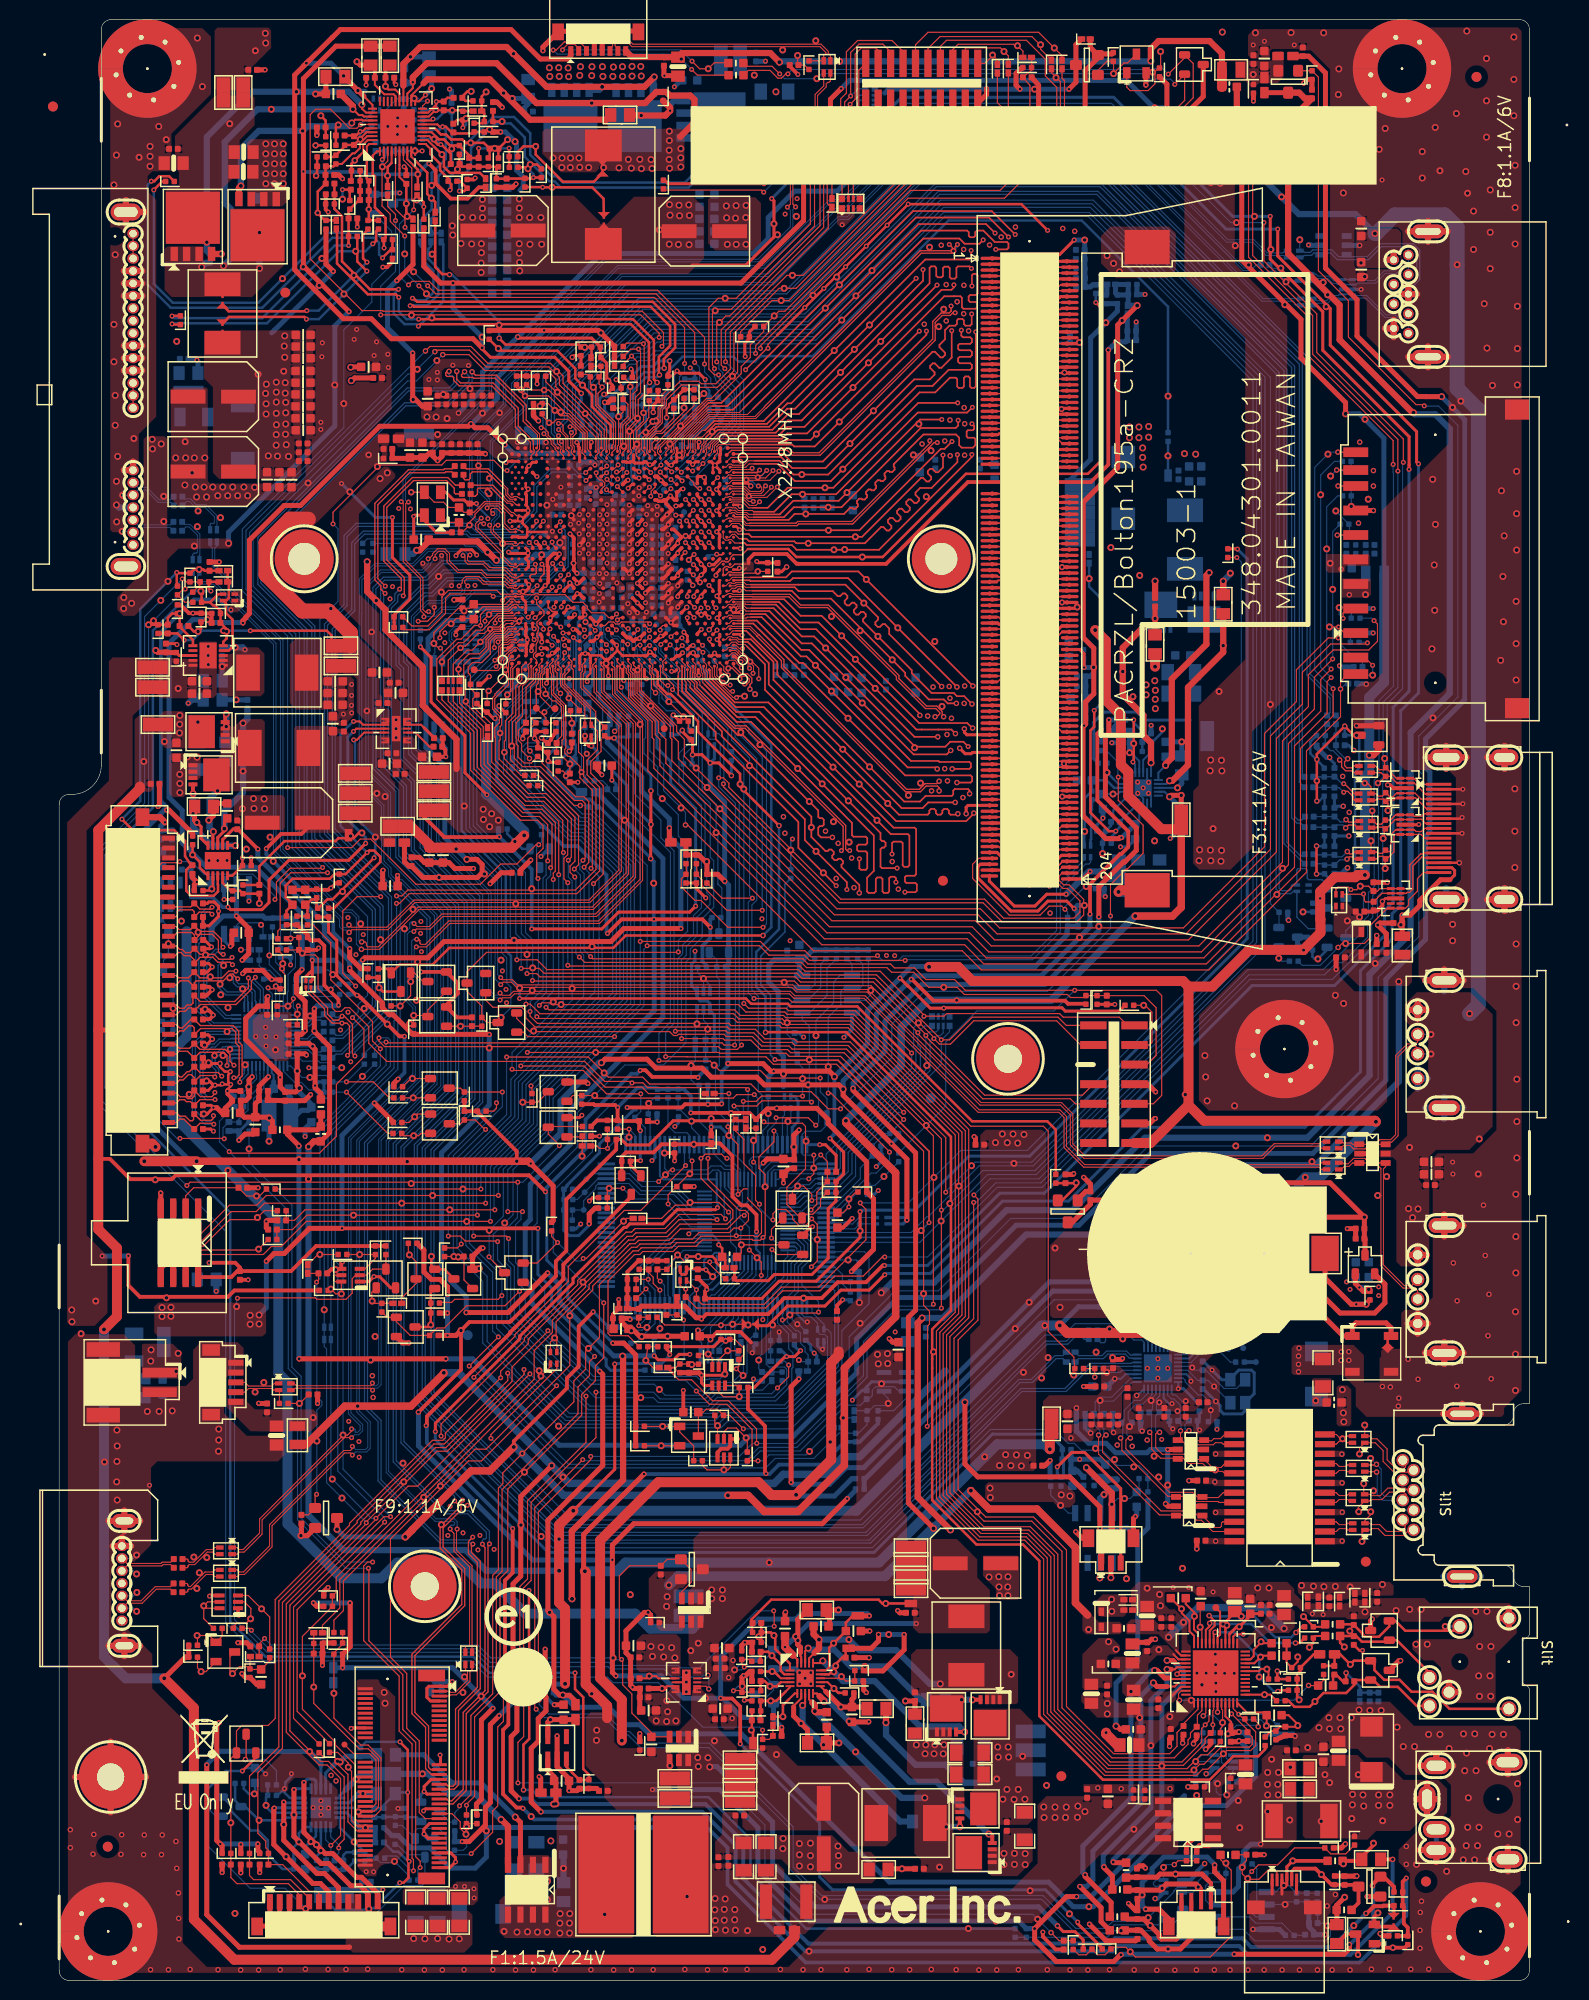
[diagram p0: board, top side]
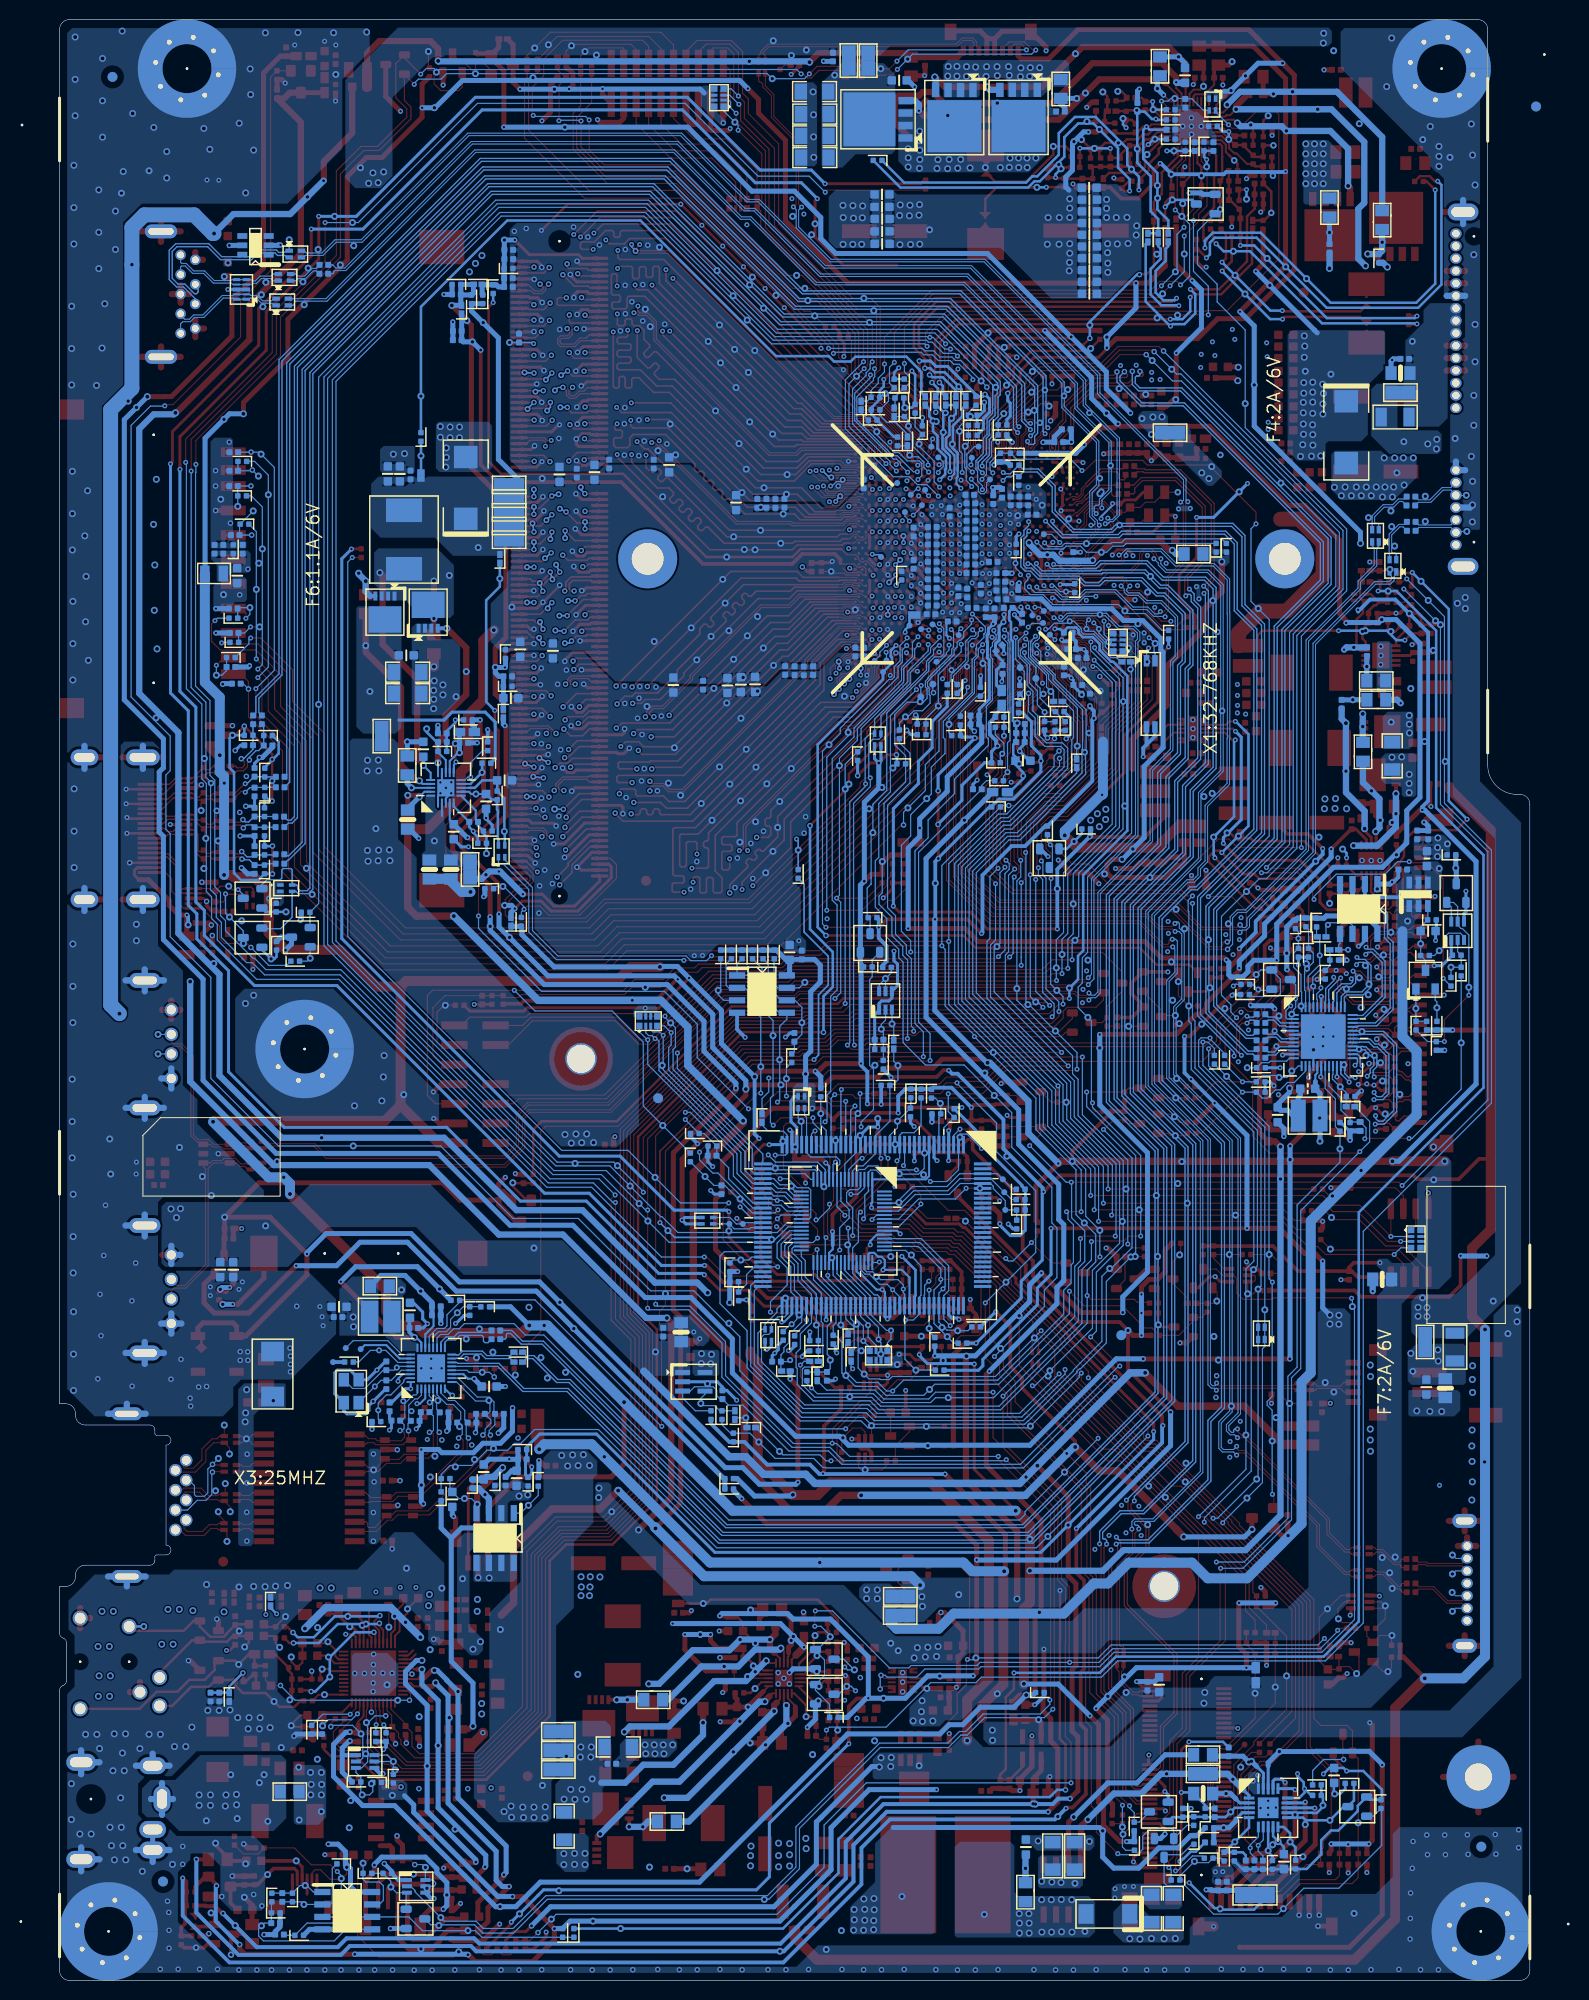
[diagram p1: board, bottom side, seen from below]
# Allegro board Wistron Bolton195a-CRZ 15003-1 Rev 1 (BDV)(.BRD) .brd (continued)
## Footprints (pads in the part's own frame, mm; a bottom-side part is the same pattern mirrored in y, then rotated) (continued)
SOT23-2D4-312H46
  custom 0.191x0.191 smd: 1(-0.984,-0.953) 2(0.984,-0.953) 3(0,0.953)
SOT23-2D4-312H48
  custom 0.191x0.191 smd: 1(-0.984,-0.953) 2(0.984,-0.953) 3(0,0.953)
SOT23-2D8-312H58
  custom 0.254x0.254 smd: 1(-1.016,-1.118) 2(1.016,-1.118) 3(0,1.118)
SOT23CBE2D4H44
  custom 0.191x0.191 smd: B(-0.984,-0.953) C(0,0.953) E(0.984,-0.953)
SOT23DGS2D4H35
  custom 0.191x0.191 smd: D(0,0.953) G(-0.984,-0.953) S(0.984,-0.953)
SOT23DGS2D4H44
  custom 0.191x0.191 smd: D(0,0.953) G(-0.984,-0.953) S(0.984,-0.953)
SOT23DGS2D4H48
  custom 0.191x0.191 smd: D(0,0.953) G(-0.984,-0.953) S(0.984,-0.953)
SOT23DGS2D8H50
  custom 0.254x0.254 smd: D(0,1.118) G(-1.016,-1.118) S(1.016,-1.118)
SOT-6-1H50
  rect 0.584x1.219 smd: 1(-0.95,-1.194) 2(0,-1.194) 3(0.95,-1.194) 4(0.95,1.194) 5(0,1.194) 6(-0.95,1.194)
SOT-6H58
  rect 0.584x1.016 smd: 1(-0.953,-1.346) 2(0,-1.346) 3(0.953,-1.346) 4(0.953,1.346) 5(0,1.346) 6(-0.953,1.346)
SOT-23-1H44
  custom 0.254x0.254 smd: 1(-1.016,-1.118) 2(1.016,-1.118) 3(0,1.118)
SOT-23-5H52
  rect 0.508x1.524 smd: 1(-0.95,-1.143) 2(0,-1.143) 3(0.95,-1.143) 4(0.95,1.143) 5(-0.95,1.143)
SOT-23-5H58
  rect 0.508x1.524 smd: 1(-0.95,-1.143) 2(0,-1.143) 3(0.95,-1.143) 4(0.95,1.143) 5(-0.95,1.143)
SOT-23-10H44
  rect 0.762x1.143 smd: 1(-0.984,-0.953) 2(0.984,-0.953) 3(0,0.953)
SOT-363H44
  rect 0.406x1.016 smd: 1(-0.65,-0.94) 2(0,-0.94) 3(0.65,-0.94) 4(0.65,0.94) 5(0,0.94) 6(-0.65,0.94)
STF237R128H34
  round 6.02 hole 3.251: 1(0,0)
STF256R109H124
  round 6.502 hole 2.769: 1(0,0)
STFT256B126R113H62
  round 6.502 hole 2.87: 1(0,0)
TPAD24
  round 0.61 smd: 1(0,0)
TPAD28-1-U
  round 0.711 smd: 1(0,0)
TVS5436-1121H105
  rect 2.337x2.007 smd: 1(0,2.299) 2(0,-2.299)
unnamed
  round 1.016 smd: (0,0)
WATA-07APLDJ6U
  oval 1.041x1.168 hole 0.762: 1(-3.81,0.25) 2(-2.54,0.25) 3(-1.27,0.25) 4(0,0.25) 5(1.27,0.25) 6(2.54,0.25) 7(3.81,0.25)
  oval 1.422x2.515 hole 0.711x1.803: 8(-6.37,0) 9(6.37,0)
XFORM24Z151100H160
  rect 0.635x2.032 smd: 1(-5.445,-4.623) 2(-4.455,-4.623) 3(-3.465,-4.623) 4(-2.475,-4.623) 5(-1.485,-4.623) 6(-0.495,-4.623) 7(0.495,-4.623) 8(1.485,-4.623) 9(2.475,-4.623) 10(3.465,-4.623) 11(4.455,-4.623) 12(5.445,-4.623) 13(5.445,4.623) 14(4.455,4.623) 15(3.465,4.623) 16(2.475,4.623) 17(1.485,4.623) 18(0.495,4.623) 19(-0.495,4.623) 20(-1.485,4.623) 21(-2.475,4.623) 22(-3.465,4.623) 23(-4.455,4.623) 24(-5.445,4.623)

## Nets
3V_5V_POK: PC4921.1 PR4928.1 PR4929.1 R4803.2 R5101.2 R5202.1
5V_A: C372.1 C435.1 C3602.1 C3608.1 EC10.1 PR4906.1 PR4907.1 PR4910.1 PR4913.1 R6536.1 R6537.1 U12.4 U13.4 U13.6 U13.7 U17.D U20.1 U20.2 U20.5 U20.6 U22.1 U22.2 U22.5 U22.6 U51.5
5V_FANCTL1_FSM#: R6513.2 U6502.1
5V_HDD: C412.1 C413.1 F4.2 HDD1.P7 HDD1.P8 HDD1.P9 R1021.2
5V_S0: C195.1 C196.1 C384.1 C3606.2 C3615.1 C6512.1 C6522.1 D14.A EC9.1 F3.1 F4.1 F7.1 FC1.1 L4.1 PR4426.1 PR4427.1 PR4440.1 R429.1 R508.2 R606.1 R607.1 R618.2 R671.1 R1021.1 R6516.1 R6531.1 R6576.1 R6578.1 U13.8 U13.9 U6502.2
5V_S5: C311.2 D7.2 L3.2 PC4806.1 PR5001.2 PR5005.2 PU4801.7 R86.1 R87.2 R499.2 R555.1 R808.2 R6536.2 R6537.2 RN11.5(B) RN11.6(B) RN11.7(B) RN11.8(B) U17.S U20.4
5V_S5_LCD_DOWN: Q33.D R377.2
12V_EN_D: PR161.2 Q82.D R1014.1
12V_EN_G: Q82.G Q4807.D R6562.2 R6563.2
12V_EN_G1: Q82.S Q83.D
+0.95V_DUAL: C119.1 C137.1 C138.1 C139.1 C140.1 C141.1 C142.1 CPU1.AR5 CPU1.AU4 CPU1.AV7 CPU1.AW5 R100.2 R119.1
+1.05V_LAN: C270.1 C271.1 C272.1 C273.1 C274.1 C275.1 C278.1 C279.1 L21.2 LAN1.3 LAN1.8 LAN1.22 LAN1.30 R269.2
+3VL: PG4904.2 PR161.1 R6541.2 R6543.1 R6544.2 R6550.1 R6551.2 R6561.1 R6563.1 R6573.1
+3VM: DIMM1.199 R136.2
+5VL: PG4901.2 PR4922.1
+5VLCDDDC: C389.1 F3.2 HDMI1.18
AGND: AUDIO1.26 AUDIO1.37 AUDS1.1 AUDS1.8 C185.2 C186.1 C187.2 C188.2 C189.2 C190.2 C191.1 C192.2 C193.1 C256.2 C257.2 C261.2 C262.2 C263.1 C264.1 C265.1 C267.1 EC704.2 R152.2 R164.1 R165.1 R166.1 R167.1 R168.1 R169.2 R235.2 R259.2 R261.2 R264.2
GND: AUDIO1.7 AUDIO1.42 AUDIO1.43 AUDIO1.49 BTT1.2 C1.2 C2.2 C3.2 C22.1 C23.1 C24.2 C25.1 C26.2 C27.1 C28.2 C29.2 C30.2 C31.2 C32.2 C33.1 C34.2 C35.2 C36.2 C37.2 C38.2 C39.2 C40.2 C41.2 C42.2 C43.2 C44.2 C45.2 C46.2 C47.2 C48.2 C49.2 C50.2 C51.2 C52.2 C53.2 C54.2 C55.2 C56.2 C57.2 C58.2 C59.2 C60.2 C61.2 C62.2 C63.2 C64.2 C65.2 C66.2 C67.2 C68.2 C69.2 C70.2 C71.2 C72.2 C73.2 C74.2 C75.2 C76.2 C77.2 C78.2 C79.2 C80.2 C81.2 C82.2 C83.2 C84.2 C85.2 C86.2 C87.2 C88.2 C89.2 C90.2 C91.2 C92.2 C93.2 C94.2 C95.2 C96.2 C97.2 C98.2 C99.2 C100.2 C101.2 C102.2 C103.2 C104.2 C105.2 C106.2 C107.2 C108.2 C109.2 C110.2 C111.2 C112.2 C113.2 C114.2 C115.2 C116.2 C117.2 C118.2 C119.2 C120.2 C121.2 C122.2 C123.2 C124.2 C125.2 C126.2 C127.2 C128.2 C129.2 C130.2 C131.2 C132.2 C133.2 C134.2 C135.2 C136.2 C137.2 C138.2 C139.2 C140.2 C141.2 C142.2 C143.2 C144.2 C145.2 C146.2 C147.2 C148.2 C149.2 C150.2 C151.2 C152.2 C153.2 C154.2 C155.2 C156.2 C157.2 C158.2 C159.1 C160.2 C161.2 C173.2 C174.1 C175.2 C176.1 C184.2 C195.2 C196.2 C197.2 C198.2 C200.2 C201.2 C205.2 C206.2 C207.2 C208.1 C209.1 C211.2 C223.2 C230.2 C235.2 C236.2 C237.2 C243.2 C245.2 C246.2 C247.2 C263.2 C264.2 C265.2 C266.2 C267.2 C268.2 C269.2 C270.2 C271.2 C272.2 C273.2 C274.2 C275.2 C278.2 C279.2 C280.2 C281.1 C282.2 C283.2 C284.2 C285.2 C286.2 C287.2 C288.2 C289.2 C292.2 C294.2 C295.2 C302.2 C303.2 C304.2 C305.2 C306.1 C307.1 C310.2 C312.1 C313.2 C325.1 C326.2 C351.2 C352.2 C353.1 C354.1 C355.2 C356.1 C357.1 C358.1 C359.1 C360.1 C361.1 C362.1 C363.1 C364.1 C365.1 C368.1 C369.1 C370.1 C371.1 C372.2 C373.1 C374.1 C375.1 C376.1 C377.1 C379.2 C384.2 C388.2 C389.2 C390.2 C391.2 C392.2 C393.2 C394.2 C395.2 C396.2 C397.2 C398.2 C412.2 C413.2 C420.2 C421.2 C426.2 C427.2 C428.2 C429.2 C430.2 C431.1 C432.2 C435.2 C436.2 C441.2 C444.2 C445.2 C446.2 C447.2 C450.2 C451.2 C452.2 C455.2 C458.2 C460.2 C467.2 C476.2 C477.2 C478.2 C480.2 C481.2 C482.2 C483.2 C484.2 C485.2 C486.2 C487.2 C488.2 C491.1 C493.2 C494.2 C497.2 C498.2 C499.2 C500.2 C501.2 C502.2 C503.2 C504.2 C505.2 C506.2 C507.2 C508.2 C509.2 C510.2 C511.2 C512.2 C679.2 C680.2 C3601.2 C3602.2 C3603.2 C3604.2 C3605.1 C3606.1 C3608.2 C3609.2 C3614.2 C3615.2 C3619.1 C4801.2 C5001.2 C5002.2 C6101.2 C6102.2 C6103.2 C6104.2 C6510.2 C6511.2 C6512.2 C6514.2 C6515.2 C6516.2 C6517.2 C6518.2 C6519.2 C6520.2 C6521.2 C6522.2 C6523.2 C6524.2 C6525.2 C6526.2 C6527.2 C6528.2 C6529.2 C6530.2 C6531.2 C6532.1 C6533.1 C6534.2 C6535.2 C6536.2 CAM1.4 CAM1.5 CAM1.9 CAM1.10 CMOS1.2 CMOS1.4 CNVBD2.1 CNVBD2.2 CNVBD2.3 CNVBD2.13 CNVBD2.14 CPU1.A8 CPU1.A13 CPU1.A15 CPU1.A31 CPU1.A35 CPU1.A39 CPU1.AA3 CPU1.AA7 CPU1.AA8 CPU1.AA11 CPU1.AA15 CPU1.AA19 CPU1.AA25 CPU1.AA29 CPU1.AA39 CPU1.AC3 CPU1.AC7 CPU1.AC11 CPU1.AC15 CPU1.AC19 CPU1.AC25 CPU1.AC29 CPU1.AC31 CPU1.AC39 CPU1.AC41 CPU1.AE3 CPU1.AE7 CPU1.AE25 CPU1.AE29 CPU1.AE32 CPU1.AE39 CPU1.AG3 CPU1.AG5 CPU1.AG10 CPU1.AG11 CPU1.AG13 CPU1.AG15 CPU1.AG19 CPU1.AG25 CPU1.AG29 CPU1.AG31 CPU1.AG39 CPU1.AG41 CPU1.AH1 CPU1.AH2 CPU1.AJ3 CPU1.AJ7 CPU1.AJ15 CPU1.AJ17 CPU1.AJ19 CPU1.AJ23 CPU1.AJ25 CPU1.AJ29 CPU1.AJ31 CPU1.AJ32 CPU1.AJ39 CPU1.AL3 CPU1.AL8 CPU1.AL15 CPU1.AL17 CPU1.AL19 CPU1.AL25 CPU1.AL29 CPU1.AL31 CPU1.AL39 CPU1.AL41 CPU1.AM11 CPU1.AM27 CPU1.AM29 CPU1.AM31 CPU1.AN3 CPU1.AN7 CPU1.AN39 CPU1.AP31 CPU1.AR3 CPU1.AR13 CPU1.AR17 CPU1.AR21 CPU1.AR25 CPU1.AR29 CPU1.AR39 CPU1.AR41 CPU1.AU1 CPU1.AU2 CPU1.AU3 CPU1.AU15 CPU1.AU19 CPU1.AU23 CPU1.AU27 CPU1.AU39 CPU1.AV9 CPU1.AW3 CPU1.AW7 CPU1.AW13 CPU1.AW15 CPU1.AW17 CPU1.AW19 CPU1.AW21 CPU1.AW23 CPU1.AW25 CPU1.AW27 CPU1.AW31 CPU1.AW33 CPU1.AW35 CPU1.AW37 CPU1.AW39 CPU1.AW41 CPU1.AY13 CPU1.AY15 CPU1.AY18 CPU1.AY30 CPU1.B8 CPU1.B13 CPU1.B23 CPU1.B31 CPU1.B39 CPU1.BA2 CPU1.BA7 CPU1.BA13 CPU1.BA15 CPU1.BA18 CPU1.BA21 CPU1.BA25 CPU1.BA31 CPU1.BA35 CPU1.BA39 CPU1.C1 CPU1.C2 CPU1.C5 CPU1.C7 CPU1.C9 CPU1.C11 CPU1.C13 CPU1.C15 CPU1.C17 CPU1.C19 CPU1.C21 CPU1.C23 CPU1.C25 CPU1.C27 CPU1.C29 CPU1.C31 CPU1.C33 CPU1.C35 CPU1.C37 CPU1.C39 CPU1.C41 CPU1.D9 CPU1.D11 CPU1.D13 CPU1.E3 CPU1.E4 CPU1.E9 CPU1.E11 CPU1.E13 CPU1.E27 CPU1.E31 CPU1.E35 CPU1.E38 CPU1.E39 CPU1.G3 CPU1.G7 CPU1.G11 CPU1.G13 CPU1.G15 CPU1.G17 CPU1.G21 CPU1.G25 CPU1.G29 CPU1.G35 CPU1.G37 CPU1.G39 CPU1.G41 CPU1.H11 CPU1.H13 CPU1.H23 CPU1.H31 CPU1.J3 CPU1.J7 CPU1.J8 CPU1.J39 CPU1.K11 CPU1.K13 CPU1.K17 CPU1.K19 CPU1.K21 CPU1.K23 CPU1.K25 CPU1.K27 CPU1.K29 CPU1.K31 CPU1.L3 CPU1.L7 CPU1.L8 CPU1.L10 CPU1.L11 CPU1.L15 CPU1.L19 CPU1.L31 CPU1.L39 CPU1.L41 CPU1.M1 CPU1.M2 CPU1.N3 CPU1.N7 CPU1.N15 CPU1.N19 CPU1.N25 CPU1.N29 CPU1.N31 CPU1.N39 CPU1.P1 CPU1.P2 CPU1.R3 CPU1.R7 CPU1.R15 CPU1.R19 CPU1.R25 CPU1.R29 CPU1.R39 CPU1.R41 CPU1.U1 CPU1.U2 CPU1.U3 CPU1.U7 CPU1.U8 CPU1.U11 CPU1.U15 CPU1.U19 CPU1.U25 CPU1.U29 CPU1.U31 CPU1.U39 CPU1.W3 CPU1.W5 CPU1.W11 CPU1.W15 CPU1.W19 CPU1.W25 CPU1.W29 CPU1.W39 CPU1.W41 CPU1.Y1 CPU1.Y2 CRS1.3 CRS1.6 CRS1.12 CRS1.13 D7.1 D9.3 D12.3 D19.3 D19.8 D20.2 D21.3 D24.2 D29.A DBGH1.7 DBGH1.11 DCIN1.2 DCIN1.3 DCIN1.4 DCIN1.5 DCIN1.6 DIMM1.2 DIMM1.3 DIMM1.8 DIMM1.9 DIMM1.13 DIMM1.14 DIMM1.19 DIMM1.20 DIMM1.25 DIMM1.26 DIMM1.31 DIMM1.32 DIMM1.37 DIMM1.38 DIMM1.43 DIMM1.44 DIMM1.48 DIMM1.49 DIMM1.54 DIMM1.55 DIMM1.60 DIMM1.61 DIMM1.65 DIMM1.66 DIMM1.71 DIMM1.72 DIMM1.127 DIMM1.128 DIMM1.133 DIMM1.134 DIMM1.138 DIMM1.139 DIMM1.144 DIMM1.145 DIMM1.150 DIMM1.151 DIMM1.155 DIMM1.156 DIMM1.161 DIMM1.162 DIMM1.167 DIMM1.168 DIMM1.172 DIMM1.173 DIMM1.178 DIMM1.179 DIMM1.184 DIMM1.185 DIMM1.189 DIMM1.190 DIMM1.195 DIMM1.196 DIMM1.201 DIMM1.205 DIMM1.206 EC1.2 EC2.2 EC3.2 EC4.2 EC5.2 EC6.2 EC7.2 EC8.2 EC9.2 EC10.2 EC11.2 EC12.2 EC13.2 EC14.2 EC15.2 EC16.2 EC17.2 EC18.2 EC302.2 EC326.2 EC327.2 EC328.2 EC329.2 EC330.2 EC701.2 EC702.2 EC703.2 EC705.2 EC706.2 EC707.2 EC708.2 EC709.2 FANC1.2 FANC1.4 FANC1.5 FC1.2 FC2.2 FC3.2 FC4.2 G3.1 GDT1.1 H1.1 H1.2 H1.3 H1.4 H1.5 H1.6 H1.7 H1.8 H2.1 H2.2 H2.3 H2.4 H2.5 H2.6 H2.7 H2.8 H3.1 H3.2 H3.3 H3.4 H3.5 H3.6 H3.7 H3.8 H4.1 H4.2 H4.3 H4.4 H4.5 H4.6 H4.7 H4.8 H5.1 H5.2 H5.3 H5.4 H5.5 H5.6 H5.7 H5.8 HDD1.23 HDD1.24 HDD1.P4 HDD1.P5 HDD1.P6 HDD1.P10 HDD1.P11 HDD1.P12 HDD1.S1 HDD1.S4 HDD1.S7 HDMI1.2 HDMI1.5 HDMI1.8 HDMI1.11 HDMI1.17 HDMI1.20 HDMI1.21 HDMI1.22 HDMI1.23 HDT1.3 HDT1.5 HDT1.7 HDT1.17 HS1.1 HS2.1 HS3.1 HS4.1 HS5.1 LAN1.33 LVDS19.7 LVDS19.14 LVDS19.17 LVDS19.24 LVDS19.31 LVDS19.32 NGFFE1.1 NGFFE1.7 NGFFE1.18 NGFFE1.33 NGFFE1.39 NGFFE1.45 NGFFE1.51 NGFFE1.57 NGFFE1.63 NGFFE1.69 NGFFE1.75 ODD1.1 ODD1.4 ODD1.7 ODD1.8 ODD1.9 ODDPW1.2 ODDPW1.3 ODDPW1.4 PC2.1 PC3.2 PC4.2 PC6.2 PC7.2 PC4205.2 PC4401.1 PC4403.2 PC4406.2 PC4407.2 PC4408.2 PC4409.2 PC4414.2 PC4416.2 PC4418.2 PC4419.2 PC4420.2 PC4421.2 PC4422.2 PC4423.2 PC4424.2 PC4425.2 PC4426.2 PC4427.2 PC4428.2 PC4429.2 PC4432.2 PC4433.2 PC4437.2 PC4442.2 PC4443.2 PC4445.2 PC4801.2 PC4803.2 PC4804.2 PC4806.2 PC4808.2 PC4809.2 PC4901.2 PC4902.2 PC4903.2 PC4905.2 PC4906.2 PC4907.2 PC4908.2 PC4911.2 PC4914.2 PC4915.2 PC4917.2 PC4919.2 PC4920.2 PC4921.2 PC4922.2 PC4923.2 PC5001.2 PC5005.2 PC5006.2 PC5007.2 PC5009.2 PC5011.2 PC5012.2 PC5014.2 PC5015.2 PC5016.2 PC5101.2 PC5102.2 PC5103.2 PC5105.2 PC5106.2 PC5107.2 PC5110.2 PC5203.2 PC5204.2 PC5205.2 PC5206.2 PC5207.2 PC5210.2 PC5211.2 PC5212.2 PC5213.2 PC5214.2 PC5215.2 PC5216.2 PC5217.2 PC5218.2 PC5219.2 PC5220.2 PC5221.2 PC5222.2 PC5223.2 PC5224.2 PC5225.2 PC5226.2 PC5229.2 PG4802.1 PQ4402.1 PQ4402.2 PQ4402.3 PQ4404.1 PQ4404.2 PQ4404.3 PQ4405.1 PQ4405.2 PQ4405.3 PQ4802.1 PQ4802.2 PQ4802.3 PQ4903.1 PQ4903.2 PQ4903.3 PQ4904.1 PQ4904.2 PQ4904.3 PQ5002.1 PQ5002.2 PQ5002.3 PR7.1 PR10.2 PR13.2 PR14.2 PR15.2 PR16.2 PR18.2 PR4408.2 PR4409.2 PR4420.2 PR4421.1 PR4425.1 PR4434.2 PR4438.1 PR4441.2 PR4443.2 PR4447.2 PR4455.2 PR4460.2 PR4805.1 PR4809.2 PR4812.2 PR4815.2 PR4919.2 PR4920.2 PR4921.2 PR4923.2 PR4924.2 PR4925.2 PR5019.2 PR5022.2 PR5104.2 PR5107.2 PR5108.2 PR5206.2 PR5208.2 PT4402.2 PT4403.2 PT4404.2 PT4406.2 PT4407.2 PT4411.2 PT4902.2 PT4903.2 PT5001.2 PU1.1 PU4401.41 PU4801.11 PU4901.21 PU5001.1 PU5001.3 PU5001.14 PU5001.21 PU5101.11 PU5201.2 PWRBT1.1 PWRBT1.3 PWRBT1.6 PWRBT1.7 PWRBT1.8 Q1.S Q2.E Q4.1 Q4.4 Q26.S Q27.1 Q27.4 Q29.1 Q29.4 Q33.S Q34.1 Q34.4 Q35.S Q39.S Q42.1 Q42.4 Q44.2 Q45.1 Q45.4 Q48.S Q49.1 Q49.4 Q75.S Q76.1 Q76.4 Q83.S Q98.S Q100.S Q4401.S Q4402.E Q4802.S Q4805.S Q4806.S Q4807.S R7.2 R10.2 R11.2 R12.2 R13.2 R14.2 R15.2 R17.2 R18.2 R21.2 R23.2 R25.2 R26.2 R27.2 R28.2 R31.2 R32.2 R42.2 R57.2 R58.2 R59.2 R60.2 R61.2 R73.2 R74.2 R93.2 R94.2 R95.2 R96.2 R97.1 R99.2 R130.2 R131.2 R132.2 R133.2 R134.2 R135.2 R141.2 R142.2 R152.1 R164.2 R165.2 R166.2 R167.2 R168.2 R179.1 R259.1 R261.1 R264.1 R268.1 R288.2 R296.2 R316.2 R342.1 R348.2 R349.2 R359.2 R378.2 R384.2 R386.1 R402.1 R435.2 R476.2 R477.2 R509.2 R510.2 R522.1 R523.2 R537.2 R546.2 R555.2 R560.2 R578.2 R583.2 R586.2 R587.2 R597.2 R601.2 R605.2 R610.2 R611.2 R613.2 R614.2 R615.2 R620.2 R624.2 R810.2 R6105.1 R6513.1 R6517.2 R6545.1 R6547.1 R6549.1 R6552.2 R6553.2 R6554.2 R6555.2 R6558.2 R6559.1 R6568.2 R6569.2 R6570.2 R6571.2 R6574.2 R6575.2 R6577.2 RJ1.9 RJ1.10 RN4.1(A) RN4.2(A) RN4.3(A) RN4.4(A) RN22.1(A) RN22.2(A) RN22.3(A) SPI1.4 TOUCH1.1 TOUCH1.2 TOUCH1.6 TOUCH1.7 U9.2 U10.2 U12.11 U12.15 U13.11 U13.15 U23.3 U23.8 U24.3 U24.8 U25.3 U25.8 U30.4 U31.7 U31.38 U31.74 U38.6 U38.16 U38.49 U39.1 U48.4 U51.2 U56.4 U58.1 U58.2 U58.4 U58.7 U59.20 U6502.5 U6502.6 U6502.7 U6502.8 U6503.54 USB2S1.4 USB2S1.5 USB2S1.6 USB2S2.4 USB2S2.5 USB2S2.6 USB3S1.4 USB3S1.7 USB3S1.10 USB3S1.11 X1.2 X1.3 X2.2 X2.4 X3.2 X3.4
V12: HDD1.P13 HDD1.P14 HDD1.P15
V33: HDD1.P1 HDD1.P2 HDD1.P3
VBAT_SB_N: C136.1 PU1.2 R122.2
VBAT_SIO: C481.1 R545.1 U31.69 U6503.29
VCC5_CAM: C446.1 C447.1 CAM1.8 F8.2 R463.2
VCC5_PANEL: C6520.1 C6521.1 L38.2 LVDS19.1 LVDS19.2 LVDS19.3 R377.1
VCC5_TOU: C450.1 C451.1 F9.2 TOUCH1.5
VDD_0.95_ALW: C123.1 C143.1 C144.1 C145.1 C146.1 CPU1.AE11 CPU1.AE13 CPU1.AJ11 CPU1.AJ13 R121.2
VDD_095_FB_H: CPU1.AV33 Q4801.S R4804.2 TP17.1
VDD_095_FB_H_CTL: PR4814.2 Q4801.D R4804.1
VDD_095_FB_L: CPU1.AU33 PG4802.2 TP18.1
VDD_095_GFX: C124.1 C125.1 CPU1.AA10 CPU1.U10 CPU1.W10 L1.1
VDDCR_APU_FB_H: PR4454.2 R35.1
VDDCR_APU_FB_L: PR4444.2 R37.1
VDDCR_CPU_SENSE: CPU1.G23 R35.2
VDDCR_NB_FB_H: PR4403.2 R34.1
VDDCR_NB_FB_L: PC4402.2 PC4406.1 PR4409.1 PR4437.2 R38.1
VDDCR_NB_SENSE: CPU1.D23 R34.2
VDDIO_SUS_FB_H: PR5210.2 R36.1
VDDIO_SUS_FB_R: PG4905.2 PR5210.1
VDDIO_SUS_SENSE: CPU1.E25 R36.2
VDDNB: C67.1 C68.1 C69.1 C70.1 C71.1 C72.1 C73.1 C74.1 C75.1 C76.1 C77.1 C78.1 C79.1 C80.1 C90.1 C91.1 C92.1 C93.1 CPU1.AA13 CPU1.AA17 CPU1.AC13 CPU1.AC17 CPU1.AE15 CPU1.AE17 CPU1.AE19 CPU1.AG17 CPU1.AG21 CPU1.L13 CPU1.L17 CPU1.N11 CPU1.N13 CPU1.N17 CPU1.R11 CPU1.R13 CPU1.R17 CPU1.U13 CPU1.U17 CPU1.W13 CPU1.W17 PC4418.1 PC4419.1 PC4420.1 PC5210.1 PC5211.1 PC5212.1 PC5213.1 PC5214.1 PC5215.1 PG4402.1 PL4905.2 PR4402.2 PT4402.1 PT4403.1 PT4404.1
VSS_BEEMA: CPU1.A23 R130.1
VSS_SENSE: CPU1.E23 R37.2 R38.2
0D75V_S0: DIMM1.203 DIMM1.204 PR5021.2
0D95V_S0: C6530.1 C6533.2 R98.1 R115.2 R116.2 R117.2 R4403.2 U12.8 U12.9
0D95V_S0_EN: C307.2 R299.2 R302.2 R6577.1 R6578.2 U12.5
0D95V_S5: C6524.1 C6527.1 PR4808.1 PR4810.1 PR4811.1 R119.2 R121.1 U12.6 U12.7
0D95V_S5_PG: PR4801.2 PU4801.1
0P95V_MAIN_APU_M: Q4402.B R4403.1
1D5V_S0: C327.2 U16.S
1D5V_S3: C94.1 C95.1 C96.1 C97.1 C98.1 C99.1 C100.1 C101.1 C102.1 C103.1 C104.1 C105.1 C114.1 C115.1 C116.1 C150.1 C151.1 C152.1 C153.1 C154.1 C155.1 C156.1 C157.1 C158.1 CPU1.AA31 CPU1.AA35 CPU1.AC32 CPU1.AC37 CPU1.AE31 CPU1.AE35 CPU1.AG32 CPU1.AG37 CPU1.AJ35 CPU1.AL32 CPU1.AL37 CPU1.AR35 CPU1.J35 CPU1.L32 CPU1.L37 CPU1.N35 CPU1.R31 CPU1.R37 CPU1.U32 CPU1.U35 CPU1.W31 CPU1.W32 CPU1.W37 DIMM1.75 DIMM1.76 DIMM1.81 DIMM1.82 DIMM1.87 DIMM1.88 DIMM1.93 DIMM1.94 DIMM1.99 DIMM1.100 DIMM1.105 DIMM1.106 DIMM1.111 DIMM1.112 DIMM1.117 DIMM1.118 DIMM1.123 DIMM1.124 EC11.1 EC12.1 FC2.1 FC3.1 PR5011.1 PR5013.1 PR5015.1 PR5016.1 PR5017.1 PR5213.1 R2.1 R4.2 R5.1 R139.1 R140.1 R832.1 U16.D
1D5V_S3_PG: PR5006.2 PU5001.10 R812.1
1D5V_S3_PG_R: C679.1 Q83.G R812.2
1D5V_S5: AUDIO1.9 C207.1 PR5204.2 R111.1 R6570.1
1D8V_S0: C6531.1 C6532.2 R109.2 U12.13 U12.14
1D8V_S0_EN: C3619.2 R982.2 R6575.1 R6576.2 U12.3
1D8V_S5: C81.1 C6525.1 C6526.1 PR5102.2 PR5211.2 R62.1 R65.2 R110.1 R6574.1 U12.1 U12.2
1P8V_PWR_PG: PU5101.4 R4801.1 R5201.1 RN19.4(B)
3D3V_2136: C497.1 L51.1 L53.1 R588.2 R589.2
3D3V_A: C478.1 C482.1 C485.1 C486.1 C3601.1 C3609.1 C6536.1 L50.2 PR4914.1 PR4915.1 PR4916.1 PR4930.1 PR5101.1 PR5201.1 PR5212.1 Q40.D Q4804.G R123.2 R309.1 R504.1 R505.1 R520.1 R524.2 R527.1 R535.1 R548.2 R549.2 R550.2 R551.2 R552.2 R553.2 R556.2 R557.1 R559.1 R568.2 R572.2 R622.2 R698.2 R822.1 R823.1 R824.1 R6535.1 R6538.1 R6539.1 R6540.2 R6572.1 RN10.1(A) RN10.2(A) RN12.1(A) RN12.2(A) U13.1 U13.2 U18.1 U18.2 U18.5 U18.6 U31.4 U31.35 U31.67 U56.8
3D3V_S0: C3605.2 C3614.1 CAM1.1 DBGH1.13 F6.1 L5.1 Q35.G Q37.C Q4803.G R16.2 R69.1 R70.1 R85.2 R112.1 R136.1 R286.1 R299.1 R367.1 R395.1 R396.1 R492.1 R493.1 R497.2 R498.2 R501.2 R502.2 R511.2 R512.2 R513.2 R526.2 R531.2 R542.2 R561.2 R562.2 R563.2 R579.1 R588.1 R982.1 R4401.1 R6512.1 R6532.2 R6534.1 R6546.1 R6548.1 R6557.1 R6560.2 R6564.2 RN5.1(A) RN5.2(A) RN9.5(B) RN9.6(B) RN9.7(B) RN9.8(B) RN16.1(A) RN16.2(A) RN18.1(A) RN18.2(A) U13.13 U13.14
3D3V_S5: C328.2 C426.1 C427.1 C6101.1 C6102.1 C6103.1 C6104.1 FC4.1 NGFFE1.2 NGFFE1.4 NGFFE1.72 NGFFE1.74 PR4801.1 PR5006.1 R76.1 R77.2 R78.2 R79.2 R80.2 R81.2 R83.2 R88.1 R89.1 R90.1 R113.1 R125.1 R126.1 R127.1 R128.1 R129.1 R175.2 R176.1 R278.1 R303.1 R310.1 R441.1 R466.1 R515.1 R516.1 R517.1 R518.1 R529.1 R533.1 R544.2 R578.1 R581.1 R608.1 R609.1 R617.1 R809.2 R1019.2 R1020.2 R1028.2 R4402.2 R6103.1 R6533.1 R6538.2 R6539.2 RN3.1(A) RN3.2(A) RN6.5(B) RN6.6(B) RN6.7(B) RN6.8(B) RN15.3(B) RN15.4(B) RN19.1(A) RN19.2(A) SPI1.8 U18.4 U30.8 U39.2
3D3V_S5_RSV: R474.1 R475.1 R6103.2 R6566.1
3D3V_USB: C444.1 C445.1 F8.1 Q40.S R589.1 R6571.1 R6572.2
+1P5V_LPS_APU: C135.1 CPU1.AN4 R122.1
+AUD_DVDD_1: AUDIO1.1 C205.1 C206.1 L5.2
+HDT_VDDIO_SUS: HDT1.1 HDT1.19 Q43.D R489.1 R491.1 RN7.5(B) RN7.6(B) RN7.7(B) RN7.8(B)
+RTCVCC: C147.1 C148.1 C149.1 CMOS1.1 CMOS1.3 D4.3 G3.2 PU1.3 R545.2
A_RST_N: CPU1.AY4 DBGH1.9 R63.1
AD_JK_S: D29.K DCIN1.1 PC2.2 PC3.1 PR1.1 PR4.1 R802.1 R803.1 R804.1
AD_JK_S_R: PC4.1 PC8.1 PR1.2 PR3.1 PR12.1 PR17.2 PU2.1 PU2.2 PU2.3 R802.2 R803.2 R804.2 U48.8
ADP_OCP: PR11.1 U48.7
ADU_LDO_CAP: AUDIO1.28 C185.1
AMPGND: SPK1.5 SPK1.6
APU_ALERT#: CPU1.B18 R40.2
APU_BLEN_SMI: CPU1.AP17 Q4803.D R6533.2
APU_DBRDY: CPU1.B25 HDT1.14
APU_DBREQ: HDT1.16 R486.1
APU_DBREQ#: C467.1 CPU1.A25 R486.2 R491.2
APU_M_VREF_SUS: C2.1 C3.1 CPU1.AD40 R6.1
APU_M_VREFDQ_SUS: C160.1 C161.1 C173.1 C174.2 DIMM1.1 R3.1 R139.2 R141.1 R145.1
APU_PROCHOT#: CPU1.A22 PR4428.1 Q75.D R41.2 R71.1
APU_PROCHOT#_R: CPU1.AM21 R71.2
APU_PWRGD: CPU1.B19 R22.2 R24.1 R56.1 R481.2
APU_PWRGD_BUF: HDT1.10 R481.1
APU_SIC: CPU1.B22 R43.2 U31.55 U6503.26
APU_SID: CPU1.B21 R44.2 U31.53 U6503.25
APU_SVC: CPU1.D27 R47.1 R54.1
APU_SVD: CPU1.E29 R48.1 R55.1
APU_SVT: CPU1.G31 R46.1 R53.1
APU_TCK: CPU1.D35 HDT1.2 RN7.2(A)
APU_TDI: CPU1.D29 HDT1.6 RN7.4(A)
APU_TDO: CPU1.D31 HDT1.8
APU_TEST0: CPU1.AU13 R88.2 R93.1 TP20.1
APU_TEST1: CPU1.AY10 R89.2 R94.1 TP19.1
APU_TEST2: CPU1.AY6 R90.2 R95.1 TP21.1
APU_TEST4_THERMDA: CPU1.H27 TP5.1
APU_TEST5_THERMDC: CPU1.H29 TP6.1
APU_TEST6_DIRECRACKMON: CPU1.D25 TP7.1
APU_TEST14_BP0: CPU1.A27 R21.1
APU_TEST15_BP1: CPU1.B27 TP8.1
APU_TEST16_BP2: CPU1.A26 R23.1
APU_TEST17_BP3: CPU1.B26 R25.1
APU_TEST28_PLLCHARZ_H: CPU1.AV35 TP9.1
APU_TEST28_PLLCHARZ_L: CPU1.AU35 TP10.1
APU_TEST31_M_TEST: CPU1.E33 TP11.1
APU_TEST36_FREE_2: CPU1.H21 R30.1 R31.1
APU_TEST37_FREE_2: CPU1.H25 R32.1 R33.1
APU_TMS: CPU1.D33 HDT1.4 RN7.3(A)
APU_TRST: CPU1.G27 R480.1 RN7.1(A)
APU_VDD18_ALW: C82.1 C83.1 C84.1 C85.1 C86.1 C87.1 C88.1 C89.1 CPU1.B1 CPU1.B2 R110.2
APU_VDD33_ALW: C118.1 C6535.1 CPU1.AL13 CPU1.AM13 R113.2
APU_VDD_0.95: C122.1 C126.1 C127.1 C128.1 C129.1 C130.1 C131.1 C132.1 C133.1 C134.1 C6534.1 CPU1.AG23 CPU1.AG27 CPU1.AJ21 CPU1.AJ27 CPU1.AL21 CPU1.AL23 CPU1.AL27 CPU1.AM23 CPU1.AM25 L1.2 R8.1 R9.2 R115.1 R116.1 R117.1
APU_VDD_18: C58.1 C59.1 C60.1 C61.1 C62.1 C63.1 C64.1 C65.1 C66.1 C120.1 CPU1.A2 CPU1.A3 CPU1.B3 CPU1.C3 PR4429.1 Q43.S R19.1 R22.1 R29.2 R30.2 R33.2 R39.2 R46.2 R47.2 R48.2 R49.1 R50.1 R51.1 R52.1 R109.1 R489.2 R490.1
APU_VDD_33: C111.1 C112.1 C113.1 C121.1 CPU1.AM15 CPU1.AM17 R40.1 R41.1 R43.1 R44.1 R45.1 R112.2 RN1.3(B) RN1.4(B)
APU_VDDIO_AZ: C106.1 C107.1 C108.1 C109.1 C110.1 C117.1 CPU1.AL10 CPU1.AL11 R111.2
APU_VRM_PWRGD: PC4429.1 PU4401.20 RN18.3(B)
AUD_CBN: AUDIO1.35 C194.1
AUD_CBP: AUDIO1.36 C194.2
AUD_CPVEE: AUDIO1.34 C186.2
AUD_LINK_RST_N1: Q4.2 R177.1
AUD_PVDD_1: AUDIO1.39 AUDIO1.46 C197.1 C198.1 C200.1 C201.1 L4.2
AUD_VREF: AUDIO1.27 C187.1 C188.1
AZ_BCLK: AUDIO1.6 EC701.1 R6552.1 RN2.4(A)
AZ_BCLK_M: CPU1.AN2 RN2.5(B)
AZ_RST_N: AUDIO1.11 R177.2 R6555.1 RN2.1(A)
AZ_RST_N_M: CPU1.AL1 RN2.8(B)
AZ_SDIN0: CPU1.AK2 R174.1 RN4.5(B)
AZ_SDIN0_R: AUDIO1.8 R174.2
AZ_SDIN1: CPU1.AK1 RN4.6(B)
AZ_SDIN2: CPU1.AM1 RN4.8(B)
AZ_SDIN3: CPU1.AL2 RN4.7(B)
AZ_SDOUT: AUDIO1.5 R6553.1 RN2.3(A)
AZ_SDOUT_M: CPU1.AN1 RN2.6(B)
AZ_SYNC: AUDIO1.10 C28.1 R6554.1 RN2.2(A)
AZ_SYNC_M: CPU1.AM2 RN2.7(B)
BATTERY: BTT1.1 R124.2
BKLT_ADJ: R353.2 R374.1 R375.1
BKLT_EN: C355.1 Q100.G R354.2 R364.2 R365.2 R367.2 U31.26
BKLT_EN_D: Q100.D Q101.G R1029.1 R1030.2
BLANCLK_REQ_N: CPU1.AU29 R85.1 R270.1
BLINK: CPU1.AU17 R76.2
BT_DISABLE_N: R6110.1 U31.18 U6503.42
BT_DISABLE_N#: NGFFE1.54 R475.2 R477.1 R6110.2
BUFFER1_M4: Q4401.G Q4402.C R4402.1
BYPASSCLK_H: CPU1.B24 R28.1
BYPASSCLK_L: CPU1.A24 R29.1
BZ_ON: AUDIO1.12 C324.1
C_GPP_TXN0: C5.1 CPU1.L1
C_GPP_TXN1: C7.1 CPU1.K1
C_GPP_TXP0: C4.1 CPU1.L2
C_GPP_TXP1: C6.1 CPU1.K2
CK_BLAN_DN: LAN1.16 R272.2
CK_BLAN_DP: LAN1.15 R271.2
CLK_48M_SIO: R547.2 U31.37 U6503.24
COMBO: AUDS1.7 C256.1 D9.1 L18.2 R236.2
COMBO JACK: AUDIO1.47 C257.1 R236.1
CPU_FANCTL1: R6511.1 R6512.2 U31.9 U6503.2
CPU_FANCTL1_5V: C6510.1 R6511.2 U6502.4
CPU_FANTACH1: C6523.1 FANC1.3 R6516.2 R6517.1 U31.8 U6503.1
CPU_VCORE: C38.1 C39.1 C40.1 C41.1 C42.1 C43.1 C44.1 C45.1 C46.1 C47.1 C48.1 C49.1 C50.1 C51.1 C52.1 C53.1 C54.1 C55.1 C56.1 C57.1 CPU1.AA21 CPU1.AA23 CPU1.AA27 CPU1.AC21 CPU1.AC23 CPU1.AC27 CPU1.AE21 CPU1.AE23 CPU1.AE27 CPU1.L21 CPU1.L23 CPU1.L25 CPU1.L27 CPU1.L29 CPU1.N21 CPU1.N23 CPU1.N27 CPU1.R21 CPU1.R23 CPU1.R27 CPU1.U21 CPU1.U23 CPU1.U27 CPU1.W21 CPU1.W23 CPU1.W27 G1.1 PC5216.1 PC5217.1 PC5218.1 PC5219.1 PC5220.1 PC5221.1 PC5222.1 PC5223.1 PC5224.1 PC5225.1 PC5226.1 PC5229.1 PG4403.1 PL4904.2 PR4458.2 PT4406.1 PT4407.1
D2_M: D4.2 R123.1 R6544.1
D2_M1: D4.1 R124.1
DAC_ZVSS: CPU1.A16 R18.1
DCBATOUT: EC13.1 EC14.1 EC15.1 EC16.1 EC17.1 EC18.1 F1.1 PC7.1 PR14.1 PR15.1 PR4405.2 PR4406.2 PR4432.2 PR4433.2 PR4802.1 PR4902.1 PR4903.1 PR4904.1 PR5002.1 PU2.5 PU2.6 PU2.7 PU2.8 R313.1 R315.1 R376.1 R380.1 R434.1 R436.1 R519.2 R530.1 R6556.1
DCBATOUT_CON: C211.1 C223.1 C351.1 C352.1 F1.2 L27.1 R339.1 R1029.2 R6556.2
DDR_VREF_S3: C1.1 PC5016.1 PU5001.4 R5.2 R6.2 R7.1 R145.2 R146.2
DIMM1_SA0: DIMM1.197 R6557.2 R6558.1
DIMM_TMPIN2: C469.1 RN20.4(B) RT2.1 U31.89 U6503.45
DMIC_CLK: AUDIO1.3 C209.2 D21.1 L74.2
DMIC_CLK_W: CAM1.3 L74.1
DMIC_DATA: AUDIO1.2 C208.2 D21.2 L75.2
DMIC_DATA_W: CAM1.2 L75.1
DP0_AUXN: C495.1 CPU1.E15 R57.1 RN1.2(A)
DP0_AUXN_PS8625: C495.2 U38.3
DP0_AUXP: C496.1 CPU1.D15 R58.1 RN1.1(A)
DP0_AUXP_PS8625: C496.2 U38.4
DP0_HPD_G: Q57.G R671.2
DP0_HPD_N: CPU1.H17 R12.1 R45.2 R830.2
DP0_HPD_NR: Q57.S R830.1
DP0_TXN0: C19.1 U38.8
DP0_TXN1: C21.1 U38.10
DP0_TXP0: C18.1 U38.7
DP0_TXP1: C20.1 U38.9
DP1_AUXN: CPU1.E17 Q38.S RN16.3(B)
DP1_AUXP: CPU1.D17 Q36.S RN16.4(B)
DP1_C_TXN0: C380.2 C397.1 R387.2 TR6.1
DP1_C_TXN1: C382.2 C395.1 R389.2 TR5.1
DP1_C_TXN2: C383.2 C393.1 R391.2 TR4.1
DP1_C_TXN3: C387.2 C388.1 R393.2 TR3.1
DP1_C_TXP0: C378.2 C396.1 R388.2 TR6.4
DP1_C_TXP1: C381.2 C394.1 R390.2 TR5.4
DP1_C_TXP2: C385.2 C392.1 R392.2 TR4.4
DP1_C_TXP3: C379.1 C386.2 R394.2 TR3.4
DP1_HDMI_CLK_C: C390.1 HDMI1.15 Q36.D RN17.4(B) U25.5 U25.6
DP1_HDMI_DATA_C: C391.1 HDMI1.16 Q38.D RN17.3(B) U25.4 U25.7
DP1_HPD_N: CPU1.H19 Q37.E R402.2
DP1_TXN0: C380.1 CPU1.B9
DP1_TXN0_C: HDMI1.3 R827.1 TR6.2 U24.4 U24.7
DP1_TXN1: C382.1 CPU1.B10
DP1_TXN1_C: HDMI1.6 R828.1 TR5.2 U24.1 U24.10
DP1_TXN2: C383.1 CPU1.B11
DP1_TXN2_C: HDMI1.9 R807.1 TR4.2 U23.4 U23.7
DP1_TXN3: C387.1 CPU1.B12
DP1_TXN3_C: HDMI1.12 R826.1 TR3.2 U23.1 U23.10
DP1_TXP0: C378.1 CPU1.A9
DP1_TXP0_C: HDMI1.1 R827.2 TR6.3 U24.5 U24.6
DP1_TXP1: C381.1 CPU1.A10
DP1_TXP1_C: HDMI1.4 R828.2 TR5.3 U24.2 U24.9
DP1_TXP2: C385.1 CPU1.A11
DP1_TXP2_C: HDMI1.7 R807.2 TR4.3 U23.5 U23.6
DP1_TXP3: C386.1 CPU1.A12
DP1_TXP3_C: HDMI1.10 R826.2 TR3.3 U23.2 U23.9
DP_2K_ZVSS: CPU1.A21 R11.1
DP_150_ZVSS: CPU1.B16 R10.1
DP_BLON: CPU1.B17 R364.1
DP_DIGON: CPU1.A17 R383.1
DP_REXT: R587.1 U38.12
DP_VARY_BL: CPU1.A18 R375.2 R585.1
DP_VARY_BL_R: R585.2 R611.1 U38.21
EC_EUP: R572.1 R574.1 R6543.2 U31.2 U6503.5
EC_EUP_EN: C493.1 Q48.G R574.2
EC_EUP_EN#: PR5209.1 Q48.D Q4805.G Q4806.G R319.1 R568.1 R4802.1 R6561.2
EC_SMI#: R75.2 R516.2
EC_SMI#_APU: CPU1.AR15 R75.1 R83.1
EDID_RDY: CPU1.AR4 TP67.1
EDP_LVDS_L0_N: C365.2 LVDS19.19 U38.42
EDP_LVDS_L0_P: C364.2 LVDS19.18 U38.41
EDP_LVDS_L1_N: C369.2 LVDS19.16 U38.40
EDP_LVDS_L1_P: C368.2 LVDS19.15 U38.39
EDP_LVDS_L2_N: C371.2 LVDS19.13 U38.38
EDP_LVDS_L2_P: C370.2 LVDS19.12 U38.37
EDP_LVDS_L3_N: C374.2 LVDS19.9 U38.34
EDP_LVDS_L3_P: C373.2 LVDS19.8 U38.33
EDP_LVDS_LC_N: C377.2 LVDS19.11 U38.36
EDP_LVDS_LC_P: C376.2 LVDS19.10 U38.35
EDP_LVDS_U0_N: C354.2 LVDS19.30 U38.32
EDP_LVDS_U0_P: C353.2 LVDS19.29 U38.31
EDP_LVDS_U1_N: C357.2 LVDS19.28 U38.30
EDP_LVDS_U1_P: C356.2 LVDS19.27 U38.29
EDP_LVDS_U2_N: C359.2 LVDS19.26 U38.28
EDP_LVDS_U2_P: C358.2 LVDS19.25 U38.27
EDP_LVDS_U3_N: C361.2 LVDS19.21 U38.24
EDP_LVDS_U3_P: C360.2 LVDS19.20 U38.23
EDP_LVDS_UC_N: C363.2 LVDS19.23 U38.26
EDP_LVDS_UC_P: C362.2 LVDS19.22 U38.25
EUP_DSW_SEL: R557.2 R560.1 R6573.2 U31.60 U6503.23
EUP_EN: C311.1 C313.1 C328.1 R314.2 U17.G U18.3 U20.3
EUP_R1: Q28.2 R313.2
EUP_R2: Q28.1 R315.2 R318.1
EUP_R3: C312.2 Q28.3 R314.1 R316.1 R317.1
EUP_R4: Q29.5 Q29.6 R318.2
EUP_R5: Q29.3 R317.2
EUP_R6: Q29.2 R319.2
F_GPP_CLK0N: CPU1.AC10 R272.1
F_GPP_CLK0P: CPU1.AC8 R271.1
F_GPP_CLK1N: CPU1.AE5 NGFFE1.49
F_GPP_CLK1P: CPU1.AE4 NGFFE1.47
F_HPO_L: AUDIO1.32 R240.1
F_HPO_L_1: L20.1 R240.2
F_HPO_R: AUDIO1.33 R238.1
F_HPO_R_1: L19.1 R238.2
F_USB0N: CPU1.AL5 L72.3
F_USB0P: CPU1.AL4 L72.2
F_USB1N: CPU1.AD2 L44.3
F_USB1N_RC: C680.1 R813.2
F_USB1P: CPU1.AD1 L44.2
F_USB2N: CPU1.AG8 L41.3
F_USB2N_RC: C452.1 R464.2
F_USB2P: CPU1.AG7 L41.2
F_USB4N: CPU1.AF2 L47.3
F_USB4P: CPU1.AF1 L47.2
F_USB5N: CPU1.AE2 L49.3
F_USB5P: CPU1.AE1 L49.2
F_USB8N: CPU1.AB2 L40.3
F_USB8P: CPU1.AB1 L40.2
FAN5V_OUT: R6515.1 U6502.3
FAN5V_OUT_CONN: C6511.1 FANC1.1 R6515.2 R6531.2
FM_L_CODEC: AUDIO1.21 C254.1
FM_R_CODEC: AUDIO1.22 C255.1
FP_RST_N: C29.1 CPU1.AY7 R78.1
HDMI_DP_5V: C398.1 D14.K RN17.1(A) RN17.2(A)
HDMI_EN: CPU1.E21 R39.1 R42.1
HDMI_HPDET_CN: HDMI1.19 R401.1 U25.1 U25.10
HDMI_HTPLG_CN1: Q37.B R401.2
HDMI_Q76_M: Q35.D R387.1 R388.1 R389.1 R390.1 R391.1 R392.1 R393.1 R394.1
HDT_C_M1: HDT1.11 RN22.8(B)
HDT_C_M2: HDT1.13 RN22.7(B)
HDT_C_M3: HDT1.15 RN22.6(B)
HDT_PW_M3: Q44.1 R492.2
HDT_PW_M4: Q43.G Q44.3 R490.2
HDT_RST0: HDT1.18 R487.1
HDT_RST1: HDT1.20 R488.1
HDT_TRST: HDT1.9 R480.2
HM_VCCP: G1.2 R507.1
HM_VCCP_R: C474.1 R507.2 U31.98 U6503.52
HP_OUT_L_CON: AUDS1.2 C262.1 D12.2 L20.2
HP_OUT_R_CON: AUDS1.3 C261.1 D12.1 L19.2
ICH_RSMRST_N_R: R534.1 U31.85 U6503.43
ISEN1: CNVBD2.12 U59.17
ISEN2: CNVBD2.11 U59.16
ISEN3: CNVBD2.8 U59.14
ISEN4: CNVBD2.7 U59.13
ISET: R341.1 R6579.1 U59.12
ISW: C183.1 R347.2 U59.19
ISW_1: Q78.1 Q78.2 Q78.3 R347.1 R348.1 R349.1
ITE_DEB: R698.1 U31.58
JD_HP_R: AUDS1.9 D9.2 EC704.1 R172.2
JDREF_1: AUDIO1.19 R169.1
KA20GATE: CPU1.AR31 Q99.S R498.1
KA20GATE_SIO: Q99.D U31.46 U6503.21
KBCLK: RN11.3(A) U31.81 U6503.39
KBRST_N: CPU1.AR23 R497.1 U31.45 U6503.20
KDAT: RN11.4(A) U31.80 U6503.38
LAD0_FWH0: CPU1.AT2 DBGH1.10 RN9.4(A) U31.41 U6503.16
LAD1_FWH1: CPU1.AT1 DBGH1.8 RN9.3(A) U31.42 U6503.17
LAD2_FWH2: CPU1.AR2 DBGH1.4 RN9.2(A) U31.43 U6503.18
LAD3_FWH3: CPU1.AR1 DBGH1.2 RN9.1(A) U31.44 U6503.19
LAN_CLKREQ_N: LAN1.12 R270.2 R285.1
LAN_EEDO: LAN1.25 TP69.1
LAN_EESK: LAN1.27 R266.1
LAN_RSET: LAN1.31 R268.2
LAN_WAKE: CPU1.AP15 LAN1.21 R287.1
LAN_XTAL1: C294.1 LAN1.28 X3.3
LAN_XTAL2: C295.1 LAN1.29 X3.1
LCD_5V_EN: C375.2 Q32.3 R378.1 R379.1 U22.3
LCD_5V_EN1: Q32.2 R376.2
LCD_5V_EN2: Q32.1 R380.2 R382.1
LCD_5V_EN3: Q33.G Q34.5 Q34.6 R382.2 R384.1
LCD_5V_EN4: Q34.3 R379.2
LCD_BOOST_VOUT: C184.1 C230.1 C235.1 C236.1 C266.1 CNVBD2.9 CNVBD2.10 D5.K U59.18
LDR: R346.2 U59.1
LDR_1: Q78.4 R346.1
LDRQ0#: CPU1.AP1 R106.2
LDRQ#: R106.1 R561.1 U31.5
LDT_PWRGD_R: C23.2 CPU1.A19 R24.2
LDT_RST: CPU1.B20 R19.2 R20.1 R483.2
LDT_RST#_BUF: HDT1.12 R483.1
LDT_RST#_R: C22.2 CPU1.A20 R20.2
LEDGND: C177.2 C178.2 C179.2 C180.2 C181.1 C182.2 C183.2 C322.2 C323.2 Q101.S Q4808.S R338.2 R341.2 R342.2 R345.2 R355.2 R356.2 R1030.1 U59.15 U59.21
LFRAMEJ_FW4: CPU1.AP2 DBGH1.1 R127.2 R133.1 U31.40 U6503.15
LINK*_ACTIVITY_L: R266.2 TP64.1
LPC_CLK0_R: CPU1.AY2 R102.2
LPC_CLK1: C35.1 DBGH1.5 R103.1 R126.2 R132.1
LPC_CLK1_R: CPU1.AW2 R103.2
LPC_PME_N: R67.1 R515.2 U31.73 U6503.32
LPC_SIO_CLK0: C34.1 R102.1 R125.2 R131.1 U31.47 U6503.22
LPF: C178.1 U59.9
LX: D5.A L27.2 Q78.5 Q78.6 Q78.7 Q78.8 R350.1
M1_SMB_CLK: NGFFE1.60 R478.1
M1_SMB_DATA: NGFFE1.58 R479.1
M_ANALOGIN: CPU1.R32 TP14.1
M_ANALOGOUT: CPU1.N32 TP15.1
M_DP0_TXN0: C19.2 CPU1.B4
M_DP0_TXN1: C21.2 CPU1.B5
M_DP0_TXP0: C18.2 CPU1.A4
M_DP0_TXP1: C20.2 CPU1.A5
M_VREFDQ: CPU1.AC38 R3.2
MCLK: RN11.1(A) U31.83 U6503.41
MCT1: GDT1.2 R284.1 XF1.1 XF1.4 XF1.7 XF1.10
MCT_R: C292.1 R284.2
MDAT: RN11.2(A) U31.82 U6503.40
MDI0+: EC1.1 LAN1.1 U10.3 XF1.13
MDI0+_C: L25.3 XF1.12
MDI0+_R: L25.4 RJ1.1
MDI0-: EC2.1 LAN1.2 U10.4 XF1.14
MDI0-_C: L25.2 XF1.11
MDI0-_R: L25.1 RJ1.2
MDI1+: EC3.1 LAN1.4 U10.1 XF1.16
MDI1+_C: L23.3 XF1.9
MDI1+_R: L23.4 RJ1.3
MDI1-: EC4.1 LAN1.5 U10.6 XF1.17
MDI1-_C: L23.2 XF1.8
MDI1-_R: L23.1 RJ1.6
MDI2+: EC5.1 LAN1.6 U9.3 XF1.19
MDI2+_C: L24.3 XF1.6
MDI2+_R: L24.4 RJ1.4
MDI2-: EC6.1 LAN1.7 U9.4 XF1.20
MDI2-_C: L24.2 XF1.5
MDI2-_R: L24.1 RJ1.5
MDI3+: EC7.1 LAN1.9 U9.1 XF1.22
MDI3+_C: L22.3 XF1.3
MDI3+_R: L22.4 RJ1.7
MDI3-: EC8.1 LAN1.10 U9.6 XF1.23
MDI3-_C: L22.2 XF1.2
MDI3-_R: L22.1 RJ1.8
MEM_MA0_CKE0: CPU1.L34 DIMM1.73
MEM_MA0_CKE1: CPU1.J38 DIMM1.74
MEM_MA0_CLK0_N: CPU1.AC34 DIMM1.103
MEM_MA0_CLK0_P: CPU1.AC35 DIMM1.101
MEM_MA0_CLK1_N: CPU1.AA32 DIMM1.104
MEM_MA0_CLK1_P: CPU1.AA34 DIMM1.102
MEM_MA0_CS_L0: CPU1.AJ34 DIMM1.114
MEM_MA0_CS_L1: CPU1.AR38 DIMM1.121
MEM_MA0_ODT0: CPU1.AN38 DIMM1.116
MEM_MA0_ODT1: CPU1.AU38 DIMM1.120
MEM_MA_ADD0: CPU1.AG38 DIMM1.98
MEM_MA_ADD1: CPU1.W35 DIMM1.97
MEM_MA_ADD2: CPU1.W38 DIMM1.96
MEM_MA_ADD3: CPU1.W34 DIMM1.95
MEM_MA_ADD4: CPU1.U38 DIMM1.92
MEM_MA_ADD5: CPU1.U37 DIMM1.91
MEM_MA_ADD6: CPU1.U34 DIMM1.90
MEM_MA_ADD7: CPU1.R35 DIMM1.86
MEM_MA_ADD8: CPU1.R38 DIMM1.89
MEM_MA_ADD9: CPU1.N38 DIMM1.85
MEM_MA_ADD10: CPU1.AG34 DIMM1.107
MEM_MA_ADD11: CPU1.R34 DIMM1.84
MEM_MA_ADD12: CPU1.N37 DIMM1.83
MEM_MA_ADD13: CPU1.AN34 DIMM1.119
MEM_MA_ADD14: CPU1.L38 DIMM1.80
MEM_MA_ADD15: CPU1.L35 DIMM1.78
MEM_MA_BANK0: CPU1.AJ38 DIMM1.109
MEM_MA_BANK1: CPU1.AG35 DIMM1.108
MEM_MA_BANK2: CPU1.N34 DIMM1.79
MEM_MA_CAS#: CPU1.AL34 DIMM1.115
MEM_MA_DATA0: CPU1.B30 DIMM1.5
MEM_MA_DATA1: CPU1.A32 DIMM1.7
MEM_MA_DATA2: CPU1.B35 DIMM1.15
MEM_MA_DATA3: CPU1.A36 DIMM1.17
MEM_MA_DATA4: CPU1.B29 DIMM1.4
MEM_MA_DATA5: CPU1.A30 DIMM1.6
MEM_MA_DATA6: CPU1.A34 DIMM1.16
MEM_MA_DATA7: CPU1.B34 DIMM1.18
MEM_MA_DATA8: CPU1.B37 DIMM1.21
MEM_MA_DATA9: CPU1.A38 DIMM1.23
MEM_MA_DATA10: CPU1.D40 DIMM1.33
MEM_MA_DATA11: CPU1.D41 DIMM1.35
MEM_MA_DATA12: CPU1.B36 DIMM1.22
MEM_MA_DATA13: CPU1.A37 DIMM1.24
MEM_MA_DATA14: CPU1.B41 DIMM1.34
MEM_MA_DATA15: CPU1.C40 DIMM1.36
MEM_MA_DATA16: CPU1.F40 DIMM1.39
MEM_MA_DATA17: CPU1.F41 DIMM1.41
MEM_MA_DATA18: CPU1.K40 DIMM1.51
MEM_MA_DATA19: CPU1.K41 DIMM1.53
MEM_MA_DATA20: CPU1.E40 DIMM1.40
MEM_MA_DATA21: CPU1.E41 DIMM1.42
MEM_MA_DATA22: CPU1.J40 DIMM1.50
MEM_MA_DATA23: CPU1.J41 DIMM1.52
MEM_MA_DATA24: CPU1.M41 DIMM1.57
MEM_MA_DATA25: CPU1.N40 DIMM1.59
MEM_MA_DATA26: CPU1.T41 DIMM1.67
MEM_MA_DATA27: CPU1.U40 DIMM1.69
MEM_MA_DATA28: CPU1.L40 DIMM1.56
MEM_MA_DATA29: CPU1.M40 DIMM1.58
MEM_MA_DATA30: CPU1.R40 DIMM1.68
MEM_MA_DATA31: CPU1.T40 DIMM1.70
MEM_MA_DATA32: CPU1.AF40 DIMM1.129
MEM_MA_DATA33: CPU1.AF41 DIMM1.131
MEM_MA_DATA34: CPU1.AK40 DIMM1.141
MEM_MA_DATA35: CPU1.AK41 DIMM1.143
MEM_MA_DATA36: CPU1.AE40 DIMM1.130
MEM_MA_DATA37: CPU1.AE41 DIMM1.132
MEM_MA_DATA38: CPU1.AJ40 DIMM1.140
MEM_MA_DATA39: CPU1.AJ41 DIMM1.142
MEM_MA_DATA40: CPU1.AM41 DIMM1.147
MEM_MA_DATA41: CPU1.AN40 DIMM1.149
MEM_MA_DATA42: CPU1.AT41 DIMM1.157
MEM_MA_DATA43: CPU1.AU40 DIMM1.159
MEM_MA_DATA44: CPU1.AL40 DIMM1.146
MEM_MA_DATA45: CPU1.AM40 DIMM1.148
MEM_MA_DATA46: CPU1.AR40 DIMM1.158
MEM_MA_DATA47: CPU1.AT40 DIMM1.160
MEM_MA_DATA48: CPU1.AV41 DIMM1.163
MEM_MA_DATA49: CPU1.AW40 DIMM1.165
MEM_MA_DATA50: CPU1.BA38 DIMM1.175
MEM_MA_DATA51: CPU1.AY37 DIMM1.177
MEM_MA_DATA52: CPU1.AU41 DIMM1.164
MEM_MA_DATA53: CPU1.AV40 DIMM1.166
MEM_MA_DATA54: CPU1.AY39 DIMM1.174
MEM_MA_DATA55: CPU1.AY38 DIMM1.176
MEM_MA_DATA56: CPU1.BA36 DIMM1.181
MEM_MA_DATA57: CPU1.AY35 DIMM1.183
MEM_MA_DATA58: CPU1.BA32 DIMM1.191
MEM_MA_DATA59: CPU1.AY31 DIMM1.193
MEM_MA_DATA60: CPU1.BA37 DIMM1.180
MEM_MA_DATA61: CPU1.AY36 DIMM1.182
MEM_MA_DATA62: CPU1.BA33 DIMM1.192
MEM_MA_DATA63: CPU1.AY32 DIMM1.194
MEM_MA_DM0: CPU1.B32 DIMM1.11
MEM_MA_DM1: CPU1.B38 DIMM1.28
MEM_MA_DM2: CPU1.G40 DIMM1.46
MEM_MA_DM3: CPU1.N41 DIMM1.63
MEM_MA_DM4: CPU1.AG40 DIMM1.136
MEM_MA_DM5: CPU1.AN41 DIMM1.153
MEM_MA_DM6: CPU1.AY40 DIMM1.170
MEM_MA_DM7: CPU1.AY34 DIMM1.187
MEM_MA_DM8: CPU1.Y40 TP1.1
MEM_MA_DQS_N0: CPU1.A33 DIMM1.10
MEM_MA_DQS_N1: CPU1.A40 DIMM1.27
MEM_MA_DQS_N2: CPU1.H40 DIMM1.45
MEM_MA_DQS_N3: CPU1.P40 DIMM1.62
MEM_MA_DQS_N4: CPU1.AH40 DIMM1.135
MEM_MA_DQS_N5: CPU1.AP40 DIMM1.152
MEM_MA_DQS_N6: CPU1.AY41 DIMM1.169
MEM_MA_DQS_N7: CPU1.BA34 DIMM1.186
MEM_MA_DQS_P0: CPU1.B33 DIMM1.12
MEM_MA_DQS_P1: CPU1.B40 DIMM1.29
MEM_MA_DQS_P2: CPU1.H41 DIMM1.47
MEM_MA_DQS_P3: CPU1.P41 DIMM1.64
MEM_MA_DQS_P4: CPU1.AH41 DIMM1.137
MEM_MA_DQS_P5: CPU1.AP41 DIMM1.154
MEM_MA_DQS_P6: CPU1.BA40 DIMM1.171
MEM_MA_DQS_P7: CPU1.AY33 DIMM1.188
MEM_MA_EVENT_L: CPU1.AE34 DIMM1.198 R1.2 R2.2
MEM_MA_RAS#: CPU1.AJ37 DIMM1.110
MEM_MA_RESET#: C159.2 CPU1.G38 DIMM1.30
MEM_MA_WE#: CPU1.AL35 DIMM1.113
MEM_VREFCA_SUS: C175.1 C176.2 DIMM1.126 R140.2 R142.1 R146.1
MEM_ZVDDIO: CPU1.AD41 R4.1
MIC2: C254.2 C255.2 R234.1
MIC_IN_JACK: L18.1 R232.1 R234.2 R235.1
MIC_VREFL: AUDIO1.31 R232.2
MIC_VREFR: AUDIO1.30 TP32.1
MODE_CFG0: R600.1 R601.1 U38.47
MODE_CFG1: R604.1 R605.1 U38.48
NGFF_SUSCLK: NGFFE1.50 TP70.1
OCP_0: PC1.1 PR2.1 PR3.2 U48.2
OCP_1: PR4.2 PR7.2 U48.3
OCP_2: PC1.2 PR2.2 PR4202.1 U48.1
OCP_3: PC4205.1 PR10.1 PR4202.2 U48.5
OCP_6: PR12.2 PR16.1 Q76.5 Q76.6
OCP_7: PR11.2 PR13.1 Q75.G Q76.3
OCP_8: PC6.1 R808.1 R809.1 R810.1 U48.6
OZ554_EMA: C322.1 Q4802.G R354.1 R356.1 R1028.1 U59.3
OZ554_PWM: C323.1 R353.1 R355.1 U59.5
OZ554_VIN: C182.1 R339.2 U59.4
P_1.2V_EDP: C507.1 C508.1 C509.1 C510.1 L52.2 R590.2 U38.11 U38.15 U38.43
P_1.05VLAN_OUT: L21.1 LAN1.24 R269.1
P_3.3V_EDP_VDDIO: C498.1 C499.1 C500.1 L51.2 R591.1 R592.1 R598.1 R599.1 R600.2 R604.2 U38.5 U58.3 U58.8
P_3.3V_EDP_VDDIOX: C501.1 C502.1 C503.1 C504.1 C505.1 C506.1 L53.2 U38.18 U38.22
P_RX_ZVDD: CPU1.W7 R9.1
P_TX_ZVDD: CPU1.W8 R8.2
PB_IN_N_1: C491.2 R575.1 R576.2 U31.75 U6503.33
PCH_CLK48: C33.2 R101.1 R547.1
PCH_CLK48_F: CPU1.AP13 R101.2
PCH_SPKR1: C324.2 C325.2 R359.1 R360.1
PCIE_C_RXN0: C276.2 CPU1.R8
PCIE_C_RXN1: CPU1.R4 NGFFE1.43
PCIE_C_RXP0: C277.2 CPU1.R10
PCIE_C_RXP1: CPU1.R5 NGFFE1.41
PCIE_C_TXN0: C5.2 LAN1.14
PCIE_C_TXN1: C7.2 NGFFE1.37
PCIE_C_TXP0: C4.2 LAN1.13
PCIE_C_TXP1: C6.2 NGFFE1.35
PCIE_RST_N: CPU1.AY9 R64.2
PCIE_RST_N_R: C25.2 R64.1
PCIE_RXN_LAN_C: C276.1 LAN1.18
PCIE_RXP_LAN_C: C277.1 LAN1.17
PCIE_WAKE_N_PCIE: CPU1.AW11 NGFFE1.55 R77.1
PCIRST1#: RN8.3(B) RN8.4(B) RN10.4(B) U31.33 U6503.10
PCIRST2#: RN10.3(B) U31.34
PD: Q4.5 Q4.6 R175.1
PD#_C: AUDIO1.4 Q4.3 R176.2 R179.2
PLT_WLAN_RST: C460.1 NGFFE1.52 R6104.2 R6105.2
PLT_WLAN_RST#: R6104.1 RN8.1(A)
PLTRST*_SIO: C26.1 C27.2 R63.2 R501.1 U31.49 U6503.13
PLTRST_LAN: LAN1.19 RN8.2(A)
PME#_M: CPU1.AN5 R67.2
PS8625_BKLT_EN: R365.1 R614.1 U38.44
PS8625_BKLT_PWM: R374.2 R610.1 U38.19
PS8625_HPD: Q57.D R615.1 U38.1
PS8625_INI_SCL: R602.2 U58.6
PS8625_INI_SCL_R: R598.2 R602.1 U38.46
PS8625_INI_SDA: R603.2 U58.5
PS8625_INI_SDA_R: R597.1 R599.2 R603.1 U38.45
PS8625_LCD_PW_EN: C511.1 R381.1 R613.1 U38.20
PS8625_ROM2_CLK: R591.2 R593.1 R595.1 U38.13
PS8625_ROM2_DAT: R592.2 R594.1 R596.1 U38.14
PS8625_SW: L52.1 R590.1 U38.17
PWR_1D8V: PC5105.1 PC5106.1 PC5107.1 PC5108.1 PL5101.2 PR5102.1 PR5105.1 PR5211.1
PWR_1D8V_EN: PC5110.1 PR5208.1 PR5209.2 PU5101.5 R5101.1 RN19.3(B)
PWR_1D8V_FB: PC5108.2 PC5109.1 PR5105.2 PR5107.1 PU5101.6
PWR_1D8V_FB_A: PC5109.2 PR5108.1
PWR_1D8V_PH: PC5104.1 PL5101.1 PU5101.1 PU5101.2 PU5101.3
PWR_1D8V_PVIN: PC5101.1 PC5102.1 PR5101.2 PR5103.1 PR5212.2 PU5101.9 PU5101.10
PWR_1D8V_SNB: PC5104.2 PR5104.1
PWR_1D8V_SVIN: PC5103.1 PR5103.2 PU5101.8
PWR_3D3V: PC4911.1 PG4902.2 PL4901.1 PR4914.2 PR4915.2 PR4916.2 PR4929.2 PR4930.2 PT4902.1
PWR_3D3V_BOOT: PR4908.2 PU4901.7
PWR_3D3V_BOOT_A: PC4909.2 PR4908.1
PWR_3D3V_ENTRIP1_D: PR4926.2 Q4806.D R6568.1
PWR_3D3V_ENTRIP2: PC4920.1 PR4927.1 PU4901.4
PWR_3D3V_ENTRIP2_D: PR4927.2 Q4805.D R6569.1
PWR_3D3V_FB: PC4916.1 PR4917.2 PR4921.1 PU4901.5
PWR_3D3V_FB_A: PC4916.2 PG4902.1 PR4917.1
PWR_3D3V_HG: PR4911.1 PU4901.8
PWR_3D3V_HG_A: PQ4901.4 PR4911.2
PWR_3D3V_LDO3: PC4914.1 PG4904.1 PU4901.15
PWR_3D3V_LG: PQ4903.4 PU4901.10
PWR_3D3V_PH: PC4909.1 PC4913.1 PL4901.2 PQ4901.1 PQ4901.2 PQ4901.3 PQ4903.5 PQ4903.6 PQ4903.7 PQ4903.8 PU4901.9
PWR_3D3V_SNB: PC4913.2 PR4920.1
PWR_5V: PC4915.1 PC4917.1 PG4903.1 PL4902.2 PR4906.2 PR4907.2 PR4910.2 PR4913.2 PT4903.1 PU4901.20
PWR_5V3V_EMN: PR4922.2 PR4925.1 PU4901.13
PWR_5V3V_ENLDO: PR4901.2 PU4901.12
PWR_5V3V_LDO5: PC4906.1 PG4901.1 PU4901.14
PWR_5V3V_PGOOD: PR4928.2 PU4901.6
PWR_5V3V_TON: PR4924.1 PU4901.3
PWR_5V3V_VIN: PC4905.1 PR4901.1 PR4905.2 PU4901.11
PWR_5V_BOOT: PR4909.1 PU4901.19
PWR_5V_BOOT_A: PC5208.1 PR4909.2
PWR_5V_ENTRIP1: PC4919.1 PR4926.1 PU4901.2
PWR_5V_FB: PC4918.2 PR4918.1 PR4923.1 PU4901.1
PWR_5V_FB_A: PC4918.1 PG4903.2 PR4918.2
PWR_5V_HG: PR4912.1 PU4901.18
PWR_5V_HG_A: PQ4902.4 PR4912.2
PWR_5V_LG: PQ4904.4 PU4901.16
PWR_5V_PH: PC4912.1 PC5208.2 PL4902.1 PQ4902.1 PQ4902.2 PQ4902.3 PQ4904.5 PQ4904.6 PQ4904.7 PQ4904.8 PU4901.17
PWR_5V_SNB: PC4912.2 PR4919.1
PWR_AD+_2: PC8.2 PR17.1 PR18.1 PU2.4
PWR_CORE_BOOT1: PR4445.1 PU4401.21
PWR_CORE_BOOT1_A: PC4431.1 PR4445.2
PWR_CORE_HG1: PR4442.1 PU4401.22
PWR_CORE_HG1_A: PQ4403.4 PR4442.2 PR4463.1
PWR_CORE_ISUMN: PC4430.2 PC4433.1 PC4439.1 PC4440.1 PR4446.1 PR4447.1 PR4448.1 PR4449.1 PR4451.1 PR4462.2
PWR_CORE_ISUMP: PC4439.2 PC4440.2 PR4451.2 PR4453.2 PR4461.2 PU4401.14
PWR_CORE_LG1: PQ4404.4 PQ4405.4 PU4401.24
PWR_CORE_PH1: PC4431.2 PC4434.1 PG4404.1 PL4904.1 PQ4403.1 PQ4403.2 PQ4403.3 PQ4404.5 PQ4404.6 PQ4404.7 PQ4404.8 PQ4405.5 PQ4405.6 PQ4405.7 PQ4405.8 PR4463.2 PU4401.23
PWR_CORE_PH1N: PG4403.2 PR4462.1
PWR_CORE_PH1P: PG4404.2 PR4461.1
PWR_CORE_SNB: PC4434.2 PR4455.1
PWR_CORE_VIN: PC4425.1 PC4426.1 PC4427.1 PC4428.1 PC4445.1 PQ4403.5 PQ4403.6 PQ4403.7 PQ4403.8 PR4432.1 PR4433.1
PWR_CPU_COMP: PC4435.1 PC4441.1 PR4460.1 PU4401.19
PWR_CPU_COMP_A: PC4441.2 PR4456.1
PWR_CPU_COMPNB: PC4404.1 PC4412.1 PR4408.1 PU4401.36
PWR_CPU_COMPNB_A: PC4412.2 PR4411.1
PWR_CPU_EN: PR4430.2 PU4401.8
PWR_CPU_FB: PC4435.2 PR4450.1 PR4452.1 PU4401.18
PWR_CPU_FB_A: PC4436.1 PR4450.2
PWR_CPU_FB_B: PR4452.2 PR4456.2 PR4457.1 PR4459.1
PWR_CPU_FB_C: PC4442.1 PR4459.2
PWR_CPU_FBNB: PC4404.2 PR4404.1 PR4407.1 PR4411.2 PR4412.1 PU4401.37
PWR_CPU_FBNB_A: PC4405.1 PR4407.2
PWR_CPU_FBNB_B: PC4403.1 PR4404.2
PWR_CPU_IMON: PC4424.1 PR4434.1 PU4401.10
PWR_CPU_ISEN1: PC4430.1 PR4443.1 PU4401.13
PWR_CPU_ISEN2: PR4440.2 PU4401.12
PWR_CPU_ISUMN: PC4438.2 PR4446.2 PU4401.15
PWR_CPU_ISUMN_A: PC4438.1 PR4449.2
PWR_CPU_ISUMNNB: PC4413.2 PR4418.2 PU4401.39
PWR_CPU_ISUMNNB_B: PC4413.1 PR4413.2
PWR_CPU_ISUMP_A: PR4448.2 PR4453.1
PWR_CPU_NB_IMON: PC4401.2 PR4425.2 PU4401.2
PWR_CPU_NB_NTC: PR4401.2 PR4422.1 PU4401.1
PWR_CPU_NB_NTCA: PR4401.1 PR4421.2 PR4422.2
PWR_CPU_NTC: PR4435.2 PR4439.1 PU4401.11
PWR_CPU_NTC_A: PR4435.1 PR4438.2 PR4439.2
PWR_CPU_PWROK: PR4431.2 PU4401.9
PWR_CPU_RTN: PC4432.1 PR4437.1 PR4441.1 PR4444.1 PU4401.17
PWR_CPU_VDD: PC4422.1 PR4427.2 PU4401.25
PWR_CPU_VDDIO: PC4423.1 PR4429.2 PU4401.6
PWR_CPU_VDDP: PC4421.1 PR4426.2 PU4401.26
PWR_CPU_VR_HOT: PR4428.2 PU4401.4
PWR_CPU_VSEN: PC4436.2 PC4437.1 PR4454.1 PR4457.2 PR4458.1 PU4401.16
PWR_CPU_VSENNB: PC4402.1 PC4405.2 PC4414.1 PR4402.1 PR4403.1 PR4412.2 PU4401.38
PWR_DCBATOUT_5V3D3V: PC4901.1 PC4902.1 PC4903.1 PC4907.1 PC4908.1 PC4922.1 PC4923.1 PQ4901.5 PQ4901.6 PQ4901.7 PQ4901.8 PQ4902.5 PQ4902.6 PQ4902.7 PQ4902.8 PR4902.2 PR4903.2 PR4904.2 PR4905.1
PWR_DCBATOUT_VDDP: PC4803.1 PC4804.1 PQ4801.5 PQ4801.6 PQ4801.7 PQ4801.8 PR4802.2
PWR_DCBATOUT_VDDQ: PC5005.1 PC5006.1 PC5007.1 PQ5001.5 PQ5001.6 PQ5001.7 PQ5001.8 PR5002.2 PR5008.1
PWR_ID0: CNVBD2.4 EC705.1 Q4808.G R822.2 U6503.58
PWR_ID1: CNVBD2.5 EC706.1 R823.2 U31.57
PWR_ID2: CNVBD2.6 EC707.1 R824.2 U31.79
PWR_V1P5A: PC5206.1 PR5204.1 PU5201.5
PWR_V1P5A_EN: PC5203.1 PR5206.1 PU5201.3 R5201.2 R5202.2
PWR_V1P5A_VIN: PC5205.1 PR5201.2 PU5201.1
PWR_VDDNB_BOOT: PR4417.1 PU4401.31
PWR_VDDNB_BOOT_A: PC4415.1 PR4417.2
PWR_VDDNB_HG: PR4415.1 PU4401.32
PWR_VDDNB_HG_A: PQ4401.4 PR4415.2 PR4464.1
PWR_VDDNB_ISUMN: PC4410.2 PC4411.2 PC4416.1 PR4413.1 PR4414.2 PR4416.2 PR4418.1 PR4424.2
PWR_VDDNB_ISUMP: PC4410.1 PC4411.1 PR4410.1 PR4414.1 PR4423.2 PU4401.40
PWR_VDDNB_ISUMP_A: PR4410.2 PR4416.1
PWR_VDDNB_LG: PQ4402.4 PU4401.34
PWR_VDDNB_PH: PC4415.2 PC4417.2 PG4401.1 PL4905.1 PQ4401.1 PQ4401.2 PQ4401.3 PQ4402.5 PQ4402.6 PQ4402.7 PQ4402.8 PR4464.2 PU4401.33
PWR_VDDNB_PH_N: PG4402.2 PR4424.1
PWR_VDDNB_PH_P: PG4401.2 PR4423.1
PWR_VDDNB_SNB: PC4417.1 PR4420.1
PWR_VDDNB_VIN: PC4407.1 PC4408.1 PC4409.1 PC4443.1 PQ4401.5 PQ4401.6 PQ4401.7 PQ4401.8 PR4405.1 PR4406.1
PWR_VDDP: PC4808.1 PC4809.1 PG4801.1 PL4906.2 PR4808.2 PR4810.2 PR4811.2 PR4814.1 PT4411.1
PWR_VDDP_BOOT: PR4806.1 PU4801.10
PWR_VDDP_BOOT_A: PC4805.2 PR4806.2
PWR_VDDP_CS: PR4805.2 PU4801.2
PWR_VDDP_EN: C4801.1 PC4801.1 PU4801.3 R4801.2 R4802.2 R4803.1
PWR_VDDP_FB: PC4810.2 PR4813.2 PR4815.1 PU4801.4
PWR_VDDP_FB_A: PC4810.1 PG4801.2 PR4813.1
PWR_VDDP_HG: PR4804.1 PU4801.9
PWR_VDDP_HG_A: PQ4801.4 PR4804.2
PWR_VDDP_LG: PQ4802.4 PU4801.6
PWR_VDDP_PH: PC4805.1 PC4807.1 PL4906.1 PQ4801.1 PQ4801.2 PQ4801.3 PQ4802.5 PQ4802.6 PQ4802.7 PQ4802.8 PU4801.8
PWR_VDDP_RF: PR4809.1 PU4801.5
PWR_VDDP_SNB: PC4807.2 PR4812.1
PWR_VDDQ: PC5011.1 PC5012.1 PC5207.1 PG4905.1 PL5001.2 PR5013.2 PR5015.2 PR5016.2 PR5017.2 PR5018.2 PR5213.2 PT5001.1
PWR_VDDQ_BOOT: PR5007.1 PU5001.18
PWR_VDDQ_BOOT_A: PC5008.1 PR5007.2
PWR_VDDQ_CS: PC5002.2 PR5004.2 PU5001.13
PWR_VDDQ_EN: C5001.1 PU5001.8 R5002.2 RN21.3(B)
PWR_VDDQ_FB: PC5013.2 PR5020.2 PR5022.1 PU5001.6
PWR_VDDQ_HG: PR5009.1 PU5001.17
PWR_VDDQ_HG_A: PQ5001.4 PR5009.2
PWR_VDDQ_LG: PQ5002.4 PU5001.15
PWR_VDDQ_PH: PC5008.2 PC5010.1 PL5001.1 PQ5001.1 PQ5001.2 PQ5001.3 PQ5002.5 PQ5002.6 PQ5002.7 PQ5002.8 PU5001.16
PWR_VDDQ_SENSE: PC5013.1 PR5018.1 PR5020.1 PU5001.5
PWR_VDDQ_SNB: PC5010.2 PR5019.1
PWR_VDDQ_TON: PR5008.2 PU5001.9
PWR_VDDQ_VDD: PC5001.1 PC5002.1 PR5001.1 PR5004.1 PU5001.11
PWR_VDDQ_VDDP: PC5204.1 PR5005.1 PU5001.12
PWR_VDDQ_VTT_EN: C5002.1 PU5001.7 R5002.1 RN21.4(B)
PWR_VDDQ_VTTIN: PC5009.1 PR5011.2 PU5001.19
PWR_VDDQ_VTTOUT: PC5014.1 PC5015.1 PR5021.1 PU5001.2 PU5001.20
PWRBTN#: EC702.1 L56.1 PWRBT1.2
PWRBTN#_1: L56.2 R622.1 R623.2 R6551.1
PWRBTN_IN: C512.1 R575.2 R623.1
PWRGD_3V_B_1: Q49.5 Q49.6 R581.2
PWRGD_3V_LL: Q49.3 R582.2
PWRGD_PS_L: C480.1 Q45.2 R530.2 R537.1
PWRGD_PS_L1: Q45.5 Q45.6 R529.2
PWRGD_PS_L2: Q45.3 R536.1
PWRLED_CON: L54.1 PWRBT1.4
PWROK3_1: R543.2 U31.32 U6503.36
PWROK3_1_R: R543.1 R579.2 R580.1
PWROK3_2: R540.1 U31.78 U6503.9
PWROK3_2_R: R540.2 R563.1 R584.1
Q5102_GATE: Q36.G R395.2
Q5103_GATE: Q38.G R396.2
REMOTE1+: C468.1 RN20.3(B) RT1.1 U31.90 U6503.46
ROM_RST#: CPU1.AU9 R105.1
RSMRST*_R: Q49.2 R584.2
RSMRST_N: D1.2 R518.2 R534.2
RSMRST_N_FCH: C24.1 CPU1.AY5 D1.3 R62.2
RT: R338.1 U59.10
RTC_CLK: CPU1.AV11 R129.2 R135.1
RTL_ISOLATE_N: LAN1.20 R286.2 R288.1
RUN_EN: C310.1 C327.1 R302.1 R307.2 U16.G
RUNPWR_G: Q26.G R1014.2 R1015.2
RUNPWR_R3: R306.1 R307.1
RUNPWR_R4: Q27.5 Q27.6 R309.2
RUNPWR_R5: Q27.3 R303.2 R306.2
RUNPWR_R6: Q26.D Q27.2 R310.2 U13.3 U13.5
S0_PWR_GOOD: C494.1 D2.2 Q76.2 R580.2 R582.1 R583.1
SATA_CALRN: CPU1.AP19 R98.2
SATA_CALRP: CPU1.AR19 R97.2
SATA_RX0N: CPU1.BA16 TR26.1
SATA_RX0P: CPU1.AY16 TR26.4
SATA_RX1N: CPU1.AY17 TR28.4
SATA_RX1P: CPU1.BA17 TR28.1
SATA_RXN0_C: C414.1 TR26.2
SATA_RXN0_N: C414.2 HDD1.S5
SATA_RXN1_C: C425.1 TR28.3
SATA_RXN1_N: C425.2 ODD1.5
SATA_RXP0_C: C411.1 TR26.3
SATA_RXP0_N: C411.2 HDD1.S6
SATA_RXP1_C: C424.1 TR28.2
SATA_RXP1_N: C424.2 ODD1.6
SATA_TX0N: CPU1.AY14 TR25.4
SATA_TX0P: CPU1.BA14 TR25.1
SATA_TX1N: CPU1.BA19 TR27.1
SATA_TX1P: CPU1.AY19 TR27.4
SATA_TXN0_C: C410.1 TR25.3
SATA_TXN0_N: C410.2 HDD1.S3
SATA_TXN1_C: C423.1 TR27.2
SATA_TXN1_N: C423.2 ODD1.3
SATA_TXP0_C: C409.1 TR25.2
SATA_TXP0_N: C409.2 HDD1.S2
SATA_TXP1_C: C422.1 TR27.3
SATA_TXP1_N: C422.2 ODD1.2
SCALAR_VDD_EN1: Q34.2 R381.2 R383.2 R386.2
SD_CD#: CPU1.AY20 CRS1.11 EC709.1
SD_CLK: CRS1.5 EC302.1 R1026.2
SD_CLK_CH: CPU1.AY22 R1026.1
SD_CMD: CRS1.2 EC328.1 R1027.2
SD_CMD_CH: CPU1.AY23 R1027.1
SD_DATA0: CRS1.7 EC327.1 R1022.2
SD_DATA0_CH_C: CPU1.BA22 R1022.1
SD_DATA1: CRS1.8 EC708.1 R1023.2
SD_DATA1_CH_C: CPU1.AY21 R1023.1
SD_DATA2: CRS1.9 EC330.1 R1024.2
SD_DATA2_CH_C: CPU1.AY24 R1024.1
SD_DATA3: CRS1.1 EC329.1 R1025.2
SD_DATA3_CH_C: CPU1.BA24 R1025.1
SD_PWRCTL_CH: CPU1.BA23 TP55.1
SD_WP: CPU1.BA20 CRS1.10 EC326.1
SENSE_A: AUDIO1.13 R172.1
SERIRQ_N: CPU1.AV29 R562.1 U31.39 U6503.14
SIO_3VSB: R6540.1 R6541.1 U6503.11
SIO_AGND: C468.2 C469.2 C471.2 C472.2 C473.2 C474.2 C475.2 C479.2 C681.2 R500.2 R503.2 R514.2 R521.2 R522.2 RT1.2 RT2.2 U31.86 U31.87 U6503.44
SIO_AMD SVID_EN: R542.1 U31.29
SIO_ATXPG: R531.1 R536.2 U31.19 U6503.6
SIO_AVCC3: C476.1 C477.1 L50.1 U31.99
SIO_BLEN: Q4802.D R6532.1 U6503.4
SIO_BLEN_SMI: Q4803.S R6534.2 U6503.3
SIO_BOARD_ID1: R505.2 R510.1 U31.14 U6503.55
SIO_BOARD_ID2: R504.2 R509.1 U31.6
SIO_BOARD_ID3: R520.2 R523.1 U31.16
SIO_CE_N: R548.1 U31.30 U56.1
SIO_CLK_DB: RN15.2(A) TP65.1 U31.51
SIO_COPEN#: R546.1 U31.68 U6503.28
SIO_DAT_DB: RN15.1(A) TP66.1 U31.52
SIO_DEBUG_RX: R512.1 TP34.1 U31.125 U6503.60
SIO_DEBUG_TX: R511.1 R6545.2 TP33.1 U31.124 U6503.59
SIO_GP31: CPU1.AV31 R6546.2 R6547.2
SIO_GP45: CPU1.AU31 R6548.2 R6549.2
SIO_HOLD#: R551.1 U56.7
SIO_JP2: R6559.2 R6560.1 U6503.57
SIO_K8PWR_EN: R513.1 TP35.1 U31.126 U6503.61
SIO_MAIN_VCC3: R526.1 R1031.1 U31.92 U6503.53
SIO_MEM_EVENT_L: R1.1 U31.54
SIO_PCIRSTIN#: R556.1 U31.3
SIO_PSON_N: Q98.G Q4807.G R527.2 R1015.1 R6550.2 U31.76 U6503.34
SIO_PSON_N_D: Q98.D R1031.2
SIO_PWNBTN_N: CPU1.BA8 R576.1 R577.2
SIO_SCK: C487.1 R539.1 R552.1 U56.6
SIO_SCK_R: R539.2 U31.25
SIO_SI: R553.1 U31.24 U56.5
SIO_SMCLK0: Q50.D R609.2 U31.63
SIO_SMCLK0_1: Q50.S R595.2
SIO_SMCLK0_2: Q50.G R607.2
SIO_SMDAT0: Q51.D R608.2 U31.64
SIO_SMDAT0_1: Q51.S R596.2
SIO_SMDAT0_2: Q51.G R606.2
SIO_SO: R549.1 U31.48 U56.2
SIO_VCORE: C483.1 C484.1 U31.36 U6503.12
SIO_VIN1: C681.1 R832.2 U31.97 U6503.51
SIO_VIN2: C475.1 R519.1 R521.1 U31.96 U6503.50
SIO_VIN3: C471.1 R499.1 R500.1 U31.95
SIO_VIN4: C472.1 R502.1 R503.1 U31.94 U6503.48
SIO_VIN5: C473.1 R508.1 R514.1 U31.93 U6503.49
SIO_VREF: C479.1 RN20.1(A) RN20.2(A) U31.91 U6503.47
SIO_WP#: R550.1 U56.3
SIO_WRST#: C488.1 R559.2 U31.50
SLP_S3_N: CPU1.AY3 D2.1 Q99.G R79.1 R6562.1 RN21.1(A) U31.71 U6503.30
SLP_S5_N: CPU1.BA5 R80.1 R439.1 R440.1 R541.2 RN21.2(A)
SLP_S5_N_R: R541.1 U31.77 U6503.35
SMB0_CLK: C179.1 CPU1.AU25 DIMM1.202 L2901.3 L2901.4 R593.2 RN5.4(B) RN12.3(B) U31.66 U59.6
SMB0_DATA: C180.1 CPU1.AV25 DIMM1.200 L2901.1 L2901.2 R594.2 RN5.3(B) RN12.4(B) U31.65 U59.7
SMB1_CLK: CPU1.AY11 R478.2 RN3.4(B)
SMB1_DATA: CPU1.BA11 R479.2 RN3.3(B)
SNB: C246.1 R350.2
SPEED_100*_L: LAN1.26 TP68.1
SPI_CLK: C430.1 CPU1.AU7 R431.2
SPI_CLK_R: R431.1 SPI1.6 U30.6
SPI_CS0_N: CPU1.AW9 RN6.2(A) SPI1.1 U30.1
SPI_DATAIN: CPU1.AR7 R430.1
SPI_DATAOUT: C429.1 CPU1.AR11 R433.2
SPI_SI_R: R433.1 SPI1.5 U30.5
SPI_SO: C428.1 R430.2 SPI1.2 U30.2
SPI_SW: CPU1.AV17 R128.2 R134.1
SPI_WP#: R105.2 R432.2 RN6.3(A) SPI1.3 U30.3
SPI_WP#_R: Q39.D R432.1
SPI_WP_R_N: Q39.G R524.1 U31.28
SPKR: CPU1.BA27 R360.2
SPKR_L+: AUDIO1.40 L7.1
SPKR_L-: AUDIO1.41 L9.1
SPKR_OUT_L+_C: C237.1 L7.2 SPK1.1
SPKR_OUT_L-_C: C243.1 L9.2 SPK1.2
SPKR_OUT_R+_C: C245.1 L11.2 SPK1.3
SPKR_OUT_R-_C: C247.1 L13.2 SPK1.4
SPKR_R+: AUDIO1.45 L11.1
SPKR_R-: AUDIO1.44 L13.1
SST_HOLDJ_1: R104.2 RN6.4(A) SPI1.7 U30.7
SST_HOLDJ_1_R: CPU1.AU11 R104.1
SSTCMP: Q101.D R322.1 U59.11
SSTCMP_1: C177.1 R322.2
STATUS: R345.1 U59.8
SUSLED_1: Q52.1 R619.1
SUSLED_2: Q4804.D R616.2 R617.2 R619.2 R620.1
SUSLED_CON: EC703.1 L55.1 PWRBT1.5 R624.1 U39.3
SUSLED_CON_P1: Q52.3 R621.1
SUSLED_N: Q4804.S R1012.1 R1013.1 R6535.2 U6503.37
SUSLED_R_N_1: R1012.2 U31.22
SUSLED_R_N_PWM: R1013.2 U31.11
SVC_VDD: PU4401.3 R50.2 R54.2 R60.1
SVD_VDD: PU4401.5 R51.2 R55.2 R61.1
SVT_VDD: PU4401.7 R49.2 R53.2
SW_ON_N_SIO: R517.2 R535.2 R577.1 U31.72 U6503.31
SYS_3VSB: R544.1 U31.70 U6503.27
SYS_ID2: CPU1.AU21 R69.2 R73.1
SYS_ID3: CPU1.AY26 R70.2 R74.1
SYS_PWRGD: CPU1.AM19 D2.3 D3.3 R65.1 R92.2
SYS_PWRGD_HV: Q1.D Q4801.G R86.2
SYS_PWRGD_HV_1: Q1.G Q2.C R87.1
SYS_PWRGD_HV_2: C32.1 Q2.B R92.1
TEST18_M: CPU1.B28 R26.1 R488.2
TEST19_M: CPU1.A28 R27.1 R487.2
TEST_MODE: R586.1 U38.2
THERMAL_SHUT#: CPU1.BA4 R81.1 R538.1
THERMAL_SHUT#_SIO: R538.2 U31.23 U6503.8
TMON_CAL: CPU1.AP29 TP16.1
TP20: CPU1.W4 TP29.1
TP29: CPU1.AV23 TP23.1
TP48: CPU1.AP21 TP24.1
TP49: CPU1.BA26 TP25.1
TP51: CPU1.BA28 TP22.1
TP52: CPU1.AN8 TP27.1
TP53: CPU1.BA6 TP28.1
TP_LPC_CLKRUN#: CPU1.AP25 TP30.1
TP_LPC_PD#: CPU1.AV2 TP31.1
USB30_EN: R866.2 R867.2 U51.4
USB30_RN0_C: D19.1 D19.10 TR11.1 USB3S1.5
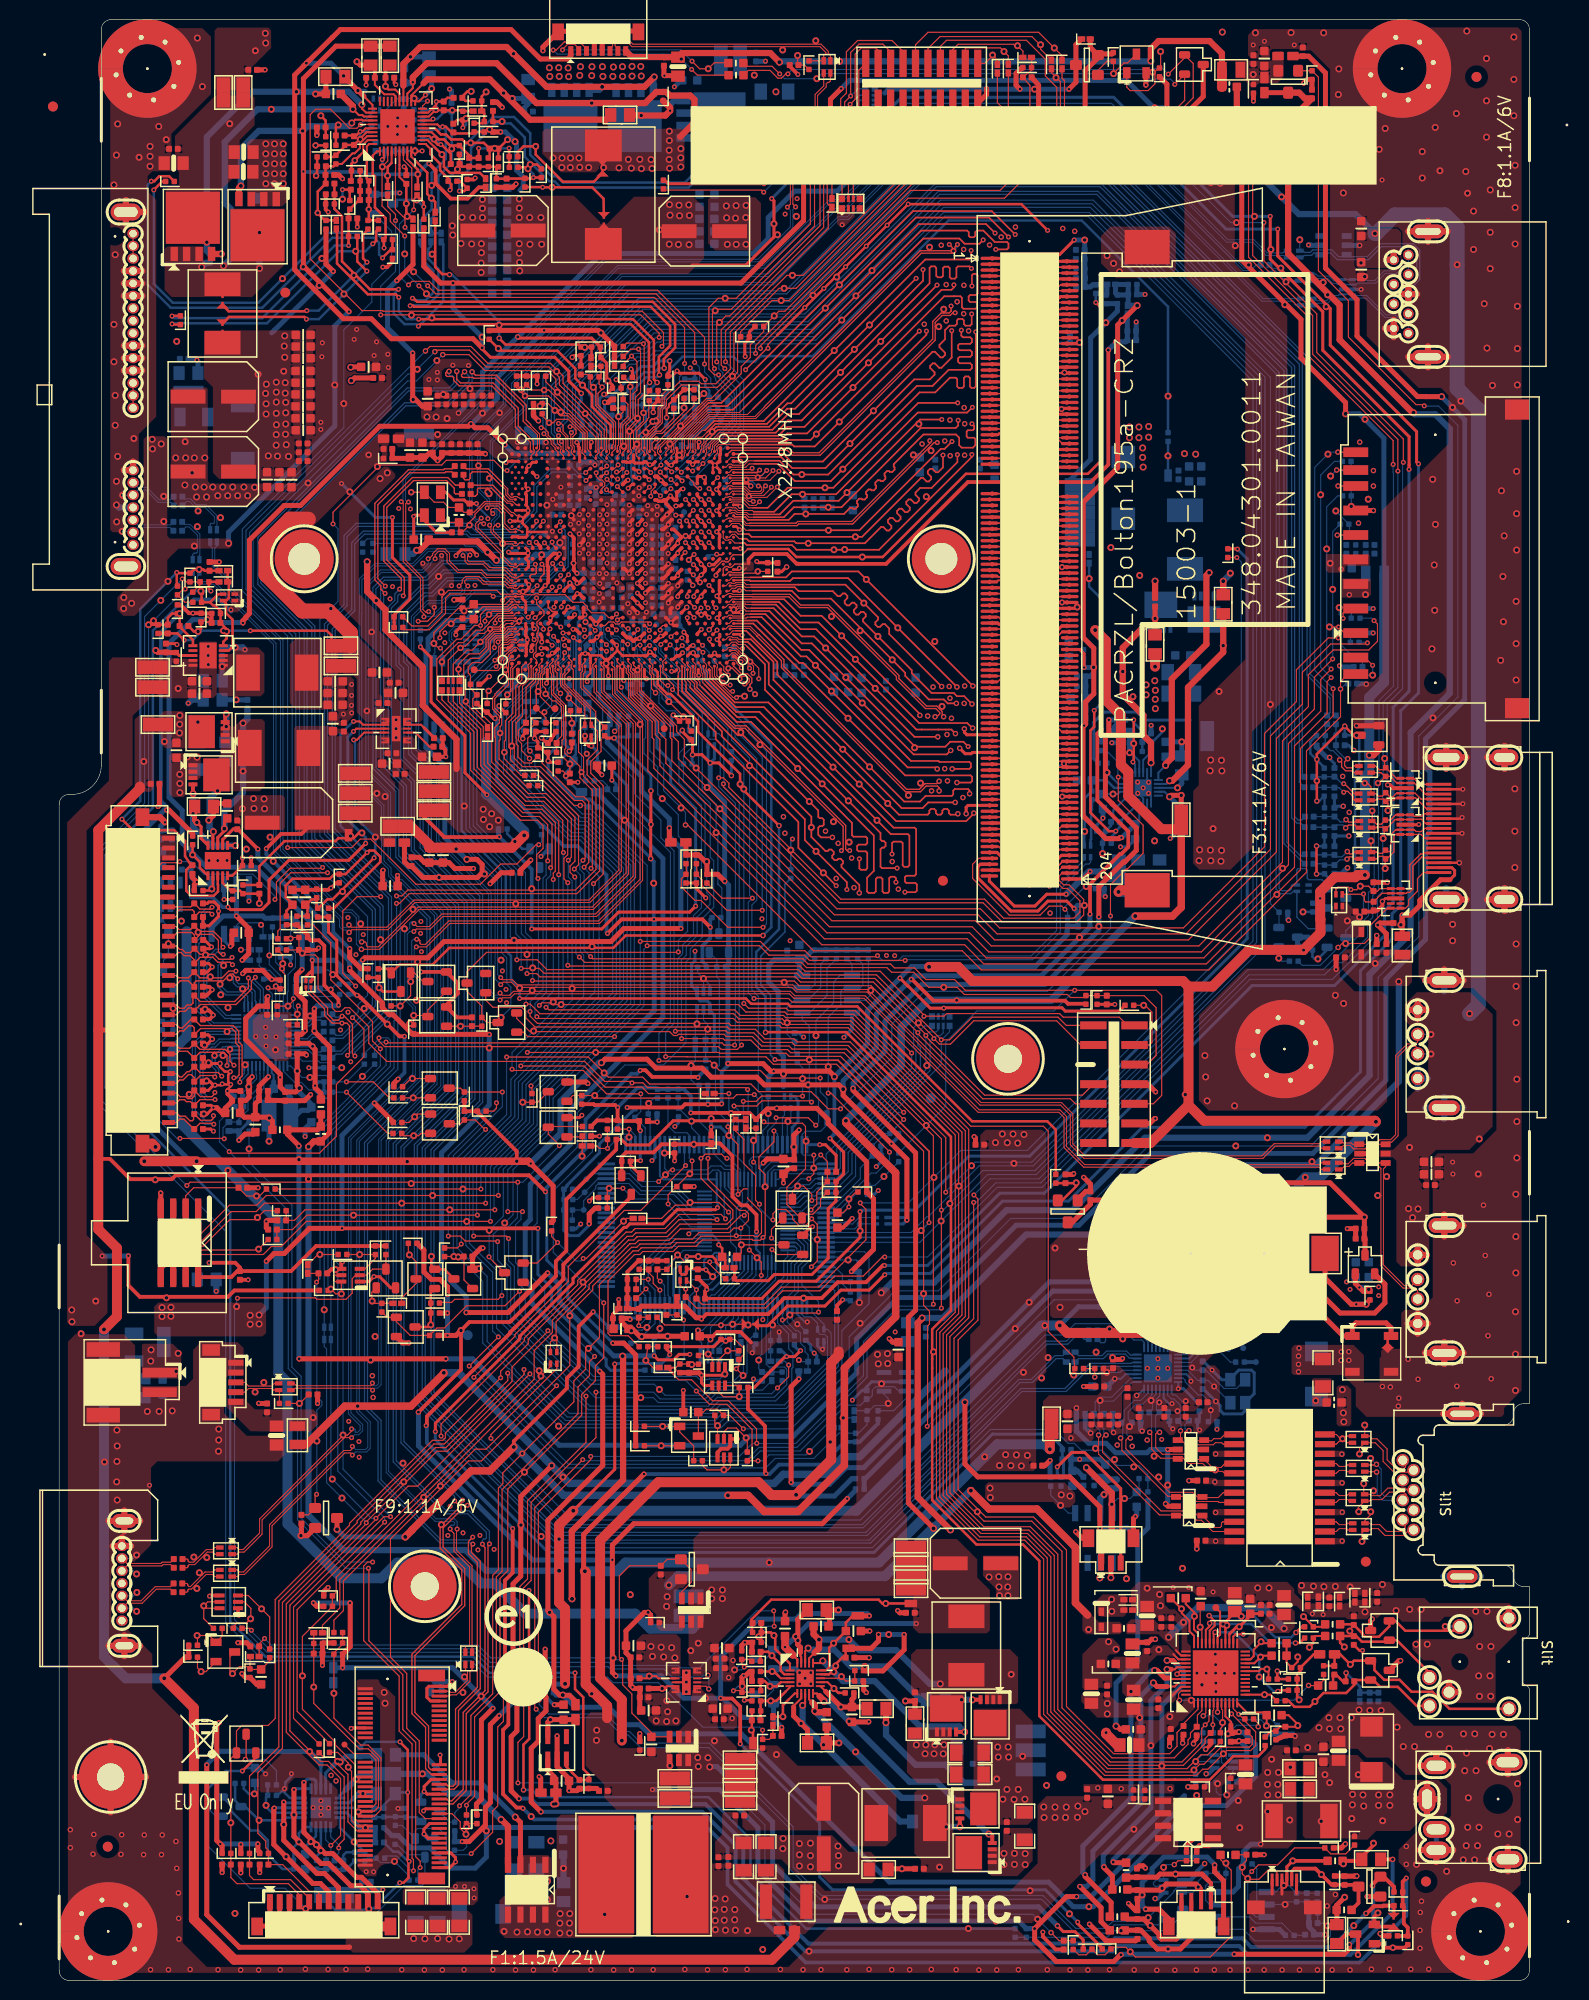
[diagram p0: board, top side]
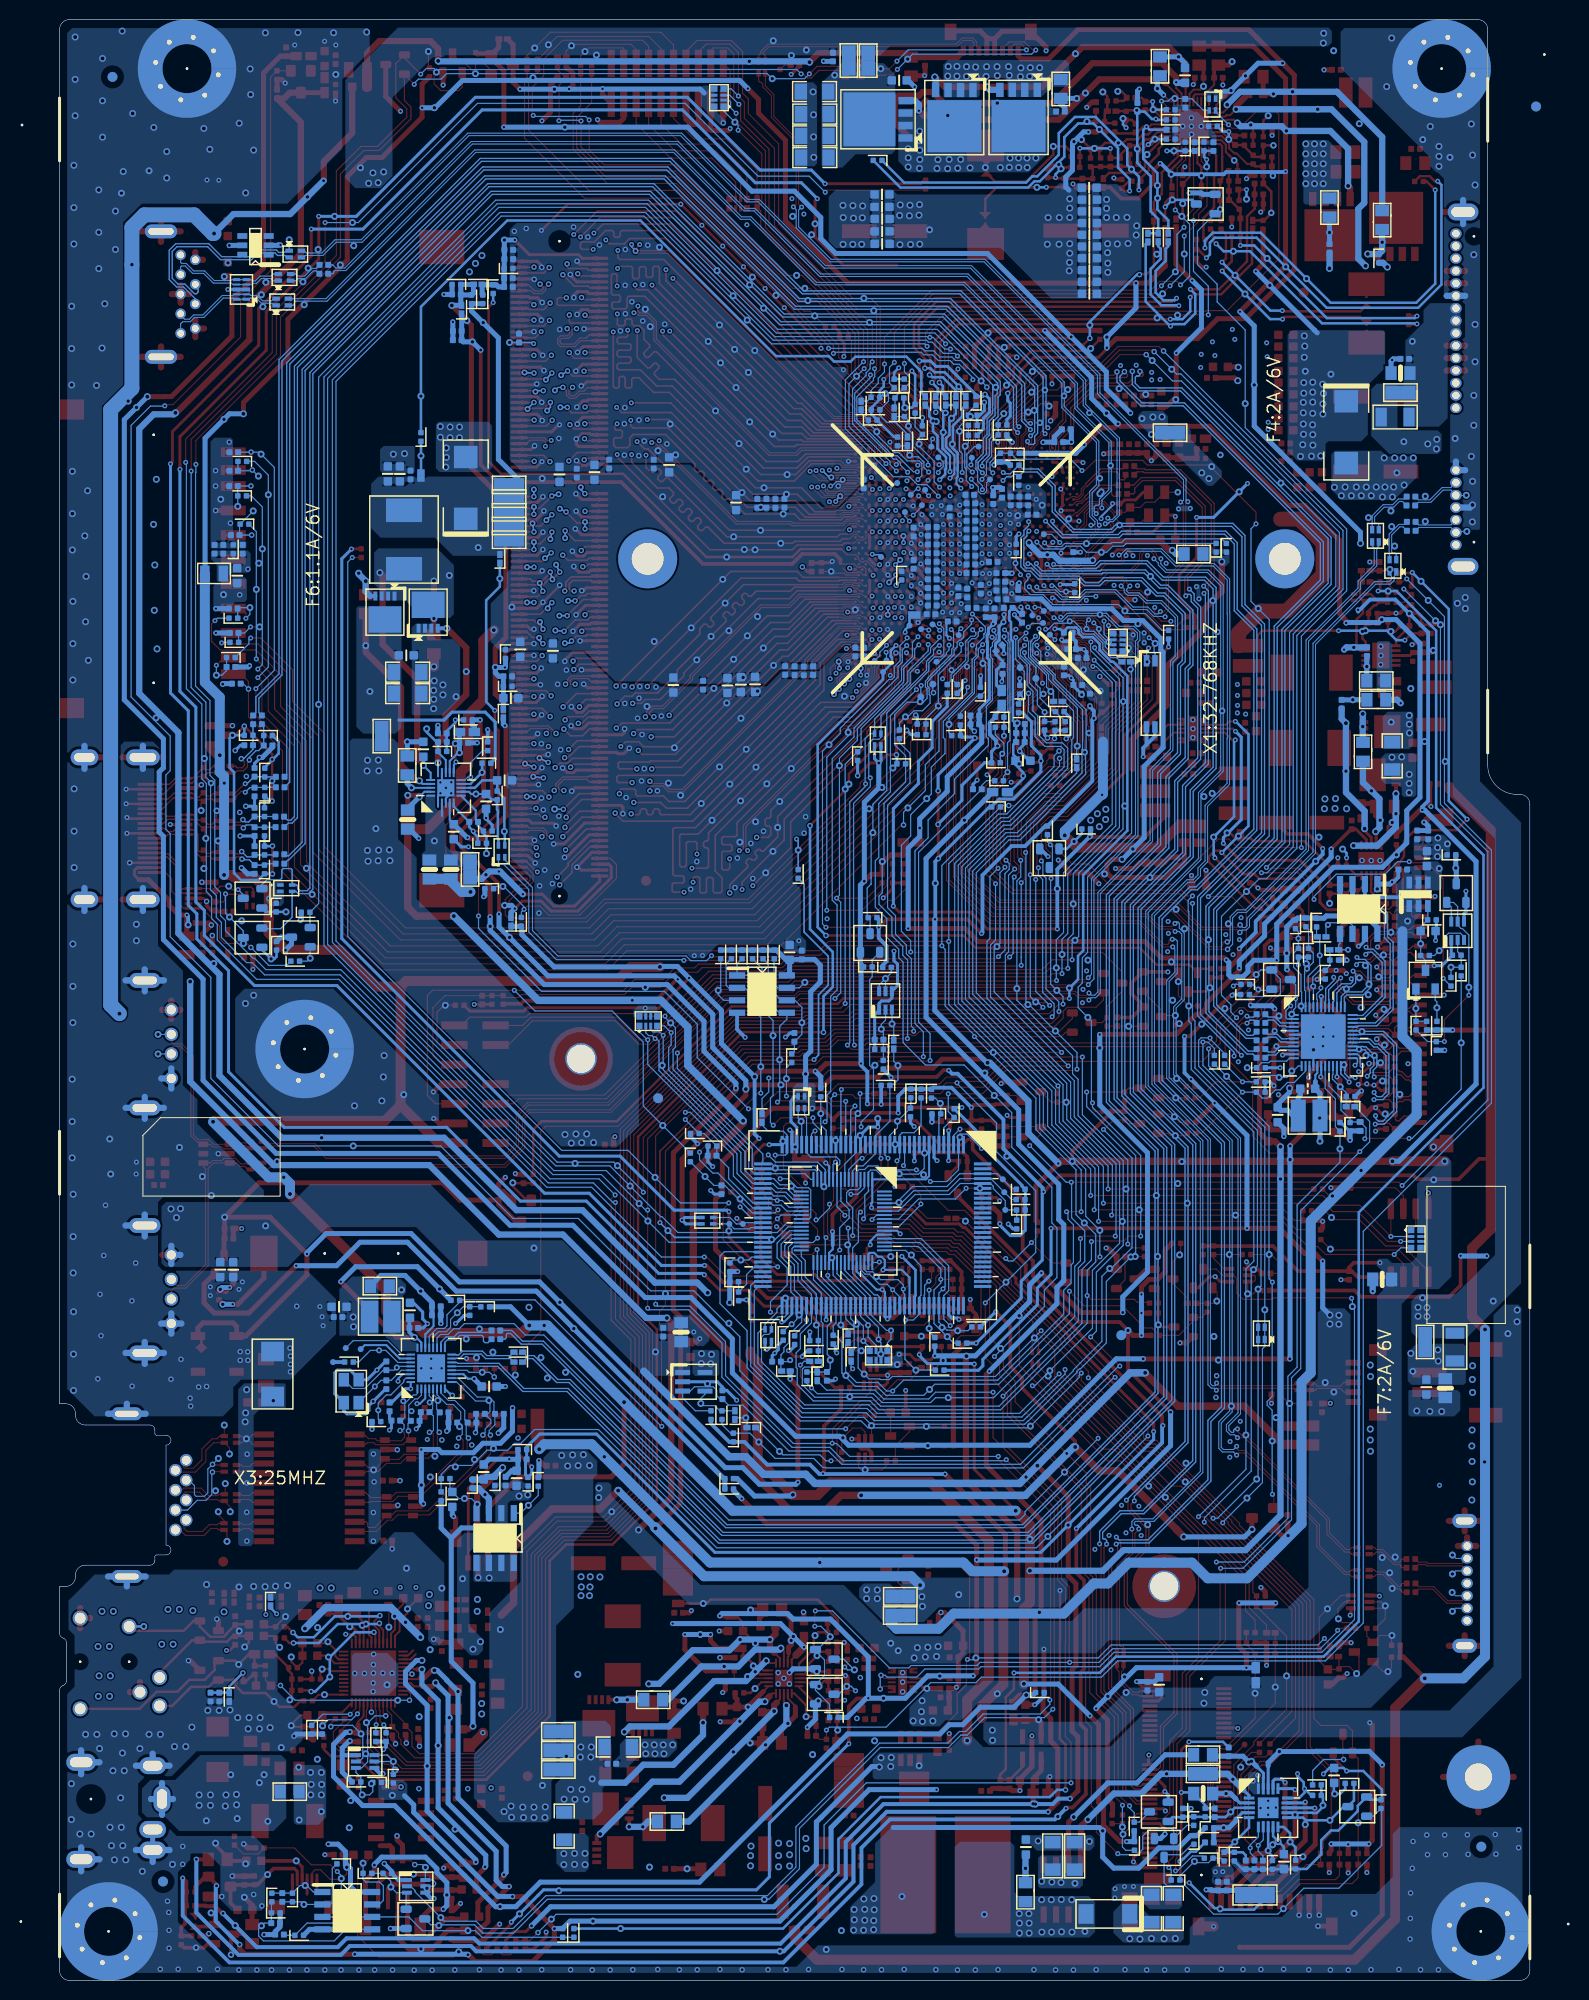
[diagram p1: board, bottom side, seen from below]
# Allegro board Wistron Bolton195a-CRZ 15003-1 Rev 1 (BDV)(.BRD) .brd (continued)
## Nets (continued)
USB30_RP0_C: D19.2 D19.9 TR11.4 USB3S1.6
USB30_RXN0: CPU1.V1 TR11.2
USB30_RXP0: CPU1.V2 TR11.3
USB30_TN0_C: D19.4 D19.7 TR12.1 USB3S1.8
USB30_TN0R*: C434.1 TR12.2
USB30_TP0_C: D19.5 D19.6 TR12.4 USB3S1.9
USB30_TP0R*: C433.1 TR12.3
USB30_TXN0: C434.2 CPU1.T1
USB30_TXP0: C433.2 CPU1.T2
USB30_VCCA: C432.1 C436.1 C458.1 C6514.1 C6515.1 C6516.1 C6517.1 C6518.1 C6519.1 D20.5 D24.5 F9.1 G2.1 R463.1 R616.1 U51.1 USB2S1.1 USB2S2.1 USB3S1.1
USB_ATEST0: CPU1.AJ10 TP12.1
USB_ATEST1: CPU1.AJ8 TP13.1
USB_COMP_M: CPU1.AG4 R96.1
USB_EN: R440.2 R867.1
USB_EN1: Q41.2 R434.2
USB_EN2: Q41.1 R436.2 R438.1
USB_EN3: C431.2 Q40.G Q41.3 R435.1 R437.1
USB_EN4: Q42.5 Q42.6 R438.2
USB_EN5: Q42.3 R437.2
USB_EN6: Q42.2 R439.2
USB_OC_01: C455.1 CPU1.AY8 R466.2
USB_OC_02: CPU1.AV1 R1019.1
USB_OC_03: CPU1.AY1 R1020.1
USB_OC_23: C441.1 CPU1.AW1 R441.2 U51.3
USB_PN0_C: D24.1 L72.4 USB2S1.2
USB_PN1_2-: L44.4 R813.1 TOUCH1.4
USB_PN2_11-: CAM1.7 L41.4 R464.1
USB_PN4_C: D24.4 L47.4 USB2S2.2
USB_PN5*: L49.4 NGFFE1.5
USB_PN8_C: D20.1 L40.4 USB3S1.2
USB_PP0_C: D24.6 L72.1 USB2S1.3
USB_PP1_2+: L44.1 TOUCH1.3
USB_PP2_11+: CAM1.6 L41.1
USB_PP4_C: D24.3 L47.1 USB2S2.3
USB_PP5*: L49.1 NGFFE1.3
USB_PP8_C: D20.6 L40.1 USB3S1.3
USB_PWR_EUP: R533.2 R866.1 U31.13
USBSS_CALRN: CPU1.AE10 R99.1
USBSS_CALRP: CPU1.AE8 R100.1
V_3_CARD: C303.1 C304.1 C305.1 C306.2 CRS1.4 F6.2 R296.1
V_3P3_DBP: DBGH1.3 R493.2
V_3P3_LAN: C268.1 C269.1 C282.1 C283.1 C284.1 C285.1 C286.1 C287.1 C288.1 C289.1 C302.1 C326.1 LAN1.11 LAN1.23 LAN1.32 R278.2 R285.2 R287.2 U9.5 U10.5
V_5_CODEC: AUDIO1.25 AUDIO1.38 C189.1 C190.1 C191.2 C192.1 C193.2 L3.1
V_5_LCD1: L38.1 U22.4
V_5_LED: G2.2 Q52.2
V_5_ODD: C420.1 C421.1 F7.2 ODDPW1.1 R429.2
V_5_PWR1: L54.2 R618.1
V_5_SUS1: L55.2 R621.2
V_VCORE_EN: PR4430.1 Q4401.D R4401.2
VCORE_PWROK: PR4431.1 R52.2 R56.2 R59.1
VGA_BLUE: CPU1.B15 R15.1
VGA_FCH_DDCSCL: CPU1.D19 TP3.1
VGA_FCH_DDCSDA: CPU1.D21 TP4.1
VGA_GREEN: CPU1.A14 R14.1
VGA_HSYNC_3V: CPU1.G19 R16.1 R17.1
VGA_RED: CPU1.B14 R13.1
VGA_VSYNC_3V: CPU1.E19 TP2.1
VREF: C181.2 U59.2
VRM_PWRGD: D3.1 PU4401.35 RN18.4(B)
VTT_CT_0.95V: C6528.1 U12.10
VTT_CT_1.8V: C6529.1 U12.12
VTT_CT_3.3V: C3604.1 U13.12
VTT_CT_5VC: C3603.1 U13.10
WIFI_DISABLE_N: NGFFE1.56 R474.2 R476.1 U31.17 U6503.7
WLAN_CLKREQ: NGFFE1.53 R6565.1 R6566.2
WLAN_CLKREQ_CPU#: CPU1.AW29 R6564.1 R6565.2
X32K_X1: C30.1 CPU1.AJ2 R84.1 X1.1
X32K_X2: C31.1 CPU1.AJ1 R84.2 X1.4
X48M_X1: C36.1 CPU1.N2 R108.1 X2.3
X48M_X2: C37.1 CPU1.N1 R108.2 X2.1
XRF_TDC1: C280.1 C281.2 XF1.15 XF1.18 XF1.21 XF1.24
N16511429: Q4808.D R6579.2

Pads without a net: AUDIO1 14 15 16 17 18 20 23 24 29 48; CPU1 A6 A7 A29 AA1 AA2 AA4 AA5 AA37 AA38 AA40 AA41 AB40 AB41 AC1 AC2 AC4 AC5 AC40 AE37 AE38 AG1 AG2 AJ4 AJ5 AL7 AL38 AN35 AN37 AP11 AP23 AP27 AR27 AR37 AV13 AV15 AV19 AV21 AV27 AY12 AY25 AY27 AY28 AY29 B6 B7 BA3 BA9 BA10 BA12 BA29 BA30 D1 D2 D7 E1 E2 E7 F1 F2 G1 G2 G4 G5 H1 H2 H15 J1 J2 J4 J5 J34 J37 K15 L4 L5 N4 N5 N8 N10 R1 R2 U4 U5 U41 V40 V41 W1 W2 W40 Y41; D1 1; D3 2; D20 3 4; DBGH1 6 12 14; DIMM1 77 122 125; HDMI1 13 14; LVDS19 4 5 6; NGFFE1 6 8 9 10 11 12 13 14 15 16 17 19 20 21 22 23 32 34 36 38 40 42 44 46 48 59 61 62 64 65 66 67 68 70 71 73 76 77; PU4401 27 28 29 30; PU5101 7; PU5201 4; RN6 1; RN22 4 5; U25 2 9; U31 1 10 12 15 20 21 27 31 56 59 61 62 84 88 100 101 102 103 104 105 106 107 108 109 110 111 112 113 114 115 116 117 118 119 120 121 122 123 127 128; U6503 56 62 63 64

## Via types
v1: diameter 0.559, hole 0.305, TOP to BOTTOM, 645 vias
v2: diameter 0.711, hole 0.356, TOP to BOTTOM, 905 vias
v3: diameter 0.508, hole 0.254, TOP to BOTTOM, 1346 vias
v4: diameter 0.66, hole 0.33, TOP to BOTTOM, 41 vias
v5: diameter 0.711, hole 0.406, TOP to BOTTOM, 666 vias
v6: diameter 0.61, hole 0.305, TOP to BOTTOM, 86 vias
v7: diameter 0.102, hole 0.051, TOP to BOTTOM, 2 vias

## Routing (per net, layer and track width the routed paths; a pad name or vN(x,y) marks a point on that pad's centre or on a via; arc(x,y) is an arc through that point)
3V_5V_POK: length 181.3
  TOP w0.114: R5101.2 14.38,142.35 14.38,142.65 ; 14.38,142.65 R4803.2 12.98,142.65 12.68,142.95 v3(12.56,142.95) ; 14.38,142.65 R5202.1 ; PR4928.1 72.82,26 PC4921.1 72.46,24.59 PR4929.1 v3(71.77,25.53)
  BOTTOM w0.114: v3(71.77,25.53) 71.46,25.83 65.67,25.83 61.13,30.37 56.51,30.37 55.95,30.93 43.71,30.93 42.05,32.59 20.86,32.59 16.99,36.46 16.99,76.4 3.92,89.48 3.92,115.28 8.71,120.07 8.71,139.1 v2(10.37,140.76) v3(12.56,142.95)
5V_A: length 152.5
  TOP w0.203: U12.4 30.31,127.68 v3(30.03,127.4)
  TOP w0.305: v3(31.27,115.98) 29.54,114.25 23.43,114.25 21.41,112.23 21.41,109.94 20.69,109.22 17.48,109.22 v3(17.22,109.47)
  BOTTOM w0.305: v3(30.03,127.4) 29.44,126.81 29.44,118.39 31.27,116.56 v3(31.27,115.98)
  BOTTOM w0.381: 13.42,110.47 15.67,110.47 16.66,109.47 v3(17.22,109.47)
  BOTTOM w1.016: 65.2,36.81 65.2,36.46 64.61,35.86 60.33,35.86 58.78,37.41 47.55,37.41 44.48,40.49 43.04,40.49 40.92,42.61 37.29,42.61 37.29,42.61 34.46,42.61 32.87,41.01 28.84,41.01 23.29,46.56 23.29,61.01 22.35,61.95 22.35,77.47 v2(17.22,82.61) 11.55,88.28 11.55,94.81 13,96.26 13,107.02
  vias: v2(12.47,108.05) v2(65.2,34.39) v2(83.9,60.86) v5(66.57,39.83) v5(66.57,38.94) v5(67.67,39.83) v5(67.67,38.94) v5(83.49,63.86) v5(83.57,62.89) v5(84.51,63.93) v5(84.53,62.92)
5V_FANCTL1_FSM#: length 4.2
  BOTTOM w0.114: U6502.1 102.96,47.66 v2(102.17,48.46) 101.16,49.46 R6513.2
5V_HDD:
  vias: v2(11.99,167.18)
5V_S0: length 399.9
  TOP w0.305: v3(30.38,100.48) 30.33,100.53 30.28,100.53 28.32,102.49 28.32,106.07 27.48,106.91 R6576.1 R6578.1
  TOP w0.381: PR4440.1 42.81,182.89 41.66,181.74 39.95,181.74 38.4,183.29 38.4,184.63 v3(37.72,185.32) ; v3(35.23,96.29) 34.72,96.29 30.81,100.2 30.78,100.2 30.51,100.48 v3(30.38,100.48) ; v3(48.84,76.71) v3(28.85,76.71)
  TOP w0.406: R618.2 v1(136.04,12.34)
  TOP w0.508: R607.1 34.15,91.5 v3(34.57,91.92) ; PR4427.1 PR4426.1 28.23,197.29 24.92,193.98 v3(24.92,184.51) 24.92,174.87 v3(29.58,170.21) ; v1(49.15,17.2) 48.16,18.19 48.16,23.67 48.88,24.39 48.88,26.7 49.66,27.49 49.66,28.89 49.58,28.97 v3(49.58,33.78) ; v3(21.13,73.36) 21.92,74.14 22.96,74.14 25.53,76.71 v3(28.85,76.71) ; v3(32.16,89.48) 34.08,87.56 R606.1
  TOP w0.635: v5(88.04,67.56) 88.04,67.51 87.59,67.07 87.59,49.29 88.24,48.64 88.24,48.64 88.98,47.9 v5(90.93,45.95)
  BOTTOM w0.305: R508.2 59.74,62.23 56.26,62.23 55.8,62.69 55.8,63.35 50.24,68.91 50.24,70.62 48.84,72.02 v3(48.84,76.71)
  BOTTOM w0.381: v3(32.16,89.48) 32.16,89.51 v3(34.57,91.92) 35.23,92.58 v3(35.23,96.29) ; v3(24.92,184.51) 24.97,184.45 30.99,184.45 31.22,184.23 36.53,184.23 37.62,185.32 v3(37.72,185.32) ; v3(30.38,100.48) 30.3,100.56 R671.1
  BOTTOM w0.406: v1(49.15,17.2) 65.61,17.2 69,13.8 69,10.08 76.11,2.97 107.5,2.97 108.03,3.51 120.39,3.51 121.29,2.6 131.74,2.6 136.04,6.91 v1(136.04,12.34)
  BOTTOM w0.508: v5(20.4,67.87) 21.13,68.61 v3(21.13,73.36) ; v3(28.85,76.71) 28.85,86.18 v3(32.16,89.48) ; v5(17.28,146.58) 17.28,147.71 28.12,158.55 v2(28.12,162.74) 28.12,168.75 v3(29.58,170.21)
  BOTTOM w0.635: v5(88.04,67.56) 90.14,67.56 98.65,76.07 105.18,76.07 112.27,83.16 128.15,83.16 136.68,91.68 v5(136.68,101.88)
  vias: v2(10.95,69.62) v2(12.85,156.95) v2(64.44,33.63) v2(93.68,47.8) v2(108.89,40.97) v2(134.26,103.73) v5(6.59,141.06) v5(6.58,139.93) v5(7.39,140.46) v5(9.49,157.19) v5(9.53,156.21) v5(10.41,156.72) v5(10.49,68.63) v5(10.49,67.72) v5(11.4,68.66) v5(11.4,67.74) v5(19.48,67.84) v5(19.48,66.93) v5(20.4,66.95) v5(60.38,34.06) v5(60.53,33.05) v5(61.42,33.99) v5(61.67,32.99) v5(62.48,33.93) v5(62.81,32.89) v5(94.97,50.22) v5(95,49.25) v5(102.23,49.53) v5(103.12,49.4) v5(107.06,34.54) v5(107.82,33.78)
5V_S5: length 371.2
  TOP w0.254: v1(47.37,19.43) 47.37,24.05 47.96,24.63 47.96,34.68 47.93,34.71 v3(47.93,39.78)
  TOP w0.305: v3(64.34,63.86) 63.25,63.86 62.69,63.3 61.11,63.3 v3(60.71,63.7) ; PC4806.1 17.76,117.44 16.68,116.36 PU4801.7
  TOP w0.381: PC4806.1 18.22,117.44 v3(20.27,115.39)
  TOP w0.508: v3(49.83,72.16) 45.8,68.12 v1(41.53,68.12) ; v1(81,90.98) 81,90.78 87.38,84.4 87.38,68.38 86.64,67.64 86.64,48.69 89.2,46.13 v5(89.2,46.1) ; v3(107.09,128.57) 107.09,127.18 106.74,126.83 106.74,120.72 107.44,120.03 107.44,120.01 109.12,118.33 109.89,117.55 109.89,115.26 108.72,114.08 108.59,114.08 106.07,111.56 v3(106.07,108.48) ; v3(43.88,96.48) 43.87,96.5 36.23,96.5 R87.2 36,96.56 34.06,98.5 33.68,98.5 32.98,99.2 R86.1 32.98,99.68 29.64,103.02 v3(29.64,103.25)
  TOP w0.635: v5(52.32,38.91) 52.3,38.94 52.3,45.82 57.53,51.05 57.53,63.63 v5(57.48,63.68)
  TOP w0.762: 104.93,37.26 103.68,38.51 103.68,44.16 99.76,48.08 94.87,48.08 93.01,49.94 v5(93.01,49.96)
  BOTTOM w0.254: R808.2 v2(92.76,5.29) 76.2,5.29 70.53,10.95 70.53,14.4 66.23,18.69 48.97,18.69 48.23,19.43 v1(47.37,19.43)
  BOTTOM w0.305: R499.2 60.71,64.68 v3(60.71,63.7)
  BOTTOM w0.508: PR5005.2 107.68,127.87 107.9,128.09 107.9,128.56 PR5001.2 v3(107.09,128.57) ; v1(41.53,68.12) 41.53,69.72 39.01,72.24 39.01,83.85 39.01,84.42 43.88,89.29 v2(43.88,95.11) 43.88,96.38 43.88,96.38 v3(43.88,96.48) ; 57.45,63.7 v5(57.48,63.68) ; 57.45,63.7 56.56,63.7 51.03,69.24 51.03,70.95 49.83,72.14 v3(49.83,72.16) ; 57.45,63.7 v3(60.71,63.7) ; v3(106.07,108.48) v2(106.07,107.52) 106.07,107.1 100.55,101.57 88,101.57 84.25,97.83 84.25,94.77 81,91.52 v1(81,90.98) ; v3(20.27,115.39) 20.27,114.56 27.06,107.77 27.06,106.54 29.64,103.96 v3(29.64,103.25)
  BOTTOM w0.762: v5(93.01,49.96) 92.99,49.96 89.28,46.25 ; 89.2,46.18 v5(89.2,46.1)
  BOTTOM w1.016: v5(62.21,40.31) 63.12,41.22 84.25,41.22 89.28,46.25
  vias: v2(58.27,39.34) v2(64.54,62.81) v2(105.03,35.79) v5(62.03,39.14) v5(61.98,38.15)
5V_S5_LCD_DOWN: length 3
  BOTTOM w0.508: Q33.D 7.5,113.23 7.56,113.29 v2(7.56,113.46) R377.2
12V_EN_D: length 7.1
  TOP w0.114: R1014.1 34.94,69.61 36.41,71.08 Q82.D 36.42,71.56 36.42,73.3 v2(35.73,74) 35.62,74.1 PR161.2
12V_EN_G: length 5.6
  TOP w0.254: Q82.G 37.91,70.16 R6562.2 R6563.2 v2(37.91,66.87) 37.69,66.65 Q4807.D
12V_EN_G1: length 3.8
  TOP w0.254: Q83.D 39.29,72.54 Q82.S 37.97,72.88 v2(37.97,73.84)
+0.95V_DUAL: length 46.2
  TOP w0.305: v3(49.17,135.89) 49.7,135.9 CPU1.AV7 ; v3(49.25,135.27) 49.2,135.26 48.86,135.26 CPU1.AW5 ; v3(49.24,136.51) 49.25,136.55 49.25,137.04 arc(49.23,137.14) 49.18,137.22 CPU1.AR5 ; v3(36.86,136.02) 37.94,134.93 37.94,130.41 38.3,130.05 38.3,130.05 41.39,126.96 41.39,123.18 41.94,122.64 41.94,122.63 v3(43.64,120.93)
  TOP w0.356: CPU1.AU4 48.18,136.08 48.18,135.63 v3(48.18,135.63)
  TOP w1.016: R119.1 35.87,117.72 37.76,115.83 C137.1 C138.1 46.19,115.54 v5(47.45,116.79)
  BOTTOM w0.305: R100.2 v3(36.86,136.02)
  BOTTOM w1.016: v5(47.45,116.79) 47.45,117.22 43.74,120.93 v3(43.64,120.93) 43.55,121.01 43.55,126.36
  vias: v2(45.54,133.68)
+1.05V_LAN: length 17.8
  BOTTOM w0.203: LAN1.8 110.18,59.84 110.11,59.84 v1(109.93,59.66) ; C273.1 111.85,67.69 111.85,66.74 112.69,65.9 LAN1.22 ; v3(113.54,58.83) 113.23,58.83 112.69,59.37 LAN1.3 ; LAN1.30 115,61.83 115.47,61.37 v3(115.47,61.11)
  BOTTOM w0.508: R269.2 117.22,71.91 114.76,71.91 v2(113.16,70.31) 112,69.15 C279.1 C273.1
  vias: v2(111.4,59.16) v5(120.04,67.67) v5(120.02,66.67)
+3VL: length 229.4
  TOP w0.305: v3(103.91,5.94) 103.91,5.79 106.41,3.29 R6551.2 ; R6541.2 69.91,87.68 69.15,87.68 R6573.1 68.87,87.68 62.64,87.68 60.17,85.22 57.91,85.22 57.35,85.78 R6543.1
  TOP w0.381: v3(67.49,28.78) 67.52,28.75 68.66,28.75 69.48,27.93 v3(69.48,24.13) ; v1(36.65,57.96) 41,62.31 v2(41,66.29) 41.86,67.16 45.97,67.16 46.11,67.3 46.14,67.3 50.66,71.82 50.66,71.84 50.67,71.86 50.67,73.36 51.74,74.42 51.74,79.65 56.83,84.75 R6543.1
  TOP w0.508: v2(41,66.29) 40.49,65.79 v3(39.62,65.79) R6550.1 ; PG4904.2 v3(82.65,37.19) ; v3(39.62,69.98) 39.62,70.74 38.86,71.5 37.98,71.5 37.21,72.27 37.21,74.49 PR161.1 ; R6563.1 v3(39.62,68.07) ; v3(80.4,49.14) 77.85,46.58 58.62,46.58 56.44,44.4 v3(56.44,42.9) 56.44,31.42 v3(56.79,31.06)
  BOTTOM w0.305: v3(103.91,5.94) 103.91,5.95 v2(103.07,6.79) 101.19,8.67 100.62,9.24 78.9,9.24 77.58,10.55 77.58,16.04 69.49,24.13 v3(69.48,24.13)
  BOTTOM w0.508: v3(56.44,42.9) 56.41,42.88 48.31,42.88 36.65,54.53 v1(36.65,57.96) ; v3(80.4,49.14) 81.24,49.97 R6544.2 ; v3(82.65,37.19) 82.42,37.41 75.72,37.41 75.16,36.86 71.35,36.86 67.49,32.99 v3(67.49,28.78) ; v3(39.62,69.98) v3(39.62,68.07) v3(39.62,65.79) ; v3(56.79,31.06) 61.43,31.06 63.71,28.78 v2(65.94,28.78) v3(67.49,28.78) ; v3(67.49,28.78) 67.69,28.78 69.65,26.82 R6561.1
+3VM: length 16.6
  TOP w0.305: v3(103.56,109.32) 102.79,110.08 100.86,110.08 99.86,109.08 97.11,109.08 93.72,112.47 93.72,113.59 93.97,113.85 DIMM1.199
  BOTTOM w0.508: R136.2 103.94,108.94 v3(103.56,109.32) 103.89,109.65 v2(104.6,109.65)
+5VL: length 12.9
  TOP w0.508: PG4901.2 82.84,33.87 83.59,34.62 v1(83.59,35.28) ; v3(86.21,35.28) 86.21,33.73 84.05,31.57 82.43,31.57 PR4922.1
  BOTTOM w0.508: v3(86.21,35.28) v2(84.63,35.28) v1(83.59,35.28)
+5VLCDDDC: length 12.8
  TOP w0.305: HDMI1.18 142.08,113.5 142.37,113.22 142.37,112.74 141.89,112.27
  TOP w0.508: 141.89,112.27 140.93,112.27 138.81,110.15 138.81,109.64 137.83,108.66 v3(137.02,108.66) C389.1 137.02,106.51 F3.2
  BOTTOM w0.381: v3(137.02,108.66) 136.88,108.52 v2(136.88,107.67)
AGND: length 19.1
  TOP w0.203: v3(120.81,35.31) 120.8,35.31 120.8,35.31 120.02,35.31 119.78,35.07 AUDIO1.26
  TOP w0.254: C257.2 129.97,31.06 C256.2 130.28,31.19 130.96,30.51 EC704.2 131.29,30.56 v1(131.29,31.37) ; R235.2 R169.2 124.27,31.43 124.28,31.45 v1(124.28,31.55) ; v3(132.97,33.66) 132.65,33.66 C261.2
  TOP w0.635: 142.82,29.4 AUDS1.8 141.8,30.42 ; 146.88,36.95 AUDS1.1 ; AUDS1.1 147.9,37.97 ; AUDS1.1 147.9,35.93
  BOTTOM w0.254: C263.1 C265.1 R167.1 132.69,29.97 v1(131.29,31.37) ; v3(127.85,37.39) 128.34,37.87 128.47,37.97 R152.2
  vias: v2(111,40.01) v3(113.65,40.08) v3(115.24,40.08) v3(117.73,39.62) v3(128.96,37.31) v5(112.27,39.37) v5(112.36,38.22) v5(122.28,40.03) v5(123.43,40.03) v5(133.22,37.59) v5(136.4,37.72) v5(137.78,37.85) v5(138.42,34.29) v5(138.94,37.85) v5(139.57,34.29) v5(144.52,37.64) v5(144.82,31.06) v5(144.92,34.06) v5(144.9,28.98) v5(145.67,37.64) v5(145.97,31.06) v5(146.08,34.06) v5(146.05,28.98)
GND: length 1399.2
  TOP w0.127: 73.25,167.8 72.31,166.87 v3(72.31,166.47) 72.21,166.47 v3(70.03,164.29) ; v3(36.63,138.63) 37.58,138.63 38.27,139.32 v3(38.27,140.05)
  TOP w0.152: CPU1.AH2 CPU1.AH1 45.62,141.15 45.25,140.77 v3(45.25,140.77) ; CPU1.AJ7 49.9,140.04 50.31,139.63 50.57,139.63 CPU1.AL8
  TOP w0.203: AUDIO1.42 114.35,31.54 v1(114.05,31.24) 114.14,31.14 AUDIO1.43 ; v3(53.87,132.49) 53.87,132.99 54.2,133.32 CPU1.BA15 54.2,133.79 54.19,133.79 54.19,134.39 CPU1.AY15 ; CPU1.AY13 53.1,134.29 53.09,134.28 53.09,133.71 CPU1.BA13 ; U13.11 63.96,30.41 v1(63.99,30.43) ; AUDIO1.7 v1(118.18,27.36) ; v1(61.97,159.41) 61.97,160.27 62.21,160.51 62.21,160.75 R25.2
  TOP w0.25: v3(67.64,133.13) 67.45,133.32 CPU1.BA39 ; v3(69.47,150.35) 69.32,150.5 CPU1.L41 ; v1(66.9,154.52) 66.7,154.33 CPU1.E38 ; v3(69.67,137.21) 69.48,137.21 69.39,137.3 CPU1.AR41 ; CPU1.BA31 62.83,133.53 v3(62.48,133.53) ; v3(69.49,146.05) 69.44,146.1 CPU1.W41 ; CPU1.C41 v3(69.52,154.95) ; v3(69.55,134.5) 69.49,134.5 69.06,134.93 69.06,134.93 68.94,135.05 CPU1.AW41 ; v3(69.42,147.96) 69.08,148.3 CPU1.R41 ; CPU1.AC41 69.25,143.9 v3(69.39,144.04) ; CPU1.AL41 69.27,139.5 69.34,139.57 v3(69.6,139.57) ; CPU1.A35 65.2,156.83 v3(65.28,156.91) ; CPU1.AG41 69.28,141.7 69.34,141.76 v3(69.41,141.76)
  TOP w0.254: v1(70.56,152.43) 70.29,152.7 CPU1.G41 ; v3(67.01,143.31) 67.01,143.46 67.4,143.85 CPU1.AC39 ; 56.92,135.68 CPU1.AW21 57.53,135.13 57.89,135.13 57.89,135.13 58.21,135.13 58.21,135.13 58.57,135.13 CPU1.AW23 58.63,135.13 59.67,135.13 CPU1.AW25 ; 56.92,135.68 56.92,136.15 v3(56.88,136.19) ; 56.92,135.68 56.92,135.62 CPU1.AW19 ; 47.75,147.74 49.76,147.74 ; 47.75,147.74 47.75,147.35 CPU1.U3 ; 47.75,147.74 47.75,148.15 CPU1.R3 47.28,148.62 47.28,148.82 CPU1.P2 CPU1.P1 ; v3(143.21,120.02) 143.18,119.99 140.75,119.99 HDMI1.5 ; CPU1.L3 47.83,150.27 v3(47.83,149.92) 47.8,149.95 CPU1.M2 CPU1.M1 ; CPU1.G3 47.6,152.31 47.79,152.12 v3(47.86,152.12) 47.86,152.02 47.6,151.77 CPU1.J3 ; U25.8 135.31,110.36 v1(135,110.06) ; v1(97.28,157.23) 96.72,157.78 95.92,157.78 95.79,157.65 DIMM1.61 ; v3(17.5,91.39) 17.5,91.21 17.17,90.88 v3(17.17,90.72) ; v3(17.5,91.39) 16.69,91.39 v3(16.64,91.44) 16.51,91.31 v3(15.9,91.31) ; v3(17.5,91.39) 17.25,91.64 17.25,92.38 17.46,92.59 v3(17.46,92.69) 16.9,92.69 16.41,93.18 v1(16.41,93.52) ; HDMI1.11 v3(143.13,117) ; CPU1.E31 63.09,153.4 63.54,152.96 v3(63.56,152.96) ; HDMI1.8 140.74,118.5 143.01,118.5 v3(143.13,118.62) ; v3(100.84,178.5) 98.16,181.18 v3(86.62,181.18) v3(84.47,179.03) v3(82.34,176.89) v3(80.23,174.79) v3(78.02,172.58) v3(76.06,170.62) 73.25,167.8 ; HDMI1.17 v1(142.85,114) ; CPU1.AL3 47.6,139.85 47.63,139.88 47.63,140.23 47.6,140.26 CPU1.AJ3 ; v3(69.9,28.57) 70.62,28.57 PR4921.2 ; CPU1.BA18 55.85,134.01 56.01,133.86 56.01,133.1 v3(56.03,133.07) ; CPU1.B31 63,155.66 63.04,155.7 63.04,156.21 63,156.25 CPU1.A31 ; CPU1.AW15 54.25,135.15 55.25,135.15 CPU1.AW17 55.65,134.75 CPU1.AY18 ; HDMI1.2 v3(143.21,121.5)
  TOP w0.305: R21.2 64.73,162.28 63.78,162.28 R23.2 63.03,161.57 R25.2 ; v3(51.04,145.49) 50.9,145.36 50.9,145.2 CPU1.AA8 ; CPU1.AR17 54.92,137.02 54.9,137.02 54.88,137 v3(54.86,137) ; CPU1.AJ3 47.25,140.95 CPU1.AH2 ; v3(52.59,139.3) 52.58,139.3 52.58,139.23 52.35,139 CPU1.AM11 ; DIMM1.49 96.05,161.25 96.19,161.11 96.6,161.11 v1(97.23,160.48) ; CPU1.AE32 63.1,142.4 v3(63.1,142.25) ; DIMM1.54 101.28,159.75 100.76,159.23 v1(100.76,159.11) ; v1(74.22,144.17) 74.19,144.17 73.72,143.69 EC11.2 ; v1(47.29,126.66) 47.29,126.94 C24.2 ; v3(27.74,111.43) 28.26,111.95 R6575.2 ; CPU1.AP31 62.71,138.2 v3(62.41,138.5) ; Q49.4 65.81,60.68 65.53,60.96 v3(65.53,61.72) 67.64,61.72 67.93,62.02 Q49.1 ; v1(97.26,155.02) 96.77,154.53 96.24,154.53 96.12,154.65 DIMM1.71 ; CPU1.R39 67.4,148.04 67.11,147.75 ; v1(92.35,127.66) 92.35,127.3 92.61,127.05 DIMM1.155 ; CPU1.E4 48.63,153.47 48.67,153.47 v3(48.74,153.39) ; 126.24,8.89 126.24,10.03 126.25,10.04 PWRBT1.6 ; 15.75,91.31 15.39,91.67 C359.1 ; 15.75,91.31 v3(15.9,91.31) ; 15.75,91.31 15.21,90.78 C356.1 ; v3(54.29,156.9) 54.2,156.81 CPU1.A15 ; DIMM1.14 102.16,171.75 102.04,171.63 101.24,171.63 v1(100.76,171.15) ; v3(58.34,164.36) 58.48,164.22 R11.2 ; CPU1.G37 65.9,153.21 v1(65.81,153.31) 65.79,153.31 65.7,153.4 CPU1.E35 65.1,153.3 CPU1.G35 ; v3(52.81,156.88) 52.96,156.73 52.96,156.44 CPU1.A13 53.09,156.29 53.09,156.26 53.03,156.21 53.03,155.69 53.09,155.64 53.09,155.61 CPU1.B13 CPU1.C13 ; v1(100.85,133.85) 101.35,133.35 DIMM1.134 ; v3(40.11,30.48) 39.62,29.99 38.96,29.99 38.95,30 38.91,30 38.9,30 38.77,30 ; CPU1.C2 46.85,154.95 CPU1.C1 45.73,154.95 v3(45.59,154.81) ; v3(54.09,79.5) 54.43,79.84 R6559.1 ; R27.2 70.41,168.13 R26.2 70.41,167.45 69.95,166.99 69.95,165.68 v3(69.99,165.64) ; CPU1.AN39 67.4,138.69 v3(67.12,138.97) 67.4,139.24 CPU1.AL39 ; C371.1 15.25,103.73 v3(15.62,103.37) 15.1,102.84 C368.1 ; CPU1.E3 47.7,153.9 47.7,154.26 v3(47.92,154.48) 48.29,154.85 48.65,154.85 CPU1.C5 ; v1(101.14,121.97) 101.16,121.95 DIMM1.172 ; CPU1.AG3 47.92,142.02 v3(47.92,142.37) 47.6,142.69 CPU1.AE3 ; DIMM1.195 95.69,115.05 97.21,113.54 ; v3(12.01,136.25) 11.91,136.35 PC5103.2 ; DIMM1.128 v1(101.61,135.15) ; v1(97.82,127.97) 97.51,127.66 96.64,127.66 96.05,128.25 DIMM1.151 ; v1(97.33,164.14) 97.33,164.16 96.64,164.85 DIMM1.37 ; CPU1.AG11 52.5,142.1 52.19,142.41 52.19,142.45 v3(52.1,142.54) 52.1,142.4 51.5,141.8 CPU1.AG10 ; v3(47.83,145.59) 47.85,145.57 47.85,145.28 47.6,145.03 CPU1.AA3 47.88,144.72 47.88,144.18 CPU1.AC3 ; v3(47.83,145.59) 47.81,145.57 47.78,145.57 47.76,145.55 CPU1.Y2 CPU1.Y1 45.98,145.55 v3(45.85,145.68) ; v3(47.83,145.59) 47.83,145.87 CPU1.W3 ; R6549.1 63.95,111.94 R6547.1 65.01,111.37 v3(65.96,110.41) ; v3(35.2,184.99) 35.42,184.77 PC4423.2 ; CPU1.AU39 67.4,136.49 v3(67.12,136.77) 67.4,137.04 CPU1.AR39 ; CPU1.AE7 49.9,142.58 v3(49.58,142.27) 49.1,141.78 CPU1.AG5 ; DIMM1.162 100.48,124.95 100.38,125.04 v1(100.15,125.04) ; NGFFE1.69 38.78,13 39.96,13 40.44,12.52 v3(40.44,12.09) 39.85,11.5 38.78,11.5 NGFFE1.75 ; C354.1 15.45,86.84 15.62,86.67 15.69,86.67 v3(15.74,86.62) ; v3(53.33,88.24) 53.32,88.24 53.09,88 Q48.S ; CPU1.AW37 66.59,135.1 v3(66.87,135.38) 67.14,135.1 CPU1.AW39 ; CPU1.AY30 62.65,134.75 CPU1.AW31 ; v3(98.99,158.67) 99.08,158.67 99.8,157.95 DIMM1.60 ; v3(63.11,140.06) 63.11,140.21 CPU1.AJ32 ; CPU1.C37 66.53,154.9 v1(66.9,154.52) ; DIMM1.133 96.72,133.65 v1(96.75,133.68) ; CPU1.U1 46.26,147.26 46.8,147.26 46.86,147.2 CPU1.U2 CPU1.U3 ; CPU1.A39 67.45,156.22 67.46,156.22 67.46,155.66 CPU1.B39 CPU1.C39 67.28,154.9 v1(66.9,154.52) ; v3(45.5,135.76) 45.52,135.78 45.66,135.78 45.8,135.93 45.83,135.95 45.95,135.95 CPU1.AU1 ; v1(96.49,168.45) DIMM1.25 ; CPU1.P1 46,148.85 v3(46,148.85) ; CPU1.C27 60.5,154.6 v3(60.26,154.6) 60.16,154.6 59.86,154.9 CPU1.C25 59.57,154.77 58.73,154.77 CPU1.C23 ; v3(34.34,193.37) 34.18,193.53 PC4422.2 ; DIMM1.167 97.3,123.45 97.56,123.19 98.2,123.19 v1(98.68,123.67) ; v3(40.47,137.25) 40.47,137.57 40.93,138.04 C31.2 ; CPU1.AY13 CPU1.AW13 53.33,135.33 v3(53.67,135.33) 53.97,135.33 CPU1.AW15 CPU1.AY15 ; CPU1.C21 57.83,154.9 57.88,154.85 58.22,154.85 58.27,154.9 CPU1.C23 ; R130.2 61.09,162.13 R28.2 60.61,160.66 v1(60.61,159.94) ; v1(91.87,125.68) 92.43,125.12 93.04,125.12 93.17,125.25 DIMM1.161 ; v1(101.6,168.17) 101.65,168.17 101.67,168.15 DIMM1.26 ; DIMM1.190 101.82,116.55 v1(101.55,116.28) ; v3(100.79,154.91) 101.35,154.35 DIMM1.72 ; DIMM1.48 101.3,161.55 100.81,161.06 v1(100.81,160.96) ; PWRBT1.1 123.75,8.82 ; v3(29.79,25.7) 29.84,25.75 31.22,25.75 NGFFE1.18 ; v1(66.9,154.52) 67.4,154.03 CPU1.E39 ; CPU1.J3 47.68,151.52 47.68,150.58 CPU1.L3 ; DIMM1.150 101.36,128.55 100.83,129.08 v1(100.82,129.08) ; v1(97.89,174) 97.89,173.92 97.22,173.25 DIMM1.9 ; CPU1.AM29 61.91,139 v3(62.41,138.5) ; Q27.1 31.6,71.28 v3(32.11,71.78) 32.69,71.78 33.83,70.65 Q26.S ; NGFFE1.51 38.77,17.5 37.39,17.5 v3(37.18,17.29) ; v1(92.53,119) 92.53,119.66 92.72,119.85 DIMM1.179 ; v1(99.59,115.92) 98.56,115.92 96.43,118.05 DIMM1.185 ; CPU1.K31 CPU1.H31 63.11,151.8 63.45,152.13 v3(63.65,152.13) ; v3(40.49,145.31) 40.49,145.38 41.03,145.92 42.1,145.92 42.6,145.43 v3(42.6,145.39) ; 97.21,113.54 97.05,113.54 96.77,113.25 DIMM1.201 ; 97.21,113.54 v1(97.22,113.54) ; 38.77,30 37.72,30 37.52,29.79 37.52,28.88 37.89,28.5 38.77,28.5 NGFFE1.7 ; 38.77,30 NGFFE1.1 ; 62.5,150.05 CPU1.L31 ; C377.1 14.83,106.12 v3(15.54,105.41) 15.37,105.23 C370.1 ; v3(107.7,99.55) C35.2 106.87,99.56 R132.2 ; DIMM1.156 101.64,126.75 v1(101.23,127.16) ; NGFFE1.45 38.77,19 37.53,19 37.26,19.27 v3(37.24,19.27) 37.24,19.79 37.95,20.5 38.77,20.5 NGFFE1.39 ; DIMM1.189 95.98,116.85 98.27,114.55 v1(98.48,114.55) ; v1(100.94,132.16) 101.26,132.16 101.27,132.15 DIMM1.138 ; DIMM1.66 101.91,156.15 v1(101.54,156.53) ; v1(100.84,169.34) 100.84,169.52 101.27,169.95 DIMM1.20 ; v1(62.66,129.06) 62.68,129.06 R74.2 ; DIMM1.43 96.23,163.05 96.65,162.64 v1(96.77,162.64) ; 67.11,147.75 67.4,147.46 CPU1.U39 67.35,147.15 67.35,146.2 67.4,146.15 CPU1.W39 ; 67.11,147.75 v3(67.08,147.75) ; CPU1.AW25 59.91,135.1 60.27,135.45 v3(60.27,135.49) 60.34,135.49 60.74,135.1 CPU1.AW27 ; CPU1.C23 CPU1.B23 ; v1(100.71,165.76) 101.3,166.35 DIMM1.32 ; C493.2 v3(55.12,86.11) ; v3(77.6,85.24) 78.18,85.24 79.27,84.16 C27.1 ; v1(100.79,123.7) 101.34,123.15 DIMM1.168 ; C482.2 60.16,87.55 v3(61.01,87.55) ; CPU1.AM31 62.92,139 v3(62.41,138.5) ; PR4815.2 v3(16.82,110.25) ; CPU1.AN3 47.6,138.07 47.65,138.02 47.65,137.68 47.6,137.63 CPU1.AR3 47.6,137.14 47.75,136.99 47.75,136.75 v3(47.77,136.74) 47.75,136.73 47.75,136.35 CPU1.AU3 ; CPU1.AW35 64.95,135.1 64.69,135.36 v1(64.69,135.41) 64.41,135.41 CPU1.AW33 ; C353.1 15.08,88.37 v3(15.73,89.02) 15.49,89.26 C357.1 ; v1(97.18,158.74) 97.17,158.75 97.17,158.89 96.61,159.45 DIMM1.55 ; DIMM1.19 95.95,170.25 96.11,170.41 96.72,170.41 v1(97.21,169.93) ; CPU1.N39 67.4,149.59 v3(67.08,149.91) 67.4,150.23 CPU1.L39 ; DIMM1.44 101.41,162.75 v1(101.32,162.84) ; v3(49.72,132.31) 49.8,132.4 CPU1.BA7 ; v1(49.2,126.73) 49.72,126.22 C29.2 ; CPU1.AW3 47.65,135.15 47.65,135.47 47.65,135.48 47.65,135.82 47.65,135.83 47.65,136.15 CPU1.AU3 ; C25.1 52.3,125.63 v1(52.04,125.37) ; CPU1.C33 64.36,154.9 v3(64.63,154.62) 64.91,154.9 CPU1.C35 ; Q98.S 76.72,76.88 v3(76.86,76.88) ; v1(97.28,157.23) 97.28,156.69 97.04,156.45 DIMM1.65 ; v3(42.57,150.63) C36.2 41.69,150.63 41.33,151 40.23,151 39.44,151.79 X2.2 ; v3(52.91,122.21) C455.2 ; v1(99.34,117.75) 99.62,118.03 101.82,118.03 102.13,118.35 DIMM1.184 ; C132.2 v3(56.38,122.43) ; C374.1 C376.1 15.29,107.57 16.25,108.52 16.25,109.04 v3(16.26,109.05) 16.26,109.56 15.82,110 15.26,110 15.11,109.86 C373.1 ; v3(50.31,135.37) 50.31,135.36 50.05,135.1 CPU1.AW7 ; v3(38.86,22.99) 38.91,22.94 38.91,22.13 NGFFE1.33 ; v1(96.53,132.22) 96.16,131.85 DIMM1.139 ; C125.2 v3(36.17,149.33) 36.29,149.45 X2.4 37.25,148.93 38.48,147.7 C37.2 ; v1(101.57,173.51) 101.65,173.51 101.69,173.55 DIMM1.8 ; v1(100.58,164.21) 100.92,164.55 DIMM1.38 ; CPU1.J39 67.4,151.75 v3(67.07,152.08) 67.07,152.12 67.4,152.46 CPU1.G39 ; DIMM1.196 102.25,114.75 v1(101.47,113.97) ; CPU1.P2 47.25,149.05 CPU1.N3 47.83,149.63 v3(47.83,149.92) ; CPU1.C29 62.25,154.55 v3(62.45,154.55) 62.8,154.9 CPU1.C31 CPU1.B31 ; v1(97.79,129.92) 97.21,129.34 96.72,129.34 96.01,130.05 DIMM1.145 ; C362.1 15.16,95.55 v1(15.62,96.01) 15.19,96.44 C361.1 ; v1(97.54,171.65) 97.54,171.88 97.16,172.25 96.18,172.25 95.98,172.05 DIMM1.13 ; NGFFE1.63 38.77,14.5 37.64,14.5 37.23,14.91 v3(37.23,14.93) 37.21,14.95 37.21,15.43 37.79,16 38.77,16 NGFFE1.57 ; v1(100.81,174.73) 100.81,174.9 101.26,175.35 DIMM1.2 ; CPU1.AW19 56.05,134.75 CPU1.AY18 CPU1.BA18 ; DIMM1.178 101.29,120.15 v1(100.84,120.6) ; v1(98.45,134.54) 98.45,134.67 97.67,135.45 DIMM1.127 ; CPU1.BA21 57.5,132.7 v3(57.61,132.59) ; v1(100.77,130.97) 101.39,130.35 102.51,130.35 DIMM1.144 ; v1(97.21,175.36) 97.21,175.31 96.94,175.05 DIMM1.3 ; PWRBT1.3 124.75,8.8 ; v1(97.16,166.07) 96.95,166.27 96.95,166.28 96.62,166.61 96.58,166.61 96.53,166.65 DIMM1.31 ; CPU1.BA25 59.7,132.98 v3(59.92,132.77) ; PC4421.2 v3(31.32,193.32) ; R133.2 43.05,132.2 43.85,133 v1(43.87,133) ; v3(138.71,117.91) 138.68,117.87 138.21,117.87 U23.3 U23.8 ; CPU1.AE39 67.35,142.75 67.35,141.75 CPU1.AG39 67.4,141.5 v3(67.1,141.2) 67.1,141.18 67.4,140.89 CPU1.AJ39 ; C363.1 C358.1 15.29,93.19 15.62,93.52 v1(16.41,93.52) ; C23.1 53.24,164.71 R59.2 52.51,165.72 v1(52.35,165.56) ; CPU1.AU3 CPU1.AU2 ; v3(66.34,144.4) 66.8,144.4 CPU1.AA39 ; v3(65.26,133.11) 65.26,133.14 65.2,133.2 CPU1.BA35 ; DIMM1.173 97.4,121.65 v1(97.75,121.3)
  TOP w0.356: CPU1.AR29 61.85,137.4 61.56,137.11 v3(61.37,137.11) 61.35,137.11 60.84,136.6 CPU1.AU27 ; v3(18.33,37.25) 18.29,37.29 18.29,37.31 18.24,37.36 Q29.1 ; CPU1.W29 61.65,146 v3(62.14,146.49) ; CPU1.AG29 61.65,142 v3(62.14,142.49) ; v3(59.06,148.5) 59.06,148.56 CPU1.N25 ; v3(52.43,137.82) 52.45,137.79 52.7,137.79 CPU1.AR13 ; CPU1.BA2 46.8,133.01 46.79,132.99 v3(46.79,132.84) ; CPU1.R29 61.65,148 v3(62.14,148.49) ; v3(62.02,149.51) 61.51,149 CPU1.N29 ; 62.14,143.49 61.65,143 CPU1.AE29 ; CPU1.AU19 56.42,136.6 56.82,136.19 v3(56.88,136.19) ; v3(54.86,137) 54.84,136.98 54.84,136.96 54.48,136.6 CPU1.AU15 ; CPU1.AJ29 61.65,141 v3(62.14,141.49) ; CPU1.K29 61.94,151 v3(62.36,151.42) 62.78,151 CPU1.K31 ; CPU1.K29 61.9,150.65 62.5,150.05 ; CPU1.K29 61.68,151 61.56,150.89 61.12,150.89 61.01,151 CPU1.K27 ; CPU1.AW31 63.28,135.1 v3(63.6,135.42) ; v3(48.67,146.69) 49.1,146.25 CPU1.W5 ; v3(50.31,135.37) 50.47,135.37 CPU1.AV9 ; CPU1.AE7 CPU1.AC7 49.9,144.18 49.81,144.27 49.81,144.91 CPU1.AA7 50.44,145.54 50.99,145.54 v3(51.04,145.49) ; Q29.4 15.41,39.26 v3(15.34,39.19) ; CPU1.AN7 50.13,138.63 50.13,138.95 50.11,138.96 v3(50.11,138.97) 50.18,139.04 50.2,139.04 50.66,139.5 CPU1.AL8 ; CPU1.AR25 59.31,137.01 59.31,136.99 v3(59.21,136.89) 59.13,136.81 58.81,136.81 CPU1.AU23 ; CPU1.AJ23 v3(59,140.5) CPU1.AL25 ; CPU1.AC29 61.65,144 v3(62.14,144.49) ; v3(52.83,143.52) 52.5,143.85 CPU1.AC11 CPU1.AA11 CPU1.W11 CPU1.U11 52.5,147.17 v3(52.12,147.55) ; v3(59,141.5) CPU1.AJ25 ; v3(59,142.5) CPU1.AG25
  TOP w0.381: C512.2 101.66,3.16 100.36,4.47 v3(100.36,4.93) ; 62.14,143.49 62.14,143.64 CPU1.AC31 ; CPU1.AU23 58.23,136.97 57.93,136.97 CPU1.AR21 ; v3(59,143.5) CPU1.AC25 ; C398.2 134,109.02 C391.2 134.51,109.13 135,109.62 v1(135,110.06) ; CPU1.AJ31 62.14,140.64 v3(62.14,140.49) ; C369.1 15.32,101.35 v3(15.62,101.04) 15.03,100.46 C364.1 ; PC4406.2 27.2,181.2 PR4409.2 27.19,180.64 v3(27.46,180.37) ; v3(62.02,149.51) 62.14,149.63 62.14,149.64 CPU1.L31 ; C360.1 15.37,98.07 15.72,98.42 v3(15.72,98.45) 15.72,98.5 15.29,98.93 14.97,98.93 C365.1 ; v3(80.9,77.72) 79.96,76.78 C488.2 ; v3(62.14,141.49) 62.14,141.64 CPU1.AG31 ; v3(59,147.5) CPU1.R25 ; v3(48.76,162.84) R10.2 47.69,163.63 R18.2 R15.2 ; 62.36,139.43 62.36,139.86 CPU1.AL31 ; v3(19.59,114.5) PR4809.2 ; v3(28.91,73.29) 28.79,73.17 Q27.4 28.75,72.54 27.77,72.54 C310.2 ; v3(21.69,102.1) 22.47,102.1 R614.2 ; v3(36.93,102.87) Q1.S 40.67,101.71 40.67,100.67 39.52,99.51 Q2.E 40.58,98.23 C32.2 ; C478.2 79.36,68.84 v3(79.93,69.42) ; v1(114.62,24.21) 114.62,24.59 114.62,24.59 114.62,24.89 114.71,24.98 C208.1 ; v3(26.47,105.31) 26.27,105.11 C355.2 ; PC5110.2 15.56,139.42 PR5208.2 14.5,139.43 PR5108.2 v3(13.65,139.45) 13.24,139.45 12.39,140.31 PR5107.2 ; v3(33.02,174.75) 33.45,174.75 34,175.3 PR4421.1 ; C427.2 v3(19.28,71.46) ; CPU1.AE25 v3(59,142.5) ; C29.2 50.17,126.52 50.17,126.61 R95.2 ; v3(63.68,60.17) C431.1 ; v3(62.14,146.49) 62.14,146.64 CPU1.U31 ; EC701.2 117.47,24.05 116.97,23.55 v1(116.97,23.57) ; C3619.1 25.1,111.24 C307.1 26.19,111.24 R6577.2 26.34,111.24 27.47,111.24 27.66,111.43 v3(27.74,111.43) ; v3(59,145.5) CPU1.W25 ; v1(115.72,24.13) 115.72,24.28 116.05,24.61 C209.1 ; C6529.2 39.14,125.89 C6528.2 39.4,125.53 39.4,124.87 v3(39.45,124.82) 39.04,124.82 39.04,124.81 C6530.2 ; v3(59,144.5) CPU1.AA25 ; CPU1.N31 62.14,148.64 v3(62.14,148.49) ; C477.2 56.5,66.52 C476.2 56.5,67.94 R522.1 v3(57.09,69.46) ; v1(120.37,24.42) C28.2 ; Q42.4 67.17,53.86 67.54,54.23 68.2,54.23 68.47,54.5 Q42.1 v3(69.18,55.22) ; C502.2 17.65,89.92 17.17,90.4 v3(17.17,90.72) C504.2 ; v3(75.36,194.41) 74.53,195.24 C452.2 ; v3(59,146.5) CPU1.U25 ; C484.2 v3(73.89,81.33) ; LVDS19.24 v3(12.44,93.5) ; PC4416.2 v3(30.41,178.84) ; v3(42.44,183.85) 42.29,183.69 PR4438.1
  TOP w0.406: CPU1.G29 61.81,152.6 61.41,153 v3(61.4,153) 61,153.4 CPU1.E27 ; CPU1.G21 57.93,153.03 v3(58.04,153.03) ; v1(135.53,121.95) 135.61,121.95 135.62,121.93 135.75,121.93 136.07,121.61 U24.8
  TOP w0.508: HDT1.7 86.1,189.82 85.56,189.29 84.42,189.29 ; v3(10.36,80.31) 10.36,80.31 U30.4 ; U9.2 115.6,48.36 v1(115.49,48.46) ; PC4403.2 26.29,188.34 26.29,188.34 v3(26.29,188.19) ; EC706.2 v3(18.53,10.97) ; v3(45.2,191.05) 44.67,191.59 PC4442.2 ; 83.56,188.77 HDT1.3 ; 83.56,188.77 83.47,188.68 81.79,188.68 v3(81.58,188.89) ; 83.56,188.77 83.9,188.77 84.42,189.29 ; v3(103.5,82.3) 103.42,82.21 C136.2 ; R6568.2 69.63,34.16 v3(69.95,34.48) PR4923.2 70.68,34.42 70.68,33.52 PC4919.2 ; R555.2 60.34,37.28 v1(60.09,37.53) 59.71,37.53 57.83,35.65 C3615.2 57.83,33.42 C3606.1 58.3,30.83 C3603.2 58.31,30.08 v3(58.5,29.9) 58.62,29.77 C3604.2 59.25,28.9 C3605.1 59.24,27.67 C3614.2 ; v1(21.62,5.54) 20.24,5.54 CNVBD2.13 ; C281.1 v1(115.27,50.98) ; v3(108.48,63.44) 108.47,63.44 108.37,63.33 C282.2 ; FANC1.4 104.38,45.1 v3(103.71,45.77) ; FC4.2 54.83,19.58 PR5206.2 54.03,19.56 PC5203.2 53.03,19.56 52.83,19.35 v3(52.02,19.35) PC5205.2 52.02,20.57 50.8,21.79 PU5201.2 v3(50.8,24.94) ; C429.2 21.23,77.52 v3(21.13,77.42) 21.13,76.77 C430.2 ; U10.2 115.57,54.15 v1(115.54,54.13) ; C505.2 21.29,89.81 C503.2 21.3,89.78 22.69,89.74 22.7,89.73 C508.2 24.49,89.73 24.53,89.73 25.04,89.73 v3(25.65,90.35) ; v3(33.05,113.23) 33,113.19 C133.2 ; 54.6,198.05 55.28,198.05 55.4,198.17 ; 54.6,198.05 53.85,198.81 50.96,198.81 CAM1.9 49.65,197.5 49.35,197.2 v3(49.35,196.82) ; 54.6,198.05 CAM1.4 ; v1(126.09,24.92) 126.02,24.98 C325.1 R359.2 ; v3(111.86,90.63) 111.08,91.41 DBGH1.7 ; C81.2 33.98,155.26 R6574.2 35.71,155.24 C88.2 C82.2 37.32,155.33 37.79,155.8 38.08,155.8 C87.2 38.1,155.52 v3(38.61,155.01) 39.07,155.47 C89.2 39.08,155.8 C86.2 C85.2 C84.2 C83.2 42.72,155.76 43.43,155.76 v3(43.48,155.7) ; v3(43.97,111.86) 45.09,112.98 C6534.2 ; R6569.2 69.66,30.92 v3(69.82,31.09) 70.03,31.09 70.45,31.51 PR4924.2 70.66,30.56 PC4920.2 ; v3(126.97,193.52) 127.34,193.89 R435.2 127.81,193.88 C6536.2 ; v3(100.79,189.68) 99.92,190.54 99.92,193.3 C467.2 ; v1(23.55,6.65) 23.5,6.7 CNVBD2.3 ; EC707.2 v3(20.46,11) ; C243.2 C247.2 109.79,7.15 v3(109.09,7.85) ; C498.2 17.61,106.65 17.61,105.62 v3(17.48,105.49) ; v1(136.86,32.61) 136.69,32.61 D9.3 ; v3(104.52,81.92) 105.21,81.23 C147.2 104.74,80.48 103.91,79.65 PU1.1 ; C451.2 20.38,58.84 v3(20.35,58.87) ; v3(18.24,34.44) 19.14,34.44 C313.2 ; Q35.S v1(132.36,127.98) ; EC15.2 100.56,52.5 v3(101.09,53.04) ; R620.2 135,4.55 v1(134.77,4.78) ; v1(40.28,140.81) 40.31,140.85 C30.2 ; CRS1.6 134.02,149.93 134.03,149.92 v1(134.08,149.92) ; v3(95.12,189.8) 94.85,189.52 92.85,189.52 92.45,189.93 HDT1.17 ; v3(28.91,183.77) 28.52,184.16 PC4414.2 ; 55.4,198.17 CAM1.5 ; 55.4,198.17 56.06,198.84 59.01,198.84 CAM1.10 ; PC4801.2 v3(16.33,144.68) ; C483.2 74.47,82.83 C484.2 ; C506.2 19.81,86.32 18.96,86.32 v3(18.34,85.7) ; v1(21.49,6.65) 21.5,6.67 CNVBD2.1 ; v3(85.55,37.72) 85.77,37.5 PC4915.2 ; C207.2 120.22,24.35 120.29,24.42 v1(120.37,24.42) ; LVDS19.17 v3(8.74,100.5) ; v1(55.65,160.96) 56,160.96 56.31,161.26 C22.1 ; Q4807.S 35.02,65.02 v3(35.69,65.02) ; 84.42,189.29 84.83,189.7 HDT1.5 ; R578.2 v3(59.24,25.17) ; v3(16.62,11) EC705.2 ; C123.2 36.74,114.55 37.28,114.01 C137.2 C138.2 39.77,114.01 40.37,113.41 v3(42.27,113.41) ; C428.2 v3(20.29,80.85) ; PC4914.2 v3(82.7,35.64) ; Q44.2 110.86,194.55 110.86,193.33 v3(110.87,193.32) ; LVDS19.7 9.74,110.5 v3(9.68,110.57) ; R6571.2 v3(121.84,191.69) ; v3(111.84,87.91) 111.76,87.91 111.26,87.41 DBGH1.11 ; R477.2 26.94,34.42 R6105.1 26.89,33.35 C460.2 v3(26.86,32.13) ; PR4447.2 44.62,182.89 PC4433.2 46.27,182.89 v3(46.61,183.24) ; C245.2 109.82,4.04 106.81,4.04 v3(105.11,5.74) ; v3(15.73,89.02) 16.09,89.02 16.62,88.48 C501.2 16.93,88.95 17.65,89.66 C502.2 ; C446.2 63.09,194.28 v3(61.75,194.28) 61.7,194.33 C447.2 ; v3(10.08,119.74) 10.22,119.88 EC13.2 ; v1(135.49,112.01) 135.46,112.01 135.45,112 C390.2 ; D24.2 v1(133.81,84.33) ; v3(27.43,40.08) 26.99,39.64 R476.2 ; Q83.S 42.18,73.82 C679.2 43.03,74.7 v3(43.23,74.7) ; v1(113.28,23.88) 113.28,24.63 C206.2 ; v3(73.71,25.81) 73.71,25.73 73.7,25.72 PC4921.2 ; Q39.S 53.77,91.64 53.92,91.48 v3(53.94,91.48) ; PC4905.2 82.57,26.36 v3(82.6,26.39) ; v3(131.42,76.68) C148.2 C149.2 ; C237.2 110.22,11.68 110.59,11.68 v3(110.82,11.46) ; v1(133.96,36.86) 133.79,36.69 D12.3 ; PR18.2 v1(115.16,19.74) ; C680.2 26.36,59.75 v3(26.36,58.85) ; v3(109.8,47.32) 109.6,47.12 FANC1.5 ; EC702.2 v3(122.94,12.82) ; EC14.2 v3(21.01,194.88) ; v3(93.34,86.06) 93.48,85.92 EC16.2 ; v3(84.68,65.46) 85.04,65.1 C435.2 ; v1(111.84,34.8) 111.44,34.8 111.12,34.48 C198.2 109.66,34.48 C197.2 ; R14.2 R13.2 48.39,159.59 v1(48.9,159.08) ; FANC1.2 v5(107.3,41.07) ; C283.2 v3(104.52,60.58) ; PR7.1 130.81,13.51 v1(131.22,13.92) ; PR4805.1 13.79,111.78 v3(14.05,112.04) 13.6,112.48 C4801.2 ; PR16.2 115.01,13.79 115.57,14.35 v1(115.57,14.74) ; PR4925.2 82.08,30.5 82.08,29.63 v3(82.35,29.36) ; C389.2 134.72,107.85 v1(134.52,107.65) 135.41,106.76 EC9.2 ; v3(65.53,61.72) 65.28,61.98 C494.2 64.26,61.99 R583.2 ; C280.2 v1(116.07,44.02) ; v3(21.69,102.1) 20.76,103.02 v3(19.76,103.02) 19.05,103.02 v3(18.72,102.69) ; CNVBD2.2 v1(22.5,6.6) ; v3(18.64,31.29) 19.05,30.89 R316.2 20.16,30.2 C312.1 ; LVDS19.14 v3(9.75,103.5) ; v1(82.63,32.92) PC4906.2 ; v1(132.38,10.64) 132.16,10.64 132.14,10.63 EC703.2 R624.2 ; FC1.2 v3(130.28,103.12) ; R510.2 v3(64.77,80.97) ; PC4917.2 74.05,37.48 74.1,37.52 v1(74.1,37.56) ; U39.1 v1(133.45,8.55) ; D21.3 116.72,192.16 v3(115.21,190.65) ; C384.2 v1(134.42,106.58) ; PC5206.2 v3(50.52,28.12)
  TOP w0.635: 139.35,102 USB2S1.6 ; USB2S1.6 143.27,102 ; USB2S1.6 141.31,103.12 ; 141.31,62.88 USB2S2.5 ; USB2S2.5 141.31,65.12 ; USB2S2.5 139.35,64 ; USB2S2.5 143.27,64 ; 6.65,45.8 ODD1.9 ; ODD1.9 6.65,47.94 ; ODD1.9 5.04,46.87 ; ODD1.9 8.26,46.87 ; USB3S1.7 138.54,172 ; USB3S1.7 137.65,172.89 ; USB3S1.7 137.65,171.11 ; USB3S1.7 136.76,172 ; USB2S2.6 143.27,77 ; USB2S2.6 141.31,78.12 ; USB2S2.6 141.31,75.88 ; HDMI1.20 141.5,125.92 ; HDMI1.20 141.5,123.58 ; HDMI1.20 139.43,124.75 ; HDMI1.20 143.57,124.75 ; 135.26,168.5 USB3S1.4 ; USB3S1.4 136.15,169.39 ; USB3S1.4 136.15,167.61 ; 6.6,164.2 HDD1.P4 8.48,164.2 ; 5.46,44.31 ODD1.7 ; ODD1.7 6.4,45.19 ; ODD1.7 7.34,44.31 ; ODD1.8 8.26,34.13 ; ODD1.8 6.65,35.2 ; ODD1.8 5.04,34.13 ; ODD1.8 6.65,33.06 ; USB3S1.11 141.66,178.4 ; USB3S1.11 139.65,179.47 ; USB3S1.11 139.65,177.33 ; USB3S1.11 137.64,178.4 ; 138.6,65.97 USB2S2.4 ; USB2S2.4 138.6,68.03 ; USB2S2.4 139.63,67 ; USB2S2.4 137.57,67 ; 6.6,174.36 HDD1.P12 8.48,174.36 ; 8.48,171.82 HDD1.P10 6.6,171.82 ; USB3S1.10 141.66,165.6 ; USB3S1.10 139.65,166.67 ; USB3S1.10 139.65,164.53 ; USB3S1.10 137.64,165.6 ; 6.6,165.47 HDD1.P5 8.48,165.47 ; 8.48,166.74 HDD1.P6 6.6,166.74 ; 141.5,109.08 HDMI1.21 143.57,110.25 ; HDMI1.22 147.46,125.92 ; HDMI1.22 147.46,123.58 ; HDMI1.22 145.69,124.75 ; 8.48,173.09 HDD1.P11 6.6,173.09 ; 138.79,21.9 DCIN1.4 ; DCIN1.4 142.22,21.9 ; DCIN1.4 140.5,23.12 ; DCIN1.5 147.8,23.47 ; DCIN1.5 145.93,22.25 ; DCIN1.5 147.8,21.03 ; 7.54,154.92 HDD1.S7 6.6,154.04 ; 6.81,179.16 HDD1.24 ; HDD1.24 8.73,180.37 ; HDD1.24 6.81,181.59 ; DCIN1.3 142.22,13.3 ; DCIN1.3 138.79,13.3 ; DCIN1.3 140.5,12.08 ; HS3.1 8.86,20.75 ; HS3.1 1.64,20.75 ; HS3.1 5.25,24.36 ; HS3.1 5.25,17.14 ; 147.8,11.13 DCIN1.6 ; DCIN1.6 145.93,12.35 ; DCIN1.6 147.8,13.57 ; LVDS19.31 10.27,118.65 v3(10.8,118.13) ; RJ1.9 143.14,58.82 ; RJ1.9 141.22,57.8 ; RJ1.9 145.06,57.8 ; 147.46,109.08 HDMI1.23 ; HDMI1.23 147.46,111.42 ; HDMI1.23 145.69,110.25
  TOP w1.016: v5(108.08,111.02) 108.25,111.2 DIMM1.206 ; PR5019.2 v5(111.81,134) ; C205.2 107.95,24 106.81,25.15 v1(106.81,25.27) ; v3(32.26,5.5) CNVBD2.14 ; v5(9.83,85.01) 9.49,85.35 LVDS19.32
  L3 w0.635: H4.2 147.7,3.98 ; H4.2 148.49,3.19 ; H4.2 147.7,2.41 ; 6.3,196.02 H2.6 ; H2.6 5.51,196.81 ; H2.6 6.3,197.59 ; 94.81,94 HS5.1 ; HS5.1 96.8,95.99 ; HS5.1 98.79,94 ; HS5.1 96.8,92.01 ; 6.41,192.3 H2.8 ; H2.8 7.98,192.3 ; H2.8 7.19,191.51 ; 1.81,3.58 H3.7 1.81,5.15 ; 146.42,1.81 H4.1 144.85,1.81 ; H3.5 5.15,8.19 ; H3.5 3.58,8.19 ; H3.5 4.37,8.98 ; H4.8 143.98,2.3 ; H4.8 142.41,2.3 ; H4.8 143.19,1.51 ; H5.6 122.3,97.59 ; H5.6 122.3,96.02 ; H5.6 121.51,96.81 ; 127.7,92.41 H5.2 ; H5.2 128.49,93.19 ; H5.2 127.7,93.98 ; 146.02,7.7 H4.4 ; H4.4 147.59,7.7 ; H4.4 146.81,8.49 ; H5.7 121.81,95.15 ; H5.7 121.81,93.58 ; H5.7 121.02,94.37 ; H2.2 12.49,193.19 ; H2.2 11.7,192.41 ; H2.2 11.7,193.98 ; 6.42,1.81 H3.1 4.85,1.81 ; H5.1 126.42,91.81 ; H5.1 124.85,91.81 ; H5.1 125.63,91.02 ; 3.19,1.51 H3.8 ; H3.8 2.41,2.3 ; H3.8 3.98,2.3 ; H1.3 140.98,195.63 ; H1.3 140.19,196.42 ; H1.3 140.19,194.85 ; 7.7,2.41 H3.2 ; H3.2 7.7,3.98 ; H3.2 8.49,3.19 ; 122.41,92.3 H5.8 ; H5.8 123.98,92.3 ; H5.8 123.19,91.51 ; 142.3,6.02 H4.6 ; H4.6 142.3,7.59 ; H4.6 141.51,6.81 ; H3.3 8.98,5.63 ; H3.3 8.19,4.85 ; H3.3 8.19,6.42 ; H2.3 12.98,195.63 ; H2.3 12.19,194.85 ; H2.3 12.19,196.42 ; 9.15,198.19 H2.5 7.58,198.19 ; 143.58,8.19 H4.5 ; H4.5 145.15,8.19 ; H4.5 144.37,8.98 ; H2.1 10.42,191.81 ; H2.1 8.85,191.81 ; H2.1 9.63,191.02 ; HS2.1 27.18,145 ; HS2.1 25,147.18 ; HS2.1 22.82,145 ; HS2.1 25,142.82 ; 126.02,97.7 H5.4 ; H5.4 126.81,98.49 ; H5.4 127.59,97.7 ; HS4.1 39.29,40.2 ; HS4.1 37.3,42.19 ; HS4.1 37.3,38.21 ; HS4.1 35.31,40.2 ; 148.19,6.42 H4.3 148.19,4.85 ; 133.51,196.81 H1.6 ; H1.6 134.3,196.02 ; H1.6 134.3,197.59 ; H1.4 139.59,197.7 ; H1.4 138.02,197.7 ; H1.4 138.81,198.49 ; H4.7 141.81,5.15 ; H4.7 141.02,4.37 ; H4.7 141.81,3.58 ; 123.58,98.19 H5.5 ; H5.5 124.37,98.98 ; H5.5 125.15,98.19 ; HS3.1 7.19,20.75 ; HS3.1 5.25,18.81 ; HS3.1 5.25,22.69 ; HS3.1 3.31,20.75 ; H5.3 128.19,96.42 ; H5.3 128.19,94.85 ; H5.3 128.98,95.63 ; H1.7 133.81,195.15 ; H1.7 133.02,194.37 ; H1.7 133.81,193.58 ; H1.1 138.42,191.81 ; H1.1 136.85,191.81 ; H1.1 137.63,191.02 ; 135.19,191.51 H1.8 ; H1.8 135.98,192.3 ; H1.8 134.41,192.3 ; H3.6 2.3,7.59 ; H3.6 2.3,6.02 ; H3.6 1.51,6.81 ; 135.58,198.19 H1.5 137.15,198.19 ; H3.4 7.59,7.7 ; H3.4 6.02,7.7 ; H3.4 6.81,8.49 ; H1.2 139.7,193.98 ; H1.2 139.7,192.41 ; H1.2 140.49,193.19 ; H2.4 11.59,197.7 ; H2.4 10.02,197.7 ; H2.4 10.81,198.49 ; 5.81,195.15 H2.7 5.81,193.58
  BOTTOM w0.203: v3(59.21,136.89) 59.51,137.19 59.51,138.48 C128.2 ; U6503.54 64.55,76.47 v3(64.24,76.15) ; v3(42.57,150.63) 42.57,150.47 43.74,149.3 v3(43.74,149.1) ; PU5001.14 110.99,122.35 v3(111.14,122.2) ; PU5001.1 111.39,120.83 v3(111.14,121.08) ; v3(22.13,96.25) 22.35,96.47 U38.6 ; PU5001.3 110.59,120.57 110.08,121.08 v3(110.04,121.08) ; U38.16 22.08,95.19 21.08,96.19 v3(21.08,96.27)
  BOTTOM w0.254: v3(64.38,164.48) 64.85,164.02 R61.2 64.84,163.34 R60.2
  BOTTOM w0.305: C396.2 131.55,125.98 v1(132.08,125.45) ; v1(49.2,126.73) 49.51,127.04 R135.2 ; Q34.1 8.02,104.68 R386.1 8.97,103.5 v3(9.75,103.5) ; EC3.2 113.2,57.15 EC2.2 113.27,56.59 v3(113.61,56.26) ; v3(53.21,77.14) 52.72,76.65 R6545.1 ; v3(9.62,106.07) C375.1 9.54,107.11 R378.2 ; v1(62.66,129.06) 62.49,128.9 R73.2 ; R96.2 46.51,142.37 v3(47.92,142.37) ; R613.2 18.39,86.62 19.28,87.51 R610.2 ; v3(62.81,87.1) 63.19,87.47 R523.2 ; R131.2 83.87,85.07 C34.2 83.87,83.51 v3(83.36,83.01) ; v3(80.92,59.18) 81.93,60.19 C441.2 82.37,60.53 82.91,61.06 U51.2 ; R97.1 57.89,131.82 57.89,132.31 v3(57.61,132.59) ; C119.2 47.06,133.12 v3(46.79,132.84) 46.56,132.62 C139.2 46.56,132.03 C141.2 ; R288.2 108.72,67.83 109.55,67.01 v3(109.6,67.01) ; R94.2 46.86,128.76 46.86,127.09 v1(47.29,126.66) ; v3(56.38,122.43) 56.81,122 C33.1 ; v3(60.48,83.62) 60.79,83.93 U31.7 ; R93.2 v3(52.03,132.79) ; v3(70.84,61.34) 71.01,61.17 C491.1 ; R597.2 21.65,102.14 v3(21.69,102.1) ; v3(6.52,111.1) Q33.S 6.52,109 6.72,108.8 Q34.4 ; v1(56.67,127.41) 57.06,127.8 C113.2 C121.2 ; U31.38 77.59,85.25 v3(77.6,85.24) ; v3(53.87,132.49) 53.8,132.56 C118.2 ; v1(131,119.76) 130.38,119.76 130.22,119.6 C392.2 C395.2 ; v3(53.67,135.33) 53.67,136.04 C6535.2 ; Q4802.S 36.89,18.92 v3(37.24,19.27) ; R601.2 23.61,104.38 R605.2 v3(23.61,103.58) ; R99.2 52.4,147.27 v3(52.12,147.55) ; v1(129.62,124.74) 129.62,124.61 130.11,124.12 C394.2 ; C302.2 113.89,69.11 112.95,68.17 112.95,67.46 v3(112.47,66.98) 112.9,66.55 C268.2 ; C487.2 75.48,96.63 75.9,96.22 v3(75.95,96.22) ; PC5016.2 109,115.62 v3(108.28,115.62) ; C481.2 77.3,63.72 v3(77.04,63.98) 76.68,64.34 76.68,64.78 R546.2 ; v1(131.57,116.73) C393.2 C379.2 ; v3(106.49,118.56) 106.49,118.48 105.86,117.85 PR5022.2 ; C295.2 116.75,60.31 v1(118.01,59.05) 118.44,58.62 118.44,58.14 118.8,57.78 120.68,57.78 121,58.11 X3.4 121.92,59.84 121.92,61.97 121.65,62.25 120.35,62.25 119.49,61.38 X3.2 118.61,61.27 v3(117.63,62.26) 116.75,63.13 C294.2 ; C286.2 116.33,57.29 EC1.2 116.14,56.34 v3(116.34,56.13) ; R32.2 61.97,159.36 61.97,159.36 v1(61.97,159.41) ; v3(132.83,172.48) D19.8 D19.3 ; v3(64.87,104.98) 64.87,104.01 64.52,103.66 64.52,101.46 Q45.4 65.08,100.22 65.41,99.9 66.14,99.9 66.39,99.65 Q45.1 66.39,98.94 66.84,98.49 C480.2 R537.2 ; R31.2 56.39,158.62 R42.2 56.12,159.65 55.65,160.12 v1(55.65,160.96) ; C26.2 83.2,80.2 v3(83.57,80.57) ; U31.74 v3(71.79,67.39) ; C107.2 C110.2 51.54,127.22 C109.2 51.54,126.13 52.02,125.65 52.02,125.37 v1(52.04,125.37) 51.08,124.41 C106.2 ; v3(17.48,105.49) 17.38,105.49 16.82,106.05 U58.7 ; v3(25.48,93.09) R587.2 ; v1(107.57,55.88) 107.48,55.97 EC6.2 107.48,57.76 EC7.2 ; R560.2 80.63,69.42 v3(79.93,69.42) ; v3(52.59,139.3) 52.58,139.3 52.58,139.25 51.82,138.5 C117.2
  BOTTOM w0.381: 39.1,126.05 38.25,126.9 X1.3 ; 39.1,126.05 X1.2 ; 39.1,126.05 39.45,125.7 v3(39.45,124.82) ; C124.2 v3(45.85,145.68) ; v3(80.06,96.19) 80.88,97.01 U56.4 ; R6552.2 R6553.2 116.69,23.85 v1(116.97,23.57) ; U58.2 v3(16.82,110.25) ; v3(17.17,90.72) 17.28,90.72 R611.2 ; Q4402.E 49.94,115.42 v3(49.16,114.64) ; v3(50.52,28.12) 50.44,28.12 49.54,29.02 R6570.2 ; R134.2 56.03,131.91 v3(56.03,133.07) ; 46.65,136.92 46.99,136.58 47.59,136.58 47.75,136.74 v3(47.77,136.74) ; 46.65,136.92 46.31,136.58 C140.2 45.53,135.79 v3(45.5,135.76) 45.23,135.5 C142.2 ; 46.65,136.92 C135.2 ; C372.2 13.41,112.52 13.89,112.04 v3(14.05,112.04)
  BOTTOM w0.406: v1(116.86,11.91) 116.12,11.16 PR13.2 115.44,10.25 Q76.1 ; 121.16,22.99 121.15,22.98 119.76,22.98 ; Q76.4 112.08,8.35 v1(111.81,8.35) ; Q4.4 117.31,21.11 117.05,21.11 v1(117.02,21.08)
  BOTTOM w0.508: v3(110.78,171.97) C1.2 R7.2 ; R58.2 53.33,154.89 R12.2 54.37,154.89 54.66,154.6 v3(54.66,154.57) ; v3(130.61,134.1) 130.74,133.97 EC330.2 ; C3.2 109.87,167.31 C2.2 109.88,168.25 v3(109.88,169.16) ; C71.2 52.86,143.55 v3(52.83,143.52) ; EC329.2 v3(134.06,137.44) ; R342.1 29.9,9.17 C6104.2 C6103.2 32.41,9.17 32.49,9.25 v3(33.02,9.25) ; v3(111.1,66.99) 111.11,67.01 C273.2 C279.2 ; C5002.2 v3(106.49,118.56) ; v1(75.54,31.39) 75.15,31.78 Q4806.S ; v1(105.23,55.83) 104.69,56.38 EC8.2 ; v3(73.71,25.81) 72.89,26.63 Q4805.S ; v1(129.62,124.74) 129.31,124.74 128.28,125.77 C397.2 ; EC17.2 72.05,195.75 v3(72.06,195.76) ; v1(125.43,108.14) 125.34,108.22 R402.1 ; R810.2 124.5,5.21 U48.4 v1(121.79,5.21) ; D20.2 127.74,176.97 127.7,177.01 v3(127.46,177.01) ; C6512.2 103.87,51.98 C6522.2 103.24,52.12 C6523.2 ; R6554.2 123.19,25.13 R6555.2 125.88,25.13 v1(126.09,24.92) ; C412.2 13.93,165.39 v3(14.05,165.28) 14.16,165.17 C413.2 ; Q4401.S 33.38,182.18 33.53,182.32 v3(34.75,182.32) ; R268.1 v3(118.12,56.21) ; v3(40.11,30.48) 39.04,30.48 C6101.2 38.29,30.45 C6102.2 ; v3(8.69,94.87) 8.71,94.87 8.71,94.87 R384.2 ; v3(37.23,14.93) 37.23,14.91 37.68,14.47 Q100.S ; C326.2 v3(104.52,60.58) ; PC5001.2 111.4,127.24 111.4,127.24 v3(111.4,128.02) ; C507.2 25.09,86.89 v3(25.09,86.08) ; EC328.2 134.02,139.93 134.03,139.92 v3(134.06,139.92) ; v3(52.1,142.54) 52.2,142.44 C144.2 ; PC5009.2 114.31,117.44 v3(113.36,116.48) ; v3(39.83,192.91) 40.03,192.71 PC4432.2 ; v3(101.09,53.04) 101.09,51.37 R6513.1 ; v3(61.01,87.55) 60.99,87.57 R509.2 ; v3(52.81,156.88) 53.35,157.43 R17.2 ; EC709.2 133.31,132.27 v1(133.36,132.22) ; C511.2 18.2,86.65 18.23,86.62 R613.2 18.34,85.77 18.34,85.77 v3(18.34,85.7) ; v3(14.05,112.04) 14.26,111.82 U58.1 ; PC4425.2 63.42,193.8 v3(62.76,193.14) ; v3(109.8,47.32) 109.93,47.45 C6510.2 ; v1(49.66,156.88) 49.64,156.9 C59.2 48.51,157.45 C120.2 ; v3(19.36,110.08) U58.4 ; v1(110.49,56.03) 110.32,56.2 EC5.2 EC4.2 ; v1(129.13,4.67) PC6.2 128,4.97 127.51,5.45 PC4205.2 127.5,5.86 PR10.2 ; R179.1 121.16,21.25 121.16,23.7 120.43,24.42 v1(120.37,24.42) ; C6523.2 v3(104.11,53.15) 104.12,53.16 106.18,53.16 C6511.2 ; C6523.2 R6517.2 ; PC5204.2 v3(107.39,126.24) ; DCIN1.2 DCIN1.3 ; R6558.2 106.61,110.66 v3(106.73,110.54) ; C73.2 54.01,152.28 v3(54.79,152.28) 54.74,152.23 C72.2 ; C6520.2 C6521.2 10.37,117.75 10.74,118.13 v3(10.8,118.13) ; C388.2 130.83,112.87 v1(131.44,113.49) ; Q75.S v1(116.23,5.29)
  BOTTOM w0.635: 7.54,154.92 HDD1.S7 6.6,154.04 ; 6.6,171.82 HDD1.P10 8.48,171.82 ; 139.35,64 USB2S2.5 ; USB2S2.5 141.31,65.12 ; USB2S2.5 141.31,62.88 ; USB2S2.5 143.27,64 ; USB2S1.4 138.6,93.03 ; USB2S1.4 138.6,90.97 ; USB2S1.4 139.63,92 ; USB2S1.5 141.31,90.12 ; USB2S1.5 143.27,89 ; USB2S1.5 139.35,89 ; USB2S1.5 141.31,87.88 ; 147.8,21.03 DCIN1.5 ; DCIN1.5 145.93,22.25 ; DCIN1.5 147.8,23.47 ; 145.93,12.35 DCIN1.6 ; DCIN1.6 147.8,13.57 ; DCIN1.6 147.8,11.13 ; RJ1.9 143.14,58.82 ; RJ1.9 141.22,57.8 ; RJ1.9 145.06,57.8 ; 140.5,12.08 DCIN1.3 ; DCIN1.3 142.22,13.3 ; DCIN1.3 138.79,13.3 ; 141.5,125.92 HDMI1.20 141.5,123.58 ; 143.14,40.18 RJ1.10 ; RJ1.10 141.22,41.2 ; RJ1.10 145.06,41.2 ; 141.31,100.88 USB2S1.6 ; USB2S1.6 143.27,102 ; USB2S1.6 141.31,103.12 ; USB2S1.6 139.35,102 ; 147.46,109.08 HDMI1.23 147.46,111.42 ; 141.5,109.08 HDMI1.21 141.5,111.42 ; v3(13.17,130.27) 13.53,130.62 PR4812.2 ; USB2S2.6 141.31,78.12 ; USB2S2.6 141.31,75.88 ; USB2S2.6 143.27,77 ; USB2S2.4 139.63,67 ; USB2S2.4 138.6,68.03 ; USB2S2.4 137.57,67 ; USB2S2.4 138.6,65.97 ; 147.46,125.92 HDMI1.22 147.46,123.58 ; C426.2 v3(16.03,70.29) ; HDD1.S4 6.1,150.23 v5(5.84,150.5) ; DCIN1.4 140.5,23.12 ; DCIN1.4 142.22,21.9 ; DCIN1.4 138.79,21.9 ; 6.81,179.16 HDD1.24 6.81,181.59
  BOTTOM w1.016: v5(108.08,111.02) 108.97,111.02 110.08,112.13 PC5015.2 PC5014.2
  vias: v1(1.14,15.37) v1(1.14,13.54) v1(3.53,14.88) v1(3.45,12.88) v1(6.3,12.85) v1(6.38,14.86) v1(8.61,12.83) v1(8.69,14.83) v1(9.32,1.09) v1(10.44,12.83) v1(10.52,14.83) v1(11.15,1.09) v1(11.91,14.17) v1(11.99,11.43) v1(12.17,8.92) v1(12.19,6.32) v1(12.22,4.22) v1(13.36,1.12) v1(15.21,136.06) v1(15.2,135.14) v1(15.22,134.21) v1(15.29,114.22) v1(16.18,114.22) v1(16.21,1.09) v1(17.13,114.23) v1(18.52,1.07) v1(20.35,1.07) v1(22.56,1.09) v1(25.12,1.14) v1(27.43,1.12) v1(27.74,20.91) v1(28.24,20.35) v1(29.26,1.12) v1(31.47,1.14) v1(31.95,61.67) v1(32.03,59.46) v1(33.53,189.11) v1(34.38,128.58) v1(34.37,127.67) v1(34.38,126.76) v1(34.53,189.98) v1(34.52,189.11) v1(34.51,188.29) v1(34.95,1.09) v1(35.41,189.11) v1(37.26,1.07) v1(39.09,1.07) v1(41.3,1.09) v1(44.25,1.09) v1(46.56,1.07) v1(48.39,1.07) v1(50.6,1.09) v1(54.25,1.09) v1(56.57,1.07) v1(58.39,1.07) v1(60.6,1.09) v1(63.83,1.12) v1(63.99,31.4) v1(63.99,29.44) v1(66.14,1.09) v1(67.97,1.09) v1(68.3,30.89) v1(68.66,26.72) v1(68.76,32.64) v1(70.18,1.12) v1(73.58,1.12) v1(73.89,118.69) v1(74.04,117.02) v1(75.54,30.25) v1(75.9,1.09) v1(76.11,30.82) v1(76.68,31.39) v1(76.68,30.25) v1(77.72,1.09) v1(78.18,117.22) v1(79.27,112.39) v1(79.48,115.98) v1(80.36,1.09) v1(80.85,114.48) v1(81.09,111.46) v1(82.63,1.12) v1(84.94,1.09) v1(84.99,114.12) v1(85.61,111.31) v1(86.77,1.09) v1(88.04,156.72) v1(88.26,168.93) v1(88.61,128.96) v1(89,121.34) v1(88.98,1.12) v1(89.15,131.93) v1(89.99,176.99) v1(90.35,157.02) v1(90.35,123.6) v1(90.5,172.97) v1(90.5,169.27) v1(90.58,127.08) v1(90.63,122.35) v1(90.81,131.98) v1(90.88,159.16) v1(90.9,155.52) v1(90.88,130.78) v1(91.03,128.74) v1(91.52,1.09) v1(91.61,171.22) v1(92.2,120.65) v1(92.28,176.56) v1(92.3,172.9) v1(92.28,170) v1(92.33,160.43) v1(92.33,130.25) v1(92.38,158.78) v1(92.37,155.57) v1(92.38,132.03) v1(92.78,168.25) v1(93.83,1.07) v1(94.92,177.01) v1(95.66,1.07) v1(96.1,177.83) v1(97.56,178.84) v1(97.87,1.09) v1(98.29,133.65) v1(98.88,125.53) v1(98.97,168.4) v1(99.06,157.28) v1(99.06,118.75) v1(99.19,132.21) v1(99.72,111.87) v1(100.51,113.26) v1(100.65,119.39) v1(100.85,126.14) v1(100.81,1.09) v1(101.03,111.64) v1(101.09,108.86) v1(102.39,178.7) v1(103.12,1.07) v1(103.23,55.32) v1(103.61,178.41) v1(104.95,1.07) v1(105.97,19.63) v1(107.16,1.09) v1(107.95,54.61) v1(108.36,19.55) v1(109.47,54.48) v1(109.68,1.07) v1(111,55.12) v1(111.99,1.04) v1(113.33,19.56) v1(113.82,1.04) v1(116.03,1.07) v1(116.08,31.34) v1(117.02,31.34) v1(117.86,1.07) v1(117.96,33.27) v1(117.98,32.21) v1(117.98,31.34) v1(118.01,30.33) v1(118.01,29.46) v1(118.9,31.32) v1(119.46,1.07) v1(119.89,31.32) v1(121.28,1.07) v1(122.94,1.07) v1(124.76,1.07) v1(125.81,68.76) v1(126.44,63.68) v1(126.44,62.84) v1(126.44,62.08) v1(126.49,64.49) v1(126.54,1.07) v1(128.37,1.07) v1(129.36,7.59) v1(129.87,1.07) v1(130.2,8.76) v1(130.81,64.11) v1(130.78,63.25) v1(130.94,122.81) v1(131.63,141.34) v1(131.62,119.14) v1(131.57,64.14) v1(131.57,63.25) v1(131.7,1.07) v1(132.56,148.64) v1(132.68,156.9) v1(133.88,1.14) v1(134.08,154) v1(134.08,152.43) v1(135,60.58) v1(135.71,1.14) v1(135.81,60.53) v1(136.63,58.57) v1(136.68,59.39) v1(137.44,13.67) v1(137.44,11.84) v1(137.62,63.35) v1(137.9,1.14) v1(138.63,61.32) v1(138.84,5.11) v1(138.84,3.28) v1(138.86,6.93) v1(138.99,8.08) v1(139.73,1.14) v1(142.24,73.18) v1(142.62,69.32) v1(142.6,60.6) v1(145.31,79.07) v1(145.49,73.94) v1(145.77,65.76) v1(145.87,69.98) v1(146.1,61.37) v2(4.62,52.88) v2(7.62,157.28) v2(8.15,185.95) v2(10.92,187.76) v2(13.56,153.77) v2(17.93,6.83) v2(22.07,94.92) v2(25.4,152.73) v2(38.71,143.21) v2(49.76,150.47) v2(71.78,3.15) v2(76.5,2.97) v2(87.27,125.73) v2(87.71,158.75) v2(101.6,74.7) v2(109.19,56.49) v2(109.55,130.94) v2(114.6,42.04) v2(114.88,90.35) v2(116.59,30.15) v2(127.38,23.75) v2(131.01,11.89) v2(131.7,40.13) v2(131.67,35.64) v2(133.27,141.35) v2(133.55,151.08) v2(140.16,128.78) v2(140.87,184.58) v2(143,161.09) v2(143.69,182.3) v2(144.78,82.25) v2(144.88,85.83) v3(9.22,50.5) v3(20.05,96.28) v3(21.06,97.22) v3(21.11,95.3) v3(26.7,158.93) v3(26.7,158.19) v3(26.85,167.03) v3(26.8,165.61) v3(28.7,96.94) v3(28.99,129.16) v3(29.46,108.4) v3(29.46,98.76) v3(29.54,57.02) v3(29.63,106.16) v3(29.74,93.7) v3(29.83,132.19) v3(29.83,131.07) v3(29.82,130.05) v3(29.84,129.28) v3(30.1,167.39) v3(30.28,104.62) v3(30.35,168.4) v3(30.58,54.97) v3(30.61,53.37) v3(31.02,106.67) v3(32.13,165.74) v3(32.38,167.13) v3(33.53,165.86) v3(33.58,164.52) v3(33.76,140.92) v3(34.01,142.16) v3(34.65,150.14) v3(35.84,150.09) v3(36.9,108.01) v3(36.87,106.8) v3(36.96,104.93) v3(37.1,144.55) v3(37.72,163.29) v3(38.58,164.02) v3(38.58,163.25) v3(39.01,145.34) v3(39.34,136.45) v3(39.35,137.45) v3(39.65,45.38) v3(39.89,48.36) v3(40.03,142.27) v3(40.16,164.75) v3(40.44,9.58) v3(41.2,45.65) v3(41.35,9.58) v3(41.66,48.46) v3(41.76,164.72) v3(42.32,9.35) v3(42.34,8.41) v3(42.42,142.29) v3(42.72,43.92) v3(42.93,45.39) v3(44.37,43.97) v3(45.22,102.97) v3(45.59,101.08) v3(45.64,99.72) v3(50.32,147.8) v3(50.36,151.07) v3(51.18,152.31) v3(53.98,149.49) v3(54,148.4) v3(54,147.48) v3(53.98,146.47) v3(54,145.53) v3(55.12,141.46) v3(55.09,140.59) v3(55.88,150.53) v3(55.88,149.51) v3(55.88,148.55) v3(55.88,147.51) v3(55.88,146.49) v3(55.88,145.53) v3(55.88,144.56) v3(59.13,151.42) v3(59.17,152.24) v3(62.11,147.48) v3(62.13,145.55) v3(71.7,108.29) v3(74.07,180.16) v3(74.57,106.05) v3(75.29,181.74) v3(79.88,179.07) v3(84.4,104.54) v3(85.24,104.52) v3(85.29,66.14) v3(110.03,122.21) v3(110.59,121.64) v3(111.02,62.43) v3(112.09,63.41) v3(112.09,62.43) v3(112.09,61.42) v3(112.48,55.18) v3(113.1,62.43) v3(121.82,197.41) v3(122.96,197.79) v3(123.11,66.78) v3(123.22,67.69) v3(123.44,68.73) v3(126.01,197.41) v3(131.34,71.25) v3(131.7,70.48) v3(133.76,183.62) v3(134.62,70.74) v3(134.62,69.85) v3(134.96,183.64) v3(142.16,83.46) v3(142.19,82.25) v5(5.59,183.13) v5(5.59,168.91) v5(5.59,165.1) v5(5.71,176.02) v5(5.71,161.67) v5(5.71,158.62) v5(5.84,186.18) v5(5.84,152.91) v5(5.84,62.69) v5(5.84,59.97) v5(5.87,148.77) v5(5.87,61.29) v5(5.89,56.13) v5(5.92,54.51) v5(5.89,52.93) v5(5.87,50.85) v5(5.92,49) v5(5.97,189.36) v5(5.97,155.45) v5(8.99,58.03) v5(9.27,187.07) v5(9.27,186.06) v5(9.27,185.04) v5(10.16,189.1) v5(10.2,58.04) v5(11.53,58.09) v5(11.89,155.3) v5(12.3,123.02) v5(12.31,122.09) v5(12.31,121.15) v5(12.83,152.53) v5(12.9,155.3) v5(13.07,124.8) v5(13.79,155.3) v5(13.89,152.32) v5(14.02,151.31) v5(14.1,198.12) v5(14.07,124.76) v5(14.61,193.17) v5(14.78,152.32) v5(14.86,155.3) v5(15.04,151.31) v5(15.67,152.32) v5(16.18,151.43) v5(16.28,62.76) v5(16.26,61.59) v5(16.28,56.24) v5(16.28,55.12) v5(16.26,53.98) v5(16.69,152.32) v5(17.2,151.43) v5(17.7,152.32) v5(18.21,151.43) v5(18.69,119.51) v5(18.85,152.32) v5(19.23,151.43) v5(19.82,120.54) v5(19.94,152.3) v5(19.87,119.54) v5(20.9,120.51) v5(20.95,119.51) v5(21.08,187.32) v5(21.08,186.31) v5(21.08,185.29) v5(21.08,184.28) v5(21.08,183.26) v5(21.97,187.32) v5(21.97,186.31) v5(21.97,185.29) v5(21.97,184.28) v5(21.97,183.26) v5(22.86,187.32) v5(22.86,186.31) v5(22.86,185.29) v5(22.86,184.28) v5(22.86,183.26) v5(40.11,178.97) v5(40.16,178.03) v5(41,177.16) v5(41.1,179.83) v5(42.09,177.11) v5(42.19,179.81) v5(43.08,177.14) v5(43.08,176.23) v5(43.05,175.16) v5(43.05,174.22) v5(43.18,181.66) v5(43.18,180.75) v5(43.18,179.81) v5(44.93,14.17) v5(50.01,195.09) v5(50.06,194.2) v5(50.16,14.22) v5(50.97,195.1) v5(51.02,194.21) v5(51.93,195.07) v5(51.98,194.18) v5(53.11,194.31) v5(53.19,195.2) v5(54.33,194.28) v5(54.36,195.2) v5(55.42,195.2) v5(55.47,194.21) v5(56.54,195.16) v5(56.49,194.21) v5(57.47,195.2) v5(57.48,194.21) v5(58.45,195.23) v5(58.45,194.23) v5(59.34,195.22) v5(59.38,194.24) v5(68.06,181) v5(68.1,179.78) v5(68.17,177.08) v5(69,179.75) v5(69.06,181.03) v5(69.07,177.08) v5(70.08,181.05) v5(70.05,179.81) v5(70.07,177.08) v5(73.13,192.63) v5(73.08,190.3) v5(73.08,188.04) v5(73.05,185.95) v5(73.83,13.44) v5(73.86,14.48) v5(75.52,13.96) v5(75.52,12.81) v5(75.52,11.67) v5(76.65,14) v5(76.65,12.73) v5(76.65,11.58) v5(79.46,13.7) v5(79.5,12.72) v5(79.5,11.68) v5(87.45,24.03) v5(88.34,23.11) v5(88.42,24.03) v5(89.33,24.03) v5(89.26,23.11) v5(90.2,23.11) v5(90.27,24.03) v5(94.87,41.15) v5(95.86,41.17) v5(95.89,40.13) v5(95.94,39.24) v5(96.39,12.95) v5(96.39,11.81) v5(96.8,41.17) v5(96.77,40.13) v5(96.8,39.24) v5(97.46,12.95) v5(97.46,11.84) v5(98.55,12.93) v5(98.55,11.81) v5(102.11,68.66) v5(106.17,41.05) v5(106.91,175.94) v5(106.93,28.24) v5(106.93,27.18) v5(107.37,38.86) v5(107.39,37.64) v5(107.57,175.13) v5(108.18,174.27) v5(109.19,158.45) v5(109.19,157.35) v5(110.16,158.45) v5(110.16,157.35) v5(110.54,156.31) v5(110.54,155.35) v5(110.59,154.36) v5(110.89,132.14) v5(110.89,131.12) v5(111.15,158.5) v5(111.15,157.4) v5(111.78,132.56) v5(111.83,131.59) v5(111.82,130.68) v5(111.83,129.72) v5(114.81,155.73) v5(115.95,155.68) v5(116.89,94.34) v5(116.97,92.15) v5(117.12,89.71) v5(118.67,198.73) v5(119.91,89.2) v5(122.05,198.65) v5(125.68,198.68) v5(126.75,40.28) v5(127.97,40.21) v5(128.52,25.78) v5(129.01,198.65) v5(129.03,40.16) v5(129.54,26.8) v5(129.61,25.65) v5(130.2,186.69) v5(130.2,100.48) v5(130.2,40.18) v5(130.51,192.35) v5(130.56,194.97) v5(130.67,26.8) v5(130.76,25.65) v5(131.01,182.32) v5(131.04,99.64) v5(131.67,189.43) v5(131.83,26.8) v5(132.61,27.58) v5(133.72,27.53) v5(134.67,186.77) v5(134.87,27.53) v5(135,40.39) v5(135.28,188.9) v5(136.5,25.83) v5(137.12,23.85) v5(138.28,23.85) v5(138.48,11.84) v5(139.06,186.54) v5(139.06,183.85) v5(139.72,25.1) v5(140.13,153.11) v5(140.06,135.81) v5(140.28,144.37) v5(140.34,139.75) v5(140.39,189) v5(140.41,148.51) v5(140.87,25.1) v5(141.55,11.13) v5(141.81,23.65) v5(142.16,107.72) v5(142.16,106.05) v5(142.54,190.42) v5(143.25,12.29) v5(143.27,25.15) v5(143.4,21.39) v5(143.51,184.51) v5(143.61,198.83) v5(143.59,23.19) v5(143.55,13.74) v5(143.7,15.62) v5(143.76,18.62) v5(144.3,180.47) v5(144.3,176.56) v5(144.42,25.15) v5(144.4,12.29) v5(144.55,21.39) v5(144.7,13.74) v5(144.86,15.62) v5(145.39,171.02) v5(145.62,196.04) v5(145.62,191.72) v5(145.62,188.01) v5(145.67,166.5) v5(145.92,23.65) v5(146,182.63) v5(146,178.31) v5(146,174.6) v5(146.23,162.69) v5(146.19,25.1) v5(146.78,14.94) v5(147.14,151.94) v5(147.07,134.65) v5(147.29,143.21) v5(147.35,138.58) v5(147.35,25.1) v5(147.42,147.35) v5(147.93,14.94) v5(148.41,198.22) v5(148.41,193.9) v5(148.41,190.2) v5(148.54,185.14) v5(148.54,180.82) v5(148.54,177.11) v5(148.51,121.54) v5(148.51,117.22) v5(148.51,113.51) v5(148.64,140.67) v5(148.64,136.35) v5(148.64,132.64) v5(148.64,105.71) v5(148.64,101.4) v5(148.64,97.69) v5(148.62,80.19) v5(148.62,75.87) v5(148.62,72.16) v5(148.58,68.2) v5(148.58,63.88) v5(148.58,60.17) v5(148.69,153.92) v5(148.69,149.61) v5(148.69,145.9) v5(148.72,91.92) v5(148.72,87.6) v5(148.72,83.9) v5(148.77,170.76) v5(148.77,166.45) v5(148.77,162.74) v5(148.79,20.07) v5(148.79,16.41) v6(67.72,132.36)
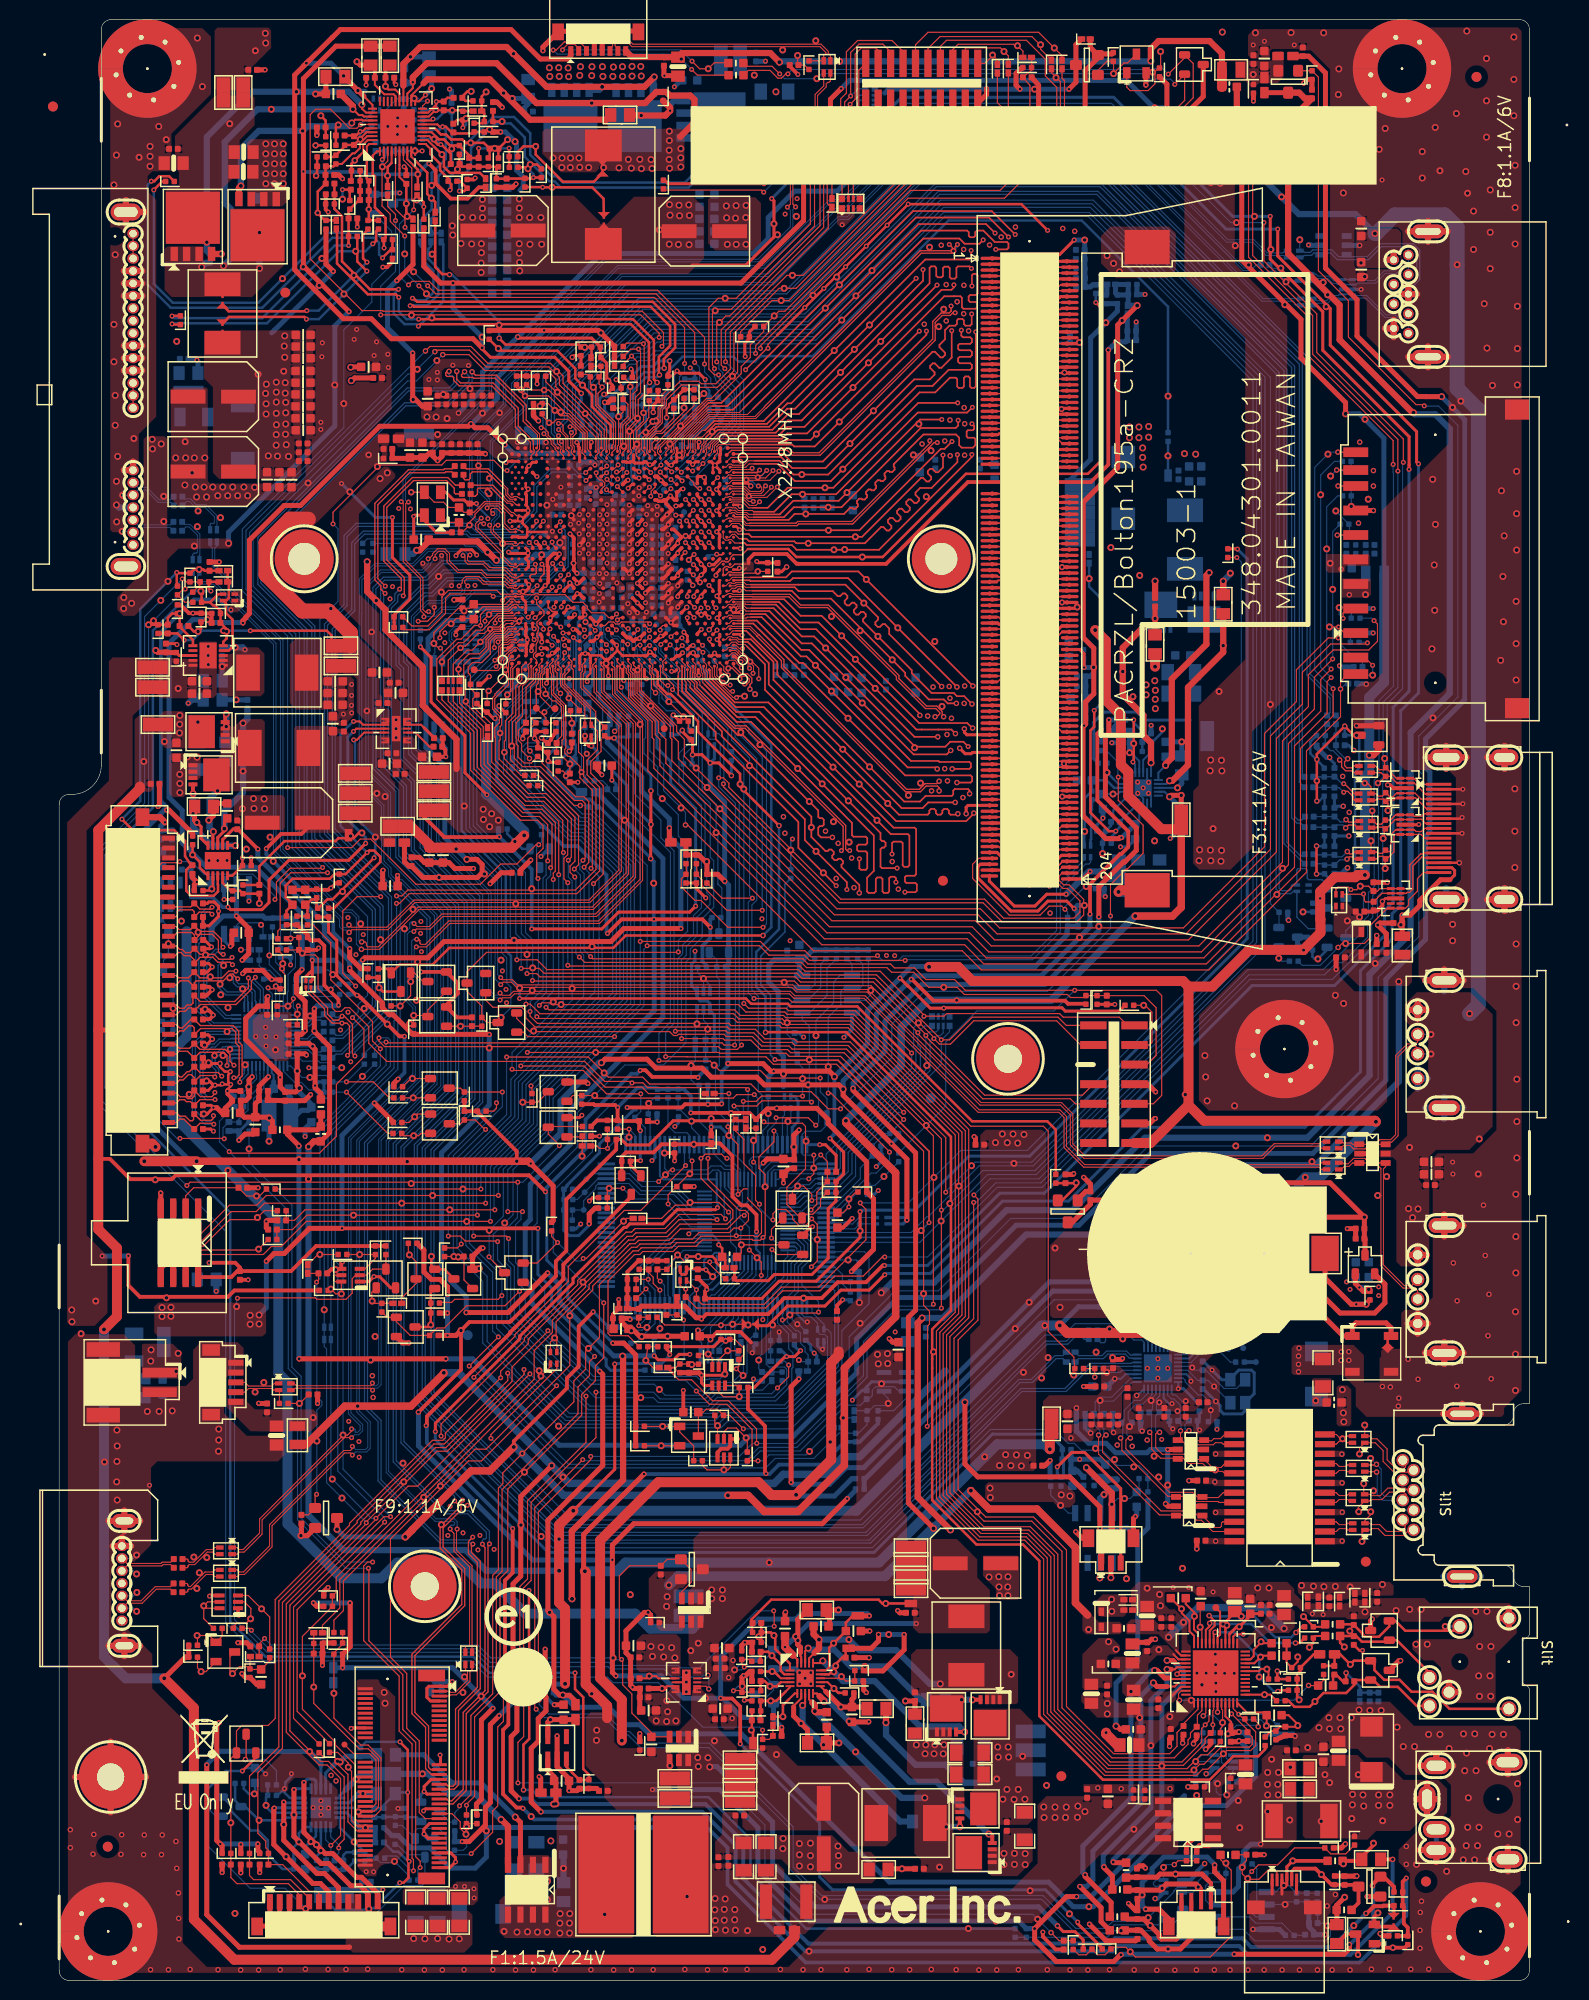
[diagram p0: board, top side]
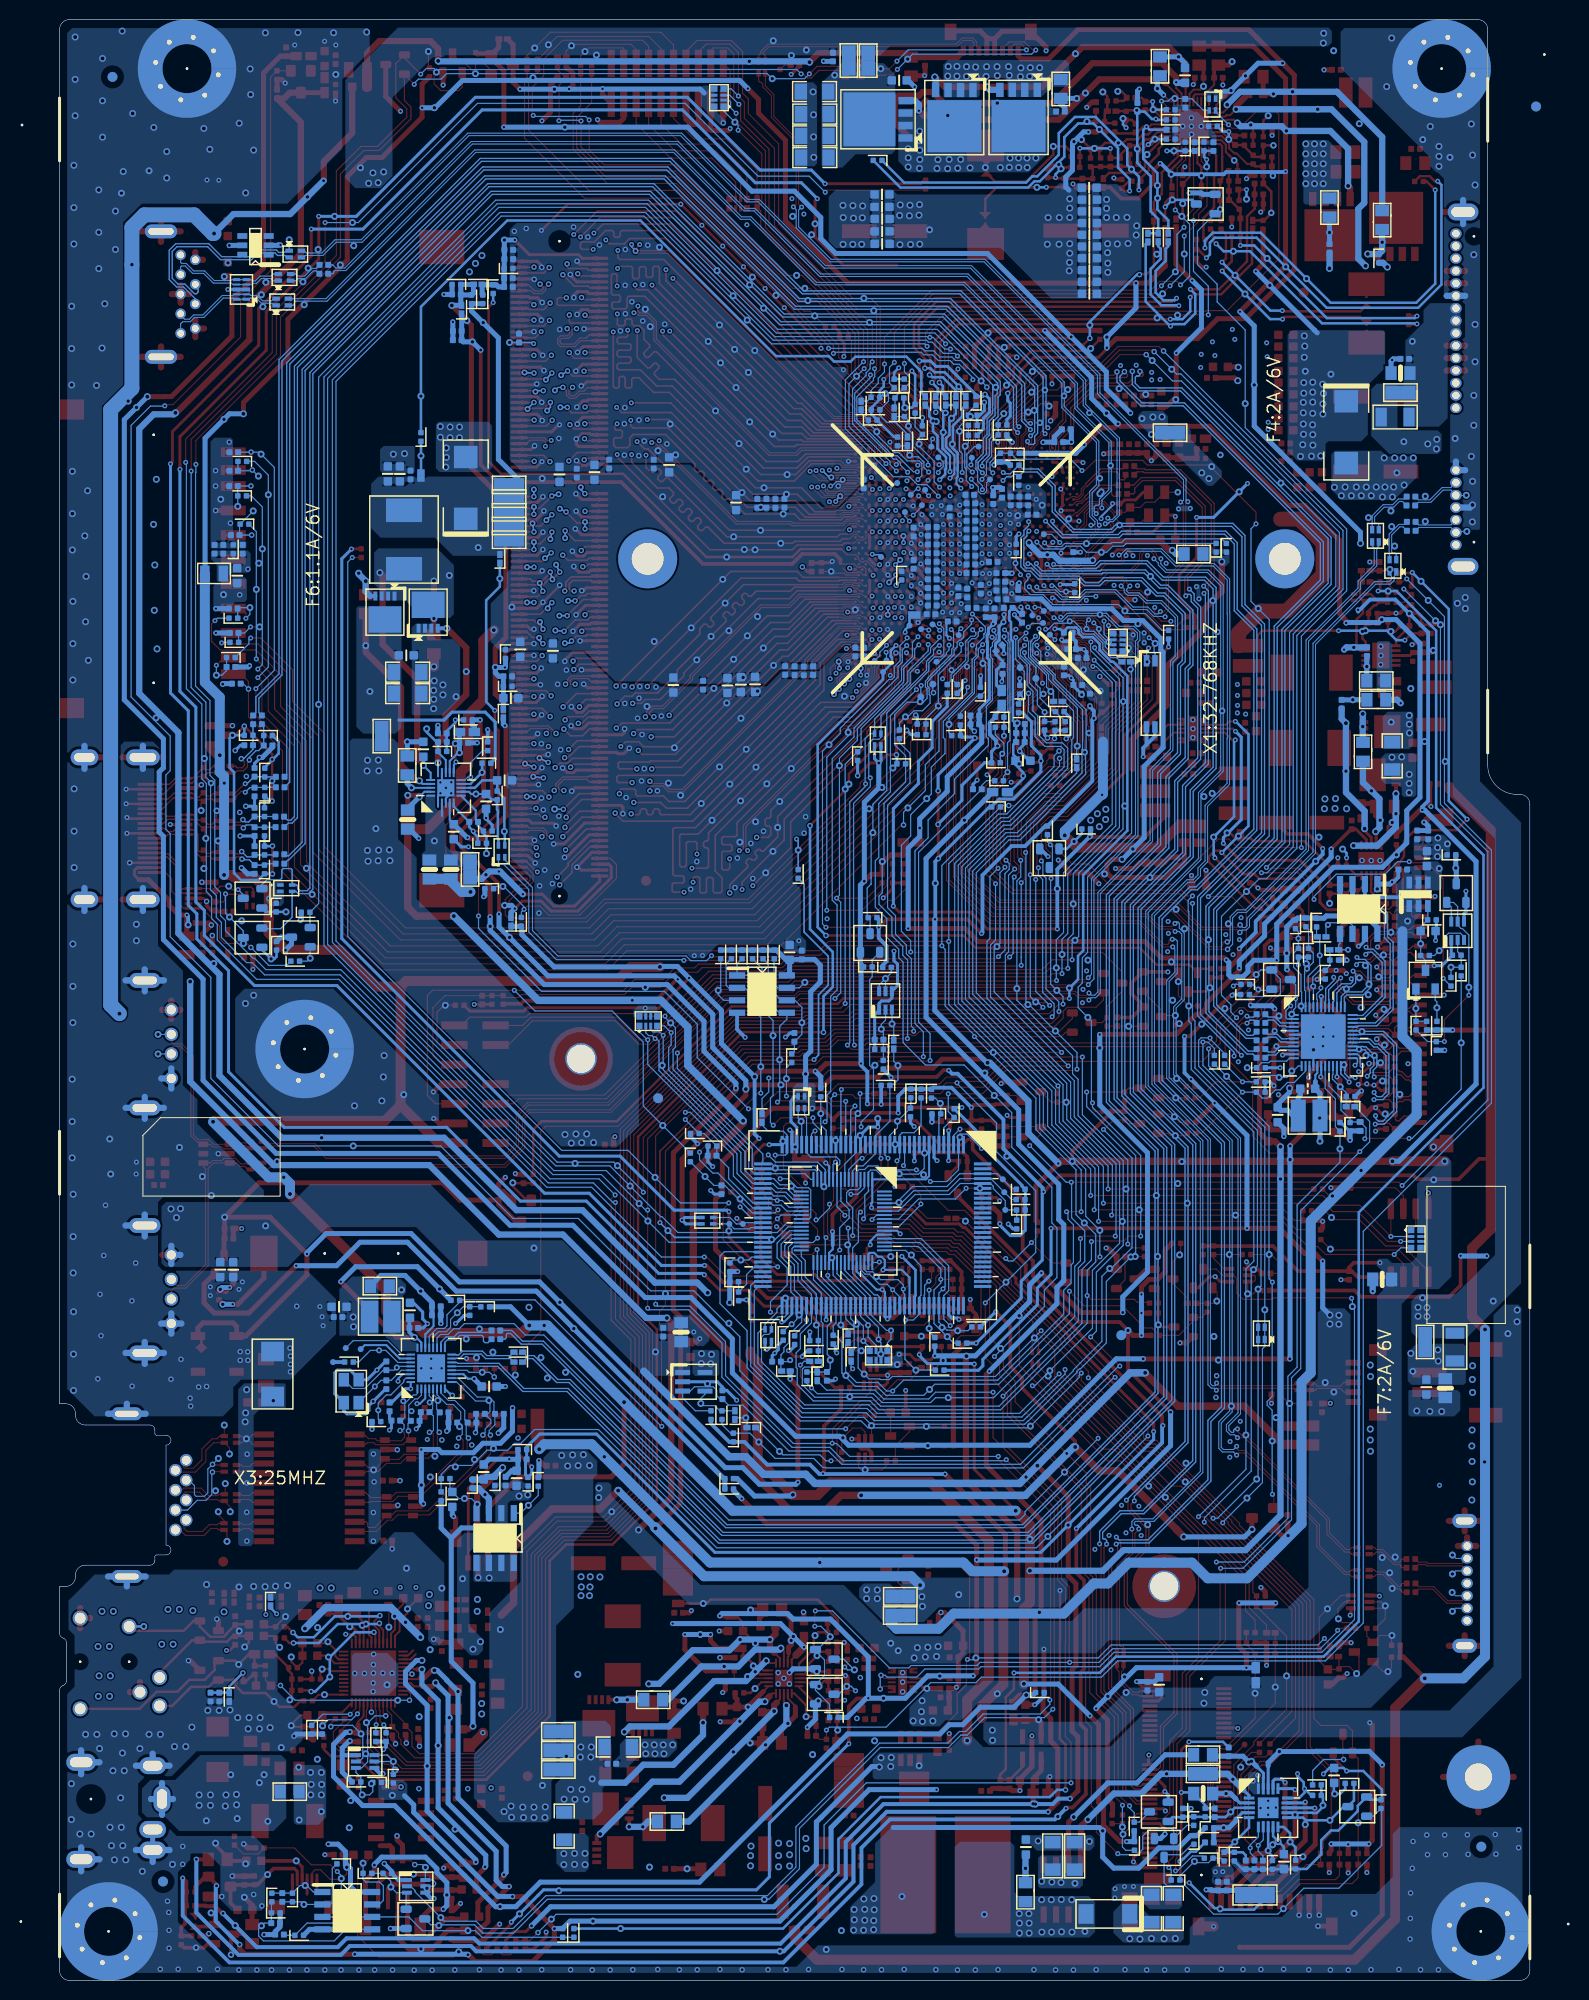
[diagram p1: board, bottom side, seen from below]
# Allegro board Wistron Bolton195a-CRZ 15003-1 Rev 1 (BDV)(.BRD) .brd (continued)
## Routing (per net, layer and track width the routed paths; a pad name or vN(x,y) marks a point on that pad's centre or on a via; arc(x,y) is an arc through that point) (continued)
V12: length 2.5
  TOP w0.114: HDD1.P13 HDD1.P14 HDD1.P15
V33: length 2.5
  TOP w0.114: HDD1.P1 HDD1.P2 HDD1.P3
VBAT_SB_N: length 4.9
  TOP w0.254: R122.2 C136.1 103.72,81.32 v2(103.76,81.36) 103.76,81 102.31,79.55 PU1.2
VBAT_SIO: length 17.5
  BOTTOM w0.114: U6503.29 75.29,75.67 75.47,75.49 75.47,75.49 76.01,74.95 76.01,73.95 75.03,72.97 75.03,70.43 74.29,69.69 U31.69 74.29,67.14 75.17,66.26 75.4,66.26 75.62,66.04 75.62,65.02 76.1,64.54 76.1,64.11 76.41,63.8 C481.1 ; C481.1 76.41,62.22 R545.1 ; C481.1 75.62,63.11 v6(75.46,63.27)
VCC5_CAM: length 67.2
  TOP w0.635: F8.2 118.63,196.56 117.37,197.82 112.17,197.82 111.38,197.03 v5(111.38,195.78) ; v5(73.48,195.66) 73.48,195.66 72.56,196.59 63.55,196.59 C446.1 61.71,196.17 C447.1 58.42,196.18 CAM1.8
  TOP w1.016: R463.2 118.63,193.14 F8.2
  BOTTOM w0.635: v5(111.38,195.78) 111.34,195.74 104.36,195.74 104.36,195.75 v2(79.63,195.75) 73.57,195.75 v5(73.48,195.66)
VCC5_PANEL:
  vias: v2(8.41,115.93) v5(9.38,116.53) v5(9.42,115.55) v5(9.42,114.64)
VCC5_TOU:
  vias: v2(25.91,57.4)
VDD_0.95_ALW: length 56.9
  TOP w0.356: v3(52.86,141.45) 52.86,141.43 52.5,141.07 CPU1.AJ11 ; CPU1.AE11 52.83,142.67 v3(52.83,142.5)
  TOP w0.381: v3(52.83,142.5) 53,142.5 CPU1.AE13 ; v3(52.86,141.45) 52.9,141.41 53.09,141.41 CPU1.AJ13
  TOP w0.508: v5(41.6,114.34) 42.63,114.34 43.15,113.82 43.15,112.98 42.67,112.5 v2(38.76,112.5) 37.11,112.5 C123.1 35.66,113.66 35.22,114.1 R121.2
  BOTTOM w0.508: C144.1 51.15,140.94 51.13,140.92 49.83,140.92 48.82,139.9 42.65,139.9 41.45,138.71 39.49,138.71 37.64,136.87 37.64,135.69 37.41,135.46 37.41,125.76 39.34,123.83 39.34,116.56 v2(40.5,115.4) 41.56,114.34 v5(41.6,114.34)
VDD_095_FB_H: length 75.1
  TOP w0.254: R4804.2 33.5,103.18 Q4801.S 34.72,103.6 38.08,103.6 39.79,105.32 56.54,105.32 57.8,106.58 v1(71.81,106.58) ; v3(64.67,136.16) 64.46,136.16 CPU1.AV33
  BOTTOM w0.254: v1(71.81,106.58) 72.65,107.43 72.65,126.05 65.99,132.72 TP17.1 65.07,134.36 65.07,134.9 65.19,135.02 65.19,135.64 v3(64.67,136.16)
VDD_095_FB_H_CTL: length 4.5
  TOP w0.254: Q4801.D 33.02,100.86 v2(32.64,101.24) 32.55,101.33 R4804.1 31.82,102.29 PR4814.2
VDD_095_FB_L: length 3.1
  TOP w0.254: v3(63.73,137.51) 64.1,137.14 CPU1.AU33
  BOTTOM w0.254: v3(63.73,137.51) 63.73,137.76 TP18.1 63.29,139.07 PG4802.2
VDD_095_GFX: length 18.3
  TOP w0.635: v5(36.47,145.87) 36.78,145.87 37.69,146.79 C125.1 37.88,146.77 42.68,146.77 v5(44.6,144.86)
  BOTTOM w0.635: v5(36.47,145.87) 36.09,145.49 L1.1 ; v5(44.6,144.86) 44.67,144.79 C124.1 47.99,144.79 48.61,145.41 v2(49.23,145.41) 49.96,145.41 51.09,146.54 v5(51.09,146.65)
VDDCR_APU_FB_H: length 47.1
  TOP w0.254: v3(36.04,171.58) 36.16,171.58 36.52,171.22 60.55,171.22 62.84,168.94 62.84,166.53 61.69,165.38 61.69,164.48 v1(61.72,164.45)
  BOTTOM w0.254: v2(37.47,172.03) 37.76,171.74 ; 37.76,171.74 38.18,172.16 38.18,174.37 37.16,175.39 37.16,176.37 37.15,176.62 36.89,176.88 PR4454.2 ; 37.76,171.74 37.39,171.37 36.25,171.37 v3(36.04,171.58) ; v1(61.72,164.45) 61.16,164.45 60.75,164.03 59.69,164.03 57.99,162.33 57.99,162.02 R35.1
VDDCR_APU_FB_L: length 46.4
  TOP w0.254: v3(35.81,170.81) 36.09,170.81 36.19,170.71 60.34,170.71 62.33,168.73 62.33,166.74 61.18,165.59 61.18,163.82 v1(61.24,163.76)
  BOTTOM w0.254: v2(38.05,176.07) 37.66,176.07 ; 37.66,176.07 37.66,176.37 37.66,176.63 37.92,176.89 PR4444.2 ; 37.66,176.07 37.66,175.6 38.68,174.58 38.68,171.95 37.6,170.87 35.86,170.87 v3(35.81,170.81) ; R37.1 58.55,162.18 59.9,163.53 60.96,163.53 61.19,163.76 v1(61.24,163.76)
VDDCR_CPU_SENSE: length 10.2
  TOP w0.254: CPU1.G23 58.45,152.6 v3(58.05,152.2)
  BOTTOM w0.203: 58.37,154 58.37,153.34 58.5,153.22 58.5,152.65 v3(58.05,152.2)
  BOTTOM w0.254: 58.37,154 58.37,155.78 58.93,156.34 v2(58.93,156.69) 58.85,156.77 58.85,158.57 57.91,159.51 57.91,160.31 R35.2
VDDCR_NB_FB_H: length 46.6
  TOP w0.254: v3(36.68,169.45) 36.68,169.44 58.54,169.44 60.67,167.31 60.67,163.31 v1(61,162.98) ; v3(34.65,171.68) 34.34,171.98 31.49,171.98 28.35,175.13 28.35,178.57 PR4403.2
  BOTTOM w0.254: v2(35.94,169.85) 35.94,169.45 ; 35.94,169.45 v3(36.68,169.45) ; 35.94,169.45 35.44,169.45 34.65,170.24 v3(34.65,171.68) ; R34.1 60.4,161.79 60.4,162.38 v1(61,162.98)
VDDCR_NB_FB_L: length 61.2
  TOP w0.254: v3(36.65,168.74) 36.65,168.74 36.85,168.94 58.33,168.94 60.17,167.09 60.17,163.05 v1(60.24,162.98) ; PC4402.2 28.08,182.19 PC4406.1 28.09,181.2 PR4409.1 28.08,180.7 28.85,179.93 28.85,175.34 31.7,172.49 v3(34.62,172.49)
  BOTTOM w0.254: R38.1 59.89,161.85 59.89,162.64 v1(60.24,162.98) ; 37.77,169.82 36.76,168.81 36.72,168.81 v3(36.65,168.74) 36.45,168.94 35.23,168.94 34.14,170.03 34.14,172.01 v3(34.62,172.49) ; 37.77,169.82 39.19,171.24 39.19,177.09 PR4437.2 ; 37.77,169.82 v2(38.02,169.57)
VDDCR_NB_SENSE: length 8.2
  TOP w0.254: CPU1.D23 58.74,154.06 58.99,154.06 59.07,153.98 59.07,153.98 v3(59.16,153.89)
  BOTTOM w0.203: v3(59.16,153.89) 59.16,155.52 59.24,155.6
  BOTTOM w0.254: R34.2 60.55,160.67 59.84,159.97 v2(59.84,157.91) 59.92,157.84 59.92,156.28 59.24,155.6
VDDIO_SUS_FB_H: length 77
  BOTTOM w0.254: PR5210.2 v2(113.13,161.59) 113.13,170.7 104.33,179.51 90.73,179.51 76.9,165.67 71.54,165.67 71,165.13 69.29,165.13 68.8,165.61 63.6,165.61 62.26,164.27 62.26,164.23 62.08,164.05 62.08,161.97 R36.1
VDDIO_SUS_FB_R: length 3.2
  BOTTOM w0.254: PG4905.2 113.12,153.81 v2(113.12,155.5) 113.12,156.98 PR5210.1
VDDIO_SUS_SENSE: length 9.4
  TOP w0.254: v3(60.2,153.07) 59.87,153.4 CPU1.E25
  BOTTOM w0.254: R36.2 61.26,160.26 61.26,159.55 60.89,159.17 v2(60.89,159.07) 60.89,158.02 60.43,157.56 60.43,156.24 59.56,155.37 59.56,154.17 59.65,154.09 59.65,153.62 v3(60.2,153.07)
VDDNB: length 17.7
  TOP w0.381: v3(53.09,146.42) 53.5,146.83 CPU1.U13
  TOP w0.508: C93.1 30.15,163.45 29.87,163.17 v5(29.79,163.17) ; C67.1 29.85,164.57 29.82,164.54 v5(29.74,164.54) ; v3(27.96,174.32) 27.96,174.33 27.22,175.07 PR4402.2
  BOTTOM w0.508: 21.69,168.05 21.97,168.33 21.97,168.33 v2(26.53,172.89) v3(27.96,174.32)
  vias: v2(20.29,163.83) v2(22.91,164.13) v2(52.25,149.4) v3(52.17,148.51) v3(53.01,148.64) v3(53.09,149.53) v3(53.06,147.55) v3(53.09,145.58) v3(55.15,149.49) v3(55.12,148.52) v3(55.12,147.51) v3(55.12,146.52) v3(55.12,145.48) v3(55.12,143.49) v3(55.15,142.48) v3(55.83,143.49) v3(56.9,142.54) v5(21.13,162.81) v5(21.06,161.87) v5(21.11,160.81) v5(21.11,159.77) v5(21.34,155.5) v5(22.15,163.02) v5(22.15,162) v5(22.15,160.99) v5(22.15,159.84) v5(22.14,157.67) v5(22.14,156.6) v5(22.16,158.67) v5(22.28,155.47) v5(23.01,167.74) v5(22.96,166.7) v5(23.01,165.56) v5(23.06,162.97) v5(23.06,161.9) v5(23.11,160.96) v5(23.11,159.89) v5(23.11,158.75) v5(23.09,157.71) v5(23.16,156.64) v5(23.39,155.45)
VSS_BEEMA: length 6.5
  TOP w0.114: CPU1.A23 58.6,158.05 59.61,159.06 v4(59.61,159.89) 59.61,161.39 60.21,161.99 R130.1
VSS_SENSE: length 10.1
  TOP w0.254: v3(59.15,153.23) 58.77,153.23 CPU1.E23
  BOTTOM w0.203: v3(59.15,153.23) 58.7,153.68 58.7,155.56 59.1,155.96
  BOTTOM w0.254: R38.2 59.6,160.68 R37.2 58.55,159.78 v2(59,159.33) 59.21,159.13 59.21,157.65 59.56,157.29 59.56,156.42 59.1,155.96
0D75V_S0: length 19
  TOP w0.305: DIMM1.203 94.9,112.13 97.44,109.58 99.55,109.58 100.75,110.79 v3(102.74,110.79) ; DIMM1.204 103.11,112.34 104.42,112.34 v3(105.18,113.11)
  BOTTOM w0.635: PR5021.2 106.93,112.35 v2(106.5,112.78) 106.17,113.11 v3(105.18,113.11) 105.05,113.11 v3(102.74,110.79)
0D95V_S0: length 62.9
  TOP w0.305: v3(64.94,109.58) 64.33,108.97 57.08,108.97 55.36,107.25 v3(48.21,107.25)
  TOP w0.381: v3(44.91,116.64) 44.88,116.62 39.29,116.62 37.21,118.69 37.21,119.7
  BOTTOM w0.305: R98.1 59.44,129.94 60.99,128.4 60.99,125.73 62.38,124.33 62.38,122.07 64.94,119.52 v3(64.94,109.58)
  BOTTOM w0.381: v3(44.91,116.64) 48.21,113.34 v2(48.21,111.35) v3(48.21,107.25)
  BOTTOM w0.508: v3(44.91,116.64) 44.82,116.73 R4403.2
0D95V_S0_EN: length 29.3
  TOP w0.203: U12.5 31.12,127.28 30.37,126.53 v3(30.05,126.53)
  TOP w0.254: v3(32.13,114.5) 27.9,110.27 27.37,110.27 26.45,109.36 R6578.2 26.26,109.46 R6577.1 26.1,110.26 25.76,110.26 25.21,109.72 C307.2 25.33,109.49 R302.2 R299.2
  BOTTOM w0.254: v3(30.05,126.53) 30.18,126.4 30.18,118.69 32,116.87 v2(32.26,116.61) 32.26,114.81 32.13,114.68 v3(32.13,114.5)
0D95V_S5:
  vias: v2(33.25,120.75)
0D95V_S5_PG: length 3.8
  TOP w0.254: PU4801.1 14.76,113.09 14.75,113.09 14.35,113.5 14.35,114.1 13.77,114.68 13.74,114.68 v2(13.61,114.81) PR4801.2
0P95V_MAIN_APU_M: length 3.5
  BOTTOM w0.254: R4403.1 45.71,117.44 45.71,116.95 v2(46.49,116.17) 47.24,115.42 Q4402.B
1D5V_S0: length 3
  TOP w0.508: C327.2 24.71,45.42 v2(24.66,45.36) 25.32,45.36 U16.S
1D5V_S3: length 288.1
  TOP w0.254: v1(100.69,140.56) 98.98,142.27 v1(98.98,142.32)
  TOP w0.305: DIMM1.123 96.17,136.65 96.18,136.64 96.89,136.64 v1(96.9,136.63) ; DIMM1.112 101.3,139.95 v1(100.69,140.56) ; CPU1.J35 65.1,151.45 v3(65.5,151.05) 65.9,150.65 CPU1.L37 ; DIMM1.100 100.99,143.55 v1(100.76,143.78) ; CPU1.AJ35 65.1,140.75 v3(65.5,141.15) 65.5,141.3 CPU1.AG37 ; v3(63.1,141.15) 63.1,141.3 CPU1.AG32 ; DIMM1.106 v1(101.61,141.75) ; DIMM1.87 96.76,147.45 97.37,148.06 v1(97.38,148.06) ; DIMM1.93 96.18,145.65 96.54,145.29 97.19,145.29 v1(97.69,145.78) ; v1(97.31,149.86) 96.7,149.25 DIMM1.81 ; DIMM1.117 95.76,138.45 95.89,138.33 96.91,138.33 v1(97.62,137.62) ; DIMM1.111 96.35,140.25 v1(97.31,139.29) ; CPU1.AE35 65.1,142.95 v3(65.5,143.35) 65.9,143.75 CPU1.AC37 65.9,144.05 v3(65.5,144.45) 65.5,144.56 65.1,144.96 CPU1.AA35 ; DIMM1.124 v1(101.6,136.35) ; CPU1.AL32 63.5,139.52 v1(64.03,140.05) ; DIMM1.99 95.79,143.85 96,143.64 97.02,143.64 97.49,144.11 97.49,144.17 v1(97.54,144.22) ; CPU1.N35 65.1,149.25 v3(65.5,148.85) 65.9,148.45 CPU1.R37 ; EC11.1 72.31,144.58 R4.2 71.91,144.61 71.91,144.6 71.3,144.6 v3(71.17,144.73) ; v3(62.92,150.39) 63.39,150.39 CPU1.L32 ; v1(97.32,151.63) 96.74,151.05 DIMM1.75 ; DIMM1.105 96.25,142.05 96.55,141.76 v1(96.72,141.76) ; DIMM1.94 101.29,145.35 v1(100.7,145.95) ; DIMM1.118 102.29,138.15 101.96,137.82 v1(101.6,137.82) ; CPU1.U35 65.1,147.05 v3(65.5,146.65) 65.9,146.25 CPU1.W37 ; DIMM1.76 101.28,150.75 v1(100.7,151.33) ; v1(100.58,149.89) 100.58,149.78 101.42,148.95 DIMM1.82 ; CPU1.AL37 65.9,139.42 v3(66.3,139.01) ; DIMM1.88 101.26,147.15 v1(100.69,147.72) ; CPU1.AR35 65.1,137.38 v3(65.52,137.8)
  TOP w0.356: CPU1.AC32 63.1,143.5 v3(63.1,143.29) 63.04,143.29 62.75,143 CPU1.AE31 ; CPU1.R31 62.7,148 CPU1.U32 63.1,146.8 v3(63.1,146.59) 63.09,146.59 CPU1.W31 ; CPU1.AA31 62.52,145 v3(63.1,145.58) 63.1,145.7 CPU1.W32
  TOP w0.381: v3(54.48,68.2) 53,66.72 53,62.63 51.8,61.43 51.8,60.42 46.38,55 v5(46.38,54.41)
  TOP w0.508: v5(28.35,46) U16.D
  TOP w0.762: v5(46.38,54.41) 43.94,51.97 42.01,51.97 36.02,45.98 36.02,45.95 v5(35.31,45.24) ; PR5011.1 114.48,109.45 113.59,108.56 v5(109.78,108.56) ; v5(80.26,87.68) 80.26,87.45 85.34,82.38 85.34,67.69 80.11,62.46 80.11,52.55 75.39,47.83 71.93,47.83 70.29,49.47 v5(68.22,49.47)
  TOP w1.016: PR5011.1 112.45,117.42 109.67,120.2 109.67,120.2 109.07,120.79 109.07,123.23 108.32,123.99 108.32,129.04 106.78,130.58 106.78,136.64 v5(105.69,137.73)
  BOTTOM w0.305: R832.1 54.5,68.2 v3(54.48,68.2)
  BOTTOM w0.508: v5(28.35,46) 29.11,45.24 v5(35.31,45.24) ; R139.1 R5.1 107.97,170.27 v2(106.78,169.09) 105.23,167.54 105.23,155.15 103.17,153.08 PR5213.1
  BOTTOM w0.762: 47.24,53.7 51.47,49.47 v5(68.22,49.47) ; 47.24,53.7 v6(47.24,53.75) ; 47.24,53.7 46.53,54.41 v5(46.38,54.41) ; v5(80.26,87.68) 85.9,93.32 85.9,97.23 88.64,99.97 v6(91.57,99.97) 101.18,99.97 109.78,108.56 v5(109.78,108.56)
  vias: v2(68.82,139.81) v2(80.14,145.95) v2(81.71,137.67) v2(88.47,151.33) v2(89.33,136.58) v2(100.76,153.2) v2(103.86,140.08)
1D5V_S3_PG: length 119
  TOP w0.114: v3(79.72,88.9) 78.46,88.9 76.71,90.65 71.35,90.65 70.57,91.43 60.24,91.43 59.53,92.13 56.03,92.13 v2(55.6,92.56) 55.1,93.06 53.97,94.18 v3(45.65,94.18) ; v3(107.26,108.57) 107.26,111.77 108.85,113.37 108.98,113.37 110.59,114.97 110.59,117.84 109.46,118.97 108.05,120.37 v3(108.05,122.73) ; R812.1 40.63,74.71 v3(41.02,75.11)
  BOTTOM w0.114: v3(41.02,75.11) 41.02,83.67 45.65,88.3 v3(45.65,94.18) ; v3(79.72,88.9) 84.94,94.13 84.94,97.54 88.29,100.88 100.83,100.88 107.26,107.31 v3(107.26,108.57) ; PU5001.10 108.65,122.44 108.36,122.73 v3(108.05,122.73) 108.01,122.77 108.01,124.27 106.85,125.44 PR5006.2
1D5V_S3_PG_R: length 5.6
  TOP w0.114: Q83.G 41.3,71.44 41.3,73.8 C679.1 v2(40.26,73.84) 39.33,73.84 R812.2
1D5V_S5: length 204.9
  TOP w0.203: 119.54,26.08 119.54,26.38 118.98,26.94 AUDIO1.9
  TOP w0.508: PR5204.2 52.68,28.47 52.07,29.08 51.41,29.08 v5(51.38,29.11) 51.05,29.11 50.47,29.69 50.47,37.11 v2(50.04,37.54) 49.86,37.72 49.86,46.93 55.45,52.52 55.45,61.82 v3(55.14,62.13) ; 119.54,26.08 119.54,25.6 119.53,25.59 C207.1 119.85,25.23 119.93,25.31 120.26,25.31 120.29,25.35 v1(120.37,25.35)
  BOTTOM w0.508: v1(120.37,25.35) 120.41,25.31 120.8,25.31 122.05,24.07 122.05,20.8 119.08,17.83 115.81,17.83 105.5,7.52 v2(105.05,7.52) 103.46,7.52 100.95,10.02 84.72,10.02 69.6,25.14 60.18,25.14 59.24,26.08 57.84,26.08 56.06,27.86 52.6,27.86 52.6,27.89 v5(51.38,29.11) 50.69,29.11 R6570.1 ; v3(55.14,62.13) 48.25,69.02 48.25,70.67 47.55,71.37 47.55,77.09 48.06,77.6 48.06,81.2 52.15,85.28 52.15,88.79 61.59,98.24 61.59,114.43 v2(57.68,118.34) 55.56,120.46 55.56,120.46 R111.1
1D8V_S0:
  vias: v2(32.46,154.41) v4(31.88,137.54) v5(32.74,153.18) v5(33.48,153.77)
1D8V_S0_EN: length 41.2
  TOP w0.203: U12.3 31,128.08 30.67,128.41 v3(30.04,128.41)
  TOP w0.254: R6576.2 28.03,109.36 32.75,114.08 32.75,114.62 32.13,115.24 31.62,115.24 v3(31.42,115.04) 29.22,112.84 R6575.1 28.08,112.84 27.61,112.37 23.82,112.37 23.11,111.67 23.11,110.49 23.8,109.8 C3619.2 23.19,109.1 R982.2
  BOTTOM w0.254: v3(31.42,115.04) v2(29.73,116.72) 28.7,117.75 28.7,127.12 30,128.41 v3(30.04,128.41)
1D8V_S5: length 40.2
  TOP w0.305: v3(34,149.22) 34,145.13 35.78,143.35 35.78,140.88 34.17,139.27 R65.2 34.17,138.54 34.18,138.53 R62.1
  TOP w1.524: 25.43,149.05 23.53,149.05 21.1,146.62 21.1,143.38 24.81,139.67 27.48,139.67 29.72,137.44 PR5211.2
  BOTTOM w0.305: v3(28.8,152.68) v2(29.65,151.83) 32.26,149.22 v3(34,149.22)
  vias: v4(31.39,129.49) v4(31.57,155.6)
1P8V_PWR_PG: length 9.7
  TOP w0.254: PU5101.4 17.29,135.64 17.69,136.03 17.69,138.8 17.02,139.47 17.02,140.45 RN19.4 16.74,140.77 17.08,140.77 17.31,141 17.31,142.53 R5201.1 R4801.1
3D3V_2136: length 278.4
  TOP w0.508: R589.2 125.89,196.27 C497.1 127.48,196.27 129.19,194.56 129.19,174.65 132.41,171.43 132.41,167.72 138.58,161.55 139.4,161.55 139.4,161.54 v5(141.05,161.54) ; L51.1 26.69,88.32 R588.2 26.34,86.76 L53.1 23.28,86.32 24.45,85.15 v1(24.45,85.11) ; v1(39.45,63.4) v1(24.49,63.4)
  BOTTOM w0.508: v1(24.49,63.4) 24.46,63.42 v2(24.46,83.72) 24.46,85.09 v1(24.45,85.11) ; v1(39.45,63.4) 42.19,63.4 51,54.58 69.49,54.58 70.41,55.5 74.89,55.5 81.36,61.97 81.36,65.44 85.57,69.65 90.25,69.65 97.62,77.03 104.04,77.03 111.37,84.35 127.9,84.35 135.36,91.81 135.36,102.12 139.4,106.17 139.4,116.7 139.84,117.13 139.84,123.25 139.4,123.69 139.4,126.63 143.4,130.62 143.4,159.19 v2(142.15,160.44) v5(141.05,161.54)
3D3V_A: length 448.7
  TOP w0.305: Q4804.G 58.28,83.15 R6535.1 58.36,83.62 v3(59.31,83.62) ; v1(101.85,5.56) 102.44,4.98 103.63,4.98 104.48,4.13 R622.2
  TOP w0.381: R556.2 R572.2 54.89,87.72 R568.2 ; R556.2 57.04,87.66 C482.1 59.17,86.8 v3(59.29,86.68) ; R556.2 56.97,89.03 v3(56.98,89.04) 56.72,89.29 54.62,89.29 54.53,89.37 R524.2 ; L50.2 66.7,65.7 67.13,66.14 69.52,66.14 70.59,65.07 ; v1(73.2,88.95) 72.22,88.95 R6540.2 70.43,88.48 v3(64.44,88.48) ; v3(7.06,73.91) 7.06,70.89 8.23,69.72 17.22,69.72 17.87,70.38 R309.1 ; v3(70.71,64.01) 70.71,64.03
  TOP w0.508: R822.1 16.62,13.73 v3(16.43,13.92) 16.07,14.28 16.07,26.03 v3(16.33,26.29) ; v3(48.97,20.78) 49.12,20.62 49.12,19.17 PR5201.1 ; v3(20.27,13.92) 20.27,13.25 20.46,13.06 R824.1 ; v3(18.53,13.87) R823.1 ; R6572.1 122.97,192.55 Q40.D ; v3(80.82,72.3) 83.08,74.56 83.08,79.72 R559.1 82.38,83.48 78.46,87.4 78.46,87.79 77.3,88.95 v1(73.2,88.95)
  TOP w0.635: v5(138.18,159.89) 138.09,159.89 130.63,167.35 130.63,170.89 125.38,176.14 125.38,189.53 C6536.1 127.09,191.96 126.5,192.55 Q40.D
  TOP w1.016: v5(57.4,24.46) 57.4,28.63 55.19,30.84 55.19,44.88 61.13,50.82 71.35,50.82 72.66,49.5 75.16,49.5 v5(75.18,49.53) 75.69,50.04 75.69,50.04 78.77,53.11 78.77,63.02 79.53,63.78 79.53,64.16
  BOTTOM w0.203: v3(76.33,67.16) 76.07,67.16 75.29,67.94 U31.67
  BOTTOM w0.305: U31.35 74.79,87.01 75.38,87.6 75.38,89.66 75.07,90.16 RN10.2 ; v3(59.31,83.62) 59.29,83.64 U31.4 59.29,86.65 59.26,86.68 v3(59.29,86.68) ; v3(70.71,64.01) 70.87,64.16 70.87,64.71 R527.1 ; v3(73.46,66.14) 73.46,65.89 73.47,65.87 R535.1 ; RN12.1 78.02,64.51 v3(77.88,64.36) 77.72,64.36 77.37,64.71 RN12.2
  BOTTOM w0.381: v3(64.44,88.48) 64.44,90.2 63.72,90.91 R520.1 62.12,90.91 R505.1 61.06,90.9 R504.1 60.87,91.06 59,91.06 v3(56.98,89.04)
  BOTTOM w0.508: C486.1 75.52,102.79 U56.8 ; C486.1 75.47,104.15 C485.1 72.98,104.15 72.39,103.56 72.39,101.83 73.36,100.86 73.36,94.79 73.89,94.26 v2(73.89,92.46) 73.89,91.16 ; C486.1 75.88,104.1 76.87,105.08 R551.2 78.22,105.08 R552.2 R553.2 R548.2 R549.2 R550.2 ; v1(101.85,5.56) 99.91,7.51 77.12,7.51 76.45,8.17 72.79,11.84 72.79,16.14 72.77,16.16 67.12,21.81 66.42,21.81 v5(66.37,21.77) ; v3(80.82,72.3) R698.2 81.61,71.29 R557.1 81.62,69.15 v5(81.64,69.14) ; v3(4.39,73.89) 7.03,73.89 v3(7.06,73.91) ; v3(20.27,13.92) 18.58,13.92 v3(18.53,13.87) 18.48,13.92 v3(16.43,13.92) ; v5(75.18,49.53) 75.29,49.53 75.42,49.4 79.1,49.4 80.87,51.18 R123.2
  BOTTOM w0.635: v5(138.18,159.89) 138.33,159.74 140.39,159.74 141.87,158.26 141.87,131.28 137.88,127.29 137.88,106.8 133.69,102.61 133.69,92.29 127.34,85.95 v2(123.27,85.95) 110.76,85.95 103.38,78.56 96.65,78.56 89.26,71.17 84.94,71.17 83.9,70.13 v5(83.87,70.13)
  vias: v2(2.24,65.96) v2(3.73,69.29) v2(62.31,21.89) v2(66.85,24.43) v2(81.71,67.03) v5(1.29,68.38) v5(1.31,67.18) v5(65.15,22.73) v5(65.2,21.82) v5(66.19,22.71)
3D3V_S0: length 914.9
  TOP w0.305: v3(62.29,63.83) 62.29,64.05 61.96,64.38 R579.1 66.79,64.64 R563.2 ; R493.1 108.14,98.87 102.65,98.87 102.31,99.21 90.29,99.21 v3(90.25,99.17) 88.87,99.17 86.62,101.41 86.58,101.44 v3(85.78,102.23) ; v1(68.58,122.89) 67.29,124.18 v1(66.42,124.18) 65.58,125.02 v1(64.62,125.02) 64.62,126.41 R70.1 64.42,126.54 63.58,127.38 v1(63.58,127.51) ; v1(43.15,166.52) 43.15,166.4 44,165.56 50.57,165.56 52,164.13 52,163.14 v1(53.26,161.87) ; R526.2 68.89,72.65 R502.2 69.09,71.37 72.34,71.37 72.96,72 76.79,72 78.46,73.66 78.46,78.71 79.26,79.51 R498.2 79.26,80.39 R501.2 80.04,82.26 80.04,84.48 v3(78.64,85.88) ; v5(52.45,47.9) 56.68,52.13 v3(56.68,62.87)
  TOP w0.381: v3(57.95,89.04) 63.52,89.04 63.85,89.36 66.17,89.36 v3(66.18,89.36) 67.54,89.36 v3(67.59,89.41) ; R982.1 24.25,107.68 R299.1 25.04,106.88 25.15,106.88 25.35,106.68 R367.1 25.63,106.1 26.49,106.1 27.05,105.54 27.05,101.5 28.5,100.05 v3(28.5,99.47)
  TOP w0.508: CAM1.1 52.2,196.3 51.88,195.99 49.1,195.99 46.1,198.98 28.68,198.98 27.87,198.18 27.86,198.18 25.46,195.78 25.45,195.78 v1(25.22,195.55) 24.97,195.3 24.97,195.29 24.03,194.35 24.03,174.5 24.26,174.27 24.26,174.24 29.01,169.49 31.85,169.49 33.9,167.45 42.23,167.45 v1(43.15,166.52) ; R6560.2 54.67,78.77 54.08,78.18 54.08,77.18 v3(54.07,77.18) ; v5(79.09,92.18) 79.09,92.23 78.58,92.74 72.91,92.74 v3(72.9,92.73) 72.6,92.73 72.31,93.02 71.82,93.51 68.24,93.51 v3(68.22,93.52) ; v1(106.17,46.15) 106.17,48.29 103.1,51.36 93.72,51.36 92.41,52.68 v5(92.41,58.98) ; R112.1 63.94,114.81 R6548.1 R6546.1 65.24,114.8 66.09,113.95 R562.2 67.19,112.82 v1(67.89,112.12) ; L5.1 108.25,25.6 107.92,25.93 v5(107.82,25.93) ; v3(79.78,192.96) 78.69,191.87 78.69,190.45 75.95,187.71 75.95,179.5 69.57,173.13 v1(40.18,173.13) 38.92,173.13 37.2,174.84 37.2,178.74 R4401.1 ; v3(44.89,27) 43.99,26.1 43.99,18.15 43.48,17.64 43.48,15.83 41.82,14.16 v3(41.12,14.16) ; R492.1 113.02,193.41 v3(113.02,191.01) 113.02,190.04 117.12,185.93 118.7,185.93 120.65,183.98 120.65,175.47 126.7,169.43 126.7,165.48 131.24,160.94 v5(131.24,159.79) ; v3(26.03,99.11) 26.03,96.79 27.59,95.23 27.59,86.48 R588.1
  TOP w0.635: R588.1 25.99,85.58 v5(25.44,85.03) ; Q35.G 134.63,125.51 134.09,124.97 v5(133.65,124.97)
  TOP w1.016: v5(133.22,112.75) 132.46,112.75 132.23,112.52 130.12,112.52 128.65,111.05 v3(128.65,110.36) 128.65,108.25 128.68,108.23 128.68,106.86 126.93,105.11 ; v5(102.08,66.8) 102.84,66.04 112.83,66.04 113.56,66.78 115.2,66.78 116.69,68.27 116.69,70.41 v5(126.49,80.21) ; 115.21,101.37 115.21,89.28 ; 115.21,101.37 117.65,101.37 121.39,105.11 126.93,105.11 ; 115.21,101.37 114.65,101.94 93.16,101.94 91.72,103.38 v5(88.75,103.38) ; 115.21,89.28 111.35,85.41 DBGH1.13 ; 115.21,89.28 116.81,87.68 134.24,87.68 v5(134.34,87.58) ; 126.93,105.11 v1(126.96,105.09) ; v5(51.61,30.25) 51.61,37.92 51,38.53 v5(51,41.78) v2(51,45.01) 51,46.46 v5(52.45,47.9)
  BOTTOM w0.305: v3(62.29,63.83) 62.29,63.74 61.47,62.92 56.73,62.92 v3(56.68,62.87) ; R497.2 64.57,124.98 v1(64.62,125.02) ; v1(63.58,127.51) 63.13,127.06 R69.1 ; R16.2 53.35,159.2 53.01,159.54 53.01,160.88 53.26,161.14 v1(53.26,161.87) ; RN5.2 66.2,124.4 v1(66.42,124.18) 66.85,124.61 66.85,125.96 RN5.1 ; R85.2 v1(68.58,122.89) ; v3(57.95,89.04) 58.6,89.04 R561.2 58.41,88.59 58.4,88.59 55.12,85.31 55.12,84.41 51.82,81.11 51.82,81.01 R513.2 51.46,80.66 51.46,79.7 R512.2 51.49,79.63 51.49,78.89 R511.2 51.48,76.51 52.02,75.97 53,75.97 54.07,77.04 v3(54.07,77.18)
  BOTTOM w0.381: R531.2 v3(66.18,89.36) ; v3(67.59,89.41) 67.59,92.68 68.22,93.32 v3(68.22,93.52) ; v5(79.09,92.18) 79.09,86.33 v3(78.64,85.88)
  BOTTOM w0.508: v1(66.42,124.18) 66.42,121.64 67.89,120.17 v1(67.89,112.12) 68.3,111.71 68.3,108.23 68.29,108.22 Q4803.G 68.3,104.86 68.3,103.7 R6534.1 68.22,103.14 v3(68.22,93.52) ; v3(113.02,191.01) v2(111.76,191.01) 111.68,191.01 108.89,193.8 103.56,193.8 103.55,193.8 80.62,193.8 v3(79.78,192.96) ; 51.59,30.23 51.61,30.23 ; 51.59,30.23 v5(51.61,30.25) ; 51.59,30.23 48.12,30.23 v3(44.89,27) ; 110.04,45.11 111.07,46.14 R6512.1 ; 110.04,45.11 110.04,32.54 107.82,30.33 v5(107.82,25.93) ; 110.04,45.11 108.99,46.15 v1(106.17,46.15) ; 31.22,192.69 30.59,192.69 v2(29.02,194.26) 27.72,195.55 v1(25.22,195.55) ; v5(79.09,92.18) 82.47,95.56 82.47,98.93 v3(85.78,102.23) 86.96,103.42 88.7,103.42 v5(88.75,103.38) 99.55,103.38 102.83,106.66 102.83,106.97 R6557.1 103.47,107.51 R136.1 ; v3(41.12,14.16) R6564.2 40.36,14.19 R6532.2 ; R542.2 72.34,92.17 v3(72.9,92.73) ; v5(102.08,66.8) 103.99,68.71 R286.1 ; F6.1 135.15,143.54 135.15,157.3 v2(133.22,159.23) 132.66,159.79 v5(131.24,159.79) ; v1(126.96,105.09) 126.33,105.71 Q37.C 127.44,106.41 R396.1 ; v3(26.03,99.11) 26.34,99.42 28.45,99.42 v3(28.5,99.47) ; v1(40.18,173.13) 40.18,170.59 v2(43.15,167.61) v1(43.15,166.52)
  BOTTOM w0.635: v5(25.44,85.03) 25.44,83.86 25.44,83.86 v2(25.44,81.74) 25.44,47.45 29,43.89 37.82,43.89 37.82,43.89 41.45,43.89 43.56,41.78 v5(51,41.78)
  BOTTOM w1.016: v5(102.08,66.8) v2(100.56,66.8) 100.23,66.8 v5(92.41,58.98) 81.33,47.9 v5(52.45,47.9) ; F6.1 135.18,132.41 133.65,130.89 v5(133.65,124.97) 133.65,123.25 133.22,122.81 v5(133.22,112.75) ; v5(126.49,80.21) 126.49,81.28 v2(127.13,81.92) 128.68,81.92 v5(134.34,87.58)
  vias: v2(54.33,29.24) v5(60.91,26.47) v5(62,28.52) v5(61.97,26.41) v5(62.08,27.41) v5(62.92,26.47)
3D3V_S5: length 674.2
  TOP w0.305: R581.1 70.92,60.48 74.07,63.63 v3(74.22,63.63) 75.03,63.63 v3(75.64,64.24) ; R466.1 50.02,124.25 v1(49.89,124.38) 49.89,125 R78.2 49.57,125.26 49.1,125.73 R81.2 48.83,126.33 v1(48.5,126.67) 48.5,126.86 48.52,126.88 48.52,127.26 R80.2 R90.1 ; v1(44.48,128.73) 44.3,128.73 R1019.2 43.61,129.41 43.45,129.41 R127.1 ; RN3.1 53.63,126.31 54.03,125.91 v1(54.31,125.91) 54.28,125.94 RN3.2 ; v1(60.35,114.43) 60.35,117.88 v1(60.38,117.9) 60.38,118.35 60.36,118.37 60.36,121.33 v1(60.37,121.34) ; v1(56.62,126.72) 55.88,126.72 55.88,126.72 R77.2 ; R1020.2 45.52,129.31 44.88,129.94 v1(44.88,130)
  TOP w0.381: v3(66.43,107.42) 65.61,108.23 v3(60.68,108.23) 57.38,108.23 v3(55.94,106.79) ; v3(106.32,127.58) 105.91,127.17 105.91,120.36 106.61,119.66 107.13,119.14 108.59,117.69 109.07,117.21 109.07,115.6 108.37,114.91 108.25,114.91 105.17,111.83 105.17,108.77 v3(105.16,108.76) ; R310.1 R303.1 32.17,74.9 26.21,74.9 23.66,72.35 C427.1 ; v3(72.11,51.69) 72.01,51.79 72.01,56.54 70.27,58.28 R581.1 ; v3(86.93,102.11) 87.01,102.11 89.19,99.93 102.61,99.93 102.92,99.62 104.69,99.62 R126.1 ; C427.1 18.44,72.72 17.96,73.2 v3(15.29,73.2) ; C427.1 18.17,72.35 17.56,71.74 U30.8 ; v2(46.69,83.55) 46.69,84.56 42.67,88.57 R515.1 42.65,88.65 R608.1 41.34,88.66 R609.1
  TOP w0.406: R617.1 136.18,9.54 135.14,10.58 U39.2 133.99,9.77 v1(133.99,9.65)
  TOP w0.508: v1(119.89,2.67) 131.07,2.67 131.62,3.22 v1(131.62,3.66) ; v1(103.79,8.55) 102.78,8.55 v1(99.52,5.28) 99.52,4.14 101.73,1.92 107.59,1.92 108.28,2.62 v1(108.33,2.62) ; v3(59.66,51.64) 53.51,45.49 53.51,41.86 v5(53.63,41.73) ; v3(48.11,83.32) 50.39,81.04 50.39,77.48 R518.1 ; v3(86.49,77.55) 86.49,83.77 v3(84.91,85.34) 79.98,90.27 v5(79.98,90.91) 79.55,91.34 v2(76.4,91.34) 71.95,91.34 71.17,92.13 66.52,92.13 65.6,93.05 60.88,93.05 59.97,93.96 55.68,93.96 v5(55.32,93.6) ; PR4801.1 13.61,116.97 11.2,119.38 v3(10.97,119.38)
  TOP w0.762: v3(48.11,83.32) 47.88,83.55 v2(46.69,83.55) v5(14.02,83.55)
  TOP w1.016: 55.91,26.75 55.91,28.02 53.71,30.21 53.71,41.65 v5(53.63,41.73) ; v5(101.07,54.18) 101.07,55.63 R278.1 ; v5(8.69,83.55) v5(14.02,83.55)
  BOTTOM w0.305: RN15.4 86.11,77.17 v3(86.49,77.55) 86.22,77.82 RN15.3 ; 54.36,125.91 54.91,125.35 R516.1 55.63,124.2 57.94,121.89 57.94,120.37 60.38,117.93 v1(60.38,117.9) ; v1(48.5,126.67) 48.5,126.8 48.44,126.86 R129.1 R89.1 ; v3(75.64,64.24) 75.46,64.24 75.03,64.67 75.03,64.83 R544.2 ; R88.1 52.14,129.31 51.76,129.31 50.85,128.4 50.85,125.93 49.89,124.97 v1(49.89,124.38) 49.89,123.29 52.68,120.5 54.15,120.5 54.9,119.75 R79.2 55.13,119.69 60.35,114.48 v1(60.35,114.43) ; R517.1 73.73,64.22 74.22,63.73 v3(74.22,63.63) ; R128.1 58.09,128.04 R76.1 57.94,126.82 56.72,126.82 v1(56.62,126.72) 60.37,122.97 v1(60.37,121.34)
  BOTTOM w0.381: v1(44.88,130) 44.88,129.9 44.48,129.49 v1(44.48,128.73) 44.64,128.56 44.64,122.32 R4402.2 49.43,117.75 51.48,115.7 52.87,115.7 55.84,112.73 55.84,106.89 v3(55.94,106.79) ; R113.1 53.88,129.76 54.54,129.1 R83.2 55.1,128.29 55.1,127.1 54.45,126.45 54.45,126.08 54.36,125.98 54.36,125.91 v1(54.31,125.91) ; R6533.1 66.43,108.22 v3(66.43,107.42) 66.43,106.32 65.63,105.52 65.63,103.94 66.03,103.54 R529.1 ; R441.1 83.54,56.79 81.67,54.93 R533.1 80.12,54.93 77.81,52.61 73.44,52.61 72.47,51.64 72.15,51.64 v3(72.11,51.69) 72.07,51.64 v3(59.66,51.64) ; v3(60.68,108.23) 60.66,108.25 v2(60.66,111.91) 60.66,114.12 v1(60.35,114.43) ; v3(10.97,119.38) 10.97,119.71 10.37,120.31 10.37,137.5 v2(12.29,139.42) 13.72,140.85 16.3,140.85 17.53,139.62 v3(17.53,139.8) ; v3(106.32,127.58) PR5006.1 ; R125.1 85.64,86.07 v3(84.91,85.34)
  BOTTOM w0.406: v1(133.99,9.65) 134.06,9.58 134.06,6.04 131.68,3.66 v1(131.62,3.66)
  BOTTOM w0.508: v5(14.02,83.55) 13.36,83.55 5.49,91.43 5.49,114.13 10.74,119.38 v3(10.97,119.38) ; 114.81,18.85 113.87,17.91 113.87,17.14 105.28,8.56 103.8,8.56 v1(103.79,8.55) ; v3(60.68,108.23) 60.71,108.2 60.71,98.93 55.37,93.6 v5(55.32,93.6) ; v5(79.98,90.91) 79.98,91.77 83.36,95.15 83.36,98.54 v3(86.93,102.11) 87.28,102.46 100.18,102.46 v2(104.09,106.38) 105.16,107.45 v3(105.16,108.76) ; v3(60.53,19.46) 67.41,19.46 71.29,15.58 71.29,11.27 74.99,7.57 76.51,6.05 v2(95.58,6.05) 97.91,6.05 R809.2 99.08,5.29 99.09,5.28 v1(99.52,5.28) ; v1(108.33,2.62) 108.38,2.67 v1(119.89,2.67) ; R1028.2 v3(34.57,17.54)
  BOTTOM w0.635: v5(55.32,93.6) 55.07,93.6 51.16,89.69 51.16,86.41 48.11,83.36 v3(48.11,83.32)
  BOTTOM w1.016: v5(53.63,41.73) 56.89,41.73 57.78,42.62 v2(72.44,42.62) 83.64,42.62 v2(94.43,53.41) 95.71,54.69 100.56,54.69 v5(101.07,54.18)
  vias: v2(9.8,81.66) v2(116.05,18.87) v3(31.32,11.09) v3(32.08,11.07) v5(33.16,29.38) v5(33.25,28.27) v5(54.84,25.53) v5(54.81,24.49)
3D3V_S5_RSV: length 41.5
  TOP w0.508: v3(28.92,31.89) R475.1 29.69,34.05 29.69,38.48 v3(29.67,38.51) ; v3(44.25,27.74) 43.08,26.57 43.08,18.49 42.57,17.99 42.57,16.93 R6566.1 ; v3(25.93,38.51) 26.29,38.15 R474.1
  BOTTOM w0.508: R6103.2 v3(28.92,31.89) 29.25,31.89 29.25,31.89 40.14,31.89 v2(43.05,28.98) 44.25,27.79 v3(44.25,27.74) ; v3(25.93,38.51) v3(29.67,38.51)
3D3V_USB:
  vias: v2(121.82,194.41)
+1P5V_LPS_APU: length 111.3
  TOP w0.254: CPU1.AN4 48.3,138.04 48.46,137.88 48.46,137.86 v3(48.47,137.86) ; R122.1 101.68,86.77 100.81,87.63 93.14,87.63 81.43,99.35 74.6,99.35 74.34,99.61 70.6,99.61 70.06,100.15 v3(46.98,100.15)
  BOTTOM w0.254: v3(46.98,100.15) v2(46.98,101.22) 46.1,102.1 46.1,104.5 45.57,105.03 45.57,112.77 41.06,117.27 41.06,133.06 42.51,134.5 42.7,134.5 43.89,135.69 43.89,136.32 44.58,137.01 45.62,137.01 46.05,137.44 46.05,137.75 46.29,138 47.17,138 47.54,137.63 C135.1 47.91,137.84 48.42,137.84 48.44,137.86 v3(48.47,137.86)
+AUD_DVDD_1:
  vias: v2(113.31,26.9)
+HDT_VDDIO_SUS: length 31.2
  TOP w0.508: v3(103.02,192.9) 103.73,193.61 Q43.D 103.73,197.45 R489.1 ; v3(98.02,192.91) 97.63,193.31 97.63,194.52 98.09,194.99 98.18,194.99 R491.1 ; HDT1.1 v1(82.29,189.46) ; HDT1.19 94.62,192.37 94.62,192.82 94.61,192.84 v3(94.61,192.94)
  BOTTOM w0.508: 98.01,192.9 v2(99.52,192.9) v3(103.02,192.9) ; 98.01,192.9 v3(98.02,192.91) ; 98.01,192.9 94.65,192.9 v3(94.61,192.94) 94.58,192.91 84.63,192.91 84.23,192.51
+RTCVCC: length 139.9
  TOP w0.254: G3.2 135.53,65.39 CMOS1.3
  TOP w0.508: CMOS1.3 135.88,66.56 135.37,67.07 132.31,67.07 131.94,66.7 CMOS1.1 130.99,65.73 124.76,71.96 v3(124.76,74.09) 128.52,77.85 v2(133.16,77.85) ; v3(74.68,50.8) 74.68,60.55 v3(75.46,61.34) ; v2(133.16,77.85) 129.66,81.35 110.95,81.35 109.18,79.59 C147.1 105.21,79.17 103.35,77.32 PU1.3 ; v2(133.16,77.85) C148.1 C149.1 133.22,75.6 D4.3
  BOTTOM w0.508: v3(124.76,74.09) 124.76,74.22 122.8,76.18 114.14,76.18 109.21,71.25 101.04,71.25 v2(98.96,69.17) 82.09,52.3 80.29,52.3 78.6,50.6 74.87,50.6 v3(74.68,50.8) ; v3(75.46,61.34) 75.46,62.14 R545.2
A_RST_N: length 138.3
  TOP w0.114: DBGH1.9 111.62,89.41 112.48,90.27 112.48,100.45 111.94,100.99 v3(103.61,100.99) 92.44,100.99 91.35,102.08 88.44,102.08 87.25,103.28 85.22,103.28 84.82,103.67 76.4,103.67 75.87,104.2 54.43,104.2 v3(54.21,104.42) ; v3(53.44,114.25) 53.66,114.47 53.66,120.05 53.37,120.35 52.57,120.35 52.29,120.62 52.29,120.62 49.11,123.8 47.29,123.8 46.43,124.66 46.43,125.76 46.26,125.93 46.26,128.35 46.91,129.01 46.91,131.96 47.91,132.96 47.91,133.85 47.84,133.92 47.84,134.18 48.15,134.49 CPU1.AY4
  BOTTOM w0.114: v3(54.21,104.42) 53.55,105.09 53.55,112.89 53.11,113.33 53.11,113.92 v3(53.44,114.25) ; R63.1 v2(88.46,87.2) 90.45,89.19 90.45,95.7 93.63,98.88 101.5,98.88 v3(103.61,100.99)
AD_JK_S: length 10.9
  TOP w0.635: DCIN1.1 139.55,20.11 ; DCIN1.1 139.55,16.89 ; DCIN1.1 140.67,18.5 ; DCIN1.1 138.43,18.5
  BOTTOM w0.635: 138.43,18.5 DCIN1.1 ; DCIN1.1 139.55,16.89 ; DCIN1.1 139.55,20.11 ; DCIN1.1 140.67,18.5
  vias: v2(128.75,16.23) v2(129.13,20.98) v2(129.62,20.17) v2(131.88,16.51) v2(132.54,20.98) v2(135.03,16.28) v5(131.94,17.91) v5(131.95,18.97) v5(133.02,18.92) v5(133.1,17.78) v5(134.61,18.92) v5(134.61,17.86) v5(135.76,18.92) v5(135.76,17.86)
AD_JK_S_R: length 10
  TOP w0.508: 117.3,13.74 116.33,13.74 116.05,13.47 PR12.1
  BOTTOM w0.508: U48.8 119.76,9.02 120.32,9.58 120.32,11.39 PR3.1 120.82,13.12 121.59,13.89 v1(122.58,13.89)
  vias: v2(120.29,18.34) v2(120.45,15.57) v2(123.29,17.22) v2(123.7,22.56) v2(125.6,21.74) v2(125.55,16.36) v5(123.29,21.21) v5(123.26,19.99) v5(123.29,18.92) v5(124.33,19.99) v5(124.4,21.21) v5(124.37,18.93)
ADP_OCP: length 6.8
  BOTTOM w0.114: v2(119.04,11.96) PR11.1 119.04,10.33 118.75,10.03 117.35,10.03 116.97,9.65 116.97,8.15 117.37,7.75 U48.7
ADU_LDO_CAP: length 3.6
  TOP w0.203: AUDIO1.28 118.98,35.51
  TOP w0.254: 118.98,35.51 118.98,36.05 119.13,36.2 v2(119.13,36.22) 119.13,36.67 C185.1
AMPGND: length 22.1
  TOP w0.508: SPK1.6 113.2,6.27 112.21,7.26 v1(110.85,7.26) ; SPK1.5 118.8,10.16 117.88,11.07 v1(117.88,11.76)
  BOTTOM w0.508: v1(117.88,11.76) 117.88,11.83 117.14,12.57 112.68,12.57 111.51,11.4 111.51,11 110.49,9.98 v2(110.49,8.71) 110.49,7.62 v1(110.85,7.26)
APU_ALERT#: length 20.9
  TOP w0.102: 56.26,157.26 56.1,157.1 56.1,156.17 56.15,156.12 56.15,155.78 55.85,155.48 CPU1.B18
  TOP w0.254: R40.2 v2(44.81,166.45) 45.04,166.22 50.84,166.22 52.66,164.4 52.66,163.42 54.36,161.72 54.36,160.53 56.26,158.62 56.26,157.26
APU_BLEN_SMI: length 40.9
  TOP w0.114: CPU1.AP17 55.7,138.2 56.06,138.56 56.56,138.56 56.77,138.35 57.15,138.35 57.35,138.56 60.07,138.56 v3(60.25,138.38)
  BOTTOM w0.114: Q4803.D 67.31,108.22 R6533.2 67.61,108.52 67.61,111.42 67.2,111.83 67.2,112.4 67.2,116.89 v2(67.02,117.07) 67.02,119.97 65.61,121.39 65.61,129.27 61.32,133.56 61.32,134.42 60.73,135 60.08,135 59.79,135.29 59.79,137.89 60.25,138.35 v3(60.25,138.38)
APU_DBRDY: length 82.9
  TOP w0.114: HDT1.14 89.91,197.27 90.53,197.89 98.68,197.89 100.61,195.96 100.61,194.26 101.78,193.09 101.78,190.33 101.68,190.23 v3(101.68,190.22) ; v3(95.97,189.76) 95.97,186.7 94.46,185.19 87.17,185.19 75.9,173.91 v2(74.8,173.91) 74.24,173.91 68.47,168.15 68.47,164.34 66.99,162.86 65.52,162.86 65.26,163.11 63.34,163.11 62.45,162.22 62.44,162.15 61.74,161.44 61.74,160.71 61.32,160.29 61.32,158.97 60.79,158.44 60.64,158.44 59.39,157.2 59.39,156.17 59.7,155.86 CPU1.B25
  BOTTOM w0.114: v3(101.68,190.22) 101.58,190.13 96.33,190.13 v3(95.97,189.76)
APU_DBREQ: length 9.7
  TOP w0.114: HDT1.16 91.18,196.96 91.7,197.48 97.36,197.48 97.49,197.36 97.75,197.36 v2(97.77,197.33) 98.34,196.77 R486.1
APU_DBREQ#: length 66
  TOP w0.114: v3(99.06,189.69) 99.04,189.71 99.04,193.3 C467.1 99.23,194.87 R491.2 99.23,196.01 R486.2 ; v3(96.8,189.66) 96.8,187.01 94.34,184.56 87.15,184.56 75.18,172.59 v2(73.96,172.59) 73.44,172.59 68.84,167.99 68.84,164.19 67.15,162.49 65.36,162.49 65.11,162.74 63.5,162.74 62.44,161.68 62.43,161.68 61.95,161.2 61.95,160.62 61.53,160.2 61.53,158.88 60.88,158.23 60.73,158.23 59.7,157.2 CPU1.A25
  BOTTOM w0.114: v3(96.8,189.66) 96.88,189.74 99.01,189.74 v3(99.06,189.69)
APU_M_VREF_SUS: length 64.6
  TOP w0.127: 70.1,144.07 69.62,143.58 68.66,143.58 68.58,143.67 68.32,143.67 68,143.35 CPU1.AD40 67.75,144 67.97,144.22 68.23,144.22 68.31,144.13 68.59,144.13 68.92,144.46 70.09,144.46
  TOP w0.381: v1(107.04,166.29) 107.04,154.61 105.26,152.83 92.71,152.83 84.37,144.49 75.43,144.49 75.42,144.5 75.23,144.5 74.24,145.49 70.89,145.49 70.33,144.93 70.33,144.55
  BOTTOM w0.508: v1(107.04,166.29) v2(107.87,167.13) 108.81,167.13 C3.1 108.98,167.31 C2.1 108.98,169.96 R6.1
APU_M_VREFDQ_SUS: length 18.7
  TOP w0.305: v3(103.56,177.52) 102.06,176.03 97.06,176.03 96.68,175.65 DIMM1.1
  BOTTOM w0.508: R139.2 106.89,171.98 R145.1 106.84,172.95 R3.1 105.44,172.95 105.23,172.74 C174.2 C173.1 104.65,174.6 R141.1 104.64,175.56 C160.1 C161.1 104.62,176.52 v2(104.62,177.52) v3(103.56,177.52)
APU_PROCHOT#: length 464.6
  TOP w0.114: v3(90,68.57) v3(90,78.57) 90,85.84 80.48,95.36 75.08,95.36 74.76,95.68 71.84,95.68 70.87,96.65 68.22,96.65 68,96.87 62.92,96.87 v3(62.87,96.81) ; v3(53.42,53.11) 48.52,48.22 48.52,27.81 v3(48.67,27.66) ; PR4428.1 33.51,180.94 34.32,180.13 v3(34.32,179.5) ; R41.2 58.3,166.39 v3(59.11,166.39) 59.11,166.34 59.31,166.13 59.31,161.98 58.8,161.47 58.8,159.07 58.05,158.32 CPU1.A22 ; v3(32.8,169.88) 59.33,169.88 61.21,168 v3(61.21,167.59)
  BOTTOM w0.114: v3(90,78.57) 90.21,78.57 v2(90.87,79.24) 94.23,82.6 99.57,82.6 122.66,105.69 122.66,163.39 105.2,180.85 90.22,180.85 77.03,167.67 61.29,167.67 v3(61.21,167.59) 60.88,167.59 59.69,166.39 v3(59.11,166.39) ; v3(48.67,27.66) 49.52,26.8 55.62,26.8 57.4,25.02 58.05,25.02 59.32,23.75 66.27,23.75 74.51,15.51 74.51,11.39 77.63,8.28 100.23,8.28 103.68,4.82 106.81,4.82 107.65,5.67 112.13,5.67 Q75.D ; v3(62.87,96.81) 62.87,97.1 63.1,97.34 63.1,104.21 63.61,104.72 63.61,105.61 64.71,106.71 64.71,108.6 65.53,109.42 65.53,119.86 63.23,122.15 63.23,125.17 64.31,126.25 R71.1 ; v3(34.32,179.5) 34.32,174.32 32.8,172.81 v3(32.8,169.88) ; v3(90,68.57) 89.84,68.4 85.83,68.4 82.42,65 82.42,61.53 75.26,54.37 71.39,54.37 70.03,53.01 53.52,53.01 v3(53.42,53.11)
APU_PROCHOT#_R: length 15.9
  TOP w0.114: v3(56.95,138.77) 56.97,138.79 57.02,138.79 57.24,139 CPU1.AM21
  BOTTOM w0.114: v3(56.95,138.77) 56.97,138.74 56.97,138.33 57.76,137.54 57.76,137.01 58.07,136.7 58.18,136.7 58.42,136.46 58.42,136.01 58.74,135.69 58.74,135.21 61.19,132.77 61.19,132.7 61.45,132.44 61.45,131.99 61.28,131.83 61.28,131.16 61.19,131.07 61.19,130.28 61.96,129.5 62.84,129.5 63.46,128.88 v2(63.7,128.88) 64.31,128.27 R71.2
APU_PWRGD: length 76.4
  TOP w0.114: R56.1 R22.2 55.27,163.75 R24.1 55.08,162.82 v1(55.4,162.51) 55.4,162.31 54.97,161.87 54.97,160.71 56.76,158.92 56.76,156.61 56.72,156.57 56.72,156.18 56.4,155.86 CPU1.B19 ; v3(71.54,166.46) 71.54,166.72 86.61,181.78 96.44,181.78 102.57,187.91 102.57,193.78 102.51,193.83 102.31,194.03 R481.2
  BOTTOM w0.114: v1(55.4,162.51) 55.4,162.56 v2(55.98,163.14) 58.07,165.23 58.6,165.23 58.96,165.59 60.19,165.59 60.82,166.22 61.72,166.22 61.96,166.46 v3(71.54,166.46)
APU_PWRGD_BUF: length 18.8
  TOP w0.114: R481.1 102.31,196.31 v2(101.52,197.1) 99.92,198.7 88.64,198.7 87.37,197.43 HDT1.10
APU_SIC: length 211.2
  TOP w0.114: CPU1.B22 58.05,155.49 58.36,155.8 58.36,156.1 58.29,156.17 58.29,158.23 59.07,159.01 59.07,161.25 59.68,161.85 59.68,166.86 v3(59.61,166.93) 59.54,167 57.89,167 R43.2
  BOTTOM w0.114: v3(59.61,166.93) 59.61,166.94 59.61,166.95 60.7,168.03 76.88,168.03 90.06,181.22 105.35,181.22 123.02,163.55 123.02,105.54 99.68,82.19 94.72,82.19 v2(89.98,77.46) 87.81,75.28 U31.55 77.29,75.28 76.66,75.91 76.63,75.91 75.67,76.87 U6503.26
APU_SID: length 207.1
  TOP w0.114: CPU1.B21 57.5,155.86 57.81,156.17 57.81,158.6 58.54,159.34 58.54,161.81 58.95,162.21 58.95,165.13 v3(58.39,165.68) 57.55,164.84 R44.2
  BOTTOM w0.114: U6503.25 75.8,77.27 76.78,76.28 U31.53 86.93,76.28 88.54,77.9 88.67,77.9 v2(91.8,81.03) 93.85,83.08 99.38,83.08 122.17,105.87 122.17,163.25 105.1,180.32 90.21,180.32 77.19,167.3 61.56,167.3 61.37,167.11 60.99,167.11 59.83,165.95 58.67,165.95 v3(58.39,165.68)
APU_SVC: length 7.7
  TOP w0.114: v3(61.39,154.56) 61.32,154.56 60.96,154.2 CPU1.D27
  BOTTOM w0.114: v3(61.39,154.56) 61.39,154.94 62.89,156.43 62.89,157.68 63.4,158.19 v2(63.4,158.55) 63.4,159.09 R47.1 R54.1
APU_SVD: length 5.8
  TOP w0.114: CPU1.E29 61.73,153.4 61.33,153.8 v3(61.33,153.85)
  BOTTOM w0.114: R48.1 63.5,156.53 R55.1 63.49,155.8 v2(63.27,155.57) 63.11,155.41 62.37,155.41 61.82,154.86 61.82,154.34 v3(61.33,153.85)
APU_SVT: length 11.8
  TOP w0.114: v3(62.42,153.09) 62.99,152.52 63.08,152.52 CPU1.G31
  BOTTOM w0.114: v3(62.42,153.09) 62.04,153.48 62.04,154.72 62.31,154.99 63.53,154.99 64.36,155.83 64.79,155.83 66.63,157.67 v2(66.63,157.97) 67.49,158.83 R46.1 68.22,159.89 R53.1
APU_TCK: length 52.2
  TOP w0.114: HDT1.2 81.58,194.83 81.58,191.05 v3(80.98,190.45) 80.98,189.61 77.99,186.63 77.99,178.8 67.54,168.36 67.54,164.77 v3(67.91,164.4) ; v3(65.69,154.72) 65.2,154.23 CPU1.D35
  BOTTOM w0.114: v3(67.91,164.4) v2(68.68,163.63) 69.46,162.85 69.46,158.49 v3(65.69,154.72) ; RN7.2 81.73,191.79 81.53,191.59 81.53,191.01 v3(80.98,190.45)
APU_TDI: length 61.8
  TOP w0.114: HDT1.6 84.83,196.71 84.04,197.5 81.61,197.5 80.75,196.64 v3(80.75,192.2) 80.14,191.59 80.14,189.94 77.06,186.87 77.06,178.95 68.58,170.46 67.08,170.46 v2(66.93,170.31) 66.65,170.03 66.65,164.74 66.85,164.54 v3(66.85,164.39) ; CPU1.D29 62.17,154.2 v3(62.49,153.88)
  BOTTOM w0.114: v3(62.49,153.88) 62.89,153.88 64.53,155.51 64.97,155.51 68.66,159.2 68.66,161.51 66.97,163.21 66.97,163.45 66.84,163.58 66.84,164.37 v3(66.85,164.39) ; RN7.4 81.48,192.94 v3(80.75,192.2)
APU_TDO: length 62.1
  TOP w0.114: HDT1.8 86.1,196.74 84.97,197.87 81.46,197.87 80.31,196.73 80.31,192.51 79.73,191.92 79.73,190.42 76.64,187.33 76.64,179.15 69.06,171.58 v2(67.94,171.58) 67.23,171.58 66.28,170.62 66.28,164.34 66.86,163.76 v3(67.27,163.76) ; v3(63.48,153.83) 63.11,154.2 CPU1.D31
  BOTTOM w0.114: v3(67.27,163.76) 67.34,163.7 67.34,163.42 68.88,161.88 68.88,159.11 64.94,155.17 64.6,155.17 64.22,154.79 64.22,154.58 v3(63.48,153.83)
APU_TEST0: length 8.2
  TOP w0.114: v3(52.45,136.98) 52.83,136.6 CPU1.AU13
  BOTTOM w0.114: v3(52.45,136.98) 52.45,134.74 52,134.29 TP20.1 51.58,133.51 51.58,131.66 R93.1 52.03,130.31 R88.2
APU_TEST1: length 9.6
  TOP w0.114: v3(51.56,135.44) 51.55,135.43 51.55,135.37 51.45,135.26 CPU1.AY10
  BOTTOM w0.114: R89.2 47.39,128.4 R94.1 48.59,129.42 49.96,130.78 49.96,131.8 50.39,132.23 TP19.1 50.39,133.89 51.56,135.06 v3(51.56,135.44)
APU_TEST2: length 8.2
  TOP w0.114: R95.1 R90.2 49.66,128.79 TP21.1 48.68,132.09 48.87,132.28 48.87,133.3 49.01,133.44 49.01,133.85 48.94,133.92 48.94,134.18 49.25,134.49 CPU1.AY6
APU_TEST4_THERMDA: length 1.5
  TOP w0.114: v3(61.34,151.42) 61.33,151.42 60.95,151.8 CPU1.H27
  BOTTOM w0.114: v3(61.34,151.42) 61.7,151.77 TP5.1
APU_TEST5_THERMDC: length 1.7
  TOP w0.114: CPU1.H29 62.05,151.8 v3(62.4,152.15)
  BOTTOM w0.114: TP6.1 62.55,152.15 v3(62.4,152.15)
APU_TEST6_DIRECRACKMON: length 2.8
  TOP w0.114: v3(60.35,153.81) 59.96,154.2 CPU1.D25
  BOTTOM w0.114: v3(60.35,153.81) 60.35,153.92 59.85,154.43 59.85,154.89 60.3,155.35 TP7.1
APU_TEST14_BP0: length 7.9
  TOP w0.114: v2(65.77,161.86) 65.27,161.35 R21.1 64.77,160.63 61.34,157.2 61.34,157.06 60.88,156.6 60.88,156.38 CPU1.A27
APU_TEST15_BP1: length 2.8
  TOP w0.114: CPU1.B27 60.8,155.86 60.49,156.17 60.49,156.8 v3(60.93,157.23)
  BOTTOM w0.114: v3(60.93,157.23) 61.06,157.1 TP8.1
APU_TEST16_BP2: length 7.2
  TOP w0.114: CPU1.A26 60.25,157.14 60.91,157.8 61.52,157.8 63.75,160.03 v2(63.75,160.41) 63.75,160.41 R23.1
APU_TEST17_BP3: length 6.7
  TOP w0.114: R25.1 62.7,159.34 v7(62.03,158.67) 61.37,158.01 60.82,158.01 60.01,157.21 60.01,156.15 59.94,156.08 59.94,155.82 60.25,155.51 CPU1.B26
APU_TEST28_PLLCHARZ_H: length 1.5
  TOP w0.114: v3(65.68,135.47) 65.34,135.8 CPU1.AV35
  BOTTOM w0.114: TP9.1 65.64,135.42 v3(65.68,135.47)
APU_TEST28_PLLCHARZ_L: length 2.7
  TOP w0.114: CPU1.AU35 65.6,136.2 65.62,136.2 v3(65.64,136.18)
  BOTTOM w0.114: v3(65.64,136.18) 65.66,136.15 65.66,136.13 66.31,135.48 66.31,135.12 TP10.1
APU_TEST31_M_TEST: length 2.9
  TOP w0.114: CPU1.E33 64.74,152.76 64.74,152.55 65.12,152.17 v3(65.35,152.17)
  BOTTOM w0.114: TP11.1 64.7,152.73 65.26,152.17 v3(65.35,152.17)
APU_TEST36_FREE_2: length 7.5
  TOP w0.114: v3(56.95,152.37) 57.5,151.82 CPU1.H21
  BOTTOM w0.114: R31.1 R30.1 57.28,156.82 v2(57.61,156.49) 57.65,156.44 57.65,154.32 57.5,154.17 57.5,153 56.95,152.44 v3(56.95,152.37)
APU_TEST37_FREE_2: length 9.6
  TOP w0.114: v3(60.22,152.31) 60.21,152.31 CPU1.H25
  BOTTOM w0.114: R33.1 62.71,158.43 R32.1 62.31,157.35 v2(62.31,156.71) 62.31,156.49 60.78,154.96 60.78,152.87 v3(60.22,152.31)
APU_TMS: length 57.9
  TOP w0.114: v3(64.63,153.96) 64.6,153.96 64.58,153.98 64.46,153.98 64.25,154.2 CPU1.D33 ; v3(67.09,165.09) 67.09,168.84 v2(67.36,169.11) 68.02,169.77 68.41,169.77 77.62,178.98 77.62,186.79 80.52,189.69 80.52,191.19 v3(80.7,191.36) 81.21,191.87 81.21,196.48 81.84,197.12 83.3,197.12 83.56,196.86 HDT1.4
  BOTTOM w0.114: v3(80.7,191.36) 81.62,192.29 RN7.3 ; v3(67.09,165.09) 67.31,164.87 67.31,164.38 67.72,163.97 67.72,163.7 69.09,162.33 69.09,158.76 65.27,154.93 65.27,154.6 v3(64.63,153.96)
APU_TRST: length 53.8
  TOP w0.114: CPU1.G27 60.8,152.31 60.4,151.91 60.4,151.43 v3(60.35,151.38) ; v3(80.77,188.72) 78.36,186.31 78.36,181.35 78.38,181.33 78.38,181.21 78.48,181.1 78.6,181.1 R480.1 78.46,180.49 78.46,178.71 67.98,168.24 v3(67.98,165.11)
  BOTTOM w0.114: v3(60.35,151.38) 60.4,151.43 60.4,151.46 61.51,152.57 62.48,152.57 63.29,153.37 64.93,153.37 69.83,158.28 69.83,163.26 v3(67.98,165.11) ; v3(80.77,188.72) 80.77,189.21 v2(81.1,189.54) 82.24,190.68 RN7.1
APU_VDD18_ALW:
  vias: v2(38.61,157.68)
APU_VDD33_ALW: length 10.4
  TOP w0.356: CPU1.AM13 53.34,139 v3(53.65,139.3)
  TOP w0.381: v3(53.65,139.3) 53.65,139.33 53.5,139.48 CPU1.AL13
  BOTTOM w0.305: v3(53.65,139.3) 53.65,138.65 53.7,138.6 v6(53.7,138.56) 54.15,138.1 54.15,137.4 54.14,137.39 54.14,136.69 54.52,136.32 54.52,135.62 54.47,135.58 54.47,135.24 53.8,134.57 C118.1 53.9,134.16 54.41,133.65 54.41,132.1 R113.2
APU_VDD_0.95: length 30.5
  TOP w0.356: v3(59,139.5) CPU1.AL23
  TOP w0.381: v3(59.82,141.51) 60.31,142 CPU1.AG27 ; C132.1 54.86,123.48 v3(55.37,122.97)
  TOP w0.508: v3(48.11,114.27) 47.05,113.22 C6534.1 ; C133.1 34.53,112.67 34.52,112.67 v3(34.52,112.7)
  TOP w0.635: 40.54,123.57 40.54,126.59 37.42,129.72 37.42,129.73 37.09,130.06 37.09,133.97 33.29,137.77 33.29,139.79 v2(32.35,140.74) 31.42,141.67 v5(31.42,144.7)
  vias: v2(41.33,119.79) v3(58.02,140.42) v3(58.18,139.51) v3(59.82,140.52) v3(59.91,139.56) v5(43.26,119.46) v5(43.28,118.41) v5(43.92,117.68) v5(44.12,119) v5(44.81,118.34)
APU_VDD_18: length 160.8
  TOP w0.254: v3(63.04,164.16) 62.53,163.65 R29.2
  TOP w0.305: v1(46.79,167.64) 46.91,167.51 54.32,167.51 54.99,166.84 54.99,166.83 R52.1 55.21,165.59 R22.1 55.5,165.3 55.52,165.3 55.86,164.96 55.86,163.29 56.44,162.71 R19.1 55.8,161.77 v1(55.58,161.77) ; v3(65.91,163.3) 65.28,163.93 63.3,163.93 63.07,164.16 v3(63.04,164.16) ; v1(62.29,165.18) 62.29,164.09 62.11,163.91 R29.2
  TOP w0.508: v3(104.67,189.03) 104.67,194.79 105.97,196.09 Q43.S ; R489.2 105.19,197.17 Q43.S ; v3(34.44,173.38) 36.1,175.04 PR4429.1 ; R490.1 107.4,196.49 106.07,196.49 Q43.S ; v3(36.07,165.99) 36.07,161.54 37.05,160.56 C58.1
  BOTTOM w0.254: R50.1 63.88,160.46 R47.2 63.78,160.41 63.05,160.41 R33.2 62.71,163.79 63.02,164.09 63.02,164.13 v3(63.04,164.16) ; R48.2 64.54,157.44 64.88,157.44 R46.2 66.6,159.19 67.2,159.78 R51.1 67.2,160.39 66.32,161.27 R49.1 66.32,162.18 65.91,162.59 v3(65.91,163.3)
  BOTTOM w0.305: R30.2 55.75,158.24 55.75,159.32 55.12,159.95 55.12,161.31 v1(55.58,161.77) 55.79,161.56 R39.2 56.5,161.73 59.4,164.63 60.59,164.63 61.14,165.18 v1(62.29,165.18)
  BOTTOM w0.508: 46.77,156.9 C59.1 ; 46.77,156.9 v1(46.77,156.91) ; 46.77,156.9 46.77,158.14 C120.1 ; v3(34.44,173.38) 33.5,172.44 33.5,168.55 v3(36.07,165.99) ; v1(40.74,159.87) 43.21,162.33 43.21,164.06 v1(46.79,167.64) 46.83,167.64 55.33,176.14 70.81,176.14 72.34,177.67 72.34,179.82 75.02,182.5 79.38,182.5 85.9,189.03 v2(98.45,189.03) v3(104.67,189.03)
  vias: v2(39.57,159.31) v4(44.93,159.89) v5(37.53,159.48) v5(38.46,159.46)
APU_VDD_33: length 210.8
  TOP w0.305: RN1.4 25.18,102.4 25.55,102.77 25.57,102.77 25.82,103.02 ; 25.82,103.02 v3(25.82,104.05) ; 25.82,103.02 25.82,102.05 RN1.3
  TOP w0.356: CPU1.AM15 54.74,138.46 54.74,138.37 v3(54.75,138.35) 54.75,138.35 55.3,138.9 CPU1.AM17
  TOP w0.508: v1(45.47,156.64) 43.74,158.37 42.42,158.37 v1(42.01,158.78) 41.76,158.52 32.7,158.52 24.62,150.44 22.95,150.44 19.41,146.9 19.41,139.41 19.05,139.05 19.05,138.99 18.75,138.68 v3(18.75,138.46) ; R40.1 43.89,168.3 v3(49.48,168.3) 55.02,168.3 v2(55.27,168.05) R43.1 R41.1 R44.1 ; v1(62.25,117.54) 62.25,116.24 R112.2 ; v3(63.42,107.29) 57.61,107.29 56.29,105.96 56.26,105.96 56.25,105.96 39.26,105.96 37.6,104.3 31.17,104.3 v3(30.96,104.09)
  BOTTOM w0.305: C121.1 56.17,129.65 55.14,130.68 55.14,134.7 55.33,134.89 55.33,136.02 55.32,136.04 55.32,136.46 55.37,136.51 55.37,137.21 55.24,137.34 55.24,137.86 55.19,137.9 54.75,138.35 v3(54.75,138.35)
  BOTTOM w0.508: v1(45.47,156.64) 46.34,155.77 R45.1 ; v1(42.01,158.78) 42.11,158.78 v2(43.19,159.85) 44.7,161.37 44.7,163.49 49.48,168.26 v3(49.48,168.3) ; v3(30.96,104.09) 30.71,103.84 30.71,102.57 30.48,102.34 29.87,102.34 29.84,102.36 29.27,102.36 28.75,102.88 28.75,103.45 28.16,104.05 v3(25.82,104.05) 25.82,107.75 20.03,113.54 15.04,113.54 12.56,116.02 12.56,119.32 11.21,120.67 11.21,136.38 13.63,138.8 v2(15.11,138.8) 15.41,138.51 18.69,138.51 v3(18.75,138.46) ; C112.1 C111.1 54.62,138.49 v3(54.75,138.35) ; v3(63.42,107.29) 63.42,115.49 62.25,116.67 v1(62.25,117.54) 62.25,118.47 59.44,121.29 59.44,122.76 55.92,126.27 55.92,127.87 C113.1 C121.1
APU_VDDIO_AZ: length 23.9
  TOP w0.254: CPU1.AL10 51.72,139.72 51.72,139.84 51.93,140.05 v3(51.93,140.09) 51.95,140.09 52.04,139.99 52.49,139.99 CPU1.AL11
  BOTTOM w0.254: R111.2 53.06,121.21 51.69,122.58 v6(51.69,122.86) 51.69,123.22 52.48,124 C106.1 52.48,124.82 52.7,125.04 52.7,126.04 C109.1 52.43,127.22 C110.1 C107.1 52.74,128.48 52.74,136.59 52.93,136.78 52.93,138.56 53.11,138.73 53.11,139.61 53.09,139.63 53.09,139.67 C108.1 52.59,139.99 51.98,139.38 C117.1 51.81,139.97 v3(51.93,140.09)
APU_VRM_PWRGD: length 6.5
  TOP w0.114: PU4401.20 37.07,191.18 v3(37.58,191.69)
  BOTTOM w0.114: RN18.3 33.29,190.74 34.47,191.92 35.15,191.92 PC4429.1 35.2,191.96 v2(36.22,191.96) 36.64,191.96 36.91,191.69 v3(37.58,191.69)
AUD_CBN: length 5.2
  TOP w0.203: AUDIO1.35 116.18,35.39 115.77,35.8 115.77,37.08 v2(115.82,37.13) 115.82,37.5 114.94,38.39 C194.1
AUD_CBP: length 5.6
  TOP w0.203: C194.2 v2(114.5,37.9) 114.53,37.87 114.53,37.46 115.32,36.67 115.32,35.61 115.78,35.15 AUDIO1.36
AUD_CPVEE: length 3.9
  TOP w0.114: C186.2 116.41,38.12 v2(116.41,36.03) 116.58,35.86 AUDIO1.34
AUD_LINK_RST_N1: length 7.9
  TOP w0.114: R177.1 122.33,26.2 v1(122.33,25.88)
  BOTTOM w0.114: v1(122.33,25.88) 122.19,26.02 120.11,26.02 v2(119.24,25.15) 119.07,24.98 119.07,22.69 119.43,22.33 119.76,22.33
AUD_PVDD_1: length 3.3
  TOP w0.203: AUDIO1.39 114.2,32.74 113.67,33.27 ; AUDIO1.46 114.45,29.94 113.51,29.01
  vias: v2(112.19,33.73)
AUD_VREF: length 5.1
  TOP w0.203: AUDIO1.27 119.38,35.31
  TOP w0.305: C187.1 121.53,37.4 C188.1 121.51,37.19 v2(120.4,36.07) 120.14,36.07 119.38,35.31
AZ_BCLK: length 177.5
  TOP w0.114: RN2.4 40.85,130.28 43.27,127.86 43.27,126.55 43.35,126.47 43.35,124.01 47.52,119.84 49.34,119.84 50.96,118.21 v3(50.96,112.78) ; AUDIO1.6 117.78,27.61 117.7,27.52 v3(117.7,26.08) 117.7,25.46 EC701.1 116.92,24.68 116.92,24.18 116.54,23.81 116.54,23.79 114.69,21.94 107.09,21.94 101.52,27.51 101.52,43.34 98.93,45.93 94.19,45.93 90.53,49.59 90.53,65.81 92.45,67.73 92.45,86.66 80.91,98.2 74.13,98.2 73.9,98.42 69.49,98.42 68.92,98.99 49.97,98.99 49.71,99.26 v3(49.67,99.26)
  BOTTOM w0.114: R6552.1 117.74,26.04 v3(117.7,26.08) ; v3(49.67,99.26) 50.22,99.8 v2(50.41,99.8) 50.96,100.36 v3(50.96,112.78)
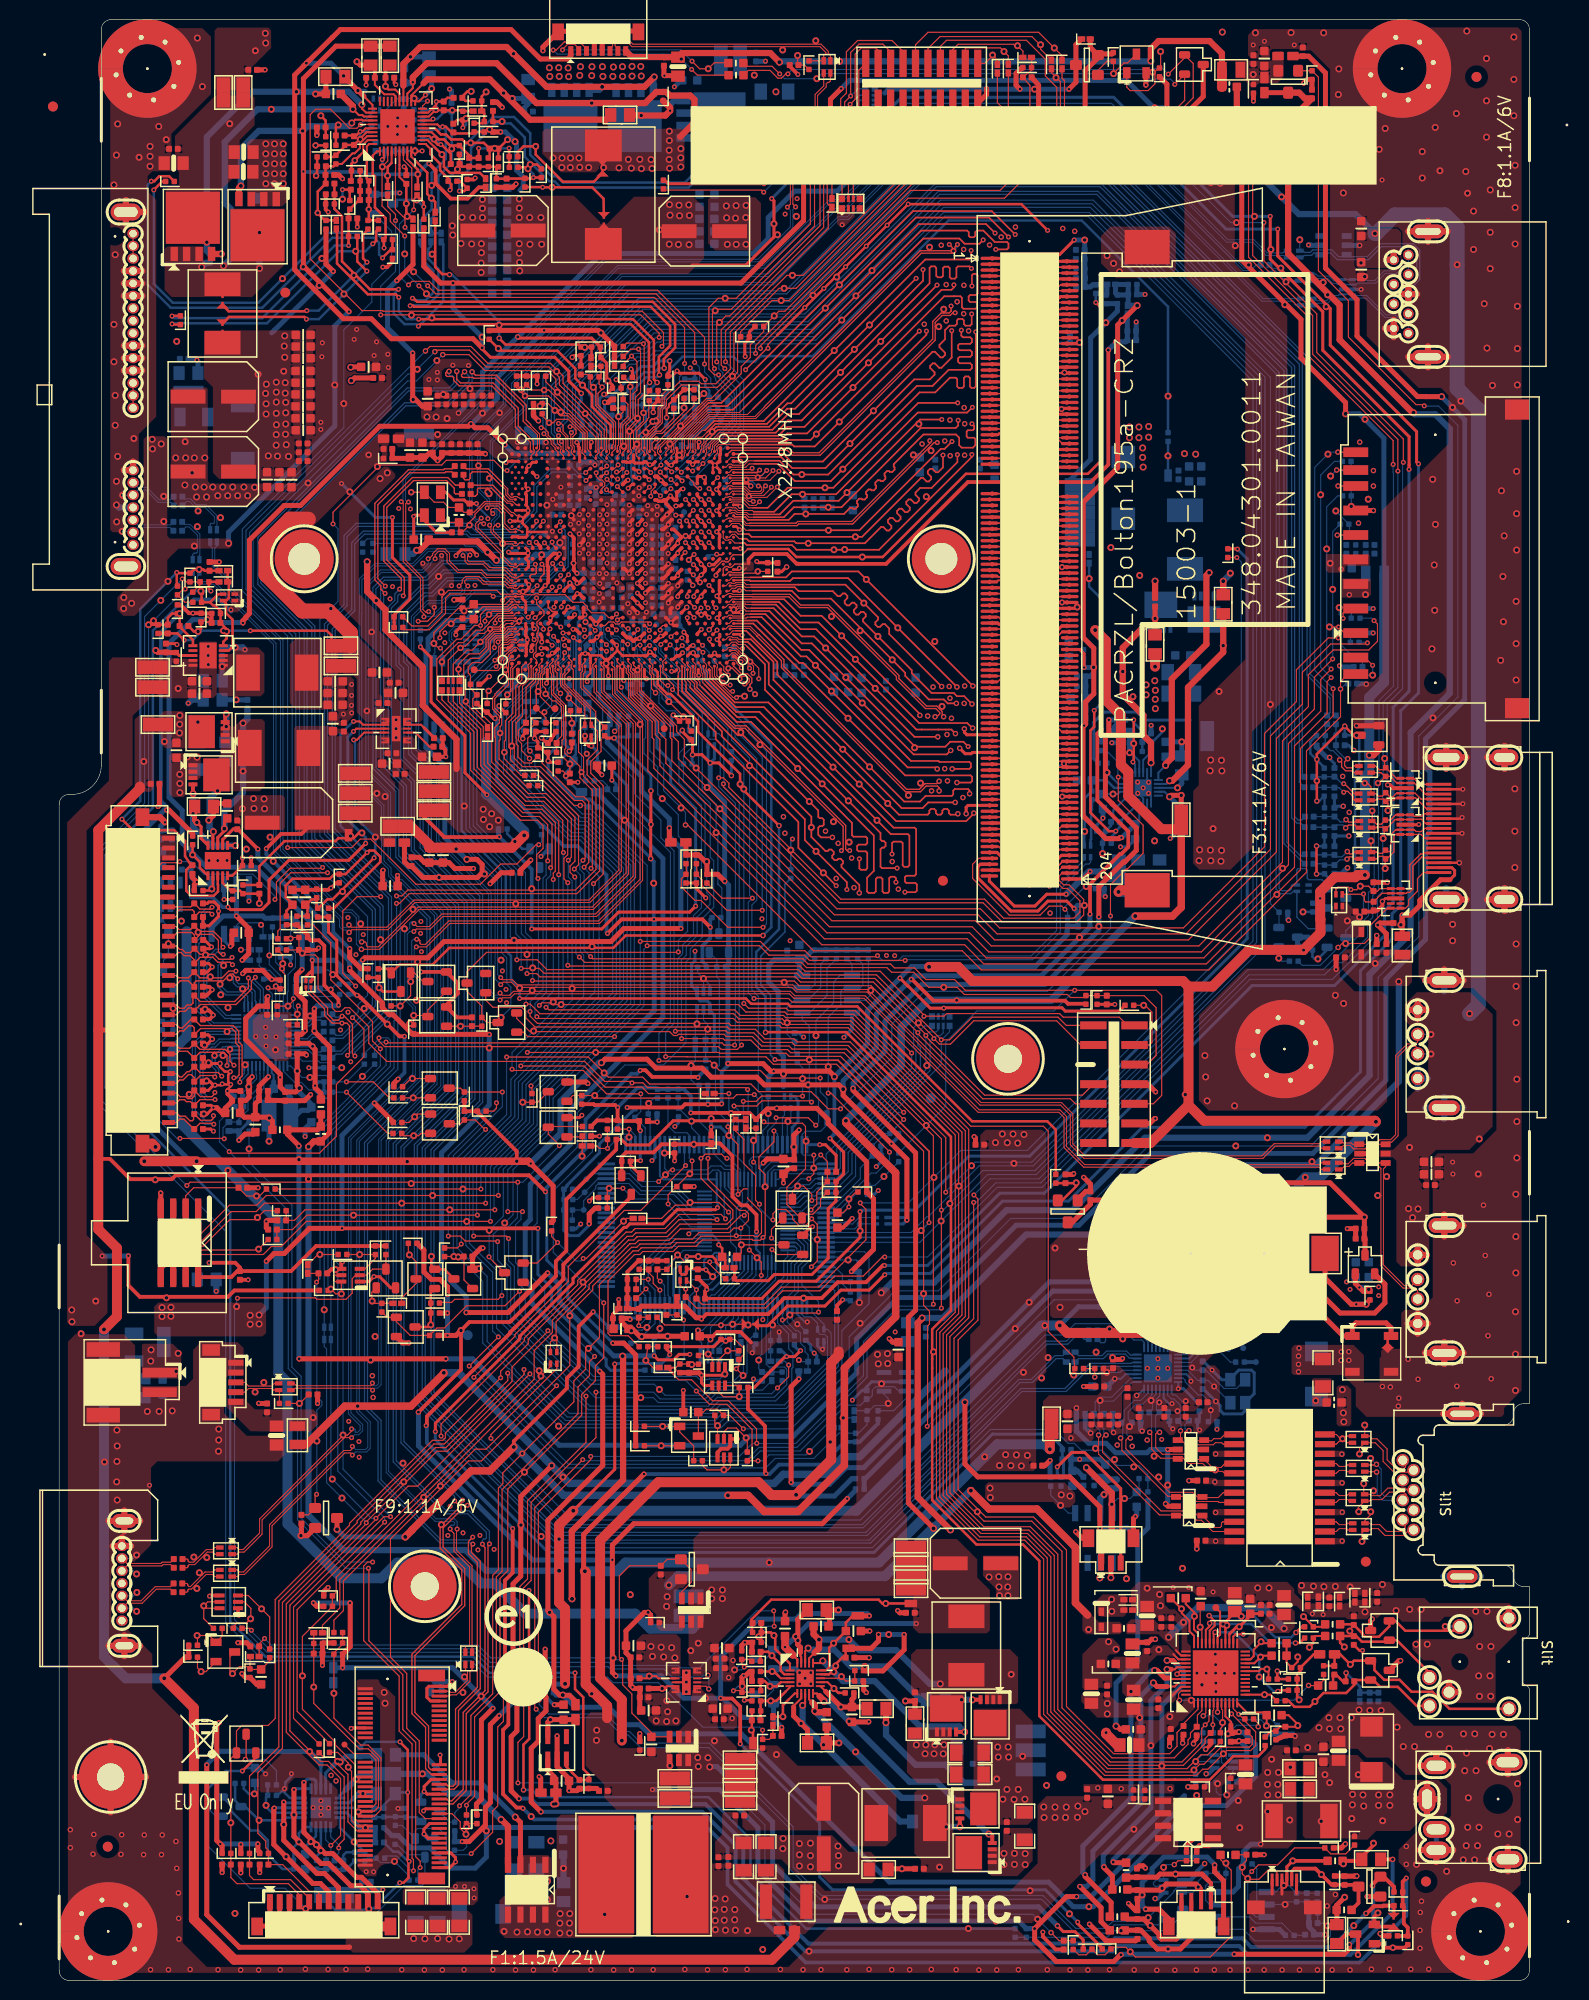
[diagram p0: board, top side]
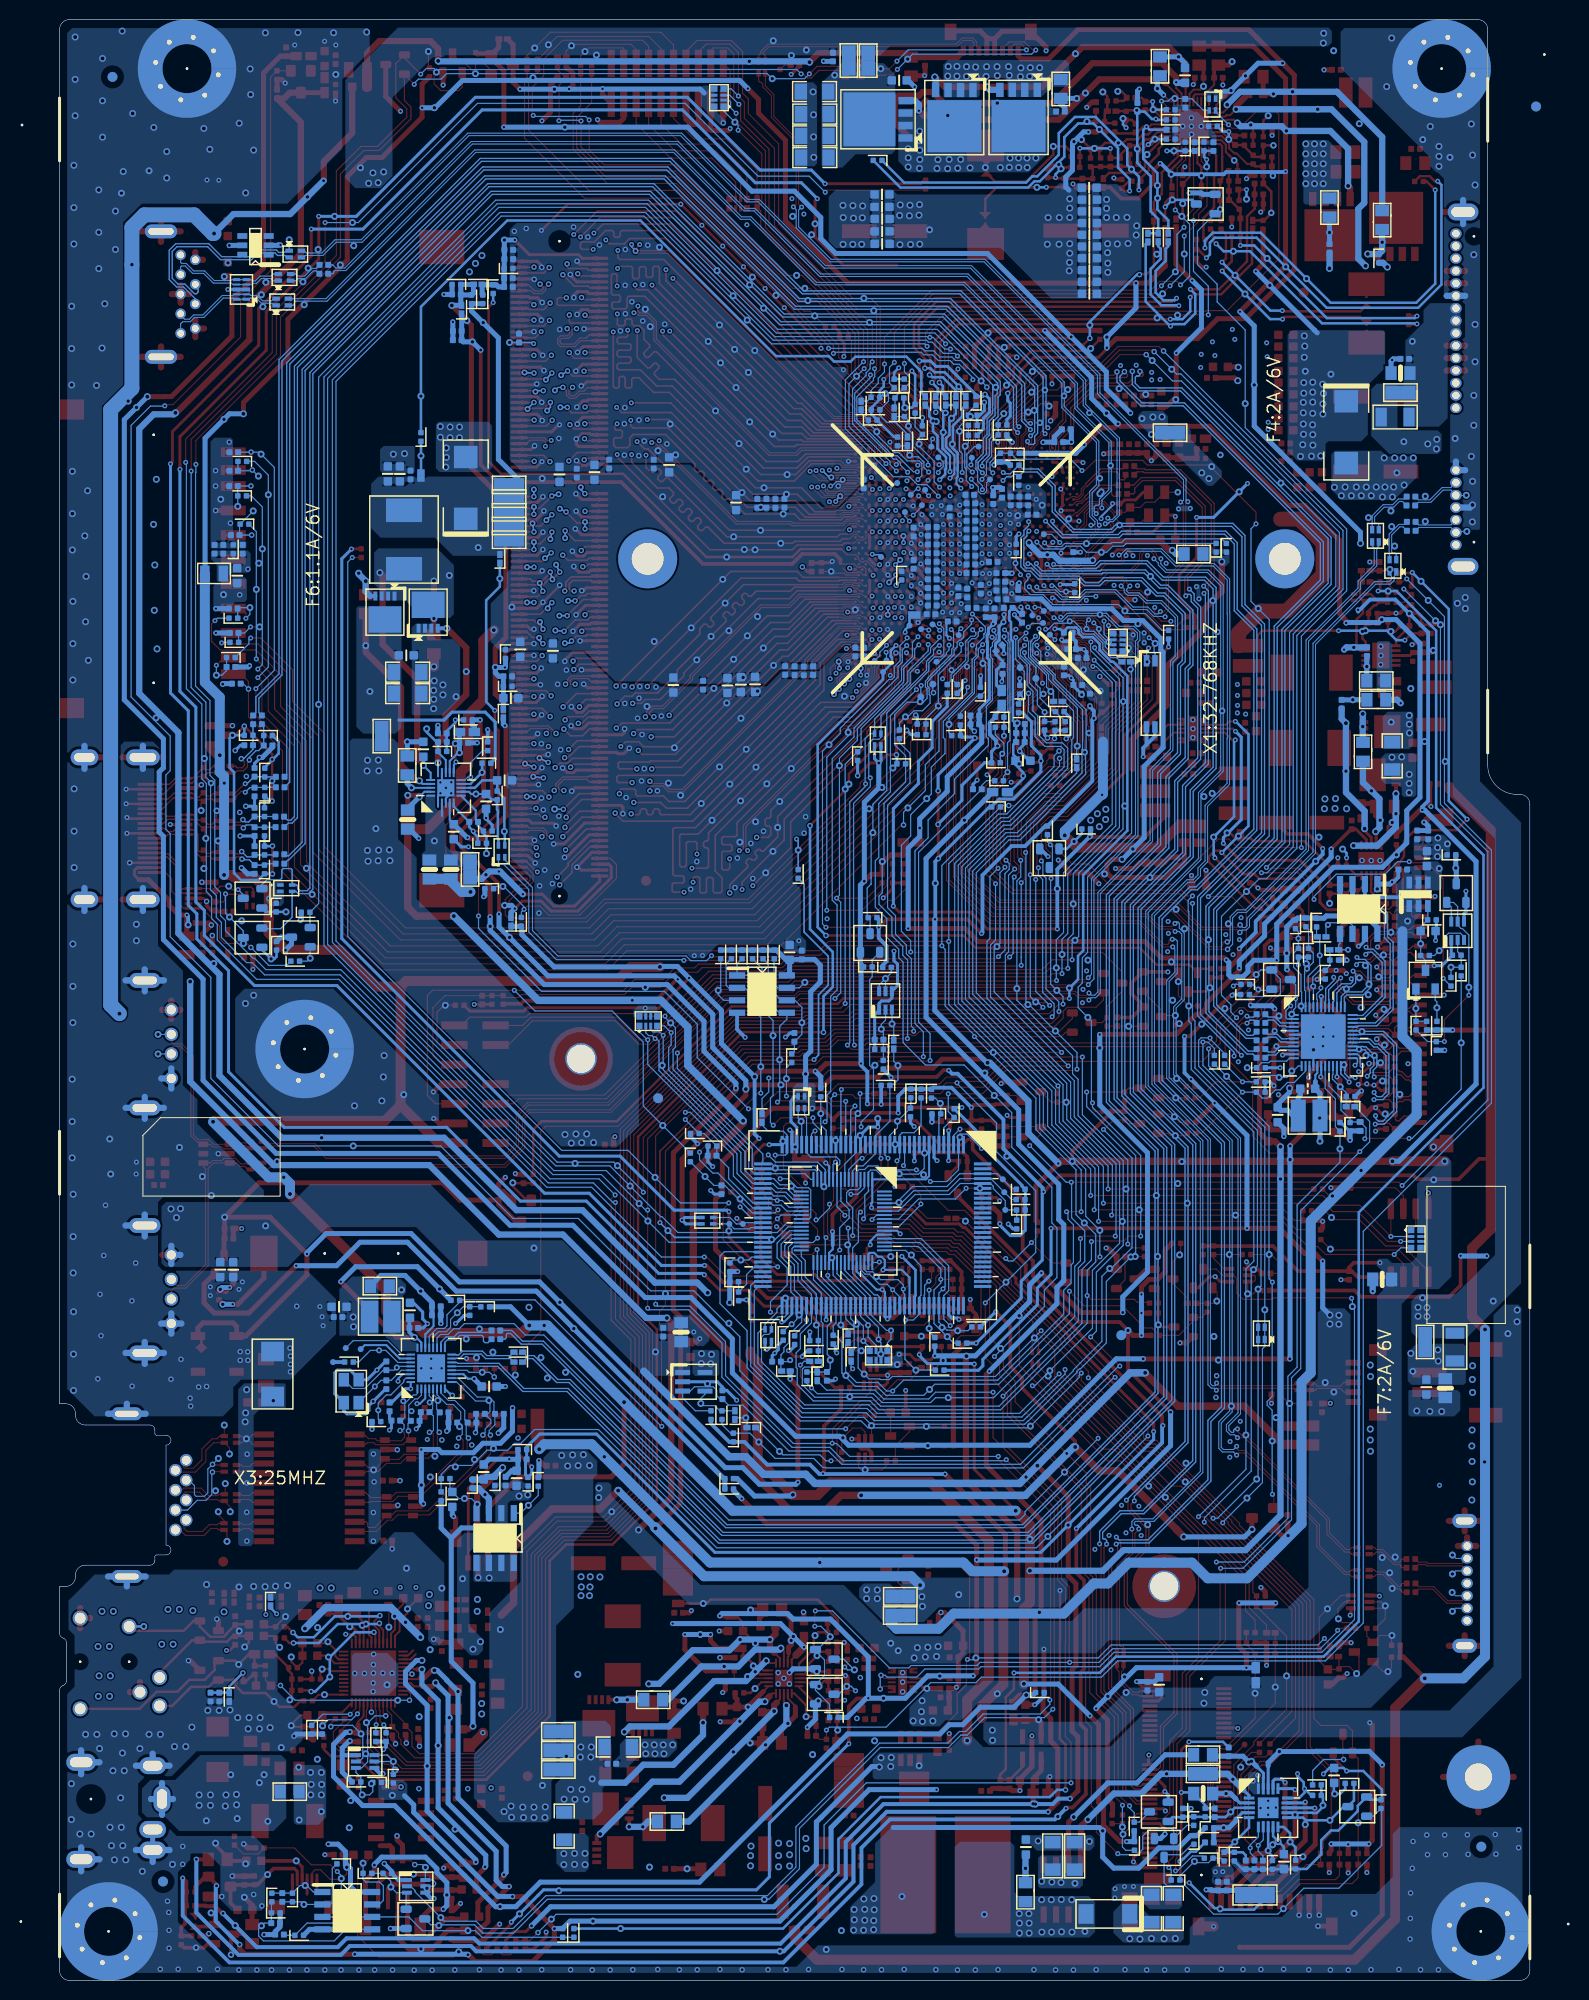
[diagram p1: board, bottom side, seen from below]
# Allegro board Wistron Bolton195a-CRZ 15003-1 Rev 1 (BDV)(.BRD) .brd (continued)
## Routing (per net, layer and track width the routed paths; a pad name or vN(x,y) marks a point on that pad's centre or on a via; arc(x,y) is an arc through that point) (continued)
AZ_BCLK_M: length 10.1
  TOP w0.114: RN2.5 40.85,133.14 40.74,133.25 v4(40.74,133.73) 40.74,134.24 41.81,135.31 42.88,135.31 43.54,135.97 43.54,136.79 44.36,137.6 45.25,137.6 45.73,138.09 46.33,138.09 46.64,138.4 CPU1.AN2
AZ_RST_N: length 190.4
  TOP w0.114: RN2.1 39.05,130.63 42.32,127.35 42.32,123.57 47.17,118.72 49,118.72 49.84,117.88 v3(49.84,114.19) ; v3(48.04,98.83) 48.04,98.37 48.79,97.62 68.32,97.62 68.55,97.38 73.48,97.38 73.7,97.17 80.49,97.17 91.42,86.23 91.42,68.16 89.5,66.24 89.5,49.17 93.77,44.9 98.51,44.9 100.44,42.97 100.44,27.14 106.67,20.91 116.03,20.91 116.66,21.54 117.2,21.54 v2(118.77,23.11) 119.1,23.44 121.56,23.44 122.07,23.95 122.07,25.36 120.97,26.45 R177.2 120.82,26.67 v3(120.35,27.15) 120.35,27.15 119.78,27.71 AUDIO1.11
  BOTTOM w0.114: R6555.1 123.15,27.15 v3(120.35,27.15) ; v3(49.84,114.19) 49.68,114.03 49.68,112.75 49.36,112.43 49.36,101.13 48.06,99.83 48.06,98.85 v3(48.04,98.83)
AZ_RST_N_M: length 11.4
  TOP w0.114: RN2.8 v4(39.05,134.49) 39.05,134.78 40.72,136.45 41.25,136.45 42.52,137.72 43.17,137.72 43.86,138.41 43.86,138.52 44.77,139.43 46.01,139.43 46.08,139.5 CPU1.AL1
AZ_SDIN0: length 192.5
  TOP w0.114: CPU1.AK2 46.99,140.05 46.68,140.36 46.42,140.36 46.33,140.27 46.22,140.27 45.82,139.86 43.54,139.86 42.99,139.3 v3(42.99,138.2) 42.39,138.2 41,136.81 40.57,136.81 38.53,134.77 38.53,130.66 41.98,127.21 41.98,123.43 47.07,118.34 48.79,118.34 49.36,117.77 49.36,115.46 48.72,114.82 48.72,112.52 v3(48.84,112.39) ; R174.1 118.47,24.31 117.17,23.01 116.48,23.01 115.07,21.6 106.95,21.6 101.17,27.38 101.17,43.21 98.79,45.59 94.05,45.59 90.19,49.45 90.19,65.95 92.11,67.87 92.11,86.52 80.77,97.85 73.98,97.85 73.77,98.07 69.34,98.07 68.81,98.6 49.04,98.6 48.07,99.58 v3(47.62,99.58)
  BOTTOM w0.114: RN4.5 42.71,137.38 42.99,137.66 v3(42.99,138.2) ; v3(47.62,99.58) 47.62,100.35 v2(48.26,100.99) 48.89,101.62 48.89,112.35 v3(48.84,112.39)
AZ_SDIN0_R: length 3.2
  TOP w0.114: R174.2 118.47,25.68 118.69,25.91 118.69,26.3 v2(118.69,26.3) 118.69,26.3 118.69,27.57 118.58,27.69 AUDIO1.8
AZ_SDIN1: length 6.4
  TOP w0.114: v3(43.44,138.65) 43.44,138.9 v4(43.86,139.32) 44.18,139.64 45.91,139.64 46.31,140.05 CPU1.AK1
  BOTTOM w0.114: RN4.6 42.89,136.73 43.44,137.28 v3(43.44,138.65)
AZ_SDIN2: length 6.6
  TOP w0.114: v3(45.01,138.78) 45.18,138.95 CPU1.AM1
  BOTTOM w0.114: RN4.8 42.86,135.58 43.33,136.04 43.33,136.47 44.47,137.62 45.01,137.62 v6(45.24,137.85) 45.24,138.55 v3(45.01,138.78)
AZ_SDIN3: length 6.3
  TOP w0.114: v3(44.48,138.46) 44.48,138.84 44.84,139.19 46.33,139.19 46.64,139.5 CPU1.AL2
  BOTTOM w0.114: v3(44.48,138.46) 43.97,137.94 v6(43.97,137.85) 43.97,137.42 43.02,136.47 43.02,136.36 42.89,136.23 RN4.7
AZ_SDOUT: length 177.7
  TOP w0.114: v3(48.99,99.45) 49.25,99.71 50.06,99.71 50.24,99.53 v2(51.21,99.53) 69.3,99.53 70.05,98.78 74.03,98.78 74.27,98.54 81.05,98.54 92.79,86.8 92.79,67.59 90.87,65.67 90.87,49.73 94.34,46.27 99.08,46.27 101.88,43.47 101.88,27.64 107.23,22.28 114.55,22.28 116.2,23.94 116.2,23.98 116.56,24.33 116.56,25.7 116.92,26.06 v3(116.92,26.07) 116.92,26.07 117.31,26.45 117.31,27.53 117.38,27.61 AUDIO1.5 ; v3(50.41,112.29) 50.41,112.94 50.62,113.16 50.62,118.07 49.24,119.46 47.42,119.46 43.01,123.87 43.01,127.64 40.2,130.45 RN2.3
  BOTTOM w0.114: R6553.1 116.69,25.83 v3(116.92,26.07) ; v3(48.99,99.45) 48.99,99.46 50.41,100.88 v3(50.41,112.29)
AZ_SDOUT_M: length 9.4
  TOP w0.114: RN2.6 40.2,134.25 41.63,135.69 42.14,135.69 v4(42.98,136.53) 44.27,137.82 45.03,137.82 45.62,138.4 CPU1.AN1
AZ_SYNC: length 188.6
  TOP w0.114: RN2.2 39.7,130.46 42.67,127.49 42.67,123.73 47.29,119.1 49.11,119.1 50.28,117.93 50.28,113.63 v3(50.14,113.49) ; v3(48.73,98.29) 48.91,98.12 68.79,98.12 69.18,97.73 73.63,97.73 73.84,97.51 80.63,97.51 91.76,86.37 91.76,68.01 89.85,66.1 89.85,49.31 93.91,45.24 98.65,45.24 100.81,43.08 100.81,27.25 106.81,21.25 115.56,21.25 v2(115.77,21.46) 116.36,22.05 116.79,22.05 118.53,23.79 121.42,23.79 121.72,24.09 121.72,24.82 C28.1 121.23,25.57 v3(119.61,27.19) 119.61,27.2 119.38,27.43 AUDIO1.10
  BOTTOM w0.114: v3(119.61,27.19) 120.21,26.59 122.59,26.59 123.17,26.01 R6554.1 ; v3(50.14,113.49) 50.14,112.73 49.71,112.29 49.71,100.79 48.54,99.62 48.54,98.49 v3(48.73,98.29)
AZ_SYNC_M: length 11.5
  TOP w0.114: CPU1.AM2 46.99,138.95 46.68,138.64 46.4,138.64 46.33,138.71 45.52,138.71 44.85,138.03 44.03,138.03 43.38,137.39 42.75,137.39 41.45,136.09 41.12,136.09 v4(40.94,135.92) 39.7,134.67 RN2.7
BATTERY: length 9.4
  TOP w0.508: R124.2 133.29,68.96 v3(132.33,68.96) 131.83,68.96 129.15,71.64 129.15,71.64 BTT1.1
  BOTTOM w0.508: v3(132.33,68.96) v2(133.35,68.96)
BKLT_ADJ: length 5.9
  BOTTOM w0.114: R353.2 31.48,12.47 R374.1 32.79,12.01 34.08,12.01 v2(34.21,12.14) 35.7,10.65 R375.1
BKLT_EN: length 165.7
  TOP w0.114: v3(42.04,12.93) 44.22,15.11 44.22,17.27 44.74,17.79 44.74,25.84 45.32,26.43 45.32,31.21 44.98,31.55 44.98,41 45.76,41.79 45.76,50.11 53.31,57.65 53.31,59.77 54.71,61.17 54.71,62.67 55.56,63.52 v3(55.56,69.11) ; R365.2 C355.1 ; C355.1 24.97,104.6 26.11,104.6 26.42,104.29 26.42,101.14 27.86,99.69 27.86,99.19 28.22,98.83 28.78,98.83 29.16,99.21 29.64,99.21 31.58,97.27 31.58,95.58 33.44,93.73 53.61,93.73 55.65,91.69 58.3,91.69 v3(58.45,91.55) 59.55,91.55 60.04,91.06 70.05,91.06 v3(70.24,90.87) ; C355.1 R367.2 23.32,106.38 R364.2
  BOTTOM w0.114: v3(70.24,90.87) 70.24,90.85 70.29,90.8 U31.26 ; R354.2 34.98,15.81 Q100.G 36.33,15.27 36.55,15.49 38.71,15.49 39.5,14.71 39.5,13.36 40.04,12.82 41.93,12.82 v3(42.04,12.93) ; v3(58.45,91.55) 58.45,91.5 54.41,87.46 54.41,84.54 50.41,80.54 50.41,74.25 v2(53.44,71.22) v3(55.56,69.11)
BKLT_EN_D: length 38.2
  BOTTOM w0.114: Q101.G 15.98,16.74 R1030.2 15.11,17.46 15.11,13.77 19.48,9.4 23.06,9.4 v2(25.14,7.31) 25.7,6.76 32.26,6.76 35.18,9.68 37.03,9.68 37.31,9.96 Q100.D 37.05,12.82 35.53,12.82 34.47,13.88 R1029.1
BLANCLK_REQ_N: length 102.5
  TOP w0.114: R270.1 103.52,63.58 100.91,66.19 100.91,86.62 100.41,87.12 93.01,87.12 81.23,98.91 74.42,98.91 74.17,99.16 70.33,99.16 v3(69.85,99.64) ; v3(61.38,136.26) 61.72,136.6 CPU1.AU29
  BOTTOM w0.114: v3(61.38,136.26) 61.38,135.6 63.46,133.53 63.46,132.45 68.22,127.69 68.22,125.68 R85.1 69.85,124.05 v2(69.85,121.51) v3(69.85,99.64)
BLINK: length 11.5
  TOP w0.114: CPU1.AU17 55.48,136.6 v3(55.83,136.25)
  BOTTOM w0.114: R76.2 59.26,127.25 v2(59.26,128.12) 59.26,128.7 56.67,131.29 56.67,134.65 56.27,135.05 56.27,135.77 56.24,135.8 56.24,135.84 v3(55.83,136.25)
BT_DISABLE_N: length 79
  TOP w0.114: R6110.1 28.03,36.75 29,37.72 29,40.75 42.44,54.18 43.56,54.18 52.1,62.72 v2(52.1,67.79) 52.1,68.07 54.43,70.41 54.43,70.82 58.39,74.78 58.93,74.78 59.26,75.11 62.36,75.11 62.86,75.62 64.62,75.62 65.28,76.28 68.38,76.28 68.83,76.73 v3(69.55,76.73) 70.33,77.51 70.33,78.21 70,78.54 69.39,78.54 66.19,81.73 v3(66.19,83.84)
  BOTTOM w0.114: v3(66.19,83.84) 66.29,83.94 U31.18 ; v3(69.55,76.73) 69.55,75.8 69.49,75.74 U6503.42
BT_DISABLE_N#: length 22.7
  TOP w0.114: NGFFE1.54 32.17,16.75 32.83,17.41 32.83,22.69 31.52,24 30.78,24 28.03,26.75 v2(28.03,29.29) R475.2 28.03,33.41 28.92,34.3 R477.1 R6110.2
BUFFER1_M4: length 106.9
  TOP w0.114: v3(48.92,115.84) 48.66,115.84 46.69,113.87 45.03,113.87 42.97,111.8 36.4,111.8 31.79,116.41 30.71,116.41 29.84,115.54 v3(23.31,115.54)
  BOTTOM w0.114: v3(23.31,115.54) 23.31,137.11 18.69,141.73 18.69,147.73 18.69,148.04 29.04,158.39 v2(29.04,160.83) 29.04,168.34 31.9,171.2 31.9,173.01 33.91,175.02 33.91,178.41 Q4401.G ; R4402.1 49.21,116.13 v3(48.92,115.84) 48.71,115.62 48.71,113.82 Q4402.C
BYPASSCLK_H: length 6.6
  TOP w0.114: R28.1 60.15,161.09 60.15,159.4 59.99,159.24 59.99,159.14 58.93,158.08 58.93,156.2 58.84,156.1 58.84,155.8 58.91,155.73 58.91,155.49 CPU1.B24
BYPASSCLK_L: length 8
  TOP w0.114: CPU1.A24 59.15,157.6 v2(60.56,159.01) 61.1,159.55 61.1,160.38 61.52,160.8 61.52,161.75 62.08,162.31 R29.1
BZ_ON: length 4.6
  TOP w0.203: AUDIO1.12 121.17,27.33 122.91,27.33 C324.1 123.19,26.04 123.16,26.01 v2(123.16,25.96)
C_GPP_TXN0: length 6.1
  TOP w0.102: 45.19,151.11 45.21,151.09 45.28,151.09 45.71,150.67 46.03,150.67 CPU1.L1
  TOP w0.127: C5.1 41.98,151.51 42.11,151.38 42.46,151.38 42.67,151.6 42.67,152.08 42.8,152.21 43.71,152.21 ; 43.71,152.21 44.1,152.21 45.19,151.11 ; 43.71,152.21 v4(43.71,151.84)
C_GPP_TXN1: length 8.1
  TOP w0.102: 45.1,152.44 45.11,152.43 45.18,152.43 45.57,152.04 45.57,151.52 46.01,151.08 46.52,151.08 CPU1.K1
  TOP w0.127: v4(43.87,153.21) 44.1,153.44 ; 44.1,153.44 45.1,152.44 ; 44.1,153.44 43.67,153.87 42.16,153.87 41.94,153.64 41.94,153.21 41.78,153.06 41.4,153.06 41.25,153.21 C7.1
C_GPP_TXP0: length 5.8
  TOP w0.102: 45.41,151.33 45.43,151.31 45.43,151.24 45.79,150.88 46.25,150.88 46.63,150.5 CPU1.L2
  TOP w0.127: 45.41,151.33 44.23,152.51 C4.1
C_GPP_TXP1: length 8.1
  TOP w0.102: 45.31,152.66 45.32,152.65 45.32,152.58 45.77,152.13 45.77,151.6 46.09,151.28 46.31,151.28 46.38,151.35 46.68,151.35 CPU1.K2
  TOP w0.127: C6.1 41.53,154.18 42.77,154.18 ; 45.31,152.66 43.79,154.18 42.77,154.18 ; 42.77,154.18 v4(42.77,154.51)
CK_BLAN_DN: length 7.2
  BOTTOM w0.127: 105.79,63.73 106.4,63.73 106.86,64.19 108.89,64.19 109.3,63.78 109.47,63.78 109.52,63.83 LAN1.16 ; 105.79,63.73 v2(105.79,64.08) ; 105.79,63.73 104,63.73 R272.2
CK_BLAN_DP: length 7.2
  BOTTOM w0.127: LAN1.15 109.53,63.43 109.49,63.47 109.17,63.47 108.76,63.88 107.47,63.88 ; v2(107.47,63.53) 107.47,63.88 ; 107.47,63.88 106.98,63.88 106.53,63.42 104,63.42 R271.2
CLK_48M_SIO: length 16.4
  TOP w0.114: v3(76.99,84.18) v2(76.99,82.85) 76.99,82.27 v3(76.48,81.76)
  BOTTOM w0.114: U6503.24 73.53,77.66 73.36,77.83 73.36,80.62 73.59,80.85 74.75,80.85 75.67,81.76 v3(76.48,81.76) ; v3(76.99,84.18) 75.94,84.18 75.79,84.33 U31.37 75.79,86.25 76.15,86.61 77.7,86.61 78.33,87.25 R547.2
COMBO: length 23
  TOP w0.254: R236.2 129.01,32.08 C256.1 130.12,32.11 L18.2 130.7,33.26 v2(131.72,32.23) 132.1,32.61 D9.1 134.19,32.21 134.19,31.65 135.18,30.66 136.75,30.66 137.97,29.44 140.11,29.44 141.85,27.7 AUDS1.7
COMBO JACK: length 17.7
  TOP w0.114: v1(114.3,28.57) 114.2,28.68 114.2,29.26 114.48,29.54 AUDIO1.47 ; R236.1 129,30.63 C257.1 127.47,30.07 v1(127.46,30.08)
  BOTTOM w0.114: v1(114.3,28.57) v2(115.5,28.57) 125.96,28.57 v1(127.46,30.08)
CPU_FANCTL1: length 138.8
  TOP w0.114: v3(38.96,55.52) 38.96,56.74 47.47,65.25 47.47,65.53 52.91,70.97 52.91,71.4 57.84,76.33 58.39,76.33 58.62,76.56 58.62,76.56 58.75,76.68 61.8,76.68 63.25,78.13 67.52,78.13 v3(67.97,77.68)
  BOTTOM w0.114: v3(67.97,77.68) 67.85,77.8 67.85,80.11 67.49,80.47 U6503.2 67.49,82.43 67.26,82.65 66.69,82.65 66.27,82.23 62.38,82.23 61.79,82.82 U31.9 ; v3(38.96,55.52) 38.96,55.5 v2(49.18,45.29) 50.34,44.13 82.96,44.13 95.02,56.19 101.53,56.19 102.94,54.78 103.58,54.78 104.28,54.08 106.4,54.08 107.95,52.53 110.16,52.53 111.06,51.63 R6511.1 111.07,51.17 R6512.2
CPU_FANCTL1_5V: length 5.4
  BOTTOM w0.114: U6502.4 107.47,48.64 107.98,49.15 v2(108.69,49.15) 109.26,49.15 C6510.1 110.17,50.06 R6511.2
CPU_FANTACH1: length 147
  TOP w0.305: v3(67.16,78.82) 66.95,78.61 63.04,78.61 61.59,77.17 58.22,77.17 57.86,76.81 57.63,76.81 52.43,71.6 52.43,71.14 47.01,65.72 47.01,65.7 46.99,65.68 46.99,65.43 38.38,56.82 v3(38.38,55.98) ; v3(101.83,52.37) 103.3,53.85 104.62,53.85 108.3,50.17 FANC1.3
  BOTTOM w0.203: U31.8 61.29,82.04 61.62,81.71 U6503.1 67.09,79.34 67.18,79.25 67.18,78.84 v3(67.16,78.82)
  BOTTOM w0.305: v3(101.83,52.37) 101.83,51.69 R6516.2 102.46,51.57 102.46,53.04 C6523.1 R6517.1 102.35,54.4 101.02,55.73 95.21,55.73 83.15,43.66 49.89,43.66 v2(47.11,46.44) 38.38,55.17 v3(38.38,55.98)
CPU_VCORE: length 254.2
  TOP w0.305: v3(84.23,71.97) 84.21,71.97 82.64,70.41 79.75,70.41 78.12,68.78 74.29,68.78 72.29,66.78 71.2,66.78 G1.1 ; v3(124.32,178.63) 124.32,175.89 129.68,170.53 129.68,166.79 138.49,157.98 138.49,154.88 v3(138.68,154.69) ; v3(72.69,181.74) 72.92,181.51 v2(72.92,179.17) 72.92,177.83 70.07,174.97 64.57,174.97
  TOP w0.356: CPU1.AC23 58.18,143.68 v3(58.18,143.51) 57.68,144 CPU1.AC21 ; CPU1.W23 58.18,145.68 v3(58.18,145.51) ; v3(58.18,144.51) 58.18,144.68 CPU1.AA23 ; CPU1.N23 58.19,148.69 v3(58.19,148.5) ; v3(58.18,146.51) 58.18,146.68 CPU1.U23 ; v3(58.17,147.51) 58.17,147.67 CPU1.R23
  TOP w0.381: v3(58.17,149.49) 58.17,149.67 CPU1.L23
  TOP w0.508: v3(45.03,188.54) 45.03,188.54 PR4458.2
  BOTTOM w0.305: v3(72.69,181.74) 74.32,183.36 79.02,183.36 86.45,190.79 106.88,190.79 119.04,178.63 v3(124.32,178.63) ; v3(138.68,154.69) 138.68,131.32 136.87,129.5 136.87,109.66 135.99,108.79 135.99,106.22 132.76,102.99 132.76,92.68 127.09,87.01 110.5,87.01 102.98,79.49 96.25,79.49 88.87,72.11 84.36,72.11 v3(84.23,71.97)
  BOTTOM w0.508: v3(45.03,188.54) 45.52,188.54 v2(46.51,187.55) 46.66,187.4 46.66,184.63 47.35,183.95 47.35,182.93 47.02,182.6
  vias: v2(61.24,178.56) v3(58.17,150.48) v3(59.82,148.51) v3(59.82,147.47) v3(59.82,146.51) v3(59.82,145.52) v3(59.82,144.5) v3(59.82,143.51) v3(59.82,142.52) v3(59.93,149.53) v3(60.05,150.43) v3(61.01,150.35) v3(61,149.5) v5(46.94,181.71) v5(46.94,180.77) v5(46.94,179.81) v5(46.94,177.14) v5(46.94,176.17) v5(46.96,175.23) v5(46.99,174.37) v5(48.01,179.81) v5(48.03,177.09) v5(49.15,179.81) v5(49.23,177.09) v5(62.24,177.1) v5(62.26,181.13) v5(62.32,180.06) v5(63.24,181.07) v5(63.18,177.07) v5(63.3,179.99) v5(64.24,181.1) v5(64.3,180.03) v5(64.26,177.05)
D2_M: length 71
  TOP w0.508: v3(125.86,72.9) 130.68,68.07 134.21,68.07 135.25,69.11 135.25,71.02 D4.2
  BOTTOM w0.508: v3(125.86,72.9) 121.74,72.9 119.35,75.29 114.51,75.29 109.52,70.31 101.36,70.31 v2(97.54,66.48) 82.24,51.18 R123.1 R6544.1
D2_M1: length 3.8
  TOP w0.508: R124.1 133.03,70.29 v3(132.65,70.68) 132.24,71.09 D4.1
  BOTTOM w0.508: v2(133.6,70.48) 133.41,70.68 v3(132.65,70.68)
DAC_ZVSS: length 10.8
  TOP w0.114: R18.1 48.21,162.22 v4(49.48,162.22) 49.95,162.22 54.75,157.42 CPU1.A16
DCBATOUT: length 303.3
  TOP w0.381: v3(59.28,92.81) 59.31,92.84 59.82,92.84 60.51,92.15 65.12,92.15 v3(65.17,92.1) ; 3.99,83.79 5.18,83.79 7.25,81.72 11.49,81.72 11.89,82.12 47.93,82.12 v3(49.61,80.44)
  TOP w0.508: v5(10.72,30.81) 12.9,32.99 13.2,32.99 13.22,32.97 ; R434.1 R436.1 58.81,63.8 57.61,65 v3(56.49,65) ; v3(7.87,96.94) 4,96.94 3.99,96.95 ; 13.22,32.97 R313.1 ; 13.22,32.97 R315.1
  TOP w1.016: v5(4.57,66.4) 5.89,67.72 5.89,74.7 3.99,76.61 3.99,117.32 8.23,121.56 8.23,121.77 ; v5(10.72,30.81) 13.74,27.79 13.74,6.23 17.86,2.11 72.72,2.11 75.02,4.41 R6556.1
  BOTTOM w0.305: v3(49.61,80.44) 49.75,80.3 49.75,73.47 51.89,71.32 51.89,69.6 v3(56.49,65) 57.43,65 R519.2
  BOTTOM w0.381: v3(65.17,92.1) 65.17,92.15 65.96,92.94 R530.1 ; v3(59.28,92.81) 58.95,92.48 58.38,92.48 53.7,87.81 53.7,84.83 49.71,80.83 49.71,80.54 v3(49.61,80.44)
  BOTTOM w0.508: v3(7.87,96.94) R376.1 R380.1
  BOTTOM w1.016: v5(4.57,66.4) 4.57,33.02 6.78,30.81 v5(10.72,30.81)
  vias: v2(8.64,124.33) v2(20.02,196.82) v2(78.11,8.26) v2(97.41,83.34) v2(99.06,9.14) v2(100.74,19.89) v2(109.65,15.42) v2(117.73,117.47) v2(119.3,184.89) v5(21.03,198.61) v5(21.07,197.61) v5(95.52,85.45) v5(95.93,52.52) v5(96.22,86.33) v5(96.56,53.62) v5(96.73,85.44) v5(97.1,52.51) v5(97.32,86.33) v5(97.66,53.6) v5(97.8,85.4) v5(98.16,52.47) v5(98.43,86.28) v5(98.78,53.55) v5(100.45,17.7) v5(100.48,16.61) v5(101.6,17.68) v5(101.6,16.61) v5(102.74,17.68) v5(102.67,16.61) v5(103.94,17.78) v5(103.89,16.64) v5(104.65,17.22) v5(116.29,114.21) v5(116.35,115.31) v5(116.94,184.46) v5(117.42,123.38) v5(117.5,183.36) v5(117.48,124.48) v5(117.45,115.29) v5(117.5,114.2) v5(118.03,184.37) v5(118.47,183.3) v5(118.53,114.16) v5(118.58,124.45) v5(118.63,123.37) v5(118.59,115.26)
DCBATOUT_CON: length 36.8
  BOTTOM w0.508: 64.95,15.6 43.92,15.6 v2(43.58,15.25) 43.58,12.58 42.45,11.46 39.91,11.46 37.85,13.51 35.86,13.51 34.61,14.77 R1029.2 33.93,14.77 R339.1
  vias: v2(64.06,8.56) v2(70.23,5.08) v5(66.91,8.35) v5(66.89,7.2) v5(66.93,6.1) v5(66.95,5.17) v5(67.94,8.31) v5(67.86,7.24) v5(67.86,6.14) v5(67.98,5.12) v5(68.93,7.22) v5(68.92,6.18) v5(68.99,5.12)
DDR_VREF_S3: length 72
  TOP w0.508: v3(108.37,116.56) 108.22,116.56 108.11,116.46 106.79,116.46 106.76,116.49 104.45,118.8 104.45,127.87 v3(104.57,127.99) 104.57,127.99 104.72,128.14 104.72,130.4 105.55,131.23 105.55,135.89 104.47,136.97 104.47,150.78 107.99,154.29 107.99,168.85 v2(108.44,169.3) v5(109.98,170.84)
  BOTTOM w0.203: PU5001.4 110.19,118.33 PC5016.1
  BOTTOM w0.508: C1.1 109.01,171.91 R5.2 107.77,172.11 R145.2 107.78,172.98 R7.1 C1.1 ; C1.1 109.07,170.98 R6.2 109.74,170.86 109.75,170.84 v5(109.98,170.84) ; v3(104.57,127.99) 104.57,127.99 104.72,128.14 104.72,128.76 R146.2 ; PC5016.1 108.45,116.59 108.4,116.59 v3(108.37,116.56)
DIMM1_SA0: length 20.2
  TOP w0.114: DIMM1.197 93.8,114.45 93.19,113.84 93.19,112.4 96.93,108.66 100.08,108.66 100.99,109.58 102.29,109.58 v3(102.61,109.25)
  BOTTOM w0.114: R6557.2 102.88,108.98 v3(102.61,109.25) 102.61,109.52 104.67,111.58 v2(104.78,111.58) 105.49,111.58 R6558.1
DIMM_TMPIN2: length 123.2
  TOP w0.114: v3(120.14,145.13) 120.14,145.13 RT2.1 ; v3(81.73,79.3) 81.73,79.23 82.3,78.65 82.3,75.54 77.48,70.72 73.69,70.72 71.92,68.95 65.6,68.95 C469.1 v3(65.01,70.45) 64.07,71.38 RN20.4
  BOTTOM w0.114: v3(81.73,79.3) 86.64,79.3 v2(89.25,81.91) 92.01,84.66 98.77,84.66 120.6,106.5 120.6,144.67 v3(120.14,145.13) ; U6503.45 68.29,72.5 67.82,72.04 67.39,72.04 66.35,71 65.56,71 v3(65.01,70.45) 64.29,69.72 U31.89
DMIC_CLK: length 281.3
  TOP w0.114: L74.2 70.3,194.82 71.93,194.82 71.93,194.82 72.53,194.82 73.33,194.02 73.69,194.02 74.13,194.46 v3(74.35,194.46) ; v3(113.16,194.44) 114.82,196.1 D21.1 115.7,195.53 115.7,192.02 114.58,190.91 114.58,190.04 117.56,187.07 119.26,187.07 121.76,184.56 121.76,175.94 127.88,169.82 127.88,165.87 136.58,157.18 v3(136.58,153.95) ; v3(93.29,79.35) 93.29,67.5 91.29,65.5 91.29,49.91 94.36,46.84 99.22,46.84 102.31,43.76 102.31,27.8 107.41,22.7 113.77,22.7 115.17,24.1 115.17,24.54 115.42,24.79 115.42,25.23 C209.2 116.12,25.94 116.12,27.05 116.58,27.51 AUDIO1.3
  BOTTOM w0.114: v3(93.29,79.35) 93.55,79.35 95.54,81.34 100.14,81.34 121.37,102.57 129.08,102.57 130.33,103.81 130.91,103.81 133.49,106.39 133.49,107.91 134.01,108.43 134.01,110.67 134.59,111.25 134.59,122.26 135.07,122.74 135.07,130.37 136.58,131.88 v3(136.58,153.95) ; v3(113.16,194.44) 112.57,195.02 111.81,195.02 111.56,194.77 v2(111.56,194.64) 111.29,194.91 104.02,194.91 104.01,194.91 74.8,194.91 v3(74.35,194.46)
DMIC_CLK_W: length 23.2
  TOP w0.114: v3(64.52,194.92) 65.11,194.33 L74.1 ; CAM1.3 53.8,197.03 53.1,197.73 51.59,197.73 51.58,197.71 51.54,197.71 50.72,196.9 v3(50.41,196.9)
  BOTTOM w0.114: v3(64.52,194.92) v2(63.47,195.98) 62.97,196.48 50.83,196.48 v3(50.41,196.9)
DMIC_DATA: length 276.2
  TOP w0.114: L75.2 70.13,195.24 72.73,195.24 v3(73.51,194.46) ; AUDIO1.2 116.18,27.66 114.71,26.19 C208.2 114.05,25.29 114.05,23.88 113.29,23.12 107.58,23.12 102.77,27.93 102.77,43.89 99.4,47.26 94.53,47.26 91.71,50.08 91.71,65.32 93.73,67.34 93.73,79.7 v3(93.32,80.11) ; v3(136.09,154.64) 136.09,157.07 127.46,165.7 127.46,169.64 121.34,175.76 121.34,184.27 118.97,186.65 117.38,186.65 114.16,189.87 114.16,190.21 114.15,190.22 114.15,191.08 114.82,191.75 114.82,194.4 ; 114.82,194.4 v3(113.82,193.4) ; 114.82,194.4 D21.2
  BOTTOM w0.114: v3(113.82,193.4) 113.82,193.5 113.39,193.93 111.07,193.93 110.51,194.49 103.84,194.49 103.84,194.49 77.81,194.49 v2(77.29,193.97) 74,193.97 v3(73.51,194.46) ; v3(136.09,154.64) 136.09,153.81 136.12,153.78 136.12,132.02 134.65,130.55 134.65,122.91 134.16,122.42 134.16,111.56 133.58,110.97 133.58,108.61 133.07,108.1 133.07,107.07 130.24,104.24 130.1,104.24 128.96,103.1 121.31,103.1 99.97,81.76 94.97,81.76 v3(93.32,80.11)
DMIC_DATA_W: length 20.3
  TOP w0.114: v3(64.57,195.76) 65.34,194.99 v2(66.22,194.99) 66.84,195.61 68.24,195.61 L75.1 ; CAM1.2 53,197.06 52.58,197.48 51.87,197.48 51.36,196.97 51.36,196.92 v3(51.35,196.91)
  BOTTOM w0.114: v3(64.57,195.76) 63.41,196.91 v3(51.35,196.91)
DP0_AUXN: length 99.9
  TOP w0.127: CPU1.E15 54.16,153.4 v3(53.75,152.98) ; v3(30.18,94.28) 29.92,94.54 29.92,97.51 29.08,98.35 v3(28.86,98.35) 28.46,97.94 27.99,97.94 27.38,98.55 27.38,99.21 25.68,100.92 RN1.2
  BOTTOM w0.127: v3(28.86,98.35) 28.76,98.25 28.18,98.25 C495.1 ; v3(53.75,152.98) 53.75,153 53.37,153.37 52.87,153.37 52.63,153.61 52.37,153.61 R57.1 51.68,153.86 50.26,153.86 48.73,152.33 48.73,149.8 46.63,147.7 42.6,147.7 41.99,148.31 30.42,148.31 29.37,147.25 29.37,140.21 27.37,138.22 27.37,117.05 33.9,110.52 33.9,98.4 33.26,97.76 ; 33.26,97.76 v2(33.48,97.54) ; 33.26,97.76 30.18,94.67 v3(30.18,94.28)
DP0_AUXN_PS8625: length 3.6
  BOTTOM w0.127: v2(25.6,98.37) 25.86,98.11 ; 25.86,98.11 26.01,98.26 26.7,98.26 C495.2 ; 25.86,98.11 25.41,97.67 U38.3
DP0_AUXP: length 100.3
  TOP w0.127: v3(29.42,94.36) 29.62,94.55 29.62,97.38 29.36,97.64 v3(28.85,97.64) 27.86,97.64 27.08,98.42 27.08,99.09 25.18,100.99 RN1.1 ; v3(53.72,153.8) 54.12,154.2 CPU1.D15
  BOTTOM w0.127: v3(29.42,94.36) 29.43,94.36 33.6,98.53 33.6,110.4 27.07,116.93 27.07,138.34 29.06,140.34 29.06,147.38 30.3,148.62 42.11,148.62 42.72,148.01 46.51,148.01 47.31,148.81 ; 47.31,148.81 48.43,149.92 48.43,152.45 50.13,154.16 51.73,154.16 52.12,154.55 R58.1 53,153.67 53.6,153.67 v3(53.72,153.8) ; 47.31,148.81 v2(47.04,149.07) ; v3(28.85,97.64) 28.55,97.94 28.16,97.94 C496.1
DP0_AUXP_PS8625: length 3.3
  BOTTOM w0.127: U38.4 24.83,97.27 24.93,97.36 25.54,97.36 26.14,97.96 26.69,97.96 C496.2
DP0_HPD_G: length 8
  BOTTOM w0.114: v2(27.91,102.59) 27.43,103.07 Q57.G 26.33,103.01 25.45,102.13 25.45,100.61 25.7,100.36 28.41,100.36 R671.2
DP0_HPD_N: length 91
  TOP w0.114: v3(30.25,101.42) 28.93,102.74 28.93,109.07 30.4,110.54 v3(32.8,110.54) ; v3(27.94,148.56) 27.94,149.76 32.75,154.57 39.03,154.57 39.5,155.05 44.34,155.05 45.39,154 v3(45.69,154) ; v3(54.79,153.77) 54.79,153.4 55.15,153.04 55.37,153.04 55.66,152.75 55.66,152.45 55.3,152.1 55.3,152.06 CPU1.H17
  BOTTOM w0.114: v3(54.79,153.77) 55.07,154.05 55.07,154.83 54.13,155.78 R12.1 52.99,155.78 R45.2 52.38,155.17 46.86,155.17 v3(45.69,154) ; v3(32.8,110.54) 32.78,110.54 26.59,116.73 26.59,138.81 v2(27.71,139.93) 28.45,140.67 28.45,148.06 v3(27.94,148.56) ; R830.2 30.07,101.6 v3(30.25,101.42)
DP0_HPD_NR: length 2.6
  BOTTOM w0.114: Q57.S 26.45,100.99 27.63,100.99 v6(27.71,101.07) 28.24,101.6 R830.1
DP0_TXN0: length 3.3
  BOTTOM w0.127: C19.1 26.66,96.21 25.9,96.21 25.42,95.73 24.84,95.73 24.77,95.67 U38.8
DP0_TXN1: length 3.3
  BOTTOM w0.127: C21.1 26.71,94.39 25.93,94.39 25.39,94.93 24.66,94.93 24.6,94.87 U38.10
DP0_TXP0: length 3.6
  BOTTOM w0.127: C18.1 26.73,96.51 26.04,96.51 ; v6(26.04,96.85) 26.04,96.51 ; 26.04,96.51 25.77,96.51 25.3,96.04 24.82,96.04 24.79,96.07 U38.7
DP0_TXP1: length 3.5
  BOTTOM w0.127: C20.1 26.69,94.69 26.06,94.69 25.67,95.08 ; U38.9 24.61,95.27 24.64,95.23 25.52,95.23 25.67,95.08 ; 25.67,95.08 v6(25.86,95.28)
DP1_AUXN: length 157.7
  TOP w0.127: CPU1.E17 v3(55.85,153.77)
  BOTTOM w0.127: 124.46,111 124.16,111.3 124.16,163.87 105.85,182.18 89.82,182.18 76.52,168.88 60.25,168.88 54.33,162.96 54.33,161.85 54.56,161.63 54.56,159.61 55.15,159.02 55.15,157.61 55.45,157.32 55.45,155.69 56.29,154.85 56.29,154.21 v3(55.85,153.77) ; 124.46,111 v2(124.23,110.77) ; 124.46,111 124.61,110.85 125.65,110.85 125.89,111.08 RN16.3 126.27,108.45 127.45,107.27 129.29,107.27 Q38.S
DP1_AUXP: length 157.7
  TOP w0.127: CPU1.D17 55.6,154.2 v3(55.87,154.46)
  BOTTOM w0.127: v2(124.82,113.44) 124.46,113.44 ; 124.46,113.44 124.46,111.43 124.74,111.15 125.53,111.15 125.7,111.33 125.7,111.63 125.8,111.73 RN16.4 126.27,113.27 126.41,113.41 127.18,113.41 127.33,113.26 127.33,112.42 127.48,112.27 128.85,112.27 129.36,111.77 Q36.S ; 124.46,113.44 124.46,164 105.98,182.48 89.69,182.48 76.4,169.18 60.12,169.18 54.03,163.09 54.03,161.73 54.26,161.5 54.26,159.48 54.85,158.89 54.85,157.48 55.14,157.19 55.14,155.56 55.87,154.84 v3(55.87,154.46)
DP1_C_TXN0: length 7.3
  TOP w0.127: TR6.1 132.07,123.19 131.88,123.38 131.24,123.38 130.84,123.79 130.84,124.29 v1(130.64,124.49)
  BOTTOM w0.127: v1(130.64,124.49) 130.64,124.76 129.96,125.44 129.69,125.44 C397.1 R387.2 129.18,126.99 129.18,127.95 C380.2
DP1_C_TXN1: length 5.4
  TOP w0.127: v3(131.05,121.19) 131.15,121.28 131.47,121.28 132.01,120.75 132.02,120.75 132.03,120.74 132.03,120.52 132.18,120.37 TR5.1
  BOTTOM w0.127: C382.2 127.95,121.69 R389.2 130.08,121.69 C395.1 130.58,121.66 v3(131.05,121.19)
DP1_C_TXN2: length 5.1
  TOP w0.127: TR4.1 132.44,117.58 132.18,117.84 131.53,117.84 v1(131.25,117.56)
  BOTTOM w0.127: C383.2 127.97,117.62 R391.2 C393.1 130.14,117.62 130.38,117.86 130.95,117.86 v1(131.25,117.56)
DP1_C_TXN3: length 5.2
  TOP w0.127: v1(131.39,114.37) 131.62,114.6 131.94,114.6 132.14,114.4 TR3.1
  BOTTOM w0.127: v1(131.39,114.37) 131.16,114.37 131.09,114.3 130.64,114.3 C388.1 R393.2 128.95,113.9 C387.2
DP1_C_TXP0: length 6.6
  TOP w0.127: TR6.4 132.07,123.87 131.88,123.69 131.37,123.69 131.14,123.91 131.14,124.29 v1(131.46,124.61)
  BOTTOM w0.127: v1(131.46,124.61) 131.21,124.61 130.26,125.56 C396.1 R388.2 130.26,128.12 C378.2
DP1_C_TXP1: length 5.4
  TOP w0.127: TR5.4 132.13,121.05 131.13,122.06 v3(131.05,122.06)
  BOTTOM w0.127: C381.2 127.95,122.75 R390.2 129.09,122.78 C394.1 130.15,122.78 130.87,122.06 v3(131.05,122.06)
DP1_C_TXP2: length 5.2
  TOP w0.127: v1(131.29,118.4) 131.55,118.14 132.18,118.14 132.3,118.26 TR4.4
  BOTTOM w0.127: C385.2 128,118.71 R392.2 C392.1 130.15,118.71 130.71,118.16 131.05,118.16 v1(131.29,118.4)
DP1_C_TXP3: length 5.2
  TOP w0.127: v1(131.42,115.14) 131.66,114.9 131.98,114.9 132.16,115.08 TR3.4
  BOTTOM w0.127: v1(131.42,115.14) 130.88,114.6 130.31,114.6 130.11,114.8 C379.1 R394.2 128.02,114.8 C386.2
DP1_HDMI_CLK_C: length 15.7
  TOP w0.127: RN17.4 130.26,111.31 130.45,111.51 131.54,111.51 v3(131.78,111.26) 132.39,111.26 v2(132.74,111.61) 133.59,111.61 C390.1 134.5,111.11 134.75,111.36 U25.6 U25.5 137.43,111.36 137.52,111.28 137.64,111.28 137.79,111.43 137.79,113.79 138.91,114.9 139.16,114.9 139.26,115 HDMI1.15
  BOTTOM w0.127: v3(131.78,111.26) 131.26,110.74 Q36.D
DP1_HDMI_DATA_C: length 19.1
  TOP w0.127: HDMI1.16 139.26,114.5 139.16,114.6 139.04,114.6 138.1,113.66 138.1,111.3 137.77,110.97 137.52,110.97 137.43,110.88 U25.4 U25.7 134.97,110.88 134.11,110.03 C391.1 134.1,110.01 133.29,110.01 133.16,110.13 133.16,110.73 v3(133.07,110.82) 133.04,110.78 RN17.3
  BOTTOM w0.127: Q38.D 131.26,107.06 v2(132.66,108.46) 133.07,108.86 v3(133.07,110.82)
DP1_HPD_N: length 152.9
  TOP w0.114: CPU1.H19 56.1,151.8 55.85,152.05 v3(55.84,152.05)
  BOTTOM w0.114: v3(55.84,152.05) 55.84,152.44 56.34,152.94 56.34,153.94 56.51,154.11 56.51,155 55.75,155.76 55.75,157.33 55.38,157.7 55.38,159.25 54.81,159.82 54.81,162.75 60.46,168.4 76.72,168.4 89.91,181.58 105.51,181.58 123.57,163.52 v2(123.57,130.15) 123.57,109.83 R402.2 124.45,107.42 Q37.E
DP1_TXN0: length 141.4
  TOP w0.102: v3(49.45,157.76) 50.19,157.02 50.19,156.72 50.6,156.31 50.6,156.17 50.9,155.87 CPU1.B9
  BOTTOM w0.127: 50.49,164.37 49.66,163.53 49.66,157.98 49.45,157.77 v3(49.45,157.76) ; 50.49,164.37 v2(50.75,164.11) ; 50.49,164.37 58.16,172.03 74.22,172.03 87.73,185.54 106.96,185.54 127.31,165.19 127.31,133.14 129.67,130.79 129.67,129.32 C380.1
DP1_TXN0_C: length 8.9
  TOP w0.127: v4(134.54,122.12) 134.65,122.12 R827.1 ; R827.1 135.23,122.81 134.85,123.19 TR6.2 ; R827.1 135.8,122.81 136.47,122.13 U24.7 U24.4 138.24,122.13 139.38,121 HDMI1.3
DP1_TXN1: length 144.9
  TOP w0.102: v3(50.94,157.55) 50.83,157.43 50.83,156.8 51.2,156.43 51.2,156.17 51.13,156.1 51.13,155.84 51.45,155.52 CPU1.B10
  BOTTOM w0.127: C382.1 126.52,122.22 126.52,164.85 106.71,184.66 88.06,184.66 74.64,171.24 59.21,171.24 50.52,162.55 50.52,162 ; 50.52,162 v2(50.83,162) ; 50.52,162 50.52,157.93 50.85,157.61 50.89,157.61 v3(50.94,157.55)
DP1_TXN1_C: length 8.7
  TOP w0.127: TR5.2 134.29,120.37 134.42,120.5 135.1,120.5 R828.1 ; R828.1 135.47,120.4 136.17,120.4 136.39,120.61 U24.10 U24.1 138.39,120.61 139.5,119.5 HDMI1.6 ; R828.1 135.56,120.04 v2(135.56,119.33)
DP1_TXN2: length 146.5
  TOP w0.102: v3(50.95,158.18) 51.7,157.43 51.7,156.17 52,155.87 CPU1.B11
  BOTTOM w0.127: C383.1 126.66,118.04 126.28,118.04 125.74,118.59 125.74,164.52 106.51,183.75 88.33,183.75 76.69,172.11 ; v3(50.95,158.18) 51.84,159.06 51.84,162.75 59.54,170.45 75.03,170.45 76.69,172.11 ; 76.69,172.11 v2(76.91,171.88)
DP1_TXN2_C: length 8.6
  TOP w0.127: v2(135.08,116.48) 135.18,116.59 135.18,117.34 R807.1 ; R807.1 135.37,117.46 136.31,118.41 U23.7 U23.4 138.19,118.41 138.23,118.44 138.96,118.44 139.4,118 HDMI1.9 ; R807.1 135.14,117.63 134.43,117.63 134.38,117.58 TR4.2
DP1_TXN3: length 147.7
  TOP w0.102: CPU1.B12 52.55,155.52 52.25,155.82 52.25,156.12 52.35,156.21 52.35,156.39 52.2,156.54 52.2,157.82 v3(52.26,157.88)
  BOTTOM w0.127: 53.15,162.95 52.68,162.48 52.68,158.3 v3(52.26,157.88) ; 53.15,162.95 v2(53.39,162.71) ; 53.15,162.95 59.87,169.67 76.2,169.67 89.49,182.96 106.18,182.96 124.95,164.2 124.95,115.95 126.64,114.26 126.71,114.26 C387.1
DP1_TXN3_C: length 10.2
  TOP w0.127: TR3.2 134.42,114.4 134.67,114.65 135.07,114.65 R826.1 ; R826.1 135.28,114.36 v2(135.28,113.41) ; R826.1 135.46,114.4 136.17,115.11 136.17,116.74 136.32,116.89 U23.10 U23.1 138.94,116.89 139.33,116.5 HDMI1.12
DP1_TXP0: length 141.9
  TOP w0.102: CPU1.A9 50.4,156.8 50.4,157.11 49.89,157.62 49.89,157.91 49.43,158.37 v3(49.17,158.37)
  BOTTOM w0.127: C378.1 129.97,129.3 129.97,130.91 127.61,133.27 127.61,165.31 107.08,185.84 87.6,185.84 74.09,172.33 58.03,172.33 49.36,163.66 49.36,160.58 ; v3(49.17,158.37) 49.36,158.55 49.36,160.58 ; 49.36,160.58 v2(49.05,160.58)
DP1_TXP0_C: length 8.8
  TOP w0.127: R827.2 135.14,123.5 134.67,123.5 134.29,123.87 TR6.3 ; R827.2 136.42,122.61 U24.6 U24.5 138.19,122.61 138.81,122 HDMI1.1 ; R827.2 135.23,123.81 v2(135.23,124.64)
DP1_TXP1: length 144.9
  TOP w0.102: CPU1.A10 51.41,155.99 51.41,156.82 v3(51.24,156.98)
  BOTTOM w0.127: v2(53.62,166.57) 53.87,166.33 ; 53.87,166.33 50.22,162.68 50.22,157.81 50.52,157.5 50.52,156.79 50.65,156.67 51.11,156.67 51.24,156.79 v3(51.24,156.98) ; 53.87,166.33 59.09,171.55 74.51,171.55 87.93,184.97 106.84,184.97 126.83,164.98 126.83,122.98 C381.1
DP1_TXP1_C: length 9.2
  TOP w0.127: HDMI1.4 138.94,120.5 138.34,121.09 U24.2 U24.9 136.43,121.09 136.04,120.7 135.78,120.7 R828.2 134.99,120.8 134.57,120.8 134.32,121.05 TR5.3 133.83,121.74 133.45,122.12 v4(133.2,122.12)
DP1_TXP2: length 146.5
  TOP w0.102: v3(50.94,158.81) 51.22,158.81 51.41,158.62 51.41,158.01 51.9,157.52 51.9,156.4 CPU1.A11
  BOTTOM w0.127: v2(51.18,159.97) 51.54,159.97 ; 51.54,159.97 51.54,159.19 51.16,158.81 v3(50.94,158.81) ; 51.54,159.97 51.54,162.88 59.42,170.76 74.9,170.76 88.2,184.06 106.63,184.06 126.04,164.65 126.04,118.71 126.41,118.35 126.74,118.35 C385.1
DP1_TXP2_C: length 8.6
  TOP w0.127: HDMI1.7 139.29,119 139.04,118.75 138.25,118.75 138.11,118.89 U23.5 U23.6 136.34,118.89 135.81,118.35 R807.2 134.95,118 134.88,117.93 134.41,117.93 134.09,118.26 TR4.3 133.96,118.32 v4(133.96,119.3)
DP1_TXP3: length 147.7
  TOP w0.102: v3(52.12,158.47) 52.41,158.47 52.73,158.15 52.73,157.78 52.4,157.45 52.4,156.63 52.55,156.48 CPU1.A12
  BOTTOM w0.127: C386.1 126.92,114.72 126.62,114.72 125.25,116.08 125.25,164.32 106.31,183.27 89.37,183.27 79.58,173.48 ; v2(79.32,173.74) 79.58,173.48 ; 79.58,173.48 76.07,169.97 59.74,169.97 52.37,162.6 52.37,158.72 v3(52.12,158.47)
DP1_TXP3_C: length 10.3
  TOP w0.127: HDMI1.10 139.32,117.5 139.01,117.19 138.43,117.19 138.25,117.37 U23.2 U23.9 136.36,117.37 135.86,116.87 135.86,115.24 135.76,115.14 135.47,115.14 R826.2 134.99,114.96 134.55,114.96 134.42,115.08 TR3.3 133.83,115.14 v2(133.83,116.23)
DP_2K_ZVSS: length 7.8
  TOP w0.114: CPU1.A21 57.5,156.43 57.5,156.43 57.5,158.63 58.27,159.39 v4(58.27,162.56) 58.27,162.84 R11.1
DP_150_ZVSS: length 10.7
  TOP w0.114: CPU1.B16 54.75,155.51 55.06,155.82 55.06,156.1 54.99,156.17 54.99,157.72 v7(52.28,160.43) 49.64,163.07 R10.1
DP_BLON: length 99.8
  TOP w0.114: R364.1 22.3,107.04 22.55,107.28 22.55,111.9 23.63,112.98 v3(27.38,112.98) ; v1(38.33,166.13) 38.49,166.29 41.87,166.29 43.58,164.57 49.97,164.57 51.04,163.5 51.04,162.74 55.61,158.17 55.61,156.17 55.3,155.86 CPU1.B17
  BOTTOM w0.114: v3(27.38,112.98) 26.79,112.98 24.14,115.63 24.14,137.33 19.43,142.04 19.43,147.69 35.59,163.86 36.05,163.86 v2(36.53,164.33) v1(38.33,166.13)
DP_DIGON: length 119.4
  TOP w0.114: v3(12.31,114.11) 12.2,114.01 10.49,114.01 8.84,112.35 v3(8.84,102.21) ; v1(39.13,165.83) 41.81,165.83 43.43,164.2 49.81,164.2 50.67,163.35 50.67,162.56 55.3,157.93 CPU1.A17 ; v3(22.02,110.26) 22.17,110.41 22.17,112.04 23.56,113.44 26.8,113.44 v3(26.87,113.51)
  BOTTOM w0.114: v3(22.02,110.26) 22.02,110.57 19.76,112.83 14.76,112.83 13.48,114.11 v3(12.31,114.11) ; v3(26.87,113.51) 24.51,115.88 24.51,137.48 19.8,142.2 19.8,147.39 35.55,163.14 36.45,163.14 v2(38.53,165.22) v1(39.13,165.83) ; v3(8.84,102.21) R383.1
DP_REXT: length 5.2
  BOTTOM w0.114: v2(28.83,93.09) R587.1 27.36,93.61 26.63,93.61 26.47,93.76 24.82,93.76 24.51,94.07 U38.12
DP_VARY_BL: length 221.7
  TOP w0.114: v3(36.83,11.51) 36.83,12.16 36.37,12.62 36.37,24.27 35.06,25.59 35.06,31.18 31.6,34.64 31.6,41.99 v3(31.55,42.04) ; CPU1.A18 55.85,158.45 51.41,162.9 51.41,163.65 50.12,164.94 43.73,164.94 42.02,166.66 37.83,166.66 v1(37.37,166.2) ; v3(29.92,98.2) 31.09,97.03 31.09,94.21 28.28,91.4 28.28,86.11 26.56,84.39 17.49,84.39 v3(17.35,84.53)
  BOTTOM w0.114: v1(37.37,166.2) 19.06,147.89 19.06,141.89 23.77,137.18 23.77,115.48 26.88,112.37 27.61,112.37 v2(28.91,111.07) 31.46,108.52 31.46,100.5 30.51,99.54 30.51,98.78 v3(29.92,98.2) ; v3(36.83,11.51) 36.59,11.27 R375.2 ; v3(31.55,42.04) 29.26,42.04 24.31,46.99 24.31,61.46 23.37,62.4 23.37,78.51 v3(17.35,84.53) 16.34,85.53 16.34,87.62 17.85,89.12 R585.1
DP_VARY_BL_R: length 4.8
  BOTTOM w0.114: R585.2 18.74,90.16 R611.1 18.73,90.53 v2(19.34,91.15) 20.14,91.95 20.14,92.32 20.08,92.38 U38.21
EC_EUP: length 22.8
  TOP w0.114: v3(61.16,81.48) v2(61.86,82.18) 62.35,82.67 v3(62.59,82.67) ; R574.1 54.86,85.12 55.12,84.86 v3(55.94,84.86) R6543.2 55.93,85.79 R572.1
  BOTTOM w0.114: U6503.5 68.69,82.47 68.45,82.71 67.87,82.71 67.5,83.07 66.52,83.07 66.12,82.67 v3(62.59,82.67) ; v3(55.94,84.86) 57.41,86.32 58.03,86.32 58.29,86.06 U31.2 58.29,82.68 59.49,81.48 v3(61.16,81.48)
EC_EUP_EN: length 3.6
  TOP w0.114: v2(53.35,84.07) R574.2 53.38,85.14 C493.1 53.31,86.04 Q48.G
EC_EUP_EN#: length 244.7
  TOP w0.114: v3(72.95,36.12) 72.95,37.64 v3(72.9,37.69) ; v3(51.03,85.14) 51.03,85.19 49.9,86.32 Q48.D 49.97,87.1 R568.1 ; v3(46.79,81.42) 13.37,81.42 v3(13.03,81.08) ; PR5209.1 12.84,140.57 R4802.1 12.66,141.92 v3(12.86,141.92) ; v3(46.95,32.44) 47,32.48 47,40.16 47.78,40.95 47.78,48.93 53.75,54.89 v3(53.75,59.59) ; v3(19.61,35.71) 19.41,35.92 R319.1
  BOTTOM w0.114: v3(19.61,35.71) 19.61,35.6 21.38,33.83 42.57,33.83 43.97,32.44 v3(46.95,32.44) 47.07,32.44 47.07,32.44 56.08,32.44 56.39,32.12 61.87,32.12 61.87,32.12 61.88,32.12 63.13,32.12 63.37,31.88 65.33,31.88 71.15,37.69 v3(72.9,37.69) ; v3(12.86,141.92) v2(9.62,138.68) 9.12,138.18 9.12,119.96 4.29,115.13 4.29,89.79 13,81.08 v3(13.03,81.08) ; R6561.2 71.44,28.16 72.89,29.6 Q4805.G 71.96,31.1 71.96,32.69 72.89,33.62 Q4806.G 72.68,33.75 v2(71.37,35.05) 71.37,35.18 72.31,36.12 v3(72.95,36.12) ; v3(53.75,59.59) 46.06,67.27 46.06,72.67 45.41,73.32 45.41,76.45 46.75,77.79 46.75,81.38 v3(46.79,81.42) 47.3,81.42 v3(51.03,85.14)
EC_SMI#: length 4.1
  BOTTOM w0.114: R75.2 54.54,127.05 53.66,126.17 53.66,125.29 v6(53.82,125.12) 54.02,124.92 R516.2
EC_SMI#_APU: length 11.2
  TOP w0.114: CPU1.AR15 53.86,137.06 v3(53.63,137.06)
  BOTTOM w0.114: v3(53.63,137.06) 53.63,136.77 53.26,136.39 53.26,129.52 53.66,129.12 R83.1 53.66,127.82 R75.1 53.65,126.94 v6(53.65,126.94)
EDID_RDY: length 1.3
  TOP w0.114: CPU1.AR4 48.3,136.92 48.44,136.78 48.44,136.78 v3(48.46,136.75)
  BOTTOM w0.114: TP67.1 48.97,137.26 v3(48.46,136.75)
EDP_LVDS_L0_N: length 14.9
  TOP w0.127: 17.22,99.54 14.41,99.54 C365.2 13.5,99.19 13.19,99.19 12.85,98.85 12.3,98.85 11.95,98.5 LVDS19.19 ; 17.22,99.54 v2(17.22,99.22) ; 17.22,99.54 18.04,99.54 19.61,101.11 19.61,101.93 20,102.32 v3(20.01,102.32)
  BOTTOM w0.127: v3(20.01,102.32) 20,102.3 20,101.99 20.83,101.15 20.83,99.92 20.88,99.87 U38.42
EDP_LVDS_L0_P: length 14.9
  TOP w0.127: v3(19.3,102.25) 19.3,102.05 19.3,101.24 18.96,100.89 ; LVDS19.18 11.95,99.5 12.3,99.15 12.72,99.15 13.07,99.49 13.46,99.49 13.64,99.68 13.64,100.32 C364.2 14.39,99.85 17.91,99.85 18.96,100.89 ; 18.96,100.89 v2(18.72,101.14)
  BOTTOM w0.127: v3(19.3,102.25) 20.53,101.03 20.53,100.05 20.48,100 U38.41
EDP_LVDS_L1_N: length 13.1
  TOP w0.127: v3(18.21,102.16) 18.18,102.16 17.71,102.64 17.43,102.64 16.74,101.96 16.41,101.96 ; LVDS19.16 11.89,101.5 12.36,101.96 13.16,101.96 C369.2 13.78,101.76 13.98,101.96 16.41,101.96 ; 16.41,101.96 v2(16.41,101.62)
  BOTTOM w0.127: U38.40 20.08,99.82 19.99,99.92 19.99,100.87 19.2,101.66 18.29,101.66 18.07,101.87 18.07,102.02 v3(18.21,102.16)
EDP_LVDS_L1_P: length 13.2
  TOP w0.127: v3(18.03,102.95) 17.3,102.95 16.62,102.26 14.36,102.26 C368.2 13.18,102.27 12.18,102.27 11.95,102.5 LVDS19.15
  BOTTOM w0.127: U38.39 19.68,99.77 19.68,99.77 19.68,100.74 19.07,101.35 18.17,101.35 17.77,101.75 17.77,102.26 ; 17.77,102.26 17.77,102.68 v3(18.03,102.95) ; 17.77,102.26 v2(17.4,102.26)
EDP_LVDS_L2_N: length 16
  TOP w0.127: LVDS19.13 11.82,104.5 12.16,104.85 12.43,104.85 12.75,104.52 13.36,104.52 13.78,104.1 C371.2 14.38,104.36 15.69,104.36 16.19,103.85 16.78,103.85 ; v3(17.68,103.6) 17.43,103.85 16.78,103.85 ; 16.78,103.85 v2(16.78,103.52)
  BOTTOM w0.127: v3(17.68,103.6) 17.44,103.84 16.94,103.84 16.51,103.4 16.51,101.45 17.13,100.83 18.78,100.83 19.23,100.37 19.23,99.87 19.28,99.82 U38.38
EDP_LVDS_L2_P: length 16
  TOP w0.127: v3(17.64,104.35) 17.45,104.15 16.32,104.15 15.81,104.66 14.38,104.66 C370.2 13.4,104.83 12.88,104.83 12.55,105.15 12.3,105.15 11.95,105.5 LVDS19.12
  BOTTOM w0.127: U38.37 18.88,99.8 18.93,99.85 18.93,100.25 18.66,100.52 17.01,100.52 16.74,100.79 ; v3(17.64,104.35) 17.43,104.14 16.81,104.14 16.21,103.53 16.21,101.32 16.74,100.79 ; 16.74,100.79 v2(16.48,100.53)
EDP_LVDS_L3_N: length 21.5
  TOP w0.127: v3(15.59,108.75) 15.37,108.97 14.29,108.97 C374.2 13.78,109.02 13.6,109.2 12.22,109.2 12.07,109.05 12.07,108.66 11.91,108.5 LVDS19.9
  BOTTOM w0.127: 14.62,98.79 15.74,97.67 U38.34 ; 14.62,98.79 14.25,99.16 14.25,105.77 14.83,106.35 14.83,108.76 15.04,108.97 15.37,108.97 v3(15.59,108.75) ; 14.62,98.79 v2(14.88,99.06)
EDP_LVDS_L3_P: length 21.5
  TOP w0.127: LVDS19.8 13.42,109.5 C373.2 14.36,109.27 15.4,109.27 v3(15.6,109.46)
  BOTTOM w0.127: U38.33 17.57,97.27 17.47,97.36 15.62,97.36 13.94,99.04 13.94,105.89 14.52,106.47 14.52,106.91 ; v3(15.6,109.46) 15.41,109.28 14.91,109.28 14.52,108.89 14.52,106.91 ; 14.52,106.91 v2(14.17,106.91)
EDP_LVDS_LC_N: length 18
  TOP w0.127: LVDS19.11 11.67,106.5 12.05,106.88 13.54,106.88 13.8,106.62 C377.2 14.38,106.69 15.63,106.69 16.24,106.08 16.24,104.91 16.5,104.65 v3(16.74,104.65)
  BOTTOM w0.127: U38.36 17.63,98.47 17.58,98.42 17.05,98.42 15.06,100.41 15.06,102.36 ; v2(15.42,102.36) 15.06,102.36 ; 15.06,102.36 15.06,103.84 16.1,104.88 16.52,104.88 v3(16.74,104.65)
EDP_LVDS_LC_P: length 17.9
  TOP w0.127: v3(16.71,105.38) 16.55,105.55 16.55,106.2 15.75,107 14.35,107 C376.2 13.4,107.19 12.23,107.19 11.92,107.5 LVDS19.10
  BOTTOM w0.127: v2(14.94,104.6) 15.16,104.37 ; 15.16,104.37 15.98,105.18 16.51,105.18 v3(16.71,105.38) ; 15.16,104.37 14.76,103.96 14.76,100.28 16.92,98.12 17.61,98.12 17.66,98.07 U38.35
EDP_LVDS_U0_N: length 20.4
  TOP w0.127: LVDS19.30 11.95,87.5 12.3,87.85 12.74,87.85 13.74,86.84 C354.2 14.36,87.43 15.68,87.43 v3(15.77,87.33)
  BOTTOM w0.127: U38.32 17.25,96.87 17.18,96.8 14.91,96.8 13.59,95.48 13.59,90.38 ; 13.59,90.38 v2(13.27,90.38) ; 13.59,90.38 13.59,88.61 14.86,87.33 15.77,87.33 v3(15.77,87.33)
EDP_LVDS_U0_P: length 20.5
  TOP w0.127: v3(15.74,88.2) 15.74,87.94 15.54,87.73 14.41,87.73 C353.2 13.71,88.3 13.71,87.81 13.58,87.68 13.33,87.68 12.86,88.15 12.3,88.15 11.95,88.5 LVDS19.29
  BOTTOM w0.127: 14.5,88.12 13.89,88.74 13.89,95.35 15.04,96.49 17.2,96.49 17.22,96.47 U38.31 ; 14.5,88.12 14.99,87.64 15.45,87.64 15.74,87.93 v3(15.74,88.2) ; 14.5,88.12 v2(14.76,88.38)
EDP_LVDS_U1_N: length 15.9
  TOP w0.127: LVDS19.28 11.95,89.5 12.28,89.83 12.78,89.83 12.98,89.64 13.4,89.64 C357.2 14.36,89.84 v3(15.9,89.84)
  BOTTOM w0.127: U38.30 17.51,96.07 17.45,96.01 16.31,96.01 15.8,95.5 15.42,95.5 15.07,95.16 ; v2(14.83,95.4) 15.07,95.16 ; 15.07,95.16 14.37,94.46 14.37,90.46 14.99,89.84 v3(15.9,89.84)
EDP_LVDS_U1_P: length 15.9
  TOP w0.127: LVDS19.27 11.97,90.5 12.34,90.14 12.91,90.14 13.1,89.94 13.53,89.94 13.78,90.19 C356.2 14.41,90.14 15.58,90.14 15.89,90.45 v3(15.89,90.57)
  BOTTOM w0.127: v3(15.89,90.57) 15.89,90.45 15.58,90.14 15.12,90.14 14.68,90.59 14.68,91.74 ; v2(15.04,91.74) 14.68,91.74 ; 14.68,91.74 14.68,94.33 15.54,95.2 15.93,95.2 16.43,95.71 17.38,95.71 17.42,95.67 U38.29
EDP_LVDS_U2_N: length 11.4
  TOP w0.127: LVDS19.26 11.95,91.5 12.3,91.85 12.65,91.85 13.19,92.39 13.48,92.39 13.78,92.09 C359.2 14.41,92.3 15.73,92.3 v3(15.88,92.15)
  BOTTOM w0.127: v2(15.24,93.6) 15.61,93.6 ; 15.61,93.6 15.61,93.2 15.98,92.83 15.98,92.26 v3(15.88,92.15) ; 15.61,93.6 15.61,94.11 16.72,95.22 16.99,95.22 17.03,95.27 U38.28
EDP_LVDS_U2_P: length 11.4
  TOP w0.127: v3(16.59,92.23) 16.22,92.6 14.37,92.6 C358.2 13.28,92.69 13.06,92.69 12.52,92.15 12.3,92.15 11.95,92.5 LVDS19.25
  BOTTOM w0.127: v3(16.59,92.23) 16.28,92.53 16.28,92.96 15.91,93.33 15.91,93.99 16.49,94.56 ; v2(16.71,94.34) 16.49,94.56 ; 16.49,94.56 16.84,94.92 17.12,94.92 17.16,94.96 17.46,94.96 17.56,94.87 U38.27
EDP_LVDS_U3_N: length 15.9
  TOP w0.127: 17.13,97.09 v2(17.13,96.78) ; 17.13,97.09 14.42,97.09 C361.2 13.78,97.18 13.59,97.37 13.22,97.37 12.7,96.85 12.3,96.85 11.95,96.5 LVDS19.21 ; 17.13,97.09 17.62,97.09 18.01,96.7 18.01,95.61 18.36,95.25 18.36,92.37 18.06,92.07 v3(17.82,92.07)
  BOTTOM w0.127: U38.24 18.88,92.51 18.45,92.07 v3(17.82,92.07)
EDP_LVDS_U3_P: length 15.9
  TOP w0.127: v3(18.43,91.62) 18.43,92.01 18.66,92.24 18.66,93.39 ; 18.66,93.39 18.66,95.38 18.31,95.73 18.31,96.83 17.75,97.39 14.41,97.39 C360.2 13.44,98.02 12.57,97.15 12.3,97.15 11.95,97.5 LVDS19.20 ; 18.66,93.39 v2(18.98,93.39)
  BOTTOM w0.127: v3(18.43,91.62) 18.57,91.77 19.19,92.38 19.19,92.38 19.28,92.47 U38.23
EDP_LVDS_UC_N: length 9.9
  TOP w0.127: v4(15.85,94.34) 15.85,94.67 ; 15.85,94.67 14.36,94.67 C363.2 13.09,94.77 12.22,94.77 11.95,94.5 LVDS19.23 ; 15.85,94.67 16.79,94.67 17.12,94.34 v3(17.12,93.32)
  BOTTOM w0.127: v3(17.12,93.32) 17.31,93.5 17.31,94.19 17.58,94.47 U38.26
EDP_LVDS_UC_P: length 10
  TOP w0.127: 17.17,94.72 16.92,94.97 14.36,94.97 C362.2 13.3,95.08 12.26,95.08 11.84,95.5 LVDS19.22 ; 17.17,94.72 v4(17.42,94.97) ; 17.17,94.72 17.42,94.47 17.42,93.75 v3(17.83,93.34)
  BOTTOM w0.127: U38.25 17.69,94.07 17.6,93.98 17.6,93.58 v3(17.83,93.34)
EUP_DSW_SEL: length 31.6
  TOP w0.114: v3(71.45,79.17) 71.04,79.58 71.04,82.12 69.85,83.31 69.85,85.8 69.01,86.64 R6573.2 ; v3(72.82,77.57) 72.82,78.21 73.25,78.64 74.14,78.64 74.83,77.95 74.83,77.64 75.45,77.01 76.18,77.01 76.77,77.61 v3(76.77,77.68) 77.34,77.12 v2(77.34,75.56) 77.34,73.38 v3(76.74,72.78)
  BOTTOM w0.114: v3(76.77,77.68) 76.39,78.06 U6503.23 ; R557.2 80.72,71.26 R560.1 79.91,71.03 79.91,72 79.12,72.78 U31.60 76.74,72.78 v3(76.74,72.78) ; v3(72.82,77.57) 72.64,77.57 71.45,78.77 v3(71.45,79.17)
EUP_EN: length 70.8
  TOP w0.114: v3(20.95,34.87) 20.4,34.32 C313.1 R314.2 ; U20.3 63.52,39.64 64.47,40.59 64.47,41.92 U17.G 62.04,42.95 C311.1 58.19,42.29 57.15,41.25 57.15,32.97 57.38,32.74 v3(57.38,32.74) 57.49,32.63 57.49,30.14 58.43,29.2 58.43,27.27 60.42,25.28 C328.1 60.44,24.85 U18.3
  BOTTOM w0.114: v3(57.38,32.74) 57.35,32.71 56.7,32.71 v2(56.52,32.89) 44.03,32.89 42.71,34.21 21.62,34.21 v3(20.95,34.87)
EUP_R1: length 3.6
  TOP w0.114: R313.2 14.11,31.86 v2(14.48,31.5) 14.98,31.5 Q28.2
EUP_R2: length 4.9
  TOP w0.114: R318.1 16.63,35.11 Q28.1 15.3,35.18 v2(14.07,35.18) 14.1,35.15 R315.2
EUP_R3: length 8.7
  TOP w0.114: Q28.3 17.42,33.02 17.42,31.55 v2(17.68,31.29) 18.39,32 19.24,32 R316.1 ; R316.1 19.47,32.99 R314.1 ; R316.1 19.52,31.72 C312.2 21.48,32.6 R317.1
EUP_R4: length 6.2
  TOP w0.114: Q29.6 14.99,37.96 v2(14.75,38.2) ; R318.2 14.75,36.9 v2(14.75,38.2) ; v2(14.75,38.2) 15.16,38.61 Q29.5
EUP_R5: length 7.4
  TOP w0.114: R317.2 21.48,37.07 v2(20.65,37.9) 19.29,39.26 Q29.3
EUP_R6: length 4.9
  TOP w0.114: R319.2 17.77,36.08 18.19,36.5 19.15,36.5 v2(19.53,36.88) 19.56,36.91 19.56,37.95 18.9,38.61 Q29.2
F_GPP_CLK0N: length 183.9
  TOP w0.127: v3(51.21,144.5) 51.5,144.21 CPU1.AC10
  BOTTOM w0.127: v2(100.89,63.53) 101.14,63.27 ; 101.14,63.27 101.6,63.73 102.4,63.73 R272.1 ; 101.14,63.27 99.16,61.29 97.9,61.29 82.31,45.69 51.18,45.69 37.35,59.52 37.35,84.83 42.41,89.89 42.41,110.33 37.13,115.62 37.13,122.76 35.16,124.73 35.16,133.81 34.67,134.29 34.67,139.64 37.05,142.01 37.79,142.01 39.34,143.56 43.59,143.56 43.68,143.47 49.88,143.47 50.91,144.5 v3(51.21,144.5)
F_GPP_CLK0P: length 184
  TOP w0.127: CPU1.AC8 v3(50.34,144.53)
  BOTTOM w0.127: 99.99,61.68 99.29,60.99 98.03,60.99 82.43,45.39 51.05,45.39 37.05,59.4 37.05,84.96 42.11,90.02 42.11,110.21 36.83,115.49 36.83,122.63 34.85,124.61 34.85,133.68 34.37,134.16 34.37,139.76 36.92,142.32 37.67,142.32 39.22,143.87 43.71,143.87 43.8,143.78 49.76,143.78 50.34,144.36 v3(50.34,144.53) ; 99.99,61.68 v2(100.23,61.44) ; 99.99,61.68 101.73,63.42 102.4,63.42 R271.1
F_GPP_CLK1N: length 158.2
  TOP w0.127: v3(49.25,144.45) 49.47,144.24 49.47,143.47 49.1,143.11 CPU1.AE5 ; v3(43.89,44.53) 43.75,44.39 43.75,29.43 41.53,27.21 41.53,19.36 40.17,18 NGFFE1.49
  BOTTOM w0.127: v2(35.08,52.76) 34.86,52.54 ; 34.86,52.54 39.5,47.9 41.81,47.9 43.89,45.82 v3(43.89,44.53) ; 34.86,52.54 34.39,53.01 34.39,85.24 39.96,90.81 39.96,109.39 34.65,114.71 34.65,121.41 32.31,123.74 32.31,141.94 33.2,142.82 37.49,142.82 39.17,144.5 43.74,144.5 44.23,144.01 48.81,144.01 v3(49.25,144.45)
F_GPP_CLK1P: length 158.3
  TOP w0.127: NGFFE1.47 39.55,18.5 39.74,18.3 40.05,18.3 41.22,19.48 41.22,27.34 43.45,29.56 43.45,44.15 43.18,44.41 v3(43.18,44.5) ; CPU1.AE4 48.03,143.07 48.03,143.26 48.18,143.41 48.54,143.41 48.67,143.54 48.67,144.36 v3(48.59,144.44)
  BOTTOM w0.127: v3(48.59,144.44) 48.46,144.31 44.36,144.31 43.87,144.81 39.04,144.81 37.36,143.13 33.07,143.13 32.01,142.06 32.01,123.62 34.34,121.29 34.34,114.58 39.66,109.26 39.66,90.93 34.09,85.36 34.09,52.88 37.44,49.53 ; 37.44,49.53 39.37,47.6 41.68,47.6 43.59,45.69 43.59,45.11 43.51,45.03 43.33,45.03 43.18,44.88 v3(43.18,44.5) ; 37.44,49.53 v2(37.19,49.28)
F_HPO_L: length 14.4
  TOP w0.203: v1(117.32,37.21) 117.88,36.65 117.88,36.18 117.38,35.68 AUDIO1.32
  TOP w0.254: R240.1 126.77,36.07 v1(126.19,35.48)
  BOTTOM w0.254: v1(126.19,35.48) 125.7,35 124.05,35 121.92,37.13 v2(120.6,37.13) 117.4,37.13 v1(117.32,37.21)
F_HPO_L_1: length 2.8
  TOP w0.203: v2(126.95,37.11) 127.95,36.11 R240.2 128.91,36.07 L20.1
F_HPO_R: length 12.9
  TOP w0.203: v1(117.37,36.42) 117.37,36.14 116.98,35.75 AUDIO1.33
  TOP w0.254: R238.1 126.56,34.42 v1(126.14,34.42)
  BOTTOM w0.254: v1(117.37,36.42) 117.45,36.35 v2(118.75,36.35) 121.62,36.35 123.55,34.42 v1(126.14,34.42)
F_HPO_R_1: length 2.4
  TOP w0.203: v2(127.55,33.97) 127.95,34.38 R238.2 128.16,35.13 L19.1
F_USB0N: length 142.1
  TOP w0.102: v3(48.56,138.99) 48.57,139 48.6,139 CPU1.AL5 ; v3(45.05,102.28) 45.26,102.07 46.24,102.07 46.77,101.54 74.85,101.54 75.32,101.07 82.52,101.07 94.06,89.53 102.26,89.53 103.41,88.38 103.41,85.34 104.65,84.1 122.71,84.1 123.95,85.34 128.55,85.34 128.77,85.56 L72.3
  BOTTOM w0.102: 44.73,104.06 44.73,102.6 v3(45.05,102.28) ; 44.73,104.06 44.73,112.37 40.23,116.86 40.23,136.6 40.04,136.8 40.04,137.43 40.48,137.87 41.98,137.87 43.31,139.19 47.11,139.19 47.66,138.64 48.02,138.64 48.38,138.99 v3(48.56,138.99) ; 44.73,104.06 v2(45.09,104.06)
F_USB0P: length 142.3
  TOP w0.102: CPU1.AL4 48.18,139.38 48.18,139.37 v3(47.86,139.05) ; v3(45.05,101.57) 45.29,101.82 46.14,101.82 46.67,101.29 74.74,101.29 75.21,100.82 82.42,100.82 93.95,89.28 102.16,89.28 103.16,88.28 103.16,85.23 104.55,83.85 122.81,83.85 124.06,85.09 128.56,85.09 128.78,84.88 L72.2
  BOTTOM w0.102: v3(45.05,101.57) 44.48,102.14 44.48,112.26 43.63,113.1 ; v3(47.86,139.05) 47.62,139.05 47.22,139.45 43.21,139.45 41.88,138.12 40.37,138.12 39.78,137.53 39.78,136.69 39.98,136.5 39.98,116.76 43.63,113.1 ; 43.63,113.1 v2(43.38,112.85)
F_USB1N: length 117.1
  TOP w0.102: L44.3 23.92,60.21 24.11,60.4 31.78,60.4 v3(31.98,60.2) ; CPU1.AD2 46.68,143.05 46.42,143.05 46.34,143.13 46.18,143.13 45.46,143.86 43.82,143.86 43.23,144.45 41.71,144.45 41.4,144.75 41.4,145.14 v3(41.2,145.34)
  BOTTOM w0.102: 32.16,120.83 33.13,119.86 33.13,114.19 33.86,113.47 33.86,112.76 34.09,112.53 34.09,112.52 34.34,112.27 34.98,112.27 38.55,108.7 38.55,91.4 32.84,85.69 32.84,60.76 32.49,60.4 32.18,60.4 v3(31.98,60.2) ; 32.16,120.83 v2(32.41,121.08) ; 32.16,120.83 30.89,122.09 30.89,126.7 30.86,126.73 30.86,139.39 30.88,139.41 30.88,142.84 32.31,144.27 36.17,144.27 37.67,145.77 41.04,145.77 41.2,145.61 v3(41.2,145.34)
F_USB1N_RC: length 2.5
  TOP w0.114: C680.1 24.55,58.85 v2(24.51,58.85) R813.2
F_USB1P: length 116.9
  TOP w0.102: CPU1.AD1 46.52,143.38 46.29,143.38 45.56,144.11 43.93,144.11 43.34,144.7 41.81,144.7 41.66,144.86 41.66,145.24 41.81,145.39 v3(41.91,145.39) ; v3(31.95,60.93) 31.95,60.81 31.8,60.66 24.2,60.66 23.96,60.89 L44.2
  BOTTOM w0.102: 32.59,65.68 32.59,85.79 38.3,91.5 38.3,108.59 34.87,112.01 34.23,112.01 33.83,112.42 33.83,112.42 33.6,112.65 33.6,113.36 32.88,114.09 32.88,119.75 30.64,121.99 30.64,126.59 30.61,126.63 30.61,139.49 30.63,139.51 30.63,142.95 32.2,144.53 36.06,144.53 37.56,146.02 41.15,146.02 41.78,145.39 v3(41.91,145.39) ; 32.59,65.68 32.59,60.86 32.38,60.66 32.13,60.66 31.95,60.83 v3(31.95,60.93) ; 32.59,65.68 v2(32.23,65.68)
F_USB2N: length 100.4
  TOP w0.102: v3(37.21,139.09) 37.21,139.37 36.86,139.72 36.86,142.96 35.1,144.71 35.1,150.62 v3(34.9,150.83) ; CPU1.AG8 51.05,142.05 51.05,142.14 v3(51.07,142.15) ; L41.3 78,193.24 77.12,192.36 77.12,190.13 74.6,187.6 74.6,181.18 v3(74.3,180.87)
  BOTTOM w0.102: v3(74.3,180.87) 74.6,180.57 74.6,178.87 73.53,177.8 ; v3(34.9,150.83) 35.08,151 35.08,153.16 43.86,161.95 43.86,163.84 55.58,175.55 71.29,175.55 73.53,177.8 ; v3(37.21,139.09) 37.25,139.13 38.37,139.13 39.07,139.83 40.57,139.83 42.35,141.6 45.29,141.6 46.03,140.87 47.79,140.87 48.49,141.57 50.48,141.57 v3(51.07,142.15) ; v2(73.28,178.05) 73.53,177.8
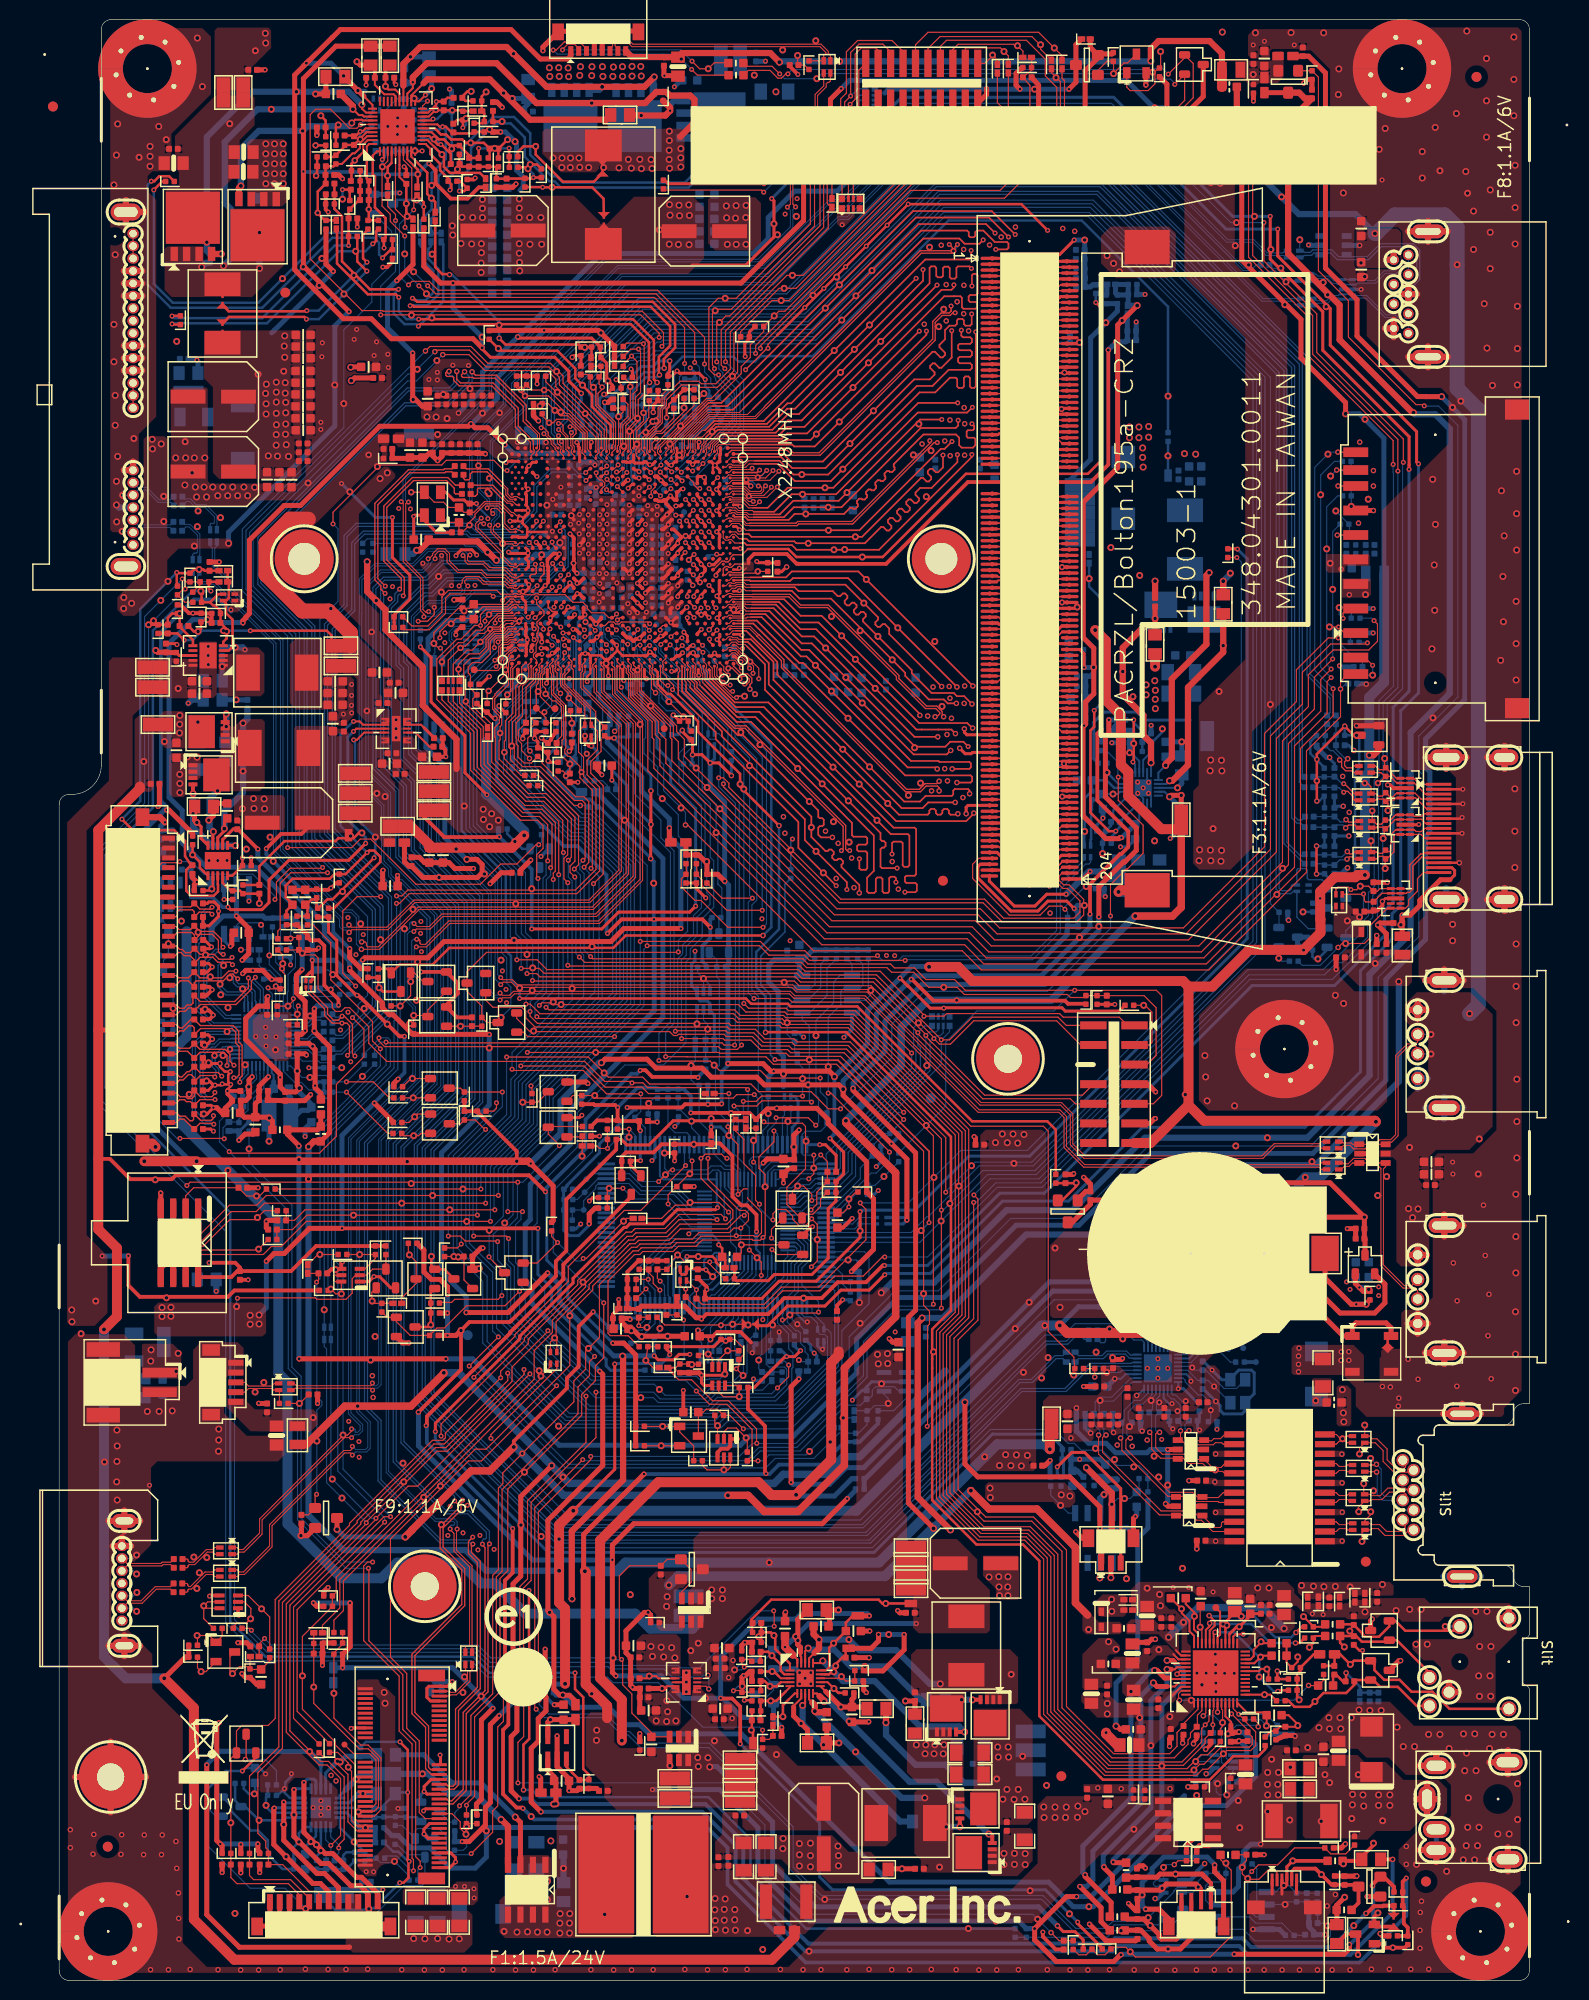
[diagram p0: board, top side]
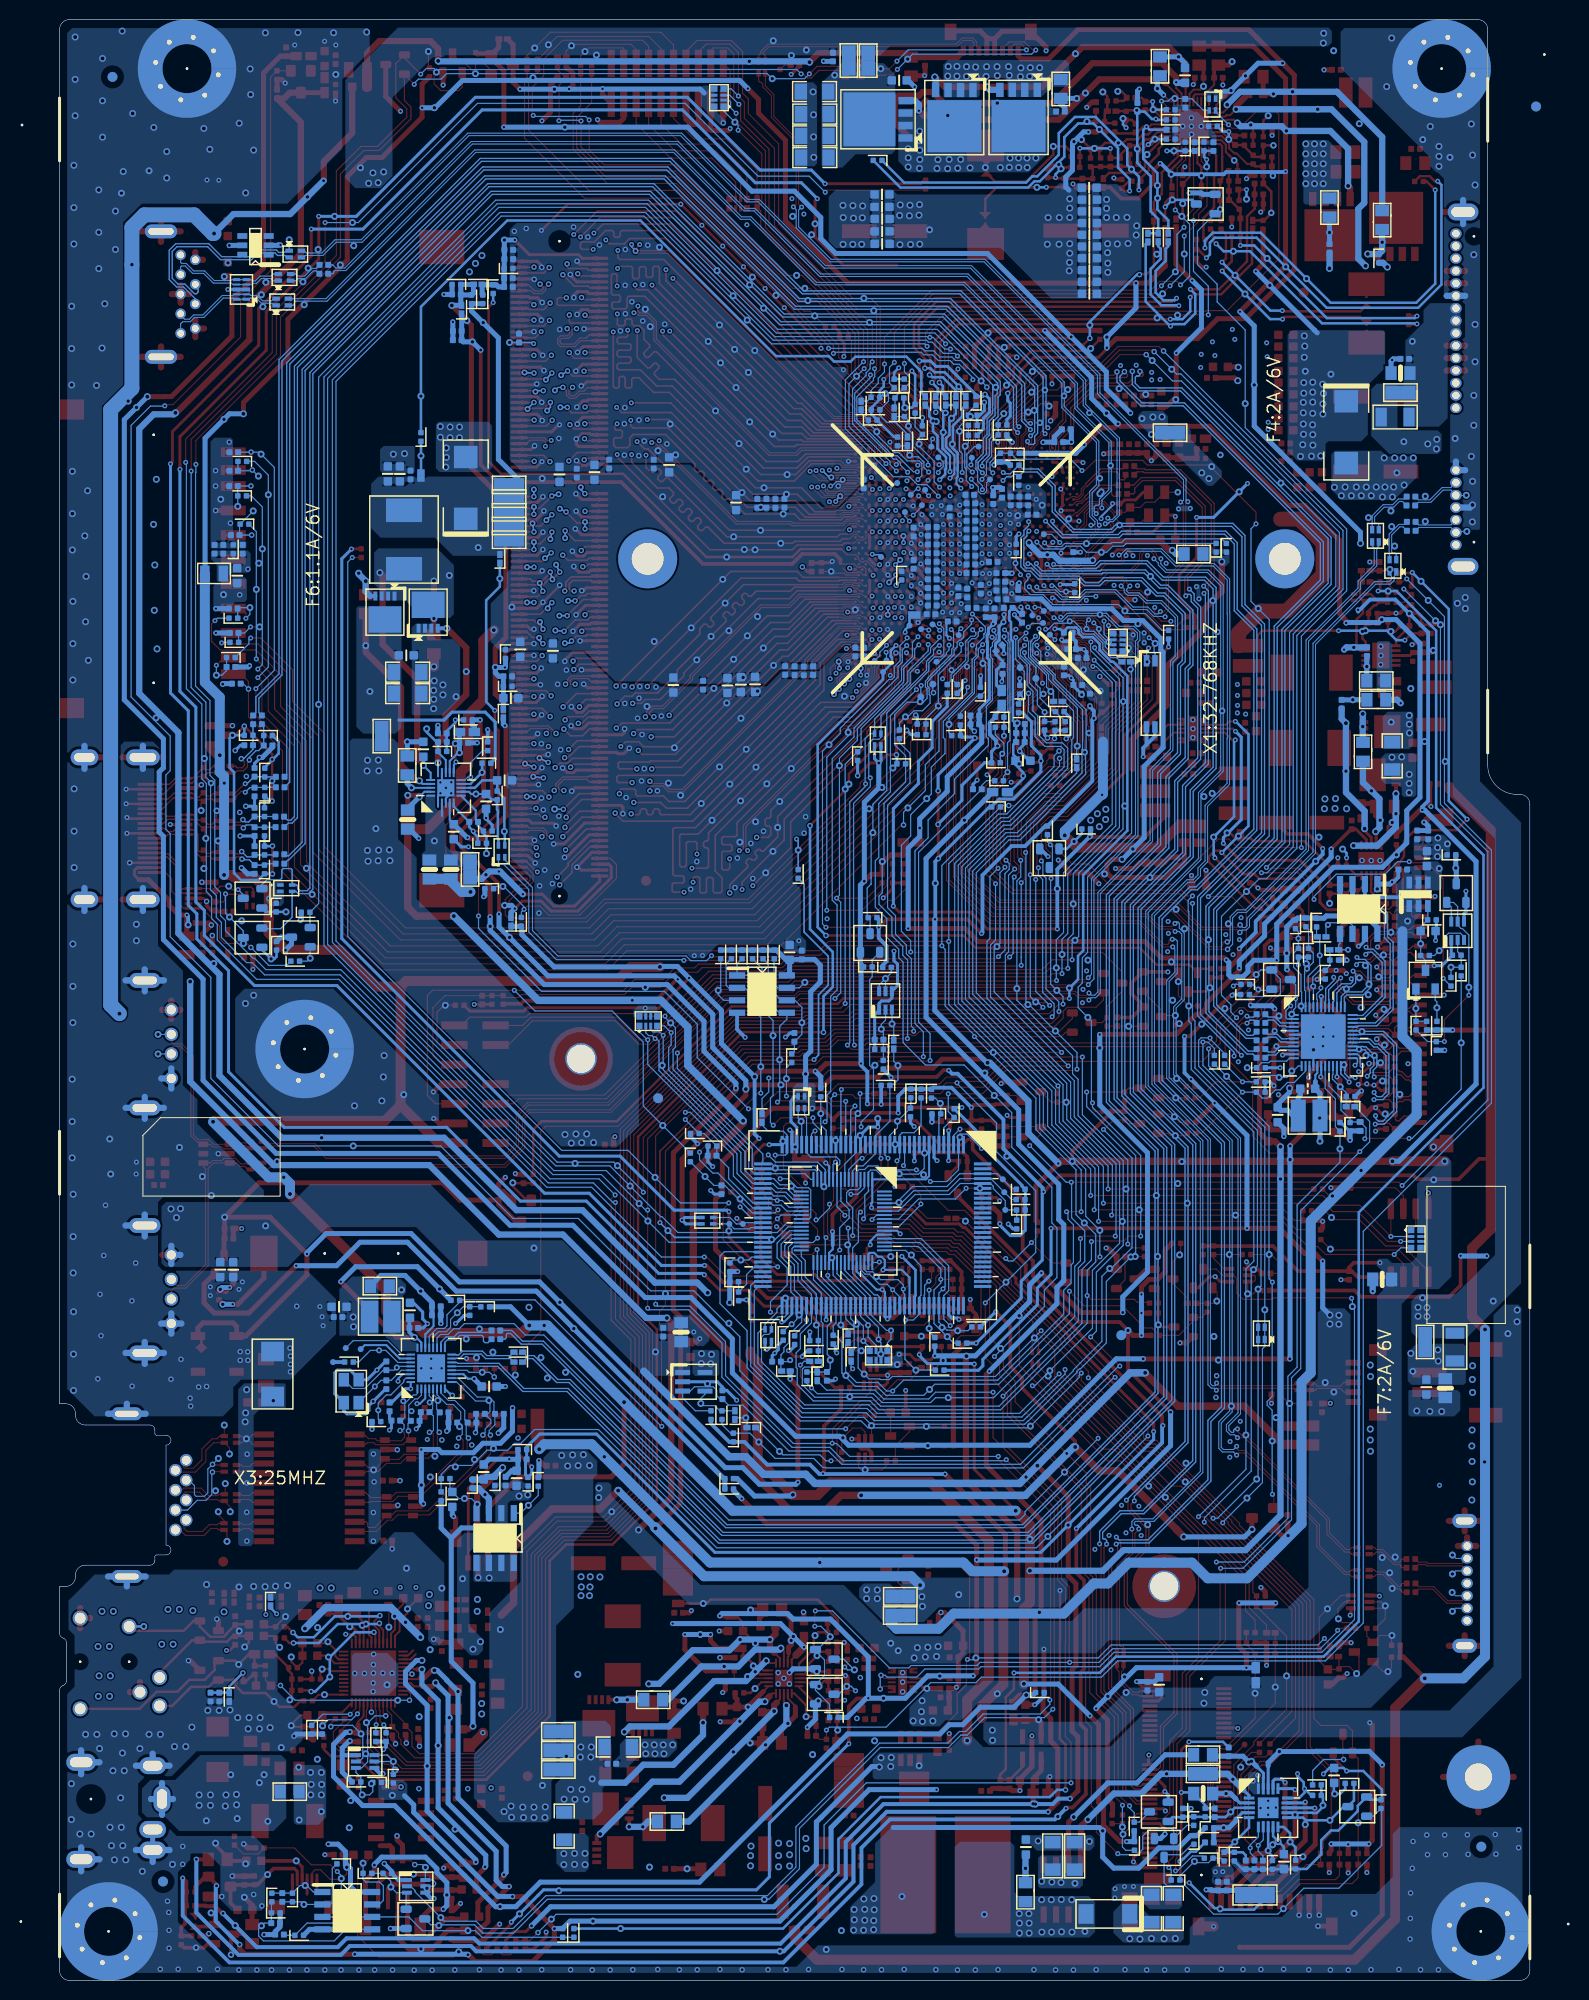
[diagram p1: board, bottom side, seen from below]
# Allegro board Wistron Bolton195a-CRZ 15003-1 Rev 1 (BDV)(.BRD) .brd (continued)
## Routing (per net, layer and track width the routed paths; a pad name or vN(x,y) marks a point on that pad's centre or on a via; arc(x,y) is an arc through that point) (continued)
F_USB2N_RC: length 2.3
  TOP w0.114: R464.2 76.05,195.36 C452.1 75.34,195.45 v2(75.34,196.34)
F_USB2P: length 99.5
  TOP w0.102: v3(50.3,142.12) 50.3,141.92 50.08,141.7 CPU1.AG7 ; L41.2 78.68,193.75 78.53,193.6 78.41,193.6 78.25,193.45 78.25,193.13 77.38,192.26 77.38,190.02 74.85,187.5 74.85,181.18 v3(75.13,180.9) ; v3(37.69,139.62) 37.64,139.57 37.37,139.57 37.11,139.83 37.11,143.06 35.36,144.82 35.36,150.65 35.5,150.79 v3(35.64,150.79)
  BOTTOM w0.102: v2(75.21,179.93) 74.85,179.93 ; 74.85,179.93 74.85,178.76 71.39,175.3 55.68,175.3 44.11,163.73 44.11,161.84 35.33,153.06 35.33,150.98 35.52,150.79 v3(35.64,150.79) ; 74.85,179.93 74.85,180.62 v3(75.13,180.9) ; v3(50.3,142.12) 50,141.82 48.38,141.82 47.68,141.12 46.13,141.12 45.4,141.86 42.24,141.86 40.46,140.08 38.96,140.08 38.27,139.38 37.93,139.38 v3(37.69,139.62)
F_USB4N: length 150.9
  TOP w0.102: v2(127.81,83.52) 127.81,83.21 ; 127.81,83.21 128.57,83.21 128.77,83.4 L47.3 ; 127.81,83.21 104.62,83.21 102.77,85.05 102.77,88.12 102.09,88.8 93.86,88.8 82.22,100.43 75.05,100.43 74.59,100.89 46.35,100.89 45.95,100.48 45.21,100.48 v3(44.98,100.71) ; CPU1.AF2 47.02,142.25 46.72,141.95 46.42,141.95 46.33,142.05 46.14,142.05 45.78,142.05 45.41,142.42 43.25,142.42 42.72,142.95 41.58,142.95 41.38,142.74 41.38,142.55 v3(41.7,142.23)
  BOTTOM w0.102: v3(41.7,142.23) 41.38,141.91 41.38,141.6 41.05,141.27 39.95,141.27 39.17,140.49 37.66,140.49 36.19,139.01 36.19,135.06 36.67,134.58 36.67,125.59 38.74,123.51 38.74,116.29 44.07,110.96 44.07,100.81 44.39,100.49 44.76,100.49 v3(44.98,100.71)
F_USB4P: length 150.9
  TOP w0.102: 88.75,93.55 82.12,100.18 74.95,100.18 74.49,100.63 46.46,100.63 46.05,100.23 45.22,100.23 v3(44.99,100) ; 88.75,93.55 v2(88.52,93.32) ; 88.75,93.55 93.75,88.54 101.99,88.54 102.52,88.01 102.52,84.95 104.52,82.95 128.53,82.95 128.77,82.72 L47.2 ; v3(40.8,142.23) 41.12,142.55 41.12,142.85 41.48,143.21 42.82,143.21 43.36,142.67 45.51,142.67 45.93,142.25 46.06,142.25 CPU1.AF1
  BOTTOM w0.102: v3(40.8,142.23) 41.12,141.91 41.12,141.71 40.94,141.53 39.85,141.53 39.06,140.74 37.56,140.74 35.93,139.11 35.93,134.96 36.42,134.48 36.42,125.48 38.49,123.41 38.49,116.19 43.82,110.86 43.82,100.71 44.29,100.24 44.75,100.24 v3(44.99,100)
F_USB5N: length 138.3
  TOP w0.102: CPU1.AE2 46.33,142.5 46.02,142.5 45.43,143.09 43.52,143.09 43,143.61 40.64,143.61 39.57,144.68 39.57,145.44 39.24,145.77 38.71,145.77 38.35,145.41 v3(38.35,145.01) ; v3(40.6,46.04) 40.54,45.97 40.54,43.87 42.12,42.29 L49.3
  BOTTOM w0.102: v3(40.6,46.04) 40.6,46.8 40.32,47.08 38.45,47.08 34.91,50.61 ; 34.91,50.61 33.62,51.91 33.62,85.56 39.19,91.13 39.19,109.04 33.81,114.42 33.81,121.15 31.54,123.42 31.54,142.26 32.89,143.61 37.14,143.61 37.9,144.37 37.9,144.55 v3(38.35,145.01) ; 34.91,50.61 v2(35.15,50.85)
F_USB5P: length 138.8
  TOP w0.102: v3(37.64,145.01) 37.74,145.01 38.1,145.37 38.1,145.52 38.6,146.02 39.35,146.02 39.83,145.55 39.83,144.78 40.75,143.87 43.11,143.87 43.63,143.34 45.53,143.34 45.78,143.09 46.08,142.8 CPU1.AE1 ; L49.2 41.44,34 41.5,34.06 41.78,34.06 41.87,34.15 41.87,42.18 40.28,43.77 40.28,45.59 39.89,45.99 v3(39.89,46.05)
  BOTTOM w0.102: v3(39.89,46.05) 39.89,46.33 39.99,46.43 40.24,46.43 40.35,46.54 40.35,46.69 40.35,46.7 40.22,46.82 38.99,46.82 ; v3(37.64,145.01) 37.64,144.47 37.03,143.87 32.79,143.87 31.28,142.36 31.28,123.32 33.56,121.05 33.56,114.32 38.94,108.94 38.94,91.23 33.36,85.66 33.36,51.8 38.34,46.82 38.99,46.82 ; 38.99,46.82 v2(38.99,46.48)
F_USB8N: length 119.9
  TOP w0.102: v3(43.06,149.15) 42.49,148.58 42.49,148.03 45.06,145.47 45.06,145.16 46.01,144.2 46.33,144.2 46.38,144.15 46.68,144.15 46.98,144.45 CPU1.AB2
  BOTTOM w0.102: v3(43.06,149.15) 42.91,149 42.6,149 42.12,149.47 42.12,157.2 45.57,160.65 45.57,163.15 57.06,174.65 71.96,174.65 78.72,181.41 79.88,181.41 86.64,188.16 108.25,188.16 119.12,177.29 119.99,177.29 ; 119.99,177.29 121.79,177.29 123.14,175.95 124.92,175.95 125.12,175.74 L40.3 ; 119.99,177.29 v2(119.99,176.94)
F_USB8P: length 119.6
  TOP w0.102: CPU1.AB1 46.48,144.45 46.48,144.46 46.12,144.46 45.31,145.26 45.31,145.57 42.75,148.14 42.75,148.48 42.99,148.72 43.17,148.72 v3(43.31,148.57)
  BOTTOM w0.102: 123.62,176.2 123.24,176.2 121.89,177.55 119.23,177.55 108.36,188.42 86.53,188.42 79.78,181.66 78.61,181.66 71.86,174.91 56.96,174.91 45.31,163.26 45.31,160.75 41.86,157.31 41.86,149.44 42.51,148.79 42.84,148.79 43.06,148.57 v3(43.31,148.57) ; 123.62,176.2 v2(123.62,176.56) ; 123.62,176.2 124.84,176.2 125.07,176.43 L40.2
FAN5V_OUT: length 3.6
  BOTTOM w0.635: R6515.1 107.24,50.19 v2(106.6,49.55) 106.2,49.15 U6502.3
FAN5V_OUT_CONN: length 14.9
  TOP w0.635: FANC1.1 106.3,44.48 107.39,45.57 v2(107.39,48.56) 107.39,49.71 v5(104.8,52.3)
  BOTTOM w0.635: v5(104.8,52.3) 105.59,51.51 R6531.2 106.46,51.36 C6511.1 107.88,51.09 R6515.2
FM_L_CODEC: length 3
  TOP w0.203: AUDIO1.21 121.93,32.34 v2(122.57,32.98) 122.64,33.05 122.67,33.05 122.73,33.12 C254.1
FM_R_CODEC: length 3.9
  TOP w0.203: C255.1 122.78,34.39 122.63,34.54 v2(122.62,34.54) 122.58,34.5 122.58,34.44 121.87,33.73 121.87,33.07 121.54,32.74 AUDIO1.22
FP_RST_N: length 10.5
  TOP w0.114: CPU1.AY7 49.8,134.14 49.49,133.83 49.49,133.3 49.31,133.12 49.31,132.08 49.63,131.75 v4(49.63,131.22) 50.34,130.51 50.65,130.51 51.25,129.9 51.25,126.9 50.75,126.4 C29.1 50.75,125.27 R78.1
HDMI_DP_5V:
  vias: v2(131.42,108.08)
HDMI_EN: length 8.3
  TOP w0.114: CPU1.E21 57.91,153.81 v3(57.91,153.81)
  BOTTOM w0.114: v3(57.91,153.81) 57.91,155.73 58.19,156 v2(58.19,158.01) 58.19,158.49 57.28,159.4 R42.1 57.28,159.89 R39.1
HDMI_HPDET_CN: length 20.2
  TOP w0.114: v1(130.48,105.36) 130.89,105.77 v2(131.24,105.77) 133.17,105.77 133.68,106.27 133.68,107.54 135.5,109.36 U25.10 U25.1 137.35,109.36 137.67,109.68 137.67,110.2 138.58,111.1 138.58,112.38 139.19,113 HDMI1.19
  BOTTOM w0.114: v1(130.48,105.36) 128.65,103.53 126.83,103.53 R401.1
HDMI_HTPLG_CN1: length 2.4
  BOTTOM w0.114: R401.2 124.73,103.96 v2(124.43,104.26) Q37.B
HDMI_Q76_M: length 42.8
  TOP w0.254: v1(128.28,115.7) v1(128.28,112.86) ; v1(128.31,120.29) v4(128.31,122.35) v1(128.31,124.54) 128.31,125.08 v1(131.15,127.93) 132.08,127 Q35.D
  BOTTOM w0.254: v1(128.31,120.29) 128.54,120.29 129.05,120.8 R389.1 129.09,120.77 R392.1 ; R387.1 127.65,126.34 127.65,125.14 128.25,124.54 v1(128.31,124.54) 128.31,124.48 129.07,123.73 R390.1 ; v1(128.28,112.86) 128.29,112.87 R393.1 129.73,112.24 131.49,112.24 132.2,112.95 132.2,123.23 132.64,123.67 132.64,126.72 v2(132.36,127) R388.1 v1(131.15,127.93) ; v1(128.28,115.7) 128.29,115.69 R394.1 R391.1
HDT_C_M1: length 15.6
  TOP w0.114: HDT1.11 88.64,189.37 86.56,187.3 82.7,187.3 79.87,184.47 RN22.8
HDT_C_M2: length 16.1
  TOP w0.114: RN22.7 80.52,184.05 83.08,186.61 87.21,186.61 89.91,189.31 HDT1.13
HDT_C_M3: length 16.4
  TOP w0.114: HDT1.15 91.18,189.4 87.66,185.88 83.46,185.88 81.02,183.43 RN22.6
HDT_PW_M3: length 8.4
  TOP w0.114: Q44.1 108.92,193.11 109.27,192.76 111.1,192.76 111.79,193.45 111.79,194.7 112.16,195.06 R492.2 112.37,195.18 v2(112.37,196.75)
HDT_PW_M4: length 6.8
  TOP w0.114: v2(107.57,194.49) 107.57,194.51 ; 107.57,194.51 108.64,195.58 109,195.58 Q44.3 ; 107.57,194.51 107.57,195.72 R490.2 106.9,195.75 105.97,194.82 Q43.G
HDT_RST0: length 7.1
  TOP w0.114: R487.1 96.84,196.3 v2(96.39,196.75) 96.03,197.12 92.52,197.12 92.45,197.04 HDT1.18
HDT_RST1: length 3.1
  TOP w0.114: HDT1.20 94.44,195.54 95.23,196.32 v2(95.23,196.38) 95.72,195.89 R488.1
HDT_TRST: length 15.2
  TOP w0.114: HDT1.9 87.37,189.93 85.27,187.83 81.99,187.83 78.84,184.68 R480.2
HM_VCCP: length 9.3
  TOP w0.114: R507.1 61.79,66.85 68.63,66.85 v2(68.71,66.93) G1.2
HM_VCCP_R: length 17
  TOP w0.114: R507.2 59.17,67.64 C474.1 v3(59.13,66.78) 59.31,66.6 v2(59.97,66.6)
  BOTTOM w0.114: v3(59.13,66.78) 59.79,67.43 U31.98 59.79,69.85 59.29,70.35 59.29,72.88 62.08,75.67 U6503.52
HP_OUT_L_CON: length 15.9
  TOP w0.254: AUDS1.2 142.46,35.66 137.34,35.66 136.33,36.67 D12.2 135.7,36.11 134.65,35.05 133.24,35.05 132.97,35.32 132.97,35.37 C262.1 132.02,36.32 L20.2
  BOTTOM w0.254: AUDS1.2 v2(141.41,36.1)
HP_OUT_R_CON: length 12.6
  TOP w0.254: AUDS1.3 139.8,31.37 136.47,34.7 D12.1 135.54,34.54 132.91,34.54 132.34,35.12 C261.1 132.07,35.13 L19.2 130.68,34.44 v2(131.11,34.01)
ICH_RSMRST_N_R: length 21.1
  TOP w0.114: R534.1 61.47,77.72 62.26,78.51 62.29,78.51 62.85,79.08 64.09,79.08 v2(64.36,79.35) 67.31,79.35 v3(68.29,78.37)
  BOTTOM w0.114: v3(68.29,78.37) 68.5,78.15 68.5,75.31 69.09,74.73 U6503.43 69.09,72.13 66.88,69.92 66.57,69.92 66.29,69.64 U31.85
ISEN1: length 18.3
  TOP w0.508: CNVBD2.12 32.5,8.88 30.86,10.52 30.34,10.52 27.92,12.93 27.14,12.93 v2(26.24,13.83) 24.97,15.11 v3(24.97,20.19)
  BOTTOM w0.305: v3(24.97,20.19) 25.3,20.52 26.01,20.52 26.2,20.34 U59.17
ISEN2: length 17.4
  TOP w0.508: CNVBD2.11 31.5,8.86 30.71,9.65 29.76,9.65 27.5,11.92 26.72,11.92 23.95,14.69 v2(23.95,16.89) v3(23.95,19.46)
  BOTTOM w0.305: v3(23.95,19.46) 24.05,19.56 U59.16
ISEN3: length 14.8
  TOP w0.508: v3(22.91,18.19) v2(22.91,15.9) 22.91,14.29 26.3,10.9 27.07,10.9 28.5,9.48 CNVBD2.8
  BOTTOM w0.305: v3(22.91,18.19) 22.99,18.1 U59.14
ISEN4: length 15.2
  TOP w0.508: v3(21.95,17.58) 21.89,17.53 21.89,13.87 v2(23.15,12.61) 25.88,9.89 26.65,9.89 27.5,9.04 CNVBD2.7
  BOTTOM w0.305: U59.13 21.97,17.6 v3(21.95,17.58)
ISET: length 6.2
  BOTTOM w0.254: U59.12 22.19,17.1 22.16,17.07 21.74,17.07 21.11,17.7 v2(21.11,17.86) 21.11,18.71 R341.1 R6579.1
ISW: length 7.6
  BOTTOM w0.305: 27.86,21.82 27.85,21.82 27.18,21.14 27.18,20.68 27.2,20.66 U59.19
  BOTTOM w0.508: 27.86,21.82 28.32,22.27 v2(28.67,22.27) 29.27,22.87 C183.1 32.23,22.87 R347.2
ISW_1: length 19.9
  TOP w0.508: Q78.3 47.06,16.13 v5(46.53,16.66)
  BOTTOM w0.508: v5(46.53,16.66) 43.05,20.14 40.08,20.14 37.2,23.01 R347.1
  vias: v2(46.41,9.91) v5(47.83,9.98) v5(48.77,10.03) v5(49.81,10.11)
ITE_DEB: length 3.6
  BOTTOM w0.114: R698.1 81.32,73.48 v2(80.49,73.48) 79.68,73.48 79.38,73.78 U31.58
JD_HP_R: length 17.4
  TOP w0.254: AUDS1.9 138.51,28 136.57,29.94 134.77,29.94 134.07,30.64 D9.2 132.26,30.64 EC704.1 132.13,30.15 131.3,29.31 128.98,29.31 v2(128.12,28.45) 127.57,27.9 126.04,27.9 125.42,28.52 R172.2
JDREF_1: length 3.4
  TOP w0.203: AUDIO1.19 122.4,31.54 122.63,31.78 123.19,31.78 v2(123.22,31.75) 123.38,31.58 R169.1
KA20GATE: length 74
  TOP w0.114: v3(62.42,137.05) 62.77,137.4 CPU1.AR31 ; v3(71.9,87.58) 72.05,87.43 75.81,87.43 76.14,87.1 76.14,85.66 v2(76.2,85.6) 76.14,85.54 76.14,82.8 74.24,80.9 74.24,79.15 75.62,77.77 Q99.S 76.17,78.15 76.89,78.15 77.67,78.93 77.67,79.69 R498.1
  BOTTOM w0.114: v3(71.9,87.58) 71.7,87.78 71.7,90.3 71.33,90.67 71.33,100.37 70.68,101.03 70.68,109.69 71.17,110.19 71.17,124.61 68.95,126.83 68.95,127.75 64.1,132.59 64.1,133.92 62.99,135.03 62.99,136.47 62.42,137.05 v3(62.42,137.05)
KA20GATE_SIO: length 8.3
  TOP w0.114: Q99.D 74.81,80.5 v2(75.34,81.03) 75.95,81.03 76.78,80.19 v3(76.78,79.55)
  BOTTOM w0.114: U6503.21 75.59,78.86 76.28,79.55 v3(76.78,79.55) 76.87,79.64 77.27,79.64 77.41,79.78 U31.46
KBCLK: length 10.7
  BOTTOM w0.114: RN11.3 66.7,64.79 67.51,65.61 v6(67.51,66.83) 67.51,66.95 68.29,67.73 U31.81 68.29,69.68 70.69,72.08 U6503.39
KBRST_N: length 91.6
  TOP w0.114: v3(86.16,88.54) 80.08,94.62 74.63,94.62 74.31,94.94 71.53,94.94 70.56,95.91 67.89,95.91 67.74,96.06 v3(63.5,96.06) ; v3(59.03,137.79) 58.95,137.71 58.95,137.59 58.76,137.4 CPU1.AR23
  BOTTOM w0.114: U6503.20 75.3,79.26 76.05,80.01 77.11,80.01 77.39,80.28 U31.45 79.5,80.28 81.25,82.04 81.25,84.15 85.65,88.54 v3(86.16,88.54) ; v3(59.03,137.79) 58.8,137.55 58.8,135.97 58.98,135.79 58.98,135.28 61.42,132.84 61.42,132.78 61.66,132.53 61.66,131.9 61.5,131.74 61.5,130.78 61.9,130.37 62.35,130.37 62.36,130.38 63.53,130.38 64.8,129.12 64.8,126.03 63.69,124.92 R497.1 63.69,122.24 65.89,120.03 65.89,114.29 v2(66.07,114.12) 66.07,110.93 66.4,110.6 66.4,109.77 65.08,108.45 65.08,106.56 63.98,105.45 63.98,104.57 63.48,104.07 63.48,96.08 v3(63.5,96.06)
KDAT: length 10.6
  BOTTOM w0.114: RN11.4 67.35,64.58 v6(68,65.23) 68,66.73 68.79,67.52 U31.80 68.79,69.63 71.09,71.92 U6503.38
LAD0_FWH0: length 128.7
  TOP w0.114: v3(48.29,101.98) 48.34,101.93 75.01,101.93 75.48,101.46 82.81,101.46 v3(87.6,96.67) 87.6,96.55 94.21,89.94 94.25,89.94 94.26,89.93 103.16,89.93 103.68,89.41 DBGH1.10 ; v3(44.58,134.02) 44.86,134.31 44.86,134.74 45.06,134.93 45.06,135.9 45.41,136.26 45.82,136.26 46.07,136.51 46.35,136.51 46.42,136.44 46.68,136.44 46.99,136.75 CPU1.AT2
  BOTTOM w0.114: v3(44.58,134.02) 44.23,134.02 42.61,132.4 42.61,117.95 47.57,112.98 47.57,106.88 48.31,106.15 v2(48.31,103.28) 48.31,102.01 v3(48.29,101.98) ; U6503.16 73.38,81.71 73.96,82.28 U31.41 79.13,82.28 79.69,82.84 79.69,84.69 87.86,92.86 87.86,95.15 87.6,95.4 v3(87.6,96.67) 88.29,97.35 RN9.4
LAD1_FWH1: length 128
  TOP w0.114: DBGH1.8 104.39,90.3 94.41,90.3 89.08,95.62 89.06,95.62 88.8,95.88 88.8,95.9 88.42,96.29 v3(88.42,96.39) 88.42,96.48 83.07,101.83 75.63,101.83 75.1,102.36 49.05,102.36 48.72,102.69 v3(47.73,102.69) ; CPU1.AT1 46,136.75 45.73,136.48 45.32,136.48 45.24,136.39 44.84,135.99 44.84,135.04 v3(44.45,134.66)
  BOTTOM w0.114: v3(47.73,102.69) v2(47.73,104.65) 47.73,106.2 47.14,106.78 47.14,112.86 42.24,117.76 42.24,132.44 v3(44.45,134.66) ; U6503.17 74.94,80.46 75.63,81.15 76.5,81.15 77.13,81.78 U31.42 79.24,81.78 80.06,82.6 80.06,84.54 88.42,92.89 v3(88.42,96.39) 88.77,96.75 89.47,96.75 89.7,96.98 89.7,97.34 RN9.3
LAD2_FWH2: length 129.1
  TOP w0.114: CPU1.AR2 46.64,137.3 46.3,136.97 45.91,136.97 45.66,136.71 44.97,136.71 44.79,136.53 v3(44.78,136.53) ; v3(47.13,103.23) 48.97,103.23 49.47,102.73 75.25,102.73 75.79,102.2 83.23,102.2 89.24,96.19 v3(89.24,96.06) 89.81,95.5 90.93,95.5 93.31,97.88 101.76,97.88 104.23,95.41 DBGH1.4
  BOTTOM w0.114: v3(47.13,103.23) 47.13,106.21 46.58,106.76 v2(46.58,109.8) 46.58,112.89 41.87,117.61 41.87,132.72 44.81,135.66 44.81,136.5 v3(44.78,136.53) ; U6503.18 75.06,80.06 75.77,80.77 76.71,80.77 77.22,81.28 U31.43 79.28,81.28 80.49,82.5 80.49,84.45 88.85,92.8 88.85,95.81 89.1,96.06 v3(89.24,96.06) 89.55,96.37 89.91,96.37 90.19,96.66 RN9.2
LAD3_FWH3: length 128.4
  TOP w0.114: v3(44.4,135.94) 44.37,135.97 44.37,136.7 44.61,136.94 45.58,136.94 45.83,137.18 46.08,137.18 CPU1.AR1 ; v3(46.7,104.1) 48.76,104.1 49.76,103.1 75.41,103.1 75.94,102.57 83.38,102.57 89.99,95.96 v3(89.99,95.94) 90.84,95.94 93.15,98.25 101.91,98.25 102.75,97.41 DBGH1.2
  BOTTOM w0.114: RN9.1 90.84,96.76 90.12,96.04 90.09,96.04 v3(89.99,95.94) 89.99,93.43 80.89,84.32 80.89,82.32 79.35,80.78 U31.44 77.3,80.78 76.91,80.39 75.91,80.39 75.18,79.66 U6503.19 ; v3(44.4,135.94) 44.4,135.77 41.5,132.87 41.5,117.45 46.02,112.93 46.02,106.48 v2(46.41,106.1) 46.7,105.81 v3(46.7,104.1)
LAN_CLKREQ_N: length 6.6
  TOP w0.114: R270.2 R285.1 v1(105.65,61.54)
  BOTTOM w0.114: v1(105.65,61.54) 106.13,62.03 v2(106.88,62.03) 108.23,62.03 108.44,62.23 LAN1.12
LAN_EEDO: length 7.5
  BOTTOM w0.114: TP69.1 120.04,65.25 116.51,65.25 115.09,63.83 LAN1.25
LAN_EESK: length 6.9
  BOTTOM w0.114: R266.1 119.48,63.07 118.29,64.26 v6(117.4,64.26) 116.71,64.26 115.48,63.03 LAN1.27
LAN_RSET: length 6.5
  BOTTOM w0.114: LAN1.31 114.66,61.43 114.88,61.21 114.88,61.04 116.2,59.72 116.66,59.72 117.49,58.89 v6(117.49,58.15) 117.49,57.25 R268.2
LAN_WAKE: length 139.7
  TOP w0.114: v3(88.56,56.52) 88.6,56.55 88.6,66.75 88.79,66.95 88.79,68.26 88.19,68.86 v2(88.19,70.05) 88.19,84.57 79.31,93.45 72.86,93.45 72.11,94.2 64.07,94.2 64.05,94.22 v3(61.87,94.22) ; v3(54.69,137.69) 54.69,137.71 CPU1.AP15
  BOTTOM w0.114: v3(61.87,94.22) 61.87,96.75 62.52,97.39 62.73,97.61 62.73,115.21 61.39,116.55 61.39,118.36 58.69,121.06 58.69,122.53 55.23,125.99 55.23,126.63 55.44,126.84 55.44,129.94 54.83,130.55 54.83,134.83 55.02,135.01 55.02,135.01 55.02,135.02 55.02,135.78 55.02,135.9 54.83,136.09 54.83,136.45 54.45,136.82 54.45,137.26 54.69,137.5 54.69,137.69 v3(54.69,137.69) ; v3(88.56,56.52) 88.6,56.52 101.51,69.42 109.13,69.42 R287.1 109.18,69.18 110.48,67.88 110.48,66.76 110.74,66.5 111.5,66.5 112.29,65.71 LAN1.21
LAN_XTAL1: length 8.1
  BOTTOM w0.114: LAN1.28 115.47,62.63 v6(115.6,62.51) 115.6,62.5 115.85,62.24 C294.1 116.98,62.24 118.85,60.38 120.11,60.38 X3.3
LAN_XTAL2: length 6.7
  BOTTOM w0.114: LAN1.29 115.13,62.23 116.17,61.2 C295.1 117.21,61.2 v6(117.83,60.58) 117.83,60.58 X3.1
LCD_5V_EN: length 7.1
  BOTTOM w0.114: U22.3 10.4,108.2 R378.1 11.14,107.46 C375.2 v2(11.14,105.74) 11.14,104.54 R379.1 10.64,104.04 Q32.3
LCD_5V_EN1: length 3.4
  BOTTOM w0.114: Q32.2 9.66,99.98 9.48,99.8 v2(9.48,99.21) R376.2
LCD_5V_EN2: length 4.4
  BOTTOM w0.114: Q32.1 v2(11.63,99.14) 11.63,97.85 R382.1 10.54,97.83 R380.2
LCD_5V_EN3: length 22.2
  TOP w0.114: v3(8.71,95.76) 8.71,97.99 v3(6.22,100.48)
  BOTTOM w0.114: v3(6.22,100.48) v2(6.22,101.3) 6.22,106.63 6.88,107.29 7.02,107.29 7.37,107.64 Q34.5 7.37,109.53 7.79,109.95 Q33.G 8.02,109.48 Q34.6 ; R382.2 10.43,95.76 R384.1 v3(8.71,95.76)
LCD_5V_EN4: length 5.4
  BOTTOM w0.114: Q34.3 6.72,106.44 7.09,106.81 8.3,106.81 8.62,106.49 8.62,105.65 v2(9.25,105.03) 9.74,104.54 R379.2
LCD_BOOST_VOUT: length 46.6
  TOP w0.508: 29.62,3.4 29.59,3.38 18.39,3.38 15.06,6.71 v3(15.06,21.97)
  BOTTOM w0.305: U59.18 26.7,21.89
  BOTTOM w0.508: v3(15.06,21.97) 15.06,22.04 16.38,23.37 21.84,23.37 21.87,23.34 v2(25.55,23.34) 26.7,22.2 26.7,21.89
  vias: v5(36.17,4.27) v5(37.31,4.24) v5(38.61,4.27) v5(39.78,4.22) v5(40.82,4.24)
LDR: length 4.9
  BOTTOM w0.305: U59.1 28.65,18.87 29.24,19.46
  BOTTOM w0.635: R346.2 30.84,21.06 v2(30.3,20.52) 29.24,19.46
LDR_1: length 17.6
  TOP w0.635: v5(45.09,16.41) 45.11,16.41 45.79,15.73 Q78.4
  BOTTOM w0.635: R346.1 v2(37.06,21.06) 37.63,21.06 39.63,19.06 42.43,19.06 v5(45.09,16.41)
LDRQ0#: length 14.7
  TOP w0.114: CPU1.AP1 45.85,137.85 45.39,137.39 44.45,137.39 43.77,136.71 43.77,135.77 42.85,134.85 41.96,134.85 41.27,134.16 41.27,133.12 41.41,132.99 41.41,130.52 v4(41.48,130.45) 41.48,130.24 43.7,128.02 R106.2
LDRQ#: length 60.4
  TOP w0.114: v3(46.2,92.94) 46.33,92.81 53.47,92.81 55.85,90.43 v3(59.33,90.43) ; R106.1 43.71,126.55 43.72,126.54 43.72,124.16 47.61,120.27 49.43,120.27 51.37,118.32 51.37,115.12 v3(51.44,115.05)
  BOTTOM w0.114: U31.5 59.79,86.96 R561.1 59.33,88.62 v3(59.33,90.43) ; v3(51.44,115.05) 51.41,115.01 51.41,99.85 v2(48.4,96.84) 46.2,94.64 v3(46.2,92.94)
LDT_PWRGD_R: length 9.4
  TOP w0.114: C23.2 53.95,163.8 R24.2 54.19,162.8 v2(54.49,162.5) 54.74,162.26 54.74,160.64 56.55,158.83 56.55,156.7 56.4,156.55 CPU1.A19
LDT_RST: length 72.2
  TOP w0.114: v3(71.05,165.95) 71.05,166.75 86.88,182.58 95.99,182.58 102.15,188.73 102.15,193.68 101.74,194.08 v2(101.7,194.08) 101.7,194.12 101.24,194.58 R483.2 ; v3(56.82,163.27) 57.33,162.76 R19.2 57.33,162.07 57.53,161.87 R20.1 58.03,160.77 58.03,159.52 57.29,158.78 57.29,156.52 57.19,156.43 57.19,156.17 57.26,156.1 57.26,155.82 56.95,155.51 CPU1.B20
  BOTTOM w0.114: v3(56.82,163.27) 56.82,163.46 58.21,164.85 58.78,164.85 59.15,165.22 60.34,165.22 60.94,165.81 61.83,165.81 62.09,166.07 69.81,166.07 69.81,166.07 70.17,166.07 70.17,166.07 70.93,166.07 v3(71.05,165.95)
LDT_RST#_BUF: length 15.9
  TOP w0.114: R483.1 100.13,196.98 v2(100.13,197.43) 100.08,197.43 99.24,198.27 89.87,198.27 88.64,197.04 HDT1.12
LDT_RST#_R: length 5.7
  TOP w0.114: C22.2 R20.2 57.53,159.98 v2(57.07,159.51) 57.07,156.61 56.95,156.49 CPU1.A20
LEDGND: length 72.7
  TOP w0.254: Q4808.S 20.06,22.73 v3(18.69,21.36) ; v3(34.75,9.96) 35.13,9.96 35.64,10.46 35.64,12.07 v3(35.71,12.14) 35.56,12.29 v3(35.56,19.18) 35.56,23.52 34.77,24.31 v3(34.77,24.33)
  BOTTOM w0.254: v3(35.56,19.18) 34.42,19.18 C181.1 33.12,17.88 R356.2 32.18,17.56 C322.2 ; v3(34.77,24.33) 31.3,24.33 C183.2 ; U59.15 23.54,18.6 22.99,19.15 v3(22.99,19.56) ; C182.2 34.07,13.13 34.6,13.13 35.35,12.38 35.42,12.38 35.66,12.14 v3(35.71,12.14) ; v3(21.06,21.06) 20.45,21.67 C177.2 19,21.67 v3(18.69,21.36) 16.99,21.36 15.09,19.46 15.09,18.53 R1030.1 16.36,18.43 Q101.S 17.55,17.81 17.55,17.27 19.53,15.29 20.29,15.29 21.29,14.3 21.29,12.85 22.77,11.37 R338.2 23.91,11.35 C178.2 26.25,11.35 R345.2 C180.2 C179.2 C323.2 29.31,11.34 R355.2 ; R341.2 22.3,18.87 v3(22.99,19.56) ; v3(34.75,9.96) 32.16,7.37 31.75,7.37 31.68,7.3 v2(31.6,7.3) 31.52,7.21 28.14,7.21 R342.2 ; v3(22.99,19.56) 23.06,19.63 23.06,20.19 23.7,20.83 v3(23.7,21.08)
  vias: v3(25.91,17.63) v3(26.7,18.32) v3(26.7,17.6) v3(26.7,16.89) v3(27.48,17.58)
LFRAMEJ_FW4: length 131.9
  TOP w0.114: v3(51.89,103.54) 51.96,103.47 75.56,103.47 76.09,102.94 83.75,102.94 88.23,98.46 v3(88.23,98.35) 90.26,98.35 90.53,98.62 102.06,98.62 102.43,98.25 108.15,98.25 108.99,97.41 DBGH1.1 ; v3(51.89,111.97) 51.5,112.36 51.5,114.43 51.88,114.81 51.88,118.34 49.54,120.68 47.73,120.68 44.13,124.27 44.13,126.54 44.14,126.55 44.14,128.11 43.37,128.88 43.27,128.88 42.18,129.97 42.18,130.69 R127.2 41.96,131.79 R133.1 41.96,133.12 41.73,133.35 41.73,133.99 42.16,134.42 43.12,134.42 43.99,135.29 43.99,136.62 44.52,137.15 45.49,137.15 45.95,137.61 46.33,137.61 46.4,137.54 46.7,137.54 47.01,137.85 CPU1.AP2
  BOTTOM w0.114: v3(51.89,103.54) 51.89,104.37 51.89,104.38 v3(51.89,111.97) ; v3(88.23,98.35) 88.23,98.24 v2(87.66,97.66) 87.17,97.17 87.17,95.21 87.41,94.96 87.41,92.93 79.33,84.84 79.33,83.03 79.08,82.78 U31.40 77.35,82.78 77.24,82.68 72.92,82.68 72.69,82.44 U6503.15
LINK*_ACTIVITY_L: length 1.2
  BOTTOM w0.381: TP64.1 R266.2
LPC_CLK0_R: length 13.2
  TOP w0.114: R102.2 47.13,122.9 45.42,124.61 v4(45.42,125.27) 45.42,126.38 45.52,126.49 45.52,128.48 46.28,129.24 46.28,133.78 CPU1.AY2
LPC_CLK1: length 88.6
  TOP w0.114: DBGH1.5 110.99,93.41 111.91,94.34 111.91,99.21 110.68,100.44 C35.1 106.87,100.45 R132.1 105.88,100.45 R126.2 104.55,100.25 103.17,100.25 102.87,100.56 92.35,100.56 91.62,101.3 v2(90.25,101.3) 88.71,101.3 87.18,102.83 84.92,102.83 84.45,103.3 76.24,103.3 75.71,103.84 53.62,103.84 v3(53.07,104.38) ; v3(52.6,112.55) 52.11,113.04 52.11,113.65 52.62,114.16 52.62,118.34 52.62,118.64 49.39,121.87 R103.1
  BOTTOM w0.114: v3(53.07,104.38) 52.72,104.74 52.72,112.33 52.6,112.45 v3(52.6,112.55)
LPC_CLK1_R: length 16.4
  TOP w0.114: CPU1.AW2 46.46,134.66 46.05,134.66 45.84,134.45 45.84,132.15 44.44,130.75 44.44,129.77 45.14,129.07 45.14,128.04 44.98,127.89 v4(44.98,127.23) 44.98,126.54 44.88,126.44 44.88,124.59 47.6,121.87 R103.2
LPC_PME_N: length 128.6
  TOP w0.114: v3(44.62,89.51) 44.62,88.94 44.34,88.67 R515.2 ; v3(44.73,75.36) 44.68,75.41 41.43,75.41 40.92,75.92 v3(39.7,75.92)
  BOTTOM w0.114: R67.1 40.63,134.39 40.63,117.02 45.12,112.53 45.12,104.84 45.66,104.3 45.66,101.74 46.08,101.31 46.08,99.22 v2(45.09,98.23) 44.73,97.87 44.73,89.62 v3(44.62,89.51) 44.62,89.05 39.7,84.14 v3(39.7,75.92) ; U6503.32 74.33,73.83 73.93,73.43 73.93,71.74 72.29,70.1 U31.73 72.29,67.18 72.13,67.03 72.13,62.86 72.43,62.56 74,62.56 74.22,62.34 74.22,60.76 72.94,59.48 67.15,59.48 66.24,58.57 54.14,58.57 45.69,67.02 45.69,72.52 44.73,73.48 v3(44.73,75.36)
LPC_SIO_CLK0: length 91.6
  TOP w0.114: v3(47.77,94.65) v2(54.74,94.65) 67.31,94.65 67.39,94.57 74.16,94.57 74.48,94.25 79.72,94.25 v3(86.16,87.81) ; v3(52.55,113.36) 52.99,113.79 52.99,118.19 52.99,118.8 49.63,122.15 49.63,122.15 48.88,122.9 R102.1
  BOTTOM w0.114: v3(86.16,87.81) 86.16,87.81 86.16,87.8 85.38,87.01 R125.2 84.23,86.39 R131.1 82.95,84.15 C34.1 81.74,82.88 81.74,81.77 79.25,79.28 U31.47 77.43,79.28 77.22,79.07 76.4,79.07 75.79,78.46 U6503.22 ; v3(52.55,113.36) 53.18,112.73 53.18,104.91 53.51,104.58 53.51,100.4 v3(47.77,94.65)
LPF: length 3.3
  BOTTOM w0.254: U59.9 26.2,14.71 25.68,14.2 v2(25.68,14.15) 25.63,14.15 25.1,13.61 C178.1
LX:
  vias: v2(45.39,5) v2(55.65,6.73) v5(46.74,8.23) v5(46.71,4.93) v5(47.8,8.26) v5(47.78,4.95) v5(48.82,8.23) v5(48.79,4.93) v5(49.81,8.23) v5(49.78,4.93) v5(51.1,6.81) v5(51.08,5.84) v5(51.08,4.83) v5(52.1,6.81) v5(52.07,5.84) v5(52.07,4.83)
M1_SMB_CLK: length 11
  TOP w0.114: NGFFE1.60 30.39,15.25 29.46,16.18 29.46,21.01 28.4,22.07 v2(28.4,22.35) 28.4,22.43 28.02,22.8 26.94,22.8 R478.1
M1_SMB_DATA: length 10
  TOP w0.114: NGFFE1.58 30.41,15.75 29.83,16.33 29.83,21.32 29.5,21.66 v2(29.5,21.75) 29.5,22.17 28.42,23.25 R479.1
M_ANALOGIN: length 1.7
  TOP w0.114: CPU1.R32 63.5,148.58 63.3,148.78 v3(63.3,148.84)
  BOTTOM w0.114: v3(63.3,148.84) 63.3,148.88 63.76,149.34 TP14.1
M_ANALOGOUT: length 2
  TOP w0.114: CPU1.N32 63.44,149.46 v3(62.91,149.46)
  BOTTOM w0.114: TP15.1 62.03,150.33 v3(62.91,149.46)
M_DP0_TXN0: length 100.8
  TOP w0.102: CPU1.B4 48.15,155.52 48.45,155.82 48.45,156.11 48.38,156.19
  TOP w0.127: 48.38,156.19 48.38,157.01 46.84,158.55 46.84,160.38 44.27,162.94 40.94,162.94 40.56,163.33 v1(40.56,164.12)
  BOTTOM w0.127: C19.2 28.08,96.09 28.96,96.09 32.26,99.39 32.26,109.25 25.3,116.21 25.3,137.8 20.58,142.52 20.58,147.07 35.64,162.13 39.19,162.13 ; 39.19,162.13 v2(39.19,161.77) ; 39.19,162.13 39.91,162.13 40.56,162.78 v1(40.56,164.12)
M_DP0_TXN1: length 101.5
  TOP w0.102: CPU1.B5 48.7,155.87 49,156.17 49,157.73 48.11,158.62 48.11,158.69 48.09,158.71
  TOP w0.127: 48.09,158.71 47.65,159.16 47.65,160.68 44.6,163.73 42.47,163.73 v1(42.12,164.08)
  BOTTOM w0.127: C21.2 28.25,94.48 28.85,94.48 33.05,98.68 33.05,109.57 26.08,116.53 26.08,138.13 21.37,142.85 21.37,146.61 35.37,160.6 39.69,160.6 41.68,162.59 ; 41.68,162.59 v2(41.91,162.36) ; 41.68,162.59 42.12,163.03 v1(42.12,164.08)
M_DP0_TXP0: length 100.7
  TOP w0.102: CPU1.A4 48.07,156.03
  TOP w0.127: v1(39.77,164.12) 39.57,164.12 39.45,163.99 39.45,163.73 39.57,163.6 40.12,163.6 40.25,163.47 40.25,163.2 40.82,162.64 44.15,162.64 46.53,160.25 46.53,158.42 48.07,156.88 48.07,156.03
  BOTTOM w0.127: 31.34,98.91 28.83,96.39 28.26,96.39 C18.2 ; 31.34,98.91 31.95,99.52 31.95,109.12 24.99,116.08 24.99,137.68 20.27,142.4 20.27,147.2 35.51,162.43 39.78,162.43 40.25,162.9 40.25,163.53 40.12,163.65 39.9,163.65 39.77,163.78 v1(39.77,164.12) ; 31.34,98.91 v2(31.11,99.14)
M_DP0_TXP1: length 101.5
  TOP w0.102: CPU1.A5 48.8,156.4 48.8,157.65 47.97,158.48 47.9,158.48 47.88,158.5
  TOP w0.127: v1(41.36,164.09) 41.05,163.78 41.05,163.63 41.17,163.5 42.21,163.5 42.29,163.42 44.48,163.42 47.34,160.56 47.34,159.03 47.88,158.5
  BOTTOM w0.127: C20.2 28.08,94.79 28.72,94.79 32.74,98.81 32.74,109.45 25.78,116.41 25.78,138 21.06,142.72 21.06,146.73 35.24,160.91 36.12,160.91 ; v1(41.36,164.09) 41.82,163.63 41.82,163.16 39.56,160.91 36.12,160.91 ; 36.12,160.91 v2(36.12,161.24)
M_VREFDQ: length 62.3
  TOP w0.127: CPU1.AC38 66.75,143.9 67.62,144.77 67.88,144.77 67.96,144.68 68.23,144.68 68.48,144.94 68.48,145.13 68.77,145.41 69.67,145.41 70.26,146
  TOP w0.254: v3(105.76,171.14) 106.23,170.67 106.23,154.94 104.95,153.67 92.51,153.67 84.02,145.19 v2(81.94,145.19) 75.21,145.19 74.4,146 70.26,146
  BOTTOM w0.254: v3(105.76,171.14) 105.76,171.14 R3.2
MCLK: length 11.4
  BOTTOM w0.114: U6503.41 69.89,72.41 67.29,69.81 U31.83 67.29,67.95 65.63,66.29 v6(65.18,66.29) 65.18,65.41 65.55,65.04 RN11.1
MCT1:
  vias: v1(130.86,53.67) v1(130.89,50.75) v1(130.91,47.75) v1(130.89,44.81) v2(130.94,55.24) v5(130.91,60.25) v5(131.01,57.89) v5(131.06,56.97)
MCT_R:
  vias: v2(128.19,59.13)
MDAT: length 10.7
  BOTTOM w0.114: U6503.40 70.29,72.29 67.79,69.79 U31.82 67.79,67.93 66.45,66.59 v6(66.45,65.38) 66.45,65.3 66.2,65.05 RN11.2
MDI0+: length 12.6
  TOP w0.102: XF1.13 118.91,55.69 118.48,55.25 117.79,55.25 117.58,55.04 116.88,55.04 U10.3 116.75,55.04 115.14,55.04 114.81,55.37 114.81,55.82 114.86,55.87 114.86,55.93 115.01,56.08 v1(115.27,56.08)
  BOTTOM w0.102: LAN1.1 113.49,59.86 113.64,59.72 113.91,59.72 114.74,58.89 ; v6(114.93,59.08) 114.74,58.89 ; 114.74,58.89 114.78,58.84 114.78,57.43 115.11,57.1 EC1.1 114.86,56.71 114.86,56.27 115.04,56.08 v1(115.27,56.08)
MDI0+_C: length 3
  TOP w0.102: L25.3 131.42,55.52 131.29,55.39 130.59,55.39 130.3,55.69 XF1.12
MDI0+_R: length 8.2
  TOP w0.102: RJ1.1 137.36,52.77 137.36,52.37 137.24,52.24 136.34,52.24 135.48,53.1 135.48,54.21 134.44,55.24 133.95,55.24 133.68,55.52 L25.4 v2(133.2,56.64)
MDI0-: length 12.7
  TOP w0.102: v1(114.4,56.06) 114.4,55.38 U10.4 114.5,55.11 114.97,54.64 117.75,54.64 117.96,54.85 118.61,54.85 118.76,54.7 XF1.14
  BOTTOM w0.102: 114.38,58.06 v6(114.1,58.06) ; 114.38,58.06 114.38,57.29 EC2.1 114.45,56.78 114.45,56.11 v1(114.4,56.06) ; 114.38,58.06 114.38,58.67 113.74,59.31 113.47,59.31 113.09,59.69 LAN1.2
MDI0-_C: length 3
  TOP w0.102: XF1.11 130.3,54.7 130.59,54.99 131.27,54.99 131.42,54.84 L25.2
MDI0-_R: length 8.3
  TOP w0.102: v2(132.66,53.7) 132.66,54.31 L25.1 134.27,54.84 135.07,54.04 135.07,52.93 136.17,51.84 137.98,51.84 RJ1.2
MDI1+: length 16.4
  TOP w0.102: XF1.16 118.93,52.72 118.54,52.32 117.64,52.32 117.09,52.87 116.81,53.15 U10.1 116.75,53.14 115.38,53.14 114.85,53.67 112.55,53.67 111.87,54.35 111.87,55.72 112.05,55.91 v1(112.26,55.91)
  BOTTOM w0.102: LAN1.4 112.29,59.62 111.94,59.27 111.94,58.95 ; 111.94,58.95 v6(112.24,58.95) ; 111.94,58.95 111.94,58.28 EC3.1 111.86,57.57 111.86,56.1 112.05,55.91 v1(112.26,55.91)
MDI1+_C: length 3
  TOP w0.102: XF1.9 130.3,52.72 130.59,52.42 131.28,52.42 131.42,52.57 L23.3
MDI1+_R: length 8.8
  TOP w0.102: v1(134.4,52.63) 134.33,52.57 L23.4
  BOTTOM w0.102: v2(133.8,53.24) 133.8,53.23 v1(134.4,52.63) 134.87,52.16 134.87,49.73 135.23,49.38 136.07,49.38 136.24,49.55 136.24,50.48 136.79,51.02 RJ1.3
MDI1-: length 16.5
  TOP w0.102: 111.94,53.7 112.38,53.26 114.06,53.26 U10.6 114.19,53.26 114.68,53.26 115.21,52.73 116.66,52.73 116.78,52.61 117.47,51.92 118.7,51.92 118.89,51.73 XF1.17 ; 111.94,53.7 111.46,54.18 111.46,55.7 v1(111.26,55.91) ; 111.94,53.7 v2(111.71,53.47)
  BOTTOM w0.102: v1(111.26,55.91) 111.45,56.1 111.45,57.7 EC4.1 111.53,58.25 111.53,59.43 111.89,59.79 LAN1.5
MDI1-_C: length 3
  TOP w0.102: XF1.8 130.3,51.73 130.59,52.02 131.29,52.02 131.42,51.89 L23.2
MDI1-_R: length 8.3
  TOP w0.102: L23.1 134.36,51.89 v1(134.4,51.85)
  BOTTOM w0.102: 134.47,49.94 134.47,49.56 135.06,48.97 135.95,48.97 136.95,47.98 RJ1.6 ; 134.47,49.94 134.47,51.78 v1(134.4,51.85) ; 134.47,49.94 v2(134.09,49.94)
MDI2+: length 22.1
  TOP w0.102: 111.95,51.11 113.27,49.79 115.63,49.79 116.17,49.25 116.55,49.25 116.61,49.31 U9.3 116.7,49.25 118.26,49.25 118.76,49.75 XF1.19 ; 111.95,51.11 108.83,54.23 108.83,55.1 109.04,55.32 v1(109.29,55.32) ; 111.95,51.11 v2(112.18,51.35)
  BOTTOM w0.102: LAN1.6 111.49,59.73 110.51,58.75 109.85,58.75 109.07,57.97 109.07,57.26 EC5.1 108.92,56.38 108.92,55.69 v1(109.29,55.32)
MDI2+_C: length 3
  TOP w0.102: XF1.6 130.3,49.75 130.59,49.45 131.38,49.45 131.51,49.58 L24.3
MDI2+_R: length 6.6
  TOP w0.102: RJ1.4 137.54,50.01 137.34,50.21 135.55,50.21 134.79,49.45 133.85,49.45 133.72,49.58 L24.4 133.1,49.68 v2(133.1,50.67)
MDI2-: length 22.1
  TOP w0.102: XF1.20 118.32,48.76 118.24,48.84 116,48.84 115.47,49.38 114.01,49.38 U9.4 113.88,49.38 113.1,49.38 109.87,52.62 ; v1(108.29,55.32) 108.42,55.19 108.42,54.06 109.87,52.62 ; 109.87,52.62 v2(109.63,52.38)
  BOTTOM w0.102: v1(108.29,55.32) 108.29,55.32 108.51,55.54 108.51,56.75 EC6.1 108.66,57.19 108.66,58.14 109.68,59.16 110.34,59.16 111.09,59.91 LAN1.7
MDI2-_C: length 3
  TOP w0.102: XF1.5 130.3,48.76 130.59,49.05 131.47,49.05 131.61,48.9 L24.2
MDI2-_R: length 6.8
  TOP w0.102: v2(132.59,47.8) 132.54,47.85 132.54,48.25 L24.1 133.72,48.9 133.85,49.04 134.96,49.04 135.72,49.8 137.17,49.8 137.4,49.57 137.4,49.31 RJ1.5
MDI3+: length 28.5
  TOP w0.102: v1(106.81,55.63) 106.69,55.63 106.45,55.39 106.45,53.85 107.42,52.88 ; 107.42,52.88 112.43,47.88 115.69,47.88 116.22,47.35 116.57,47.35 U9.1 117.85,46.19 118.45,46.19 118.58,46.32 118.58,46.65 118.7,46.78 XF1.22 ; 107.42,52.88 v2(107.67,53.12)
  BOTTOM w0.102: LAN1.9 109.5,61.03 107.56,59.1 106.34,59.1 106.09,58.85 106.09,58.02 106.33,57.78 EC7.1 106,57.17 106,56.83 106.58,56.25 106.58,55.85 v1(106.81,55.63)
MDI3+_C: length 3
  TOP w0.102: XF1.3 130.3,46.78 130.59,46.48 131.3,46.48 131.44,46.63 L22.3
MDI3+_R: length 6.9
  TOP w0.102: RJ1.7 137.3,46.74 137.3,46.1 136.99,45.79 135.42,45.79 134.73,46.49 133.89,46.49 133.75,46.63 L22.4 133.22,46.91 133.81,47.5 v2(133.81,47.8)
MDI3-: length 28.5
  TOP w0.102: v2(105.73,54.26) 106.05,54.26 ; 106.05,54.26 v1(106.05,55.63) ; 106.05,54.26 106.05,53.69 112.14,47.59 112.26,47.47 113.88,47.47 U9.6 114.01,47.47 115.52,47.47 116.05,46.94 116.53,46.94 117.68,45.79 XF1.23
  BOTTOM w0.102: v1(106.05,55.63) 106.17,55.75 106.17,56.09 105.59,56.66 105.59,57.77 EC8.1 105.68,57.89 105.68,59.02 106.17,59.5 107.39,59.5 109.32,61.43 LAN1.10
MDI3-_C: length 3
  TOP w0.102: XF1.2 130.3,45.79 130.59,46.08 131.31,46.08 131.44,45.95 L22.2
MDI3-_R: length 6.8
  TOP w0.102: v2(132.92,44.78) 132.92,45.64 L22.1 133.75,45.95 133.89,46.08 134.56,46.08 135.02,45.62 135.02,45.62 135.26,45.39 137.16,45.39 137.72,45.94 RJ1.8
MEM_MA0_CKE0: length 39.9
  TOP w0.165: DIMM1.73 v1(96.41,151.65) ; CPU1.L34 64.3,150.65 v3(63.9,151.05)
  L3 w0.152: v3(63.9,151.05) 63.83,151.05 63.68,151.2 63.68,151.53 63.83,151.68 66.85,151.68 66.89,151.65 67.52,151.65 69.25,149.92 70.04,149.92 70.25,149.71 74.43,149.71 74.59,149.86 81.9,149.86 85.94,153.9 94.16,153.9 v1(96.41,151.65)
  BOTTOM w0.165: v6(96.82,152.3) 96.82,152.07 v1(96.41,151.65)
MEM_MA0_CKE1: length 42.6
  TOP w0.165: v1(101.61,151.34) 101.62,151.35 DIMM1.74 ; CPU1.J38 66.7,151.75 v3(66.3,152.15)
  L3 w0.152: v1(101.61,151.34) 100.12,152.83 95.78,152.83 94.21,154.41 85.73,154.41 81.69,150.37 73.03,150.37 72.62,149.96 70.51,149.96 68.32,152.15 67.61,152.15 67.25,152.51 66.89,152.51 66.52,152.15 v3(66.3,152.15)
  BOTTOM w0.165: v6(101.61,152.07) v1(101.61,151.34)
MEM_MA0_CLK0_N: length 45.8
  TOP w0.178: v3(64.7,143.37) 64.63,143.37 64.3,143.7 CPU1.AC34 ; v1(97.5,141.72) 97.81,141.72 97.99,141.91 97.99,142.45 97.64,142.8 95.78,142.8 95.63,142.65 DIMM1.103
  L3 w0.102: v3(64.7,143.37) 64.7,143.72 64.79,143.81 65.81,143.81 65.99,143.63 65.99,143.21 66.61,142.59 66.92,142.59 66.95,142.56 66.98,142.56
  L3 w0.14: 66.98,142.56 67.25,142.56 67.91,143.22 68.29,143.22 68.9,142.61 70.46,142.61 72.62,140.45 73.13,140.45 73.54,140.03 74.06,140.03 74.75,140.72 75.23,140.72 75.5,140.45 84.03,140.45 85.66,138.83 93.11,138.83 96.67,142.38 97.81,142.38 97.97,142.22 97.97,141.76 97.87,141.66 97.57,141.66 v1(97.5,141.72)
  BOTTOM w0.178: v6(65.37,142.6) 64.7,143.27 v3(64.7,143.37)
MEM_MA0_CLK0_P: length 45.5
  TOP w0.178: DIMM1.101 95.71,143.25 95.81,143.15 97.79,143.15 98.35,142.6 98.35,141.84 v1(98.46,141.72) ; v3(64.72,144.4) 65.1,144.02 CPU1.AC35
  L3 w0.102: v3(64.72,144.4) 64.72,144.28 64.98,144.02 65.89,144.02 66.19,143.71 66.19,143.29 66.69,142.79 66.92,142.79 66.95,142.82 66.98,142.82
  L3 w0.14: 66.98,142.82 67.14,142.82 67.8,143.48 68.4,143.48 69.01,142.88 70.57,142.88 72.73,140.72 73.24,140.72 73.65,140.3 73.95,140.3 74.64,140.98 75.35,140.98 75.61,140.72 84.15,140.72 85.77,139.09 93,139.09 96.56,142.65 97.92,142.65 98.25,142.32 98.25,141.94 v1(98.46,141.72)
  BOTTOM w0.178: v6(64.23,144.89) 64.39,144.73 64.71,144.41 v3(64.72,144.4)
MEM_MA0_CLK1_N: length 45.7
  TOP w0.178: v3(63.86,145.65) 63.5,145.3 CPU1.AA32 ; v1(98.97,143.65) 99.47,143.15 99.85,143.15 100.66,142.35 DIMM1.104
  L3 w0.102: 66.37,145.49 66.35,145.51 66.31,145.51 65.63,146.19 64.5,146.19 63.97,145.65 v3(63.86,145.65)
  L3 w0.14: 66.37,145.49 66.94,144.92 67.86,144.92 69.2,143.58 70.79,143.58 72.74,141.62 84.54,141.62 86.17,140 92.53,140 95.79,143.26 98.58,143.26 v1(98.97,143.65)
  BOTTOM w0.178: v1(98.97,143.65) v6(99.34,144.4)
MEM_MA0_CLK1_P: length 45.7
  TOP w0.178: v3(64.77,145.45) 64.75,145.45 CPU1.AA34 ; DIMM1.102 101.98,142.95 101.73,142.71 100.8,142.71 99.93,143.58 v1(99.93,143.65)
  L3 w0.102: v3(64.77,145.45) 64.54,145.45 64.37,145.62 64.37,145.77 64.58,145.98 65.54,145.98 66.16,145.36 66.16,145.32 66.18,145.3
  L3 w0.14: 66.18,145.3 66.83,144.65 67.75,144.65 69.09,143.31 70.68,143.31 72.63,141.35 84.43,141.35 86.05,139.73 92.64,139.73 95.9,142.99 98.69,142.99 98.87,143.17 99.19,143.17 99.67,143.65 v1(99.93,143.65)
  BOTTOM w0.178: v1(99.93,143.65) v6(99.72,142.9)
MEM_MA0_CS_L0: length 44
  TOP w0.165: v3(64.82,140.04) 64.3,140.56 CPU1.AJ34 ; DIMM1.114 100.95,139.35 v1(99.77,140.53)
  L3 w0.152: v3(64.82,140.04) 64.82,140.31 65.2,140.69 70.33,140.69 72.84,138.18 83.22,138.18 84.75,136.65 93.07,136.65 96.22,139.8 99.04,139.8 v1(99.77,140.53)
  BOTTOM w0.165: v1(99.77,140.53) 100.2,140.1 v6(100.2,139.94)
MEM_MA0_CS_L1: length 40.6
  TOP w0.165: CPU1.AR38 66.71,137.3 67.11,137.7 v3(67.11,137.73) ; v1(97.77,136.62) 97.27,137.13 96.32,137.13 96.2,137.25 DIMM1.121
  L3 w0.152: v1(97.77,136.62) 97.27,136.13 96.2,136.13 93.17,133.1 79.02,133.1 78.87,133.25 78.87,134.47 78.71,134.62 78.38,134.62 78.23,134.47 78.23,133.91 78.08,133.76 77.75,133.76 77.6,133.91 77.6,134.47 77.44,134.62 72.75,134.62 70.66,136.71 68.14,136.71 v3(67.11,137.73)
  BOTTOM w0.165: v6(98.45,136.4) 98,136.4 v1(97.77,136.62)
MEM_MA0_ODT0: length 43.2
  TOP w0.165: CPU1.AN38 66.7,138.16 v1(66.32,137.78) ; v1(100.69,137.82) 101.62,138.75 DIMM1.116
  L3 w0.102: v1(66.32,137.78) 66.68,138.14 67.28,138.14 67.68,137.74 68.4,137.74
  L3 w0.152: v1(100.69,137.82) 100,137.13 96.7,137.13 93.17,133.6 79.55,133.6 79.4,133.76 79.4,134.98 79.25,135.13 72.88,135.13 70.27,137.74 68.4,137.74
  BOTTOM w0.165: v6(100.99,138.56) v1(100.69,137.82)
MEM_MA0_ODT1: length 42.1
  TOP w0.165: CPU1.AU38 66.35,136.55 v3(66.35,136.81) ; v1(100.69,136.35) 101.32,136.98 101.75,136.98 102.32,137.55 DIMM1.120
  L3 w0.152: v3(66.35,136.81) 66.88,136.28 70.37,136.28 72.55,134.1 76.67,134.1 78.18,132.59 93.16,132.59 96.34,135.76 100.1,135.76 v1(100.69,136.35)
  BOTTOM w0.165: v6(101.07,136.94) 101.07,136.73 v1(100.69,136.35)
MEM_MA_ADD0: length 42.6
  TOP w0.165: DIMM1.98 v1(101.6,144.15) ; CPU1.AG38 66.7,141.88 v3(66.29,142.29)
  L3 w0.152: v3(66.29,142.29) 70.22,142.29 72.76,139.76 83.82,139.76 85.39,138.18 93.05,138.18 96.09,141.22 98.89,141.22 101.6,143.94 v1(101.6,144.15)
  BOTTOM w0.165: v1(101.6,144.15) v6(102.31,144.15)
MEM_MA_ADD1: length 39.6
  TOP w0.165: CPU1.W35 65.1,146.25 v3(64.7,146.65) ; DIMM1.97 96.06,144.45 96.32,144.2 v1(96.62,144.2)
  L3 w0.102: 67.61,146.62 67.37,146.86 66.67,146.86 66.48,147.06 64.9,147.06 64.7,146.86 v3(64.7,146.65)
  L3 w0.152: v1(96.62,144.2) 94.84,144.2 91.79,141.15 86.77,141.15 86.13,141.78 86.13,142 86.39,142.25 86.39,142.47 86.17,142.68 85.96,142.68 85.7,142.43 85.49,142.43 85.14,142.77 72.42,142.77 70.31,144.88 69.01,144.88 68.34,145.55 68.34,145.9 67.61,146.62
MEM_MA_ADD2: length 43.3
  TOP w0.165: v3(66.3,146.65) 66.7,146.25 CPU1.W38 ; DIMM1.96 100.71,144.75 v1(99.84,145.61)
  L3 w0.152: v1(99.84,145.61) 97.95,143.71 95.22,143.71 92.15,140.64 86.43,140.64 84.81,142.27 72.45,142.27 70.19,144.53 68.71,144.53 66.75,146.48 66.47,146.48 v3(66.3,146.65)
  BOTTOM w0.165: v6(100.48,145.06) v1(99.84,145.61)
MEM_MA_ADD3: length 44.4
  TOP w0.165: v3(63.9,146.65) 64.3,146.25 CPU1.W34 ; DIMM1.95 96,145.05 96.2,144.85 98.14,144.85 v1(98.66,145.38)
  L3 w0.102: v3(63.9,146.65) 64.51,147.26 66.68,147.26 66.8,147.14 67.45,147.14 67.79,146.8
  L3 w0.152: v1(98.66,145.38) 98.19,144.91 94.81,144.91 91.56,141.66 87.93,141.66 86.18,143.41 85.31,143.41 85.31,143.41 73.12,143.41 71.19,145.33 69.11,145.33 68.6,145.85 68.6,146 67.79,146.8
  BOTTOM w0.165: v6(63.91,147.34) 63.91,147.32 63.9,147.18 v3(63.9,146.65)
MEM_MA_ADD4: length 43.8
  TOP w0.165: v1(101.61,145.95) DIMM1.92 ; CPU1.U38 66.7,147.35 v3(66.3,147.75)
  L3 w0.102: 67.97,146.98 67.61,147.35 66.9,147.35 66.5,147.75 v3(66.3,147.75)
  L3 w0.152: v1(101.61,145.95) 101.13,146.43 99.02,146.43 97.89,145.3 94.4,145.3 91.39,148.31 88.54,148.31 84.15,143.92 75.51,143.92 75.3,143.71 73.21,143.71 71.96,144.97 71.96,144.97 71.31,145.61 69.23,145.61 68.85,145.99 68.85,146.11 67.97,146.98
  BOTTOM w0.165: v1(101.61,145.95) v6(101.61,146.71)
MEM_MA_ADD5: length 39.2
  TOP w0.165: v3(65.5,147.75) 65.9,147.35 CPU1.U37 ; DIMM1.91 96.37,146.25 v1(96.77,145.85)
  L3 w0.102: v3(65.5,147.75) 65.5,147.95 65.71,148.16 67.25,148.16 67.61,147.8 67.61,147.71 67.81,147.51
  L3 w0.152: v1(96.77,145.85) 94.59,145.85 91.62,148.82 88.32,148.82 83.93,144.42 74.75,144.42 74.55,144.63 73.81,144.63 73.53,144.35 72.94,144.35 71.34,145.95 70.24,145.95 69.67,146.51 68.81,146.51 67.81,147.51
MEM_MA_ADD6: length 45.6
  TOP w0.165: CPU1.U34 64.3,147.35 v3(64.7,147.75) ; v1(99.77,147.73) 100.95,146.55 DIMM1.90
  L3 w0.152: v1(99.77,147.73) 98.54,146.5 94.7,146.5 91.87,149.33 88.11,149.33 83.72,144.93 72.71,144.93 71.32,146.33 70.22,146.33 69.78,146.77 68.91,146.77 67.85,147.83 67.85,147.88 67.34,148.39 65.34,148.39 v3(64.7,147.75)
  BOTTOM w0.165: v6(99.92,147.02) v1(99.77,147.73)
MEM_MA_ADD7: length 45.5
  TOP w0.165: DIMM1.86 v1(101.6,147.75) ; v3(64.7,148.85) 65.1,148.45 CPU1.R35
  L3 w0.102: 67.08,148.93 66.79,148.93 66.47,149.26 65.11,149.26 v3(64.7,148.85)
  L3 w0.152: v1(101.6,147.75) 101.01,148.34 98.22,148.34 97.87,147.98 97.87,147.86 97.22,147.21 95.46,147.21 92.33,150.34 87.69,150.34 83.29,145.95 72.69,145.95 71.81,146.83 70.44,146.83 69.99,147.28 69.12,147.28 68.72,147.68 68.72,147.73 67.52,148.93 67.08,148.93
  BOTTOM w0.165: v6(101.75,148.62) v1(101.6,147.75)
MEM_MA_ADD8: length 42.4
  TOP w0.165: CPU1.R38 66.7,148.45 v3(66.3,148.85) ; v1(98.42,147.85) 97.42,146.85 DIMM1.89
  L3 w0.152: v3(66.3,148.85) 66.49,148.66 67.43,148.66 68.45,147.64 68.45,147.59 69.02,147.02 69.89,147.02 70.33,146.58 71.63,146.58 72.77,145.44 83.51,145.44 87.9,149.83 92.1,149.83 95.08,146.86 97.43,146.86 v1(98.42,147.85)
  BOTTOM w0.165: v1(98.42,147.85) v6(98.42,147.12)
MEM_MA_ADD9: length 39.9
  TOP w0.165: CPU1.N38 66.7,149.55 v3(66.3,149.95) ; DIMM1.85 v1(96.39,148.05)
  L3 w0.102: v3(66.3,149.95) 66.46,149.95 66.97,149.44 67.36,149.44
  L3 w0.152: v1(96.39,148.05) 96.09,148.05 92.79,151.36 87.25,151.36 82.85,146.96 81.83,146.96 81.52,147.27 81.22,147.27 80.92,146.96 80.61,146.96 80.31,147.27 80,147.27 79.7,146.96 79.39,146.96 79.09,147.27 78.78,147.27 78.48,146.96 78.17,146.96 77.87,147.27 77.56,147.27 77.26,146.96 76.95,146.96 76.65,147.27 76.34,147.27 76.04,146.96 75.51,146.96 75.36,147.12 75.36,147.29 75.21,147.45 74.9,147.45 74.75,147.29 74.75,147.12 74.6,146.96 74.29,146.96 74.14,147.12 74.14,147.29 73.99,147.45 73.69,147.45 73.53,147.29 73.53,147.12 73.38,146.96 72.9,146.96 72.43,147.43 70.58,147.43 69.36,148.65 68.52,148.65 67.73,149.44 67.36,149.44
  BOTTOM w0.165: v6(96.39,148.77) v1(96.39,148.05)
MEM_MA_ADD10: length 40.8
  TOP w0.165: CPU1.AG34 64.09,141.49 v3(64.09,141.16) ; DIMM1.107 96.16,141.45 96.37,141.24 96.83,141.24 97.36,140.71 v1(97.41,140.71)
  L3 w0.152: v1(97.41,140.71) 96.08,140.71 93.04,137.67 85.16,137.67 83.61,139.23 72.78,139.23 70.72,141.29 68.37,141.29 67.75,141.91 66.53,141.91 66.47,141.86 65.05,141.86 64.78,141.59 64.57,141.59 64.14,141.16 v3(64.09,141.16)
  BOTTOM w0.165: v1(97.41,140.71) v6(98.12,140.71)
MEM_MA_ADD11: length 46.7
  TOP w0.165: v3(64.01,148.88) 64.3,148.59 CPU1.R34 ; v1(99.78,149.49) 100.93,148.35 DIMM1.84
  L3 w0.102: v3(64.01,148.88) 64.59,149.46 66.64,149.46 66.92,149.19 67.09,149.19
  L3 w0.152: v1(99.78,149.49) 99.08,148.79 97.43,148.79 96.88,148.23 96.88,147.85 96.59,147.57 95.84,147.57 92.56,150.85 87.48,150.85 83.08,146.46 72.77,146.46 72.14,147.09 70.54,147.09 70.1,147.53 69.24,147.53 68.98,147.79 68.98,147.83 67.62,149.19 67.09,149.19
  BOTTOM w0.165: v6(100.33,148.95) v1(99.78,149.49)
MEM_MA_ADD12: length 42.3
  TOP w0.165: v3(65.5,149.95) 65.9,149.55 CPU1.N37 ; DIMM1.83 97.19,148.65 v1(98.32,149.78)
  L3 w0.102: 67.67,149.97 67.28,150.36 65.91,150.36 v3(65.5,149.95)
  L3 w0.152: 67.67,149.97 68.74,148.9 69.48,148.9 70.6,147.78 82.9,147.78 86.98,151.87 93.6,151.87 96.1,149.37 97.91,149.37 v1(98.32,149.78)
  BOTTOM w0.165: v6(98.96,150.11) v1(98.32,149.78)
MEM_MA_ADD13: length 39.4
  TOP w0.165: DIMM1.119 96.49,137.85 v1(96.73,137.62) ; v3(64.08,138.99) 64.08,138.62 CPU1.AN34
  L3 w0.102: v3(64.08,138.99) 64.73,138.34 67.43,138.34 67.78,137.99 68.4,137.99
  L3 w0.152: v1(96.73,137.62) 96.67,137.62 93.55,134.49 93.55,134.48 93.18,134.11 80.09,134.11 79.93,134.26 79.93,135.48 79.78,135.64 72.86,135.64 70.51,137.99 68.4,137.99
MEM_MA_ADD14: length 42.2
  TOP w0.165: CPU1.L38 66.7,150.65 v3(66.3,151.05) ; DIMM1.80 v1(101.61,149.55)
  L3 w0.152: v1(101.61,149.55) 101.34,149.82 100.46,150.7 96.05,150.7 95.42,151.33 94.1,152.64 93.86,152.88 86.4,152.88 82.36,148.84 70.3,148.84 69.74,149.41 68.95,149.41 67.31,151.05 v3(66.3,151.05)
  BOTTOM w0.165: v1(101.61,149.55) v6(101.61,150.29)
MEM_MA_ADD15: length 44.2
  TOP w0.165: DIMM1.78 101.05,150.15 v1(99.78,151.41) ; CPU1.L35 65.1,150.65 v3(64.7,151.05)
  L3 w0.102: 66.87,151.33 66.64,151.33 66.51,151.46 65.11,151.46 v3(64.7,151.05)
  L3 w0.152: v1(99.78,151.41) 99.47,151.09 96.2,151.09 93.91,153.39 86.15,153.39 82.11,149.35 70.18,149.35 69.86,149.66 69.05,149.66 67.39,151.33 66.87,151.33
  BOTTOM w0.165: v1(99.78,151.41) v6(99.09,151.59)
MEM_MA_BANK0: length 40.7
  TOP w0.165: CPU1.AJ38 66.7,140.3 v3(67.01,139.99) ; v1(98.22,139.2) 96.57,140.85 DIMM1.109
  L3 w0.152: v3(67.01,139.99) 67.63,139.99 68.55,139.06 70.95,139.06 72.85,137.17 81.43,137.17 81.58,137.01 81.58,135.79 81.74,135.64 93.06,135.64 96.23,138.81 97.83,138.81 v1(98.22,139.2)
  BOTTOM w0.165: v1(98.22,139.2) v6(99.01,139.2)
MEM_MA_BANK1: length 44.1
  TOP w0.165: CPU1.AG35 64.75,141.35 v3(64.75,141.16) ; v1(100.7,141.7) 101.24,141.15 DIMM1.108
  L3 w0.152: v1(100.7,141.7) 100.19,141.7 98.65,140.16 96.07,140.16 93.08,137.17 84.95,137.17 83.4,138.71 72.79,138.71 70.56,140.95 68.35,140.95 67.64,141.66 66.63,141.66 66.58,141.6 65.19,141.6 v3(64.75,141.16)
  BOTTOM w0.165: v6(101.02,142.52) v1(100.7,141.7)
MEM_MA_BANK2: length 39.5
  TOP w0.165: v3(64.7,149.95) 64.3,149.55 CPU1.N34 ; v1(96.39,149.85) DIMM1.79
  L3 w0.152: v3(64.7,149.95) 64.11,149.95 63.96,150.1 63.96,150.46 64.11,150.61 67.39,150.61 68.84,149.16 69.63,149.16 70.45,148.34 82.57,148.34 82.62,148.38 82.62,148.38 86.61,152.37 93.87,152.37 v1(96.39,149.85)
MEM_MA_CAS#: length 43.7
  TOP w0.165: v3(64.77,139) 64.77,139.03 CPU1.AL34 ; DIMM1.115 95.85,139.05 96.13,138.77 97.38,138.77 v1(98.53,137.62)
  L3 w0.102: v3(64.77,139) 65.21,138.56 67.62,138.56 67.87,138.3 68.4,138.3
  L3 w0.152: v1(98.53,137.62) 98.04,138.1 96.53,138.1 93.05,134.62 80.62,134.62 80.47,134.77 80.47,135.99 80.31,136.14 72.9,136.14 70.74,138.3 68.4,138.3
  BOTTOM w0.165: v6(99.42,137.69) v1(98.53,137.62)
MEM_MA_DATA0: length 54.2
  TOP w0.102: 66.63,160.21 66.19,160.21 62.7,156.72 62.7,156.15 62.75,156.09 62.75,155.82 62.45,155.52 CPU1.B30
  TOP w0.165: v1(98.22,175.08) 98.22,174.78 98.06,174.61 96.2,174.61 96.04,174.45 DIMM1.5 ; v3(95.48,178.23) 95.48,178.23 94.56,179.14 87.68,179.14 v2(82.93,174.4) 68.74,160.21 66.63,160.21
  L3 w0.152: v1(98.22,175.08) 95.97,177.33 95.43,177.33 94.58,178.18 94.58,178.4 94.84,178.66 95.05,178.66 v3(95.48,178.23)
MEM_MA_DATA1: length 54.3
  TOP w0.102: CPU1.A32 63.55,157.28 66.19,159.92 69.39,159.92 69.78,160.31
  TOP w0.165: 69.78,160.31 v2(81.29,171.82) 87.95,178.48 92.63,178.48 92.8,178.32 92.8,177.95 92.95,177.8 93.31,177.8 93.46,177.95 93.46,178.32 93.63,178.48 94.29,178.48 95.45,177.32 96.7,177.32 96.85,177.16 96.85,176.72 96.7,176.56 v3(95.55,176.56) ; v1(97.13,174.08) 96.9,173.85 DIMM1.7
  L3 w0.152: v1(97.13,174.08) 97.29,174.08 97.49,174.28 97.49,174.73 97.33,174.88 96.73,174.88 96.47,175.14 96.47,175.35 96.85,175.73 96.85,175.95 96.61,176.19 96.39,176.19 96.04,175.83 95.82,175.83 95.43,176.22 95.43,176.44 v3(95.55,176.56)
MEM_MA_DATA2: length 51.3
  TOP w0.102: 66,157.42 65.78,157.19 65.78,156.82 65.56,156.61 65.56,156.25 65.53,156.18 65.45,156.1 65.45,155.85 CPU1.B35
  TOP w0.165: v3(88.14,174.5) 88.14,173.37 v2(81.13,166.36) 75.08,160.32 74.28,160.32 72.44,158.47 67.06,158.47 66,157.42 ; v1(96.75,171.65) 96.55,171.45 DIMM1.15
  L3 w0.152: v3(88.14,174.5) 88.14,172.42 88.29,172.26 88.65,172.26 88.8,172.42 88.8,175.17 88.93,175.3 89.37,175.3 89.5,175.17 89.5,174.27 89.65,174.12 89.99,174.12 90.15,174.27 90.15,175.17 90.27,175.3 93.19,175.3 94.85,173.63 94.85,173.34 96.54,171.65 v1(96.75,171.65)
MEM_MA_DATA3: length 53.3
  TOP w0.102: CPU1.A36 65.76,155.98 65.76,156.52 65.98,156.74 65.98,156.95 66.25,157.22
  TOP w0.165: v1(98.3,171.63) 99.09,171.63 99.24,171.48 99.24,171 99.09,170.85 DIMM1.17 ; v3(93.07,174.62) 92.86,174.83 91.69,174.83 91.54,174.68 91.54,173.74 91.39,173.58 91.01,173.58 90.86,173.74 90.86,174.65 90.7,174.8 90.32,174.8 90.17,174.65 90.17,173.86 90.02,173.71 89.64,173.71 89.48,173.86 89.48,174.68 89.33,174.83 88.95,174.83 88.8,174.68 88.8,173.1 v2(79.72,164.02) 75.47,159.77 74.37,159.77 72.77,158.17 67.2,158.17 66.25,157.22
  L3 w0.152: v3(93.07,174.62) 96.52,171.17 97.82,171.17 98.27,171.63 v1(98.3,171.63)
MEM_MA_DATA4: length 55
  TOP w0.102: CPU1.B29 61.9,155.87 62.2,156.17 62.2,156.86 62.73,157.39
  TOP w0.165: DIMM1.4 v1(101.6,174.75) ; 62.73,157.39 66.25,160.91 67.56,160.91 v2(79.6,172.94) 87.13,180.47 95.15,180.47 v3(97.54,178.08)
  L3 w0.152: v3(97.54,178.08) 97.54,177.16 98.87,175.82 100.53,175.82 v1(101.6,174.75)
MEM_MA_DATA5: length 53.7
  TOP w0.102: 66.61,160.58 66.27,160.58 62.45,156.76 CPU1.A30
  TOP w0.165: v1(100.05,174.7) 100.6,174.15 DIMM1.6 ; 66.61,160.58 68.17,160.58 v2(78.16,170.57) 87.4,179.81 94.87,179.81 v3(96.85,177.83)
  L3 w0.152: v3(96.85,177.83) 96.85,177.15 98.56,175.44 99.31,175.44 v1(100.05,174.7)
MEM_MA_DATA6: length 52.7
  TOP w0.102: CPU1.A34 64.65,157.14 65.61,158.1 65.87,158.1
  TOP w0.165: 65.87,158.1 66.83,159.05 71.88,159.05 v2(79.07,166.25) 88.36,175.53 92.85,175.53 93.04,175.72 v3(93.04,176.45) ; v1(101.61,170.92) 101.84,171.15 DIMM1.16
  L3 w0.152: v3(93.04,176.45) 95.56,173.93 95.56,173.64 96.66,172.54 99.91,172.54 99.91,172.54 102.16,172.54 102.31,172.39 102.31,171.98 102.16,171.83 101.76,171.83 101.61,171.68 v1(101.61,170.92)
MEM_MA_DATA7: length 51.2
  TOP w0.102: CPU1.B34 64.65,155.52 64.95,155.82 64.95,156.08 64.87,156.15 64.87,157.07 65.2,157.4 65.58,157.4 66.08,157.9
  TOP w0.165: DIMM1.18 102.22,170.55 102.11,170.43 100.61,170.43 v1(99.95,171.09) ; v3(87.43,173.61) v2(82.67,168.85) 74.68,160.86 74.3,160.86 72.21,158.77 66.95,158.77 66.08,157.9
  L3 w0.152: v3(87.43,173.61) 87.43,174.75 88.62,175.95 93.04,175.95 95.21,173.78 95.21,173.49 96.51,172.19 98.42,172.19 99.52,171.09 v1(99.95,171.09)
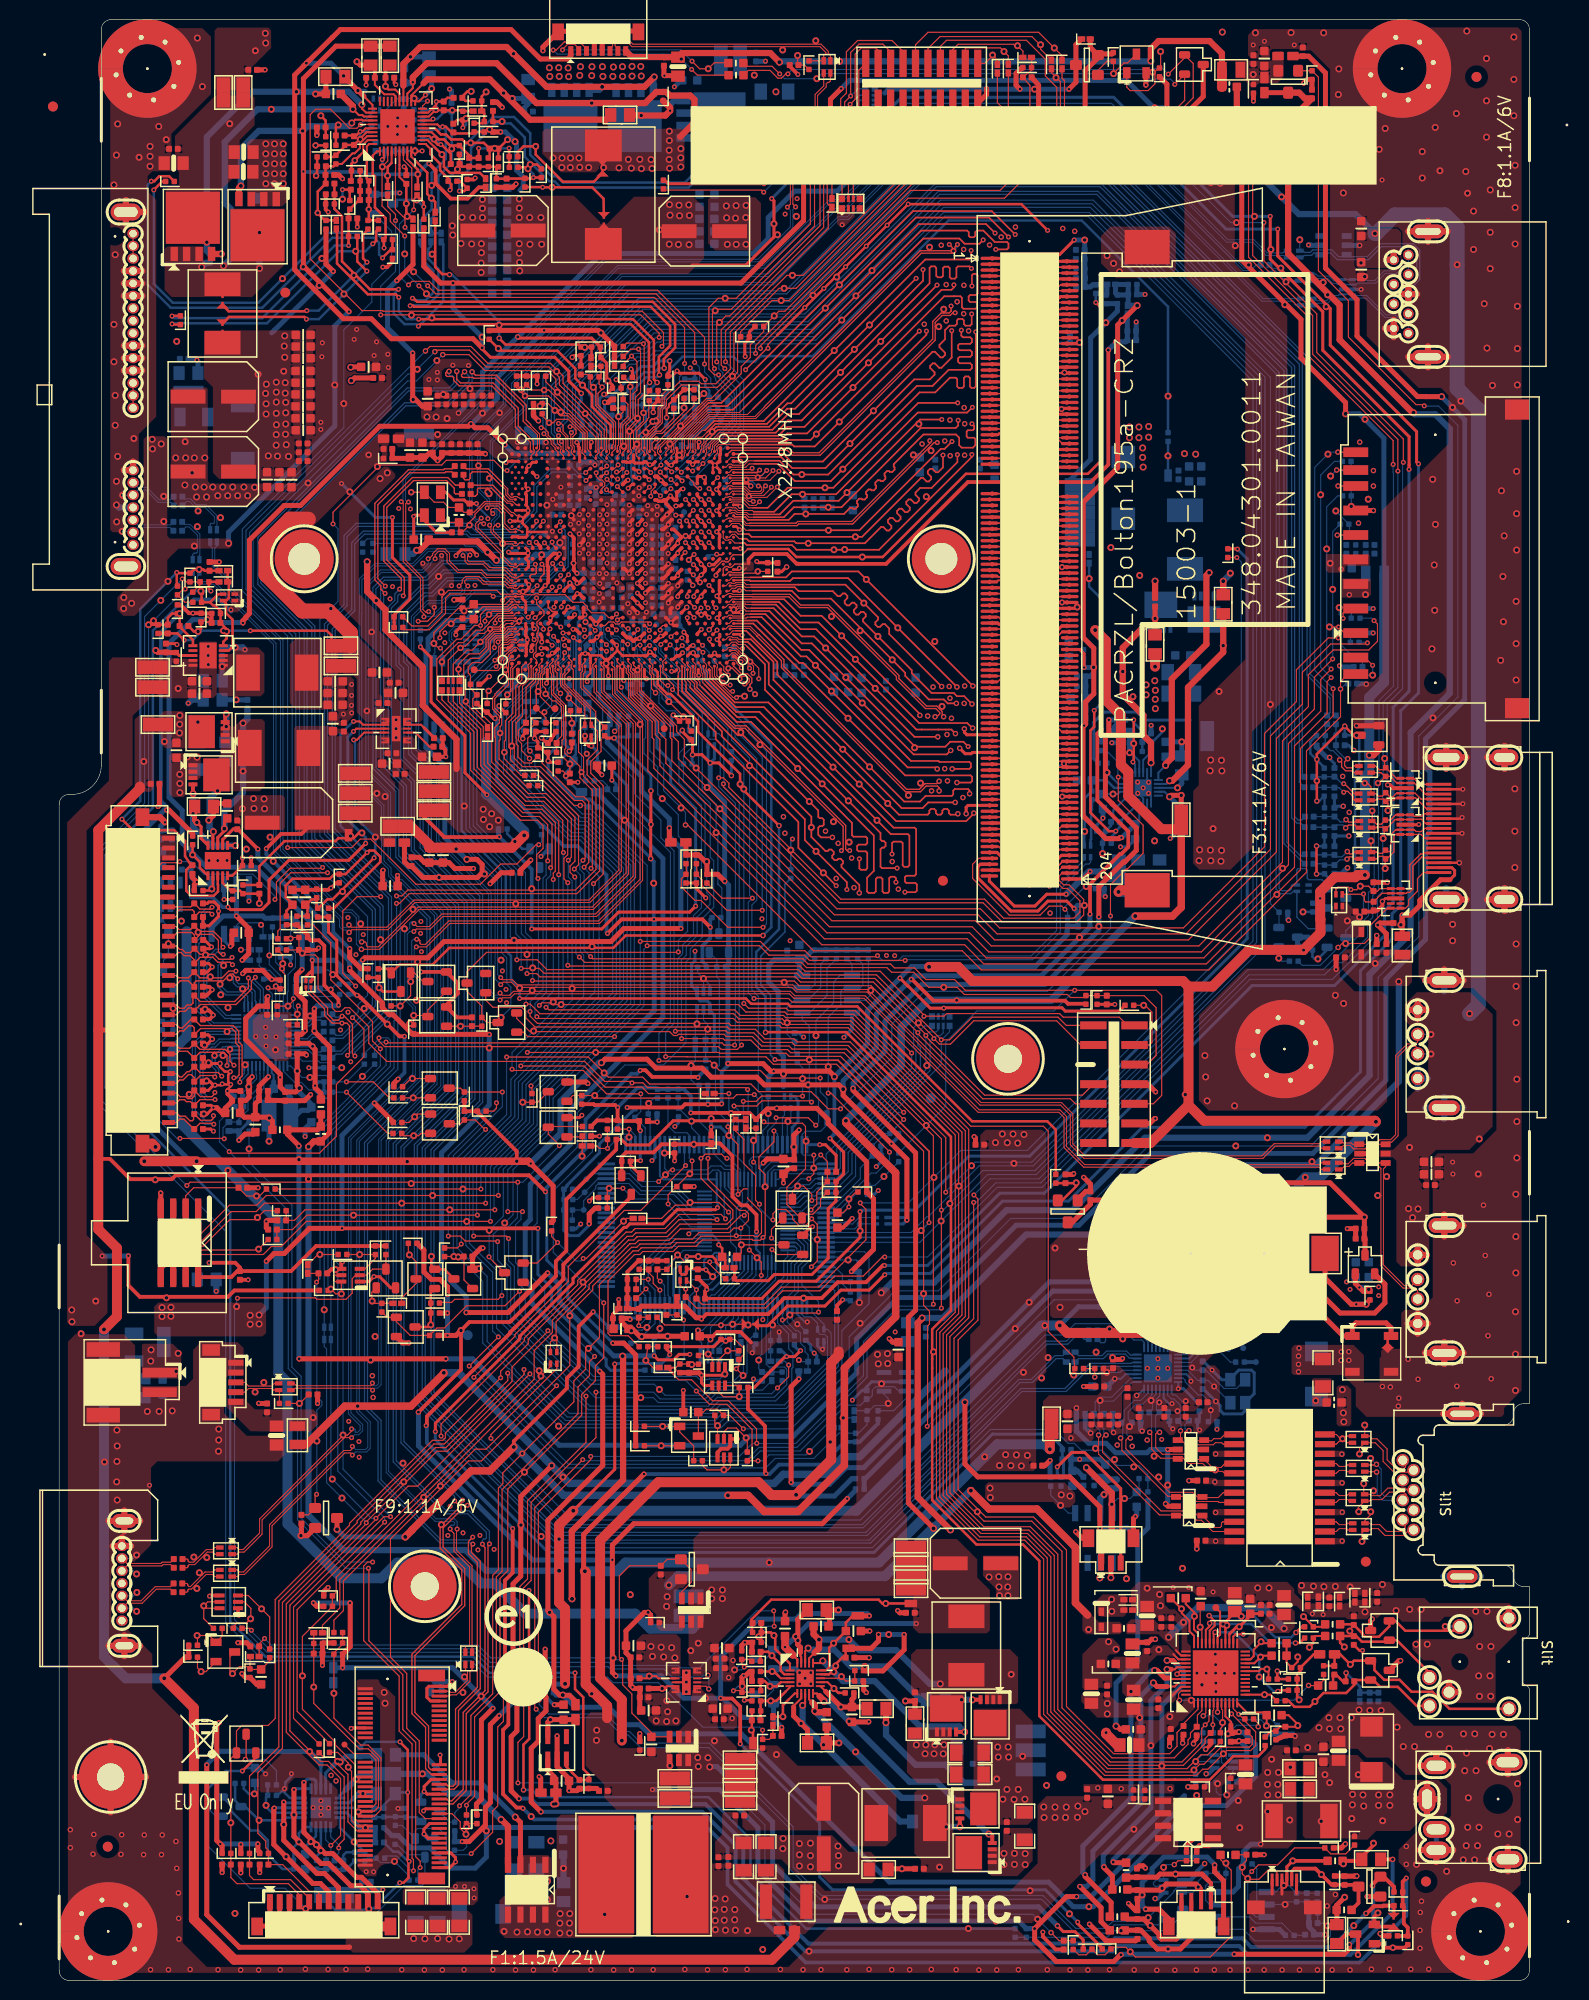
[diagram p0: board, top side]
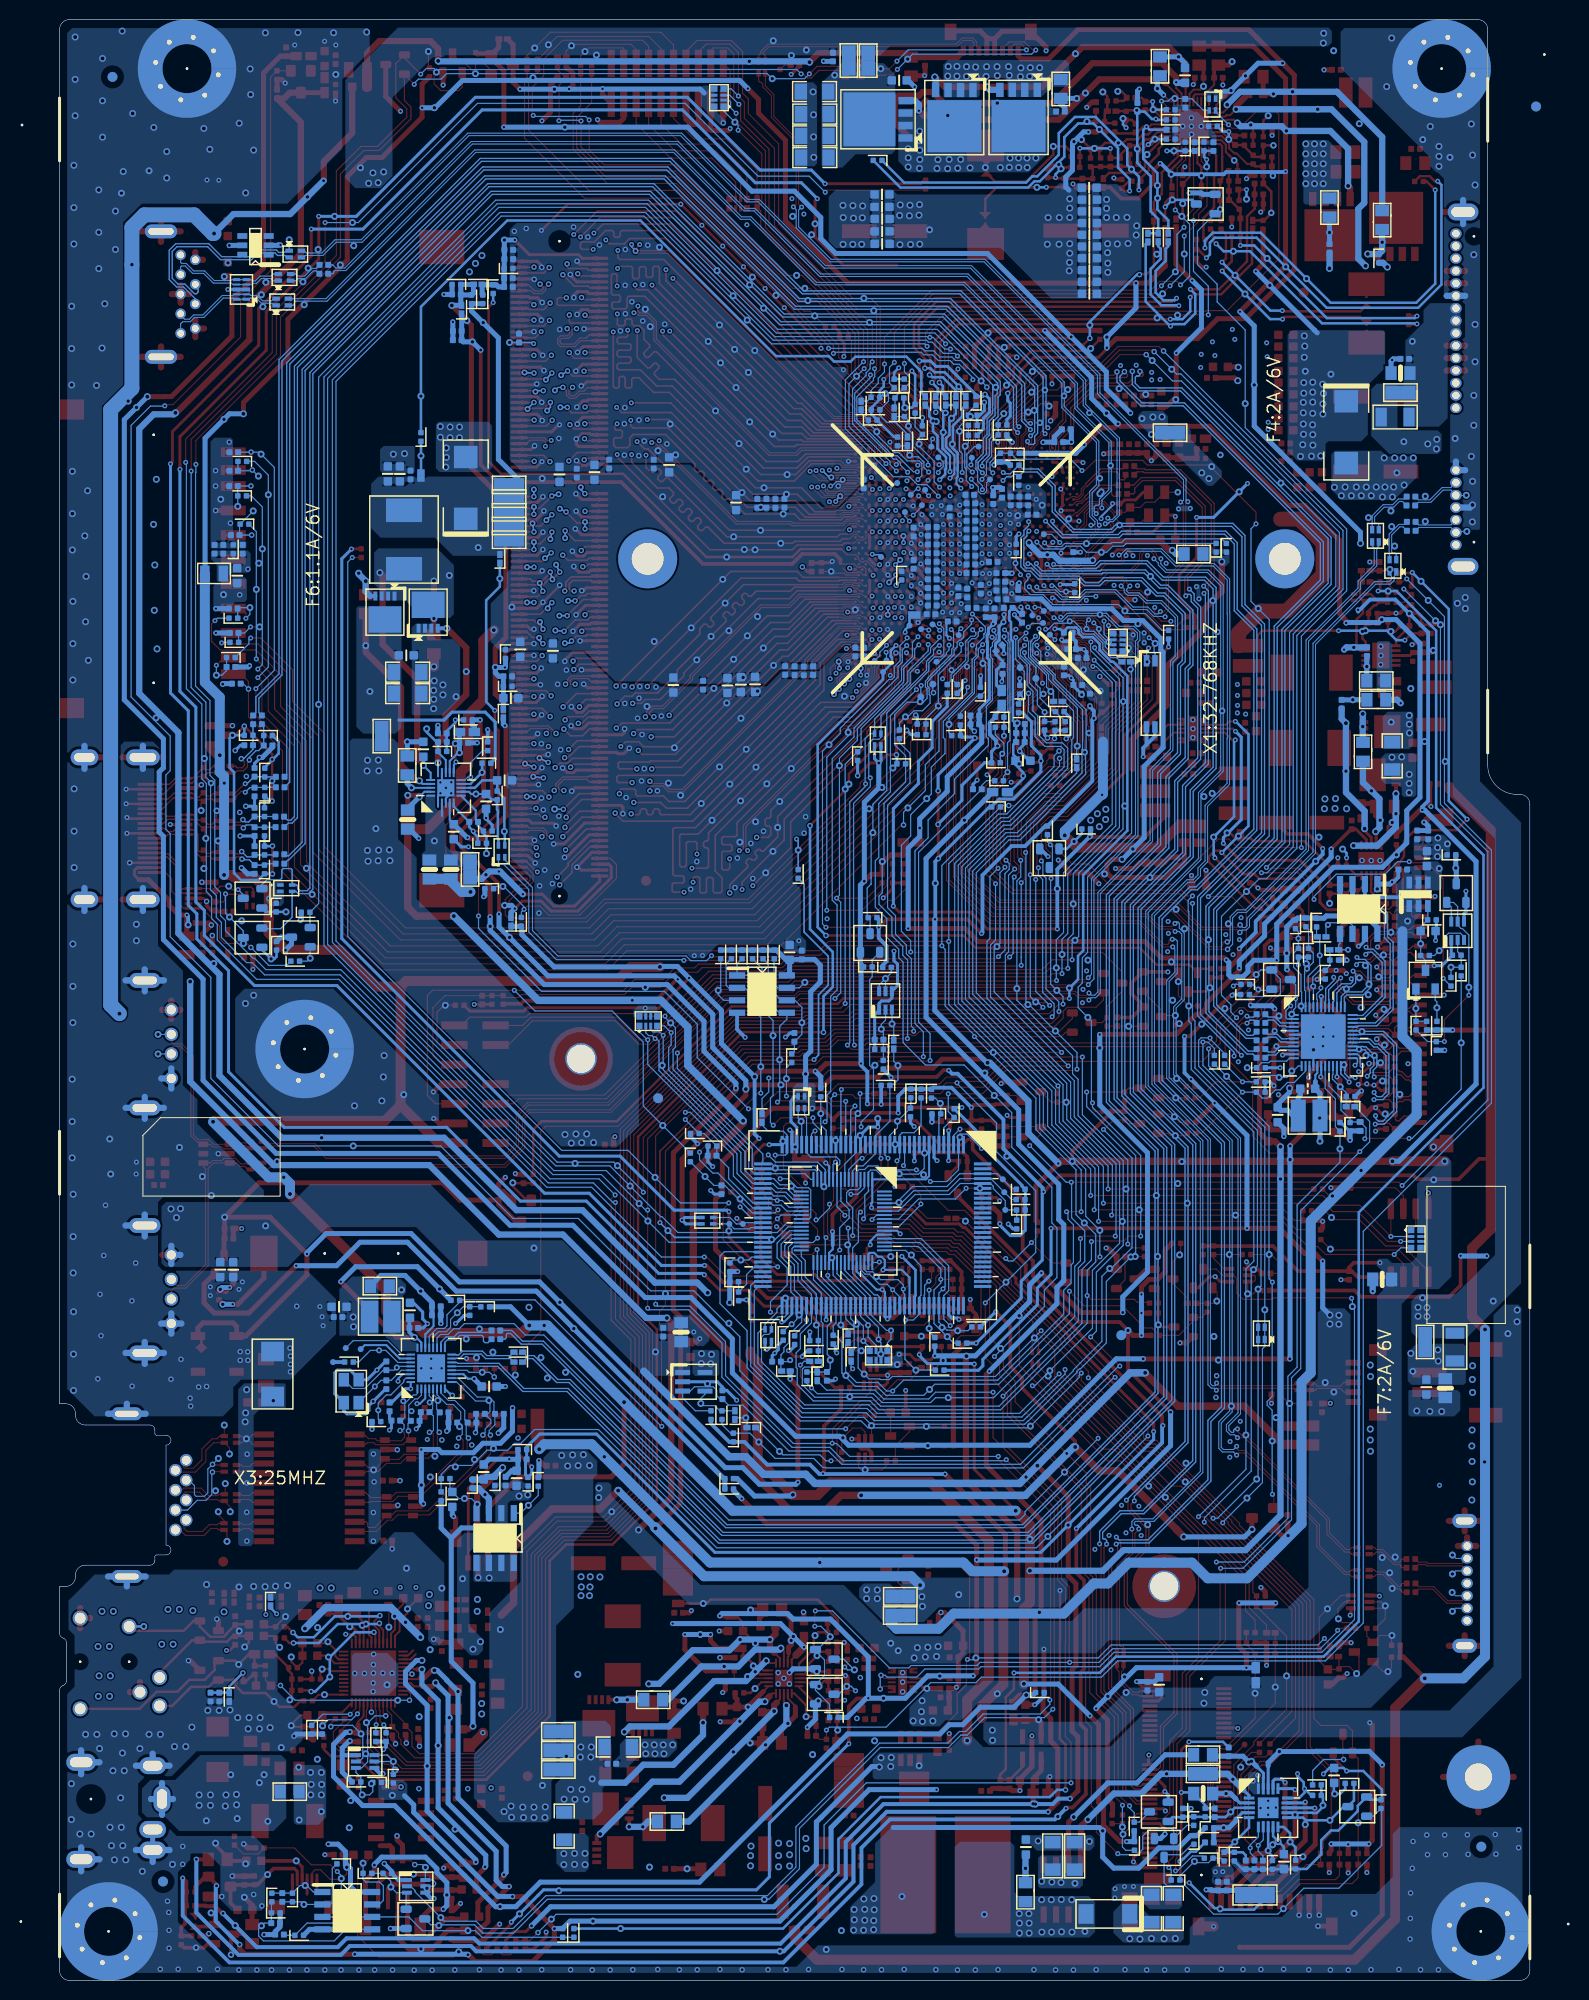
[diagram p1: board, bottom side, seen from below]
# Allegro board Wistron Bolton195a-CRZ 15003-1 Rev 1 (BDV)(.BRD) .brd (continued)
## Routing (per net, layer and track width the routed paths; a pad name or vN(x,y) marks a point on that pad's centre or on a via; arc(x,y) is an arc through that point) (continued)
MEM_MA_DATA8: length 48.1
  TOP w0.102: 68.05,157.25 67.33,157.25 66.65,156.57 66.65,156.17 66.55,156.08 66.55,155.85 CPU1.B37
  TOP w0.165: v1(96.39,169.85) 96.39,169.8 96.24,169.65 DIMM1.21 ; 68.05,157.25 73.74,157.25 74.27,157.79 76.31,157.79 v2(80.99,162.47) 90.29,171.78 91.31,171.78 91.31,171.78 91.95,171.78 92.1,171.63 92.1,170.66 92.25,170.51 93.5,170.51 93.65,170.66 93.65,171.04 93.5,171.2 92.94,171.2 92.79,171.35 92.79,171.75 92.94,171.91 93.55,171.91 93.7,172.06 93.7,173.91 93.55,174.07 93.27,174.07 93.12,173.91 v3(93.12,172.82)
  L3 w0.152: v1(96.39,169.85) 96.33,169.85 93.36,172.82 v3(93.12,172.82)
MEM_MA_DATA9: length 46.2
  TOP w0.102: 68.05,156.97 67.34,156.97 66.85,156.49 CPU1.A38
  TOP w0.165: DIMM1.23 97.84,169.05 97.99,169.2 v1(97.99,169.88) ; 68.05,156.97 74.17,156.97 74.32,157.13 76.65,157.13 v2(77.25,157.73) v3(87.75,168.22)
  L3 w0.152: v1(97.99,169.88) 97.49,169.37 96.19,169.37 93.2,172.36 90.53,172.36 89.13,170.97 87.93,170.97 87.77,170.81 87.77,170.46 87.93,170.31 88.39,170.31 88.54,170.15 88.54,169.77 88.39,169.62 87.9,169.62 87.75,169.47 v3(87.75,168.22)
MEM_MA_DATA10: length 47.6
  TOP w0.102: 70.94,155 70.31,155 69.85,154.54 68.69,154.54 68.58,154.65 68.32,154.65 68.02,154.35 CPU1.D40
  TOP w0.165: v3(92.04,168.32) 92.04,167.76 92.2,167.6 92.95,167.6 93.12,167.43 93.12,167.1 92.95,166.93 91.87,166.93 91.72,166.78 91.72,166.42 91.87,166.27 92.95,166.27 93.12,166.11 93.12,165.77 92.95,165.61 91.87,165.61 91.72,165.46 91.72,165.26 91.72,165.25 91.72,165.1 91.87,164.94 92.95,164.94 93.12,164.78 93.12,164.45 92.95,164.28 90.75,164.28 89.1,162.64 87.5,162.64 78.46,153.6 v2(75.77,153.6) 74.9,153.6 73.49,155 70.94,155 ; DIMM1.33 96.38,166.05 v1(96.39,166.04)
  L3 w0.152: v1(96.39,166.04) 96.21,166.22 96.16,166.22 93.6,168.78 92.5,168.78 v3(92.04,168.32)
MEM_MA_DATA11: length 47.9
  TOP w0.102: CPU1.D41 68.46,154.34 70.05,154.34 70.39,154.68 70.92,154.68
  TOP w0.165: DIMM1.35 97.48,165.45 97.99,165.96 v1(97.99,166.04) ; v3(93.51,168.15) 93.51,162.59 93.36,162.43 93.07,162.43 92.91,162.59 92.91,163.45 92.76,163.6 92.46,163.6 92.3,163.45 92.3,162.59 92.15,162.43 91.77,162.43 91.62,162.59 91.62,163.32 91.47,163.47 90.88,163.47 89.38,161.97 87.78,161.97 v2(79.95,154.15) 78.74,152.93 75.05,152.93 73.3,154.68 70.92,154.68
  L3 w0.152: v3(93.51,168.15) 96.1,165.55 97.51,165.55 v1(97.99,166.04)
MEM_MA_DATA12: length 47.7
  TOP w0.102: 67.97,157.86 67.36,157.86 66.24,156.74 66.24,156.69 66.21,156.64 66,156.43 66,156.17 66.04,156.13 66.05,156.12 66.05,155.82 65.97,155.74 65.97,155.47 CPU1.B36
  TOP w0.165: 67.97,157.86 73.1,157.86 74.36,159.12 75.76,159.12 v2(83.82,167.18) v3(89.56,172.92) ; DIMM1.22 v1(101.6,169.35)
  L3 w0.152: v1(101.6,169.35) 101.13,169.82 100.2,169.82 99.21,170.81 96.37,170.81 93.11,174.08 91.2,174.08 90.57,173.46 90.1,173.46 v3(89.56,172.92)
MEM_MA_DATA13: length 46.3
  TOP w0.102: CPU1.A37 66.44,156.44 66.44,156.65 67.35,157.56 68.02,157.56
  TOP w0.165: v3(91.28,172.94) 91.28,172.69 91.04,172.44 90.02,172.44 v2(82.57,164.99) 76.03,158.45 74.28,158.45 73.38,157.56 68.02,157.56 ; DIMM1.24 100.59,168.75 v1(100.03,169.32)
  L3 w0.152: v1(100.03,169.32) 98.88,170.46 96.23,170.46 93.26,173.43 91.47,173.43 91.28,173.25 v3(91.28,172.94)
MEM_MA_DATA14: length 46.7
  TOP w0.165: DIMM1.34 v1(101.61,165.75) ; v3(93.1,169.98) 93.1,168.94 92.94,168.78 92.46,168.78 92.3,168.94 92.3,169.32 92.15,169.47 91.74,169.47 91.59,169.32 91.59,168.96 91.41,168.78 90.83,168.78 90.37,168.33 90.37,167.39 89.81,166.83 89.81,166.59 90.39,166.01 90.39,165.8 90.13,165.55 89.92,165.55 89.34,166.12 89.11,166.12 v2(83.08,160.09) 77.91,154.92 74.66,154.92 73.88,155.7 CPU1.B41
  L3 w0.152: v3(93.1,169.98) 93.1,169.97 93.46,169.97 96.51,166.93 99.8,166.93 100.36,166.37 100.99,166.37 v1(101.61,165.75)
MEM_MA_DATA15: length 47.4
  TOP w0.102: 69.47,155.4 69.42,155.35 68.55,155.35 CPU1.C40
  TOP w0.165: v3(91.06,168.28) 91.06,165.53 90.01,164.49 89.78,164.49 89.33,164.94 89.12,164.94 88.86,164.68 88.86,164.47 89.31,164.02 89.31,163.79 88.83,163.3 87.23,163.3 v2(80.68,156.75) 78.19,154.26 74.78,154.26 73.64,155.4 69.47,155.4 ; v1(99.82,165.76) 100.43,165.15 DIMM1.36
  L3 w0.152: v3(91.06,168.28) 91.06,169.19 91.3,169.43 93.46,169.43 96.32,166.57 99.01,166.57 v1(99.82,165.76)
MEM_MA_DATA16: length 42.9
  TOP w0.102: CPU1.F40 67.98,153.25 68.28,153.55 68.6,153.55 68.66,153.5 71.67,153.5 v3(72.19,154.02)
  TOP w0.165: v1(96.49,164.14) 96.38,164.25 DIMM1.39
  L3 w0.152: v3(72.19,154.02) 74.96,156.79 75.13,156.79 80.88,162.54 81.09,162.54 81.43,162.2 81.65,162.2 81.89,162.44 81.89,162.66 81.55,163 81.55,163.21 81.8,163.46 82.01,163.46 82.35,163.12 82.57,163.12 82.81,163.36 82.81,163.58 82.47,163.92 82.47,164.13 82.72,164.38 82.93,164.38 83.27,164.04 83.49,164.04 83.73,164.28 83.73,164.5 83.39,164.84 83.39,165.05 83.64,165.3 83.85,165.3 84.19,164.96 84.41,164.96 84.65,165.2 84.65,165.42 84.31,165.76 84.31,165.97 84.77,166.43 93.43,166.43 95.73,164.14 v1(96.49,164.14)
  BOTTOM w0.165: v3(72.19,154.02) 71.48,153.31 v6(71.27,153.31)
MEM_MA_DATA17: length 42.5
  TOP w0.102: v3(72.82,154.01) 72.07,153.25 CPU1.F41
  TOP w0.165: v1(98.17,164.16) 97.66,163.65 DIMM1.41
  L3 w0.152: v1(98.17,164.16) 97.67,163.66 95.7,163.66 93.57,165.78 86.16,165.78 81.91,161.54 80.87,161.54 80.41,161.08 80.41,160.87 80.72,160.56 80.72,160.35 80.47,160.1 80.26,160.1 79.95,160.41 79.74,160.41 79.49,160.16 79.49,159.95 79.8,159.64 79.8,159.43 79.55,159.18 79.34,159.18 79.03,159.49 78.82,159.49 75.41,156.08 74.9,156.08 v3(72.82,154.01)
  BOTTOM w0.165: v6(98.83,163.73) v1(98.17,164.16)
MEM_MA_DATA18: length 41.2
  TOP w0.102: CPU1.K40 67.98,151.28 68.23,151.28 68.3,151.35 68.59,151.35 68.73,151.22 69.97,151.22 70.33,150.86 v3(70.82,150.86)
  TOP w0.165: v1(96.39,160.49) 96.38,160.5 96.29,160.5 96.14,160.65 DIMM1.51
  L3 w0.152: v1(96.39,160.49) 95.44,160.49 93.72,162.21 88.75,162.21 87.25,160.7 86.01,160.7 85.55,160.24 85.55,160.03 86,159.58 86,159.36 85.76,159.12 85.54,159.12 85.09,159.57 84.88,159.57 84.63,159.32 84.63,159.11 85.08,158.66 85.08,158.44 84.84,158.2 84.62,158.2 84.17,158.65 83.96,158.65 83.71,158.4 83.71,158.19 84.16,157.74 84.16,157.52 83.92,157.28 83.7,157.28 83.25,157.73 83.04,157.73 77.73,152.43 75.11,152.43 74.43,151.75 71.71,151.75 v3(70.82,150.86)
  BOTTOM w0.165: v3(70.82,150.86) 70.82,150.93 v6(70.36,151.38)
MEM_MA_DATA19: length 42.1
  TOP w0.102: v3(71.46,150.82) 71.08,150.45 70.44,150.45 69.87,151.01 68.49,151.01 CPU1.K41
  TOP w0.165: DIMM1.53 96.05,160.05 96.21,159.89 96.79,159.89 96.79,159.89 97.76,159.89 98.2,160.32 v1(98.2,160.45)
  L3 w0.152: v1(98.2,160.45) 97.74,159.99 95.3,159.99 93.74,161.56 89.12,161.56 84.02,156.46 82.69,156.46 82.44,156.22 82.44,156 82.77,155.68 82.77,155.46 82.52,155.22 82.31,155.22 81.98,155.54 81.77,155.54 81.52,155.3 81.52,155.08 81.85,154.76 81.85,154.54 81.6,154.3 81.39,154.3 81.06,154.62 80.85,154.62 78,151.78 75.42,151.78 75.01,151.36 71.99,151.36 v3(71.46,150.82)
  BOTTOM w0.165: v6(98.91,160.45) v1(98.2,160.45)
MEM_MA_DATA20: length 43.3
  TOP w0.102: CPU1.E40 68.35,153.8 68.65,154.1 70.56,154.1 v3(70.7,154.24)
  TOP w0.165: DIMM1.40 v1(101.6,163.95)
  L3 w0.152: v1(101.6,163.95) 100.55,165 95.97,165 93.2,167.77 84.23,167.77 v3(70.7,154.24)
  BOTTOM w0.165: v6(102.57,164.01) v1(101.6,163.95)
MEM_MA_DATA21: length 42.3
  TOP w0.165: v1(99.77,163.96) 100.38,163.35 DIMM1.42 ; CPU1.E41 71.21,153.8 v3(71.46,154.05)
  L3 w0.152: v3(71.46,154.05) 84.49,167.09 93.31,167.09 95.75,164.64 99.09,164.64 v1(99.77,163.96)
  BOTTOM w0.165: v6(100.38,163.27) v1(99.77,163.96)
MEM_MA_DATA22: length 42.4
  TOP w0.102: v3(72.66,152.31) 72.66,152.24 71.89,151.47 70.3,151.47 69.86,151.9 68.67,151.9 68.37,151.6 CPU1.J40
  TOP w0.165: DIMM1.50 v1(101.6,160.95)
  L3 w0.152: v3(72.66,152.31) 72.66,152.33 73.16,152.83 74.12,152.83 75.04,153.75 77.22,153.75 87.02,163.55 93.59,163.55 95.7,161.44 101.11,161.44 v1(101.6,160.95)
  BOTTOM w0.165: v6(102.26,160.27) 102.26,160.29 v1(101.6,160.95)
MEM_MA_DATA23: length 42.7
  TOP w0.102: v3(73.27,152.33) 73.26,152.33 72.2,151.27 70.21,151.27 69.88,151.6 CPU1.J41
  TOP w0.165: DIMM1.52 100.53,160.35 v1(99.92,160.96)
  L3 w0.152: v1(99.92,160.96) 99.8,161.09 95.48,161.09 93.68,162.89 87.28,162.89 86.82,162.43 86.82,162.21 87.22,161.81 87.22,161.6 86.98,161.35 86.76,161.35 86.36,161.75 86.14,161.75 77.49,153.1 75.07,153.1 74.3,152.33 v3(73.27,152.33)
  BOTTOM w0.165: v6(100.25,160.12) 99.92,160.45 v1(99.92,160.96)
MEM_MA_DATA24: length 39.4
  TOP w0.102: 70.86,149.53 70.34,149.53 70.14,149.73 69.19,149.73 68.97,149.95 CPU1.M41
  TOP w0.165: v1(96.42,158.78) 96.18,158.78 96.11,158.85 DIMM1.57 ; v3(90.04,159.21) 87.82,159.21 v2(80.38,151.76) 79.54,150.92 74.9,150.92 73.51,149.53 70.86,149.53
  L3 w0.152: v3(90.04,159.21) 89.4,159.21 89.25,159.36 89.25,160.71 89.4,160.86 89.75,160.86 89.9,160.71 89.9,160.06 90.05,159.91 90.4,159.91 90.55,160.06 90.55,160.63 90.7,160.78 91.06,160.78 91.21,160.63 91.21,160.06 91.36,159.91 93.88,159.91 95,158.78 v1(96.42,158.78)
MEM_MA_DATA25: length 40.4
  TOP w0.102: 70.86,149.24 70.34,149.24 70.06,149.53 69.1,149.53 68.93,149.7 68.63,149.7 68.58,149.65 68.35,149.65 CPU1.N40
  TOP w0.165: v1(97.94,158.68) 97.5,158.25 DIMM1.59 ; v3(91.72,159.13) 91.72,158.6 91.47,158.34 87.9,158.34 79.81,150.26 v2(78.46,150.26) 74.95,150.26 73.93,149.24 70.86,149.24
  L3 w0.152: v3(91.72,159.13) 91.85,159.26 94.01,159.26 95.54,157.73 98.35,157.73 98.5,157.89 98.5,158.53 98.35,158.68 v1(97.94,158.68)
MEM_MA_DATA26: length 40.3
  TOP w0.102: CPU1.T41 69.04,147.75 69.27,147.52 69.67,147.52
  TOP w0.165: DIMM1.67 97.18,155.85 v1(98.04,154.99) ; v3(90.17,155.57) 90.17,154.33 89.67,153.83 89.44,153.83 89.08,154.18 88.85,154.18 88.61,153.95 88.61,153.71 88.97,153.36 88.97,153.12 88.73,152.89 88.5,152.89 88.15,153.24 87.91,153.24 81.92,147.25 v2(81.23,147.25) 70.63,147.25 70.36,147.52 69.67,147.52
  L3 w0.152: v3(90.17,155.57) 90.71,156.11 91.21,156.11 91.85,156.75 94.15,156.75 95.33,155.57 97.46,155.57 v1(98.04,154.99)
MEM_MA_DATA27: length 40.4
  TOP w0.102: 69.6,147.05 69.38,147.05 68.93,147.5 68.67,147.5 68.37,147.2 CPU1.U40
  TOP w0.165: v3(91.64,155.62) 91.64,154.86 89.01,152.23 87.83,152.23 87.36,151.76 87.36,151.52 87.72,151.17 87.72,150.94 87.48,150.7 87.25,150.7 86.9,151.05 86.66,151.05 86.43,150.82 86.43,150.59 86.78,150.23 86.78,150 86.54,149.76 86.31,149.76 85.96,150.12 85.72,150.12 85.49,149.88 85.49,149.65 85.84,149.29 85.84,149.06 85.61,148.83 85.37,148.83 85.02,149.18 84.79,149.18 84.55,148.94 84.55,148.71 84.9,148.36 84.9,148.12 84.67,147.89 84.44,147.89 84.08,148.24 83.85,148.24 82.19,146.59 v2(76.43,146.59) 75.21,146.59 75.01,146.79 70.38,146.79 70.12,147.05 69.6,147.05 ; v1(96.47,155.09) 96.47,155.09 96.31,155.25 DIMM1.69
  L3 w0.152: v3(91.64,155.62) 92.12,156.1 94.3,156.1 95.31,155.09 v1(96.47,155.09)
MEM_MA_DATA28: length 40.5
  TOP w0.102: CPU1.L40 68.35,150.75 68.58,150.75 68.63,150.8 69.72,150.8 70.32,150.2 70.79,150.2
  TOP w0.165: DIMM1.56 v1(101.58,159.15) ; v3(91.67,160.91) 87.65,160.91 78.99,152.25 v2(78.13,152.25) 74.32,152.25 72.28,150.2 70.79,150.2
  L3 w0.152: v3(91.67,160.91) 93.88,160.91 95.15,159.64 101.09,159.64 v1(101.58,159.15)
MEM_MA_DATA29: length 40.9
  TOP w0.102: 70.86,149.8 70.73,149.93 69.28,149.93 69.02,150.2 68.66,150.2 68.66,150.2 68.6,150.25 68.28,150.25 68.23,150.2 68,150.2 CPU1.M40
  TOP w0.165: v3(93.17,160.45) 92.63,159.92 87.6,159.92 79.26,151.58 v2(75.84,151.58) 74.72,151.58 72.94,149.8 70.86,149.8 ; v1(99.75,159.13) 100.33,158.55 DIMM1.58
  L3 w0.152: v3(93.17,160.45) 93.84,160.45 94.92,159.37 94.92,159.37 95.01,159.28 95.3,159.28 99.59,159.28 v1(99.75,159.13)
MEM_MA_DATA30: length 40.6
  TOP w0.102: 70.38,147.91 70.07,147.91 69.38,148.6 68.64,148.6 68.34,148.3 CPU1.R40
  TOP w0.165: DIMM1.68 100.61,155.55 v1(99.97,154.91) ; v3(91.08,156.96) 90.33,156.22 89.95,156.22 81.64,147.91 v2(78.49,147.91) 70.38,147.91
  L3 w0.152: v1(99.97,154.91) 98.88,154.91 97.87,155.93 95.49,155.93 94.02,157.4 91.52,157.4 v3(91.08,156.96)
MEM_MA_DATA31: length 41.4
  TOP w0.102: 69.47,146.61 68.94,146.61 68.59,146.95 68.31,146.95 68.26,146.9 67.97,146.9 67.75,147.12 CPU1.T40
  TOP w0.165: 69.47,146.61 69.94,146.61 70.14,146.41 74.75,146.41 75.23,145.92 v2(79.04,145.92) 83.64,145.92 93.11,155.39 v3(93.11,155.64) ; DIMM1.70 v1(101.57,154.95)
  L3 w0.152: v3(93.11,155.64) 94.22,155.64 95.42,154.43 101.06,154.43 v1(101.57,154.95)
MEM_MA_DATA32: length 41
  TOP w0.102: CPU1.AF40 68.02,142.25 68.32,142.55 68.58,142.55 68.63,142.5 68.93,142.5 69,142.57 69.9,142.57 70.11,142.36 70.57,142.36
  TOP w0.165: v1(90.03,131.97) 84.68,137.32 84.68,137.9 84.25,138.33 84.01,138.33 83.74,138.06 83.5,138.06 83.27,138.29 83.27,138.53 83.54,138.8 83.54,139.04 v2(82.09,140.49) 80.22,142.36 75.44,142.36 75.44,142.36 70.57,142.36 ; v1(97.61,134.57) 97.33,134.85 DIMM1.129
  L3 w0.152: v1(97.61,134.57) 96.94,134.57 93.2,130.82 91.88,130.82 91.44,131.27 90.25,131.27 90.03,131.48 v1(90.03,131.97)
MEM_MA_DATA33: length 41.8
  TOP w0.102: CPU1.AF41 68.97,142.25 69.08,142.37 69.73,142.37 70,142.1 70.61,142.1
  TOP w0.165: DIMM1.131 96.99,134.25 v1(97.53,133.71) ; 70.61,142.1 75.04,142.1 75.44,141.7 78.92,141.7 79.43,141.19 79.67,141.19 79.94,141.46 80.18,141.46 80.41,141.23 80.41,141 80.14,140.72 80.14,140.49 80.37,140.25 80.6,140.25 80.88,140.53 81.11,140.53 81.35,140.29 81.35,140.06 81.07,139.78 81.07,139.55 81.31,139.31 81.54,139.31 81.82,139.59 82.05,139.59 82.29,139.35 82.29,139.12 82.01,138.84 82.01,138.61 v2(83.53,137.09) 86.98,133.64 86.98,133.34 89,131.32 91.26,131.32 91.59,130.99 92.33,130.99 v1(93.13,130.19)
  L3 w0.152: v1(93.13,130.19) 93.23,130.19 96.19,133.15 96.97,133.15 v1(97.53,133.71)
MEM_MA_DATA34: length 42.4
  TOP w0.102: CPU1.AK40 67.99,140.05 68.29,140.35 68.6,140.35 68.66,140.3 68.93,140.3 69.01,140.39 70.01,140.39 70.07,140.33 70.68,140.33
  TOP w0.165: v1(98.63,129.9) 97.27,131.25 DIMM1.141 ; 70.68,140.33 73.12,140.33 75.63,137.82 77.22,137.82 v2(83.25,131.79) 87.45,127.59 88,127.59 90.43,127.59 90.77,127.59 91.03,127.59 v1(91.44,127.17)
  L3 w0.152: v1(98.63,129.9) 98.12,130.4 96.55,130.4 93.32,127.17 v1(91.44,127.17)
MEM_MA_DATA35: length 40.4
  TOP w0.102: CPU1.AK41 69.09,140.05 69.22,140.18 69.9,140.18 70.12,139.96 70.62,139.96
  TOP w0.165: v1(96.95,129.9) 96.95,130.03 96.33,130.65 DIMM1.143 ; 70.62,139.96 72.89,139.96 75.77,137.08 77.02,137.08 v2(78.2,135.9) 87.26,126.85 v1(89.64,126.85)
  L3 w0.152: v1(96.95,129.9) 96.57,129.9 93.18,126.52 91.03,126.52 90.7,126.19 88.85,126.19 88.7,126.34 88.7,126.69 88.85,126.85 v1(89.64,126.85)
MEM_MA_DATA36: length 42
  TOP w0.102: CPU1.AE40 68.37,142.8 68.68,143.11 68.96,143.11 68.97,143.11 70.52,143.11
  TOP w0.165: v1(93.22,132.03) v2(82.34,142.9) 81.53,143.71 74.75,143.71 74.15,143.11 70.52,143.11 ; v1(100.76,135.13) 101.34,134.55 DIMM1.130
  L3 w0.152: v1(100.76,135.13) 100.48,135.41 96.59,135.41 v1(93.22,132.03)
MEM_MA_DATA37: length 41.2
  TOP w0.165: DIMM1.132 v1(101.61,133.95) ; v1(91.59,131.93) v2(85.56,137.96) 80.49,143.03 74.85,143.03 74.56,142.74 70.53,142.74 70.45,142.81 68.9,142.81 68.89,142.8 CPU1.AE41
  L3 w0.152: v1(91.59,131.93) 91.7,131.93 92.15,131.47 93.34,131.47 96.92,135.05 100,135.05 100.61,134.44 101.11,134.44 v1(101.61,133.95)
MEM_MA_DATA38: length 42
  TOP w0.102: 69.53,140.88 68.95,140.88 68.93,140.9 68.67,140.9 68.37,140.6 CPU1.AJ40
  TOP w0.165: v1(87.81,129.03) 87.81,129.17 v2(79.83,137.15) 77.79,139.19 75.64,139.19 73.96,140.88 69.53,140.88 ; DIMM1.140 100.38,131.55 v1(99.85,131.02)
  L3 w0.152: v1(99.85,131.02) 99.76,131.11 96.12,131.11 93.38,128.37 93.09,128.37 92.87,128.15 88.69,128.15 v1(87.81,129.03)
MEM_MA_DATA39: length 41.2
  TOP w0.102: CPU1.AJ41 70.71,140.6
  TOP w0.165: v1(93.19,127.74) 93.16,127.74 92.65,128.25 87.73,128.25 v2(81.23,134.75) 77.47,138.51 75.53,138.51 73.43,140.6 70.71,140.6 ; DIMM1.142 v1(101.61,130.95)
  L3 w0.152: v1(93.19,127.74) 93.25,127.74 96.27,130.76 99.14,130.76 99.4,130.49 100.98,130.49 101.43,130.95 v1(101.61,130.95)
MEM_MA_DATA40: length 46.7
  TOP w0.102: 70.57,139.05 70.19,139.05 70.1,138.96 68.46,138.96 CPU1.AM41
  TOP w0.165: v1(98.42,128.57) 98.09,128.91 96.54,128.91 95.99,129.45 DIMM1.147 ; v1(91.11,123.57) 92.86,123.57 93.01,123.73 93.01,124.13 92.86,124.28 89.81,124.28 89.7,124.39 86.9,124.39 v2(77.15,134.14) 76.24,135.05 75.67,135.05 71.67,139.05 70.57,139.05
  L3 w0.152: v1(98.42,128.57) 98.3,128.7 96.88,128.7 95.83,127.66 95.83,127.34 93.02,124.52 92.06,124.52 v1(91.11,123.57)
MEM_MA_DATA41: length 46.4
  TOP w0.102: CPU1.AN40 68.35,138.4 68.65,138.7 69.19,138.7
  TOP w0.165: v1(97.08,128.22) 96.7,128.22 96.07,128.85 DIMM1.149 ; 69.19,138.7 71.18,138.7 75.5,134.38 75.9,134.38 v2(78.78,131.5) 86.56,123.72 89.43,123.72 v1(89.59,123.57)
  L3 w0.152: v1(97.08,128.22) 96.98,128.12 96.98,127.93 92.92,123.87 92.33,123.87 91.38,122.92 91.34,122.89 89.26,122.89 89.11,122.73 89.11,122.12 88.95,121.97 88.61,121.97 88.46,122.12 88.46,122.73 88.3,122.89 87.58,122.89 87.43,123.04 87.43,123.41 87.58,123.57 v1(89.59,123.57)
MEM_MA_DATA42: length 47
  TOP w0.102: CPU1.AT41 69.1,136.75 69.33,136.52 69.83,136.52
  TOP w0.165: 69.83,136.52 70.25,136.52 72.39,134.38 72.39,132.19 v2(84.53,120.05) 85.68,118.91 88.61,118.91 88.78,119.07 88.78,119.32 88.94,119.49 89.28,119.49 89.44,119.32 89.44,119.07 89.61,118.91 89.94,118.91 90.1,119.07 90.1,119.32 90.27,119.49 90.6,119.49 90.77,119.32 90.77,119.07 90.93,118.91 91.6,118.91 v1(91.68,118.99) ; v1(98.07,125.55) 97.17,126.45 DIMM1.157
  L3 w0.152: v1(91.68,118.99) 91.68,119.35 91.83,119.5 92.99,119.5 93.32,119.84 93.32,120.12 94.4,121.2 94.4,121.65 96.44,123.69 96.44,124.01 97.98,125.55 v1(98.07,125.55)
MEM_MA_DATA43: length 47.1
  TOP w0.102: 70.17,136.08 69.99,136.25 69.3,136.25 69.13,136.42 69.05,136.5 68.63,136.5 68.33,136.2 CPU1.AU40
  TOP w0.165: v1(98.48,124.71) 98.13,124.71 97,125.85 DIMM1.159 ; 70.17,136.08 72.01,134.23 72.01,131.63 v2(81.62,122.02) 85.4,118.24 92.54,118.24 93.32,119.02 v1(93.32,119.07)
  L3 w0.152: v1(98.48,124.71) 97.65,124.71 96.8,123.87 96.8,123.55 94.76,121.5 94.76,121.05 93.68,119.97 93.68,119.43 v1(93.32,119.07)
MEM_MA_DATA44: length 45.9
  TOP w0.102: 70.64,139.67 70.08,139.67 69.77,139.98 69.31,139.98 69.17,139.84 68.7,139.84 68.58,139.71 68.31,139.71 CPU1.AL40
  TOP w0.165: DIMM1.146 102.92,129.75 102.92,129.75 100.79,129.75 v1(99.95,128.91) ; v3(92.74,125.86) 92.25,126.34 90.91,126.34 90.41,125.84 87.33,125.84 v2(80.26,132.91) 76.79,136.37 75.76,136.37 72.46,139.67 70.64,139.67
  L3 w0.152: v1(99.95,128.91) 99.95,129.29 100.1,129.44 100.41,129.44 100.56,129.59 100.56,129.98 100.41,130.14 99.81,130.14 99.09,129.41 96.58,129.41 93.7,126.53 93.7,126.24 93.32,125.86 v3(92.74,125.86)
MEM_MA_DATA45: length 45.1
  TOP w0.102: CPU1.AM40 67.88,139.08 68.14,139.08 68.32,139.25 68.62,139.25 68.71,139.17 69.87,139.17 70.06,139.36 70.5,139.36
  TOP w0.165: v1(90.96,125.45) 90.56,125.05 87.18,125.05 v2(81.93,130.3) 76.52,135.71 75.71,135.71 72.05,139.36 70.5,139.36 ; DIMM1.148 v1(101.61,129.15)
  L3 w0.152: v1(90.96,125.45) 91.21,125.2 93.19,125.2 95.48,127.49 95.48,127.81 96.73,129.06 99.06,129.06 99.21,128.91 99.21,128.35 99.36,128.19 101.45,128.19 101.61,128.35 v1(101.61,129.15)
MEM_MA_DATA46: length 47.1
  TOP w0.102: CPU1.AR40 68.37,137.3 68.73,137.66 69.05,137.66
  TOP w0.165: 69.05,137.66 70.09,137.66 73.26,134.48 73.26,133.19 v2(82.68,123.78) 86.21,120.24 87.82,120.24 88.39,120.82 91.06,120.82 91.22,120.97 91.22,121.36 91.37,121.51 92.73,121.51 92.88,121.36 v1(92.88,121.04) ; DIMM1.158 v1(101.61,126.15)
  L3 w0.152: v1(92.88,121.04) 92.88,121.55 97.72,126.39 100.01,126.39 100.24,126.62 101.14,126.62 v1(101.61,126.15)
MEM_MA_DATA47: length 47.1
  TOP w0.102: 69.88,136.79 69.36,136.79 69.19,136.95 68.71,136.95 68.61,137.05 68.29,137.05 67.99,136.75 CPU1.AT40
  TOP w0.165: DIMM1.160 100.43,125.55 v1(100.13,125.86) ; v1(91.41,120.15) 88.67,120.15 88.08,119.57 85.95,119.57 v2(79.94,125.58) 72.87,132.65 72.87,134.5 70.58,136.79 69.88,136.79
  L3 w0.152: v1(100.13,125.86) 99.95,126.03 97.87,126.03 96.09,124.25 96.09,123.84 94.05,121.8 94.05,121.42 92.78,120.15 v1(91.41,120.15)
MEM_MA_DATA48: length 47.9
  TOP w0.102: CPU1.AV41 69.02,135.65 69.26,135.41 69.26,135.41 69.53,135.14 69.78,135.14 70.84,134.08 70.84,133.38 v3(70.79,133.32)
  TOP w0.165: v1(99.44,123.7) 98.98,124.16 98.16,124.16 97.68,124.65 DIMM1.163
  L3 w0.152: v1(99.44,123.7) 98.83,123.09 97.85,123.09 95.82,121.06 95.82,120.49 94.74,119.41 94.74,118.8 93.65,117.71 93.65,117.71 93.45,117.5 93.15,117.21 90.45,117.21 89.27,118.4 85.47,122.2 85.47,123.02 84.87,123.61 84.59,123.61 84.05,123.61 84.05,123.61 75.53,132.13 72.66,132.13 71.47,133.32 v3(70.79,133.32)
MEM_MA_DATA49: length 48.9
  TOP w0.102: v3(70.43,133.83) 70.29,133.98 70.29,134.35 69.7,134.93 69.45,134.93 69.18,135.21 69.17,135.21 68.98,135.4 68.65,135.4 68.35,135.1 CPU1.AW40
  TOP w0.165: v1(97.87,123.75) 97.87,123.77 97.58,124.05 DIMM1.165
  L3 w0.152: v1(97.87,123.75) 97.87,123.61 95.47,121.21 95.47,120.76 94.39,119.68 94.39,118.95 93.3,117.86 90.72,117.86 89.92,118.67 89.92,118.67 86.12,122.47 86.12,123.29 85.14,124.26 84.32,124.26 83.86,124.72 83.86,124.94 84.06,125.13 84.06,125.35 83.81,125.59 83.6,125.59 83.4,125.4 83.19,125.4 82.94,125.64 82.94,125.86 83.14,126.05 83.14,126.27 82.89,126.51 82.68,126.51 82.48,126.32 82.27,126.32 82.02,126.56 82.02,126.78 82.22,126.97 82.22,127.19 81.97,127.43 81.76,127.43 81.56,127.24 81.35,127.24 81.1,127.48 81.1,127.7 81.3,127.89 81.3,128.11 81.05,128.35 80.84,128.35 80.64,128.16 80.43,128.16 80.18,128.4 80.18,128.62 80.38,128.81 80.38,129.03 80.13,129.27 79.92,129.27 79.72,129.08 79.51,129.08 75.79,132.8 72.49,132.8 71.45,133.83 v3(70.43,133.83)
  BOTTOM w0.165: v6(70.51,134.52) v3(70.43,133.83)
MEM_MA_DATA50: length 49.3
  TOP w0.102: v3(68.71,131.48) 68.43,131.48 66.85,133.06 CPU1.BA38
  TOP w0.165: DIMM1.175 96.98,121.05 98.58,119.46 v1(98.6,119.46)
  L3 w0.152: v1(98.6,119.46) 98.46,119.46 97.23,118.23 97.23,117.57 92.7,113.04 88.66,113.04 73.71,127.99 72.58,127.99 69.09,131.48 v3(68.71,131.48)
  BOTTOM w0.165: v2(99.49,119.47) 99.48,119.46 v1(98.6,119.46)
MEM_MA_DATA51: length 50
  TOP w0.102: v3(69.1,130.85) 68.77,130.85 66.63,132.99 66.63,133.85 66.3,134.17 CPU1.AY37
  TOP w0.165: DIMM1.177 96.72,120.45 98.31,118.85 v1(98.31,118.63) ; v3(69.1,130.85) 69.24,130.99 v2(69.93,130.99)
  L3 w0.152: v1(98.31,118.63) 98.13,118.63 97.59,118.08 97.59,117.42 94.67,114.5 94.67,114.29 92.76,112.38 88.39,112.38 73.51,127.27 72.68,127.27 v3(69.1,130.85)
MEM_MA_DATA52: length 48
  TOP w0.102: CPU1.AU41 69.04,136.2 69.4,135.85 v3(69.72,135.85)
  TOP w0.165: DIMM1.164 100.27,124.35 v1(100.15,124.23)
  L3 w0.152: v1(100.15,124.23) 97.67,124.23 97.31,123.87 97.31,123.55 95.11,121.36 95.11,120.9 94.03,119.82 94.03,119.1 93.45,118.51 90.99,118.51 90.57,118.94 86.77,122.74 86.77,123.56 80.43,129.9 80.43,129.9 80.4,129.92 79.58,129.92 79.12,130.38 79.12,130.6 79.59,131.07 79.59,131.28 79.35,131.53 79.13,131.53 78.66,131.06 78.45,131.06 76.06,133.45 72.4,133.45 70,135.85 v3(69.72,135.85)
  BOTTOM w0.165: v6(101.04,124.69) v1(100.15,124.23)
MEM_MA_DATA53: length 48.8
  TOP w0.102: CPU1.AV40 68,135.65 68.3,135.95 68.6,135.95 68.69,135.87 68.79,135.87 69.09,135.87 69.34,135.61 69.35,135.61 69.62,135.34 69.87,135.34 71.37,133.83 v3(71.37,132.77)
  TOP w0.165: DIMM1.166 v1(101.61,123.75)
  L3 w0.152: v3(71.37,132.77) 72.67,131.47 75.27,131.47 90.19,116.56 93.04,116.56 95.1,118.62 95.1,119.26 96.18,120.34 96.18,120.91 97.95,122.68 99.19,122.68 99.72,123.22 101.08,123.22 v1(101.61,123.75)
  BOTTOM w0.165: v6(102.51,124.1) v1(101.61,123.75)
MEM_MA_DATA54: length 48.2
  TOP w0.102: CPU1.AY39 67.8,134 67.8,133.6 68.26,133.14 v3(68.26,133.14)
  TOP w0.165: DIMM1.174 100.73,121.35 v1(100.08,120.7)
  L3 w0.152: v1(100.08,120.7) 99.75,120.37 98.33,120.37 96.49,118.53 96.49,117.91 92.91,114.34 89.22,114.34 74.25,129.31 72.23,129.31 68.39,133.14 v3(68.26,133.14)
  BOTTOM w0.165: v6(68.26,133.83) v3(68.26,133.14)
MEM_MA_DATA55: length 49.9
  TOP w0.102: v3(68.45,132.13) 68.06,132.13 67.1,133.1 67.1,133.87 67.15,133.92 67.15,134.22 66.85,134.52 CPU1.AY38
  TOP w0.165: DIMM1.176 v1(101.61,120.75)
  L3 w0.152: v1(101.61,120.75) 101.61,120.69 100.94,120.02 98.48,120.02 96.88,118.41 96.88,117.72 92.85,113.69 88.93,113.69 73.96,128.65 72.37,128.65 68.89,132.13 v3(68.45,132.13)
  BOTTOM w0.165: v1(101.61,120.75) v6(102.34,120.75)
MEM_MA_DATA56: length 59.8
  TOP w0.102: CPU1.BA36 65.75,133.51 65.88,133.38 65.88,132.57 66.09,132.36
  TOP w0.165: v1(98.44,117.6) 98.44,117.75 96.95,119.25 DIMM1.181 ; 66.09,132.36 69.07,129.39 71.44,129.39 v2(80.52,120.31) 83.79,117.04 83.79,116.37 83.96,116.21 84.14,116.21 84.31,116.04 84.31,115.71 84.14,115.54 83.96,115.54 83.79,115.38 83.79,113.6 83.95,113.45 v3(85.49,113.45)
  L3 w0.152: v3(85.49,113.45) 84.33,113.45 84.18,113.6 84.18,114.66 84.02,114.81 83.64,114.81 83.49,114.66 83.49,113.06 83.89,112.66 86.27,112.66 87.85,111.08 92.76,111.08 95.4,113.73 95.4,114.14 98.44,117.18 v1(98.44,117.6)
MEM_MA_DATA57: length 61.2
  TOP w0.102: CPU1.AY35 65.41,134.19 65.41,133.92 65.5,133.83 65.5,133.44 65.66,133.28 65.66,132.37 65.85,132.18
  TOP w0.165: DIMM1.183 96.69,118.65 98.65,116.69 v1(98.65,116.66) ; v3(85.37,112.01) 85.37,112.42 85.22,112.57 84.84,112.57 84.68,112.42 84.68,111.07 84.53,110.92 84.15,110.92 84,111.07 84,112.34 83.85,112.5 83.46,112.5 83.31,112.34 83.31,111.07 83.16,110.92 82.57,110.92 82.42,111.07 82.42,112.48 83.11,113.16 83.11,116.78 v2(77.84,122.05) 72.78,127.12 71.04,128.85 69.17,128.85 65.85,132.18
  L3 w0.152: v1(98.65,116.66) 98.51,116.66 95.81,113.96 95.81,113.48 92.76,110.43 87.58,110.43 86,112.01 v3(85.37,112.01)
MEM_MA_DATA58: length 59.8
  TOP w0.165: v3(80.37,111.27) 80.37,112.01 v2(77.22,115.16) 76.08,116.3 76.08,118.44 67.61,126.9 67.61,127.41 63.55,131.47 CPU1.BA32 ; v1(99.24,112.54) 98.12,113.67 98.12,113.94 95.81,116.25 DIMM1.191
  L3 w0.152: v3(80.37,111.27) 85.33,106.3 93.66,106.3 97.38,110.03 97.38,110.84 99.09,112.54 v1(99.24,112.54)
MEM_MA_DATA59: length 61.3
  TOP w0.102: CPU1.AY31 63,134.13 63.3,133.83 63.3,133.52 63.16,133.37 63.16,133.05
  TOP w0.165: 63.16,133.05 63.16,131.14 66.98,127.31 66.98,126.59 75.41,118.16 75.41,115.52 v2(77.96,112.97) v3(79.27,111.66) ; DIMM1.193 95.86,115.65 97.71,113.79 97.71,113 v1(98.97,111.75)
  L3 w0.152: v3(79.27,111.66) 79.27,111.44 85.06,105.65 93.92,105.65 98.04,109.77 98.04,110.97 98.82,111.75 v1(98.97,111.75)
MEM_MA_DATA60: length 60.3
  TOP w0.165: v3(86.28,111) 87.35,111 87.5,111.15 87.5,111.79 87.35,111.94 86.44,111.94 86.28,112.09 86.28,112.52 86.44,112.67 87.27,112.67 87.43,112.83 87.43,117.43 87.27,117.58 85.13,117.58 v2(78.95,123.75) 72.35,130.35 68.93,130.35 66.39,132.89 66.39,133.61 CPU1.BA37 ; DIMM1.180 v1(101.4,119.55)
  L3 w0.152: v1(101.4,119.55) 101.4,118.88 100.4,117.88 100.38,117.88 99.14,116.64 99.14,116.46 98.85,116.18 98.53,116.18 96.22,113.86 96.22,113.24 92.76,109.78 87.14,109.78 86.28,110.64 v3(86.28,111)
MEM_MA_DATA61: length 60.8
  TOP w0.102: CPU1.AY36 65.75,134.51 66.05,134.2 66.05,133.91 66,133.84 66,133.57 66.14,133.43 66.14,132.77 66.34,132.56
  TOP w0.165: 66.34,132.56 69.03,129.87 71.9,129.87 v2(83.44,118.33) 84.85,116.92 86.59,116.92 86.74,116.76 86.74,113.74 86.59,113.59 86.21,113.59 86.06,113.74 86.06,116 85.9,116.15 85.12,116.15 84.97,116 v3(84.97,114.88) ; DIMM1.182 101.12,118.95 100.81,118.64 v1(100.48,118.64)
  L3 w0.152: v3(84.97,114.88) 88.12,111.73 92.76,111.73 95.02,114 95.02,114.35 97.96,117.29 97.96,117.8 98.3,118.15 98.51,118.15 98.6,118.24 100.08,118.24 v1(100.48,118.64)
MEM_MA_DATA62: length 58.2
  TOP w0.102: CPU1.BA33 64.1,132.64 64.38,132.36 64.38,131.93
  TOP w0.165: DIMM1.192 101.91,115.95 101.75,115.79 101.62,115.79 v1(101.37,115.54) ; v1(78.89,116.59) 77.72,116.59 77.44,116.86 77.44,117.58 77.6,117.73 77.85,117.73 78,117.88 78,118.39 77.85,118.54 77.6,118.54 77.44,118.69 77.44,119.33 v2(76.53,120.25) 69.77,127 69.24,127 64.38,131.86 64.38,131.93
  L3 w0.152: v1(78.89,116.59) 78.89,113.54 80.29,112.14 81.33,112.14 85.87,107.6 93.12,107.6 101.05,115.54 v1(101.37,115.54)
MEM_MA_DATA63: length 59.6
  TOP w0.102: CPU1.AY32 63.55,134.51 63.85,134.2 63.85,133.92 63.8,133.87 63.8,132.58 63.96,132.42 63.96,132.11
  TOP w0.165: v1(81.63,110.92) 81.63,111.74 79.81,113.56 79.81,113.79 79.96,113.94 79.96,114.17 79.72,114.41 79.49,114.41 79.34,114.26 79.11,114.26 78.87,114.5 78.87,114.73 79.02,114.88 79.02,115.11 78.79,115.35 78.55,115.35 78.41,115.2 78.17,115.2 76.74,116.63 v2(76.74,117.6) 76.74,118.71 63.96,131.49 63.96,132.11 ; DIMM1.194 102.07,115.35 101.47,114.76 v1(101.3,114.76)
  L3 w0.152: v1(81.63,110.92) 85.6,106.95 93.39,106.95 96.8,110.37 96.8,110.78 100.77,114.76 v1(101.3,114.76)
MEM_MA_DM0: length 53
  TOP w0.102: CPU1.B32 63.78,155.48 63.78,155.75 63.85,155.82 63.85,156.08 63.8,156.13 63.8,157.24 66.27,159.72 70.21,159.72 70.82,160.32
  TOP w0.165: DIMM1.11 95.92,172.65 96.08,172.81 97.49,172.81 v1(98.65,173.97) ; 70.82,160.32 v2(79.85,169.35) 88.17,177.67 91.85,177.67 92.38,177.14 93.89,177.14 v3(94.27,177.53)
  L3 w0.152: v3(94.27,177.53) 94.13,177.39 94.13,176.98 95.64,175.46 96.51,174.6 96.51,174.32 96.5,174.32 96.5,174.03 97.01,173.52 98.46,173.52 98.65,173.71 v1(98.65,173.97)
MEM_MA_DM1: length 46.4
  TOP w0.102: CPU1.B38 66.85,155.48 67.15,155.78 67.15,156.08 67.1,156.13 67.1,156.45 67.3,156.65 68.55,156.65
  TOP w0.165: 68.55,156.65 74.79,156.65 74.98,156.46 77.09,156.46 v2(79.59,158.96) 88.48,167.85 v3(88.48,168.22) ; v3(100.86,168.18) 101.49,167.55 DIMM1.28
  L3 w0.152: v3(100.86,168.18) 100.06,168.18 99.25,168.99 96.07,168.99 93.36,171.7 90.86,171.7 90.45,171.3 90.45,170.2 v3(88.48,168.22)
MEM_MA_DM2: length 42.2
  TOP w0.102: CPU1.G40 68.35,152.7 68.66,153.01 72.51,153.01 v3(73.43,153.93)
  TOP w0.165: DIMM1.46 100.71,162.15 100.71,162.15 v1(100.64,162.15)
  L3 w0.152: v1(100.64,162.15) 99.67,163.12 95.74,163.12 93.72,165.13 86.42,165.13 76.64,155.35 74.85,155.35 v3(73.43,153.93)
  BOTTOM w0.165: v6(101.45,162.05) 101.35,162.15 v1(100.64,162.15)
MEM_MA_DM3: length 41.4
  TOP w0.165: v3(93.12,158.78) 93.34,158.55 93.34,158.24 93.22,158.12 92.71,158.12 92.58,157.99 92.58,157.48 92.71,157.35 93.34,157.35 93.47,157.23 93.47,156.59 93.22,156.34 92.08,156.34 91.82,156.59 91.82,157.35 91.49,157.68 88.17,157.68 85.14,154.65 85.14,154.42 85.23,154.33 85.23,154.1 84.99,153.86 84.76,153.86 84.67,153.95 84.44,153.95 84.2,153.71 84.2,153.48 84.29,153.39 84.29,153.16 84.06,152.92 83.82,152.92 83.74,153.01 83.5,153.01 83.27,152.77 83.27,152.54 83.35,152.45 83.35,152.22 83.12,151.98 82.88,151.98 82.8,152.07 82.56,152.07 82.33,151.84 82.33,151.6 82.42,151.52 82.42,151.28 82.18,151.05 81.95,151.05 81.86,151.13 81.63,151.13 81.39,150.9 81.39,150.67 81.48,150.58 81.48,150.34 81.24,150.11 81.01,150.11 80.92,150.2 80.69,150.2 80.07,149.58 v2(76.17,149.58) 75.03,149.58 74.42,148.97 70.28,148.97 69.96,149.29 68.91,149.29 CPU1.N41 ; v1(96.44,157.25) 96.24,157.05 DIMM1.63
  L3 w0.152: v1(96.44,157.25) 95.51,157.25 93.98,158.78 v3(93.12,158.78)
MEM_MA_DM4: length 41.8
  TOP w0.102: 70.72,141.74 70.05,141.74 69.62,142.17 69.17,142.17 69.01,142 68.63,142 68.33,141.7 CPU1.AG40
  TOP w0.165: v1(91.54,130.26) 90.65,130.26 90.25,130.66 88.72,130.66 86.32,133.06 86.32,133.37 v2(84.99,134.69) 78.74,140.94 75.53,140.94 74.74,141.74 70.72,141.74 ; DIMM1.136 102.97,132.75 v1(101.61,132.75)
  L3 w0.152: v1(101.61,132.75) 96.37,132.75 93.33,129.71 92.08,129.71 v1(91.54,130.26)
MEM_MA_DM5: length 46.3
  TOP w0.165: v1(98.55,127.64) 97.87,126.95 96.63,126.95 95.93,127.65 DIMM1.153 ; CPU1.AN41 70.82,138.4 v2(80.48,128.74) 86.31,122.91 92.99,122.91 93.14,122.76 93.14,122.33 92.99,122.18 v1(91.59,122.18)
  L3 w0.152: v1(91.59,122.18) 91.73,122.18 97.01,127.46 98.37,127.46 v1(98.55,127.64)
MEM_MA_DM6: length 48.4
  TOP w0.102: v3(69.6,133.88) 69.6,133.89 69.15,134.33 69.15,134.45 68.95,134.65 68.35,134.65 CPU1.AY40
  TOP w0.152: v1(100.63,122.66) 100.63,122.66 100.74,122.55 DIMM1.170
  L3 w0.152: v1(100.63,122.66) 100.33,122.66 100.18,122.51 100.18,122.02 100.03,121.87 99.69,121.87 99.54,122.02 99.54,122.17 99.39,122.33 98.09,122.33 96.54,120.77 96.54,120.19 95.48,119.14 95.48,118.35 93.04,115.91 89.92,115.91 75.02,130.81 72.67,130.81 v3(69.6,133.88)
  BOTTOM w0.165: v6(101.68,122.78) v1(100.63,122.66)
MEM_MA_DM7: length 60.5
  TOP w0.102: 65.57,131.93 65.37,132.13 65.37,132.43 64.85,132.94 64.85,133.28 64.9,133.33 64.9,133.83 64.95,133.88 64.95,134.22 64.65,134.52 CPU1.AY34
  TOP w0.165: v3(81.64,114.4) 81.64,113.44 81.79,113.28 82.29,113.28 82.45,113.44 82.45,115.01 82.29,115.16 81.56,115.16 81.41,115.32 81.41,115.7 81.56,115.85 82.3,115.85 82.45,116 82.45,116.51 82.29,116.66 81.03,116.66 80.88,116.81 80.88,118.07 v2(75.35,123.61) 70.58,128.37 69.13,128.37 65.57,131.93 ; v1(98.38,115.31) 96.24,117.45 DIMM1.187
  L3 w0.152: v3(81.64,114.4) 81.64,114 86.5,109.13 92.76,109.13 96.62,112.99 96.62,113.76 98.17,115.31 v1(98.38,115.31)
MEM_MA_DM8: length 1.7
  TOP w0.165: v3(67.08,145.47) 67.13,145.41 67.62,145.41 CPU1.Y40
  BOTTOM w0.165: v3(67.08,145.47) 67.03,145.41 66.41,145.41 TP1.1
MEM_MA_DQS_N0: length 54.3
  TOP w0.102: CPU1.A33 64.19,156.39 64.19,157.35 66.35,159.51 70.97,159.51 71.95,160.49 71.95,160.52 71.97,160.54
  TOP w0.127: v3(90.81,177.06) 91.14,176.74 91.14,176.61 90.95,176.43 88.8,176.43 ; v2(88.8,176.78) 88.8,176.43 ; 88.8,176.43 87.85,176.43 71.97,160.54 ; v1(100.98,173.02) 100.67,172.72 100.67,172.51 100.87,172.31 101.52,172.31 102.16,172.95 DIMM1.10
  L3 w0.114: v3(90.81,177.06) 90.93,177.06 91.08,177.22 91.08,177.55 91.47,177.93 92.71,177.93 96.17,174.46 96.17,173.89 96.87,173.18 98.86,173.18 99.57,173.89 100.51,173.89 100.76,173.63 100.76,173.24 v1(100.98,173.02)
MEM_MA_DQS_N1: length 47.2
  TOP w0.127: v1(97.26,168.48) 97.56,168.48 97.71,168.33 97.71,167.84 98.07,167.49 98.78,167.49 98.93,167.34 98.93,167.06 98.78,166.9 97.51,166.9 96.91,167.5 96.3,167.5 95.96,167.85 DIMM1.27 ; v3(90.99,170.78) 90.99,170.27 90.8,170.08 90.25,170.08 ; 90.25,170.08 v2(90.25,170.46) ; 90.25,170.08 89.99,170.08 89.12,169.21 89.12,167.41 77.53,155.82 74.89,155.82 74.39,156.32 68.22,156.32 CPU1.A40
  L3 w0.114: v3(90.99,170.78) 91.19,170.59 91.37,170.59 91.53,170.75 93.54,170.75 96.61,167.68 97.24,167.68 97.71,168.15 97.71,168.33 97.56,168.48 v1(97.26,168.48)
MEM_MA_DQS_N2: length 43.5
  TOP w0.102: v3(71.34,152.43) 71.53,152.43 71.67,152.28 71.67,152.02 71.53,151.88 70.49,151.88 70.01,152.35 68.72,152.35 68.62,152.45 68.28,152.45 67.98,152.15 CPU1.H40
  TOP w0.127: DIMM1.45 96.17,162.45 96.51,162.1 96.99,162.1 97.45,161.65 97.86,161.65 98.03,161.81 98.03,162.12 v1(97.67,162.48)
  L3 w0.114: v3(71.34,152.43) 71.8,152.89 71.8,153.1 72.17,153.48 73.66,153.48 74.83,154.65 76.85,154.65 86.7,164.5 93.76,164.5 96.22,162.05 97.23,162.05 v1(97.67,162.48)
  BOTTOM w0.127: v6(70.11,153.07) 70.3,152.87 70.75,152.87 71.19,152.43 v3(71.34,152.43)
MEM_MA_DQS_N3: length 41.4
  TOP w0.102: CPU1.P40 68.28,149.15 68.59,149.15 68.69,149.05 69.68,149.05 70.11,148.61 70.43,148.61 70.46,148.64 70.48,148.64
  TOP w0.127: DIMM1.62 100.53,157.35 100.26,157.08 v3(99.84,157.08) ; 87.4,155.35 88.82,156.78 v3(88.82,157.05) ; 87.4,155.35 80.85,148.81 75.35,148.81 75.17,148.64 70.48,148.64 ; 87.4,155.35 v2(87.15,155.6)
  L3 w0.114: v3(99.84,157.08) 99.84,156.84 99.54,156.53 95.74,156.53 93.97,158.3 90.08,158.3 v3(88.82,157.05)
MEM_MA_DQS_N4: length 42.5
  TOP w0.102: CPU1.AH40 68.3,141.45 68.62,141.45 68.72,141.35 70.74,141.35 70.76,141.38 70.77,141.38
  TOP w0.127: 70.77,141.38 74.55,141.38 75.65,140.28 78.49,140.28 85.67,133.1 85.67,132.79 88.49,129.98 89.54,129.98 89.82,129.7 ; v1(98.38,132.22) 98.15,132.46 98.15,132.72 97.81,133.05 DIMM1.135 ; 89.82,129.7 90.09,129.42 90.09,129.03 v1(90.23,128.89) ; 89.82,129.7 v2(90.07,129.95)
  L3 w0.114: v1(90.23,128.89) 90.54,129.2 91.3,129.2 91.72,128.78 93.29,128.78 95.99,131.47 97.75,131.47 98.04,131.77 98.04,131.88 v1(98.38,132.22)
MEM_MA_DQS_N5: length 47
  TOP w0.102: CPU1.AP40 68.01,137.85 68.32,138.15 68.62,138.15 68.67,138.1 68.93,138.1 68.94,138.11 70.51,138.11 71.29,137.33 71.4,137.22 71.43,137.22 71.44,137.21
  TOP w0.127: 71.44,137.21 73.94,134.71 73.94,134.01 86.46,121.49 87.76,121.49 88.14,121.87 ; v2(87.88,122.12) 88.14,121.87 ; 88.14,121.87 88.34,122.07 89.53,122.07 v1(89.77,122.31) ; DIMM1.152 100.11,127.95 v1(99.35,127.19)
  L3 w0.114: v1(89.77,122.31) 89.77,122.06 90.02,121.82 90.47,121.82 90.84,121.45 91.93,121.45 95.82,125.34 95.82,125.79 97.02,126.99 99.15,126.99 v1(99.35,127.19)
MEM_MA_DQS_N6: length 49
  TOP w0.127: DIMM1.169 95.96,122.85 96.05,122.76 98.65,122.76 99.36,122.05 99.36,121.54 v1(99.53,121.37) ; CPU1.AY41 68.8,134.07 69.6,133.27 70.23,133.27 70.66,132.84 70.66,132.36 70.47,132.17 v1(70.47,131.71)
  L3 w0.114: v1(70.47,131.71) 71.12,131.63 72.7,130.05 72.85,129.9 74.58,129.9 89.51,114.97 93.07,114.97 96.15,118.05 96.15,118.67 98.19,120.71 98.63,120.71 v1(99.53,121.37)
  BOTTOM w0.127: v6(70.99,131.19) v1(70.47,131.71)
MEM_MA_DQS_N7: length 58.9
  TOP w0.127: CPU1.BA34 64.65,133.96 64.67,133.94 64.67,133.41 64.63,133.37 64.63,132.81 65.07,132.37 65.07,131.88 68.99,127.97 70.08,127.97 80.24,117.81 80.24,116.1 ; DIMM1.186 102.31,117.75 102.11,117.55 100.66,117.55 100.3,117.2 100.3,116.84 100.11,116.64 v1(99.82,116.64) ; 80.24,116.1 80.24,115.39 80.39,115.24 v3(80.65,115.24) ; 80.24,116.1 v2(80.59,116.1)
  L3 w0.114: v1(99.82,116.64) 100.15,116.64 100.39,116.4 100.39,115.74 93.16,108.5 86.24,108.5 81.59,113.16 80.54,113.16 80.36,113.34 80.36,114.95 v3(80.65,115.24)
MEM_MA_DQS_P0: length 55
  TOP w0.102: 72.15,160.36 72.13,160.35 72.1,160.35 71.9,160.15 71.06,159.31 66.44,159.31 64.39,157.26 64.39,156.44 64.41,156.41 64.41,156.18 CPU1.B33
  TOP w0.127: v1(100.11,173.02) 100.42,172.72 100.42,172.4 100.76,172.06 101.63,172.06 101.92,172.35 DIMM1.12 ; v3(91.64,177.06) 91.39,176.81 91.39,176.5 91.06,176.17 87.96,176.17 72.15,160.36
  L3 w0.114: v3(91.64,177.06) 91.55,177.06 91.35,177.27 91.35,177.44 91.58,177.66 92.59,177.66 95.9,174.35 95.9,173.78 96.76,172.91 98.97,172.91 99.68,173.62 100.4,173.62 100.5,173.52 100.5,173.38 100.14,173.02 v1(100.11,173.02)
  BOTTOM w0.127: v6(91.24,176.4) 91.64,176.81 v3(91.64,177.06)
MEM_MA_DQS_P1: length 47.2
  TOP w0.127: CPU1.B40 68.61,156.07 74.29,156.07 74.79,155.57 77.64,155.57 89.37,167.3 89.37,168.68 ; 89.37,168.68 v2(89.74,168.68) ; 89.37,168.68 89.37,169.1 90.09,169.82 90.91,169.82 91.18,170.1 v3(91.41,170.1) ; v1(98.22,168.48) 97.97,168.23 97.97,167.95 98.17,167.74 98.89,167.74 99.19,167.44 99.19,166.95 98.89,166.65 97.41,166.65 96.81,167.25 DIMM1.29
  L3 w0.114: v3(91.41,170.1) 91.41,170.25 91.64,170.48 93.43,170.48 96.5,167.41 97.35,167.41 98.22,168.27 v1(98.22,168.48)
MEM_MA_DQS_P2: length 43
  TOP w0.102: CPU1.H41 69.93,152.15 70.4,151.67 71.61,151.67 71.88,151.94 71.88,152.25 v3(72.06,152.44)
  TOP w0.127: DIMM1.47 96.89,161.85 97.35,161.39 97.97,161.39 98.29,161.71 98.29,162.12 v1(98.65,162.48)
  L3 w0.114: v1(98.65,162.48) 97.95,161.78 96.11,161.78 93.65,164.24 86.81,164.24 76.96,154.38 74.94,154.38 73.77,153.21 72.28,153.21 72.06,152.99 v3(72.06,152.44)
  BOTTOM w0.127: v6(99.47,162.18) 99.16,162.48 v1(98.65,162.48)
MEM_MA_DQS_P3: length 41.3
  TOP w0.102: 70.48,148.38 70.46,148.38 70.43,148.41 70.03,148.41 69.59,148.85 68.61,148.85 68.61,148.85 CPU1.P41
  TOP w0.127: 70.48,148.38 75.28,148.38 75.45,148.56 80.96,148.56 88.69,156.29 ; 88.69,156.29 89.26,156.86 v3(89.59,156.86) ; 88.69,156.29 v2(88.95,156.03) ; v3(100.44,156.48) 100.44,156.9 100.63,157.1 102.01,157.1 102.36,156.75 DIMM1.64
  L3 w0.114: v3(89.59,156.86) 89.43,157.01 89.43,157.28 90.19,158.03 93.86,158.03 95.63,156.27 99.65,156.27 100.02,156.64 100.28,156.64 v3(100.44,156.48)
MEM_MA_DQS_P4: length 42.5
  TOP w0.102: CPU1.AH41 70.67,141.15 70.69,141.12 70.85,141.12
  TOP w0.127: DIMM1.137 95.75,132.45 96.09,132.8 97.71,132.8 97.89,132.61 97.89,132.26 97.8,132.17 97.45,132.17 v1(97.4,132.22) ; v2(78.79,139.12) 79.04,139.37 ; 79.04,139.37 78.38,140.03 75.54,140.03 74.45,141.12 70.85,141.12 ; 79.04,139.37 85.42,132.99 85.42,132.69 88.38,129.73 89.43,129.73 89.84,129.32 89.84,129.18 89.55,128.89 v1(89.36,128.89)
  L3 w0.114: v1(97.4,132.22) 97.6,132.22 97.78,132.04 97.78,131.88 97.63,131.74 95.88,131.74 93.18,129.04 91.83,129.04 91.41,129.47 90.43,129.47 90.32,129.36 89.56,129.36 89.36,129.17 v1(89.36,128.89)
MEM_MA_DQS_P5: length 46.9
  TOP w0.102: CPU1.AP41 68.49,137.89 69.01,137.89 69.02,137.91 70.43,137.91 71.14,137.19 71.14,137.18 71.15,137.18 71.15,137.18 71.2,137.13 71.19,137.12 71.19,137.1 71.2,137.09
  TOP w0.127: DIMM1.154 102.3,127.35 101.95,127.7 100.22,127.7 100.13,127.61 100.13,127.4 v1(100.33,127.19) ; 86.64,121.24 v2(86.64,120.88) ; 86.64,121.24 86.35,121.24 73.69,133.9 73.69,134.61 71.2,137.09 ; 86.64,121.24 87.86,121.24 88.44,121.82 89.6,121.82 89.77,121.65 v1(89.77,121.33)
  L3 w0.114: v1(89.77,121.33) 90,121.55 90.36,121.55 90.73,121.18 92.04,121.18 96.08,125.22 96.08,125.68 97.13,126.73 99.87,126.73 v1(100.33,127.19)
MEM_MA_DQS_P6: length 48.9
  TOP w0.127: v1(98.55,121.37) 98.87,121.37 99.11,121.61 99.11,121.94 98.55,122.5 96.21,122.5 95.96,122.25 DIMM1.171 ; v1(69.93,132.25) 70.2,132.25 70.41,132.46 70.41,132.74 70.13,133.02 69.49,133.02 68.65,133.86 68.36,133.86 CPU1.BA40
  L3 w0.114: v1(69.93,132.25) 70.34,132.66 70.46,132.66 72.97,130.16 74.47,130.16 74.69,130.16 89.62,115.23 92.96,115.23 95.88,118.16 95.88,118.78 98.08,120.97 98.4,120.97 98.55,121.13 v1(98.55,121.37)
  BOTTOM w0.127: v6(69.42,132.77) v1(69.93,132.25)
MEM_MA_DQS_P7: length 59
  TOP w0.127: CPU1.AY33 64.1,134.15 64.42,133.83 64.42,133.52 64.38,133.48 64.38,132.71 64.82,132.27 64.82,131.77 68.88,127.71 69.97,127.71 79.25,118.44 ; v2(78.99,118.19) 79.25,118.44 ; 79.25,118.44 79.98,117.7 79.98,115.42 v3(79.8,115.24) ; DIMM1.188 102.23,117.15 102.08,117.3 100.77,117.3 100.56,117.09 100.56,116.89 v1(100.78,116.66)
  L3 w0.114: v3(79.8,115.24) 80.09,114.95 80.09,113.23 80.43,112.89 81.47,112.89 86.13,108.24 93.27,108.24 100.66,115.63 100.66,116.54 v1(100.78,116.66)
MEM_MA_EVENT_L: length 74.2
  TOP w0.165: CPU1.AE34 64.3,142.79 64.64,142.44 v1(64.64,142.29) ; DIMM1.198 102.39,114.15 101.31,113.07 v3(101.26,113.07)
  L3 w0.152: v1(64.64,142.29) 64.61,142.29 63.57,141.25 63.57,138.86 66.32,136.12 66.32,133.01 74.81,124.52 v3(74.81,116.42) 74.81,114.98 84.79,105 94.73,105 100.28,110.55 100.28,112.09 v3(101.26,113.07)
  BOTTOM w0.165: R1.2 v2(74.64,115.29) 74.64,116.25 v3(74.81,116.42) ; v1(64.64,142.29) 64.64,142.29 R2.2
MEM_MA_RAS#: length 43.3
  TOP w0.165: CPU1.AJ37 65.9,140.3 v3(66.21,139.99) ; v1(101.6,140.55) DIMM1.110
  L3 w0.152: v1(101.6,140.55) 99.51,138.46 96.38,138.46 93.05,135.13 81.18,135.13 81.03,135.28 81.03,136.5 80.87,136.65 79.88,136.65 79.88,136.65 79.46,136.65 72.75,136.65 70.78,138.62 68.34,138.62 67.4,139.56 66.64,139.56 v3(66.21,139.99)
  BOTTOM w0.165: v1(101.6,140.55) v6(102.31,140.55)
MEM_MA_RESET#: length 55.8
  TOP w0.14: CPU1.G38 66.7,152.81 v3(67.18,153.29)
  TOP w0.165: v3(101.63,166.95) 101.7,166.95 101.7,166.95 DIMM1.30
  L3 w0.152: v3(101.63,166.95) 102.09,166.49 102.09,154.78 101.38,154.08 95.28,154.08 94.44,154.91 83.16,154.91 79.29,151.04 72.42,151.04 71.75,150.38 70.63,150.38 67.72,153.29 v3(67.18,153.29)
  BOTTOM w0.165: v2(104.09,167.07) C159.2 101.75,167.07 v3(101.63,166.95)
MEM_MA_WE#: length 39.9
  TOP w0.165: v3(65.48,139.99) 65.1,139.62 CPU1.AL35 ; DIMM1.113 96.04,139.65 v1(96.39,139.29)
  L3 w0.152: v3(65.48,139.99) 65.48,140.25 65.66,140.44 70.22,140.44 72.82,137.85 72.82,137.8 72.97,137.65 75.48,137.65 75.51,137.67 81.99,137.67 82.14,137.52 82.14,136.3 82.29,136.14 82.75,136.14 82.88,136.27 82.88,137.08 83.03,137.24 83.44,137.24 83.62,137.06 83.62,136.3 83.77,136.14 93.06,136.14 96.21,139.29 v1(96.39,139.29)
  BOTTOM w0.165: v6(65.51,139.29) 65.48,139.32 v3(65.48,139.99)
MEM_VREFCA_SUS: length 9.9
  TOP w0.305: v3(104.56,133.92) 104.56,135.31 104.13,135.75 DIMM1.126
  BOTTOM w0.508: R146.1 104.73,130.78 C175.1 R142.1 C176.2 105.18,133.01 105.54,133.38 v2(105.54,133.93) 105.52,133.92 v3(104.56,133.92) 104.51,133.97 R140.2
MEM_ZVDDIO: length 4
  TOP w0.114: R4.1 v4(71.28,143.72) 71.09,143.54 69.95,143.54 69.77,143.35 CPU1.AD41
MIC2: length 4.1
  TOP w0.203: C255.2 C254.2 125.22,32.42 R234.1 125.77,31.9 125.78,31.92 125.78,31.93 126.36,32.51 v2(126.36,32.99)
MIC_IN_JACK: length 6
  TOP w0.254: L18.1 127.99,33.26 R234.2 126.63,31.58 126.3,31.25 R235.1 R232.1 126.3,28.82 v2(126.5,28.61)
MIC_VREFL: length 12.4
  TOP w0.203: v1(117.93,35.51) 117.78,35.36 AUDIO1.31
  TOP w0.254: v1(124.33,29.46) 124.46,29.59 R232.2
  BOTTOM w0.254: v1(124.33,29.46) 123.91,29.46 v2(122.43,30.95) 122.43,32.97 119.89,35.51 v1(117.93,35.51)
MIC_VREFR: length 3.9
  TOP w0.203: TP32.1 118.44,37.59 118.44,35.26 118.18,35 AUDIO1.30
MODE_CFG0: length 8.9
  BOTTOM w0.114: R600.1 22.58,107.2 R601.1 22.09,104.78 22.09,103.84 v6(22.73,103.2) 22.98,102.95 22.98,101.02 22.88,100.92 U38.47
MODE_CFG1: length 8.7
  BOTTOM w0.114: U38.48 23.28,100.8 23.35,100.86 23.35,102.6 24.1,103.35 24.1,104.77 R605.1 v6(23.61,106.27) 23.61,106.98 R604.1
NGFF_SUSCLK: length 9.5
  TOP w0.114: TP70.1 30.02,23.14 31.66,23.14 32.32,22.48 32.32,18.02 32.05,17.75 NGFFE1.50
OCP_0: length 9.4
  BOTTOM w0.114: PR3.2 122.18,11.41 122.18,7.94 122.38,7.75 U48.2 v2(125.07,7.75) 125.34,8.01 PR2.1 PC1.1
OCP_1: length 18.3
  TOP w0.114: PR4.2 131.25,12.9 129.73,12.9 PR7.2 126.03,13.51 124.31,11.79 122.35,11.79 v3(121.67,11.1)
  BOTTOM w0.114: v3(121.67,11.1) 121.26,10.69 v2(121.26,10.39) 121.26,7.32 122.1,6.48 U48.3
OCP_2: length 5.8
  BOTTOM w0.114: U48.1 124.1,9.02 124.76,9.68 v2(124.94,9.68) 125.46,9.68 PR2.2 PC1.2 PR4202.1
OCP_3: length 16.7
  BOTTOM w0.114: U48.5 120.8,5.21 121.98,4.03 129.2,4.03 129.69,4.52 129.69,5.28 v2(129.41,5.57) 129.13,5.85 PC4205.1 128.4,6.86 PR10.1 128.38,7.98 PR4202.2
OCP_6: length 7.4
  TOP w0.114: v1(113.77,11.81) 114.16,12.2 PR16.1 PR12.2
  BOTTOM w0.114: Q76.5 111.82,9.6 111.64,9.78 111.64,9.96 111.92,10.25 Q76.6 v2(112.68,11.53) 112.96,11.81 v1(113.77,11.81)
OCP_7: length 6.5
  BOTTOM w0.114: Q75.G 114.64,8.86 Q76.3 115.63,8.95 v2(116.2,9.53) 116.2,10.12 PR13.1 PR11.2
OCP_8: length 31.3
  BOTTOM w0.114: PC6.1 127.04,4.6 R810.1 124.75,5.84 122.07,5.84 121.44,6.48 U48.6 114.38,6.48 112.97,5.07 v2(108.33,5.07) 107.58,5.07 106.91,4.4 R809.1 R808.1
OZ554_EMA: length 8.9
  BOTTOM w0.254: U59.3 30.1,17.6 v2(30.52,17.19) 31.05,16.65 C322.1 33.1,16.65 R356.1 33.71,16.68 R354.1 35.36,16.7 R1028.1 36.46,16.65 Q4802.G
OZ554_PWM: length 7.5
  BOTTOM w0.254: U59.5 28.65,15.57 v2(30.1,14.12) 30.27,13.96 30.27,13.96 R353.1 R355.1 29.29,13.07 28.98,12.76 C323.1
OZ554_VIN: length 5.9
  BOTTOM w0.305: 29.97,16.46 29.33,17.1 U59.4
  BOTTOM w0.508: 29.97,16.46 29.97,16.28 30.68,15.57 v2(31.24,15.57) R339.2 C182.1
P_1.2V_EDP: length 30.3
  TOP w0.508: v3(25.23,94.39) 25.1,94.51 C509.1 v2(24.29,92.76) 24.29,91.24 v5(24.51,91.01) 24.12,90.62 C508.1 22.56,91.13 v3(22.56,92.1) 22.56,92.44 19.02,95.97 19.02,98.09 20.31,99.38 C510.1 21.21,100.29 v3(21.28,100.36)
  BOTTOM w0.203: v3(25.23,94.39) 25.15,94.47 U38.11 ; U38.15 22.48,92.2 22.49,92.2 22.49,92.17 v3(22.56,92.1) ; U38.43 v3(21.28,100.36)
  BOTTOM w0.508: v5(24.51,91.01) 24.51,90.58 25.73,89.37 C507.1 25.42,88.75 24.71,88.75 24.17,88.21 L52.2 23.62,90.04 23.42,90.24 R590.2
P_1.05VLAN_OUT:
  vias: v2(115.11,70.43)
P_3.3V_EDP_VDDIO: length 43.9
  TOP w0.508: v3(24.77,103.1) 24.21,102.54 24.21,100.74 25.1,99.85 v3(25.1,96.87) 24.7,96.47 C499.1 C500.1 25.48,95.58 26.11,94.95 v3(26.11,91.26) 26.11,91.06 26.7,90.47 L51.2 ; v3(18.08,108.57) 19.34,107.32 C498.1 19.34,104.73 v3(18.67,104.06)
  BOTTOM w0.203: U38.5 v3(25.1,96.87)
  BOTTOM w0.305: v3(26.11,91.26) 26.5,91.65 R591.1 27.01,91.64 R592.1
  BOTTOM w0.508: R599.1 18.67,104.07 v3(18.67,104.06) ; v3(24.77,103.1) 24.8,103.13 v2(24.8,104.78) 24.8,107.46 24.1,108.16 R604.2 23.71,108.36 R600.2 21.78,108.36 R598.1 21,108.34 20.76,108.57 v3(18.08,108.57) ; U58.8 15.55,107.39 16.74,108.57 v3(18.08,108.57) ; v3(18.08,108.57) 18.09,108.58 U58.3
P_3.3V_EDP_VDDIOX: length 15.9
  TOP w0.508: C506.1 20.01,89.42 C503.1 20.39,90.17 20.39,90.17 C505.1 20.4,91.23 v3(21.34,92.17) ; C506.1 18.89,88.05 C501.1 18.53,88.56 C502.1 19.02,89.73 19.37,90.09 C504.1 19.37,91.85 v3(19.68,92.16) ; C506.1 21.35,88.05 v2(21.44,87.96) 21.76,87.64 L53.2
  BOTTOM w0.203: U38.22 v3(19.68,92.16) ; v3(21.34,92.17) 21.28,92.23 U38.18
P_RX_ZVDD: length 19.9
  TOP w0.114: CPU1.W7 49.9,146.24 v3(49.5,146.63)
  BOTTOM w0.114: v3(49.5,146.63) 49.12,146.25 47.78,146.25 47.47,146.56 v2(45.24,146.56) 42.75,146.56 42.65,146.66 41.66,146.66 41.27,147.04 31.43,147.04 R9.1
P_TX_ZVDD: length 20.1
  TOP w0.114: v3(50.29,146.71) 50.29,146.51 CPU1.W8
  BOTTOM w0.114: v3(50.29,146.71) 49.58,146 47.6,146 47.31,146.29 45.83,146.29 45.21,145.67 v2(43.71,145.67) 43.18,145.67 42.56,146.29 41.45,146.29 41.17,146.57 R8.2
PB_IN_N_1: length 14.4
  BOTTOM w0.114: U6503.33 73.09,71.46 71.29,69.66 U31.75 71.29,67.12 71.68,66.73 71.68,63.86 71.37,63.55 v2(71.37,63.27) 71.37,62.4 C491.2 R575.1 72.7,62.06 R576.2
PCH_CLK48: length 53.9
  TOP w0.114: v3(77.65,92.04) 72.31,92.04 71.53,92.82 67.35,92.82 v2(66.82,93.35) 66.41,93.77 61.25,93.77 v3(61.19,93.83)
  BOTTOM w0.114: v3(61.19,93.83) 61.19,96.58 62.36,97.76 62.36,115.05 C33.2 55.92,121.88 55.43,122.37 R101.1 ; v3(77.65,92.04) 77.65,90.63 78.33,89.94 R547.1
PCH_CLK48_F: length 16.6
  TOP w0.114: CPU1.AP13 53.55,137.75 v3(53.58,137.75)
  BOTTOM w0.114: R101.2 53.71,122.82 v6(53.29,123.24) 53.29,126.24 53.04,126.49 53.04,136.49 53.22,136.66 53.22,137.42 53.55,137.75 v3(53.58,137.75)
PCH_SPKR1: length 6
  TOP w0.203: R360.1 123.65,25.44 R359.1 124.56,25.87 C325.2 126.25,25.87 v2(126.36,25.98) 126.36,26.11 125.43,27.05 C324.2
PCIE_C_RXN0: length 190
  TOP w0.127: CPU1.R8 50.7,148.36 v3(51.13,148.79)
  BOTTOM w0.127: 38.75,141.85 38.11,141.21 37.36,141.21 35.46,139.31 35.46,134.62 35.95,134.13 35.95,125.22 37.97,123.19 37.97,115.96 43.2,110.73 43.2,89.57 38.24,84.61 38.24,60 51.76,46.48 81.92,46.48 100.64,65.2 102.77,65.2 103.86,66.29 C276.2 ; 38.75,141.85 v2(38.99,141.6) ; 38.75,141.85 39.67,142.77 43.36,142.77 43.87,142.26 45.45,142.26 46.12,142.93 50.14,142.93 50.96,143.75 51.48,143.75 51.93,144.2 51.93,147.15 51.61,147.46 51.61,147.91 51.13,148.4 v3(51.13,148.79)
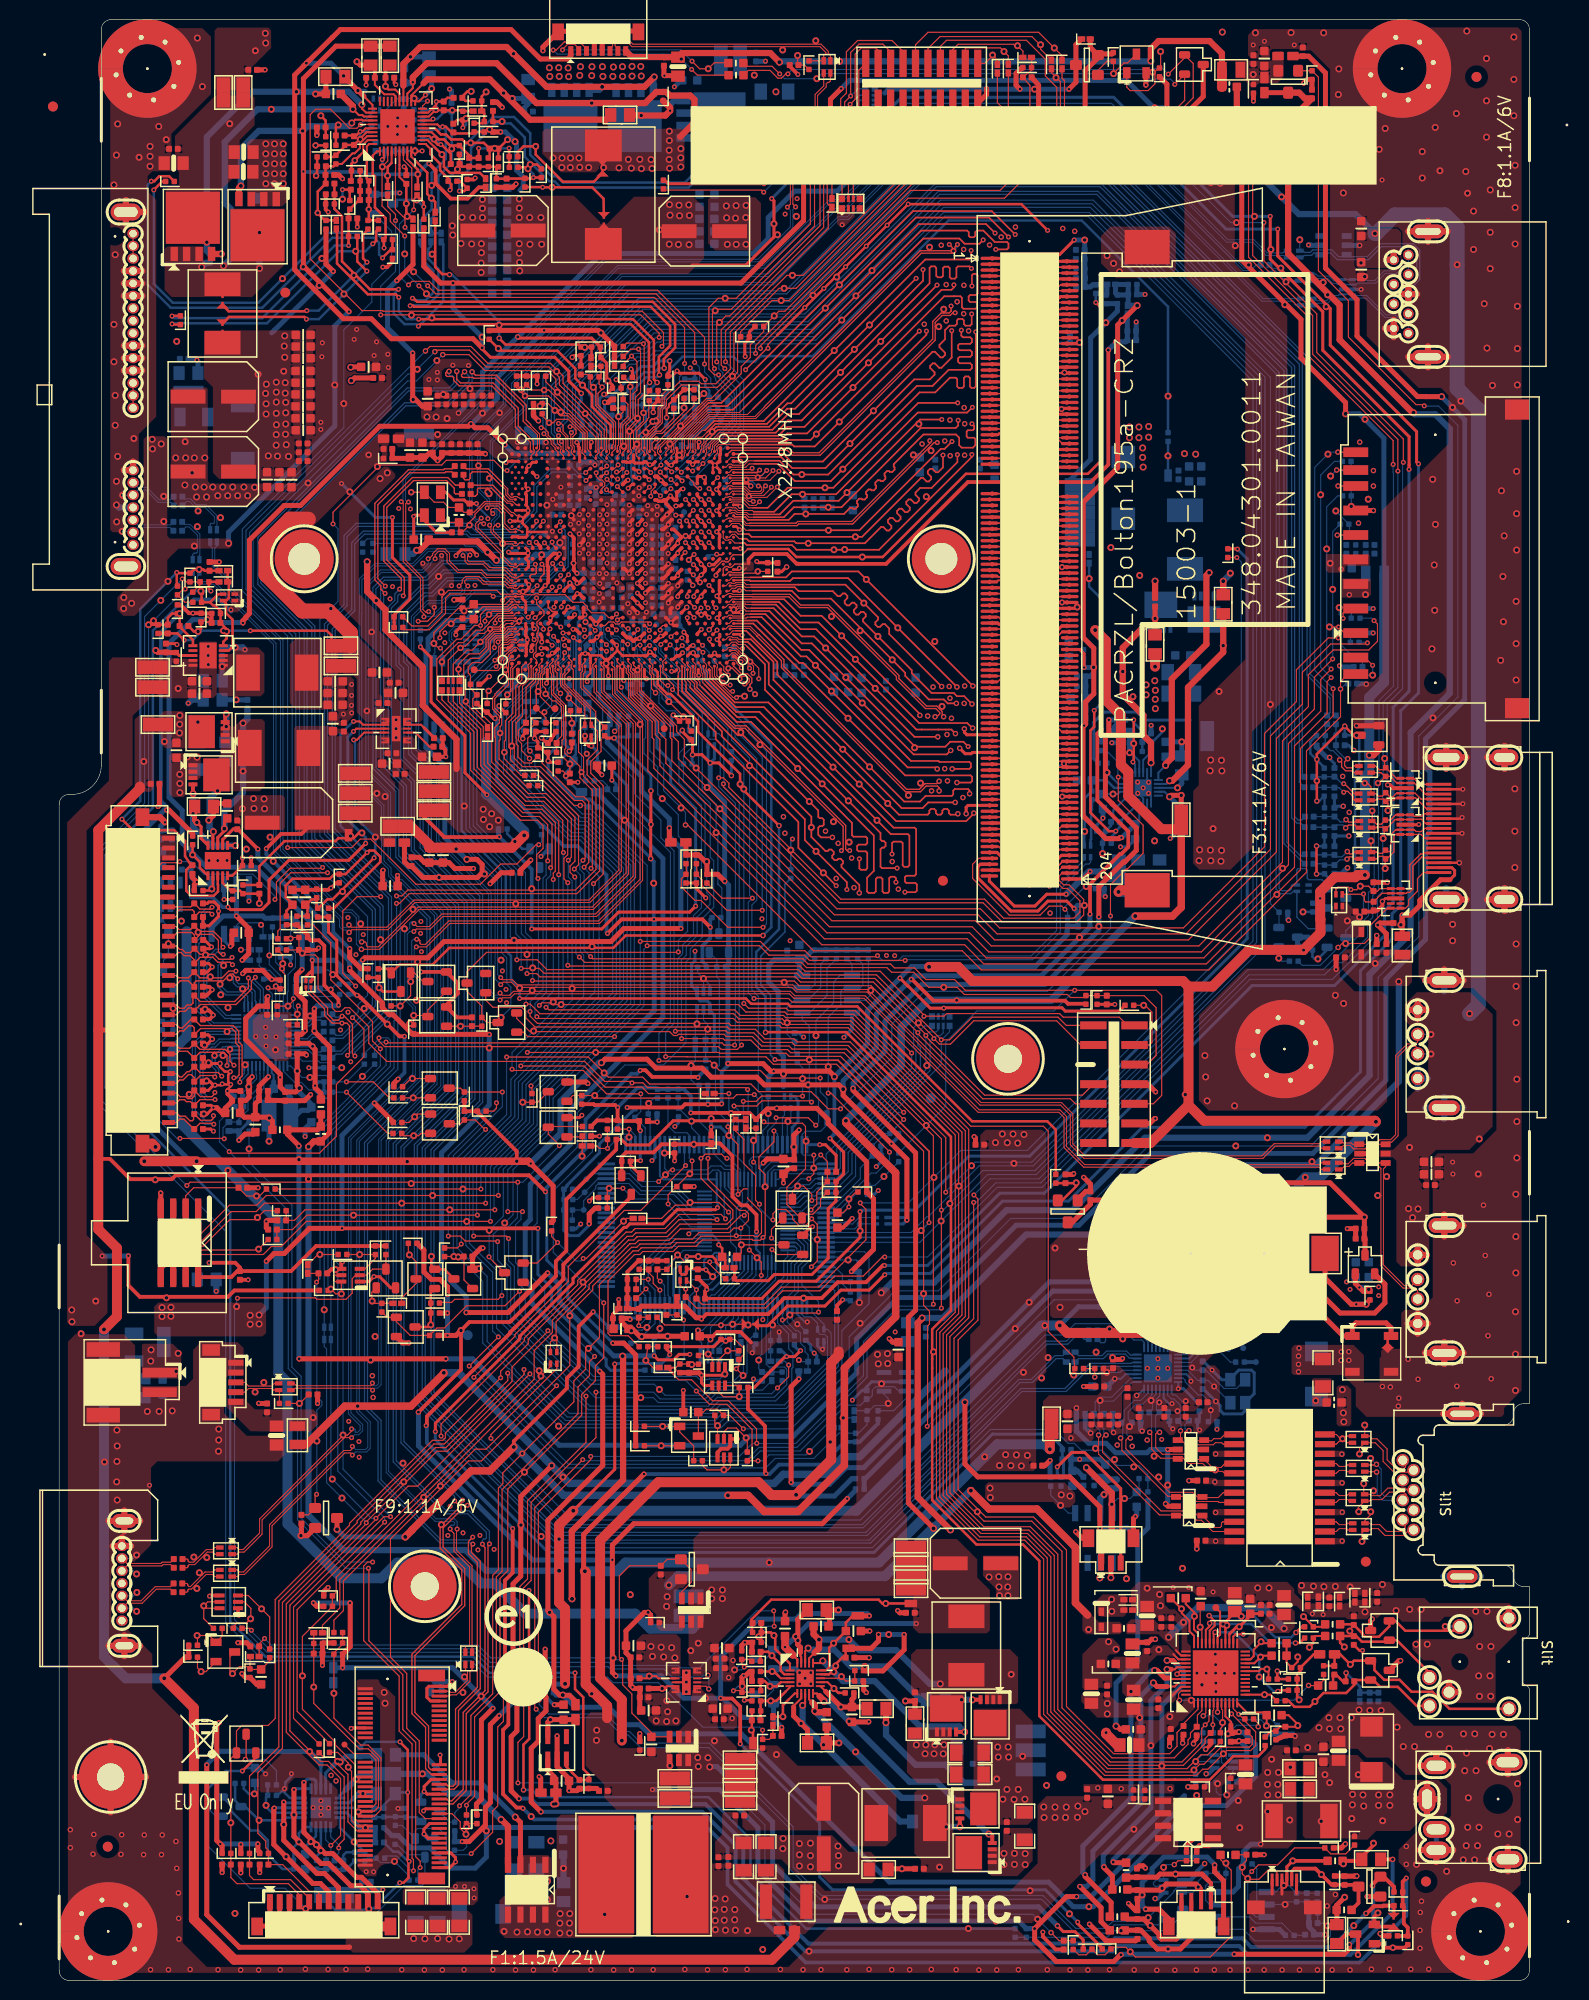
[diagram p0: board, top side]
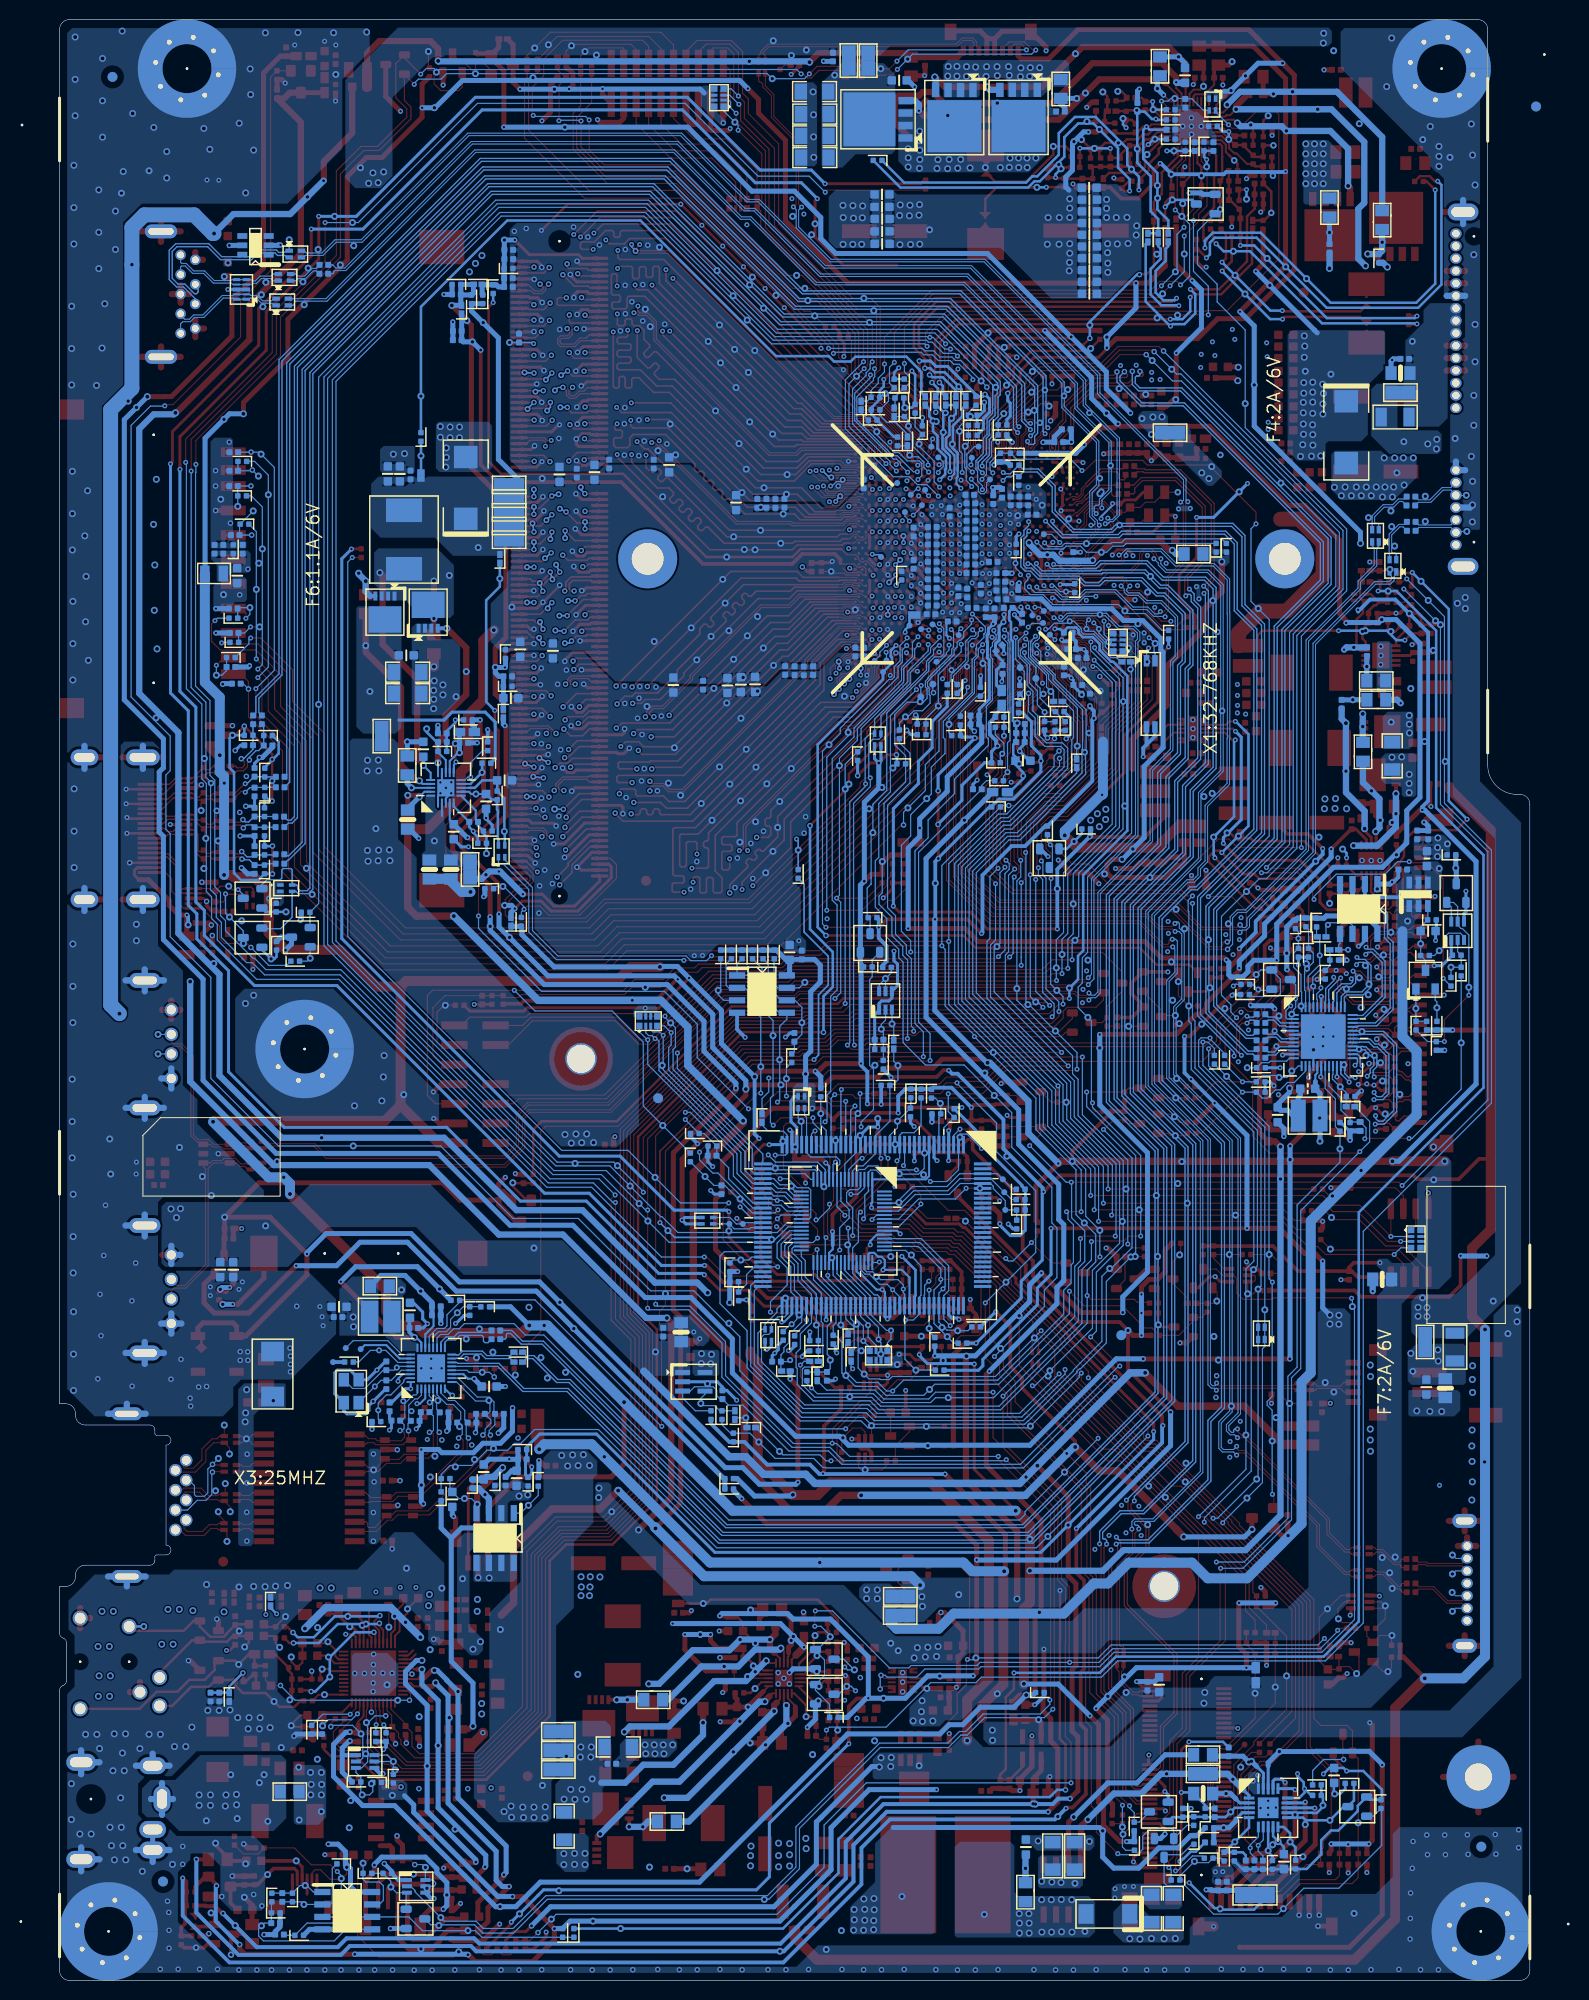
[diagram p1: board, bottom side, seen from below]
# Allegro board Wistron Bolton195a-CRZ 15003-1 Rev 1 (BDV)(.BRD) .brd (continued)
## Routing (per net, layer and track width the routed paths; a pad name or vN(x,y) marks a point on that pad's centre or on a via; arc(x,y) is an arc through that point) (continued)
PCIE_C_RXN1: length 165.8
  TOP w0.127: v3(42.2,44.5) 42.06,44.36 42.06,43.66 42.96,42.76 42.96,29.76 40.74,27.54 40.74,19.94 40.3,19.5 NGFFE1.43 ; CPU1.R4 48.69,148.69 v3(48.69,148.84)
  BOTTOM w0.127: 36.32,109.47 37.52,108.27 37.52,91.82 31.15,85.45 31.15,58.38 32.54,57 32.54,50.93 38.84,44.63 42.08,44.63 v3(42.2,44.5) ; 36.32,109.47 v2(36.09,109.25) ; 36.32,109.47 34.55,111.24 33.91,111.24 27.85,117.3 27.85,137.84 29.85,139.83 29.85,146.65 31.03,147.82 41.66,147.82 42.01,147.47 47.6,147.47 48.69,148.56 v3(48.69,148.84)
PCIE_C_RXP0: length 189.9
  TOP w0.127: v3(51.1,147.83) 51.1,147.9 CPU1.R10
  BOTTOM w0.127: 98.14,62.27 82.05,46.18 51.63,46.18 37.93,59.87 37.93,84.73 42.9,89.69 42.9,110.6 37.67,115.83 37.67,123.06 35.64,125.09 35.64,134.01 35.16,134.49 35.16,139.44 37.24,141.52 37.99,141.52 39.55,143.08 43.48,143.08 44,142.57 45.32,142.57 46,143.24 50.01,143.24 50.83,144.06 51.35,144.06 51.63,144.33 51.63,147.02 51.31,147.34 51.31,147.62 v3(51.1,147.83) ; 98.14,62.27 100.77,64.9 102.89,64.9 103.99,65.99 104.32,65.99 104.42,65.89 104.42,65.56 104.57,65.41 C277.2 ; 98.14,62.27 v2(98.37,62.03)
PCIE_C_RXP1: length 165.8
  TOP w0.127: v3(49.4,148.84) 49.1,148.54 CPU1.R5 ; NGFFE1.41 39.51,20 39.7,19.8 40.18,19.8 40.44,20.07 40.44,27.66 42.66,29.89 42.66,42.63 41.76,43.54 41.76,44.77 42.19,45.2 v3(42.19,45.21)
  BOTTOM w0.127: v3(49.4,148.84) 47.73,147.17 41.89,147.17 41.54,147.52 31.15,147.52 30.16,146.52 30.16,139.71 28.16,137.71 28.16,117.42 34.04,111.54 34.68,111.54 37.83,108.4 37.83,91.7 31.46,85.33 31.46,63.27 ; 31.46,63.27 31.46,58.51 32.84,57.12 32.84,51.05 38.96,44.93 41.91,44.93 42.16,45.19 v3(42.19,45.21) ; 31.46,63.27 v2(31.78,63.27)
PCIE_C_TXN0: length 195
  TOP w0.127: C5.2 40.44,151.62 40.31,151.75 40.31,152.2 39.52,152.98 36.16,152.98 33.43,150.25 33.43,144.88 35.21,143.1 35.21,141.33 v3(35.1,141.22)
  BOTTOM w0.127: 103.75,61.51 v2(103.5,61.75) ; 103.75,61.51 105.18,62.94 109.39,62.94 109.49,63.03 LAN1.14 ; 103.75,61.51 102.62,60.38 98.1,60.38 82.63,44.91 50.83,44.91 36.54,59.19 36.54,85.13 41.63,90.22 41.63,109.97 36.23,115.37 36.23,122.34 33.89,124.68 33.89,139.97 34.55,140.63 34.55,141.25 34.67,141.38 34.95,141.38 v3(35.1,141.22)
PCIE_C_TXN1: length 153
  TOP w0.127: v3(40.35,48.91) 40.69,48.56 40.69,48.11 38.86,46.28 38.86,44.09 41.07,41.89 41.07,38.35 35.99,33.27 35.99,27.2 37.38,25.81 37.38,21.6 37.98,21 NGFFE1.37 ; v3(33.27,142.21) 33.13,142.35 32.51,142.98 32.51,150.53 35.77,153.78 39.34,153.78 39.43,153.87 40.06,153.87 C7.2
  BOTTOM w0.127: v2(38.89,50.42) 39.09,50.62 ; 39.09,50.62 34.87,54.84 34.87,85.01 40.45,90.59 40.45,109.59 35.13,114.91 35.13,121.74 32.8,124.08 32.8,141.74 v3(33.27,142.21) ; 39.09,50.62 40.35,49.37 v3(40.35,48.91)
PCIE_C_TXP0: length 195
  TOP w0.127: v3(34.74,141.91) 34.9,142.07 34.9,142.97 33.12,144.75 33.12,150.38 36.03,153.29 39.65,153.29 40.43,152.51 C4.2
  BOTTOM w0.127: 36.23,81.28 36.23,59.07 50.7,44.6 82.76,44.6 98.23,60.07 102.74,60.07 105.3,62.63 LAN1.13 ; 36.23,81.28 36.23,85.26 41.32,90.35 41.32,109.85 35.93,115.24 35.93,122.21 33.58,124.56 33.58,140.1 34.24,140.76 34.24,141.41 v3(34.74,141.91) ; 36.23,81.28 v2(35.92,81.28)
PCIE_C_TXP1: length 153
  TOP w0.127: v3(41.16,48.98) 41,48.82 41,47.98 39.17,46.15 39.17,44.22 41.38,42.01 41.38,38.23 36.3,33.15 36.3,27.33 37.69,25.94 37.69,21.72 37.91,21.5 NGFFE1.35 ; C6.2 40.08,154.18 39.31,154.18 39.22,154.09 35.64,154.09 32.21,150.65 32.21,142.85 32.82,142.24 32.82,141.91 v3(33.25,141.48)
  BOTTOM w0.127: 35.18,83.52 v2(35.51,83.52) ; 35.18,83.52 35.18,84.89 40.75,90.46 40.75,109.72 35.43,115.04 35.43,121.87 33.1,124.2 33.1,141.33 v3(33.25,141.48) ; 35.18,83.52 35.18,54.97 v3(41.16,48.98)
PCIE_RST_N: length 5.8
  TOP w0.114: CPU1.AY9 50.9,134.14 51.21,133.83 51.21,133.34 51.15,133.28 51.15,132.08 51.92,131.32 51.92,130.86 v4(51.99,130.78) 53.06,129.71 R64.2
PCIE_RST_N_R: length 2.4
  TOP w0.114: C25.2 v2(52.3,128.24) 52.3,128.7 52.17,128.83 52.17,128.84 R64.1
PCIE_RXN_LAN_C: length 6.6
  BOTTOM w0.127: v2(107.16,66.45) 107.16,66.09 ; 107.16,66.09 109.3,66.09 109.75,65.63 110.57,65.63 111.09,65.11 LAN1.18 ; 107.16,66.09 106.13,66.09 C276.1
PCIE_RXP_LAN_C: length 6.7
  BOTTOM w0.127: LAN1.17 110.69,65.08 110.44,65.33 109.63,65.33 109.17,65.79 108.51,65.79 ; 108.51,65.79 v2(108.51,65.43) ; 108.51,65.79 106.91,65.79 106.76,65.63 106.76,65.2 106.6,65.05 106.29,65.05 C277.1
PCIE_WAKE_N_PCIE: length 141.9
  TOP w0.114: v3(50.75,60.66) 43.08,52.98 41.76,52.98 33.8,45.03 33.8,32.96 35.46,31.3 35.46,25.71 36.74,24.43 36.74,17.11 37.35,16.5 38.77,16.5 NGFFE1.55 ; v3(54.51,111.86) 55.5,112.85 55.5,121.87 54.23,123.14 54.23,124.31 55.28,125.36 55.28,126.58 55.22,126.65 55.22,127.4 R77.1 54.74,128.75 54.74,129.41 52.45,131.7 52.45,133.69 52.24,133.9 52.24,134.18 52.31,134.25 52.31,134.55 52,134.85 CPU1.AW11
  BOTTOM w0.114: v3(50.75,60.66) 50.5,60.66 v2(48.97,62.18) 44.63,66.52 44.63,72.42 41.85,75.19 41.85,83.45 46.48,88.08 46.48,91.78 55.02,100.32 55.02,105.61 54.51,106.12 v3(54.51,111.86)
PCIRST1#: length 43.2
  TOP w0.114: v2(50.55,65.53) 50.12,65.11 RN8.4 ; v2(50.55,65.53) 50.7,65.68 50.7,67.18 51.73,68.21 51.73,68.22 54.06,70.56 54.06,70.97 58.02,74.93 58.24,75.15 58.78,75.15 59.08,75.45 59.12,75.49 62.2,75.49 63.37,76.66 68.17,76.66 69.54,78.03 v3(69.89,78.03) ; v2(50.55,65.53) 50.77,65.31 RN8.3
  BOTTOM w0.114: RN10.4 74,88.24 73.79,88.04 U31.33 73.79,84.43 73.36,84 70.75,84 70.4,83.65 70.4,83.27 70.69,82.98 U6503.10 70.69,78.92 69.89,78.12 v3(69.89,78.03)
PCIRST2#: length 3.9
  BOTTOM w0.114: U31.34 74.29,87.57 v2(74.35,87.63) 74.65,87.93 RN10.3
PD: length 5.5
  BOTTOM w0.114: R175.1 v2(115.95,22.33) ; v2(115.95,22.33) 115.95,22.35 116.58,22.98 Q4.6 ; v2(115.95,22.33) Q4.5
PD#_C: length 14.2
  TOP w0.114: v1(116.73,26.98) 116.73,27.01 116.98,27.27 AUDIO1.4
  BOTTOM w0.114: v1(116.73,26.98) 117.82,26.98 118.57,26.23 118.57,22.27 119.17,21.68 119.76,21.68 119.76,21.21 119.27,20.71 R179.2 119.27,19.06 v2(119.13,18.92) 118.36,18.92 118.05,19.24 R176.2
PLT_WLAN_RST: length 22.6
  TOP w0.114: R6104.2 R6105.2 C460.1 v2(25.97,29.92) 25.97,28.26 30.61,23.62 31.54,23.62 32.57,22.59 32.57,17.69 32.13,17.25 NGFFE1.52
PLT_WLAN_RST#: length 37.1
  TOP w0.114: RN8.1 50.12,62.62 v2(49.15,61.65) 49.15,61.42 28.63,40.9 28.63,38 26.86,36.23 R6104.1
PLTRST*_SIO: length 25.2
  TOP w0.114: v3(76.71,78.59) 77.29,79.17 77.29,80.39 78.37,81.47 R501.1 78.37,82.46 C27.2 78.38,83.52 v3(77.7,84.2)
  BOTTOM w0.114: v3(77.7,84.2) 76.96,83.46 72.64,83.46 71.89,82.71 U6503.13 ; v3(76.71,78.59) 77.01,78.28 U31.49 79.32,78.28 82.13,81.09 C26.1 83.24,81.09 v2(84.15,82) R63.2
PLTRST_LAN: length 91.4
  TOP w0.114: RN8.2 50.77,62.4 44.05,55.68 v3(44.05,55.29)
  BOTTOM w0.114: v3(44.05,55.29) 44.15,55.19 44.15,55.17 v2(47.47,51.84) 51.5,47.81 51.5,47.51 52.06,46.96 81.72,46.96 100.59,65.83 102.48,65.83 103.64,66.99 108.71,66.99 109.22,66.47 109.8,66.47 110.39,65.89 111.12,65.89 111.49,65.52 LAN1.19
PME#_M: length 11.1
  TOP w0.114: v3(49.4,137.82) 49.4,138.1 CPU1.AN5
  BOTTOM w0.114: R67.2 41.74,134.49 42.2,134.95 42.75,134.95 43.56,135.76 43.56,136.4 44.48,137.31 45.52,137.31 45.76,137.56 45.76,137.89 46.51,138.63 v6(46.94,138.63) 47.14,138.43 48.51,138.43 49.13,137.82 v3(49.4,137.82)
PS8625_BKLT_EN: length 8
  TOP w0.114: R365.1 22.81,104.6 v2(22.81,103.71) 22.81,102.84 23,102.65 23,101.39 22.76,101.14 R614.1 21.42,101.14 v3(21.31,101.25)
  BOTTOM w0.114: U38.44 21.68,100 21.74,100.06 21.74,100.61 21.31,101.04 v3(21.31,101.25)
PS8625_BKLT_PWM: length 96
  TOP w0.114: v3(31.98,42.67) 31.47,42.67 31.06,42.27 31.06,34.66 34.69,31.03 34.69,25.43 36,24.12 36,12.47 36.14,12.32 v3(36.14,11.18)
  BOTTOM w0.114: U38.19 20.88,90.99 19.84,89.94 19.84,87.08 R610.1 v2(19.37,84.81) 19.37,83.46 23.74,79.09 23.74,62.56 24.68,61.62 24.68,47.14 29.15,42.67 v3(31.98,42.67) ; v3(36.14,11.18) 35.94,11.18 34.42,12.69 33.43,12.69 R374.2
PS8625_HPD: length 6
  TOP w0.114: R615.1 v2(23.34,99.38) 23.89,99.92 v3(23.89,100.13)
  BOTTOM w0.114: Q57.D 23.89,101.55 v3(23.89,100.13) 23.89,99.22 24.08,99.03 U38.1
PS8625_INI_SCL: length 4.9
  BOTTOM w0.114: U58.6 18.09,107.6 18.37,107.88 20.39,107.88 v6(20.6,107.67) 20.79,107.48 R602.2
PS8625_INI_SCL_R: length 8.9
  BOTTOM w0.114: U38.46 22.48,100.27 22.49,100.28 22.49,101.05 22.61,101.17 22.61,102.43 21.44,103.61 v6(21.44,104.55) 21.44,106.19 R602.1 21.76,106.51 R598.2
PS8625_INI_SDA: length 2.6
  BOTTOM w0.114: U58.5 19.36,105.76 19.51,105.61 R603.2 v6(18.54,105.12)
PS8625_INI_SDA_R: length 7
  BOTTOM w0.114: R603.1 20.4,104.07 R599.2 20.4,103.49 R597.1 21.46,103.03 22.15,102.34 22.15,101.45 v6(22.1,101.4) 22.08,101.38 U38.45
PS8625_LCD_PW_EN: length 33.2
  TOP w0.114: v3(12.32,85.88) 16.8,85.88 v3(16.84,85.85)
  BOTTOM w0.114: U38.20 20.48,92.5 20.49,92.5 20.49,91.23 19.27,90 19.27,88.77 18.34,87.85 R613.1 18.29,87.56 C511.1 16.71,86.96 16.71,85.98 v3(16.84,85.85) ; R381.1 v2(7,95.63) 7,90.89 12.01,85.88 v3(12.32,85.88)
PS8625_ROM2_CLK: length 15
  TOP w0.114: R595.1 33.68,90.02 32.05,91.65 v3(29.31,91.65)
  BOTTOM w0.114: U38.13 23.62,93.27 24.79,92.1 v2(25.58,92.1) 25.78,92.3 27.26,92.3 R591.2 v3(29.31,91.65) 31.12,93.46 R593.1
PS8625_ROM2_DAT: length 18.9
  TOP w0.114: v3(29.31,90.6) 33.52,86.39 R596.1
  BOTTOM w0.114: U38.14 22.88,92.74 24.03,91.59 24.71,91.59 25.48,90.83 25.95,90.83 26.79,89.99 27.29,89.99 R592.2 v3(29.31,90.6) 29.32,90.6 v2(30.94,92.21) R594.1
PS8625_SW: length 8
  BOTTOM w0.203: 21.88,91.67 21.88,92.35 21.68,92.55 U38.17
  BOTTOM w0.508: v2(21.41,85.6) 21.41,85.6 L52.1 21.41,90.46 R590.1 21.88,90.97 21.88,91.67
PWR_1D8V: length 19.6
  TOP w0.254: PR5211.1 27.79,137.19 27.3,137.67 v3(19.51,137.67) ; v3(12.75,136.7) 12.06,137.39 PC5108.1
  TOP w0.381: PC5108.1 10.09,137.39 PR5105.1
  BOTTOM w0.254: v3(12.75,136.7) 13.61,136.7 14.58,137.67 v2(16.76,137.67) v3(19.51,137.67)
PWR_1D8V_EN: length 9
  TOP w0.254: 15.39,140.57 16.22,141.4 RN19.3 ; 15.39,140.57 PR5209.2 14.53,141.59 R5101.1 ; 15.39,140.57 15.7,140.26 15.87,140.26 16.46,139.67 PR5208.1 16.46,138.48 PC5110.1 17.08,137.84 v2(17.08,137.59) 17.08,136.86 16.75,136.53 PU5101.5
PWR_1D8V_FB: length 7.8
  TOP w0.254: v2(9.12,138.28) PR5105.2 10.09,138.28 PC5108.2 11.08,138.97 11.53,139.42 PR5107.1 12.29,139.19 PC5109.1 12.29,138.08 13.65,136.72 PU5101.6
PWR_1D8V_FB_A: length 2.3
  TOP w0.254: PC5109.2 13.74,137.59 v2(14.17,137.59) 14.2,137.59 14.47,137.86 PR5108.1
PWR_1D8V_PH: length 2.4
  BOTTOM w0.635: v3(18.95,135.74) 18.72,135.97 v2(17.96,135.97) PC5104.1
PWR_1D8V_PVIN:
  vias: v2(12.14,131.78)
PWR_1D8V_SNB: length 2.5
  BOTTOM w0.508: PR5104.1 v2(16.63,134.01) 16.63,135.06 PC5104.2
PWR_1D8V_SVIN: length 4
  TOP w0.305: PR5103.2 12.25,135.14 PU5101.8
  TOP w0.508: v2(9.86,135.66) 10.05,135.46 PC5103.1 10.91,135.44 PR5103.2
PWR_3D3V:
  vias: v2(73.18,23.04)
PWR_3D3V_BOOT: length 6
  TOP w0.203: PU4901.7 75.71,28.77 74.93,27.99 74.93,27.9
  TOP w0.508: PR4908.2 76.35,25.55 v2(75.69,26.21) 74.93,26.97 74.93,27.9
PWR_3D3V_BOOT_A: length 2.9
  TOP w0.508: v2(79.55,24.22) PR4908.1 78.31,24.25 PC4909.2
PWR_3D3V_ENTRIP1_D: length 5.6
  TOP w0.127: v3(69.9,31.96) 69.63,32.22 R6568.1 70.47,32.73 PR4926.2
  BOTTOM w0.127: v3(69.9,31.96) 69.61,31.67 v2(68.91,31.67) 70,32.77 Q4806.D
PWR_3D3V_ENTRIP2: length 4.4
  TOP w0.203: PU4901.4 73.62,30.42
  TOP w0.254: 73.62,30.42 73.2,30 v2(72.52,30) 71.97,30.54 PC4920.1 71.57,29.55 PR4927.1
PWR_3D3V_ENTRIP2_D: length 4.8
  TOP w0.127: v3(68.79,29.54) 68.81,29.57 69.48,29.57 R6569.1 70.53,29.39 PR4927.2
  BOTTOM w0.127: Q4805.D 70.5,29.18 v2(69.69,30) 69.25,30 v3(68.79,29.54)
PWR_3D3V_FB: length 5.7
  TOP w0.203: PU4901.5 74.56,29.9 74.1,29.45
  TOP w0.254: PC4916.1 71.57,26.54 PR4917.2 PR4921.1 71.57,28.51 v2(72.59,28.51) 73.16,28.51 74.1,29.45
PWR_3D3V_FB_A: length 3.1
  TOP w0.254: PG4902.1 70.78,25.36 v2(70.61,25.53) 70.67,25.58 PC4916.2 70.68,26.54 PR4917.1
PWR_3D3V_HG: length 18.6
  TOP w0.203: v5(75.85,28.05) 76.11,28.3 PU4901.8
  BOTTOM w0.635: PR4911.1 85.8,16.21 v2(77.98,24.03) 75.85,26.15 v5(75.85,28.05)
PWR_3D3V_HG_A: length 4
  TOP w0.406: v5(91.89,15.66) 91.89,15.99 91.89,15.99 PQ4901.4
  BOTTOM w0.635: v5(91.89,15.66) v2(90.5,15.66) 89.96,16.21 PR4911.2
PWR_3D3V_LDO3: length 7.5
  TOP w0.203: 78.56,31.95 78.23,31.62 PU4901.15
  TOP w0.254: PG4904.1 80.95,37.19 80.26,36.5 PC4914.1 v2(79.02,34.39) 78.56,33.93 78.56,31.95
PWR_3D3V_LG: length 25.1
  TOP w0.203: PU4901.10 77.3,29.27 77.57,29
  TOP w0.406: PQ4903.4 95.19,14.72 94.99,14.93 v5(94.85,14.93)
  TOP w0.635: 77.57,29 78.04,28.53 v5(78.04,28.43)
  BOTTOM w0.635: v5(94.85,14.93) 89.5,20.27 86.76,20.27 v2(80.59,26.43) 78.6,28.43 v5(78.04,28.43)
PWR_3D3V_PH: length 18.2
  TOP w0.203: PU4901.9 76.51,28.67 76.83,28.34
  TOP w0.635: 76.83,28.34 77.1,28.07 v5(77.1,27.47) 77.2,27.36 PC4909.1
  BOTTOM w0.635: v5(88.32,18.62) 85.94,18.62 v2(81.26,23.31) v5(77.1,27.47)
  vias: v2(89.81,11.56)
PWR_3D3V_SNB: length 2.8
  TOP w0.508: PR4920.1 84.64,11.38 v2(85.98,11.38) PC4913.2
PWR_5V: length 17.7
  TOP w0.203: PU4901.20 75.31,32.74 74.86,33.18
  TOP w0.762: 74.86,33.18 v3(74.05,33.99) PC4917.1
  BOTTOM w0.508: v3(74.05,33.99) v2(75.14,35.07) 76.46,36.4 v3(87.45,36.4)
PWR_5V3V_EMN: length 4.8
  TOP w0.127: PR4922.2 81.17,30.56 PR4925.1 80.26,30.54 v2(79.81,30.99) 79.64,30.82 PU4901.13
PWR_5V3V_ENLDO: length 3
  TOP w0.203: PU4901.12 78.4,30.42 78.85,29.96
  TOP w0.254: PR4901.2 79.61,29.32 79.6,29.33 79.49,29.33 v2(79.04,29.77) 78.85,29.96
PWR_5V3V_LDO5: length 4.4
  TOP w0.203: PU4901.14 78.13,31.22
  TOP w0.254: 78.13,31.22 78.54,31.22 79.22,31.9 v2(79.22,32.08) 79.22,32.26 79.89,32.92 PC4906.1 80.24,33.87 PG4901.1
PWR_5V3V_PGOOD: length 4.2
  TOP w0.203: PU4901.6 75.04,29.27 74.46,28.68
  TOP w0.254: 74.46,28.68 73.84,28.07 v2(73.84,26.9) 73.51,26.9 73.51,26.9 PR4928.2
PWR_5V3V_TON: length 3.3
  TOP w0.203: PU4901.3 73.62,30.82 73.39,31.05
  TOP w0.254: 73.39,31.05 72.93,31.51 v2(72.75,31.51) PR4924.1
PWR_5V3V_VIN: length 7.3
  TOP w0.203: PU4901.11 78.2,29.48
  TOP w0.508: PC4905.1 80.88,28.66 81.08,28.86 PR4901.1 ; PC4905.1 v2(79.76,27.88) 79.76,27.92 78.2,29.48 ; PC4905.1 82.25,27.88 PR4905.2
PWR_5V_BOOT: length 6
  TOP w0.203: 75.62,33.43 75.62,33.08 75.71,32.99 PU4901.19
  TOP w0.508: PR4909.1 75.36,36.82 v2(75.36,34.67) 75.36,34.24 75.62,33.98 75.62,33.43
PWR_5V_BOOT_A: length 3.1
  TOP w0.508: PC5208.1 78.59,36.21 78.59,36.96 78.26,37.29 PR4909.2 v2(79.5,37.78)
PWR_5V_ENTRIP1: length 5.3
  TOP w0.203: 73.98,31.22 PU4901.2
  TOP w0.254: PR4926.1 71.55,33.5 PC4919.1 72.33,33.52 v2(72.72,33.12) 73.61,32.23 73.61,31.59 73.98,31.22
PWR_5V_FB: length 7.6
  TOP w0.203: PU4901.1 74.56,32.3
  TOP w0.254: PR4918.1 72.61,35.5 v2(72.92,35.18) 73.05,35.05 73.05,33.81 74.56,32.3 ; PR4918.1 71.63,35.5 PC4918.2 ; PR4918.1 71.62,35.49 PR4923.1
PWR_5V_FB_A: length 18.4
  TOP w0.254: PR4918.2 70.64,35.52 PC4918.1 70.64,36.83 72.65,38.84 83.59,38.84 83.98,38.45 v2(84.33,38.45) PG4903.2
PWR_5V_HG: length 15.9
  TOP w0.203: v5(76.41,33.89) 76.11,33.59 PU4901.18
  BOTTOM w0.635: v5(76.41,33.89) 76.56,33.74 79.05,33.74 80.76,32.02 v2(82.19,32.02) 84.51,32.02 87.91,28.63 PR4912.1
PWR_5V_HG_A: length 3.6
  TOP w0.406: v5(93.16,28.61) 93.18,28.63 PQ4902.4
  BOTTOM w0.635: PR4912.2 v2(92.08,28.63) 93.15,28.63 v5(93.16,28.61)
PWR_5V_LG: length 19.4
  TOP w0.203: v5(77.91,32.6) 77.68,32.37 PU4901.16
  TOP w0.406: PQ4904.4 v5(92.38,25.34)
  BOTTOM w0.635: v5(77.91,32.6) v2(79.03,31.48) 79.97,30.53 83.21,30.53 87.83,25.91 91.81,25.91 v5(92.38,25.34)
PWR_5V_PH: length 18.6
  TOP w0.203: 77.07,33.42 76.51,32.85 PU4901.17
  TOP w0.635: 77.07,33.42 77.52,33.87 v5(77.52,34.76) 76.97,35.32 PC5208.2
  BOTTOM w0.635: v5(77.52,34.76) v2(80.57,34.76) 81.65,33.68 85.39,33.68 88.83,30.25 v5(89.89,30.25)
  vias: v2(97.13,31.22)
PWR_5V_SNB: length 2.3
  TOP w0.508: PR4919.1 PC4912.2 v2(86.33,28.5)
PWR_AD+_2:
  vias: v2(118.19,20.07)
PWR_CORE_BOOT1: length 3.6
  TOP w0.203: PU4401.21 36.72,191.67 v3(37.36,192.3)
  BOTTOM w0.508: PR4445.1 38,194.01 v2(38,192.96) 38,192.94 v3(37.36,192.3)
PWR_CORE_BOOT1_A: length 3.3
  BOTTOM w0.508: PC4431.1 35.18,195.54 v2(35.84,196.2) PR4445.2
PWR_CORE_HG1: length 23.6
  TOP w0.203: PU4401.22 35.92,192.26 37.17,193.51
  TOP w0.635: 37.17,193.51 37.57,193.9 43.94,193.9 v2(45.34,192.51) 48.06,189.79 55.8,189.79 PR4442.1
PWR_CORE_HG1_A: length 7.8
  TOP w0.635: PR4463.1 62.33,191.02 v3(62.33,190.71) 61.85,190.22 v2(59.39,190.22) 59.36,190.25 PR4442.2
  BOTTOM w0.635: v3(62.33,190.71) 62.33,191.34 62.73,191.74 PQ4403.4
PWR_CORE_ISUMN: length 12.2
  TOP w0.254: PR4451.1 40.83,185.28 PC4430.2 41.1,185.01 PC4440.1 42.78,185.01 PC4439.1 43.78,185 PR4446.1 43.79,184.99 PR4449.1 44.61,184.78 PR4447.1 45.64,183.77 PC4433.1 47.5,183.78 PR4462.2 48.31,183.81 v3(48.39,183.89) PR4448.1
  BOTTOM w0.254: v2(47.83,184.78) 48.39,184.23 v3(48.39,183.89)
PWR_CORE_ISUMP: length 13
  TOP w0.203: 38.46,188.06 38,188.51 PU4401.14
  TOP w0.254: v3(42.8,186.87) 42.79,186.86 PC4439.2 41.83,185.89 PC4440.2 41.82,186.16 PR4451.2 39.87,187.16 39.25,187.78 38.74,187.78 38.46,188.06 ; PR4453.2 45.91,184.95 PR4461.2 v3(45.91,186.88)
  BOTTOM w0.254: v3(45.91,186.88) 45.89,186.87 v2(44.42,186.87) v3(42.8,186.87)
PWR_CORE_LG1: length 35.1
  TOP w0.203: PU4401.24 35.12,193.26
  TOP w0.635: v5(60.71,194.15) 59.7,193.14 v5(55.4,193.14) 49.73,193.14 v2(46.35,196.52) 46.33,196.52 45.64,197.21 36.83,197.21 35.12,195.49 35.12,193.26
  BOTTOM w0.635: PQ4405.4 55.09,192.83 v5(55.4,193.14) ; PQ4404.4 60.62,194 60.71,194.08 v5(60.71,194.15)
PWR_CORE_PH1: length 39.8
  TOP w0.203: PU4401.23 35.52,192.45 36.08,193.01 v3(36.08,193.61)
  TOP w0.635: v3(36.08,193.61) 36.08,194.12 37.52,195.55 44.63,195.55 48.69,191.49 v2(54.33,191.49) 59.79,191.49 60.92,192.62 PR4463.2 61.93,192.62 62.3,192.25 64.39,192.25 64.81,191.84 64.81,189.49 63.35,188.04
  BOTTOM w0.635: v3(36.08,193.61) 36.01,193.55 PC4431.2
  vias: v2(55.55,184.91) v5(50.39,185.88) v5(51.3,185.88) v5(51.28,184.92) v5(52.15,184.92) v5(52.17,185.88) v5(53.03,185.88) v5(53.11,184.94) v5(54.03,184.92) v5(57.11,184.88) v5(58.07,185.74) v5(58.37,184.84) v5(59.24,185.75) v5(59.4,184.8) v5(60.39,185.72) v5(60.48,184.82) v5(62.25,188.62) v5(62.25,187.67) v5(62.23,186.68) v5(62.23,185.73) v5(62.27,184.83) v5(63.43,186.83) v5(63.42,185.91) v5(63.43,184.97)
PWR_CORE_PH1N: length 11.2
  TOP w0.254: PG4403.2 55.54,181.73 54.37,182.9 v3(49.33,182.9) 49.31,182.92 PR4462.1
  BOTTOM w0.254: v2(50.29,182.9) v3(49.33,182.9)
PWR_CORE_PH1P: length 11.7
  TOP w0.254: PR4461.1 46.8,186.5 47.37,187.07 v2(48.62,187.07) 48.62,186.23 51.38,183.46 54.55,183.46 PG4404.2
PWR_CORE_SNB: length 3.1
  BOTTOM w0.508: v2(46.23,191.96) PR4455.1 47.84,191.95 47.84,191.39 47.44,191 PC4434.2
PWR_CORE_VIN:
  vias: v2(70.92,194.34)
PWR_CPU_COMP: length 6.2
  TOP w0.203: v3(38.48,191.64) 38.48,191.35 37.64,190.51 PU4401.19
  TOP w0.254: PC4441.1 39.61,192.02 PC4435.1 v3(38.48,191.64)
  BOTTOM w0.254: v3(38.48,191.64) 38.48,190.86 v2(38.43,190.81) PR4460.1
PWR_CPU_COMP_A: length 2.5
  TOP w0.254: v2(42.04,192.68) 41.66,192.68 41.13,192.16 PC4441.2 41.44,191.71 PR4456.1
PWR_CPU_COMPNB: length 5.4
  TOP w0.203: v3(30.72,188.58) 30.93,188.58 31.27,188.91 PU4401.36
  TOP w0.254: PC4412.1 30,188.18 PC4404.1 30.24,188.1 v3(30.72,188.58)
  BOTTOM w0.254: v2(30.72,187.79) v3(30.72,188.58) 31.34,188.58 PR4408.1
PWR_CPU_COMPNB_A: length 2.2
  TOP w0.254: PR4411.1 28.23,187.2 PC4412.2 28.23,189.01 v2(28.47,189.26)
PWR_CPU_EN: length 4.1
  TOP w0.203: PU4401.8 35.52,185.76 36.17,185.11
  TOP w0.254: PR4430.2 36.59,183 v2(36.59,184.23) 36.59,184.69 36.17,185.11
PWR_CPU_FB: length 5.5
  TOP w0.203: PC4435.2 38.35,190.75 37.71,190.11 PU4401.18
  TOP w0.254: PR4452.1 41.2,190.67 PR4450.1 41.08,190.75 v4(40.11,190.75) PC4435.2
PWR_CPU_FB_A: length 3
  TOP w0.254: v3(41.19,188.98) PR4450.2 40.6,189.76 PC4436.1
  BOTTOM w0.254: v2(41.5,189.92) 41.5,189.29 v3(41.19,188.98)
PWR_CPU_FB_B: length 4.4
  TOP w0.254: PR4457.1 43.2,189.44 PR4459.1 43.37,190.41 PR4452.2 PR4456.2 43.11,192.17 v2(43.56,192.62)
PWR_CPU_FB_C: length 2
  TOP w0.254: v2(45.19,189.61) 45.11,189.61 45.11,189.61 PR4459.2 44.26,190.69 PC4442.1
PWR_CPU_FBNB: length 8.1
  TOP w0.203: PU4401.37 31.35,188.51 30.35,187.52 30.35,187.49 PC4404.2
  TOP w0.254: PC4404.2 29.15,187.22 PR4411.2 29.12,187.06 PR4412.1 28.06,186 PR4407.1 27.2,187.16 PR4404.1 v4(26.16,187.17)
PWR_CPU_FBNB_A: length 2
  TOP w0.254: PR4407.2 26.32,185.99 PC4405.1 26.32,184.18 v4(26.21,184.07)
PWR_CPU_FBNB_B: length 2.3
  TOP w0.254: v2(26.7,190.2) 27.18,189.71 PC4403.1 27.19,188.99 PR4404.2
PWR_CPU_IMON: length 3.6
  TOP w0.203: PU4401.10 36.98,186.56 v3(37.03,186.61)
  BOTTOM w0.254: v3(37.03,186.61) v2(36.3,186.61) PR4434.1 34.21,186.61 PC4424.1
PWR_CPU_ISEN1: length 6.8
  TOP w0.203: PU4401.13 37.77,188.11 38.43,187.45
  TOP w0.254: 38.43,187.45 38.63,187.25 v3(38.94,187.25) 39.01,187.25 39.95,186.31 PC4430.1
  BOTTOM w0.254: PR4443.1 v2(38.25,187.81) 38.38,187.81 v3(38.94,187.25)
PWR_CPU_ISEN2: length 8.7
  TOP w0.203: PU4401.12 37.58,187.71 38.27,187.02
  TOP w0.254: PR4440.2 42.92,184.37 39.87,184.37 39.25,184.98 39.25,186.04 v2(39.05,186.24) 38.27,187.02
PWR_CPU_ISUMN: length 8.7
  TOP w0.203: PU4401.15 38.32,188.91 38.4,188.83
  TOP w0.254: 38.4,188.83 38.94,188.29 39.47,188.29 39.98,187.78 41.12,187.78 41.48,187.43 v2(41.99,187.43) 43.33,187.43 PC4438.2 43.92,186.02 PR4446.2
PWR_CPU_ISUMN_A: length 2.3
  TOP w0.254: PR4449.2 44.81,185.89 PC4438.1 44.83,186.84 v2(45.75,187.76)
PWR_CPU_ISUMNNB: length 5.4
  TOP w0.203: 30.69,186.17 31.01,186.49 31.01,187.24 31.48,187.71 PU4401.39
  TOP w0.254: 30.69,186.17 v4(30.16,185.64) 29.82,185.3 PR4418.2 29.82,183.62 PC4413.2
PWR_CPU_ISUMNNB_B: length 3
  TOP w0.254: PR4413.2 29.65,182.56 PC4413.1 v3(28.91,182.66)
  BOTTOM w0.254: v3(28.91,182.66) v2(28.91,181.69)
PWR_CPU_ISUMP_A: length 2.7
  TOP w0.254: PR4453.1 47.78,184.94 v2(48.06,185.22) 48.75,185.22 PR4448.2
PWR_CPU_NB_IMON: length 3.6
  TOP w0.203: PU4401.2 33.12,185.88 32.97,185.74 v3(32.97,185.72)
  BOTTOM w0.254: PC4401.2 32.29,186.62 PR4425.2 33.24,186 v3(32.97,185.72) v2(32.97,184.99)
PWR_CPU_NB_NTC: length 50.4
  TOP w0.203: 31.99,186.14 32.42,186.56 PU4401.1
  TOP w0.254: PR4422.1 10.54,183.49 10.49,183.47 v3(9.65,182.63) ; v3(33.15,176.71) 33.12,176.74 PR4401.2 33.3,177.76 33.3,179.75 32.22,180.83 32.22,184 31.99,184.23 31.99,186.14
  BOTTOM w0.254: v3(9.65,182.63) 9.65,173.06 11.59,171.12 20.32,171.12 v2(22.78,173.58) 27.46,178.26 32.34,178.26 33.15,177.45 v3(33.15,176.71)
PWR_CPU_NB_NTCA: length 45.4
  TOP w0.254: v3(9.4,183.51) 9.7,183.51 10.21,184.02 11.21,184.02 PR4422.2 ; v3(32.99,175.69) 32.99,175.72 33.81,176.53 PR4421.2 34,176.55 34.01,176.55 PR4401.1
  BOTTOM w0.254: v3(9.4,183.51) 9.02,183.13 9.02,172.97 11.38,170.61 20.73,170.61 v2(24.9,174.78) 27.87,177.75 32.13,177.75 32.64,177.24 32.64,176.05 v3(32.99,175.69)
PWR_CPU_NTC: length 42.2
  TOP w0.203: PU4401.11 37.38,187.31 37.87,186.82
  TOP w0.254: 37.87,186.82 37.87,186.28 38.86,185.29 38.86,184.63 39.69,183.81 PR4435.2 40.01,183.2 40.01,182.75 v3(39.88,182.63)
  BOTTOM w0.254: PR4439.1 63.83,183.38 51.39,183.38 50.76,184.02 50.25,184.02 48.06,186.21 48.06,188.42 46.41,190.07 44.3,190.07 41.07,186.84 41.07,185.17 v2(40.64,184.73) 39.88,183.97 v3(39.88,182.63)
PWR_CPU_NTC_A: length 38.2
  TOP w0.254: PR4435.1 40.91,183.52 PR4438.2 41.33,182.51 v3(40.83,182.51)
  BOTTOM w0.254: v3(40.83,182.51) 40.83,183.73 42.01,184.91 42.01,186.89 v2(43.92,188.8) 44.53,189.41 46.08,189.41 47.5,187.99 47.5,186 49.99,183.51 50.54,183.51 51.18,182.87 64.22,182.87 PR4439.2
PWR_CPU_PWROK: length 7.2
  TOP w0.203: 36.37,185.57 35.92,186.03 PU4401.9
  TOP w0.254: PR4431.2 38.36,181.4 v2(37.97,181.79) 37.55,182.21 37.55,184.4 36.37,185.57
PWR_CPU_RTN: length 18.8
  TOP w0.203: PU4401.17 38,189.71 v3(38.15,189.86)
  BOTTOM w0.254: PR4437.1 37.94,178.21 PR4444.1 37.92,179.66 38.68,180.43 38.68,184.02 40.05,185.39 v2(40.05,186.82) 40.05,190.59 PC4432.1 39.31,190.61 38.55,189.86 v3(38.15,189.86) 38.06,189.77 PR4441.1
PWR_CPU_VDD: length 4.9
  TOP w0.203: PC4422.1 v2(33.29,193.19) 33.29,193.16 33.59,192.86 34.29,192.86 34.72,192.44 PU4401.25
  TOP w0.381: PC4422.1 33.29,194.93 PR4427.2
PWR_CPU_VDDIO: length 7.5
  TOP w0.203: PU4401.6 34.72,185.19 34.72,185.19 34.72,184.79 34.72,184.79 34.72,183.94 PC4423.1
  TOP w0.254: PR4429.2 35.42,180.34 v2(35.42,181.23) PC4423.1
PWR_CPU_VDDP: length 6.9
  TOP w0.203: PU4401.26 34.32,192.2 34.13,192.38 33.17,192.38 32.21,193.34 PC4421.1
  TOP w0.381: PC4421.1 32.21,194.92 PR4426.2
  TOP w0.508: PR4426.2 30.72,195.36 v2(30.38,195.71)
PWR_CPU_VR_HOT: length 3.8
  TOP w0.203: 33.92,185.38 PU4401.4
  TOP w0.254: PR4428.2 v2(33.51,184.07) 33.51,184.97 33.92,185.38
PWR_CPU_VSEN: length 21
  TOP w0.203: PU4401.16 38.58,189.31 38.82,189.07 v3(39.11,189.07)
  TOP w0.254: PR4458.1 43.36,188.55 PR4457.2 42.18,188.39 40.32,188.39 PC4436.2 40.03,188.49 39.45,189.07 v3(39.11,189.07)
  BOTTOM w0.254: PC4437.1 38.82,188.77 v3(39.11,189.07) 39.44,188.74 39.44,185.8 38,184.35 v2(38,183.08) 38,180.64 36.89,179.53 PR4454.1
PWR_CPU_VSENNB: length 13.7
  TOP w0.203: PR4412.2 28.84,185.28 29.92,186.36 30.15,186.36 30.68,186.89 30.68,187.38 31.42,188.11 PU4401.38
  TOP w0.254: PR4412.2 27.98,185.03 PC4405.2 27.17,185 PC4414.1 27.17,183.29 PC4402.1 26.38,182.46 v4(26.38,180.29) 26.38,180.25 27.11,179.52 PR4402.1 27.23,179.53 PR4403.1
PWR_DCBATOUT_5V3D3V: length 15.1
  TOP w0.635: PR4905.1 v5(84.35,26.29)
  BOTTOM w0.635: v5(84.35,26.29) 84.35,25.02 87.38,22 90.45,22 92.28,20.17 94.74,20.17
  vias: v2(95.66,20.55) v2(98.3,22.86) v5(95.76,23.81) v5(95.8,22.78) v5(96.28,18.48) v5(96.7,19.48) v5(96.82,23.81) v5(96.87,22.78) v5(97.42,18.46) v5(97.85,19.48) v5(98.53,18.48)
PWR_DCBATOUT_VDDP:
  vias: v2(10.74,126.36) v2(14.15,128.35) v5(12.31,129.02) v5(12.3,128.13) v5(12.28,127.24)
PWR_DCBATOUT_VDDQ: length 15
  BOTTOM w0.305: PR5008.1 105.55,124.61 105.55,128.34 106.57,129.36 109.96,129.36 110.77,128.55 115.39,128.55
  vias: v2(118.34,131.47)
PWR_ID0: length 104.1
  TOP w0.114: v3(67.11,77.6) 63.25,77.6 61.9,76.25 58.84,76.25 58.78,76.19 58.48,75.9 57.94,75.9 53.29,71.25 53.29,70.83 47.85,65.39 47.85,64.95 45.04,62.14 v3(45.04,61.47) 39.4,55.82 39.4,55.34 39.15,55.09 38.08,55.09 29.62,46.62 29.62,46.42 22.04,38.84 22.04,26.72 21.33,26.01 18.64,26.01 18.09,25.46 Q4808.G 17.51,22.63 v2(17.51,16.08) R822.2 EC705.1 17.51,10.49 18.14,9.87 23.38,9.87 24.5,8.75 CNVBD2.4
  BOTTOM w0.114: v3(67.11,77.6) 66.65,78.06 U6503.58
PWR_ID1: length 126.4
  TOP w0.114: v3(45.76,61.94) 45.76,61.18 39.3,54.72 38.24,54.72 30.41,46.89 30.41,46.69 22.41,38.69 22.41,23.82 19.42,20.83 R823.2 EC706.1 19.42,10.69 19.84,10.27 23.61,10.27 25.5,8.38 CNVBD2.5
  BOTTOM w0.114: U31.57 79.19,74.28 79.23,74.33 82.17,74.33 82.62,73.88 82.62,69.03 79.86,66.27 79.86,62.48 74.44,57.07 68.23,57.07 67.53,56.36 51.12,56.36 v2(50.95,56.53) 45.98,61.5 45.98,61.72 v3(45.76,61.94)
PWR_ID2: length 102.9
  TOP w0.114: v3(49.86,66.27) 49.86,66.22 46.2,62.56 46.2,61.1 39.45,54.35 38.39,54.35 30.77,46.73 30.77,46.54 22.78,38.54 22.78,23.66 20.27,21.16 20.27,15.01 21.08,14.2 21.08,13.53 21.35,13.26 R824.2 EC707.1 22.79,11.81 25.54,9.07 26.3,9.07 26.5,8.86 CNVBD2.6
  BOTTOM w0.114: U31.79 69.29,67.5 68.53,66.74 68.53,62.46 v2(67.91,61.84) 67.42,61.35 66.33,61.35 66.26,61.28 65.35,61.28 65.04,61.59 54.53,61.59 v3(49.86,66.27)
PWR_V1P5A: length 4.4
  TOP w0.508: PR5204.1 PC5206.1 v2(50.12,26.59) 49.85,26.33 PU5201.5
PWR_V1P5A_EN: length 170.5
  TOP w0.254: v3(52.63,31.37) 52.63,29.72 53.47,28.88 53.47,21.56 54.05,20.98 PR5206.1 54.03,20.45 PC5203.1 52.37,21.16 52.37,21.16 51.75,21.78 PU5201.3 ; v3(15.48,141.71) 15.47,141.73 15.47,141.74 15.27,141.93 R5202.2 16.29,142.66 R5201.2
  BOTTOM w0.254: v3(52.63,31.37) 43.89,31.37 42.23,33.03 21.04,33.03 17.45,36.62 17.45,78.33 4.72,91.06 4.72,114.78 9.56,119.61 9.56,137.67 13.6,141.71 v2(14.45,141.71) v3(15.48,141.71)
PWR_V1P5A_VIN: length 4.9
  TOP w0.508: PU5201.1 49.85,21.42 50.5,20.78 PC5205.1 50.68,20.16 PR5201.2 v2(50.68,18.01)
PWR_VDDNB_BOOT: length 4.4
  TOP w0.203: PU4401.31 31.97,191.3 31.09,192.18
  TOP w0.508: 31.09,192.18 30.51,192.76 v2(30.48,192.76) 29.15,194.09 PR4417.1
PWR_VDDNB_BOOT_A: length 2.8
  TOP w0.508: v2(26.16,192.42) PC4415.1 27.21,194.17 PR4417.2
PWR_VDDNB_HG: length 27.5
  TOP w0.203: v5(30.89,191.31) 30.89,190.93 31.3,190.51 PU4401.32
  BOTTOM w0.635: PR4415.1 15.06,188.03 19.68,192.64 v2(24.21,192.64) 29.56,192.64 v5(30.89,191.31)
PWR_VDDNB_HG_A: length 4.8
  TOP w0.635: v5(16.54,176.1) PQ4401.4
  BOTTOM w0.635: PR4415.2 v2(15.06,177.29) 15.06,176.42 PR4464.1 16.52,176.09 v5(16.54,176.1)
PWR_VDDNB_ISUMN: length 30.2
  TOP w0.254: v3(29.53,176.96) 29.53,177.21 29.52,177.22 PR4424.2 29.53,177.89 PC4416.1 29.53,180.54 PR4413.1 30.58,181.59 PC4411.2 PC4410.2 30.71,182.55 PR4414.2 PR4418.1 ; PR4416.2 11.55,169.79 v3(11.52,169.76)
  BOTTOM w0.254: v3(29.53,176.96) 28.12,176.96 v2(26.8,175.64) 20.71,169.55 11.72,169.55 v3(11.52,169.76)
PWR_VDDNB_ISUMP: length 9.4
  TOP w0.203: 31.38,186.07 31.38,187.07 31.62,187.31 PU4401.40
  TOP w0.254: 31.38,186.07 31.38,183.76 PR4414.1 31.59,183.54 PC4410.1 PC4411.1 v4(31.59,180.64) 31.59,179.6 PR4423.2 32.57,179.52 PR4410.1
PWR_VDDNB_ISUMP_A: length 26.5
  TOP w0.254: v3(32,177.13) 32.03,177.13 32.34,177.44 32.34,178.4 PR4410.2 ; PR4416.1 11.58,168.9 v3(11.52,168.96)
  BOTTOM w0.254: v3(32,177.13) 31.24,176.37 v2(30.25,176.37) 28.54,176.37 21.19,169.02 11.58,169.02 v3(11.52,168.96)
PWR_VDDNB_LG: length 19.9
  TOP w0.203: v5(29.85,189.46) 30.19,189.79 30.88,189.79 30.96,189.71 PU4401.34
  TOP w0.635: v5(18.54,183.03) 18.34,182.83 PQ4402.4
  BOTTOM w0.635: v5(29.85,189.46) 29.52,189.13 25.32,189.13 v2(24.84,188.65) 20.35,188.65 18.54,186.83 v5(18.54,183.03)
PWR_VDDNB_PH: length 34.7
  TOP w0.203: v5(29.97,190.86) 30.57,190.26 30.95,190.26 31.1,190.11 PU4401.33
  TOP w0.635: v5(29.97,190.86) 29.97,191.18 PC4415.2
  BOTTOM w0.635: PR4464.2 14.98,175.2 v5(14.54,174.76) ; v5(20.45,174.62) 20.44,174.64 PC4417.2 ; v5(29.97,190.86) v2(21.64,190.86) 20.23,190.86 16.89,187.52 16.89,181.31 17.5,180.7 17.5,175.62 v5(16.76,174.88)
PWR_VDDNB_PH_N: length 21
  TOP w0.254: PR4424.1 30.41,175.33 v3(31.39,174.35) ; PG4402.2 16.74,169.09 17.33,169.68 25,169.68 v3(25.22,169.45)
  BOTTOM w0.254: v3(25.22,169.45) 26.49,169.45 v2(29.05,172.01) v3(31.39,174.35)
PWR_VDDNB_PH_P: length 20.8
  TOP w0.254: v3(25.26,170.31) 25.19,170.25 17.28,170.25 PG4401.2 ; PR4423.1 31.5,178.57 31,178.07 31,175.65 v3(31.4,175.25)
  BOTTOM w0.254: v3(25.26,170.31) 26.46,170.31 v2(30.07,173.92) v3(31.4,175.25)
PWR_VDDNB_SNB: length 2.8
  BOTTOM w0.508: PR4420.1 v2(20.44,178.28) 20.44,177.99 PC4417.1
PWR_VDDNB_VIN:
  vias: v2(17.4,189.38)
PWR_VDDP: length 22.8
  TOP w0.381: v3(21.13,115.44) 22.63,116.94 24.72,116.94 PT4411.1
  TOP w0.508: v3(29.64,105.23) 29.64,104.34 30.79,103.2 PR4814.1
  BOTTOM w0.381: v3(29.64,105.23) 27.97,106.91 27.97,108.03 v2(21.84,114.15) 21.13,114.86 v3(21.13,115.44)
PWR_VDDP_BOOT: length 4.5
  TOP w0.305: v2(14.05,118.11) 14.48,117.68 14.48,116.48 PU4801.10
  TOP w0.508: v2(14.05,118.11) 13.82,118.34 PR4806.1
PWR_VDDP_BOOT_A: length 3.1
  TOP w0.508: PC4805.2 16.06,120.05 PR4806.2 15.75,118.82 v2(15.27,118.34)
PWR_VDDP_CS: length 2.4
  TOP w0.254: PR4805.2 15.41,111.16 v2(15.57,111.33) 15.68,111.44 PU4801.2
PWR_VDDP_EN: length 51.7
  TOP w0.254: C4801.1 13.45,113.75 ; 13.45,113.75 12.97,113.27 12.97,111.14 13.47,110.63 15.77,110.63 16.21,111.07 16.21,111.76 16.18,111.79 PU4801.3 ; 13.45,113.75 12.84,114.68 12.84,116.22 11.74,117.32 7.52,117.32 v3(6.4,118.44) ; R4802.2 12,142.3 v3(12,143.61) 12.06,143.54 R4803.1 13.41,143.54 13.78,143.92 v2(14.27,143.92) 14.71,143.92 14.84,143.79 PC4801.1 16.3,143.79 R4801.2
  BOTTOM w0.254: v3(6.4,118.44) 8.27,120.31 8.27,139.88 v2(11.1,142.71) v3(12,143.61)
PWR_VDDP_FB: length 5.9
  TOP w0.254: v2(20.42,109.86) PC4810.2 PR4813.2 18.45,111.14 PR4815.1 17.49,111.14 16.68,111.95 PU4801.4
PWR_VDDP_FB_A: length 15.5
  TOP w0.254: PR4813.1 PC4810.1 20.42,113.64 22.99,116.2 28.19,116.2 28.49,116.5 PG4801.2 30.04,116.5 30.58,117.04 v2(30.89,117.04)
PWR_VDDP_HG: length 9.5
  TOP w0.305: v5(15.73,117.18) 15.68,117.13 15.68,116.49 15.68,116.49 PU4801.9
  BOTTOM w0.635: v5(15.73,117.18) 15.34,117.56 15.34,120.51 v2(16.16,121.33) 17.02,122.19 PR4804.1
PWR_VDDP_HG_A: length 3.8
  TOP w0.381: PQ4801.4 16.94,128.34 16.94,129 17.05,129.11 v5(17.05,129.18)
  BOTTOM w0.635: PR4804.2 17.05,126.31 v2(17.05,127.89) v5(17.05,129.18)
PWR_VDDP_LG: length 10.3
  TOP w0.305: PU4801.6 17.95,115.77 v5(17.98,115.74)
  TOP w0.406: v5(13.66,121.05) 13.65,121.06 PQ4802.4
  BOTTOM w0.635: v5(13.66,121.05) v2(13.66,119) 13.66,117.63 15.55,115.74 v5(17.98,115.74)
PWR_VDDP_PH: length 16.4
  TOP w0.305: PU4801.8 16.18,116.58 16.85,117.25 v5(16.85,117.47) 16.85,118.13 PC4805.1
  BOTTOM w0.635: v5(16.85,117.47) 16.85,119.26 18.76,121.17 v2(18.76,123.34) v5(18.76,128.24) 19.2,128.68 PC4807.1
PWR_VDDP_RF: length 3.8
  TOP w0.254: PU4801.5 17.66,112.67 PR4809.1 v3(18.7,114.5)
  BOTTOM w0.254: v3(18.7,114.5) 18.7,114.99 v2(19.1,115.39)
PWR_VDDP_SNB: length 2.6
  BOTTOM w0.508: PR4812.1 v2(18.06,130.62) 18.07,130.61 PC4807.2
PWR_VDDQ:
  vias: v2(107.29,146.15)
PWR_VDDQ_BOOT: length 3.5
  BOTTOM w0.203: PU5001.18 v2(114.1,121.64)
  BOTTOM w0.508: v2(114.1,121.64) 114.53,122.07 PR5007.1
PWR_VDDQ_BOOT_A: length 3.1
  BOTTOM w0.508: PR5007.2 114.53,124.9 v2(114.53,126.33) PC5008.1
PWR_VDDQ_CS: length 5.4
  BOTTOM w0.203: 111.39,125.27 110.59,124.47 PU5001.13
  BOTTOM w0.254: v2(112.55,127.66) 112.55,127.33 111.54,126.32 PC5002.2 PR5004.2 111.39,125.27
PWR_VDDQ_EN: length 11
  BOTTOM w0.203: 108.25,121.64 PU5001.8
  BOTTOM w0.254: RN21.3 104.58,117.15 v2(104.62,117.2) 104.62,120.58 R5002.2 105.36,122.4 C5001.1 106.87,122.4 107.63,121.64 108.25,121.64
PWR_VDDQ_FB: length 7
  BOTTOM w0.203: PC5013.2 107.54,118.4 107.54,119.34 PU5001.6
  BOTTOM w0.254: PC5013.2 107.31,117.79 PR5022.1 106.75,116.99 106.45,116.69 PR5020.2 v2(106.45,114.94)
PWR_VDDQ_HG: length 20.8
  TOP w0.635: v5(113.28,122.35) 113.56,122.35 115.16,123.95 115.16,131.88 118.76,135.48 v2(118.76,136.14) PR5009.1
  BOTTOM w0.203: PU5001.17 112.97,122.04 v5(113.28,122.35)
PWR_VDDQ_HG_A: length 4.7
  TOP w0.635: PR5009.2 v5(118.76,142.72)
  BOTTOM w0.406: 118.32,141.21 PQ5001.4
  BOTTOM w0.635: v2(119.48,143.54) 119.48,143.44 v5(118.76,142.72) 118.77,142.71 118.77,141.66 118.32,141.21
PWR_VDDQ_LG: length 17.7
  TOP w0.635: v5(111.39,124.19) 111.39,126.23 110.62,127 110.62,129.03 108.51,131.14 v2(108.51,133.5) 108.51,135.93 v5(110.49,137.91)
  BOTTOM w0.203: PU5001.15 v5(111.39,124.19)
  BOTTOM w0.406: PQ5002.4 v5(110.49,137.91)
PWR_VDDQ_PH: length 25.9
  TOP w0.635: v5(112.89,123.93) 112.89,124.06 113.51,124.69 113.51,132.75 117.04,136.28 117.04,143.31 v5(117.32,143.59) ; v5(111.8,142.73) 111.81,142.73 PC5010.1
  BOTTOM w0.203: v5(112.89,123.93) 112.14,123.18 PU5001.16
  BOTTOM w0.381: v5(112.89,123.93) PC5008.2
  vias: v2(110.24,143.31)
PWR_VDDQ_SENSE: length 35
  TOP w0.254: v3(107.8,117.22) 107.1,117.22 106.02,118.31 105.21,119.11 105.21,127.49 105.6,127.87 v3(105.6,129.54)
  BOTTOM w0.203: PC5013.1 109.79,119.76 PU5001.5
  BOTTOM w0.254: PR5018.1 105.08,144.55 v2(105.08,142.98) 105.08,142.17 106.48,140.77 106.48,130.42 v3(105.6,129.54) ; PC5013.1 108.2,117.62 v3(107.8,117.22) 107.8,117.09 107.34,116.63 PR5020.1
PWR_VDDQ_SNB: length 2.9
  TOP w0.508: PR5019.1 v2(111.81,138.91) PC5010.2
PWR_VDDQ_TON: length 3.6
  BOTTOM w0.203: 107.57,122.53 108.06,122.04 PU5001.9
  BOTTOM w0.254: PR5008.2 v2(106.9,123.21) 107.57,122.53
PWR_VDDQ_VDD: length 10
  TOP w0.254: v3(109.63,128.57) v2(109.63,126.16) 109.63,124.35 v3(109.55,124.28)
  BOTTOM w0.203: PU5001.11 109.77,123.21 109.77,124 109.55,124.22 v3(109.55,124.28)
  BOTTOM w0.254: PR5004.1 PC5002.1 110.5,127.06 110.51,127.07 PC5001.1 110.51,127.41 109.63,128.3 v3(109.63,128.57) PR5001.1
PWR_VDDQ_VDDP: length 4.6
  BOTTOM w0.203: PU5001.12 110.19,124.38 109.35,125.22 v2(109.2,125.22)
  BOTTOM w0.508: PR5005.1 109.2,127.33 PC5204.1 v2(109.2,125.22)
PWR_VDDQ_VTT_EN: length 8.7
  BOTTOM w0.203: C5002.1 v2(107.52,121.01) 108.01,121.01 108.24,121.24 PU5001.7
  BOTTOM w0.254: RN21.4 105.23,116.35 105.28,116.41 105.28,119.33 105.37,119.42 105.37,120.41 R5002.1 105.9,120.42 C5002.1
PWR_VDDQ_VTTIN: length 6
  TOP w0.508: v5(113.28,120.73) 113.44,120.88 v2(114.48,120.88) PR5011.2
  BOTTOM w0.203: v5(113.28,120.73) 112.77,121.24 PU5001.19
  BOTTOM w0.508: v5(113.28,120.73) 114.48,119.53 PC5009.1
PWR_VDDQ_VTTOUT: length 1.3
  BOTTOM w0.203: PU5001.2 110.99,118.77
  vias: v2(111.76,116.23)
PWRBTN#: length 8.3
  TOP w0.114: L56.1 120.03,12.82 EC702.1 121.13,12.22 120.7,11.79 v2(120.7,11.53) 120.7,10.87 121.26,10.31 122.4,10.31 123.37,11.28 123.93,11.28 124.25,10.95 PWRBT1.2
PWRBTN#_1: length 27.2
  TOP w0.114: R623.2 103.47,3.16 104.01,2.62 104.79,2.62 R622.1 105.94,2.62 106.71,2.62 R6551.1 107.31,3.21 107.48,3.38 108.81,3.38 v2(109.28,2.92) 109.81,2.38 117.44,2.38 119.58,4.52 119.58,11.23 118.49,12.32 L56.2
PWRBTN_IN: length 128
  TOP w0.114: v1(101.19,4.88) 102.02,4.05 C512.1 R623.1 ; v3(54.76,59.99) 54.76,55.37 48.15,48.76 48.15,40.8 47.36,40.01 47.36,34.48 47.39,34.45 47.39,24.87 46.81,24.28 v3(46.81,20.15)
  BOTTOM w0.114: v1(101.19,4.88) 101.19,4.88 v2(99.83,6.24) 99.33,6.74 76.8,6.74 75.68,7.86 72,11.54 72,15.84 67.7,20.15 v3(46.81,20.15) ; v3(54.76,59.99) 60.63,59.99 61.32,59.31 65.91,59.31 66.82,60.21 71.74,60.21 R575.2
PWRGD_3V_B_1: length 5.4
  TOP w0.114: Q49.6 69.18,60.68 R581.2 v2(69.38,59.54) 67.77,59.54 67.28,60.02 Q49.5
PWRGD_3V_LL: length 2.5
  TOP w0.114: Q49.3 66.63,63.46 v2(66.22,63.88) 65.37,63.88 R582.2
PWRGD_PS_L: length 5.4
  BOTTOM w0.114: R530.2 65.95,93.85 R537.1 C480.1 65.95,96.71 66.17,96.93 v2(66.17,97.03) 66.17,97.51 65.74,97.94 Q45.2
PWRGD_PS_L1: length 4.3
  BOTTOM w0.114: Q45.6 66.39,101.53 v2(65.74,102.18) ; v2(65.74,102.18) Q45.5 ; v2(65.74,102.18) 65.14,102.78 R529.2
PWRGD_PS_L2: length 3.2
  BOTTOM w0.114: Q45.3 65.08,97.58 v2(65.07,97.56) 65.07,97.4 64.9,97.23 R536.1
PWRLED_CON: length 5.8
  TOP w0.305: v2(125.86,12.19) 125.25,11.58 PWRBT1.4
  TOP w0.381: L54.1 v2(125.86,12.19)
PWROK3_1: length 42.8
  TOP w0.114: v3(72.92,86.65) 72.92,85.52 71.39,83.99 71.39,82.84 72.02,82.22 v2(72.02,80.95) 72.03,80.93 72.03,76 v3(71.81,75.77) 71.52,75.49 70.79,75.49 70.69,75.59 69.37,75.59 69.29,75.51 65.61,75.51 64.97,74.88 63.17,74.88 62.64,74.35 59.54,74.35 59.23,74.04 58.7,74.04 56,71.34 56,66.01 56.23,65.77 57.78,65.77 57.78,65.76 58.05,65.76 R543.2
  BOTTOM w0.114: v3(72.92,86.65) 72.93,86.64 72.97,86.64 73.29,86.33 U31.32 ; v3(71.81,75.77) 71.89,75.7 U6503.36
PWROK3_1_R: length 4.1
  TOP w0.114: R580.1 60.58,62.51 v2(59.86,63.23) R543.1 R579.2
PWROK3_2: length 20.2
  TOP w0.114: v3(71.63,71.91) 71.63,73.28 v2(71.2,73.71) v3(70.41,74.5)
  BOTTOM w0.114: v3(71.63,71.91) 71.63,71.65 69.79,69.81 U31.78 69.79,67.48 68.94,66.63 68.94,64.35 R540.1 ; v3(70.41,74.5) 70.41,76.78 69.45,77.74 69.45,78.63 70.29,79.47 U6503.9
PWROK3_2_R: length 6
  TOP w0.114: R563.1 68.94,65.38 69.85,64.47 69.85,63.84 R584.1 69.34,62.64 v3(69.09,62.38) v2(69.77,61.7)
  BOTTOM w0.114: v3(69.09,62.38) 69.24,62.53 R540.2
Q5102_GATE: length 2.6
  BOTTOM w0.254: v2(126.9,108.99) R395.2 128.96,108.99 Q36.G
Q5103_GATE: length 2.9
  BOTTOM w0.254: Q38.G 129.36,105.13 v2(128.42,104.19) 128.09,104.19 127.86,104.42 R396.2
REMOTE1+: length 246.1
  TOP w0.114: v3(122.91,179.3) 122.91,175.38 128.3,169.99 128.3,166.05 137.13,157.21 v3(137.13,154.84) ; v3(71.88,182.4) 71.67,182.61 61.76,182.61 RT1.1 ; RN20.3 63.35,70.94 63.78,70.51 v3(63.92,70.51) C468.1 65.03,68.59 72.08,68.59 73.82,70.33 77.61,70.33 79.12,71.84 82.02,71.84 83.95,73.76 84.2,73.76 v3(84.23,73.79)
  BOTTOM w0.114: v3(71.88,182.4) 73.51,184.03 78.74,184.03 86.17,191.46 107.36,191.46 119.52,179.3 v2(120.12,179.3) v3(122.91,179.3) ; v3(137.13,154.84) 137.06,154.76 137.06,131.75 135.49,130.18 135.49,122.56 135.03,122.1 135.03,111.07 134.49,110.54 134.49,108.31 133.91,107.72 133.91,106.12 129.9,102.11 121.5,102.11 100.29,80.9 95.71,80.9 88.59,73.79 v3(84.23,73.79) ; U6503.46 67.89,72.5 67.66,72.28 67.04,72.28 66.24,71.48 64.47,71.48 63.92,70.93 v3(63.92,70.51) 63.92,70.14 63.79,70.01 U31.90
ROM_RST#: length 15.4
  TOP w0.114: CPU1.AU9 50.9,136.6 50.44,137.06 v3(50.44,137.1)
  BOTTOM w0.114: R105.1 46.23,125.85 v2(46.18,125.91) 46.18,125.91 46.15,125.93 46.15,129.77 49.09,132.71 49.09,133.21 50.93,135.06 50.93,135.71 50.92,135.72 50.92,136.58 50.44,137.06 v3(50.44,137.1)
RSMRST*_R: length 3.2
  TOP w0.114: R584.2 v2(68.2,64.22) 67.28,63.31 Q49.2
RSMRST_N: length 16.1
  TOP w0.114: R534.2 57.86,77.72 v2(57.58,77.44) 53.77,73.63 v3(53.47,73.63) ; R518.2 50.24,75.87 v3(50.85,75.26) 48.76,73.17 D1.2
  BOTTOM w0.114: v3(50.85,75.26) 52.73,73.38 53.21,73.38 v3(53.47,73.63)
RSMRST_N_FCH: length 99.4
  TOP w0.102: 48.54,135.4 48.66,135.52 48.66,136.28 arc(48.67,136.34) 48.7,136.38 48.7,136.38 48.78,136.5 arc(48.81,136.55) 48.84,136.61 arc(48.86,136.68) 48.86,136.75 48.86,136.92 48.85,136.93 arc(48.84,136.94) 48.83,136.96 48.82,136.96 arc(48.8,136.98) 48.79,137 48.77,137.02 arc(48.75,137.05) 48.74,137.1 48.74,137.19
  TOP w0.114: v1(47.98,124.64) 47.18,125.44 47.18,126.15 46.86,126.48 46.86,127.5 C24.1 47.63,131.86 48.37,132.59 48.37,133.83 48.66,134.13 48.7,134.16 CPU1.AY5 48.7,134.66 48.39,134.97 48.39,135.23 48.48,135.34 48.54,135.4 ; v3(48.7,141.01) 48.7,140.41 49.46,139.65 49.46,139.27 48.74,138.55 48.74,138.18 48.79,138.12 48.88,138.03 48.88,137.69 48.88,137.69 48.81,137.53 arc(48.76,137.46) 48.74,137.36 48.74,137.19 ; v3(44.28,141.17) 44.04,141.42 39.87,141.42 39.42,140.96 39.42,139.42 37.77,137.77 35.29,137.77 R62.2 ; D1.3 43.86,73.76 v3(43.86,73.8)
  BOTTOM w0.114: v3(48.7,141.01) 48.46,141.01 48.06,140.61 45.98,140.61 45.42,141.18 44.42,141.18 44.41,141.17 v3(44.28,141.17) ; v3(43.86,73.8) 43.87,73.82 v2(43.87,76.51) 45.31,77.95 45.31,82.74 49.63,87.06 49.63,90.47 58.68,99.52 58.68,113.91 54,118.59 53.23,118.59 47.98,123.84 v1(47.98,124.64)
RT: length 4.5
  BOTTOM w0.254: U59.10 25.1,15.65 24.46,15.01 v2(24.46,14.12) 23.9,13.56 R338.1
RTC_CLK: length 10.6
  TOP w0.114: v3(51.55,136.17) 51.63,136.17 CPU1.AV11
  BOTTOM w0.114: R129.2 49.48,128.39 R135.1 v6(49.51,129.36) 50.24,130.1 50.24,131.52 51.03,132.31 51.03,134.22 51.98,135.17 51.98,135.65 51.55,136.08 v3(51.55,136.17)
RTL_ISOLATE_N: length 7.7
  BOTTOM w0.114: R286.2 107.04,68.72 R288.1 108.8,68.72 v2(109.42,68.1) 110.11,67.41 110.11,66.61 110.55,66.17 111.34,66.17 111.89,65.62 LAN1.20
RUN_EN: length 69.9
  TOP w0.114: R307.2 C310.1 26.46,71.42 v3(26.26,71.22) ; R302.1 25.89,107.66 27.71,105.84 27.71,102.06 31.97,97.8 31.97,95.82 v3(32.77,95.02) ; v3(26.26,49.58) 26.11,49.43 U16.G 25.41,47.49 C327.1
  BOTTOM w0.114: v3(32.77,95.02) 32.77,93.28 26.61,87.13 26.61,71.57 v3(26.26,71.22) 26.29,71.2 26.29,59.55 26.8,59.03 26.8,58.67 26.29,58.16 v2(26.29,55.02) 26.29,49.61 v3(26.26,49.58)
RUNPWR_G: length 3.8
  TOP w0.114: Q26.G 31.9,70.2 31.9,69.32 v2(31.93,69.29) 32.17,69.06 R1015.2 32.93,69.06 R1014.2
RUNPWR_R3: length 3.5
  TOP w0.114: R306.1 v2(26.59,74.04) 26.39,74.04 R307.1
RUNPWR_R4: length 4.8
  TOP w0.114: Q27.5 28.11,71.93 28.02,71.83 28.02,71.42 28.16,71.28 Q27.6 v2(28.79,70.03) 28.22,70.03 27.87,70.38 R309.2
RUNPWR_R5: length 5.3
  TOP w0.114: Q27.3 31.2,72.58 32.26,73.63 R303.2 32.25,74.04 v2(30.66,74.04) R306.2
RUNPWR_R6: length 106.5
  TOP w0.114: U13.3 65.99,30.01 v1(66.27,29.72) ; v3(18.19,69.58) 18.23,69.62 26.13,69.62 26.28,69.47 29.26,69.47 29.9,70.1 29.9,71.58 30.25,71.93 Q27.2 31.36,71.93 31.99,72.55 Q26.D 33.33,74.02 R310.2 ; v1(66.2,31.12) 65.89,30.81 U13.5
  BOTTOM w0.114: v3(18.19,69.58) 18.1,69.49 v2(18.1,68.73) 17.89,68.52 17.89,36.8 21.23,33.46 42.42,33.46 43.88,32 56,32 56.24,31.76 61.72,31.76 62.54,30.93 65.58,30.93 65.76,31.12 v1(66.2,31.12) 66.27,31.04 v1(66.27,29.72)
S0_PWR_GOOD: length 232.1
  TOP w0.114: R582.1 64.28,62.85 C494.1 64.26,62.88 R583.1 63.3,62.88 62.92,62.5 R580.2 62.09,62.37 63.2,61.26 64.52,61.26 66.65,59.13 68.28,59.13 71.15,56.26 71.15,54.81 v3(71.17,54.79) ; v3(89.19,68.97) 89.19,86.13 80.33,94.99 74.78,94.99 74.47,95.31 71.69,95.31 70.71,96.28 68.06,96.28 67.84,96.5 63.17,96.5 63.05,96.37 62.68,96.37 62.28,96.77 48.02,96.77 46.68,98.12 D2.2 ; v3(48.97,28.6) 48.89,28.68 48.89,47.77 54.23,53.11 v3(54.23,53.45)
  BOTTOM w0.114: 71.17,54.76 v3(71.17,54.79) ; 71.17,54.76 75.14,54.76 82.05,61.68 82.05,65.15 85.67,68.77 88.99,68.77 v3(89.19,68.97) ; 71.17,54.76 70.72,54.76 69.4,53.45 v3(54.23,53.45) ; v3(48.97,28.6) 48.97,28.14 49.94,27.17 55.77,27.17 57.56,25.39 58.2,25.39 59.38,24.21 66.33,24.21 74.88,15.66 74.88,11.55 77.78,8.64 100.38,8.64 103.72,5.3 106.77,5.3 107.5,6.03 110.74,6.03 v2(111.11,6.4) 113.74,9.03 113.74,9.16 114.17,9.6 Q76.2
SATA_CALRN: length 8.1
  TOP w0.102: CPU1.AP19 56.4,138.2 v3(56.85,137.75)
  BOTTOM w0.102: v3(56.85,137.75) 56.52,137.47 56.52,137.24 56.65,137.11 57.02,137.11 57.56,136.58 57.56,134.67 58.79,133.44 ; v6(59,133.65) 58.79,133.44 ; 58.79,133.44 59.06,133.17 59.06,132.56 R98.2
SATA_CALRP: length 8.1
  TOP w0.102: CPU1.AR19 56.4,137.4 56,137.8 v3(55.98,137.8)
  BOTTOM w0.102: v6(57.43,134.01) 57.65,134.23 ; 57.65,134.23 58.8,133.07 58.8,132.56 R97.2 ; 57.65,134.23 57.3,134.57 57.3,136.47 56.92,136.86 56.55,136.86 56.27,137.13 56.27,137.49 56,137.8 v3(55.98,137.8)
SATA_RX0N: length 101.8
  TOP w0.102: 34.99,107.5 36.72,109.23 54.49,109.23 58.1,112.84 58.1,128.24 54.82,131.51 54.82,133.88 54.75,133.95 CPU1.BA16 ; 34.99,107.5 v2(35.23,107.26) ; 34.99,107.5 32.66,105.17 v1(30.84,105.17)
  BOTTOM w0.102: TR26.1 15.41,146.31 15.62,146.1 15.62,144.27 17.27,142.62 17.27,141.91 22.58,136.61 22.58,115.27 28.9,108.94 29.76,108.94 30.32,108.38 30.32,105.68 v1(30.84,105.17)
SATA_RX0P: length 101.8
  TOP w0.102: 33.03,105.9 36.61,109.48 54.38,109.48 57.84,112.95 57.84,128.13 54.57,131.4 54.57,133.77 54.45,133.89 54.45,134.18 54.75,134.48 CPU1.AY16 ; 33.03,105.9 v2(32.79,106.15) ; 33.03,105.9 32.55,105.42 31.47,105.42 31.34,105.55 31.34,105.79 31.22,105.92 30.88,105.92 v1(30.87,105.93)
  BOTTOM w0.102: TR26.4 16.09,146.31 15.88,146.1 15.88,144.38 17.53,142.73 17.53,142.02 22.83,136.71 22.83,115.37 29.01,109.19 29.87,109.19 30.58,108.49 30.58,106.05 30.7,105.93 v1(30.87,105.93)
SATA_RX1N: length 123
  TOP w0.102: TR28.4 18.17,43.47 18.39,43.69 18.86,43.69 20.7,45.52 20.7,46.96 29.09,55.36 v3(29.83,55.36) ; CPU1.AY17 55.3,134.16 55.6,133.86 55.6,131.5 58.81,128.29 58.81,112.5 54.82,108.52 39.14,108.52 37.86,107.24 36.44,107.24 v3(36.19,106.99)
  BOTTOM w0.102: v2(35.86,101.88) 35.51,101.88 ; 35.51,101.88 35.51,106.72 35.78,106.99 v3(36.19,106.99) ; 35.51,101.88 35.51,100.12 36.34,99.29 36.34,92.37 29.77,85.8 29.77,57.89 30.96,56.7 30.96,56.05 30.56,55.65 30.13,55.65 v3(29.83,55.36)
SATA_RX1P: length 122.9
  TOP w0.102: v3(29.83,56.25) 29.83,56.03 29.41,55.61 28.99,55.61 20.45,47.07 20.45,45.63 18.76,43.94 18.39,43.94 18.17,44.16 TR28.1 ; v3(36.2,107.81) 36.52,107.49 37.76,107.49 39.04,108.77 54.72,108.77 58.55,112.61 58.55,128.19 55.35,131.39 55.35,133.65 CPU1.BA17
  BOTTOM w0.102: 36.09,97.59 36.09,92.48 29.51,85.91 29.51,57.78 30.71,56.59 30.71,56.16 30.45,55.91 30.25,55.91 30.2,55.96 30.2,56.16 30.11,56.25 v3(29.83,56.25) ; 36.09,97.59 v2(35.76,97.59) ; 36.09,97.59 36.09,99.19 35.26,100.02 35.26,106.83 35.76,107.34 35.76,107.82 35.89,107.95 36.08,107.95 36.2,107.82 v3(36.2,107.81)
SATA_RXN0_C: length 6.1
  BOTTOM w0.102: 14.17,150.27 14.86,150.27 15.83,149.29 15.83,148.68 15.77,148.62 15.49,148.62 15.41,148.53 TR26.2 ; 14.17,150.27 13.89,150.27 13.31,150.85 12.99,150.85 C414.1 ; 14.17,150.27 v2(14.17,149.89)
SATA_RXN0_N: length 6.1
  BOTTOM w0.102: v2(6.48,151.49) 6.5,151.46 7.5,151.46 HDD1.S5 8.05,152.01 8.85,152.01 10.09,150.77 11.37,150.77 C414.2
SATA_RXN1_C: length 5
  TOP w0.102: v2(15.06,43.13) 14.81,43.38 ; 14.81,43.38 15.11,43.69 15.65,43.69 15.86,43.47 TR28.3 ; 14.81,43.38 13.83,42.41 13.25,42.41 13.15,42.3 13.15,42.19 13.05,42.09 C425.1
SATA_RXN1_N: length 7.3
  TOP w0.102: C425.2 11.38,42.41 10.61,42.41 10.48,42.28 6.91,42.28 ODD1.5
  BOTTOM w0.102: v2(7.9,41.45) 7.58,41.77 ODD1.5
SATA_RXP0_C: length 6.1
  BOTTOM w0.102: v2(16.46,149.2) 16.09,149.2 ; 16.09,149.2 TR26.3 ; 16.09,149.2 16.09,149.4 14.96,150.52 14,150.52 13.41,151.11 12.8,151.11 C411.1
SATA_RXP0_N: length 5.4
  BOTTOM w0.102: 10.67,151.02 11.36,151.02 C411.2 ; 10.67,151.02 v2(10.67,151.38) ; 10.67,151.02 10.2,151.02 8.95,152.27 8.05,152.27 HDD1.S6
SATA_RXP1_C: length 5
  TOP w0.102: 13.99,42.93 13.72,42.66 13.25,42.66 13.15,42.76 13.15,42.88 13.05,42.98 C424.1 ; 13.99,42.93 v2(13.74,43.18) ; 13.99,42.93 15.01,43.94 15.65,43.94 15.86,44.16 TR28.2
SATA_RXP1_N: length 7.3
  TOP w0.102: ODD1.6 6.91,42.53 10.38,42.53 10.5,42.66 11.38,42.66 C424.2
  BOTTOM w0.102: ODD1.6 7.55,43.04 v2(7.9,43.38)
SATA_TX0N: length 97.8
  TOP w0.102: 30.76,107.42 29.8,107.42 v1(29.56,107.66) ; 30.76,107.42 v2(30.76,107.77) ; 30.76,107.42 33.42,107.42 36.2,110.2 54.04,110.2 57.1,113.25 57.1,127.98 53.21,131.86 53.21,133.35 53.4,133.54 53.4,133.87 53.35,133.92 53.35,134.18 53.37,134.19 53.37,134.21 53.65,134.5 CPU1.AY14
  BOTTOM w0.102: TR25.4 14.31,143.42 14.1,143.21 14.1,142.9 14.33,142.67 15.82,142.67 22.12,136.38 22.12,115.08 28.85,108.34 28.85,107.57 29.04,107.39 29.3,107.39 v1(29.56,107.66)
SATA_TX0P: length 97.8
  TOP w0.102: CPU1.BA14 53.65,133.96 53.66,133.95 53.66,133.44 53.47,133.25 53.47,131.97 57.35,128.08 57.35,113.15 54.15,109.94 36.3,109.94 33.53,107.17 29.86,107.17 v1(29.58,106.89)
  BOTTOM w0.102: 21.87,116.61 21.87,136.27 15.72,142.42 14.22,142.42 13.84,142.8 13.84,143.21 13.63,143.42 TR25.1 ; 21.87,116.61 v2(21.51,116.61) ; 21.87,116.61 21.87,114.97 28.6,108.24 28.6,107.47 28.93,107.14 29.34,107.14 v1(29.58,106.89)
SATA_TX1N: length 125.4
  TOP w0.102: v3(36.48,106.2) 36.68,106.2 36.8,106.07 36.8,105.8 36.93,105.67 37.36,105.67 39.75,108.06 55.02,108.06 59.27,112.31 59.27,128.37 56.45,131.19 56.45,133.63 56.4,133.68 CPU1.BA19 ; v3(29.91,54.47) 29.91,54.24 29.72,54.05 29.03,54.05 21.46,46.48 21.46,44.32 18.8,41.66 18.39,41.66 18.17,41.87 TR27.1
  BOTTOM w0.102: 36.8,99.97 36.8,92.12 30.37,85.69 30.37,57.98 31.48,56.87 31.48,54.37 31.26,54.15 30.23,54.15 v3(29.91,54.47) ; 36.8,99.97 v2(36.45,99.97) ; 36.8,99.97 36.8,101.9 35.97,102.73 35.97,106.02 36.14,106.2 v3(36.48,106.2)
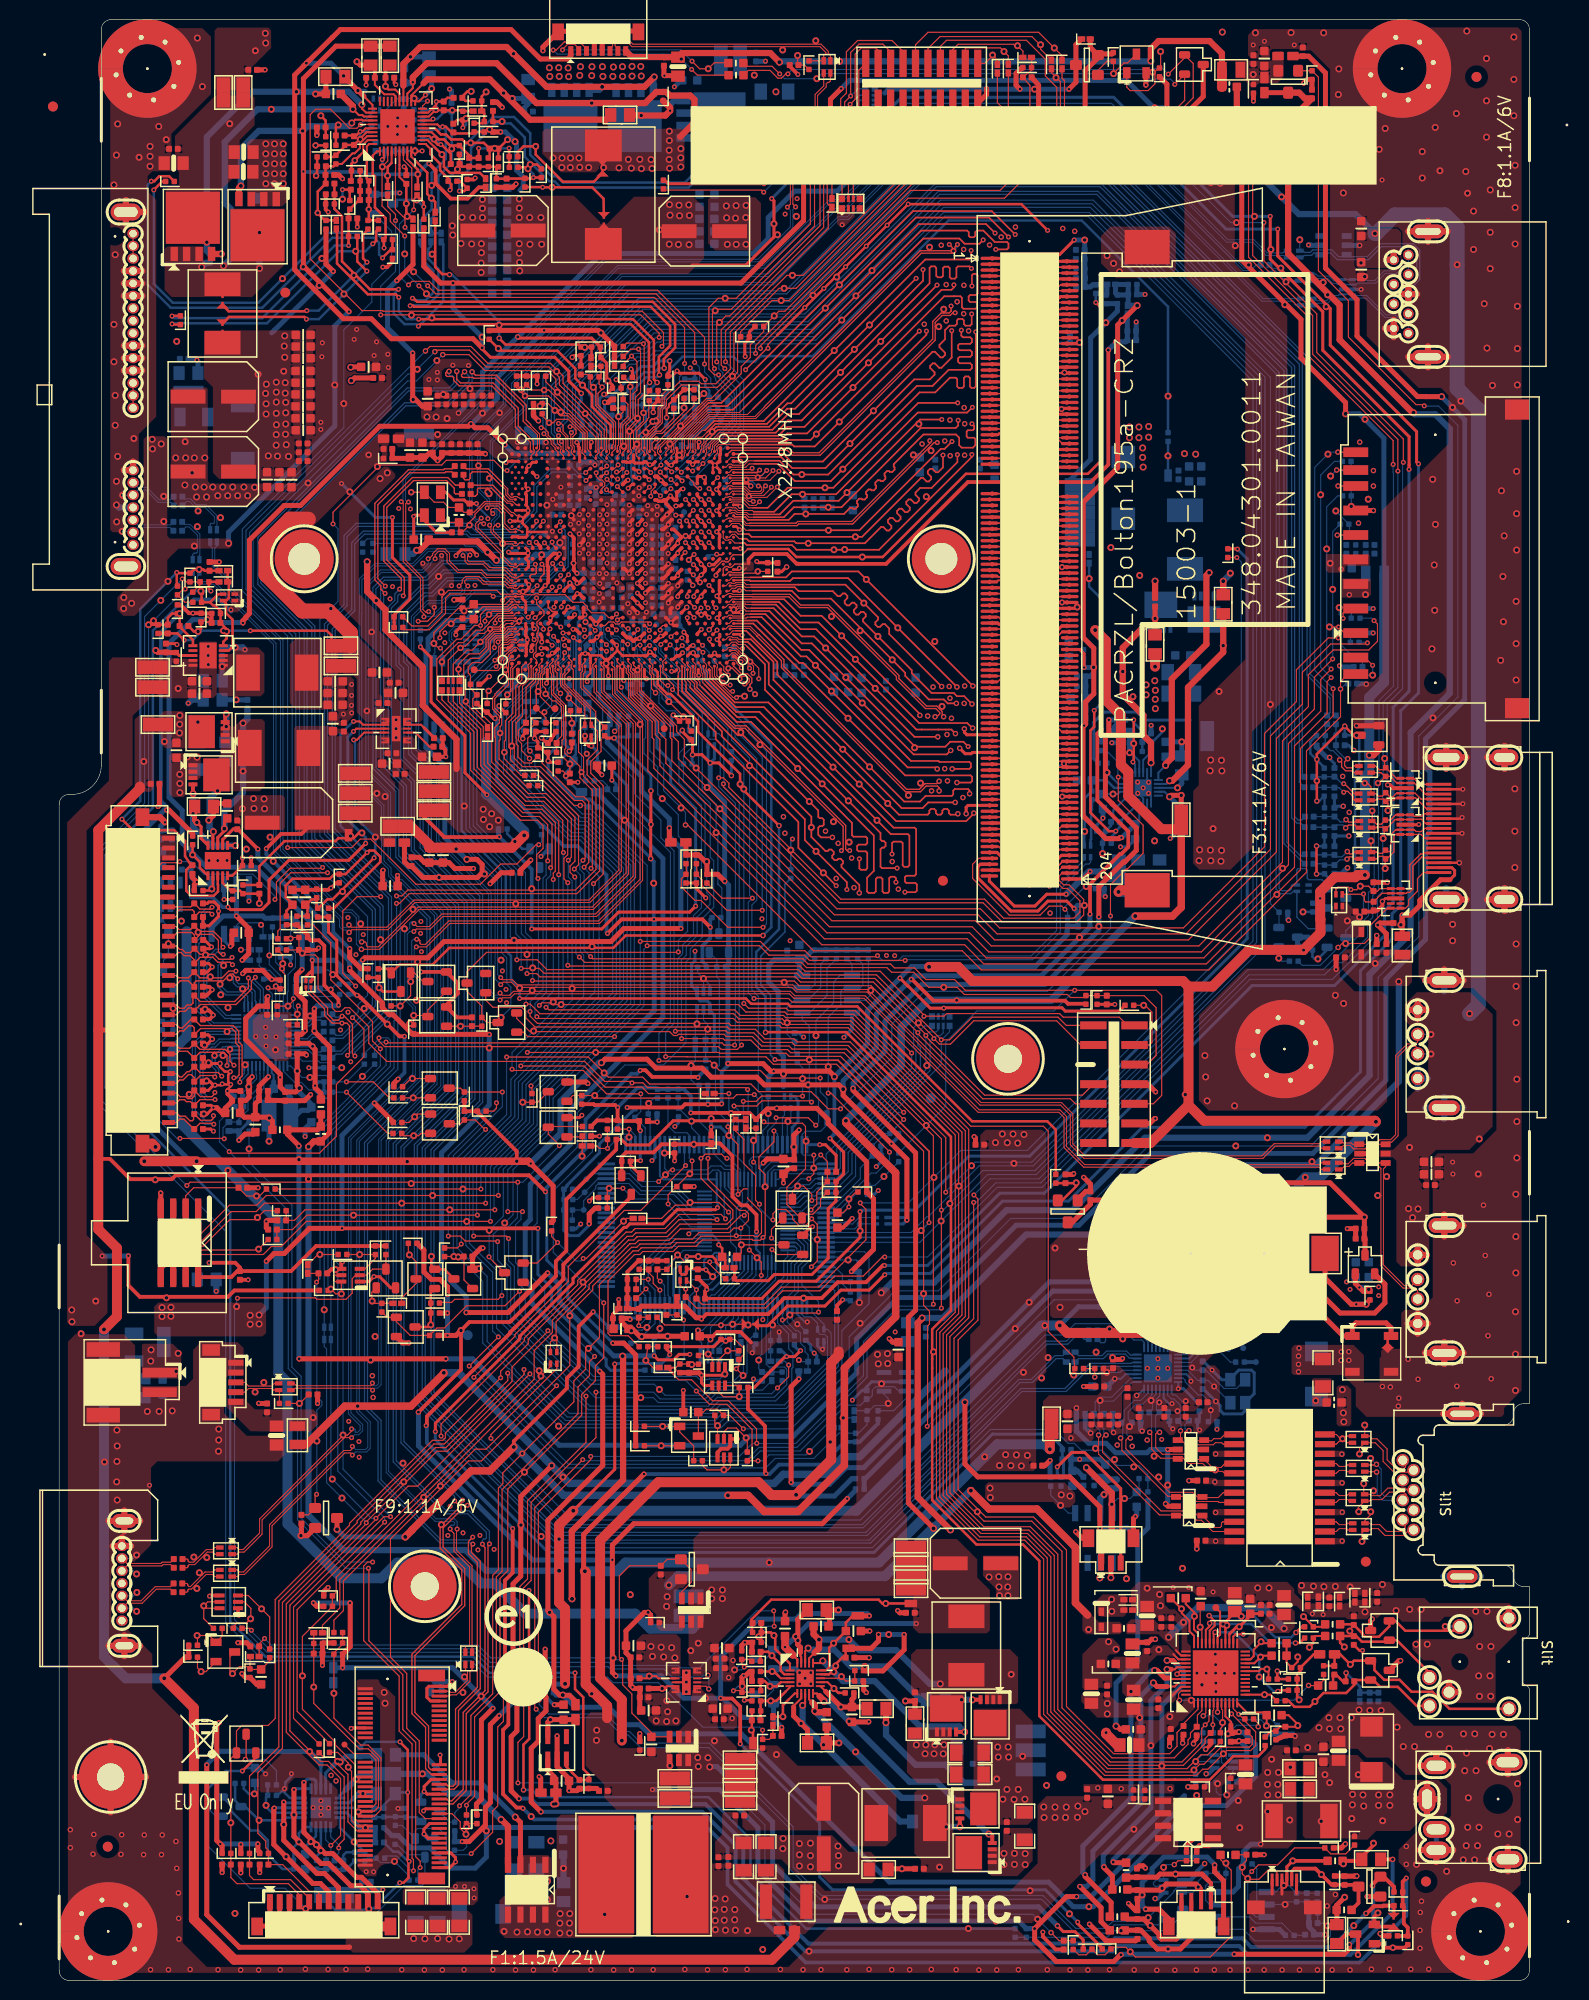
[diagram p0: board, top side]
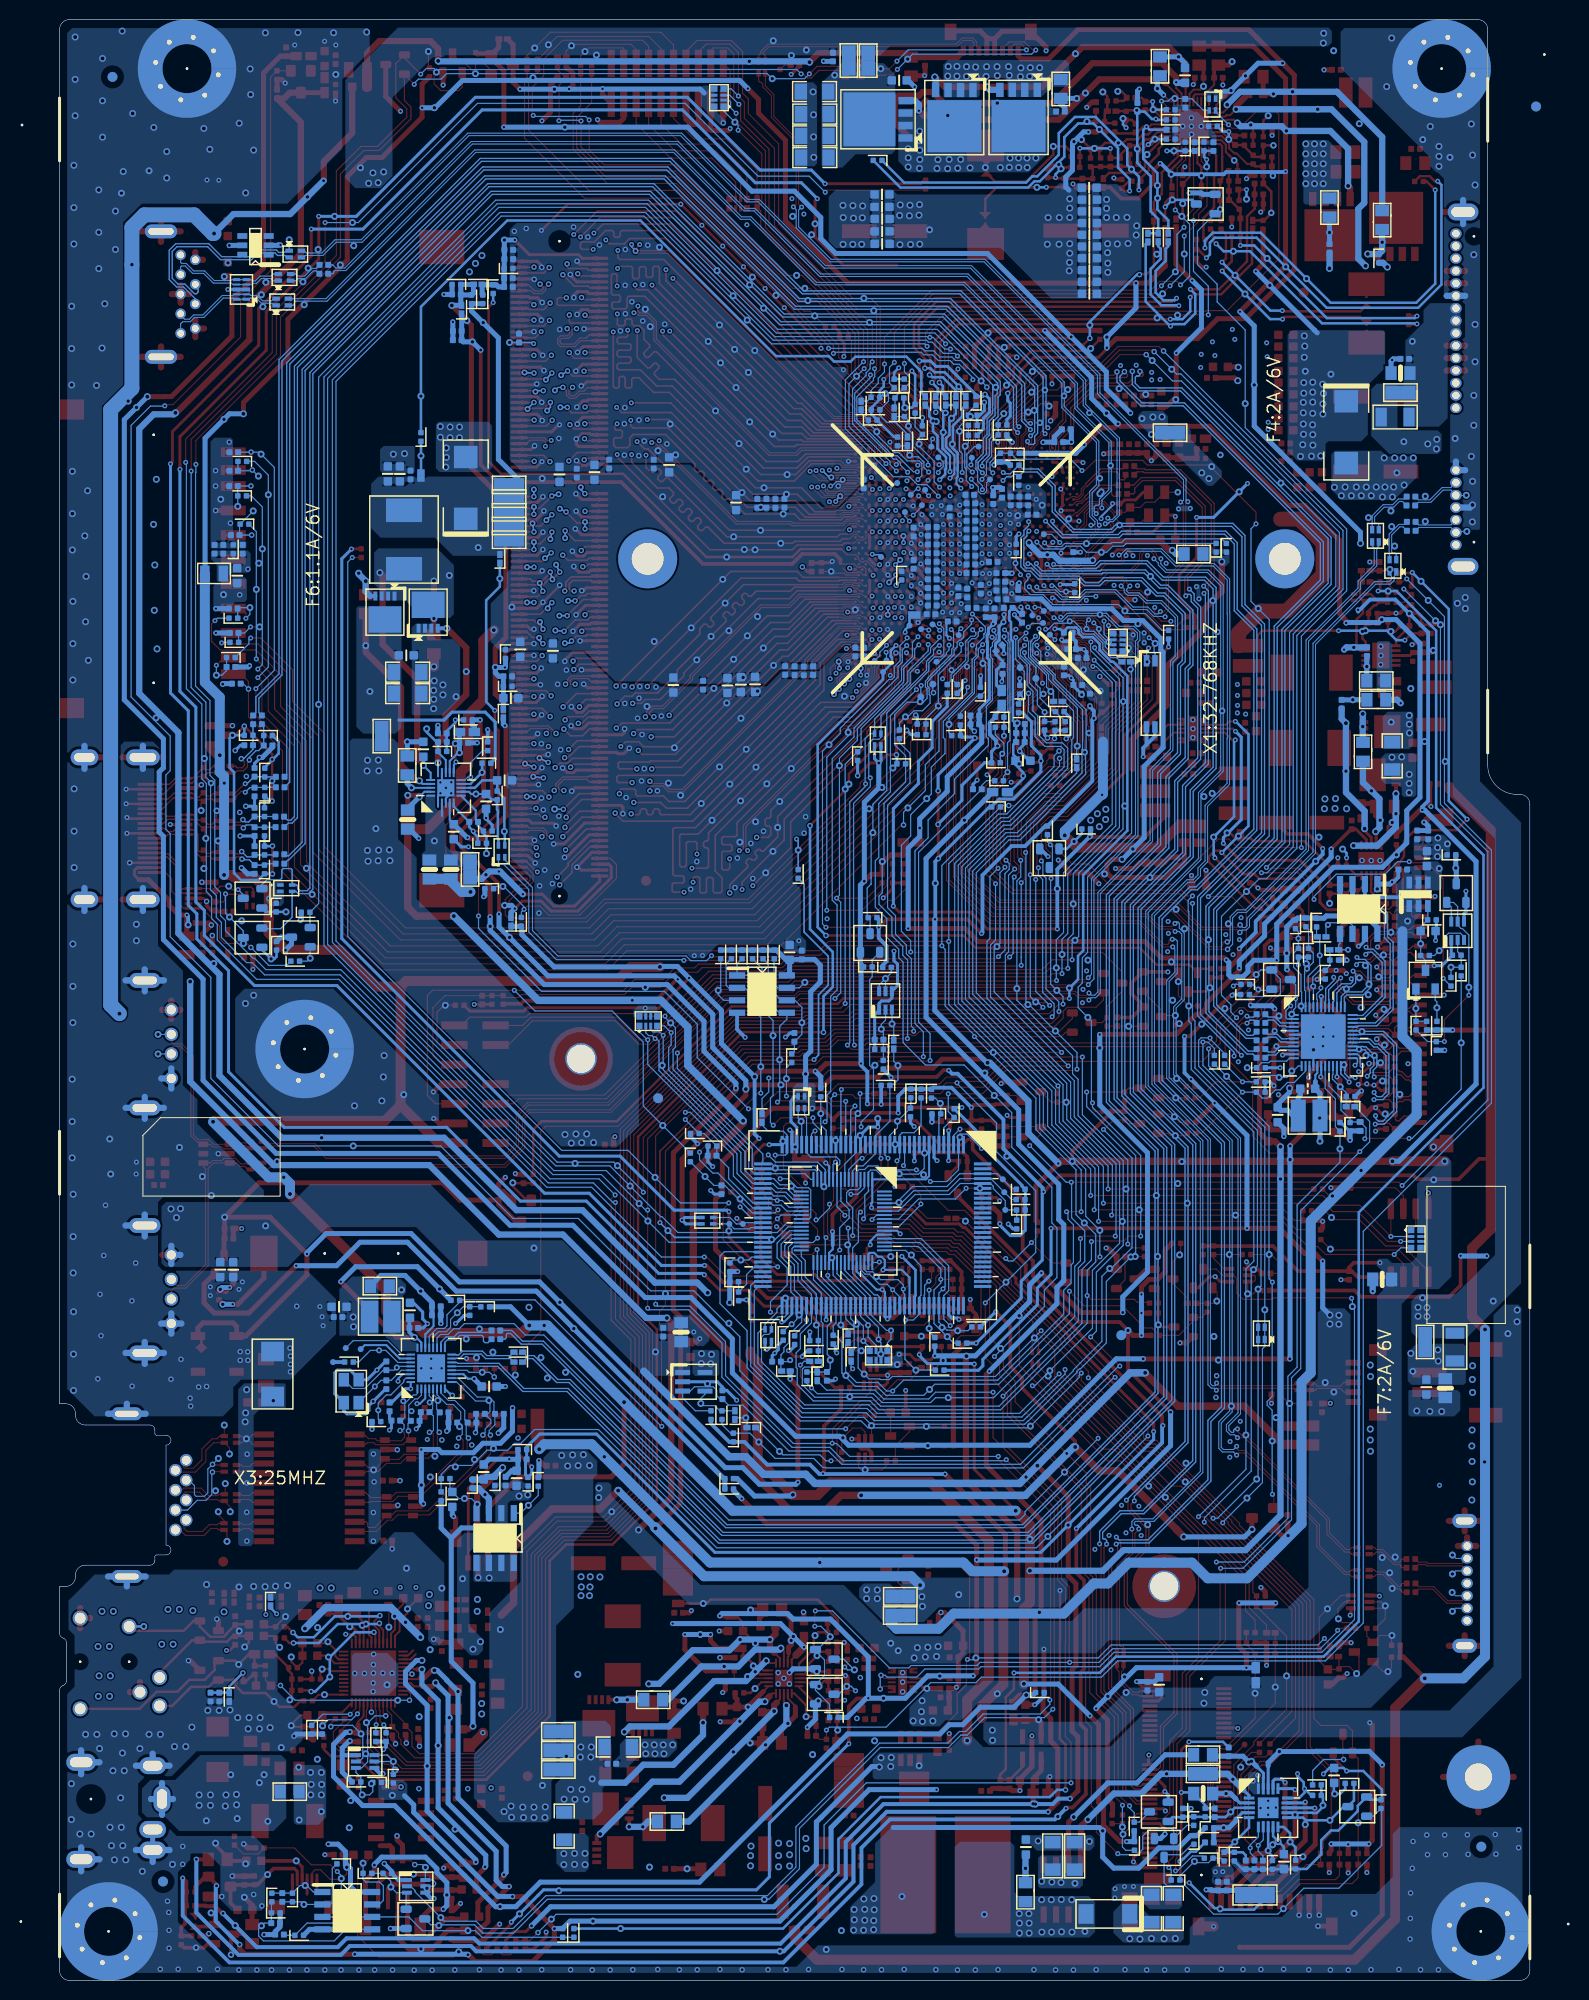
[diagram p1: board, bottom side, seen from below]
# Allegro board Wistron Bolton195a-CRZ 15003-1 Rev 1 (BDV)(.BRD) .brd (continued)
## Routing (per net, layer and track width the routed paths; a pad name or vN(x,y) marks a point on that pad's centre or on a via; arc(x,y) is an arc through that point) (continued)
SATA_TX1P: length 125.4
  TOP w0.102: v3(29.91,53.58) 29.69,53.8 29.14,53.8 21.72,46.38 21.72,44.22 18.9,41.4 18.39,41.4 18.17,41.19 TR27.4 ; v3(36.43,105.42) 37.47,105.42 39.86,107.81 55.13,107.81 59.52,112.2 59.52,128.48 56.7,131.29 56.7,133.85 56.4,134.15 CPU1.AY19
  BOTTOM w0.102: v3(29.91,53.58) 30.23,53.9 31.37,53.9 31.74,54.27 31.74,56.97 30.62,58.09 30.62,85.59 37.05,92.02 37.05,102 36.22,102.83 36.22,103.89 ; v3(36.43,105.42) 36.22,105.2 36.22,103.89 ; 36.22,103.89 v2(36.58,103.89)
SATA_TXN0_C: length 5.3
  BOTTOM w0.102: 13.84,148.03 13.36,148.51 12.8,148.51 C410.1 ; 13.84,148.03 v2(14.1,148.29) ; 13.84,148.03 14.35,147.52 14.35,145.45 14.31,145.41 TR25.3
SATA_TXN0_N: length 4.8
  BOTTOM w0.102: C410.2 11.34,148.46 10.67,148.46 ; 10.67,148.46 8.05,148.46 HDD1.S3 ; 10.67,148.46 v2(10.67,148.82)
SATA_TXN1_C: length 5.1
  TOP w0.102: 14.55,41.33 14.88,41.66 15.65,41.66 15.86,41.87 TR27.2 ; 14.55,41.33 13.39,40.17 13.23,40.17 13.13,40.27 13.13,40.39 13.03,40.49 C423.1 ; 14.55,41.33 v2(14.3,41.58)
SATA_TXN1_N: length 7.9
  TOP w0.102: C423.2 11.34,40.16 9.8,40.16 8.37,38.72 6.91,38.72 ODD1.3
  BOTTOM w0.102: v2(7.92,39.57) 7.58,39.23 ODD1.3
SATA_TXP0_C: length 5.2
  BOTTOM w0.102: TR25.2 13.63,145.45 13.77,145.59 14.02,145.59 14.1,145.67 14.1,146.3 ; C409.1 12.94,148.26 13.26,148.26 14.1,147.42 14.1,146.3 ; 14.1,146.3 v2(13.79,146.3)
SATA_TXP0_N: length 5.6
  BOTTOM w0.102: v2(6.43,147.8) 7.43,147.8 HDD1.S2 8.05,148.2 11.31,148.2 C409.2
SATA_TXP1_C: length 5.1
  TOP w0.102: 13.8,40.22 13.5,39.92 13.23,39.92 13.13,39.81 13.13,39.7 13.03,39.6 C422.1 ; 13.8,40.22 v2(14.05,39.98) ; 13.8,40.22 14.99,41.4 15.65,41.4 15.86,41.19 TR27.3
SATA_TXP1_N: length 7.8
  TOP w0.102: C422.2 11.37,39.9 9.91,39.9 8.47,38.47 6.91,38.47 ODD1.2
  BOTTOM w0.102: v2(7.9,37.64) 7.58,37.96 ODD1.2
SCALAR_VDD_EN1: length 5
  BOTTOM w0.114: Q34.2 7.37,104.92 R386.2 7,104.56 R381.2 v2(8.04,103.34) R383.2
SD_CD#: length 117.2
  TOP w0.114: v1(63.9,117.85) 64.12,117.85 76.96,105.02 92.12,105.02 94.08,103.07 117.29,103.07 127.25,113.03 127.25,125.41 130.73,128.88 v1(130.73,131.72) 130.73,131.73 130.73,132.48 131.49,133.24 CRS1.11 ; CPU1.AY20 56.95,134.49 57.26,134.18 57.26,133.92 57.19,133.85 57.19,132.07 v3(57.35,131.9)
  BOTTOM w0.114: v3(57.35,131.9) 57.45,131.8 57.45,131.32 60.27,128.5 60.27,125.4 61.68,124 61.68,121.37 v2(63.45,119.59) 63.9,119.14 v1(63.9,117.85) ; EC709.1 131.27,132.27 v1(130.73,131.72)
SD_CLK: length 6.2
  TOP w0.114: CRS1.5 130.41,147.43 v1(130.4,147.42)
  BOTTOM w0.114: v1(130.4,147.42) EC302.1 131.64,148.48 R1026.2 130.25,149.87 v2(130.25,149.88)
SD_CLK_CH: length 123.3
  TOP w0.114: CPU1.AY22 58.05,134.51 58.36,134.2 58.36,133.9 58.29,133.83 58.29,133.57 58.52,133.34 58.52,131.04 61.16,128.4 61.16,127.32 61.89,126.59 61.89,124.15 78.58,107.47 93.14,107.47 95.09,105.52 116.27,105.52 124.81,114.05 124.81,126.42 128.06,129.68 128.06,132.92 v3(129.93,134.78)
  BOTTOM w0.114: v3(129.93,134.78) v2(129.93,141.88) 129.93,147.78 R1026.1
SD_CMD: length 5.6
  TOP w0.114: v3(130.99,138.93) 130.99,139.47 131.45,139.93 CRS1.2
  BOTTOM w0.114: v3(130.99,138.93) 130.59,139.33 v2(130.59,140.02) 131.75,140.02 EC328.1 131.83,139.92 R1027.2
SD_CMD_CH: length 116.2
  TOP w0.114: v3(134.15,138.69) 134.5,138.35 134.5,136.59 133.61,135.7 129.98,135.7 127.45,133.17 127.45,129.93 124.19,126.68 124.19,115.12 115.21,106.13 95.44,106.13 93.72,107.85 93.49,108.08 78.83,108.08 v2(67.41,119.5) 62.51,124.4 62.51,126.59 62.36,126.74 62.36,127.89 58.96,131.29 58.96,133.52 58.93,133.55 58.93,133.83 58.6,134.16 CPU1.AY23
  BOTTOM w0.114: v3(134.15,138.69) 133.89,138.95 R1027.1
SD_DATA0: length 5.2
  TOP w0.114: CRS1.7 v1(130.48,152.43)
  BOTTOM w0.114: v2(131.82,150.35) R1022.2 131.81,151.47 EC327.1 131.81,152.43 v1(130.48,152.43)
SD_DATA0_CH_C: length 127.7
  TOP w0.114: CPU1.BA22 58.08,134.02 58.08,133.48 58.31,133.25 58.31,130.92 60.81,128.42 60.81,127.07 61.28,126.59 61.28,123.9 78.32,106.86 92.88,106.86 94.84,104.9 116.53,104.9 125.42,113.8 125.42,126.17 128.71,129.46 128.71,132.69 v3(129.77,133.75)
  BOTTOM w0.114: v3(129.77,133.75) 129.32,134.21 v2(129.32,146.01) 129.32,150.3 130.44,151.42 R1022.1
SD_DATA1: length 5.3
  TOP w0.114: CRS1.8 v1(130.34,154.06)
  BOTTOM w0.114: R1023.2 131.8,153.99 EC708.1 130.41,153.98 v1(130.34,154.06) 129.72,153.44 v2(129.72,153.44)
SD_DATA1_CH_C: length 134.1
  TOP w0.114: v3(129.77,132.89) 129.36,132.48 129.36,129.25 126.03,125.92 126.03,113.54 116.78,104.29 94.58,104.29 92.63,106.25 78.07,106.25 60.67,123.64 60.67,126.59 60.49,126.77 60.49,128.41 58.09,130.81 58.09,133.16 57.86,133.39 57.86,133.78 57.5,134.14 CPU1.AY21
  BOTTOM w0.114: R1023.1 130.1,154.94 128.7,153.54 v2(128.7,151.54) 128.7,133.96 v3(129.77,132.89)
SD_DATA2: length 5.6
  TOP w0.114: CRS1.9 133.21,134.93 v3(134,134.14)
  BOTTOM w0.114: v3(134,134.14) v2(134,133.13) 133.43,133.13 132.96,133.6 EC330.1 132.96,134.93 R1024.2
SD_DATA2_CH_C: length 109.4
  TOP w0.114: CPU1.AY24 59.15,134.5 59.46,134.19 59.46,133.91 59.39,133.84 59.39,131.57 62.99,127.97 62.99,127.38 63.78,126.59 63.78,124.86 v2(64.98,123.66) 79.34,109.31 93.99,109.31 95.95,107.35 114.7,107.35 122.97,115.62 122.97,127.19 126.22,130.44 126.22,133.68 129.47,136.93 v3(130.5,136.93)
  BOTTOM w0.114: v3(130.5,136.93) 130.68,136.75 130.68,136.33 R1024.1
SD_DATA3: length 5.4
  TOP w0.114: v2(129.59,138.05) v3(130.52,138.05) 131.14,137.43 CRS1.1
  BOTTOM w0.114: R1025.2 131.74,136.49 EC329.1 131.13,137.44 v3(130.52,138.05)
SD_DATA3_CH_C: length 110.6
  TOP w0.114: CPU1.BA24 59.15,133.63 59.17,133.61 59.17,131.48 62.66,127.99 62.66,126.85 63.17,126.34 63.17,124.61 v2(66.1,121.68) 79.08,108.69 93.74,108.69 95.7,106.74 114.95,106.74 123.58,115.37 123.58,126.93 126.84,130.19 126.84,133.42 129.73,136.31 133.35,136.31 v3(133.47,136.43)
  BOTTOM w0.114: R1025.1 133.41,136.48 v3(133.47,136.43)
SD_PWRCTL_CH: length 7.3
  TOP w0.114: CPU1.BA23 58.7,133.6 58.7,133.47 58.74,133.43 58.74,131.17 61.72,128.19 TP55.1
SD_WP: length 140.1
  TOP w0.114: v1(130.46,155.88) 130.47,155.88 130.48,155.87 CRS1.10 ; CPU1.BA20 56.92,134.02 56.92,131.65 60.06,128.51 60.06,123.39 77.81,105.63 92.38,105.63 94.33,103.68 117.03,103.68 126.64,113.29 126.64,125.66 129.97,128.99 v3(129.97,131.75)
  BOTTOM w0.114: EC326.1 v1(130.46,155.88) 129.65,155.88 v2(129.44,155.68) 128.09,154.32 128.09,133.63 v3(129.97,131.75)
SENSE_A: length 3.4
  TOP w0.203: AUDIO1.13 v2(122.97,29.14) 123.57,29.14 R172.1
SERIRQ_N: length 86.2
  TOP w0.114: v3(62.33,136.23) 62.28,136.18 62.28,136.18 CPU1.AV29 ; v3(70.72,110.39) 67.63,110.39 R562.1 ; v3(70.89,100.15) 74.42,100.15 74.78,99.78 81.78,99.78 v3(86.97,94.59)
  BOTTOM w0.114: v3(62.33,136.23) 62.76,135.8 62.76,134.92 63.89,133.8 63.89,132.4 68.61,127.69 68.61,126.49 70.43,124.66 v2(70.43,123.9) 70.43,110.68 v3(70.72,110.39) 70.31,109.97 70.31,100.74 v3(70.89,100.15) ; U6503.14 72.29,81.71 72.29,82.43 72.94,83.08 77.11,83.08 77.31,83.28 U31.39 78.25,84.29 86.97,93.01 v3(86.97,94.59)
SIO_3VSB: length 6.5
  TOP w0.114: v3(70.84,83.46) v2(70.84,85.67) 71.09,85.93 R6540.1 R6541.1
  BOTTOM w0.114: v3(70.84,83.46) 71.09,83.22 U6503.11
SIO_AGND: length 379
  TOP w0.305: v3(120.22,145.99) 120.19,146.02 RT2.2 ; v3(137.72,154.13) 137.72,154.59 137.73,154.59 137.73,157.46 128.92,166.27 128.92,170.21 123.56,175.57 v3(123.56,179.93) ; RT1.2 61.77,183.62 62.13,183.26 v3(71.91,183.26) ; v3(81.71,78.41) v2(81.71,76.45) 81.71,75.79 77.24,71.31 73.45,71.31 71.68,69.55 C469.2
  TOP w0.381: R503.2 C472.2 C471.2 R500.2 59.1,73.41 57.97,72.28 R521.2 57.97,70.5 C475.2 C681.2 57.97,68.53 R522.2 58.01,68.49 C474.2 ; v3(65.53,67.46) 66.03,67.96 72.34,67.96 73.98,69.6 v2(75.95,69.6) 77.8,69.6 79.42,71.21 82.31,71.21 84.02,72.92 v3(84.2,72.92) ; C469.2 65.9,70.29 v3(66.07,70.46) 66.07,70.73 C479.2
  TOP w0.508: R514.2 63.02,69.68 C468.2 ; R514.2 C473.2 59.41,68.77 C474.2 ; R514.2 63.82,68.77 65,67.59 65.41,67.59 v3(65.53,67.46)
  BOTTOM w0.203: U6503.44 68.69,72.32 68.35,71.98 68.18,71.98 66.65,70.46 v3(66.07,70.46) 65.79,70.18 U31.86
  BOTTOM w0.305: v3(71.91,183.26) 73.31,184.66 78.53,184.66 85.95,192.07 107.58,192.07 119.72,179.93 v2(121.95,179.93) v3(123.56,179.93) ; v3(120.22,145.99) 121.21,145 121.21,106.27 99.01,84.07 92.81,84.07 87.3,78.56 81.86,78.56 v3(81.71,78.41) ; U31.86 65.79,67.72 v3(65.53,67.46) 65.29,67.71 U31.87 ; v3(84.2,72.92) 88.6,72.92 95.96,80.29 100.52,80.29 121.7,101.47 130.12,101.47 135.23,106.58 135.23,109.14 136.09,110.01 136.09,129.86 137.72,131.48 v3(137.72,154.13)
SIO_AMD SVID_EN: length 5.1
  BOTTOM w0.114: U31.29 71.79,86.7 72.34,87.25 v2(72.34,88.42) R542.1
SIO_ATXPG: length 15.9
  BOTTOM w0.114: U6503.6 69.09,82.59 68.6,83.08 68.02,83.08 66.79,84.31 U31.19 66.79,86.15 65.29,87.64 R531.1 65.19,91.39 64.93,91.39 64.47,91.86 v2(64.47,93.32) 64.9,93.75 R536.2
SIO_AVCC3: length 10.5
  TOP w0.508: v3(58.24,67.42) 58.14,67.52 C476.1 57.39,67.15 C477.1 58.47,66.45 59.22,65.7 v2(62.08,65.7) L50.1
  BOTTOM w0.305: U31.99 59.29,67.87 58.98,67.56 58.39,67.56 v3(58.24,67.42)
SIO_BLEN: length 93.1
  TOP w0.114: 70.23,79.84 70.23,79.76 71.65,78.33 71.65,76.25 71.27,75.87 70.94,75.87 70.84,75.97 69.22,75.97 69.2,75.95 v3(69.08,75.95) 69.02,75.9 65.46,75.9 64.81,75.25 63.02,75.25 62.5,74.73 59.4,74.73 59.39,74.71 59.08,74.41 58.55,74.41 55.12,70.98 55.12,65.58 v2(54,64.47) 53.71,64.17 53.71,62.34 52.51,61.14 52.51,59.01 45.26,51.77 45.26,50.67 44.81,50.22 44.81,41.9 44.23,41.31 44.23,29.24 42.01,27.01 42.01,18.97 v3(40.84,17.81)
  BOTTOM w0.114: Q4802.D 39.85,16.14 R6532.1 40.36,17.12 40.84,17.6 v3(40.84,17.81) ; v3(69.08,75.95) 69.08,78.78 69.7,79.41 69.7,80.36 69.41,80.66 68.53,80.66 68.29,80.9 U6503.4
SIO_BLEN_SMI: length 29.9
  TOP w0.114: 70.23,80.73 69.82,80.73 v3(69.27,80.18) 69.24,80.2 69.24,85.27 v2(68.33,86.18) 68.33,86.97 v3(68.22,87.07)
  BOTTOM w0.114: v3(69.27,80.18) 68.56,80.18 67.89,80.86 U6503.3 ; Q4803.S 67.09,104.1 R6534.2 67.09,102.35 67.35,102.09 67.35,93.34 66.96,92.95 66.96,88.82 68.22,87.55 v3(68.22,87.07)
SIO_BOARD_ID1: length 18.3
  TOP w0.114: v3(62.13,79.2) 62.13,80.14 62.96,80.97 R510.1 63.01,80.99 64.29,82.27 v2(64.34,82.27) 64.57,82.5 v3(64.57,83.59)
  BOTTOM w0.114: R505.2 62.11,87.18 62.83,86.46 64.03,86.46 64.29,86.21 U31.14 64.29,83.87 v3(64.57,83.59) ; U6503.55 64.38,76.87 62.13,79.12 v3(62.13,79.2)
SIO_BOARD_ID2: length 5.4
  BOTTOM w0.114: U31.6 60.29,88 60.1,88.18 R509.1 60.1,89.42 v2(60.15,89.46) 60.69,90 R504.2
SIO_BOARD_ID3: length 5.7
  BOTTOM w0.114: U31.16 65.29,86.2 64.52,86.97 v2(64.52,87.64) R523.1 63.15,89 R520.2
SIO_CE_N: length 27.1
  TOP w0.114: v3(73.14,87.99) 76.43,87.99 v3(77.19,87.22)
  BOTTOM w0.114: v3(77.19,87.22) 77.48,87.51 77.48,90.01 77.21,90.27 v2(77.21,96.37) 77.21,97.91 79.02,99.72 79.02,101.85 79.67,102.51 U56.1 80.88,103.69 R548.1 ; v3(73.14,87.99) 73.14,87.49 72.29,86.64 U31.30
SIO_CLK_DB: length 5.4
  BOTTOM w0.114: RN15.2 81.61,77.82 80.95,77.16 TP65.1 80.17,77.28 U31.51
SIO_COPEN#: length 12.7
  BOTTOM w0.114: U6503.28 75.41,76.07 75.62,75.86 75.62,75.86 76.38,75.1 76.38,73.8 75.4,72.82 75.4,70.24 74.79,69.63 U31.68 74.79,67.42 75.28,66.93 v6(75.31,66.93) 75.43,66.93 R546.1
SIO_DAT_DB: length 5.3
  BOTTOM w0.114: RN15.1 81.67,77.17 TP66.1 81.17,76.66 79.6,76.66 79.48,76.78 U31.52
SIO_DEBUG_RX: length 15.5
  BOTTOM w0.114: U6503.60 64.54,78.86 62.87,80.54 59.38,80.54 58.15,81.78 U31.125 54.99,81.78 TP34.1 53.03,79.83 52.86,79.65 R512.1
SIO_DEBUG_TX: length 17.5
  BOTTOM w0.114: U6503.59 64.41,78.46 62.71,80.16 59.23,80.16 58.11,81.28 U31.124 55.02,81.28 54.74,81 54.74,80.77 53.52,79.55 TP33.1 53.51,78.58 R511.1 52.35,78.56 R6545.2
SIO_GP31: length 40.8
  TOP w0.114: R6546.2 65.06,113.17 R6547.2 65.61,112.23 65.61,111.66 68.12,109.15 v3(71.73,109.15) ; CPU1.AV31 63.2,135.8 v3(63.57,136.16)
  BOTTOM w0.114: v3(63.57,136.16) 64.02,135.71 64.02,134.46 64.46,134.02 64.46,132.92 69.55,127.84 v2(69.55,127.3) 69.55,126.95 71.73,124.77 v3(71.73,109.15)
SIO_GP45: length 46.7
  TOP w0.114: v3(63.53,136.93) 63.33,136.93 CPU1.AU31 ; R6548.2 63.99,113.16 R6549.2 63.47,112.35 63.47,111.53 64.85,110.16 65.48,110.16 68.22,107.42 v3(71.81,107.42)
  BOTTOM w0.114: v3(63.53,136.93) 63.53,136.87 64.25,136.15 64.25,134.6 64.84,134 64.84,132.94 65.08,132.7 65.37,132.7 70.35,127.73 70.35,127.19 v2(71.5,126.04) 72.17,125.37 72.17,107.77 v3(71.81,107.42)
SIO_HOLD#: length 6.1
  BOTTOM w0.114: v2(73.96,101.8) 74.53,101.24 U56.7 76.73,101.24 77.11,101.63 77.11,104.17 R551.1
SIO_JP2: length 13.1
  TOP w0.114: v3(57.51,80.8) v2(56.11,80.8) 56.11,80.79 55.92,80.61 R6559.2 55.92,78.79 R6560.1
  BOTTOM w0.114: v3(57.51,80.8) 58.61,79.71 62.35,79.71 64.39,77.66 U6503.57
SIO_K8PWR_EN: length 15.3
  BOTTOM w0.114: R513.1 52.83,80.77 TP35.1 54.34,82.28 U31.126 58.17,82.28 59.47,80.98 62.97,80.98 64.68,79.26 U6503.61
SIO_MAIN_VCC3: length 14.8
  TOP w0.254: v3(67.28,75.03) 67.64,74.68 R1031.1 67.96,73.47 R526.1 67.54,72.72 67.01,73.25 67.01,73.48 66.65,73.84 v2(65.2,73.84) v3(64.06,73.84)
  BOTTOM w0.203: U6503.53 66.63,76.07 67.28,75.41 v3(67.28,75.03)
  BOTTOM w0.254: U31.92 62.79,69.74 62.68,69.85 62.68,72.46 v3(64.06,73.84)
SIO_MEM_EVENT_L: length 58.3
  TOP w0.165: v3(73.03,93.93) 73.1,93.85 79.46,93.85 88.75,84.57 v3(88.75,77.29)
  BOTTOM w0.165: U31.54 87.24,75.78 v2(87.93,76.48) v3(88.75,77.29) ; v3(73.03,93.93) 72.57,94.39 72.57,100.53 71.58,101.52 71.58,104.47 74.04,106.93 74.04,111.81 R1.1
SIO_PCIRSTIN#: length 3.8
  TOP w0.114: R556.1 v3(58.14,86.83) v2(58.14,86)
  BOTTOM w0.114: v3(58.14,86.83) 58.79,86.18 U31.3
SIO_PSON_N: length 64.4
  TOP w0.114: v3(72.72,74.55) 73.23,74.04 Q98.G ; v3(46.97,70.29) 45.49,68.81 41.57,68.81 39.3,66.55 38.54,66.55 R6550.2 35.81,65.79 34.4,67.2 Q4807.G 33.46,67.63 R1015.1
  BOTTOM w0.114: v3(72.72,74.55) 72.69,74.51 U6503.34 72.69,71.64 70.79,69.75 U31.76 70.79,67.08 71.07,66.8 R527.2 70.85,65.8 70.18,65.13 70.18,61.95 68.81,60.58 66.6,60.58 65.7,59.68 61.84,59.68 v2(61.24,60.27) 60.71,60.81 54.18,60.81 46.97,68.01 v3(46.97,70.29)
SIO_PSON_N_D: length 5.8
  TOP w0.114: R1031.2 69.6,74.22 v2(69.6,75.03) Q98.D
SIO_PWNBTN_N: length 113.8
  TOP w0.114: v3(74.42,62.76) 74.42,61.58 v3(73.28,60.43) ; v3(42.29,75.92) 45.59,75.92 v3(45.85,75.67) ; v3(54.26,113.43) 54.4,113.57 54.4,121.4 53.13,122.67 53.13,123.82 52.1,124.84 51.92,124.84 51.58,125.18 51.58,125.57 51.68,125.67 51.68,130.08 50.45,131.31 50.45,133.37 50.35,133.47 CPU1.BA8
  BOTTOM w0.114: v3(54.26,113.43) 54.25,113.43 55.08,112.61 55.08,106.29 55.39,105.98 55.39,100.17 46.85,91.63 46.85,87.93 42.22,83.3 42.22,75.99 v3(42.29,75.92) ; v3(74.42,62.76) 74.03,63.15 R577.2 ; v3(45.85,75.67) 45.85,73.41 46.43,72.82 46.43,67.71 54.7,59.44 v2(59.33,59.44) 60.63,59.44 61.13,58.94 66.08,58.94 66.98,59.84 72.69,59.84 v3(73.28,60.43) 73.76,60.91 R576.1
SIO_SCK: length 12.6
  BOTTOM w0.114: R539.1 75.03,94.78 C487.1 74.27,96.51 v2(74.27,97.68) 74.27,99.26 74.98,99.97 U56.6 76.37,99.97 77.7,101.3 77.7,103.67 R552.1
SIO_SCK_R: length 14.3
  TOP w0.114: v3(75.84,90.2) 71.65,90.2 71.11,89.66 v3(69.79,89.66)
  BOTTOM w0.114: v3(69.79,89.66) 69.79,86.47 69.79,86.46 U31.25 ; v3(75.84,90.2) v2(75.84,91.97) 75.84,93.08 R539.2
SIO_SI: length 29.2
  TOP w0.114: v3(68.85,89.19) 71.16,89.19 71.69,89.72 76.63,89.72 v3(76.76,89.59)
  BOTTOM w0.114: v3(68.85,89.19) 69.29,88.75 U31.24 ; v3(76.76,89.59) 76.53,89.81 v2(76.53,93.9) 76.53,97.31 75.8,98.04 U56.5 76.58,98.7 78.33,100.46 78.33,103.24 R553.1
SIO_SMCLK0: length 86.4
  TOP w0.114: Q50.D 40.94,91.01 R609.2 v3(45.21,90.61)
  BOTTOM w0.114: v3(45.21,90.61) 45.21,89.13 40.21,84.13 40.21,74.29 v2(40.71,73.79) 43.21,71.3 43.21,65.02 45.85,62.38 45.95,62.38 46.2,62.12 46.2,62.03 51.16,57.07 51.18,57.07 51.52,56.73 67.23,56.73 67.94,57.44 74.29,57.44 79.49,62.64 79.49,70.89 79.1,71.28 U31.63
SIO_SMCLK0_1: length 2.8
  TOP w0.114: R595.2 35.04,90.02 v2(36.12,90.02) Q50.S
SIO_SMCLK0_2: length 3.2
  TOP w0.114: R607.2 35.87,91.99 v2(36.04,91.99) Q50.G
SIO_SMDAT0: length 78.3
  TOP w0.114: Q51.D 40.95,87.38 R608.2 42.46,87.76 43.41,86.82 43.47,86.82 43.48,86.8 v3(43.5,86.8)
  BOTTOM w0.114: U31.64 78.7,70.78 79.12,70.36 79.12,62.79 74.23,57.9 67.7,57.9 66.9,57.1 51.67,57.1 51.33,57.44 51.31,57.44 46.57,62.18 46.57,62.28 43.66,65.19 43.66,71.81 v2(42.86,72.61) 42.7,72.61 40.58,74.73 40.58,83.88 v3(43.5,86.8)
SIO_SMDAT0_1: length 3.1
  TOP w0.114: Q51.S 36.92,86.4 36.68,86.16 v2(36.17,86.16) 35.18,86.16 R596.2
SIO_SMDAT0_2: length 3.3
  TOP w0.114: R606.2 35.69,87.51 v2(36.27,88.09) 36.55,88.37 Q51.G
SIO_SO: length 34.4
  TOP w0.114: v3(78.46,90.5) 78.74,90.5 84.71,84.53 v3(84.71,84.48)
  BOTTOM w0.114: v3(84.71,84.48) 84.71,83.7 83.36,82.35 82.83,82.35 79.27,78.78 U31.48 ; v3(78.46,90.5) v2(78.46,93.19) 78.46,98.25 79.75,99.54 79.75,100.89 80.1,101.24 U56.2 81.73,101.24 81.99,101.5 81.99,103.67 R549.1
SIO_VCORE: length 10
  TOP w0.508: v3(71.83,83.38) 72.24,83.79 C484.1 73.96,83.72 C483.1 74.99,84.98 v2(74.96,85.01) 74.96,86.21 v3(75.49,86.74)
  BOTTOM w0.203: v3(71.83,83.38) 71.49,83.04 U6503.12
  BOTTOM w0.305: v3(75.49,86.74) 75.29,86.54 U31.36
SIO_VIN1: length 18.3
  TOP w0.114: v3(59.87,70.54) 58.92,69.59 C681.1
  BOTTOM w0.114: U6503.51 62.24,75.27 59.66,72.69 59.66,70.75 v3(59.87,70.54) 60.29,70.12 U31.97 60.29,67.15 59.46,66.32 58.5,66.32 58.44,66.27 v2(58.38,66.27) 57.32,66.27 R832.2
SIO_VIN2: length 18.1
  TOP w0.114: C475.1 R521.1 v3(60.1,71.5)
  BOTTOM w0.114: U6503.50 62.39,74.87 60.1,72.57 v3(60.1,71.5) 60.1,71.12 60.79,70.43 U31.96 60.79,67.01 v2(59.44,65.66) 58.77,64.99 R519.1
SIO_VIN3: length 8.6
  TOP w0.114: R500.1 C471.1 60.14,72.19 60.6,71.73 60.6,71.09 v3(61.29,70.41)
  BOTTOM w0.114: R499.1 61.29,66.16 v2(61.29,66.5) U31.95 v3(61.29,70.41)
SIO_VIN4: length 13.7
  TOP w0.114: v3(61.32,71.32) 61.03,71.61 C472.1 R503.1 62.51,73.04 62.51,73.41 v2(63.09,73.99) 63.14,73.99 63.91,73.22 66.31,73.22 v3(66.37,73.28) 66.37,73.05 67.85,71.57 R502.1
  BOTTOM w0.114: v3(66.37,73.28) 66.43,73.22 U6503.48 ; v3(61.32,71.32) 61.74,70.89 61.74,69.95 61.79,69.91 U31.94
SIO_VIN5: length 20.6
  TOP w0.114: C473.1 R514.1 63.18,67.88 v3(63.7,67.36)
  BOTTOM w0.114: R508.1 v2(62.64,62.25) 63.75,63.37 63.75,67.31 v3(63.7,67.36) 62.89,67.36 62.29,67.96 U31.93 62.29,69.69 62.11,69.87 62.11,72.88 63.7,74.47 U6503.49
SIO_VREF: length 14.5
  TOP w0.254: v2(66.67,71.78) 66.67,71.78 v3(65.99,72.47) 65.93,72.52 C479.1 65.1,72.58 RN20.1 64,72.11 63.89,72 63.53,72 63.35,72.18 RN20.2
  BOTTOM w0.203: U31.91 63.29,71.7 64.05,72.47 v3(65.99,72.47) 65.99,72.64 65.81,72.82 65.81,73.48 66.14,73.81 66.49,73.81 66.89,74.21 67.37,74.21 67.49,74.09 U6503.47
SIO_WP#: length 5.9
  BOTTOM w0.114: R550.1 82.55,101.24 v2(82.8,100.99) 82.8,100.53 82.24,99.97 U56.3
SIO_WRST#: length 6.2
  TOP w0.114: C488.1 79.98,78.31 v3(80.57,78.89) v2(80.57,79.71) 81.28,80.42 R559.2
  BOTTOM w0.114: U31.50 79.46,77.78 v3(80.57,78.89)
SLP_S3_N: length 208.4
  TOP w0.114: v3(72.67,75.72) 72.67,76.62 Q99.G ; v1(53.16,119.84) 52.55,119.84 48.97,123.42 47.15,123.42 46.05,124.52 46.05,125.59 45.89,125.76 45.89,128.39 46.58,129.08 46.58,132.03 47.2,132.65 47.2,133.01 47.19,133.02 47.19,133.99 CPU1.AY3 ; v3(86.31,104.04) 76.55,104.04 76.02,104.57 72.42,104.57 71.45,105.54 v3(59.99,105.54) ; D2.1 47.35,96.71 47.8,96.27 v3(56.67,96.27) ; R6562.1 38.87,69.16 40.04,69.16 40.35,69.47 44.78,69.47 v3(45.16,69.85)
  BOTTOM w0.114: v3(86.31,104.04) 86.38,104.11 99.31,104.11 102.13,106.94 102.13,111.28 104.72,113.87 105.05,113.87 105.23,114.04 RN21.1 ; v3(72.67,75.72) 73.12,75.27 U6503.30 75.17,75.27 75.31,75.12 75.32,75.12 75.64,74.8 75.64,74.1 75.31,73.77 74.66,73.12 74.66,71.36 73.29,69.99 U31.71 73.29,67.07 74.42,65.94 74.42,64.44 74.86,64 74.86,62.54 74.74,62.42 74.74,60.76 74.37,60.39 73.09,59.11 67.31,59.11 66.41,58.2 53.99,58.2 45.16,67.03 v3(45.16,69.85) 45.16,72.4 44.3,73.27 44.3,73.99 44.29,73.99 44.29,76.09 v2(45.46,77.26) 46.3,78.11 46.3,82.69 50.39,86.78 50.39,89.99 v3(56.67,96.27) 56.67,96.41 59.65,99.39 59.65,105.17 59.99,105.5 v3(59.99,105.54) 59.99,113.72 R79.1 53.87,119.84 v1(53.16,119.84)
SLP_S5_N: length 183.2
  TOP w0.114: CPU1.BA5 48.7,133.43 48.61,133.34 48.61,132.46 48.08,131.93 48.08,128.83 R80.1 48.13,127.75 48.13,127.03 47.8,126.71 47.8,125.63 v1(48.03,125.4) ; v3(71.3,53) R439.1 70.69,53.48 70.69,56.2 68.12,58.76 66.35,58.76 v3(65,60.12) ; v3(45.77,78.41) v3(47.27,78.41) ; v3(59.28,105.98) 71.53,105.98 72.48,105.03 76.08,105.03 76.7,104.41 83.38,104.41 v3(83.49,104.52)
  BOTTOM w0.114: RN21.2 104.58,114.3 101.75,111.48 101.75,107.08 99.17,104.5 86.08,104.5 85.59,104.01 84,104.01 v3(83.49,104.52) ; v3(47.27,78.41) 47.12,78.26 47.12,77.64 46.56,77.08 46.56,73.21 46.8,72.97 46.8,71.14 47.56,70.39 47.56,67.95 54.29,61.22 63.89,61.22 v3(65,60.12) 65.61,60.12 66.48,60.99 68.69,60.99 69.81,62.1 69.81,64.8 R541.2 ; R440.1 v2(76.55,53.96) 76.2,53.61 72.43,53.61 71.82,53 v3(71.3,53) ; v1(48.03,125.4) 48.54,124.89 48.54,123.8 53.37,118.97 54.2,118.97 59.28,113.89 v3(59.28,105.98) 59.28,99.54 50.01,90.27 50.01,86.92 45.77,82.68 v3(45.77,78.41)
SLP_S5_N_R: length 8.4
  BOTTOM w0.114: U6503.35 72.29,71.78 70.29,69.78 U31.77 v2(70.29,66.85) 69.55,66.12 R541.1
SMB0_CLK: length 299
  TOP w0.114: v3(32.62,96.13) 32.62,95.82 33.19,95.24 67.27,95.24 67.54,94.96 69.18,94.96 v3(69.62,95.4) ; DIMM1.202 102.32,112.95 102.01,112.64 102.01,112.21 102.47,111.75 103.03,111.75 104.52,110.26 104.52,108.66 103.82,107.96 96.21,107.96 94.25,109.92 79.59,109.92 67.77,121.74 v3(67.77,122.05) ; v3(48.02,61.87) 36.58,50.42 35.6,50.42 v3(32.32,47.14) 32.32,47.04 23.54,38.26 23.54,25.46 26.66,22.34 27.48,22.34 29.08,20.75 29.08,14.4 28.52,13.84 v3(28.52,13.51) ; v3(60.25,137.02) 59.83,136.6 CPU1.AU25
  BOTTOM w0.114: v3(32.32,47.14) 31.86,47.14 v2(27.86,51.13) 27.72,51.27 L2901.4 L2901.3 v2(27.72,70.51) 27.43,70.81 27.43,86.89 33.79,93.25 33.79,95.89 33.53,96.15 32.64,96.15 v3(32.62,96.13) 32.62,96.02 31.14,94.54 R593.2 ; C179.1 28.09,12.57 28.52,13 v3(28.52,13.51) 28.52,13.82 27.69,14.65 U59.6 ; v3(60.25,137.02) 60.25,136.82 61.14,135.93 61.14,135.46 63.22,133.38 63.22,132.29 66.85,128.66 RN5.4 67.29,127.17 67.81,126.65 67.81,122.09 v3(67.77,122.05) 67.77,121.82 69.38,120.21 69.38,95.64 v3(69.62,95.4) ; v3(48.02,61.87) 52.06,57.84 66.57,57.84 67.44,58.7 73.99,58.7 78.39,63.09 78.39,65.62 78.12,65.89 77.65,65.89 77.37,66.16 RN12.3 77.37,67.03 76.71,67.69 76.02,67.69 75.79,67.92 U31.66
SMB0_DATA: length 296.5
  TOP w0.114: v3(67.28,122.66) 67.78,122.66 68.33,122.11 68.33,121.7 79.74,110.29 94.41,110.29 96.35,108.34 103.52,108.34 104.14,108.97 104.14,110.11 102.87,111.38 102.39,111.38 101.7,112.07 101.7,112.9 102.35,113.55 DIMM1.200 ; v3(27.71,13.77) 28.71,14.77 28.71,20.59 27.33,21.97 26.51,21.97 23.17,25.31 23.17,38.41 31.33,46.57 v3(31.33,46.67) 31.33,46.77 38.54,53.98 39.6,53.98 47.42,61.8 v3(47.42,62.31) ; v3(33.35,95.71) 33.38,95.71 33.46,95.62 67.62,95.62 67.84,95.4 v3(68.91,95.4) ; v3(60.24,136.16) 60.06,136.16 CPU1.AV25
  BOTTOM w0.114: v3(31.33,46.67) 31.33,46.72 v2(28.85,49.2) 27.28,50.77 27.28,64.42 27.04,64.66 L2901.1 L2901.2 v2(27.04,68.4) 27.04,87.03 33.35,93.34 v3(33.35,95.71) 32.83,95.71 32.18,95.06 R594.2 ; C180.1 27.23,12.7 27.71,13.18 v3(27.71,13.77) 27.71,13.82 27.2,14.33 U59.7 ; v3(68.91,95.4) 68.92,95.4 68.99,95.47 68.99,120.06 67.28,121.77 v3(67.28,122.66) 67.44,122.82 67.44,126.2 67.05,126.59 66.4,126.59 66.2,126.79 RN5.3 66.2,129.01 61.54,133.66 61.54,134.54 60.83,135.25 60.83,135.71 60.39,136.16 v3(60.24,136.16) ; U31.65 76.5,68.82 76.81,68.5 76.81,68.15 78.03,66.93 78.03,66.42 RN12.4 78.37,66.41 78.75,66.03 78.75,62.94 74.14,58.33 67.6,58.33 66.74,57.47 51.82,57.47 51.48,57.81 51.46,57.81 47.42,61.85 v3(47.42,62.31)
SMB1_CLK: length 142.1
  TOP w0.114: v3(34.42,110.62) 34.96,110.62 35.56,111.21 52.66,111.21 54.76,113.32 54.76,121.55 53.5,122.82 53.5,124.79 52.98,125.3 52.98,127.42 RN3.4 53.63,129.91 51.37,132.17 51.37,133.19 51.58,133.4 51.58,133.72 52,134.14 CPU1.AY11 ; v3(33.81,47.29) 33.14,47.29 23.91,38.06 23.91,26.73 R478.2
  BOTTOM w0.114: v3(34.42,110.62) 34.86,110.18 34.86,109.1 34.79,109.04 34.79,97.84 34.54,97.59 34.54,92.93 28.16,86.55 28.16,73.36 28.96,72.56 v2(28.96,55.63) 28.96,52.14 v3(33.81,47.29)
SMB1_DATA: length 140.9
  TOP w0.114: CPU1.BA11 52,133.52 51.58,133.1 51.58,132.26 54.2,129.64 54.2,128.14 RN3.3 54.91,127.43 54.91,125.53 53.86,124.48 53.86,122.97 55.13,121.7 55.13,113.17 52.81,110.85 35.71,110.85 34.72,109.86 v3(34.42,109.86) ; R479.2 24.28,27.45 24.28,37.81 v3(33.21,46.75)
  BOTTOM w0.114: v3(33.21,46.75) 33.2,46.76 33.2,47.18 28.42,51.95 28.42,72.26 v2(28.19,72.5) 27.79,72.89 27.79,86.7 34.16,93.07 34.16,97.87 34.42,98.12 v3(34.42,109.86)
SNB: length 2.9
  BOTTOM w0.635: C246.1 51.46,12.8 v2(51.46,11.43) R350.2
SPEED_100*_L: length 5.8
  BOTTOM w0.203: LAN1.26 115.3,63.43 116.66,64.8 118.87,64.8 TP68.1
SPI_CLK: length 94.1
  TOP w0.114: v3(50.29,136.18) 49.87,136.6 CPU1.AU7 ; v3(42.67,78.05) v2(30.02,78.05) 25.27,78.05 23.8,76.58 C430.1 R431.2
  BOTTOM w0.114: v3(50.29,136.18) 50.29,135.95 49.89,135.55 49.89,134.63 48.44,133.17 48.44,132.77 45.27,129.6 45.27,125.46 45.32,125.41 45.32,123.01 51.99,116.33 53.13,116.33 56.47,112.99 56.47,100.73 47.24,91.5 47.24,87.8 42.59,83.15 42.59,78.14 v3(42.67,78.05)
SPI_CLK_R: length 11.9
  TOP w0.114: SPI1.6 11.63,72.77 13.36,74.5 20.26,74.5 v2(20.35,74.59) R431.1
SPI_CS0_N: length 105.7
  TOP w0.114: SPI1.1 v3(14.17,75.88) 17.37,79.07 20.14,79.07 21.13,80.06 v2(38.1,80.06) v3(44.81,80.06) ; CPU1.AW9 50.9,134.84 50.59,134.53 50.59,134.27 50.66,134.2 50.66,133.9 50.59,133.83 50.59,133.57 50.8,133.36 50.8,131.65 51.15,131.3 v1(51.15,131.27)
  BOTTOM w0.114: v1(51.15,131.27) 51.15,129.43 50.47,128.75 50.47,126.86 49.48,125.86 47.84,125.86 47.52,125.54 47.52,123.78 53.09,118.21 53.86,118.21 58.31,113.76 58.31,99.69 49.2,90.58 49.2,87.15 44.81,82.76 v3(44.81,80.06) ; v3(14.17,75.88) RN6.2
SPI_DATAIN: length 92.2
  TOP w0.114: R430.1 22.04,80.72 v2(41.2,80.72) v3(43.03,80.72) ; CPU1.AR7 49.9,137.68 v3(50.07,137.85)
  BOTTOM w0.114: v3(50.07,137.85) 50.03,137.81 50.03,136.93 50.29,136.67 50.39,136.67 50.71,136.35 50.71,135.63 50.72,135.62 50.72,135.15 48.65,133.08 48.65,132.63 45.64,129.61 45.64,125.61 45.69,125.56 45.69,123.16 52.15,116.7 53.29,116.7 56.84,113.15 56.84,100.58 47.62,91.36 47.62,87.66 43.03,83.06 v3(43.03,80.72)
SPI_DATAOUT: length 96.2
  TOP w0.114: R433.2 C429.1 24,77.52 25.08,78.6 v2(39.85,78.6) v3(44.45,78.6) ; v3(51.4,137.44) 51.96,137.44 CPU1.AR11
  BOTTOM w0.114: v3(51.4,137.44) 52.19,136.65 52.19,135.08 51.28,134.17 51.28,132.08 50.7,131.5 50.7,129.48 50.2,128.98 50.2,127.11 49.32,126.23 47.69,126.23 47.15,125.69 47.15,123.63 52.95,117.83 53.72,117.83 57.94,113.6 57.94,99.91 48.77,90.73 48.77,87.24 44.37,82.84 44.37,78.68 v3(44.45,78.6)
SPI_SI_R: length 15
  TOP w0.114: R433.1 20.93,78.51 v2(20.23,77.81) 20.02,77.6 17.4,77.6 14.71,74.9 12.93,74.9 10.36,72.34 SPI1.5
SPI_SO: length 10.5
  TOP w0.114: R430.2 20.44,80.01 v2(20.14,80.01) 19.13,80.01 18.3,80.84 C428.1 13.72,80.85 12.9,80.04 U30.2
SPI_SW: length 8.7
  TOP w0.114: v3(55.84,135.57) 55.69,135.57 55.46,135.8 CPU1.AV17
  BOTTOM w0.114: R128.2 58.1,129.3 56.4,131 R134.1 55.52,131.53 55.52,134.06 v2(55.8,134.34) 55.8,135.53 v3(55.84,135.57)
SPI_WP#: length 93.1
  TOP w0.114: v3(43.51,79.27) v2(34.95,79.27) 20.95,79.27 20.1,78.42 17.54,78.42 14.49,75.38 v3(13.18,75.38) 11.63,76.93 SPI1.3 ; v3(48.13,91.24) 48.23,91.14 R432.2
  BOTTOM w0.114: R105.2 46.23,123.14 52.3,117.07 53.44,117.07 57.21,113.3 57.21,100.31 v3(48.13,91.24) 48.01,91.11 48.01,87.52 43.51,83.02 v3(43.51,79.27) ; RN6.3 v3(13.18,75.38)
SPI_WP#_R: length 3.1
  TOP w0.114: v2(47.29,89.57) R432.1 48.82,89.57 Q39.D
SPI_WP_R_N: length 24.9
  TOP w0.114: v3(70.92,90.35) 69.12,90.35 68.77,89.99 54.91,89.99 v2(54.64,90.26) R524.1 52.39,90.26 Q39.G
  BOTTOM w0.114: v3(70.92,90.35) 71.29,89.98 U31.28
SPKR: length 161.7
  TOP w0.254: v1(73.44,117.79) 69.47,121.76 v2(69.47,122.02) 69.47,123.07 65.18,127.36 65.18,128.42 62.38,131.22 62.03,131.22 61.06,132.18 61.06,133.44 CPU1.BA27 ; R360.2 123.04,23.57 122.33,22.86 119.78,22.86 117.39,20.47 115.31,20.47 106.48,20.47 106.23,20.73 100,26.96 100,42.79 98.32,44.46 93.59,44.46 89.32,48.73 89.07,48.98 89.07,62.46 89.06,62.46 89.06,63.39 89.07,63.39 89.07,66.42 90.98,68.34 90.98,86.05 80.31,96.72 72.09,96.72 v1(72.06,96.7)
  BOTTOM w0.254: v1(72.06,96.7) 72.06,100.38 71.11,101.33 71.11,104.9 73.44,107.22 v1(73.44,117.79)
SPKR_L+: length 27.9
  TOP w0.203: AUDIO1.40 113.91,32.34 113.82,32.44
  TOP w0.508: v1(107.54,12.06) 107.59,12.01 L7.1 ; v5(113.03,32.64) 113.62,32.64 113.82,32.44
  BOTTOM w0.508: v5(113.03,32.64) 113.58,32.64 114.71,31.52 114.71,30.25 112.5,28.04 v2(112.5,21.87) 112.5,17.26 107.54,12.3 v1(107.54,12.06)
SPKR_L-: length 27.6
  TOP w0.203: 113.46,31.72 113.81,31.72 114.03,31.94 AUDIO1.41
  TOP w0.508: L9.1 107.45,10.64 106.6,11.5 v1(106.6,11.57) ; 113.46,31.72 v5(113.03,31.72)
  BOTTOM w0.508: v5(113.03,31.72) 113.03,30.19 111.38,28.54 v2(111.38,23.95) 111.38,17.61 106.52,12.75 106.52,11.65 v1(106.6,11.57)
SPKR_OUT_L+_C: length 11
  TOP w0.406: SPK1.1 117.5,9.93 117.2,10.24
  TOP w0.508: 117.2,10.24 116.59,10.85 v2(113.89,10.85) 112.32,10.85 112,10.53 C237.1 108.89,10.53 L7.2
SPKR_OUT_L-_C: length 9.3
  TOP w0.406: SPK1.2 116.5,9.33 116,9.83
  TOP w0.508: 116,9.83 112.95,9.83 v2(112.52,9.4) 112.33,9.21 C243.1 109.04,9.21 L9.2
SPKR_OUT_R+_C: length 12
  TOP w0.406: 115.52,6.55 115.52,6.97 115.5,6.99 SPK1.3
  TOP w0.508: 115.52,6.55 115.52,4.34 114.38,3.2 v2(113.13,3.2) 112.03,3.2 111.21,4.02 111.21,4.26 110.35,5.12 C245.1 108.72,5.12 L11.2
SPKR_OUT_R-_C: length 10.4
  TOP w0.406: 114.5,6.56 SPK1.4
  TOP w0.508: L13.2 108.95,6.26 C247.1 110.64,6.26 v2(111.31,5.6) 112.23,4.68 112.23,4.44 112.45,4.22 113.96,4.22 114.5,4.76 114.5,6.56
SPKR_R+: length 33.8
  TOP w0.203: AUDIO1.45 114.19,30.34 113.83,29.98 113.03,29.98
  TOP w0.508: v5(111.63,30.35) 112.01,29.98 113.03,29.98 ; v1(104.14,9.58) 106.3,7.42 106.3,6 L11.1
  BOTTOM w0.508: v1(104.14,9.58) 104.83,9.58 105.46,10.21 105.46,13.17 110.36,18.08 110.36,26.67 v2(110.24,26.8) 110.36,26.92 110.36,29.04 111.51,30.19 111.51,30.23 v5(111.63,30.35)
SPKR_R-: length 33.1
  TOP w0.203: 113.23,30.84 113.33,30.73 114.26,30.73 114.27,30.74 AUDIO1.44
  TOP w0.508: v5(111.76,31.62) 112.01,31.62 112.79,30.84 113.23,30.84 ; v1(104.67,10.78) 104.67,10.6 107.33,7.95 107.33,6.64 L13.1
  BOTTOM w0.508: v5(111.76,31.62) 111.47,31.62 110.49,30.65 110.49,30.61 v2(109.35,29.46) 109.35,18.61 104.44,13.7 104.44,11.01 v1(104.67,10.78)
SST_HOLDJ_1: length 100.5
  TOP w0.114: SPI1.7 12.9,73.1 v3(13.84,74.04) 20.83,74.04 21.64,74.85 22.66,74.85 25.22,77.42 v2(41.58,77.42) v3(44,77.42)
  BOTTOM w0.114: v3(13.84,74.04) 13.16,74.73 RN6.4 ; R104.2 47.52,130.45 46.55,129.48 46.55,126.75 46.74,126.57 46.74,123.52 52.82,117.44 53.59,117.44 57.58,113.45 57.58,100.06 48.39,90.87 48.39,87.38 44,82.99 v3(44,77.42)
SST_HOLDJ_1_R: length 8.3
  TOP w0.114: v3(51.44,136.82) 51.45,136.82 51.46,136.83 51.77,136.83 CPU1.AU11
  BOTTOM w0.114: R104.1 48.59,131.19 v2(48.87,131.47) 49.31,131.91 49.31,133.12 50.71,134.53 50.73,134.53 51.15,134.95 51.15,135.8 51.14,135.8 51.14,136.56 51.4,136.82 v3(51.44,136.82)
SSTCMP: length 9.5
  BOTTOM w0.254: R322.1 17.95,18.34 Q101.D 19,17.73 v2(20.4,16.33) 22.86,16.33 23.13,16.6 U59.11
SSTCMP_1: length 3
  BOTTOM w0.254: R322.2 18.83,19.55 19.35,19.02 v2(19.91,19.02) 20.02,19.13 C177.1
STATUS: length 3.6
  BOTTOM w0.254: U59.8 v2(26.7,13.23) 26.7,13.11 26.26,12.67 R345.1
SUSLED_1: length 3.7
  TOP w0.381: Q52.1 134.87,3.74 135.27,3.34 v4(136.07,3.34) 137.29,3.34 R619.1
SUSLED_2: length 188.8
  TOP w0.381: v3(47.32,17.55) 47.24,17.63 46.66,17.63 45.29,19 45.29,25.55 45.83,26.09 45.83,31.41 45.48,31.76 45.48,40.79 46.27,41.58 v3(46.27,46.09) ; v3(37.44,56.59) 37.52,56.67 37.52,57.53 46,66.01 46,66.09 46.44,66.54 46.45,66.54 51.42,71.5 51.42,71.51 51.44,71.53 51.44,71.54 51.44,72.17 51.44,73.02 58.37,79.96 Q4804.D ; R620.1 136.55,4.53 R619.2 137.59,5.38 137.19,5.79 137.19,7.51 R616.2 R617.2 137.07,10.07 v3(137.44,10.44)
  BOTTOM w0.381: v3(47.32,17.55) v2(48.16,16.71) 48.45,16.42 65.29,16.42 68.19,13.52 68.19,9.79 76.16,1.83 132.67,1.83 137.44,6.6 v3(137.44,10.44) ; v3(46.27,46.09) 37.52,54.84 37.52,56.52 v3(37.44,56.59)
SUSLED_CON: length 11.2
  TOP w0.305: PWRBT1.5 125.75,11.12 126.03,11.4
  TOP w0.381: 126.03,11.4 128.17,11.4 v2(128.78,10.79) 129.81,9.77 R624.1 EC703.1 132.39,9.74 U39.3 132.56,7.9 L55.1
SUSLED_CON_P1: length 4.5
  TOP w0.381: v4(132.51,2.62) 132.51,4.48 Q52.3 131.32,4.72 R621.1
SUSLED_N: length 26.7
  TOP w0.381: Q4804.S 57.39,82.09 R6535.2 57.39,84.01 57.84,84.45 60.63,84.45 61.46,85.28 R1013.1 v2(64.74,85.28) 66.45,85.28 R1012.1 66.54,85.37 67.41,85.37 68.69,84.09 68.69,79.95 69.58,79.06 70.19,79.06 71.15,78.1 v3(71.15,76.38)
  BOTTOM w0.203: 71.12,74.98 71.12,74.57 71.49,74.21 U6503.37
  BOTTOM w0.381: 71.12,74.98 71.12,76.35 v3(71.15,76.38)
SUSLED_R_N_1: length 4.7
  TOP w0.381: v3(66.52,87.05) R1012.2
  BOTTOM w0.305: U31.22 68.29,86.22 67.46,87.05 v3(66.52,87.05)
  BOTTOM w0.381: v3(66.52,87.05) v2(66.52,87.91)
SUSLED_R_N_PWM: length 3.5
  TOP w0.381: v3(62.79,83.59) R1013.2 v2(61.75,84.39)
  BOTTOM w0.305: U31.11 v3(62.79,83.59)
SVC_VDD: length 53.5
  TOP w0.114: v3(63.81,164.92) 63.81,168.59 60.73,171.66 37.89,171.66 v3(36.7,172.85) ; PU4401.3 33.52,185.57 32.94,185 32.94,180.99 33.78,180.14 33.78,179.42 35.26,177.94 v3(35.26,177.93)
  BOTTOM w0.114: v3(36.7,172.85) 35.26,174.29 v2(35.26,176.1) v3(35.26,177.93) ; v3(63.81,164.92) 63.81,164.08 63.28,163.55 63.28,162.91 R60.1 64.77,161.5 R50.2 64.77,160.47 R54.2
SVD_VDD: length 57.7
  TOP w0.114: PU4401.5 34.32,184.56 34.31,184.55 34.31,180.68 35.28,179.71 v3(35.28,178.82) ; v3(64.83,165.03) 64.83,168.08 60.89,172.03 38.41,172.03 v3(37.59,172.85)
  BOTTOM w0.114: v3(64.83,165.03) 65.33,164.54 65.33,162.92 R61.1 65.43,161.86 65.43,161.08 R51.2 66.31,159.63 65.58,158.9 64.69,158.9 63.49,157.7 R55.2 ; v3(35.28,178.82) 35.99,178.1 35.99,174.45 v2(36.16,174.28) v3(37.59,172.85)
SVT_VDD: length 55.7
  TOP w0.114: v3(36.17,180.59) 36.18,180.61 36.18,181.4 35.97,181.61 35.97,184.84 35.12,185.7 PU4401.7 ; v3(35.64,172.94) 36,173.3 37.76,173.3 38.67,172.4 61.04,172.4 61.25,172.18 65.84,167.59 v3(65.84,164.87)
  BOTTOM w0.114: v3(65.84,164.87) 65.84,164.05 66.48,163.41 66.48,162.91 67.21,162.18 R49.2 67.6,161.08 R53.2 ; v3(35.64,172.94) 35.59,172.94 34.72,173.82 34.72,179.14 v2(35.5,179.93) v3(36.17,180.59)
SW_ON_N_SIO: length 13.6
  BOTTOM w0.114: U6503.31 75.05,74.87 75.16,74.75 75.17,74.75 75.27,74.64 75.27,74.26 74.29,73.28 74.29,71.53 72.79,70.02 U31.72 v2(72.79,66.85) 72.79,66.83 72.59,66.62 R535.2 R517.2 R577.1
SYS_3VSB: length 18.8
  TOP w0.114: v3(73.79,67.36) 74.04,67.36 v2(74.55,67.87) 74.75,68.07 77.38,68.07 v3(77.47,68.16)
  BOTTOM w0.114: U31.70 73.79,67.36 v3(73.79,67.36) 73.79,67.09 75.01,65.88 R544.1 ; v3(77.47,68.16) 77.47,69.23 75.77,70.93 75.77,72.67 76.8,73.69 76.8,75.2 76.75,75.25 76.75,75.25 75.78,76.22 75.77,76.22 75.53,76.47 U6503.27
SYS_ID2: length 11.4
  TOP w0.114: v3(58.01,136.29) 58,136.3 57.8,136.3 CPU1.AU21
  BOTTOM w0.114: R69.2 R73.1 61.61,128.74 v2(60.35,130) 60.35,133.17 58.01,135.51 v3(58.01,136.29)
SYS_ID3: length 9.1
  TOP w0.114: R70.2 64.18,127.74 R74.1 62.2,130.42 v2(62.2,130.43) 62.2,130.64 60.67,132.17 60.67,133.16 60.49,133.34 60.49,133.83 60.56,133.9 60.56,134.18 60.25,134.49 CPU1.AY26
SYS_PWRGD: length 94.9
  TOP w0.114: v3(63.17,104.9) 63.13,104.86 43.6,104.86 41.61,102.88 D3.3 41.61,100.88 43.12,99.38 R92.2 43.63,97.7 D2.3 ; v3(56.87,139.37) 56.5,139 CPU1.AM19 56.07,139 55.58,139.5 54.31,139.5 53.87,139.94 53.87,140.13 53.44,140.56 52.4,140.56 51.62,141.34 48.95,141.34 48.87,141.43 48.53,141.43 48.45,141.34 47.52,141.34 47.4,141.46 47.1,141.46 47.03,141.39 46.77,141.39 46.7,141.46 46.41,141.46 46.34,141.39 45.04,141.39 44.64,141.79 39.72,141.79 39.05,141.12 39.05,141.07 39.05,139.57 37.63,138.15 35.99,138.15 R65.1
  BOTTOM w0.114: v3(56.87,139.37) 55.55,138.05 55.55,137.47 55.68,137.34 55.68,137.32 55.7,137.3 55.7,136.98 56.46,136.22 56.46,135.88 56.51,135.83 56.51,135.11 56.9,134.72 56.9,131.37 59.84,128.42 59.84,126.77 59.66,126.59 59.66,125.15 59.69,125.12 61.06,123.74 61.06,121 v2(61.53,120.54) 63.17,118.9 63.17,116.73 64.12,115.78 64.12,107 63.17,106.06 v3(63.17,104.9)
SYS_PWRGD_HV: length 6.9
  TOP w0.114: R86.2 34.79,99.4 v2(34.8,99.39) 35.85,100.45 Q4801.G 36.22,102.77 37.11,101.88 Q1.D
SYS_PWRGD_HV_1: length 5.8
  TOP w0.114: R87.1 v2(36.17,98.42) 37.5,98.42 Q2.C 37.61,99 Q1.G
SYS_PWRGD_HV_2: length 3.6
  TOP w0.114: R92.1 43.11,97.34 C32.1 42.09,97.32 v2(40.94,97.32) Q2.B
TEST18_M: length 60.6
  TOP w0.114: R488.2 95.72,191.53 97.24,190.01 97.24,186.93 94.25,183.95 87.07,183.95 74.47,171.35 v2(73.66,171.35) 72.72,171.35 69.52,168.15 R26.1 69.52,167.49 69.21,167.18 69.21,164.03 66.54,161.37 66.06,161.37 61.11,156.42 61.11,156.17 61.04,156.1 61.04,155.82 61.35,155.51 CPU1.B28
TEST19_M: length 58.8
  TOP w0.114: R487.2 96.84,191.2 97.61,190.43 97.61,186.78 94.12,183.29 87.07,183.29 74.04,170.26 73.43,170.26 v2(72.95,169.78) R27.1 71.88,168.19 70.51,166.82 70.51,165.54 69.58,164.61 69.58,163.89 66.85,161.15 66.15,161.15 61.35,156.35 CPU1.A28
TEST_MODE: length 4.2
  TOP w0.114: R586.1 v2(24.3,98.55) 24.3,99.3 v3(24.4,99.4)
  BOTTOM w0.114: v3(24.4,99.4) 24.88,98.92 24.88,98.2 24.75,98.07 U38.2
THERMAL_SHUT#: length 70.5
  TOP w0.114: v3(47.09,93.27) 53.54,93.27 55.7,91.11 59.47,91.11 60.12,90.46 R538.1 ; v3(53.56,113.55) 54.03,114.02 54.03,120.24 53.54,120.73 52.71,120.73 49.28,124.16 49.28,124.4 R81.1 48.44,124.45 48.44,124.45 48.17,124.17 47.43,124.17 46.81,124.8 46.81,125.93 46.62,126.12 46.62,128.29 47.27,128.93 47.27,132.01 48.15,132.89 CPU1.BA4
  BOTTOM w0.114: v3(47.09,93.27) 54.65,100.83 54.65,105.16 v2(54.37,105.45) 54.06,105.76 54.06,112.97 53.56,113.47 v3(53.56,113.55)
THERMAL_SHUT#_SIO: length 10.9
  TOP w0.114: R538.2 v3(68.33,90.46)
  BOTTOM w0.114: U6503.8 69.89,83.28 68.79,84.37 U31.23 68.79,88.18 v2(68.55,88.42) 68.33,88.65 v3(68.33,90.46)
TMON_CAL: length 1.7
  TOP w0.114: v3(61.32,137.73) 61.34,137.75 61.34,137.96 61.59,138.2 CPU1.AP29
  BOTTOM w0.114: TP16.1 61.42,137.83 v3(61.32,137.73)
TP20: length 2.7
  TOP w0.114: CPU1.W4 48.3,146.31 v3(47.96,146.66)
  BOTTOM w0.114: TP29.1 48.79,147.5 v3(47.96,146.66)
TP29: length 3.2
  TOP w0.114: CPU1.AV23 59,136.2 59.25,136.2 v3(59.26,136.19)
  BOTTOM w0.114: TP23.1 60.27,134.5 59.54,135.23 59.54,135.41 59.26,135.72 v3(59.26,136.19)
TP48: length 1.4
  TOP w0.114: CPU1.AP21 57.82,137.88 v3(58.05,137.88)
  BOTTOM w0.114: v3(58.05,137.88) 58.27,137.66 TP24.1
TP49: length 3.9
  TOP w0.114: v1(60.84,131.34) 60.43,131.75 60.43,133.09 60.25,133.27 CPU1.BA26
  BOTTOM w0.114: v1(60.84,131.34) 60.91,131.41 TP25.1
TP51: length 3.6
  TOP w0.114: v3(62.1,132.08) 62.09,132.08 61.85,132.08 61.35,132.58 CPU1.BA28
  BOTTOM w0.114: TP22.1 62.13,132.05 v3(62.1,132.08)
TP52: length 2.3
  TOP w0.114: v3(51.18,138.03) 51.07,138.03 CPU1.AN8
  BOTTOM w0.114: TP27.1 49.71,138.4 50.81,138.4 v3(51.18,138.03)
TP53: length 5.2
  TOP w0.114: TP28.1 50.31,129.72 49.09,130.95 49.09,133.21 49.25,133.37 CPU1.BA6
TP_LPC_CLKRUN#: length 1.7
  TOP w0.114: v3(60.2,137.7) 60.2,137.76 59.76,138.2 CPU1.AP25
  BOTTOM w0.114: TP30.1 60.78,138.29 v3(60.2,137.7)
TP_LPC_PD#: length 6.5
  TOP w0.114: TP31.1 42.43,133.61 44.75,133.61 45.08,133.94 45.08,134.65 45.27,134.84 45.27,134.93 45.97,135.64 46.08,135.64 46.4,135.96 46.68,135.96 46.99,135.65 CPU1.AV2
USB30_EN: length 5.2
  BOTTOM w0.114: U51.4 84.15,59.79 84.58,59.36 v2(84.58,58.85) 84.35,58.62 83.16,58.62 82.64,58.1 R866.2 81.23,58.1 R867.2
USB30_RN0_C: length 12.6
  BOTTOM w0.102: v2(129.26,170.71) 129.26,171.07 ; 129.26,171.07 129.41,171.07 129.95,171.6 130.53,171.6 130.66,171.48 D19.1 D19.10 132.18,171.48 132.31,171.6 133.3,171.6 135.28,169.62 136.22,169.62 136.65,169.19 137.43,169.19 137.65,168.97 USB3S1.5 ; 129.26,171.07 128.32,171.07 128.11,170.86 TR11.1
USB30_RP0_C: length 11.8
  BOTTOM w0.102: 129.66,171.68 129.31,171.32 128.35,171.32 128.13,171.54 TR11.4 ; 129.66,171.68 v2(129.41,171.93) ; 129.66,171.68 129.84,171.86 130.49,171.86 130.61,171.98 D19.2 D19.9 132.23,171.98 132.35,171.86 133.4,171.86 135.38,169.88 136.32,169.88 136.75,169.44 137.26,169.44 137.65,169.83 USB3S1.6
USB30_RXN0: length 116.1
  TOP w0.102: CPU1.V1 46.44,146.76 45.37,146.76 44.3,147.83 44.3,148.23 44.49,148.43 v3(44.78,148.43)
  BOTTOM w0.102: 125.04,171.28 125.91,171.28 126.03,171.16 126.03,171.01 126.19,170.86 TR11.2 ; 125.04,171.28 122.71,171.28 107.54,186.46 87.35,186.46 80.52,179.63 79.56,179.63 72.87,172.95 57.77,172.95 47.75,162.92 47.75,160.42 44.22,156.89 44.22,152.56 44.91,151.87 44.91,149.32 44.37,148.79 44.37,148.54 44.48,148.43 v3(44.78,148.43) ; 125.04,171.28 v2(125.04,170.92)
USB30_RXP0: length 116.9
  TOP w0.102: CPU1.V2 46.98,146.65 46.68,146.35 46.38,146.35 46.22,146.51 45.26,146.51 44.04,147.73 44.04,148.31 v3(43.92,148.43)
  BOTTOM w0.102: 47.5,162.26 47.5,160.53 43.97,157 43.97,152.45 44.65,151.76 44.65,149.43 44.12,148.89 44.12,148.63 v3(43.92,148.43) ; 47.5,162.26 47.5,163.03 57.67,173.2 72.77,173.2 79.45,179.88 80.42,179.88 87.24,186.71 107.64,186.71 122.82,171.54 TR11.3 ; 47.5,162.26 v2(47.14,162.26)
USB30_TN0_C: length 12.3
  BOTTOM w0.102: TR12.1 128.2,173.37 128.42,173.58 128.96,173.58 ; USB3S1.8 137.65,174.77 137.55,174.87 137.18,174.87 136.42,174.12 135.31,174.12 134.32,173.13 132.49,173.13 132.34,172.98 D19.7 D19.4 130.41,172.98 130.29,173.1 129.92,173.1 129.43,173.58 128.96,173.58 ; 128.96,173.58 v2(128.96,173.2)
USB30_TN0R*: length 3.8
  BOTTOM w0.102: v2(125.17,173.25) 125.17,173.58 ; 125.17,173.58 125.68,173.58 125.9,173.37 TR12.2 ; 125.17,173.58 124.89,173.58 124.1,174.37 123.78,174.37 C434.1
USB30_TP0_C: length 12.3
  BOTTOM w0.102: TR12.4 128.2,174.05 128.42,173.84 129.54,173.84 130.02,173.35 130.29,173.35 130.41,173.48 D19.5 D19.6 132.41,173.48 132.51,173.38 133.2,173.38 ; 133.2,173.38 v2(133.2,173.79) ; 133.2,173.38 134.21,173.38 135.2,174.37 136.32,174.37 137.07,175.13 137.55,175.13 137.65,175.23 USB3S1.9
USB30_TP0R*: length 3.8
  BOTTOM w0.102: C433.1 123.84,174.62 124.21,174.62 124.41,174.42 ; v2(124.64,174.65) 124.41,174.42 ; 124.41,174.42 125,173.84 125.68,173.84 125.9,174.05 TR12.3
USB30_TXN0: length 112.5
  TOP w0.102: v3(44.24,149.61) 44.04,149.8 44.04,150.04 44.15,150.14 44.67,150.14 45.21,149.6 45.21,148.48 45.97,147.73 46.44,147.73 46.46,147.75 CPU1.T1
  BOTTOM w0.102: C434.2 122.12,174.08 122.02,174.18 122.02,174.3 121.92,174.4 120.8,174.4 120.26,174.95 107.9,187.31 87,187.31 80.18,180.49 79.15,180.49 72.46,173.8 57.42,173.8 46.42,162.8 46.42,160.34 42.95,156.87 42.95,152.05 43.61,151.39 ; 43.61,151.39 43.83,151.17 43.92,151.08 43.92,150.57 44.02,150.47 44.27,150.47 44.45,150.29 44.45,149.82 v3(44.24,149.61) ; 43.61,151.39 v2(43.87,151.64)
USB30_TXP0: length 112.4
  TOP w0.102: v3(43.66,150.19) 43.87,150.39 44.78,150.39 45.47,149.7 45.47,148.59 46.08,147.98 46.33,147.98 46.4,148.05 46.63,148.05 CPU1.T2
  BOTTOM w0.102: v3(43.66,150.19) 43.66,150.98 43.65,150.99 42.7,151.94 42.7,156.98 46.16,160.44 46.16,162.91 57.31,174.05 72.35,174.05 79.04,180.75 80.07,180.75 86.89,187.56 108,187.56 120.44,175.13 120.91,174.66 121.36,174.66 ; C433.2 122.12,174.98 121.8,174.66 121.36,174.66 ; 121.36,174.66 v2(121.36,174.98)
USB30_VCCA: length 344.4
  TOP w0.305: R616.1 136.18,6.59 G2.1
  TOP w0.406: R616.1 135.1,7.62 135.05,7.57 134.13,7.57 133.4,6.83 v1(133.32,6.83)
  TOP w0.508: v5(50.24,52.5) 47.09,49.35 47.09,41.24 46.3,40.45 46.3,32.1 46.7,31.71 46.7,25.44 46.11,24.85 46.11,19.34 v1(46.91,18.54)
  TOP w0.635: 137.67,74 USB2S2.1 ; USB2S2.1 138.6,73.07 ; USB2S2.1 139.53,74 ; USB2S2.1 138.6,74.93 ; R463.1 120.15,188.41 123.04,185.52 123.04,183.59 v1(123.06,183.57) ; USB2S1.1 138.6,99.93 ; USB2S1.1 138.6,98.07 ; USB2S1.1 137.67,99 ; USB2S1.1 139.53,99 ; 135.36,175.5 USB3S1.1 136.15,176.29
  TOP w0.762: v5(39.24,61.98) 39.24,61.93 35.89,58.57 v2(30.45,58.57) 29.13,58.57 25.22,54.66 F9.1
  BOTTOM w0.406: v1(46.91,18.54) 48.12,18.54 48.68,17.98 v2(50.44,17.98) 65.94,17.98 69.79,14.13 69.79,10.4 76.44,3.76 107.17,3.76 107.71,4.29 120.71,4.29 121.62,3.39 129.88,3.39 v2(132.08,5.59) v1(133.32,6.83)
  BOTTOM w0.508: v1(132.68,176.96) 132.53,176.96 132.51,176.97 D20.5
  BOTTOM w0.635: v1(123.06,183.57) v2(124.72,181.91) 126.46,180.16 132.26,180.16 v5(134.24,178.18) ; 137.67,74 USB2S2.1 ; USB2S2.1 138.6,74.93 ; USB2S2.1 138.6,73.07
  BOTTOM w0.762: 90.4,62.14 81.68,53.42 79.97,53.42 78.17,51.62 73.87,51.62 72.94,50.69 52.05,50.69 v2(51.4,51.34) v5(50.24,52.5) 40.77,61.98 v5(39.24,61.98)
  BOTTOM w1.524: v5(143.89,98.6) 144.79,99.51 144.79,160.21 142.62,162.38 v2(142.62,175.01) 142.62,178.82 141.35,180.09 136.27,180.09 134.37,178.18 v5(134.24,178.18)
  vias: v2(89.2,64.11) v2(128.98,76.96) v2(137.77,84.96) v5(137.67,78.71) v5(138.07,77.8) v5(138.63,78.69)
USB_ATEST0: length 1.7
  TOP w0.114: v3(51.23,140.09) 51.23,140.09 51.23,140.33 CPU1.AJ10
  BOTTOM w0.114: TP12.1 50.75,139.61 v3(51.23,140.09)
USB_ATEST1: length 1.7
  TOP w0.114: v3(50.49,140.06) 50.55,140.11 50.55,140.45 CPU1.AJ8
  BOTTOM w0.114: TP13.1 49.96,140.06 v3(50.49,140.06)
USB_COMP_M: length 3.4
  TOP w0.114: v3(48.77,142.27) 48.74,142.24 48.74,142.14 CPU1.AG4
  BOTTOM w0.114: v3(48.77,142.27) 48.53,142.27 47.92,141.66 v6(47.32,141.66) 46.52,141.66 R96.1
USB_EN: length 2.2
  BOTTOM w0.114: R867.1 80.94,57.38 v2(79.98,57.38) 79.87,57.26 R440.2
USB_EN1: length 3.6
  TOP w0.114: R434.2 v2(61.42,54.53) 63.3,54.53 Q41.2
USB_EN2: length 7.7
  TOP w0.114: R438.1 64.73,54.52 63.31,55.94 Q41.1 v2(61.57,56.51) 59.71,56.51 R436.2
USB_EN3: length 205
  TOP w0.114: Q40.G 126.4,194.78 R435.1 128.47,194.13 128.47,174.39 131.53,171.33 131.53,167.62 138.43,160.72 139.15,160.72 v3(139.27,160.6) ; v3(69.8,56.26) 68.43,57.63 R437.1 67.14,58.27 66.01,58.27 65.71,57.96 C431.2 65.21,57.95 Q41.3
  BOTTOM w0.114: v3(139.27,160.6) 139.29,160.58 140.73,160.58 142.71,158.6 142.71,130.92 138.71,126.93 138.71,123.39 139.15,122.96 139.15,117.42 138.71,116.98 138.71,106.46 134.57,102.31 134.57,92 127.68,85.12 v2(120.04,85.12) 111.12,85.12 103.73,77.72 97.07,77.72 89.69,70.34 85.28,70.34 80.6,65.65 80.6,62.18 74.68,56.26 v3(69.8,56.26)
USB_EN4: length 5.9
  TOP w0.114: R438.2 65.62,52.54 66.09,52.07 v2(67.82,52.07) ; Q42.5 v2(67.82,52.07) ; v2(67.82,52.07) 68.22,52.07 68.47,52.31 Q42.6
USB_EN5: length 2.5
  TOP w0.114: Q42.3 v2(67.17,56.58) 66.89,56.86 R437.2
USB_EN6: length 5.1
  TOP w0.114: R439.2 70.21,55.22 v2(70.08,55.34) 69.09,56.34 68.2,56.34 67.82,55.96 Q42.2
USB_OC_01: length 14.1
  TOP w0.114: CPU1.AY8 50.35,134.49 50.04,134.18 50.04,133.9 50.12,133.82 50.12,133.39 50.23,133.29 50.23,131.23 51.47,129.99 51.47,126.65 51.3,126.49 51.3,125.81 51.21,125.72 51.21,124.97 v2(52.1,124.08) C455.1 51.65,123.1 51.39,123.36 R466.2
USB_OC_02: length 6.7
  TOP w0.114: R1019.1 43.66,131.37 v4(43.81,131.52) 45.34,133.05 45.34,134.59 45.84,135.09 45.84,135.2 46.05,135.41 46.15,135.41 46.4,135.65 CPU1.AV1
USB_OC_03: length 4.4
  TOP w0.114: CPU1.AY1 46.2,134.01 46.06,133.87 46.06,131.48 v4(45.72,131.14) 45.57,130.99 R1020.1
USB_OC_23: length 142.1
  TOP w0.114: CPU1.AW1 46.02,134.87 45.96,134.87 45.63,134.54 45.63,132.37 44.47,131.21 44.47,131.08 44.22,130.83 44.22,129.68 44.48,129.42 44.48,129.38 44.91,128.95 44.91,128.28 44.44,127.81 44.44,126.83 44.5,126.77 44.5,124.43 47.87,121.06 49.68,121.06 52.25,118.49 52.25,114.56 v3(51.94,114.25) ; v3(44.81,65.63) v3(41.83,62.66)
  BOTTOM w0.114: v3(44.81,65.63) 44.22,66.22 44.22,72.24 41.48,74.97 41.48,83.6 46.09,88.21 46.09,91.91 46.65,92.48 46.65,94.3 52.33,99.98 v2(52.33,101.17) 52.33,112.15 51.94,112.54 v3(51.94,114.25) ; R441.2 85.13,58.1 86.44,59.41 U51.3 85.66,60.11 85.22,60.55 83.31,60.55 82.96,60.19 82.96,59.64 82.61,59.3 C441.1 81.75,58.67 80.27,58.67 75.6,54 71.54,54 70.18,52.64 51.97,52.64 41.95,62.66 v3(41.83,62.66)
USB_PN0_C: length 19.3
  TOP w0.102: L72.4 130.88,85.56 131.01,85.42 131.8,85.42 131.94,85.28 D24.1 134.28,85.28 134.75,85.75 135.84,85.75 136.35,86.26 136.35,94.34 137.53,95.53 138.38,95.53 138.6,95.74 USB2S1.2
  BOTTOM w0.102: v2(139.95,96.49) 138.61,96.49 USB2S1.2
USB_PN1_2-: length 6.3
  TOP w0.102: v2(19.99,60.02) 19.99,60.37 ; 19.99,60.37 19.32,60.37 18.95,60 TOUCH1.4 ; 19.99,60.37 21.69,60.37 21.85,60.21 L44.4 22.47,60.13 R813.1
USB_PN2_11-: length 25.8
  TOP w0.102: CAM1.7 57,197.05 56.72,197.33 56.72,197.66 56.93,197.87 57.81,197.87 58.43,197.24 73.81,197.24 ; 73.81,197.24 77.62,197.24 78.21,196.65 78.21,196.54 78,196.33 L41.4 78,195.8 R464.1 ; 73.81,197.24 v2(73.81,196.9)
USB_PN4_C: length 20.7
  TOP w0.102: 135.33,83.38 135.33,83.01 135.1,82.78 135.1,81.99 ; 135.33,83.38 134.64,83.38 134.38,83.63 133.44,83.63 133.3,83.77 133.3,83.77 133.22,83.85 132.05,83.85 131.5,83.29 131.06,83.29 130.95,83.4 L47.4 ; 135.33,83.38 D24.4 ; 135.1,81.99 135.1,72.99 137.23,70.87 137.98,70.87 138.6,71.49 USB2S2.2 ; 135.1,81.99 v2(135.43,81.99)
USB_PN5*: length 5.9
  TOP w0.102: NGFFE1.5 39.83,29 39.95,29.12 40.53,29.12 40.98,29.58 ; v2(41.19,29.37) 40.98,29.58 ; 40.98,29.58 41.91,30.51 41.91,31.5 42.12,31.71 L49.4
USB_PN8_C: length 20.7
  BOTTOM w0.127: v2(132.82,175.18) 132.82,175.51 ; 132.82,175.51 133.58,175.51 134.9,176.83 138.02,176.83 138.51,176.35 138.51,173.61 137.93,173.03 137.22,173.03 136.22,172.03 136.04,172.03 135.86,172.21 135.86,172.71 USB3S1.2 ; 132.82,175.51 130.4,175.51 129.72,176.2 128.84,176.2 D20.1 128.49,176.2 128.02,176.2 127.76,175.95 127.03,175.95 126.82,175.74 L40.4
USB_PP0_C: length 19.4
  TOP w0.102: L72.1 130.75,84.88 131.04,85.17 131.7,85.17 132.05,84.81 133.23,84.81 133.45,85.03 134.38,85.03 134.64,85.28 D24.6 135.55,85.5 135.94,85.5 136.6,86.15 136.6,94.23 137.64,95.27 138.39,95.27 138.6,95.06 USB2S1.3
  BOTTOM w0.102: v2(139.95,94.49) 138.61,94.49 USB2S1.3
USB_PP1_2+: length 5
  TOP w0.102: v2(20.88,60.99) 20.88,60.63 ; 20.88,60.63 21.69,60.63 21.96,60.89 L44.1 ; 20.88,60.63 19.32,60.63 18.95,61 TOUCH1.3
USB_PP2_11+: length 25.2
  TOP w0.102: CAM1.6 56.2,197.04 56.46,197.31 56.46,197.76 56.82,198.12 57.92,198.12 58.54,197.5 77.19,197.5 ; 77.19,197.5 v2(77.19,197.84) ; 77.19,197.5 77.72,197.5 78.47,196.75 78.47,196.54 78.68,196.33 L41.1
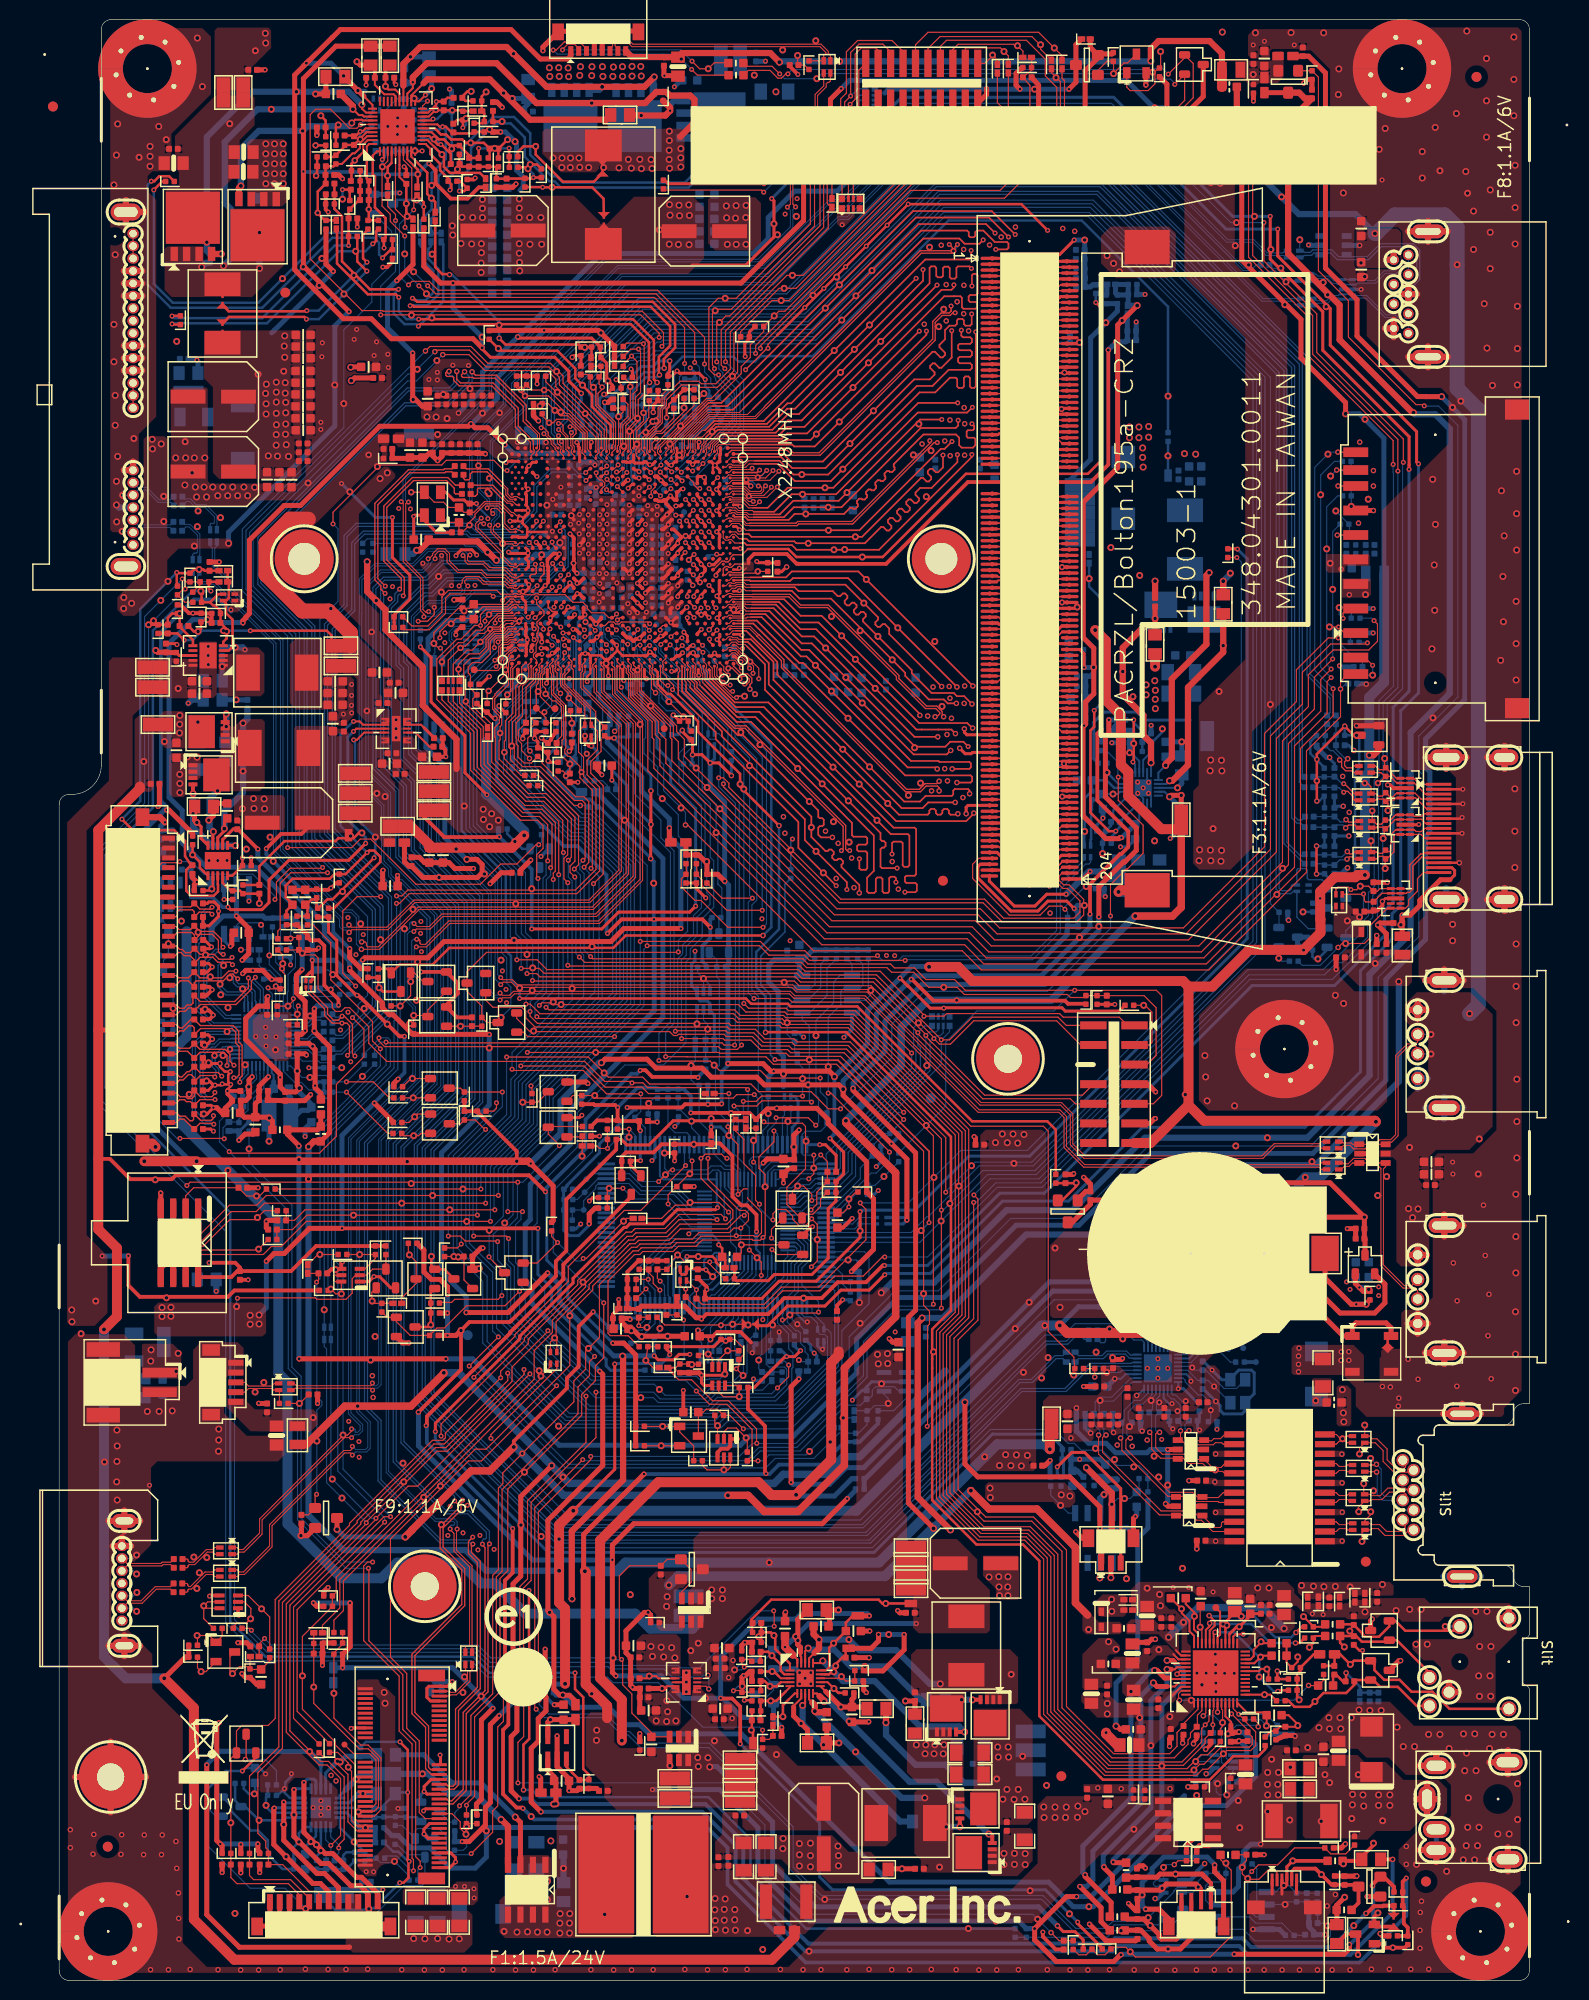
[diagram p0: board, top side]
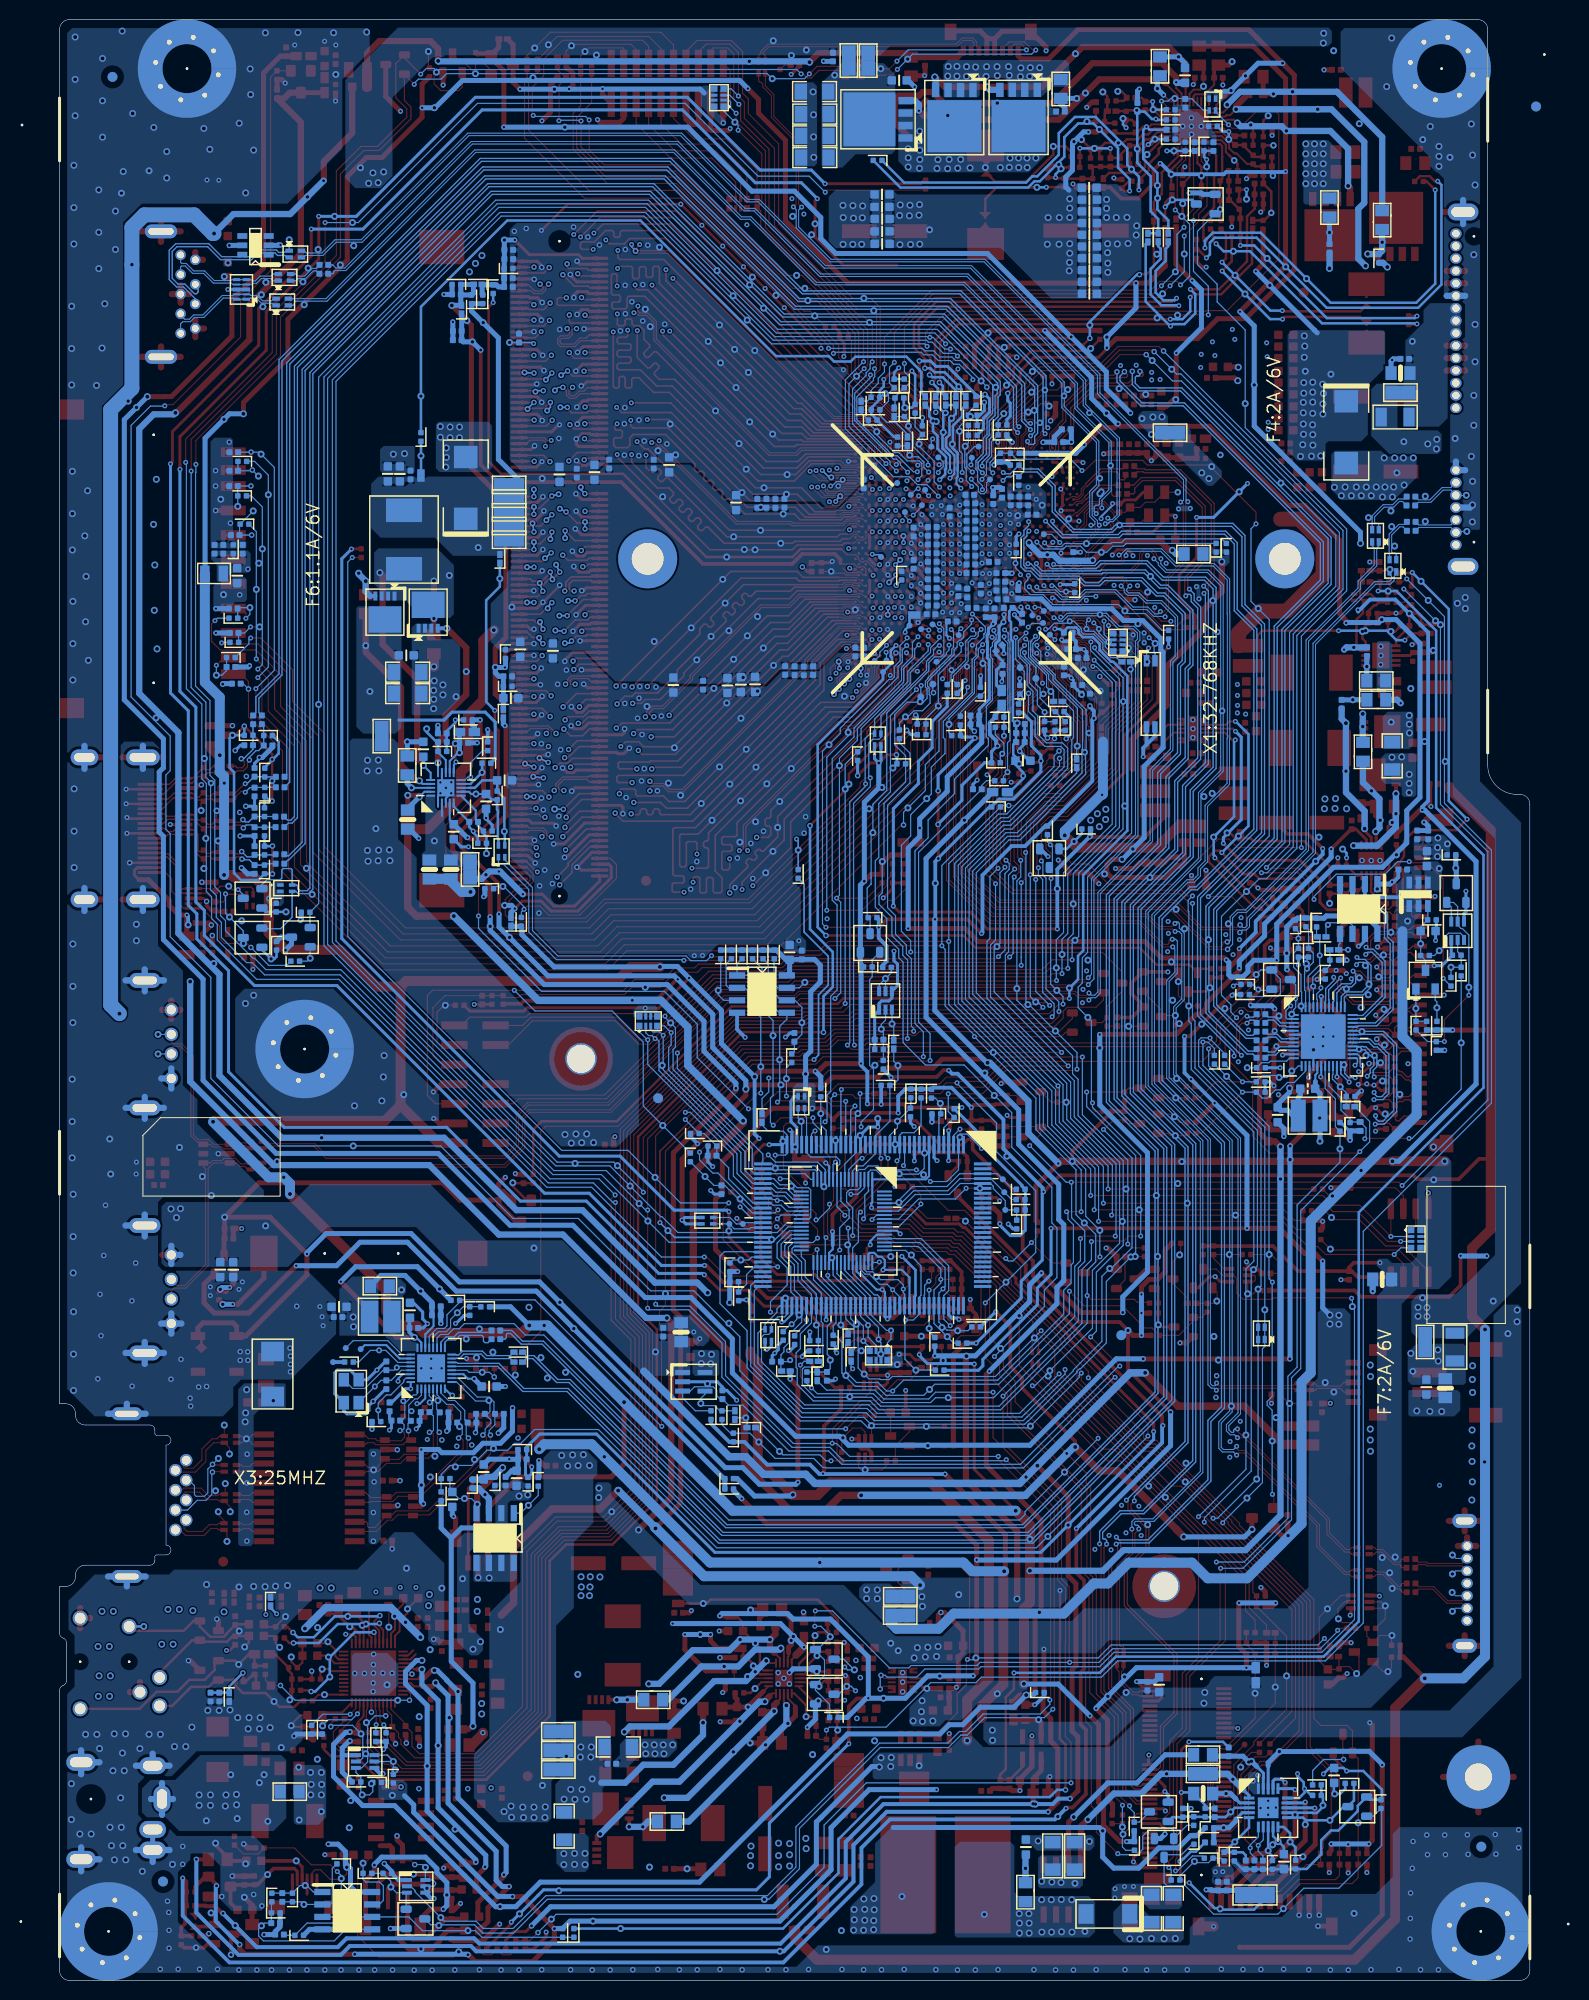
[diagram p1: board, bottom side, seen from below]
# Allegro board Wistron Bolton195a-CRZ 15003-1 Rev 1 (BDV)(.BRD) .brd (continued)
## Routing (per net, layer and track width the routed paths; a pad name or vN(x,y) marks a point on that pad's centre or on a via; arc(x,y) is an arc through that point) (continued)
USB_PP4_C: length 20.7
  TOP w0.102: USB2S2.3 138.6,70.34 138.32,70.61 137.12,70.61 134.85,72.88 134.85,80.06 ; L47.1 130.8,82.72 131.11,83.03 131.6,83.03 131.94,83.38 D24.3 134.28,83.38 134.85,82.8 134.85,80.06 ; 134.85,80.06 v2(134.52,80.06)
USB_PP5*: length 5.4
  TOP w0.102: L49.1 41.44,31.71 41.66,31.5 41.66,30.96 ; v2(41.35,30.96) 41.66,30.96 ; 41.66,30.96 41.66,30.61 40.42,29.38 39.95,29.38 39.83,29.5 38.78,29.5 NGFFE1.3
USB_PP8_C: length 21.8
  BOTTOM w0.127: USB3S1.3 136.15,171.53 137.35,172.73 138.05,172.73 138.81,173.48 138.81,176.48 138.15,177.14 134.77,177.14 133.45,175.82 131.56,175.82 D20.6 131.15,175.82 130.53,175.82 129.84,176.5 127.89,176.5 127.64,176.25 127.05,176.25 126.88,176.43 L40.1 v2(126.57,177.55)
USB_PWR_EUP: length 80
  TOP w0.114: v3(63.91,83.11) 59.33,78.54 57.66,78.54 51.94,72.82 51.94,71.32 51.92,71.3 51.92,71.3 46.51,65.88 46.51,65.71 v3(42.31,61.51)
  BOTTOM w0.114: v3(42.31,61.51) 42.43,61.51 51.66,52.27 71.81,52.27 71.85,52.32 72.13,52.32 73.05,53.24 76.99,53.24 v2(78.66,54.91) 79.57,55.82 R533.2 81.55,55.82 82.42,56.69 R866.1 ; v3(63.91,83.11) 63.79,83.23 U31.13
USBSS_CALRN: length 3.2
  TOP w0.114: v3(51.97,143.38) 51.5,142.91 CPU1.AE10
  BOTTOM w0.114: v3(51.97,143.38) 51.97,143.59 52.48,144.09 v6(52.48,144.55) 52.48,144.63 52.4,144.7 R99.1
USBSS_CALRP: length 18.7
  TOP w0.114: CPU1.AE8 50.85,142.8 51.16,143.1 v3(51.16,143.31)
  BOTTOM w0.114: v3(51.16,143.31) 51.21,143.26 51.21,142.85 51.54,142.52 51.54,141.94 50.95,141.35 49.66,141.35 48.64,140.34 41.96,140.34 v2(41.31,139.69) 41.05,139.42 39.22,139.42 37.5,137.71 R100.1
V_3_CARD:
  vias: v1(130.78,143.95) v2(129.67,144.55)
V_3P3_DBP: length 7.1
  TOP w0.114: DBGH1.3 111.23,95.41 111.49,95.67 111.49,98.76 110.78,99.46 v2(110.64,99.46) R493.2
V_3P3_LAN: length 54.5
  TOP w0.508: v3(121.31,71.27) 121.31,71.27 115.63,65.58 v5(113.79,65.58) ; U10.5 v3(113.09,54.15) ; v1(112.88,48.62) 113.13,48.36 U9.5
  BOTTOM w0.203: LAN1.23 113.09,65.06 113.61,65.58 v5(113.79,65.58) ; v3(114.17,60.35) 114.18,60.35 LAN1.32 ; LAN1.11 108.8,61.83 108.33,61.37 v1(107.7,61.37)
  BOTTOM w0.305: v3(114.17,60.35) 114.71,60.35 116.12,58.94 C286.1
  BOTTOM w0.381: C302.1 114.31,67.53 C268.1 114.31,66.1 v5(113.79,65.58)
  BOTTOM w0.508: v3(121.31,71.27) 119.79,72.8 113.5,72.8 v2(111.23,70.52) R287.2 ; C326.1 107.7,61.34 v1(107.7,61.37) ; v1(103.78,58.39) 103.8,58.38 103.8,56.01 105.02,54.79 106.81,54.79 107.77,53.82 111,53.82 111.33,54.15 v3(113.09,54.15) v2(113.09,50.52) 113.09,48.83 v1(112.88,48.62)
  vias: v2(106.2,59.16)
V_5_CODEC: length 15.2
  TOP w0.203: 113.92,33.67 114.45,33.14 AUDIO1.38
  BOTTOM w0.762: v5(124.97,35.89) 122.83,38.02 116.2,38.02 v2(114.71,36.52) v5(113.18,35)
  vias: v2(123.67,35.99)
V_5_LCD1:
  vias: v2(9.25,113.41)
V_5_LED: length 3.4
  TOP w0.381: G2.2 134.4,5.49 Q52.2 134.18,6.51 v2(134.54,6.88)
V_5_ODD:
  vias: v2(11.94,62.13) v5(9.35,63.17) v5(9.38,64.31) v5(12.14,63.96)
V_5_PWR1: length 4.2
  TOP w0.356: v2(134.09,14) 134.09,13.79 132.89,12.6 R618.1
  TOP w0.406: L54.2 132.74,12.19 R618.1
V_5_SUS1: length 3.1
  TOP w0.508: v2(131.15,8.48) 130.33,7.66 L55.2 130.35,7.16 R621.2
V_VCORE_EN: length 6.3
  TOP w0.254: R4401.2 37.2,179.65 v3(37.2,180.9) 37.2,181.35 PR4430.1
  BOTTOM w0.254: v3(37.2,180.9) 36.49,181.61 v2(36.47,181.61) 34.44,181.61 Q4401.D
VCORE_PWROK: length 26.1
  TOP w0.254: v1(39.83,173.99) 39.78,174.04 39.08,174.04 38.36,174.76 PR4431.1 ; v1(44.89,167.5) 45.53,166.85 53,166.85 R59.1 53.24,166.61 R52.2 54.32,165.59 R56.2
  BOTTOM w0.254: v1(44.89,167.5) v2(44.89,168.83) 44.89,169.18 40.08,173.99 v1(39.83,173.99)
VGA_BLUE: length 11.9
  TOP w0.114: R15.1 46.66,162.46 47.5,161.62 v4(47.52,161.62) 49.91,161.62 51.71,159.82 51.99,159.82 53.87,157.94 53.87,156.18 54.2,155.86 CPU1.B15
VGA_FCH_DDCSCL: length 1.5
  TOP w0.114: v3(57.02,154.58) 56.64,154.2 CPU1.D19
  BOTTOM w0.114: v3(57.02,154.58) 56.93,154.67 TP3.1
VGA_FCH_DDCSDA: length 4.4
  TOP w0.114: v3(56.87,153.85) 57.15,153.85 CPU1.D21
  BOTTOM w0.114: TP4.1 56.65,156.46 57.44,155.67 57.44,154.41 56.87,153.85 v3(56.87,153.85)
VGA_GREEN: length 7.5
  TOP w0.114: CPU1.A14 53.65,157.83 51.88,159.6 51.12,159.6 v2(50.57,160.15) 49.88,160.83 R14.1
VGA_HSYNC_3V: length 8.3
  TOP w0.114: CPU1.G19 v3(55.89,153.11)
  BOTTOM w0.114: v3(55.89,153.11) 55.88,153.12 55.88,153.16 55.44,153.6 55.44,154.93 54.91,155.46 54.91,156.95 R17.1 R16.1 54.24,159.12 53.67,159.69 v2(53.67,159.82)
VGA_RED: length 8.1
  TOP w0.114: R13.1 49.28,159.59 v4(49.99,158.88) 50.39,158.88 50.75,159.23 51.94,159.23 53.41,157.76 53.41,156.15 53.34,156.08 53.34,155.82 53.65,155.51 CPU1.B14
VGA_VSYNC_3V: length 4.6
  TOP w0.114: v3(56.98,153.13) 56.8,153.13 56.53,153.4 CPU1.E19
  BOTTOM w0.114: TP2.1 55.43,152.74 55.43,151.88 55.67,151.64 56.02,151.64 56.26,151.88 56.26,152.34 56.98,153.06 v3(56.98,153.13)
VREF: length 4.1
  BOTTOM w0.305: U59.2 29.58,18.1 29.97,18.49
  BOTTOM w0.508: 29.97,18.49 30.53,19.05 v2(30.99,19.05) C181.2
VRM_PWRGD: length 296.3
  TOP w0.114: PU4401.35 31.11,189.31 31.08,189.28 v3(30.74,189.28) 30.38,188.92 29.63,188.92 27.69,190.86 26.16,190.86 25.61,190.3 25.61,175.6 30.89,170.32 32.98,170.32 33.05,170.26 59.48,170.26 61.65,168.08 61.65,166.83 v3(61.49,166.67) ; D3.1 43.52,99.99 44.25,99.26 47.19,99.26 47.6,98.85 47.6,98.19 48.54,97.25 68.15,97.25 68.39,97.02 71.02,97.02 71.99,96.04 74.97,96.04 75.29,95.73 80.69,95.73 90.45,85.96 v3(90.45,80.39)
  BOTTOM w0.114: v3(90.45,80.39) 90.45,80.47 v2(93.08,83.1) 93.45,83.46 99.24,83.46 121.8,106.03 121.8,163.1 104.94,179.96 90.37,179.96 77.34,166.93 61.75,166.93 v3(61.49,166.67) ; RN18.4 32.06,190.6 v3(30.74,189.28)
VTT_CT_0.95V: length 3.3
  TOP w0.203: C6528.1 37.78,125.84 36.35,127.28 U12.10
VTT_CT_1.8V: length 3.4
  TOP w0.203: U12.12 36.92,128.08 37.24,127.76
  TOP w0.305: 37.24,127.76 38.25,126.75 C6529.1
VTT_CT_3.3V: length 2.8
  TOP w0.203: 61.8,29.8 62.01,30.01 U13.12
  TOP w0.508: C3604.1 v2(61.52,29.77) 61.78,29.77 61.8,29.8
VTT_CT_5VC: length 3.9
  TOP w0.203: U13.10 61.14,30.81 60.91,31.04 v2(60.2,31.04) 59.97,30.81 C3603.1
WIFI_DISABLE_N: length 102.5
  TOP w0.114: NGFFE1.56 30.43,16.25 30.2,16.48 30.2,21.99 28.17,24.02 28.17,24.31 24.82,27.66 v2(24.82,31.06) 24.82,35.09 R474.2 R476.1 28.26,39.6 28.26,41.13 48.46,61.33 48.46,64.24 50.32,66.1 50.32,67.34 51.36,68.38 51.36,68.38 53.7,70.71 53.7,71.12 57.66,75.08 58.09,75.51 58.62,75.51 58.93,75.82 58.98,75.87 62.05,75.87 63.32,77.14 68.13,77.14 68.73,77.73 68.73,78.57 65.48,81.81 v3(65.48,83.85) 65.49,83.85 65.92,84.28 67.57,84.28 68,83.85 v3(68.12,83.85)
  BOTTOM w0.114: U31.17 65.79,84.18 65.48,83.87 v3(65.48,83.85) ; U6503.7 69.49,82.71 68.34,83.85 v3(68.12,83.85)
WLAN_CLKREQ: length 6.2
  TOP w0.114: NGFFE1.53 38.78,17 40.08,17 40.92,16.16 40.92,15.49 v2(41.5,14.91) 41.5,15.61 41.55,15.66 R6565.1 R6566.2
WLAN_CLKREQ_CPU#: length 144.6
  TOP w0.102: 61.98,133.02 61.59,133.4 61.59,133.83 61.67,133.91 61.67,134.16 61.59,134.24 61.59,134.54 61.9,134.85 CPU1.AW29
  TOP w0.114: v3(54.62,63.64) 54.1,63.12 54.1,61.7 52.93,60.53 52.93,57.81 45.19,50.06 45.19,41.74 44.6,41.16 44.6,31.4 44.91,31.09 44.91,29.39 42.38,26.86 42.38,18.78 41.55,17.96 v3(41.55,17.86) 41.55,17.86 R6565.2 ; v3(62.58,131.66) 62.69,131.77 62.69,132.08 61.98,132.79 61.98,133.02
  BOTTOM w0.114: R6564.1 41.22,13.27 41.57,13.61 v2(41.57,15.65) 41.57,17.85 v3(41.55,17.86) ; v3(62.58,131.66) 62.58,131.65 65.23,128.99 65.23,121.23 66.42,120.04 66.42,114.55 66.78,114.2 66.78,109.47 65.61,108.3 65.61,106.4 64.39,105.18 64.39,104.32 63.94,103.87 63.94,95.66 61.66,93.37 57.71,93.37 52.86,88.51 52.86,84.99 48.77,80.9 48.77,77.27 48.25,76.75 48.25,71.69 49.53,70.41 49.53,68.73 v3(54.62,63.64)
X32K_X1: length 13.6
  TOP w0.114: CPU1.AJ2 46.64,140.6 46.33,140.91 46.07,140.91 45.52,140.35 42.31,140.35 R84.1 41.88,139.96 C30.1 40.72,139.96 38.23,137.46 v2(38.23,136.37) 38.71,135.89 v3(38.9,135.89)
  BOTTOM w0.114: v3(38.9,135.89) 39.1,135.69 X1.1
X32K_X2: length 12.1
  TOP w0.114: v3(38.84,136.95) 38.84,137.56 39.59,138.3 39.9,138.3 v2(39.98,138.38) 40.53,138.93 C31.1 42.21,138.93 R84.2 42.29,139.17 43.24,140.12 45.72,140.12 45.86,140.26 CPU1.AJ1
  BOTTOM w0.114: v3(38.84,136.95) 38.33,136.44 38.33,135.4 38.25,135.32 X1.4
X48M_X1: length 12.9
  TOP w0.114: v4(35.92,151.79) X2.3 38.27,150.77 39.22,150.77 39.75,150.24 R108.1 41.29,149.75 C36.1 42.31,149.75 43.39,150.83 45.04,150.83 46.15,149.72 46.34,149.72 46.66,149.4 CPU1.N2
X48M_X2: length 10.6
  TOP w0.114: CPU1.N1 46.14,149.4 44.93,150.61 43.48,150.61 42.43,149.56 42.43,149.28 41.86,148.72 v4(41.86,148.44) 41.12,147.7 C37.1 40.79,147.87 R108.2 39.63,148.72 X2.1
XRF_TDC1:
  vias: v1(117.91,50.85) v1(117.98,53.7) v1(117.98,47.73) v1(117.98,44.8) v2(117.96,52.07)
N16511429: length 7.7
  TOP w0.127: Q4808.D 19.08,22.61 v1(19,22.53)
  BOTTOM w0.127: v1(19,22.53) 21.03,22.53 22.16,21.4 R6579.2

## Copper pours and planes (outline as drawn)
5V_A on TOP: 65.69,30.13 65.54,30.28 64.7,30.28 64.65,30.33 64.65,30.48 64.7,30.53 66.17,30.53 66.55,30.91 66.55,31.27 66.36,31.46 66.01,31.46 65.56,31.02 64.75,31.02 64.62,31.14 64.62,31.74 64.22,32.15 64.22,39.73 64.71,40.22 64.71,45.05 65.46,45.8 78.33,45.8 81.34,48.81 81.34,60.54 81.36,60.55 81.36,62.43 83.26,64.34 85.78,64.34 86.08,64.03 86.08,47.8 86.49,47.4 86.49,39.22 72.03,39.22 67.32,34.5 67.32,30.76 66.68,30.13 ; 5 cut-outs
5V_A on BOTTOM: 64.77,36.35 64.64,36.47 64.64,39.83 65.3,40.49 67.94,40.49 68.43,40.01 68.43,39.09 65.68,36.35
5V_A on BOTTOM: 82.88,61.65 82.7,61.82 82.7,64.19 82.83,64.31 85.39,64.31 85.45,64.26 85.45,61.93 85.17,61.65
5V_A on BOTTOM: 11.83,106.32 11.76,106.39 11.76,108.02 11.06,108.72 11.06,113.13 11.58,113.65 12.72,113.65 12.84,113.53 12.84,112.56 13.67,111.72 13.67,106.48 13.52,106.32 ; 1 cut-out
5V_HDD on BOTTOM: 9.25,158.48 8.39,159.35 8.39,166.98 7.98,167.39 7.51,167.39 7.06,167.83 7.06,170.66 7.49,171.08 10.16,171.08 10.85,170.39 10.85,169.09 12.7,167.25 12.7,164.8 12.86,164.64 12.86,158.53 12.81,158.48 ; 2 cut-outs
5V_S0 on TOP: 6.56,139.17 5.95,139.78 5.95,141.09 8.62,143.76 8.62,157.2 8.92,157.5 10.76,157.5 11.03,157.23 11.03,147.34 11.3,147.07 17.4,147.07 17.65,146.81 17.65,146.35 17.35,146.05 12.19,146.05 11.05,144.91 11.03,144.91 11.03,142.51 7.69,139.17
5V_S0 on TOP: 132.61,101.42 130.89,103.15 130.89,104.78 131.27,105.16 137.92,105.16 138.02,105.05 138.02,101.83 137.62,101.42 ; 5 cut-outs
5V_S0 on TOP: 101.98,48.23 101.42,48.79 94.92,48.79 94.48,49.24 94.48,50.51 94.77,50.8 102.57,50.8 103.66,49.71 103.66,48.77 103.12,48.23
5V_S0 on TOP: 10.08,65.68 9.7,66.07 9.7,68.73 10.11,69.14 20.7,69.14 21.11,68.73 21.11,66.04 20.75,65.68
5V_S0 on TOP: 61.24,31.04 60.86,31.42 59.23,31.42 58.88,31.78 58.88,34.67 59.51,35.31 62.97,35.31 63.4,34.87 63.4,31.17 63.28,31.04 ; 4 cut-outs
5V_S0 on TOP: 104.65,29.59 104.39,29.84 104.39,33.27 106.05,34.92 107.44,34.92 108.2,34.16 108.2,33.66 107.82,33.27 107.19,33.27 106.93,33.02 106.93,31.75 107.44,31.24 107.44,29.97 107.31,29.84 105.79,29.84 105.54,29.59 ; 1 cut-out
5V_S0 on BOTTOM: 58.42,32.23 57.28,33.38 44.26,33.38 42.95,34.68 22.36,34.68 18.31,38.73 18.31,51.33 18.29,51.36 18.29,67.92 18.92,68.55 21.18,68.55 21.64,68.1 21.64,61.44 22.3,60.78 22.31,60.78 22.56,60.54 22.56,51.61 22.53,51.59 22.58,51.54 22.58,40.11 24.74,37.95 45.44,37.95 46.72,36.66 58.38,36.66 59.93,35.12 64.76,35.12 69.98,40.34 84.61,40.34 93.7,49.43 93.7,50.52 93.98,50.8 95.1,50.8 95.33,50.57 95.33,47.88 85.75,38.3 71.3,38.3 65.23,32.23
5V_S0 on BOTTOM: 9.39,155.7 9,156.08 9,157.72 9.4,158.12 13.18,158.12 13.51,158.44 13.51,162.75 13.62,162.86 15.62,162.86 16.18,162.29 16.18,157.54 14.34,155.7
5V_S0 on BOTTOM: 107.31,33.15 106.81,33.66 106.81,34.81 108.17,36.17 108.17,43.69 107.6,44.27 105.29,44.27 104.27,45.29 104.27,48.65 103.99,48.93 102.69,48.93 102.67,48.95 102.18,48.95 101.85,49.28 101.85,50.48 101.92,50.55 101.92,50.65 102.01,50.74 102.6,50.74 102.87,51.02 103.9,51.02 104.13,50.78 105.82,50.78 105.89,50.72 105.89,49.89 105.55,49.55 105.55,46.19 106.08,45.66 108.67,45.66 109.44,44.88 109.44,34.54 108.04,33.15 ; 5 cut-outs
5V_S0 on BOTTOM: 6.48,65.51 0.89,71.09 0.89,118.11 5.08,122.3 5.08,141.35 5.84,142.11 7.49,142.11 7.87,141.73 7.87,120.78 3.56,116.46 3.56,73.99 7.56,69.99 11.37,69.99 12.09,69.27 12.09,66.12 11.48,65.51
5V_S5 on TOP: 104.78,35.31 104.39,35.69 104.39,37.08 104.65,37.34 105.28,37.34 106.05,36.58 108.2,36.58 108.46,36.32 108.46,35.56 108.2,35.31
5V_S5 on TOP: 61.32,35.66 60.93,36.04 60.93,37.26 60.15,38.05 60.15,41 60.86,41.71 64.04,41.71 64.27,41.48 64.27,40.39 63.88,40.01 63.25,40.01 62.94,39.7 62.94,38.2 63.2,37.95 63.5,37.95 63.86,37.59 63.86,35.97 63.55,35.66 ; 4 cut-outs
5V_S5 on BOTTOM: 64.39,62.46 63.98,62.87 63.98,64.03 64.14,64.19 64.54,64.19 64.69,64.03 64.69,63.83 64.85,63.68 67.72,63.68 67.82,63.58 67.82,62.66 67.61,62.46
5V_S5 on BOTTOM: 61.82,36.55 60.33,38.05 48.01,38.05 47.14,38.91 47.14,40.79 47.42,41.07 51.16,41.07 51.17,41.08 63.77,41.08 64.11,40.74 64.11,36.71 63.96,36.55
+0.95V_DUAL on BOTTOM: 43.18,124.85 42.9,125.13 42.9,132.46 44.75,134.32 44.75,134.32 44.88,134.44 45.62,134.44 45.72,134.54 45.72,135.1 45.92,135.31 46.66,135.31 46.81,135.46 46.81,136.18 46.89,136.25 48.46,136.25 48.96,136.75 49.39,136.75 49.51,136.63 49.51,134.78 48.44,133.71 47.17,133.71 46.02,132.56 46.02,131.9 45.92,131.8 45.54,131.8 45.2,131.46 45.2,130.87 44.83,130.51 44.5,130.51 44.08,130.09 44.08,125 43.93,124.85 ; 7 cut-outs
+1.05V_LAN on TOP: 109.73,58.04 109.5,58.27 109.5,59.69 109.75,59.94 112.52,59.94 112.53,59.93 114.59,59.93 115.21,60.55 115.21,64.59 118.9,68.28 120.45,68.28 120.73,68 120.73,66.12 120.22,65.61 119.51,65.61 116.59,62.69 116.59,58.8 115.82,58.04 ; 8 cut-outs
+1.05V_LAN on BOTTOM: 117.65,65.76 117.47,65.94 117.47,71.5 117.78,71.81 120.14,71.81 121.46,70.48 121.46,65.84 121.39,65.76 ; 4 cut-outs
AGND on TOP: 141.86,28.32 140.97,29.21 140.97,31.88 140.21,32.64 139.19,32.64 138.05,33.78 138.05,34.29 138.56,34.8 143.89,34.8 144.27,35.18 144.27,36.83 144.02,37.08 141.35,37.08 140.84,36.58 137.03,36.58 136.14,37.47 135,37.47 134.37,36.83 131.44,36.83 131.25,37.02 127.79,37.02 127.22,37.59 126.85,37.59 126.24,38.2 124.16,38.2 124.03,38.07 124.03,38.02 123.93,37.92 122.25,37.92 121.72,38.46 119.02,38.46 118.34,39.14 118.01,39.14 117.98,39.12 116.2,39.12 115.7,39.62 112.9,39.62 112.78,39.5 112.78,38.35 113.28,37.85 113.82,37.85 115.09,36.58 115.09,34.47 115.44,34.11 115.44,33.45 115.42,33.43 114.53,33.43 114.5,33.45 114.5,35.99 113.79,36.7 112.27,36.7 111.51,37.47 109.47,37.47 109.35,37.59 109.35,39.88 110.11,40.64 125.3,40.64 126.01,39.93 126.01,39.5 127.03,38.48 131.44,38.48 131.95,38.99 139.32,38.99 139.83,38.48 147.96,38.48 148.72,37.72 148.72,35.43 146.56,33.27 146.56,28.45 146.43,28.32 ; 16 cut-outs
AGND on L2VCC: 138.46,26.56 136.1,28.92 130.32,28.92 128.32,26.91 126.42,26.91 125.35,27.98 123.55,27.98 123.27,28.26 121.51,28.26 120.9,28.86 120.9,33.43 120.17,34.16 116.3,34.16 115.41,33.27 114.71,33.27 114.43,33.56 114.43,35.84 113.44,36.83 113.13,36.83 112.94,36.64 112.35,36.64 111.71,37.27 109.55,37.27 109.28,37.54 109.28,39.8 110.19,40.7 123.75,40.7 126.16,38.29 130,38.29 130.76,39.05 139.37,39.05 139.75,38.67 149.24,38.67 149.24,35.58 148.73,35.11 148.54,34.45 148.54,30.55 148.73,29.89 149.24,29.42 149.24,26.56
AGND on L3: 126.54,35.97 126.54,31.09 124.64,29.18 123.55,29.18 121.82,30.91 121.82,32.77 120.4,34.19 112.93,34.19 112.6,34.52 112.6,35.94 115.34,38.68 123.83,38.68
GND on TOP: 40.61,173.76 39.67,174.7 39.67,180.8 40.03,181.15 41.73,181.15 42.77,182.19 44.22,182.19 44.6,181.81 44.6,173.91 44.45,173.76
GND on TOP: 104.7,19.08 104.47,19.3 104.47,19.91 104.56,20 113.65,20 113.77,19.89 113.77,19.3 113.54,19.08 ; 4 cut-outs
GND on TOP: 5.46,147.7 5.21,147.96 5.21,192.41 5.71,192.91 6.73,192.91 7.11,192.53 10.29,192.53 11.68,193.93 11.68,196.09 9.78,197.99 10.29,198.5 10.29,198.75 10.67,199.14 14.61,199.14 15.49,198.25 15.49,192.41 11.46,188.37 11.46,184.71 11.43,184.68 11.43,184.66 11.3,184.53 9.53,184.53 9.02,184.02 9.02,182.5 9.91,181.61 9.91,159.51 8.13,157.73 8.13,148.46 7.37,147.7 ; 2 cut-outs
GND on TOP: 37.43,161.35 37.13,161.65 37.13,163.57 37.83,164.27 37.83,164.27 38.98,165.41 41.75,165.41 42.14,165.02 42.14,164.67 41.95,164.48 39.36,164.48 39.05,164.17 39.05,163.41 40.25,162.21 44.11,162.21 44.42,161.91 44.42,161.46 44.31,161.35 ; 9 cut-outs
GND on TOP: 18.97,117.33 18.3,118.01 17.91,118.01 17.83,118.08 17.83,120.64 18.08,120.9 22.76,120.9 23.04,120.62 23.04,117.58 22.79,117.33 ; 1 cut-out
GND on TOP: 107.7,66.75 106.88,67.56 101.37,67.56 101.09,67.84 101.09,74.98 102.51,76.4 113.46,76.4 113.46,76.38 114.1,75.74 114.1,72.92 115.39,71.63 115.39,67.79 115.01,67.41 113.23,67.41 112.57,66.75
GND on TOP: 67.82,30.48 67.56,30.73 67.56,34.14 67.76,34.33 68.77,34.33 68.91,34.19 68.91,30.76 68.63,30.48 ; 3 cut-outs
GND on TOP: 35.28,7.67 35.05,7.9 35.05,9.22 35.36,9.53 40.01,9.53 40.56,10.08 42.55,10.08 42.75,9.88 42.75,8.15 42.27,7.67
GND on TOP: 122.3,3.3 121.41,4.19 121.41,8.79 121.77,9.14 130.3,9.14 130.56,8.89 130.56,8.51 129.79,7.75 129.79,6.99 129.41,6.6 129.41,3.81 128.91,3.3
GND on TOP: 66.93,176.45 66.19,177.19 66.19,181.66 66.41,181.88 71.02,181.88 71.6,181.29 71.6,177.29 70.76,176.45
GND on TOP: 117.3,88.72 116.28,89.74 116.28,98.45 121.03,103.2 129.9,103.2 130.15,103.45 130.53,103.45 130.66,103.33 130.66,102.39 132.16,100.89 134.98,100.89 135.48,100.38 135.48,89.69 134.52,88.72 ; 1 cut-out
GND on TOP: 38.13,139.82 37.67,140.28 37.67,143.43 36.83,144.27 36.83,144.67 36.98,144.82 37.23,144.82 37.45,144.6 38.53,144.6 38.74,144.81 38.74,145.38 38.9,145.54 39.14,145.54 39.27,145.41 39.27,144.37 40.27,143.37 40.27,142.16 40.13,142.02 39.39,142.02 38.51,141.14 38.51,139.98 38.35,139.82
GND on TOP: 130.89,141.05 130.68,141.25 130.68,142.88 130.81,143 133.71,143 133.83,142.88 133.83,141.35 133.53,141.05
GND on TOP: 67.87,25.58 67.51,25.93 67.51,28.22 67.67,28.37 68.58,28.37 69.16,27.79 69.16,25.91 68.83,25.58 ; 3 cut-outs
GND on TOP: 106.3,37.08 105.92,37.47 105.92,38.84 106.45,39.37 108.71,39.37 108.84,39.24 108.84,37.34 108.58,37.08
GND on TOP: 102.62,54.97 102.49,55.09 102.49,56.77 103.89,56.77 104.14,57.02 108.2,57.02 108.56,57.38 108.56,59.74 108.69,59.87 109.27,59.87 109.35,59.79 109.35,58.17 109.73,57.78 116.2,57.78 116.84,58.42 116.84,62.36 117.22,62.74 117.88,62.74 118.41,62.2 118.41,57.58 116.59,55.75 115.95,55.75 115.7,56.01 115.7,56.39 115.57,56.52 114.3,56.52 113.92,56.13 113.92,55.88 113.67,55.63 113.28,55.63 112.52,56.39 111.12,56.39 110.49,55.75 108.08,55.75 107.95,55.63 107.44,55.63 106.93,56.13 105.92,56.13 105.54,55.75 105.54,55.24 105.26,54.97 ; 13 cut-outs
GND on TOP: 87.58,20.12 86.49,21.21 86.49,25.73 86.56,25.81 91.03,25.81 91.06,25.78 91.06,24.69 91.26,24.49 91.95,24.49 92.28,24.16 92.28,20.22 92.18,20.12
GND on TOP: 34.06,122.68 33.97,122.77 33.97,126.37 33.95,126.38 33.95,129.67 33.66,129.97 33.27,129.97 33.15,130.1 33.15,131.17 33.02,131.29 33.02,133.81 33.17,133.96 33.81,133.96 34.11,133.65 34.11,131.17 34.84,130.43 34.84,127.86 34.92,127.78 35.87,127.78 35.9,127.76 35.9,127.59 35.87,127.57 35.03,127.57 34.84,127.38 34.84,123.54 34.75,123.44 34.75,122.76 34.66,122.68 ; 4 cut-outs
GND on TOP: 62.61,137.96 61.98,138.59 61.72,138.59 61.47,138.34 61.34,138.34 60.96,138.72 60.71,138.72 60.58,138.85 60.58,139.1 60.84,139.35 61.09,139.35 61.34,139.61 61.34,149.26 62.36,150.28 62.49,150.28 62.74,150.02 62.74,148.63 62.23,148.12 62.23,147.61 62.74,147.1 62.74,146.69 62.18,146.13 62.18,145.85 62.36,145.67 62.36,145.32 62.11,145.07 62.11,144.82 62.36,144.56 62.49,144.56 62.74,144.31 62.74,143.8 62.11,143.16 62.11,142.78 62.36,142.53 62.87,142.53 63.38,143.04 63.63,143.04 63.76,142.91 63.76,142.53 62.74,141.51 62.74,140.88 62.87,140.75 63.63,140.75 63.76,140.62 63.76,140.37 62.99,139.61 62.99,139.48 63.25,139.23 63.25,138.21 62.99,137.96
GND on TOP: 105.92,26.8 104.27,28.45 104.27,29.08 104.52,29.34 106.93,29.34 107.95,28.32 110.36,28.32 110.74,27.94 111.76,27.94 111.89,28.07 112.52,28.07 112.65,27.94 112.65,27.43 112.14,26.92 110.11,26.92 109.98,26.8 ; 2 cut-outs
GND on TOP: 127.08,38.86 126.36,39.57 126.36,40.39 126.62,40.64 135.76,40.64 136.14,40.26 136.14,39.37 136.02,39.24 131.83,39.24 131.44,38.86 ; 4 cut-outs
GND on TOP: 95.73,38.81 95.61,38.94 95.61,39.9 94.25,41.26 94.25,43.27 94.31,43.33 97.74,43.33 97.94,43.13 97.94,38.99 97.76,38.81
GND on TOP: 78.59,9.91 77.75,10.74 75.34,10.74 75.33,10.75 75.26,10.75 73.68,12.34 66.98,12.34 66.92,12.41 66.92,14.16 67.65,14.89 67.65,16.96 67.86,17.18 69.1,17.18 69.23,17.04 69.23,15.48 69.88,14.83 78.83,14.83 80.53,13.13 82.78,13.13 83.31,12.59 83.31,10.31 82.91,9.91 ; 4 cut-outs
GND on TOP: 11.56,120.7 11.23,121.03 11.23,124.97 11.44,125.18 14.3,125.18 14.44,125.04 14.44,122.74 14.14,122.44 13,122.44 12.9,122.33 12.9,120.91 12.68,120.7 ; 2 cut-outs
GND on TOP: 79.68,178.84 79.35,179.17 79.35,180.97 79.48,181.1 81.13,181.1 81.18,181.05 81.18,179.91 80.11,178.84
GND on TOP: 12.27,150.29 11.39,151.17 11.39,162.29 11.59,162.49 15,162.49 15.16,162.32 15.16,152.93 15.42,152.68 24.51,152.68 25.13,153.3 25.13,168.31 25.65,168.83 31.32,168.83 33.92,166.23 33.92,160.29 24.59,150.95 19.71,150.95 19.05,150.29 ; 25 cut-outs
GND on TOP: outline of 88 points within 121.28,57.48 149.2,199.21 ; 21 cut-outs
GND on TOP: 21.99,93.77 19.75,96.01 19.75,97.97 20.55,98.76 23.63,98.76 23.71,98.68 23.71,94.24 23.25,93.77 ; 11 cut-outs
GND on TOP: 14.5,130.82 14.28,131.04 14.28,136.44 14.4,136.56 16,136.56 16.08,136.49 16.08,131.16 15.74,130.82 ; 6 cut-outs
GND on TOP: outline of 111 points within 49.28,143.8 59.93,157.26
GND on TOP: 28.5,127.96 28.09,128.36 27.53,128.36 27.38,128.51 27.38,129.25 27.59,129.46 28.05,129.46 28.31,129.72 28.31,132.83 28.46,132.98 29.75,132.98 30.07,132.66 30.07,129.01 29.42,128.36 29.42,128.06 29.31,127.96 ; 5 cut-outs
GND on TOP: 107.8,173.63 106.3,175.13 106.3,177.93 107.26,178.89 113.23,178.89 113.92,178.21 113.92,174.45 113.11,173.63
GND on TOP: 55.96,139.55 55.67,139.83 54.36,139.83 54.18,140 54.18,140 54.13,140.06 54.13,141 53.3,141.84 53.3,142.09 53.85,142.64 54.14,142.64 55.14,141.64 55.79,141.64 56.35,142.2 56.61,142.2 56.72,142.09 56.72,139.9 56.36,139.55
GND on TOP: 95.11,10.64 94.74,11.01 94.74,13.53 94.79,13.58 96.04,13.58 96.31,13.85 96.31,15.4 96.45,15.54 99.06,15.54 99.31,15.29 99.31,12.19 97.76,10.64 ; 1 cut-out
GND on TOP: 19.26,180.95 19.18,181.03 19.18,187.45 19.54,187.81 22.89,187.81 23.16,187.53 23.16,181.35 22.76,180.95
GND on TOP: outline of 86 points within 0.89,0.76 149.1,65.91 ; 3 cut-outs
GND on BOTTOM: 14.11,131.77 14.03,131.85 14.03,136.26 14.39,136.61 15.47,136.61 15.47,136.6 15.63,136.44 15.63,131.87 15.54,131.77
GND on BOTTOM: 84.25,104.24 82.8,105.69 76.58,105.69 75.82,104.93 74.9,104.93 74.7,104.72 73.96,104.72 73.84,104.85 73.84,106.05 74.37,106.58 74.37,111.33 75.21,112.17 75.21,116.54 75.03,116.71 74.04,116.71 73.76,116.99 73.76,118.03 73.37,118.43 73.37,125.77 66.34,132.8 66.34,135.11 66.82,135.59 67.03,135.59 67.2,135.41 70.64,135.41 72.49,133.55 76.29,133.55 77.87,131.98 88.82,131.98 89.18,132.33 93.39,132.33 96.57,135.51 103.4,135.51 104.18,134.73 104.18,123.25 104.47,122.96 104.47,121.8 104.18,121.51 104.18,114.66 101.54,112.02 101.54,107.24 98.99,104.68 86.02,104.68 85.58,104.24 ; 31 cut-outs
GND on BOTTOM: 103.68,40.65 103.35,40.98 103.35,43.41 103.38,43.45 107.69,43.45 107.77,43.37 107.77,40.77 107.66,40.65
GND on BOTTOM: 33.6,140.67 33.48,140.79 33.48,141.15 33.6,141.27 33.6,142.27 33.78,142.44 34.11,142.44 34.29,142.27 34.29,142.04 34.01,141.76 34.01,140.82 33.86,140.67
GND on BOTTOM: 70.59,150.29 68,152.88 65.74,152.88 65.46,153.17 65.46,153.65 70.15,158.34 70.15,163.3 69.65,163.8 69.65,164.34 69.88,164.57 71.07,164.57 71.73,165.23 77.04,165.23 91.09,179.28 103.37,179.28 104.08,178.57 104.08,155.12 102.86,153.9 95.25,153.9 94.36,154.79 85.55,154.79 81.61,150.85 72.43,150.85 71.87,150.29 ; 21 cut-outs
GND on BOTTOM: 7.72,57.52 7.1,58.14 7.1,59.93 7.39,60.22 12.3,60.22 12.4,60.12 12.4,57.71 12.21,57.52 ; 2 cut-outs
GND on BOTTOM: 42.93,171.5 40.97,173.46 40.49,173.46 39.62,174.32 39.62,180.7 39.64,180.71 39.64,181.65 40.06,182.07 40.92,182.07 42.06,183.21 44.7,183.21 44.7,171.6 44.6,171.5 ; 9 cut-outs
GND on BOTTOM: 58.93,140.24 58.8,140.37 58.8,141.39 58.55,141.64 57.15,141.64 57.03,141.77 57.03,142.15 57.28,142.4 57.28,142.78 57.15,142.91 57.15,143.93 57.66,143.93 57.79,143.8 57.79,143.16 58.55,143.16 58.68,143.29 58.68,149.51 58.8,149.64 59.38,149.64 59.49,149.53 59.49,149.05 59.31,148.88 59.31,140.5 59.06,140.24 ; 2 cut-outs
GND on BOTTOM: 106.32,153.85 105.87,154.31 105.87,157.43 105.88,157.44 105.88,158.58 106.27,158.98 111.33,158.98 111.61,158.7 111.61,154.23 111.23,153.85
GND on BOTTOM: 32.08,187.22 31.98,187.32 31.98,188.24 32.41,188.67 32.41,189.38 32.79,189.76 33.07,189.76 33.93,190.63 34.42,190.63 34.65,190.86 34.65,191.29 34.7,191.34 36.3,191.34 36.47,191.16 36.47,187.55 36.14,187.22 ; 14 cut-outs
GND on BOTTOM: 49.7,149.15 49.33,149.52 49.33,151.71 49.91,152.3 49.91,152.31 50.29,152.69 52.96,152.69 53.34,152.31 53.34,151.17 53.22,151.04 50.93,151.04 50.67,150.77 50.67,149.26 50.55,149.15 ; 6 cut-outs
GND on BOTTOM: 11.79,120.71 11.59,120.91 11.59,124.94 11.82,125.17 14.72,125.17 15.17,124.72 15.17,122.44 14.75,122.02 13.46,122.02 13.07,121.63 13.07,120.91 12.87,120.71
GND on BOTTOM: 27.61,18.95 27.51,19.05 27.51,21.03 27.74,21.26 28.5,21.26 28.78,20.98 28.78,19.61 28.12,18.95
GND on BOTTOM: 113.92,153.72 113.77,153.87 113.77,156.39 113.89,156.51 116.94,156.51 117.3,156.16 117.3,154 117.02,153.72 ; 4 cut-outs
GND on BOTTOM: 132.49,139.6 132.36,139.73 132.36,140.31 132.08,140.59 131.11,140.59 130.89,140.82 130.89,142.9 131.11,143.13 132.28,143.13 132.41,143 132.41,142.7 132.66,142.44 134.09,142.44 134.32,142.21 134.32,139.73 134.19,139.6 ; 3 cut-outs
GND on BOTTOM: 131.06,146.05 130.94,146.18 130.94,146.74 131.09,146.89 132.11,146.89 132.31,147.09 132.31,157.14 132.53,157.36 134.18,157.36 134.59,156.95 134.59,146.18 134.47,146.05 ; 10 cut-outs
GND on BOTTOM: 111.48,87.66 111.28,87.86 111.28,90.35 122.07,101.14 131.14,101.14 132.08,100.2 132.08,92.63 127.1,87.66 ; 1 cut-out
GND on BOTTOM: 84.28,64.69 83.72,65.25 83.72,65.84 85.72,67.84 87.3,67.84 87.43,67.72 87.43,67.28 87.68,67.03 88.8,67.03 88.87,66.95 88.87,66.34 88.72,66.19 85.88,66.19 85.37,65.68 85.37,65.1 84.96,64.69
GND on BOTTOM: 5.84,0.76 5.21,1.4 5.21,2.03 7.49,4.32 7.49,6.35 6.1,7.75 4.06,7.75 2.29,5.97 1.4,5.97 0.76,6.6 0.76,15.49 0.9,15.63 13.28,15.63 13.98,14.94 13.98,10.56 15.72,8.81 22.96,8.81 25.3,6.48 33.6,6.48 34.7,5.38 34.7,3.73 34.85,3.58 72.62,3.58 74.8,1.4 133.35,1.4 137.92,5.97 137.92,11.05 136.65,12.32 136.65,12.83 136.53,12.95 134.87,12.95 133.6,11.68 133.6,8.26 132.46,7.11 129.41,7.11 129.03,7.49 129.03,13.59 130.18,14.73 138.05,14.73 139.57,16.26 141.35,16.26 141.99,16.89 141.99,20.07 141.22,20.83 138.56,20.83 136.02,23.37 126.36,23.37 125.22,24.51 125.22,26.92 127.76,29.46 127.76,35.31 124.21,38.86 115.19,38.86 112.39,36.07 112.39,34.67 111.89,34.16 111.25,34.16 110.74,34.67 110.74,42.55 113.92,45.72 115.82,45.72 119.63,41.91 138.3,41.91 138.81,41.4 146.43,41.4 149.1,38.73 149.1,35.81 148.46,35.18 148.46,29.97 149.22,29.21 149.22,7.24 148.97,6.99 147.7,6.99 147.32,7.37 143,7.37 142.49,6.86 142.49,1.14 142.11,0.76 ; 3 cut-outs
GND on BOTTOM: 62.23,138.21 62.11,138.34 62.11,138.59 61.85,138.85 61.34,138.85 61.09,139.1 61.09,148.92 61.94,149.77 62.23,149.77 62.49,149.51 62.49,148.75 62.61,148.63 62.99,148.63 63.25,148.37 63.25,147.99 63.12,147.86 62.61,147.86 62.36,147.61 62.36,144.56 62.61,144.31 63.12,144.31 63.25,144.18 63.25,143.8 63.12,143.67 62.74,143.67 62.49,143.42 62.49,142.91 62.74,142.66 63.25,142.66 63.38,142.53 63.38,142.15 63.12,141.89 62.61,141.89 62.49,141.77 62.49,140.75 62.87,140.37 63.25,140.37 63.38,140.24 63.38,139.86 62.87,139.35 62.87,138.47 62.61,138.21 ; 11 cut-outs
GND on BOTTOM: 19.6,181.13 19.29,181.44 19.29,184.77 19.3,184.79 19.3,186.43 20.57,187.71 22.86,187.71 23.11,187.45 23.11,181.36 22.89,181.13
GND on BOTTOM: 116.46,29.08 115.44,30.1 115.44,32.26 116.57,33.39 119.9,33.39 120.22,33.07 120.22,29.29 120.02,29.08
GND on BOTTOM: 56.31,192.07 56.13,192.25 56.13,193.68 55.78,194.03 53.62,194.03 53.29,193.7 53.29,192.28 53.11,192.1 49.83,192.1 48.79,193.14 47.22,193.14 46.99,193.37 46.99,195.5 47.37,195.88 59.36,195.88 59.84,195.4 59.84,192.1 59.82,192.07
GND on BOTTOM: 5.21,147.96 5.08,148.08 5.08,194.44 5.33,194.69 5.59,194.69 7.75,192.53 10.54,192.53 11.68,193.68 11.68,196.34 10.41,197.61 10.41,198.5 11.05,199.14 18.92,199.14 19.3,198.75 19.3,195.07 10.16,185.93 10.16,185.04 9.53,184.4 9.4,184.4 8.76,183.77 8.76,171.83 8.38,171.45 7.11,171.45 6.6,170.94 6.6,167.64 6.99,167.26 7.75,167.26 8.13,166.88 8.13,153.8 7.87,153.54 6.99,153.54 6.86,153.42 6.86,148.08 6.73,147.96
GND on BOTTOM: 73,185.04 72.72,185.32 72.72,193.22 73.1,193.6 74.96,193.6 75.08,193.47 75.08,185.14 74.98,185.04
GND on BOTTOM: 92.05,21.72 91.03,22.73 87.91,22.73 87,23.65 87,24.33 87.33,24.66 92.28,24.66 92.84,24.1 92.84,22.99 93.47,22.35 93.47,21.84 93.34,21.72 ; 1 cut-out
GND on BOTTOM: 35.79,7.26 35.47,7.58 35.47,9.33 35.56,9.42 37.29,9.42 37.72,9.86 42.19,9.86 42.67,9.37 42.67,8.28 42.49,8.1 39.62,8.1 38.79,7.26
GND on BOTTOM: 56.01,144.05 55.76,144.31 54.99,144.31 54.87,144.43 54.87,144.92 55.02,145.07 55.37,145.07 55.63,145.32 55.63,150.95 56.52,151.84 56.86,151.84 56.9,151.8 56.9,144.18 56.77,144.05 ; 8 cut-outs
GND on BOTTOM: 53.47,139.61 53.34,139.74 53.34,140.24 53.47,140.37 53.85,140.37 53.98,140.5 53.98,142.91 54.1,143.04 54.61,143.04 54.74,142.91 54.74,142.15 55,141.88 56.4,141.88 56.77,141.51 56.77,139.74 56.64,139.61 ; 5 cut-outs
GND on BOTTOM: 110.87,129.04 109.14,130.77 109.14,136.09 109.86,136.8 111.56,136.8 111.86,137.11 111.86,138.38 113.69,138.38 114.07,138 114.07,129.18 113.93,129.04 ; 2 cut-outs
GND on BOTTOM: 40.69,134.99 40.44,135.24 40.44,136.75 40.21,136.98 40.21,137.35 40.38,137.52 40.99,137.52 41.17,137.71 41.86,137.71 41.87,137.7 41.87,135.19 41.68,134.99
GND on BOTTOM: 13.84,151 11.56,153.29 11.56,155.19 11.81,155.45 14.57,155.45 15.16,156.03 19.87,156.03 20.25,155.65 20.25,152.08 19.18,151
GND on BOTTOM: 44.86,13.23 44.42,13.67 44.42,14.5 44.73,14.81 51.71,14.81 51.87,14.66 51.87,13.97 51.77,13.87 50.93,13.87 50.29,13.23
GND on BOTTOM: 66.43,176.7 66.22,176.91 66.22,182.52 66.34,182.65 70.82,182.65 71.53,181.94 71.53,177.39 70.83,176.7 ; 7 cut-outs
GND on BOTTOM: 133.35,57.53 132.28,58.6 132.28,60.48 131.5,61.26 126.44,61.26 121.79,65.91 121.79,69.47 124.71,72.39 139.45,72.39 139.95,72.9 139.95,79.38 139.45,79.88 129.29,79.88 129.16,80.01 129.16,80.62 135.94,87.4 135.94,89.84 137.41,91.31 137.41,103 139.95,105.54 139.95,116.46 140.34,116.84 140.34,123.57 139.83,124.08 139.83,125.73 140.46,126.36 143.38,126.36 143.76,125.98 143.76,99.95 143,99.19 143,98.3 143.51,97.79 144.4,97.79 145.67,99.06 145.67,160.53 143.51,162.69 143.51,179.32 141.6,181.23 126.75,181.23 121.16,186.82 121.16,193.93 118.36,196.72 118.36,198.88 118.62,199.14 134.24,199.14 134.49,198.88 134.49,193.42 135.38,192.53 138.3,192.53 139.45,193.68 139.45,198.88 139.7,199.14 148.72,199.14 149.22,198.63 149.22,60.33 146.43,57.53 ; 7 cut-outs
GND on BOTTOM: 96.39,11.05 96.01,11.43 96.01,14.61 96.39,14.99 99.09,14.99 99.31,14.77 99.31,11.94 98.42,11.05
GND on L2VCC: 1,0.76 0.83,0.83 0.76,1 0.76,119.97 0.83,120.14 1,120.21 1.3,120.21 3.96,121.31 5.06,123.97 5.06,199 5.13,199.17 5.3,199.24 149,199.24 149.17,199.17 149.24,199 149.24,59.58 148.08,59.02 147.62,57.82 147.62,57.65 147.55,57.48 147.38,57.41 140.78,57.41 139.97,57.12 139.54,56.36 139.14,56.36 137.94,55.5 138.38,54.09 138.38,44.91 137.94,43.5 139.14,42.64 139.54,42.64 139.97,41.88 140.78,41.59 147.38,41.59 147.55,41.52 147.62,41.35 147.62,41.18 148.08,39.98 149.24,39.42 149.24,39.05 139.91,39.05 139.52,39.43 130.6,39.43 129.84,38.67 126.32,38.67 123.9,41.08 110.03,41.08 108.9,39.96 108.9,37.39 109.4,36.89 111.55,36.89 112.19,36.26 112.94,36.26 113.67,35.53 113.67,33.24 114.4,32.51 115.73,32.51 116.62,33.4 119.86,33.4 120.14,33.12 120.14,28.54 121,27.69 121.32,27.69 121.51,27.88 123.11,27.88 123.39,27.6 125.19,27.6 126.26,26.53 128.48,26.53 130.48,28.54 135.94,28.54 138.3,26.17 149.24,26.17 149.24,1 149.17,0.83 149,0.76 ; 1 cut-out
VCC5_PANEL on TOP: 9.28,114.24 9.04,114.49 9.04,116.67 9.27,116.9 11.8,116.9 11.89,116.81 11.89,114.33 11.8,114.24
VCC5_PANEL on BOTTOM: 8.32,114.31 8.14,114.49 8.14,116.21 8.79,116.85 9.53,116.85 9.66,116.71 9.75,116.71 9.76,116.72 11.7,116.72 11.84,116.57 11.84,114.59 11.56,114.31 ; 8 cut-outs
VCC5_TOU on TOP: 20.28,55.99 20.27,56.01 19.53,56.01 17.14,58.39 17.14,59.39 18.82,59.39 19.96,58.24 25.93,58.24 26.37,57.81 26.37,56.69 25.67,55.99 ; 2 cut-outs
VDD_0.95_ALW on BOTTOM: 51.95,140.5 51.82,140.62 51.82,141.26 52.33,141.26 52.58,141.51 52.58,142.66 52.83,142.91 53.09,142.91 53.22,143.04 53.72,143.04 53.85,142.91 53.85,140.62 53.72,140.5 ; 2 cut-outs
VDD_095_GFX on TOP: 51.41,144.78 51.31,144.88 51.31,145.85 50.72,146.43 50.72,146.77 51.35,147.4 51.59,147.4 51.82,147.17 51.82,145.06 51.54,144.78
VDDNB on TOP: 57.03,141.51 56.84,141.7 56.84,142.16 56.66,142.34 56.29,142.34 55.84,141.89 55.04,141.89 53.52,143.42 53.47,143.42 52.83,144.06 52.83,147.42 51.87,148.39 51.87,148.98 52.31,149.42 52.58,149.42 52.91,149.75 52.91,150.02 53.09,150.19 53.39,150.24 53.57,150.24 53.72,150.09 53.72,149.77 53.72,144.18 54.24,143.66 54.66,143.66 54.87,143.87 54.87,150.15 54.99,150.28 55.5,150.28 55.67,150.11 55.67,144.03 56.08,143.62 57.04,143.62 57.19,143.46 57.19,142.81 57.68,142.33 57.68,141.78 57.42,141.51
VDDNB on TOP: 16.3,153.16 15.69,153.77 15.69,162.49 14.77,163.41 14.77,168.09 14.79,168.09 15,168.3 24.59,168.3 24.71,168.17 24.71,153.62 24.25,153.16 ; 19 cut-outs
VDDNB on BOTTOM: 55.14,142.01 54.89,142.27 54.89,143 54.66,143.23 54.15,143.23 54.08,143.31 54.08,143.74 53.87,143.94 52.93,143.94 52.78,144.09 52.78,147.85 51.44,149.2 50.98,149.2 50.88,149.3 50.88,150.67 50.98,150.77 53.29,150.77 53.49,150.98 53.49,151.54 53.52,151.56 54.13,151.56 54.23,151.46 54.23,151.08 54.38,150.93 55.24,150.93 55.4,150.77 55.4,145.39 55.24,145.24 54.69,145.24 54.61,145.16 54.61,144.3 54.84,144.07 55.73,144.07 55.91,143.89 56.77,143.89 56.92,143.74 56.92,143 57.15,142.77 57.15,142.49 56.67,142.01 ; 9 cut-outs
VDDNB on BOTTOM: 21.21,155.02 20.84,155.4 20.84,156.7 20.55,156.99 19.31,156.99 19.31,156.99 17.19,156.99 16.53,157.66 16.53,162.7 14.76,164.47 14.76,168.09 14.99,168.32 24.25,168.32 24.71,167.85 24.71,156.01 23.72,155.02
VDDNB on L2VCC: 55.31,144.45 57.15,142.6 56.17,141.29 52.4,141.29 52.15,141.54 48.44,141.54 48.18,141.29 45.01,141.29 44.63,140.91 43.64,140.91 43.26,141.29 41.83,141.29 41.2,140.65 40.69,140.65 36.5,136.46 31.45,136.46 28.77,139.14 28.77,148.92 25.61,152.08 20.14,152.08 19.11,153.11 19.11,168.2 19.89,168.97 26.72,168.97 37.51,158.18 44.12,158.18 47.05,155.24 47.05,153.59 48.94,151.7 51.48,151.7 52.88,150.3 54.66,150.3 55.31,149.65
(no net) on L3: 1,0.76 0.83,0.83 0.76,1 0.76,119.97 0.83,120.14 1,120.21 1.3,120.21 3.96,121.31 5.06,123.97 5.06,199 5.13,199.17 5.3,199.24 149,199.24 149.17,199.17 149.24,199 149.24,59.58 148.08,59.02 147.62,57.82 147.62,57.65 147.55,57.48 147.38,57.41 140.78,57.41 139.97,57.12 139.54,56.36 139.14,56.36 137.94,55.5 138.38,54.09 138.38,44.91 137.94,43.5 139.14,42.64 139.54,42.64 139.97,41.88 140.78,41.59 147.38,41.59 147.55,41.52 147.62,41.35 147.62,41.18 148.08,39.98 149.24,39.42 149.24,35.58 148.73,35.11 148.54,34.45 148.54,30.55 148.73,29.89 149.24,29.42 149.24,1 149.17,0.83 149,0.76 ; 4 cut-outs
0D95V_S0 on TOP: 34.82,118.66 34.63,118.85 34.63,122.23 34.93,122.53 34.93,123.26 35.07,123.4 35.07,126.97 35.94,126.97 36.53,126.38 36.53,125.68 36.73,125.48 37.54,125.48 37.69,125.32 37.69,124.51 37.82,124.38 37.83,124.38 37.98,124.23 37.98,118.96 37.68,118.66 ; 3 cut-outs
0D95V_S5 on TOP: 33.06,115.61 32.89,115.77 32.89,116.15 31.3,117.75 30.83,117.75 30.42,118.16 30.42,126.15 31.26,126.99 33.62,126.99 33.62,126.97 33.7,126.89 33.7,126.12 33.81,126.01 33.81,122.64 34.27,122.17 34.27,117.5 34.27,117.49 34.27,115.83 34.05,115.61 ; 5 cut-outs
1D5V_S3 on BOTTOM: 78,132.26 76.58,133.68 72.67,133.68 70.31,136.04 69.42,136.04 68.99,135.61 66.78,135.61 66.47,135.31 65.81,135.31 64.95,136.17 64.95,136.5 63.47,137.97 63.47,140.34 63.25,140.56 62.97,140.56 62.74,140.79 62.74,141.58 62.92,141.76 63.3,141.76 63.47,141.94 63.47,142.57 63.27,142.77 62.84,142.77 62.64,142.98 62.64,143.36 62.87,143.59 63.2,143.59 63.37,143.76 63.37,144.25 63.14,144.48 62.69,144.48 62.48,144.68 62.48,147.52 62.74,147.78 63.2,147.78 63.35,147.93 63.35,148.54 62.61,149.28 62.61,150.8 64.41,152.6 68,152.6 70.54,150.06 72.01,150.06 72.54,150.6 81.66,150.6 85.67,154.61 94.31,154.61 95.24,153.68 103.49,153.68 103.91,153.26 103.91,144.04 104.4,143.55 104.4,142.06 106.01,140.44 106.01,136.52 104.99,135.5 104.68,135.5 104.67,135.49 104.08,135.49 103.93,135.64 96.44,135.64 93.29,132.49 88.9,132.49 88.67,132.26 ; 42 cut-outs
1D8V_S0 on TOP: 35.11,128.36 35.06,128.4 35.06,130.37 34.24,131.19 34.24,132 34.24,132.01 34.24,133.61 30.74,137.11 30.74,138.15 28.57,140.31 28.57,149.87 33.33,154.63 34.3,153.66 34.3,153.31 30.58,149.59 30.58,141.46 32.66,139.39 32.66,137.66 36.58,133.73 36.58,129.92 37.08,129.42 37.08,128.61 36.83,128.36 ; 4 cut-outs
1D8V_S0 on BOTTOM: 32.36,152.45 31.42,153.39 31.42,154 34.59,157.18 34.59,158.09 35.13,158.62 36.27,158.62 36.45,158.45 36.45,156.03 32.87,152.45
1D8V_S5 on TOP: 31.34,128.35 30.35,129.34 30.35,132.77 29.84,133.27 29.06,133.27 28.96,133.38 28.96,136.93 29.06,137.03 30.51,137.03 32.68,134.86 32.68,131.23 32.94,130.96 32.94,129.97 33.17,129.74 33.55,129.74 33.73,129.57 33.73,128.42 33.66,128.35 ; 6 cut-outs
1D8V_S5 on TOP: 24.97,148.29 24.69,148.56 24.69,149.83 32.66,157.81 33.48,157.81 33.62,157.67 33.62,156.45 33.49,156.32 33.49,155 33.35,154.86 32.46,154.86 25.88,148.29 ; 2 cut-outs
3D3V_A on TOP: 64.11,17.63 64.07,17.66 63.44,17.66 63.07,18.04 63.07,25.31 64.47,26.71 64.47,29.47 64.72,29.72 65.54,29.72 65.98,29.28 66.67,29.28 67.18,28.77 67.18,25.74 69.13,23.79 69.13,23.4 69.14,23.39 69.14,18.16 68.61,17.63 ; 3 cut-outs
3D3V_A on TOP: 1.17,66.75 0.81,67.12 0.81,118.12 5.07,122.38 5.07,134.57 5.46,134.95 9.07,134.95 9.17,134.85 9.17,130.66 7.5,128.98 7.5,121.99 2.8,117.29 2.8,76.01 4.93,73.89 4.93,68.07 3.61,66.75 2.31,66.75 2.3,66.75
3D3V_A on TOP: 77.85,63.7 76.48,65.07 73.13,65.07 71.86,63.8 70.48,63.8 70.15,64.14 70.15,64.85 70.46,65.15 71.45,65.15 73.15,66.85 74.4,66.85 75.21,67.67 79.53,67.67 81.84,69.98 82.96,69.98 83.65,70.68 84.52,70.68 84.84,70.36 84.84,68.66 79.88,63.7 ; 2 cut-outs
3D3V_A on BOTTOM: 73.1,88.57 72.87,88.8 72.87,91.31 73.05,91.49 74.78,91.49 75.26,91.01 75.26,89.69 75.11,89.53 73.86,89.53 73.63,89.31 73.63,88.72 73.48,88.57
3D3V_A on BOTTOM: 40.23,20.52 35.97,24.79 6.91,24.79 0.86,30.84 0.86,68.63 1.17,68.94 2.64,68.94 3.71,67.87 3.71,32 8.18,27.53 39.09,27.53 42.82,23.8 55.7,23.8 55.73,23.77 56.85,24.89 57.91,24.89 59.56,23.24 66.34,23.24 67.06,22.53 67.06,20.75 66.83,20.52
3D3V_S0 on TOP: 60.68,25.98 60.1,26.57 60.1,28.07 59.69,28.47 59.69,29.24 59.78,29.33 62,29.33 62.39,29.72 63.33,29.72 63.4,29.64 63.4,26.2 63.19,25.98 ; 5 cut-outs
3D3V_S0 on BOTTOM: 127.43,109.58 127.13,109.88 127.13,111.91 127.23,112.01 128.3,112.01 128.55,111.76 128.55,110.9 128.96,110.49 128.96,110.11 128.42,109.58 ; 2 cut-outs
3D3V_S0 on BOTTOM: 89.05,98.3 89,98.35 89,99.21 89.23,99.44 90.96,99.44 91.47,98.93 91.47,98.32 91.44,98.3
3D3V_S0 on BOTTOM: 60.22,25.91 59.59,26.54 58.04,26.54 56.29,28.3 52.45,28.3 51.23,29.51 51.23,30.38 51.44,30.58 55.78,30.58 56.26,30.1 57.76,30.1 58.28,29.58 61.56,29.58 63.3,27.84 63.3,26.21 62.99,25.91
3D3V_S0 on BOTTOM: 31.47,191.62 30.89,192.2 30.89,192.74 31.01,192.86 32.97,192.86 33.1,192.74 33.1,191.8 32.92,191.62
3D3V_S5 on TOP: 17.4,139.55 17.27,139.67 17.27,140 17.55,140.28 17.55,141.5 17.78,141.73 18.59,141.73 18.75,141.58 18.75,140.08 18.21,139.55
3D3V_S5 on TOP: 31.37,10.62 30.51,11.48 30.51,12.4 30.56,12.45 32,12.45 33.21,13.66 33.21,23.1 32.74,23.57 32.74,28.57 32.19,29.12 30.42,29.12 30.35,29.18 30.35,30.53 30.53,30.71 32.51,30.71 34.29,28.93 34.29,24.18 35.21,23.26 35.21,12.94 34.19,11.91 33.6,11.91 32.31,10.62
3D3V_S5 on TOP: 56.84,17.41 55.6,18.64 55.6,19.99 53.72,21.87 53.72,26.87 54.2,27.35 56.45,27.35 56.63,27.17 56.63,24.29 57.23,23.7 62,23.7 62.44,23.25 62.44,17.63 62.22,17.41 ; 6 cut-outs
3D3V_S5 on BOTTOM: 43.13,23.98 39.32,27.79 31.15,27.79 31.13,27.81 16.2,27.81 13.08,30.92 13.08,68.99 11.56,70.51 9.27,70.51 8,71.78 8,83.57 8.38,83.95 8.81,83.95 11.51,81.25 11.51,73.84 12.17,73.18 14.07,73.18 14.5,73.61 15.39,73.61 15.61,73.39 15.61,72.89 14.99,72.26 14.99,70.38 15.6,69.77 15.6,32.64 17.2,31.04 32.16,31.04 33.32,29.87 40.82,29.87 44.3,26.39 55.55,26.39 55.75,26.19 55.75,24.56 55.17,23.98 ; 6 cut-outs
3D3V_S5 on BOTTOM: 114.86,18.41 114.53,18.75 114.53,20.04 114.94,20.45 116.71,20.45 116.76,20.5 117.32,20.5 117.47,20.35 117.47,18.69 117.2,18.41 ; 2 cut-outs
3D3V_S5 on BOTTOM: 30.48,9.73 30.2,10.01 30.2,11.38 30.53,11.71 32.16,11.71 32.46,11.4 32.46,10.03 32.16,9.73 ; 3 cut-outs
3D3V_USB on TOP: 121.64,193.12 120.75,194.01 120.04,194.01 119.99,194.06 119.99,195.73 120.07,195.81 123.65,195.81 123.77,195.94 123.77,196.49 124.05,196.77 124.76,196.77 124.94,196.6 124.94,194.16 124.28,193.5 122.38,193.5 122,193.12 ; 7 cut-outs
+AUD_DVDD_1 on TOP: 109.73,23.24 109.47,23.5 109.47,24.64 109.73,24.89 109.73,26.29 109.98,26.54 112.22,26.54 113.11,27.43 113.79,27.43 114.68,28.32 114.68,28.57 114.91,28.8 115.8,28.8 115.87,28.73 115.87,27.76 113.41,25.3 113.06,25.3 111,23.24 ; 3 cut-outs
+HDT_VDDIO_SUS on BOTTOM: 82.21,189.19 81.99,189.41 81.99,189.61 82.89,190.51 82.89,193.23 82.93,193.27 84.33,193.27 84.58,193.01 84.58,191.23 82.55,189.19
AD_JK_S on TOP: 131.83,14.35 131.7,14.48 127.13,14.48 126.87,14.73 126.87,22.86 127,22.99 132.46,22.99 133.16,22.29 135.32,22.29 137.16,20.45 140.72,20.45 141.6,19.56 141.6,17.14 141.1,16.64 139.19,16.64 137.79,15.24 134.37,15.24 133.48,14.35 ; 4 cut-outs
AD_JK_S on BOTTOM: 128.17,15.24 126.87,16.54 126.87,22.48 127.38,22.99 135.64,22.99 138.18,20.45 140.72,20.45 141.6,19.56 141.6,17.14 141.1,16.64 139.19,16.64 137.79,15.24
AD_JK_S_R on TOP: 117.22,13.46 116.46,14.22 116.46,17.02 116.84,17.4 118.87,17.4 119,17.53 119,19.81 119.25,20.07 119.89,20.07 120.65,20.83 122.3,20.83 122.68,21.21 122.68,22.61 123.7,23.62 123.7,23.75 123.95,24 125.35,24 125.6,23.75 125.6,23.5 125.59,23.48 125.59,22.85 125.83,22.61 125.98,22.61 126.24,22.35 126.24,14.35 125.35,13.46 ; 2 cut-outs
AD_JK_S_R on BOTTOM: 123.57,15.88 122.81,16.64 122.81,21.46 123.32,21.97 125.86,21.97 126.11,21.72 126.11,16.13 125.86,15.88
APU_M_VREF_SUS on TOP: 69.95,143.74 69.77,143.92 69.77,144.63 69.88,144.73 70.69,144.73 70.87,144.55 70.87,143.92 70.69,143.74
APU_VDD18_ALW on TOP: 44.44,155.24 43.31,156.37 34.61,156.37 34.47,156.51 34.14,156.51 34.08,156.57 34.08,157.64 34.33,157.89 43.69,157.89 45.33,156.24 46.23,156.24 46.61,155.86 46.91,155.86 47.12,155.65 47.12,155.3 47.07,155.24 ; 10 cut-outs
APU_VDD_0.95 on TOP: 42.07,117.05 42.06,117.06 40.73,117.06 38.62,119.17 38.62,123.77 39.04,124.2 39.04,124.21 40.56,124.21 45.39,119.38 45.39,117.14 45.29,117.05
APU_VDD_0.95 on TOP: 58.2,138.84 57.23,139.82 57.23,141.1 57.82,141.69 57.82,142.53 57.92,142.63 58.56,142.63 58.69,142.5 58.69,141.69 58.17,141.17 58.17,140.88 58.42,140.62 58.42,140.37 59.18,139.61 59.69,139.61 59.82,139.74 59.82,140.24 59.69,140.37 59.69,140.75 59.82,140.88 59.82,141.13 59.57,141.39 59.57,141.64 60.07,142.15 60.84,142.15 61.09,141.89 61.09,139.86 60.07,138.84
APU_VDD_0.95 on BOTTOM: 31.01,144.25 30.63,144.63 30.63,145.9 30.73,146 32.23,146 32.46,146.23 33.88,146.23 33.99,146.13 33.99,144.86 33.88,144.75 32.03,144.75 31.52,144.25 ; 3 cut-outs
APU_VDD_0.95 on BOTTOM: 58.3,138.21 57.03,139.48 57.03,141.38 57.12,141.48 57.16,141.51 58.55,141.51 58.68,141.39 58.68,140.24 58.8,140.12 59.31,140.12 59.57,140.37 59.57,141.64 60.33,142.4 60.71,142.4 60.84,142.28 60.84,139.99 60.96,139.86 60.96,138.97 60.84,138.85 59.69,138.85 59.57,138.97 59.18,138.97 58.93,138.72 58.93,138.34 58.8,138.21 ; 7 cut-outs
APU_VDD_0.95 on L2VCC: 56.34,140.91 56.35,140.92 56.37,140.92 56.41,140.97 56.45,141.02 56.45,141.03 57.5,142.43 58.21,142.43 58.72,141.92 61.15,141.92 61.15,138.86 61.79,138.22 61.79,135.84 61.14,135.19 53.01,135.19 52.64,134.83 52.64,131.75 55.94,128.45 55.94,125.3 55.44,124.79 55.44,123.37 55.69,123.11 55.69,112.73 53.64,110.68 35.86,110.68 34.59,109.41 34.24,109.41 33.97,109.68 33.97,114.73 36.77,117.52 36.77,136.19 40.85,140.27 41.35,140.27 41.99,140.91 43.1,140.91 43.48,140.53 44.78,140.53 45.16,140.91 48.34,140.91 48.59,141.16 51.99,141.16 52.25,140.91 56.2,140.91 56.21,140.9 56.27,140.91
APU_VDD_18 on TOP: 47.5,154.72 47.37,154.85 47.37,155.61 46.87,156.12 46.61,156.12 43.85,158.88 37.44,158.88 36.93,159.38 36.93,160.78 37.22,161.07 45.39,161.07 46.64,159.82 46.64,158.04 47.88,156.79 47.88,154.98 47.63,154.72 ; 9 cut-outs
APU_VDD_18 on BOTTOM: 36.96,157.15 36.93,157.18 36.93,159.56 37.44,160.07 39.52,160.07 39.93,159.66 39.93,158.85 38.23,157.15
AUD_PVDD_1 on TOP: 110.74,28.32 110.24,28.83 108.97,28.83 108.46,29.34 108.46,31.24 107.82,31.88 107.31,31.88 107.31,32.64 107.7,33.02 110.24,33.02 110.49,33.27 110.49,33.78 110.62,33.91 111.38,33.91 111.66,34.19 113.06,34.19 113.92,33.32 113.92,33.15 113.79,33.02 113.28,33.02 113.16,33.15 112.01,33.15 111.12,32.26 111.12,29.9 111.56,29.46 113.16,29.46 113.21,29.51 113.79,29.51 113.92,29.39 113.92,28.6 113.64,28.32 ; 3 cut-outs
CPU_VCORE on TOP: 59.69,142.28 59.57,142.4 59.57,142.66 59.82,142.91 59.82,143.16 59.57,143.42 59.57,143.67 59.82,143.92 59.82,144.18 59.57,144.43 59.57,144.56 59.82,144.82 59.82,145.2 59.57,145.45 59.57,145.58 59.82,145.83 59.82,146.09 59.57,146.34 59.57,146.59 59.82,146.85 59.82,147.1 59.69,147.23 59.69,147.23 59.57,147.36 59.57,147.61 59.82,147.86 59.82,148.25 59.57,148.5 59.57,148.63 59.82,148.88 59.82,149.26 59.69,149.39 58.93,149.39 58.67,149.12 58.67,142.86 58.6,142.8 57.36,142.8 57.3,142.86 57.3,150.07 57.3,150.08 57.3,150.17 57.91,150.78 58.3,150.78 58.87,150.21 59.36,150.21 59.89,150.73 61.05,150.73 61.7,150.09 61.7,149.8 61.19,149.29 61.19,142.7 60.85,142.36 60.16,142.36 60.07,142.28
CPU_VCORE on TOP: 45.54,174.04 45.31,174.27 45.31,181.48 45.76,181.93 45.78,181.93 45.9,182.04 52.49,182.04 55.19,179.34 55.19,179.17 55.91,179.17 58.67,181.93 64.67,181.93 65.23,181.38 65.27,181.38 65.8,180.85 65.8,175.68 64.17,174.04
CPU_VCORE on BOTTOM: 45.34,171.55 45.22,171.67 45.22,174.33 45.21,174.35 45.21,183.26 45.26,183.31 48.01,183.31 49.15,182.17 64.54,182.17 65.05,182.68 65.71,182.68 65.86,182.52 65.86,176.83 65.74,176.71 54,176.71 48.84,171.55 ; 16 cut-outs
CPU_VCORE on BOTTOM: 59.69,142.15 59.57,142.28 59.57,148.63 59.69,148.75 59.69,149.51 59.44,149.77 58.55,149.77 58.42,149.64 58.42,143.42 58.3,143.29 57.91,143.29 57.91,144.05 57.28,144.05 57.15,144.18 57.15,151.8 57.28,151.93 58.17,151.93 58.8,151.29 59.69,151.29 59.95,151.04 60.96,151.04 61.34,150.66 61.34,149.39 60.84,148.88 60.84,142.66 60.71,142.53 60.2,142.53 59.82,142.15 ; 17 cut-outs
CPU_VCORE on L2VCC: 32.19,168.07 32.19,170.1 32.59,170.5 34.62,170.5 35.37,171.24 35.37,172.13 36.53,173.29 44.66,173.29 45.15,173.78 45.15,181.4 45.8,182.05 64.56,182.05 65.72,180.9 65.72,170.13 65.21,169.62 65.21,164.54 66.18,163.57 66.18,161.95 61.4,157.18 61.4,155.37 62.02,154.75 62.53,154.75 62.8,154.48 62.8,151.21 62.29,150.7 62.29,143.33 61.26,142.3 58.88,142.3 58.37,142.81 57.48,142.81 55.69,144.6 55.69,149.81 54.82,150.69 53.04,150.69 51.64,152.08 49.1,152.08 47.43,153.75 47.43,155.4 44.27,158.56 37.67,158.56 30.18,166.05
DCBATOUT on TOP: 16.04,192.77 15.86,192.95 15.86,198.9 16.15,199.19 21.34,199.19 21.63,198.9 21.63,197.1 19.57,195.05 19.57,193.06 19.29,192.77 ; 2 cut-outs
DCBATOUT on TOP: 93.68,51.94 92.94,52.68 92.94,53.77 92.94,53.77 92.94,62.89 92.95,62.9 92.95,65.87 93.97,66.89 93.97,86.22 94.51,86.77 100.28,86.77 100.71,86.33 100.71,62.05 99.67,61.01 99.67,52.22 99.39,51.94 ; 3 cut-outs
DCBATOUT on TOP: 74.68,4.7 74.55,4.83 74.55,9.81 74.88,10.15 77.15,10.15 78.15,9.14 97.03,9.14 99.82,11.94 99.82,17.91 100.71,18.8 113.67,18.8 114.17,18.29 114.17,13.26 113.74,12.83 106.22,12.83 99.24,5.84 77.22,5.84 76.07,4.7 ; 11 cut-outs
DCBATOUT on TOP: 7.98,121.23 7.7,121.51 7.7,128.6 8.08,128.98 9.53,128.98 9.65,128.85 9.65,121.56 9.32,121.23 ; 2 cut-outs
DCBATOUT on TOP: 116.32,113.3 115.7,113.92 115.7,121.34 116.26,121.89 116.26,130 121.01,134.75 121.01,167.56 114.8,173.77 114.8,184.08 115.77,185.05 118.18,185.05 119.94,183.28 119.94,175.11 125.3,169.75 125.3,130.96 121.7,127.37 121.7,115.48 119.52,113.3
DCBATOUT on BOTTOM: 117.27,182.81 116.03,184.04 116.03,192.04 111.92,196.16 110.9,196.16 110.7,196.36 66.23,196.36 65.57,197.02 65.56,197.02 65.29,197.28 20.57,197.28 20.2,197.65 20.2,198.85 20.54,199.19 115.48,199.19 120.85,193.82 120.85,183.84 119.82,182.81 ; 2 cut-outs
DCBATOUT on BOTTOM: 93.04,85.06 90.91,87.2 90.91,95.77 93.73,98.59 101.84,98.59 113.57,110.32 113.57,114.53 115.46,116.42 115.46,126.17 115.95,126.67 120.11,126.67 120.14,126.67 120.4,126.42 120.4,106.63 98.83,85.06 ; 1 cut-out
DCBATOUT on BOTTOM: 100.2,16.13 99.82,16.51 99.82,20.32 99.34,20.8 99.34,36.2 97.53,38 97.53,44.7 95.55,46.68 95.55,51.21 95.14,51.62 95.14,52.98 96.22,54.05 99.9,54.05 100.63,53.31 100.63,49.29 102.98,46.94 102.98,40.65 106.16,37.47 106.16,24.66 107.73,23.09 107.73,18.58 105.27,16.13
DCBATOUT_CON on TOP: 60.81,4.43 60.63,4.61 60.63,16.84 60.73,16.94 66.19,16.94 66.44,16.69 66.44,12.12 66.64,11.92 68.44,11.92 68.45,11.91 73.36,11.91 73.97,11.29 73.97,4.86 73.55,4.43 ; 6 cut-outs
DCBATOUT_CON on BOTTOM: 60.96,4.7 60.71,4.95 60.71,15.49 60.96,15.75 65.02,15.75 66.8,13.97 66.8,10.03 69.34,7.49 69.34,4.95 69.09,4.7
